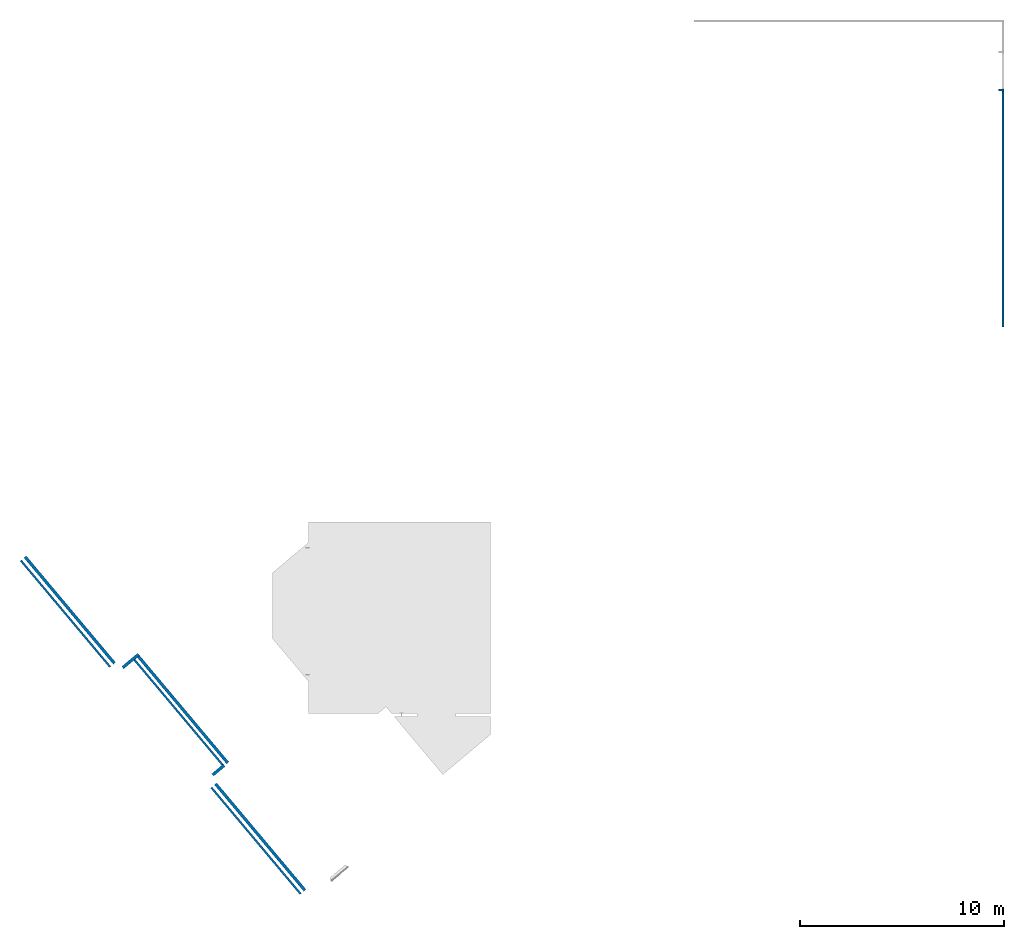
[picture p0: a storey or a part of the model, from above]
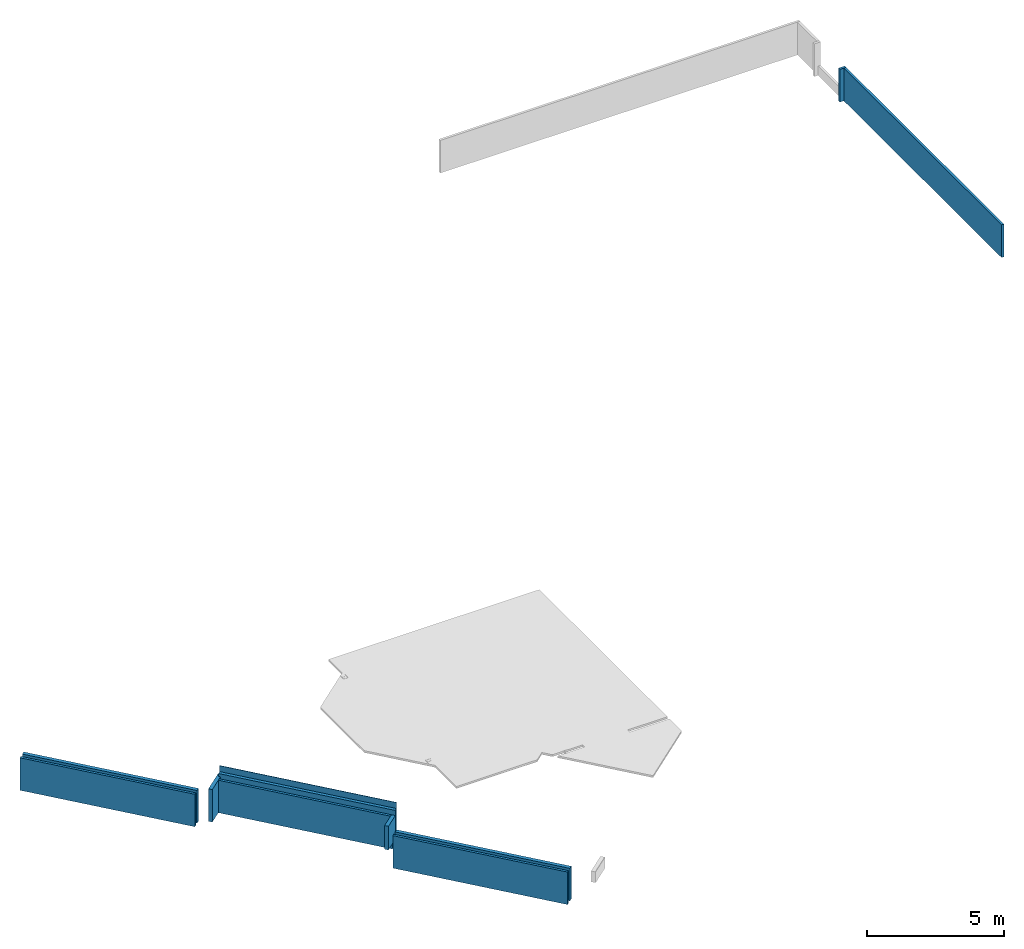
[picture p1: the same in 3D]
Properties of the parts of a building model (IFC2X3), part 1 of 11

# File
Description: ViewDefinition [9, SurfaceGeometryAddOnView, QuantityTakeOffAddOnView, SpaceBoundary2ndLevelAddOnView], Option [Elements to export: Visible elements (on all stories)], Option [Partial Structure Display: Entire Model], Option [IFC Domain: All], Option [Structural Function: All Elements], Option [Convert Grid elements: On], Option [Convert IFC Annotations and ARCHICAD 2D elements: Off], Option [Convert 2D symbols of Doors and Windows: Off], Option [Export geometries that Participates in Collision Detection only: On], Option [Split complex elements: Off], Option [Material Preservation: Explode all], Option [IFC Model position: Survey Point and Project Origin], Option [Curtain Wall export mode: Container Element], Option [Railing export mode: Container Element], Option [Stair export mode: Container Element], Option [Properties To Export: Current Scheme properties only], Option [Space containment: On], Option [IFC Domain For Space Containment: Custom], Option [Bounding Box: On], Option [Geometry to type objects: On], Option [Element Properties: Off], Option [Building Material Properties: Off], Option [Element Parameters: Off], Option [Component Parameters: IFC Component Quantities Only], Option [IFC Base Quantities: On], Option [Door Window Parameters: Off], Option [IFC Space boundaries: On], Option [ARCHICAD Zone Categories as IFC Space classification data: Off], Option [Element Classifications: On]
File name: D:\Dropbox (DankersSlimmerBouwen)\! DankersSlimmerBouwen\! projecten\197 IKC Woensdrecht\Productie\197_ TOT BWK_DO.ifc
Time: 2022-08-03T15:14:06
Author: Architect
Organization: Carree Architecten BNA
Written by: The EXPRESS Data Manager Version 5.02.0100.09 : 26 Sep 2013
Made in: IFC file generated by GRAPHISOFT ARCHICAD 25.0.0 NED FULL Windows version (IFC add-on version: 5010 NED FULL).
Authorization: The authorising person

# IfcSite, Fortuinstraat Woensdrecht
RefLatitude: 51, 27, 0, 0; RefLongitude: 5, 29, 0, 0; RefElevation: 15000 mm
BaseQuantities - GrossPerimeter: 0 mm; GrossArea: 0 m2

# IfcBuilding, IKC Fortuna
BaseQuantities - GrossFloorArea: 0 m2

# IfcBuildingStorey (4)
In: IKC Fortuna
BaseQuantities - GrossFloorArea: 0 m2
Name | Elevation (mm) | NetHeight (mm) = GrossHeight (mm) = Height (mm)
-1 fundering | -1085 | 1085
00 begane grond | 0 | 4000
01 eerste verdieping | 4000 | 4100
02 dak | 8100 | 2400

# IfcBeam: 41 Waterslag SW - MW 290 x 65 (4)
In: 00 begane grond
Type - PredefinedType: BEAM
Classification: Balk (ARCHICAD Classification); 28.11_L KOLOM-/LIGGERCONSTRUCTIES, LIGGER (NL/SfB (4 cijfers))
Pset_BeamCommon - Slope: 0 deg; FireRating: 0; LoadBearing: yes; IsExternal: no; Reference: 41 Waterslag SW - MW 290 x 65
CPset_Phasing - Renovation Phase: Bestaand
BaseQuantities - CrossSectionArea: 0.000438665 m2
Name | NetSurfaceAreaExtrudedSides (m2) = OuterSurfaceArea (m2) | Length (mm) | TotalSurfaceArea (m2) = GrossSurfaceArea (m2) = NetSurfaceArea (m2) | GrossVolume (m3) | NetVolume (m3)
28_Balk_UNP203 | 13.2138 | 15110 | 13.2146 | 0.00657677 | 0.00657677
28_Balk_UNP203 | 1.34295 | 1640.99 | 1.34383 | 0.000668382 | 0.000668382
28_Balk_UNP203 | 21.5643 | 24610 | 21.5652 | 0.0107441 | 0.0107432
28_Balk_UNP203 | 10.1795 | 11669 | 10.1803 | 0.00506733 | 0.00506716

# IfcBeam: 41 Waterslag SW - TR 130 x 66 (5)
In: 02 dak
Type - PredefinedType: BEAM
Classification: Balk (ARCHICAD Classification); 28.11_L KOLOM-/LIGGERCONSTRUCTIES, LIGGER (NL/SfB (4 cijfers)); Material: Metaal - Aluminium
Pset_BeamCommon - Slope: 0 deg; FireRating: 0; LoadBearing: no; IsExternal: yes; Reference: 41 Waterslag SW - TR 130 x 66
CPset_Phasing - Renovation Phase: Bestaand
BaseQuantities - CrossSectionArea: 0.000206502 m2
Component Quantities - Metaal - Aluminium, Component Cross Section Area: 0.000206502 m2
Name | NetSurfaceAreaExtrudedSides (m2) = OuterSurfaceArea (m2) | Length (mm) | TotalSurfaceArea (m2) = GrossSurfaceArea (m2) = NetSurfaceArea (m2) | GrossVolume (m3) | NetVolume (m3) = Metaal - Aluminium, Component Volume (Net) (m3) = Metaal - Aluminium, Component Volume (Gross) (m3) | Metaal - Aluminium, Mass (kg)
28_Balk_Waterslag | 2.97245 | 7220 | 2.97286 | 0.00147965 | 0.00147927 | 4.14196
28_Balk_Waterslag | 1.95411 | 4763.68 | 1.95453 | 0.000973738 | 0.000973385 | 2.72548
28_Balk_Waterslag | 1.2771 | 3135.33 | 1.27751 | 0.000636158 | 0.000635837 | 1.78034
28_Balk_Waterslag | 3.00315 | 7350.01 | 3.00357 | 0.0014952 | 0.00149457 | 4.18481
28_Balk_Waterslag | 3.63498 | 9026.01 | 3.6354 | 0.0018413 | 0.0018405 | 5.1534

# IfcBeam: 41 Waterslag SW - dakopstand 130 x 55, 28_Balk_UNP203
In: 01 eerste verdieping
Type - PredefinedType: BEAM
Classification: Balk (ARCHICAD Classification); 28.11_L KOLOM-/LIGGERCONSTRUCTIES, LIGGER (NL/SfB (4 cijfers)); Material: Metaal - Aluminium
Pset_BeamCommon - Slope: 0 deg; FireRating: 0; LoadBearing: yes; IsExternal: no; Reference: 41 Waterslag SW - dakopstand 130 x 55
CPset_Phasing - Renovation Phase: Bestaand
BaseQuantities - NetSurfaceAreaExtrudedSides: 3.48741 m2; Length: 9114.01 mm; CrossSectionArea: 0.000195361 m2; OuterSurfaceArea: 3.48741 m2; TotalSurfaceArea: 3.4878 m2; GrossSurfaceArea: 3.4878 m2; GrossVolume: 0.00178052 m3; NetSurfaceArea: 3.4878 m2; NetVolume: 0.0017805 m3
Component Quantities - Metaal - Aluminium, Mass: 4.98539 kg; Metaal - Aluminium, Component Cross Section Area: 0.000195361 m2; Metaal - Aluminium, Component Volume (Net): 0.0017805 m3; Metaal - Aluminium, Component Volume (Gross): 0.0017805 m3

# IfcBeam: 41 Zetwerk SW 115 x 74 (3)
In: 00 begane grond
Type - PredefinedType: BEAM
Classification: Balk (ARCHICAD Classification); 28.11_L KOLOM-/LIGGERCONSTRUCTIES, LIGGER (NL/SfB (4 cijfers)); Material: Metaal - Aluminium
Pset_BeamCommon - Slope: 0 deg; FireRating: 0; LoadBearing: yes; IsExternal: no; Reference: 41 Zetwerk SW 115 x 74
CPset_Phasing - Renovation Phase: Bestaand
BaseQuantities - CrossSectionArea: 0.000228 m2
Component Quantities - Metaal - Aluminium, Component Cross Section Area: 0.000228 m2
Name | NetSurfaceAreaExtrudedSides (m2) = OuterSurfaceArea (m2) | Length (mm) | TotalSurfaceArea (m2) = GrossSurfaceArea (m2) = NetSurfaceArea (m2) | GrossVolume (m3) | NetVolume (m3) = Metaal - Aluminium, Component Volume (Net) (m3) = Metaal - Aluminium, Component Volume (Gross) (m3) | Metaal - Aluminium, Mass (kg)
28_Balk_UNP203 | 0.215603 | 1100 | 0.216059 | 0.0002508 | 0.000107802 | 0.301844
28_Balk_UNP203 | 0.0991772 | 1100 | 0.0996332 | 0.0002508 | 0.0000044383 | 0.0124272
28_Balk_UNP203 | 0.0990777 | 1098.97 | 0.0995337 | 0.000250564 | 0.00000442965 | 0.012403

# IfcBeam: 41 Zetwerk SW b 151 x 74, 28_Balk_UNP203
In: 00 begane grond
Type - PredefinedType: BEAM
Classification: Balk (ARCHICAD Classification); 28.11_L KOLOM-/LIGGERCONSTRUCTIES, LIGGER (NL/SfB (4 cijfers)); Material: Metaal - Aluminium
Pset_BeamCommon - Slope: 0 deg; FireRating: 0; LoadBearing: yes; IsExternal: no; Reference: 41 Zetwerk SW b 151 x 74
CPset_Phasing - Renovation Phase: Bestaand
BaseQuantities - NetSurfaceAreaExtrudedSides: 0.244343 m2; Length: 1100 mm; CrossSectionArea: 0.000258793 m2; OuterSurfaceArea: 0.244343 m2; TotalSurfaceArea: 0.244861 m2; GrossSurfaceArea: 0.244861 m2; GrossVolume: 0.000284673 m3; NetSurfaceArea: 0.244861 m2; NetVolume: 0.000121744 m3
Component Quantities - Metaal - Aluminium, Mass: 0.340884 kg; Metaal - Aluminium, Component Cross Section Area: 0.000258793 m2; Metaal - Aluminium, Component Volume (Net): 0.000121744 m3; Metaal - Aluminium, Component Volume (Gross): 0.000121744 m3

# IfcBeam: 41 Zetwerk SW hd b 77 x 97, 28_Balk_UNP203
In: 00 begane grond
Type - PredefinedType: BEAM
Classification: Balk (ARCHICAD Classification); 28.11_L KOLOM-/LIGGERCONSTRUCTIES, LIGGER (NL/SfB (4 cijfers)); Material: Metaal - Aluminium
Pset_BeamCommon - Slope: 0 deg; FireRating: 0; LoadBearing: yes; IsExternal: no; Reference: 41 Zetwerk SW hd b 77 x 97
CPset_Phasing - Renovation Phase: Bestaand
BaseQuantities - NetSurfaceAreaExtrudedSides: 0.421984 m2; Length: 1934.7 mm; CrossSectionArea: 0.000188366 m2; OuterSurfaceArea: 0.421984 m2; TotalSurfaceArea: 0.422361 m2; GrossSurfaceArea: 0.422361 m2; GrossVolume: 0.000343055 m3; NetSurfaceArea: 0.422361 m2; NetVolume: 0.00021001 m3
Component Quantities - Metaal - Aluminium, Mass: 0.588029 kg; Metaal - Aluminium, Component Cross Section Area: 0.000188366 m2; Metaal - Aluminium, Component Volume (Net): 0.00021001 m3; Metaal - Aluminium, Component Volume (Gross): 0.00021001 m3

# IfcBeam: 41 Zetwerk SW o 74 x 109 (4)
In: 00 begane grond
Type - PredefinedType: BEAM
Classification: Balk (ARCHICAD Classification); 28.11_L KOLOM-/LIGGERCONSTRUCTIES, LIGGER (NL/SfB (4 cijfers)); Material: Metaal - Aluminium
Pset_BeamCommon - Slope: 0 deg; FireRating: 0; LoadBearing: yes; IsExternal: no; Reference: 41 Zetwerk SW o 74 x 109
CPset_Phasing - Renovation Phase: Bestaand
BaseQuantities - CrossSectionArea: 0.000205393 m2
Component Quantities - Metaal - Aluminium, Component Cross Section Area: 0.000205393 m2
Name | NetSurfaceAreaExtrudedSides (m2) = OuterSurfaceArea (m2) | Length (mm) | TotalSurfaceArea (m2) = GrossSurfaceArea (m2) = NetSurfaceArea (m2) | GrossVolume (m3) | NetVolume (m3) = Metaal - Aluminium, Component Volume (Net) (m3) | Metaal - Aluminium, Mass (kg) | Metaal - Aluminium, Component Volume (Gross) (m3)
2 x 28_Balk_UNP203 | 0.143414 | 920 | 0.143825 | 0.000188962 | 0.0000717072 | 0.20078 | 0.0000717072
28_Balk_UNP203 | 0.0643181 | 922.191 | 0.0647289 | 0.000189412 | 0.00000328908 | 0.00920943 | 0.00000328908
28_Balk_UNP203 | 0.0641629 | 919.966 | 0.0645737 | 0.000188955 | 0.00000327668 | 0.00917469 | 0.00000328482

# IfcBeam: 41 Zetwerk dakrand sw 253 x 40 (3)
In: 02 dak
Type - PredefinedType: BEAM
Classification: Balk (ARCHICAD Classification); 28.11_L KOLOM-/LIGGERCONSTRUCTIES, LIGGER (NL/SfB (4 cijfers)); Material: Metaal - Staal AFW
Pset_BeamCommon - Slope: 0 deg; FireRating: 0; LoadBearing: yes; IsExternal: no; Reference: 41 Zetwerk dakrand sw 253 x 40
CPset_Phasing - Renovation Phase: Bestaand
BaseQuantities - CrossSectionArea: 0.000346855 m2
Component Quantities - Metaal - Staal AFW, Component Cross Section Area: 0.000346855 m2
Name | NetSurfaceAreaExtrudedSides (m2) = OuterSurfaceArea (m2) | Length (mm) | TotalSurfaceArea (m2) = GrossSurfaceArea (m2) = NetSurfaceArea (m2) | GrossVolume (m3) | NetVolume (m3) = Metaal - Staal AFW, Component Volume (Net) (m3) = Metaal - Staal AFW, Component Volume (Gross) (m3) | Metaal - Staal AFW, Mass (kg)
28_Balk_UNP200 | 16.9808 | 24462 | 16.9815 | 0.00844712 | 0.00844615 | 67.1469
28_Balk_UNP201 | 10.1584 | 14784 | 10.1591 | 0.00505261 | 0.00505261 | 40.1682
28_Balk_UNP202 | 16.9839 | 24462 | 16.9846 | 0.00844712 | 0.00844712 | 67.1546

# IfcBeam: 41 Zetwerk dakrand sw TR 136 x 39 (4)
In: 02 dak
Type - PredefinedType: BEAM
Classification: Balk (ARCHICAD Classification); 28.11_L KOLOM-/LIGGERCONSTRUCTIES, LIGGER (NL/SfB (4 cijfers)); Material: Metaal - Staal AFW
Pset_BeamCommon - Slope: 0 deg; FireRating: 0; LoadBearing: yes; IsExternal: no; Reference: 41 Zetwerk dakrand sw TR 136 x 39
CPset_Phasing - Renovation Phase: Bestaand
BaseQuantities - CrossSectionArea: 0.000219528 m2
Component Quantities - Metaal - Staal AFW, Component Cross Section Area: 0.000219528 m2
Name | NetSurfaceAreaExtrudedSides (m2) = OuterSurfaceArea (m2) | Length (mm) | TotalSurfaceArea (m2) = GrossSurfaceArea (m2) = NetSurfaceArea (m2) | GrossVolume (m3) = NetVolume (m3) = Metaal - Staal AFW, Component Volume (Net) (m3) = Metaal - Staal AFW, Component Volume (Gross) (m3) | Metaal - Staal AFW, Mass (kg)
2 x 28_Balk_UNP201 | 3.18414 | 7340 | 3.18458 | 0.00158494 | 12.6003
2 x 28_Balk_UNP201 | 3.92334 | 9015.99 | 3.92378 | 0.00195287 | 15.5253

# IfcBeam: 42 Wand - Trap 130 x 52
In: 01 eerste verdieping
Type - PredefinedType: BEAM
Classification: Balk (ARCHICAD Classification); 16.12 FUNDATIE BALKEN (NL/SfB (4 cijfers))
Pset_BeamCommon - Slope: 38.2396 deg; FireRating: 0; LoadBearing: yes; IsExternal: yes; Reference: 42 Wand - Trap 130 x 52
CPset_Phasing - Renovation Phase: Bestaand
BaseQuantities - NetSurfaceAreaExtrudedSides: 0.894455 m2; Length: 2091.08 mm; CrossSectionArea: 0.00170275 m2; OuterSurfaceArea: 0.894455 m2; TotalSurfaceArea: 0.89786 m2; GrossSurfaceArea: 0.89786 m2; GrossVolume: 0.00354164 m3; NetSurfaceArea: 0.89786 m2; NetVolume: 0.00325273 m3

# IfcBeam: Hout - Multiplex 12 x 1229, 28_Balk_UNP204
In: 00 begane grond
Type - PredefinedType: BEAM
Classification: Balk (ARCHICAD Classification); 28.11_L KOLOM-/LIGGERCONSTRUCTIES, LIGGER (NL/SfB (4 cijfers)); Material: Hout - Multiplex
Pset_BeamCommon - Slope: 10 deg; FireRating: 0; LoadBearing: yes; IsExternal: no; Reference: Hout - Multiplex 12 x 1229
CPset_Phasing - Renovation Phase: Bestaand
BaseQuantities - NetSurfaceAreaExtrudedSides: 0.349953 m2; Length: 436.899 mm; Width: 12 mm; Depth: 1229.33 mm; CrossSectionArea: 0.014752 m2; OuterSurfaceArea: 0.349953 m2; TotalSurfaceArea: 0.379457 m2; GrossSurfaceArea: 0.379457 m2; GrossVolume: 0.00329864 m3; NetSurfaceArea: 0.379457 m2; NetVolume: 0.0020755 m3
Component Quantities - Hout - Multiplex, Mass: 1.45285 kg; Hout - Multiplex, Projected Component Area (Net): 0.172944 m2; Hout - Multiplex, Projected Component Area (Gross): 0.172944 m2; Hout - Multiplex, Component Thickness: 12 mm; Hout - Multiplex, Rectangular Component Height: 1229.33 mm; Hout - Multiplex, Rectangular Component Width: 12 mm; Hout - Multiplex, Component Cross Section Area: 0.014752 m2; Hout - Multiplex, Component Volume (Net): 0.0020755 m3; Hout - Multiplex, Component Volume (Gross): 0.0020755 m3

# IfcBeam: Hout - Multiplex 120 x 12 (2)
In: 00 begane grond
Type - PredefinedType: BEAM
Classification: Balk (ARCHICAD Classification); 28.11_L KOLOM-/LIGGERCONSTRUCTIES, LIGGER (NL/SfB (4 cijfers)); Material: Hout - Multiplex
Pset_BeamCommon - Slope: 0 deg; FireRating: 0; LoadBearing: yes; IsExternal: no; Reference: Hout - Multiplex 120 x 12
CPset_Phasing - Renovation Phase: Bestaand
BaseQuantities - Width: 120 mm; Depth: 12 mm; CrossSectionArea: 0.00144 m2
Component Quantities - Hout - Multiplex, Component Thickness: 120 mm; Hout - Multiplex, Rectangular Component Height: 12 mm; Hout - Multiplex, Rectangular Component Width: 120 mm; Hout - Multiplex, Component Cross Section Area: 0.00144 m2
Name | NetSurfaceAreaExtrudedSides (m2) = OuterSurfaceArea (m2) | Length (mm) | TotalSurfaceArea (m2) = GrossSurfaceArea (m2) = NetSurfaceArea (m2) | GrossVolume (m3) | NetVolume (m3) = Hout - Multiplex, Component Volume (Net) (m3) = Hout - Multiplex, Component Volume (Gross) (m3) | Hout - Multiplex, Mass (kg) | Hout - Multiplex, Projected Component Area (Net) (m2) = Hout - Multiplex, Projected Component Area (Gross) (m2)
28_Balk_UNP204 | 3.13448 | 11907.8 | 3.13736 | 0.0171472 | 0.017093 | 11.9651 | 0.142894
28_Balk_UNP204 | 0.622431 | 2388.22 | 0.625311 | 0.00343903 | 0.00338577 | 2.37004 | 0.0286058

# IfcBeam: Hout - Multiplex 220 x 12 (3)
In: 00 begane grond
Type - PredefinedType: BEAM
Classification: Balk (ARCHICAD Classification); 28.11_L KOLOM-/LIGGERCONSTRUCTIES, LIGGER (NL/SfB (4 cijfers)); Material: Hout - Multiplex
Pset_BeamCommon - Slope: 0 deg; FireRating: 0; LoadBearing: yes; IsExternal: no; Reference: Hout - Multiplex 220 x 12
CPset_Phasing - Renovation Phase: Bestaand
BaseQuantities - Width: 220 mm; Depth: 12 mm; CrossSectionArea: 0.00264 m2
Component Quantities - Hout - Multiplex, Component Thickness: 220 mm; Hout - Multiplex, Rectangular Component Height: 12 mm; Hout - Multiplex, Rectangular Component Width: 220 mm; Hout - Multiplex, Component Cross Section Area: 0.00264 m2
Name | NetSurfaceAreaExtrudedSides (m2) = OuterSurfaceArea (m2) | Length (mm) | TotalSurfaceArea (m2) = GrossSurfaceArea (m2) = NetSurfaceArea (m2) | GrossVolume (m3) | NetVolume (m3) = Hout - Multiplex, Component Volume (Net) (m3) = Hout - Multiplex, Component Volume (Gross) (m3) | Hout - Multiplex, Mass (kg) | Hout - Multiplex, Projected Component Area (Net) (m2) = Hout - Multiplex, Projected Component Area (Gross) (m2)
28_Balk_UNP203 | 6.56699 | 14310 | 6.57227 | 0.0375503 | 0.0373903 | 26.1732 | 0.171719
28_Balk_UNP203 | 11.1618 | 24238.5 | 11.1671 | 0.0637523 | 0.0635542 | 44.4879 | 0.290835
28_Balk_UNP203 | 5.63733 | 12210 | 5.64261 | 0.0322344 | 0.0321038 | 22.4727 | 0.146521

# IfcBeam: Hout - Multiplex 233 x 12 (10)
In: 00 begane grond
Type - PredefinedType: BEAM
Classification: Balk (ARCHICAD Classification); 28.11_L KOLOM-/LIGGERCONSTRUCTIES, LIGGER (NL/SfB (4 cijfers)); Material: Hout - Multiplex
Pset_BeamCommon - Slope: 0 deg; FireRating: 0; LoadBearing: yes; IsExternal: no; Reference: Hout - Multiplex 233 x 12
CPset_Phasing - Renovation Phase: Bestaand
BaseQuantities - Width: 232.524 mm; Depth: 12 mm; CrossSectionArea: 0.00279029 m2
Component Quantities - Hout - Multiplex, Component Thickness: 232.524 mm; Hout - Multiplex, Rectangular Component Height: 12 mm; Hout - Multiplex, Rectangular Component Width: 232.524 mm; Hout - Multiplex, Component Cross Section Area: 0.00279029 m2
Name | NetSurfaceAreaExtrudedSides (m2) = OuterSurfaceArea (m2) | Length (mm) | TotalSurfaceArea (m2) = GrossSurfaceArea (m2) = NetSurfaceArea (m2) | GrossVolume (m3) | NetVolume (m3) = Hout - Multiplex, Component Volume (Net) (m3) = Hout - Multiplex, Component Volume (Gross) (m3) | Hout - Multiplex, Mass (kg) | Hout - Multiplex, Projected Component Area (Net) (m2) = Hout - Multiplex, Projected Component Area (Gross) (m2)
28_Balk_UNP203 | 5.97294 | 12374.5 | 5.97852 | 0.0342611 | 0.03412 | 23.884 | 0.148493
28_Balk_UNP203 | 4.38759 | 9025.03 | 4.39317 | 0.0251825 | 0.0250482 | 17.5337 | 0.1083
28_Balk_UNP203 | 0.511081 | 1065 | 0.516662 | 0.00297166 | 0.00292176 | 2.04523 | 0.01278
28_Balk_UNP203 | 5.47805 | 11355 | 5.48363 | 0.0314262 | 0.0312823 | 21.8976 | 0.136259
28_Balk_UNP203 | 0.571299 | 1175 | 0.57688 | 0.00327859 | 0.0032587 | 2.28109 | 0.0141
28_Balk_UNP203 | 2.49706 | 5140 | 2.50264 | 0.0143421 | 0.0142613 | 9.98293 | 0.0616799
28_Balk_UNP203 | 0.504886 | 1065 | 0.510466 | 0.00297166 | 0.00289323 | 2.02526 | 0.01278
28_Balk_UNP203 | 2.06934 | 4357.04 | 2.07492 | 0.0121574 | 0.0120029 | 8.402 | 0.0522845
28_Balk_UNP203 | 5.79093 | 11864 | 5.79651 | 0.033104 | 0.0330505 | 23.1354 | 0.142368
28_Balk_UNP203 | 0.870498 | 1779.98 | 0.876079 | 0.00496667 | 0.00496667 | 3.47667 | 0.0213598

# IfcBuildingElementPart (2314)
Name | In | Material | Mass (kg) | Projected Component Area (Net) (m2) | Projected Component Area (Gross) (m2) | Component Thickness (mm) | Component Volume (Net) (m3) | Component Volume (Gross) (m3) | Rectangular Component Height (mm) | Rectangular Component Width (mm) | Component Cross Section Area (m2)
Cement | -1 fundering | Cement | 13312.7 | 100.11 | 99.8191 | 70 | 7.00671 | 6.98639
Isolatie - XPS zwevende dekvloer | -1 fundering | Isolatie - XPS zwevende dekvloer | 70.0771 | 100.11 | 99.8191 | 20 | 2.0022 | 1.99638
Cement | -1 fundering | Cement | 13.8225 | 0.485 | 0.485 | 15 | 0.007275 | 0.007275 | 485 | 15 | 0.007275
ALG - ISOLATIE | -1 fundering | ALG - ISOLATIE | 3.492 | 0.485 | 0.485 | 160 | 0.0776 | 0.0776 | 485 | 160 | 0.0776
4 x Gipsplaat | 00 begane grond | Gipsplaat | 306.986 | 30.6986 | 43.067 | 12.5 | 0.383732 | 0.538337 | 5585 | 12.5 | 0.0698125
Isolatie - Steenwol LSW | 00 begane grond | Isolatie - Steenwol LSW | 84.421 | 30.6986 | 43.067 | 50 | 1.53493 | 2.15335 | 5585 | 50 | 0.27925
ALG - ISOLATIE | 00 begane grond | ALG - ISOLATIE | 19.7388 | 3.13314 | 3.13314 | 140 | 0.438639 | 0.438639 | 830 | 140 | 0.1162
Steen - Baksteen Hoofd | 00 begane grond | Steen - Baksteen Hoofd | 501.302 | 3.13314 | 3.13314 | 100 | 0.313314 | 0.313314 | 830 | 100 | 0.083
ALG - ISOLATIE | 00 begane grond | ALG - ISOLATIE | 86.3275 | 13.7028 | 19.4815 | 140 | 1.91839 | 2.72741 | 3272.5 | 140 | 0.45815
Steen - Baksteen Accent | 00 begane grond | Steen - Baksteen Accent | 2192.44 | 13.7028 | 19.4815 | 100 | 1.37028 | 1.94815 | 3272.5 | 100 | 0.32725
2 x Steen - Baksteen Hoofd | 00 begane grond | Steen - Baksteen Hoofd | 1185.92 | 7.41199 | 7.41199 | 100 | 0.741199 | 0.741199 | 4135 | 100 | 0.4135
2 x ALG - ISOLATIE | 00 begane grond | ALG - ISOLATIE | 42.0064 | 6.66769 | 6.66769 | 140 | 0.933476 | 0.933476 | 4135 | 140 | 0.5789
6 x Isolatie - PUR gespoten | 00 begane grond | Isolatie - PUR gespoten | 0.0309313 |  |  |  | 0.00088375 | 0.00088375 | 87.5 | 10 | 0.000875
6 x Hout AFW | 00 begane grond | Hout AFW | 1.84704 |  |  |  | 0.00335825 | 0.00335825 | 87.5 | 38 | 0.003325
6 x Steen - Kunststeen | 00 begane grond | Steen - Kunststeen | 21.2604 |  |  |  | 0.0132877 | 0.0132877 |  |  | 0.0131562
2 x Metaal - Staal AFW | 00 begane grond | Metaal - Staal AFW | 9.89794 |  |  |  | 0.00124502 | 0.00124502
2 x ALG - ISOLATIE | 00 begane grond | ALG - ISOLATIE | 0.655276 |  |  |  | 0.0145617 | 0.0145617
2 x Metaal - Staal AFW | 00 begane grond | Metaal - Staal AFW | 9.26652 |  |  |  | 0.0011656 | 0.0011656
2 x ALG - ISOLATIE | 00 begane grond | ALG - ISOLATIE | 0.543959 |  |  |  | 0.012088 | 0.012088
Metaal - Staal AFW | 00 begane grond | Metaal - Staal AFW | 10.0635 |  |  |  | 0.00126585 | 0.00126585
ALG - ISOLATIE | 00 begane grond | ALG - ISOLATIE | 0.666918 |  |  |  | 0.0148204 | 0.0148204
Metaal - Staal AFW | 00 begane grond | Metaal - Staal AFW | 9.42248 |  |  |  | 0.00118522 | 0.00118522
ALG - ISOLATIE | 00 begane grond | ALG - ISOLATIE | 0.553619 |  |  |  | 0.0123026 | 0.0123026
Cement | 00 begane grond | Cement | 14034.3 | 105.523 | 103.867 | 70 | 7.38646 | 7.2705
Isolatie - XPS zwevende dekvloer | 00 begane grond | Isolatie - XPS zwevende dekvloer | 73.8662 | 105.523 | 103.867 | 20 | 2.11046 | 2.07733
Cement | 00 begane grond | Cement | 14061 | 105.724 | 103.864 | 70 | 7.40055 | 7.27033
Isolatie - XPS zwevende dekvloer | 00 begane grond | Isolatie - XPS zwevende dekvloer | 74.0071 | 105.724 | 103.864 | 20 | 2.11449 | 2.07728
Cement | 00 begane grond | Cement | 15360.6 | 115.506 | 115.506 | 70 | 8.0845 | 8.0845
Isolatie - XPS zwevende dekvloer | 00 begane grond | Isolatie - XPS zwevende dekvloer | 80.8544 | 115.506 | 115.506 | 20 | 2.31013 | 2.31013
ALG - ISOLATIE | 00 begane grond | ALG - ISOLATIE | 7.1884 | 1.14102 | 6.91977 | 140 | 0.159742 | 0.968767 | 3272.5 | 140 | 0.45815
Steen - Baksteen Accent | 00 begane grond | Steen - Baksteen Accent | 182.562 | 1.14102 | 6.91977 | 100 | 0.114102 | 0.691977 | 3272.5 | 100 | 0.32725
Gipsplaat | 00 begane grond | Gipsplaat | 79.471 | 7.9471 | 7.717 | 12.5 | 0.0993388 | 0.0964625 | 2160 | 12.5 | 0.027
Gipsplaat | 00 begane grond | Gipsplaat | 78.0137 | 7.80137 | 7.64414 | 12.5 | 0.0975171 | 0.0955517 | 2160 | 12.5 | 0.027
Isolatie - Steenwol LSW | 00 begane grond | Isolatie - Steenwol LSW | 32.4612 | 8.13787 | 7.98063 | 75 | 0.590204 | 0.578411 | 2160 | 75 | 0.162
2 x Gipsplaat | 00 begane grond | Gipsplaat | 81.0875 | 8.10875 | 7.95152 | 12.5 | 0.101359 | 0.0993939 | 2160 | 12.5 | 0.027
4 x Steen - Kunststeen | 00 begane grond | Steen - Kunststeen | 20.3552 |  |  |  | 0.012722 | 0.012722 |  |  | 0.0131562
4 x Hout AFW | 00 begane grond | Hout AFW | 1.7684 |  |  |  | 0.00321527 | 0.00321527 | 87.5 | 38 | 0.003325
4 x Isolatie - PUR gespoten | 00 begane grond | Isolatie - PUR gespoten | 0.0296144 |  |  |  | 0.000846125 | 0.000846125 | 87.5 | 10 | 0.000875
ALG - ISOLATIE | 00 begane grond | ALG - ISOLATIE | 5.58306 |  |  |  | 0.124068 | 0.124068 | 210 | 140 | 0.0294
Steen - Baksteen Accent Rollaag | 00 begane grond | Steen - Baksteen Accent Rollaag | 141.792 |  |  |  | 0.08862 | 0.08862 | 210 | 100 | 0.021
8 x Isolatie - PUR gespoten | 00 begane grond | Isolatie - PUR gespoten | 0.0447426 |  |  |  | 0.00127836 | 0.00127836 | 53 | 12 | 0.000636
8 x Hout AFW | 00 begane grond | Hout AFW | 3.40494 |  |  |  | 0.0061908 | 0.0061908 | 70 | 44 | 0.00308
8 x ALG - ISOLATIE | 00 begane grond | ALG - ISOLATIE | 1.98809 |  |  |  | 0.0441798 | 0.0441798 | 157 | 140 | 0.02198
3 x Metaal - Staal AFW | 00 begane grond | Metaal - Staal AFW | 5.03401 |  |  |  | 0.000633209 | 0.000633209 | 4 | 90 | 0.00036
3 x Steen - Baksteen Accent Rollaag | 00 begane grond | Steen - Baksteen Accent Rollaag | 67.536 |  |  |  | 0.04221 | 0.04221 | 210 | 100 | 0.021
3 x Metaal - Staal C | 00 begane grond | Metaal - Staal C | 13.8388 |  |  |  | 0.00174072 | 0.00174072 |  |  | 0.000920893
Metaal - Aluminium | 00 begane grond | Metaal - Aluminium | 66.1067 | 23.6095 | 29.9834 | 1 | 0.0236095 | 0.0299829 | 6000 | 1 | 0.006
Isolatie - Kunststof hard | 00 begane grond | Isolatie - Kunststof hard | 231.374 | 23.61 | 30 | 98 | 2.31374 | 2.93996 | 6000 | 98 | 0.588
Metaal - Aluminium | 00 begane grond | Metaal - Aluminium | 65.7611 | 23.6026 | 29.9926 | 1 | 0.0234861 | 0.0298978 | 6000 | 1 | 0.006
Metaal - Aluminium | 00 begane grond | Metaal - Aluminium | 4.03838 | 1.44228 | 1.44228 | 1 | 0.00144228 | 0.00144228 | 2020 | 1 | 0.00202
Isolatie - Kunststof hard | 00 begane grond | Isolatie - Kunststof hard | 14.1235 | 1.44228 | 1.44228 | 98 | 0.141235 | 0.141235 | 2020 | 98 | 0.19796
Metaal - Aluminium | 00 begane grond | Metaal - Aluminium | 3.96049 | 1.42871 | 1.42871 | 1 | 0.00141446 | 0.00141446 | 2020 | 1 | 0.00202
Steen - Baksteen Accent | 00 begane grond | Steen - Baksteen Accent | 2207.52 | 13.797 | 13.797 | 100 | 1.3797 | 1.3797 | 3285 | 100 | 0.3285
ALG - ISOLATIE | 00 begane grond | ALG - ISOLATIE | 87.7489 | 13.9284 | 13.9284 | 140 | 1.94998 | 1.94998 | 3285 | 140 | 0.4599
Steen - Baksteen Accent | 00 begane grond | Steen - Baksteen Accent | 2289.25 | 14.3078 | 14.3078 | 100 | 1.43078 | 1.43078 | 3585 | 100 | 0.3585
ALG - ISOLATIE | 00 begane grond | ALG - ISOLATIE | 88.1615 | 13.9939 | 13.9939 | 140 | 1.95914 | 1.95914 | 3585 | 140 | 0.5019
ALG - ISOLATIE | 00 begane grond | ALG - ISOLATIE | 264.153 | 41.929 | 46.739 | 140 | 5.87006 | 6.53336 | 3285 | 140 | 0.4599
Steen - Baksteen Accent | 00 begane grond | Steen - Baksteen Accent | 6897.48 | 43.1116 | 47.9216 | 100 | 4.31093 | 4.79052 | 3285 | 100 | 0.3285
Membraan - waterdicht | 00 begane grond | Membraan - waterdicht | 8.24771 | 1.30939 | 2.31903 | 6 | 0.00785496 | 0.0139142 | 472.5 | 6 | 0.002835
Steen - Cellenbeton | 00 begane grond | Steen - Cellenbeton | 162.332 | 2.31903 | 2.31903 | 100 | 0.231903 | 0.231903 | 472.5 | 100 | 0.04725
ALG - ISOLATIE | 00 begane grond | ALG - ISOLATIE | 14.5547 | 2.31028 | 2.31028 | 140 | 0.323439 | 0.323439 | 472.5 | 140 | 0.06615
ALG - ISOLATIE | 00 begane grond | ALG - ISOLATIE | 121.089 | 19.2205 | 27.903 | 140 | 2.69088 | 3.90643 | 3285 | 140 | 0.4599
Steen - Baksteen Accent | 00 begane grond | Steen - Baksteen Accent | 3148.18 | 19.6804 | 28.3629 | 100 | 1.96761 | 2.83348 | 3285 | 100 | 0.3285
Steen - Baksteen Accent | 00 begane grond | Steen - Baksteen Accent | 2790.93 | 17.4508 | 29.1865 | 100 | 1.74433 | 2.91428 | 3285 | 100 | 0.3285
ALG - ISOLATIE | 00 begane grond | ALG - ISOLATIE | 106.215 | 16.8595 | 28.5952 | 140 | 2.36033 | 4.00333 | 3285 | 140 | 0.4599
Steen - Baksteen Accent | 00 begane grond | Steen - Baksteen Accent | 2284.5 | 14.2828 | 25.8724 | 100 | 1.42781 | 2.58362 | 3285 | 100 | 0.3285
ALG - ISOLATIE | 00 begane grond | ALG - ISOLATIE | 92.8787 | 14.7427 | 26.3323 | 140 | 2.06397 | 3.68652 | 3285 | 140 | 0.4599
Steen - Baksteen Accent Rollaag | 00 begane grond | Steen - Baksteen Accent Rollaag | 29.2134 |  |  |  | 0.0182584 | 0.0182584 | 210 | 100 | 0.021
2 x ALG - ISOLATIE | 00 begane grond | ALG - ISOLATIE | 1.15101 |  |  |  | 0.025578 | 0.025578 | 210 | 140 | 0.0294
Steen - Baksteen Accent | 00 begane grond | Steen - Baksteen Accent | 3082.52 | 19.2717 | 33.733 | 100 | 1.92657 | 3.36873 | 3285 | 100 | 0.3285
ALG - ISOLATIE | 00 begane grond | ALG - ISOLATIE | 121.412 | 19.2717 | 33.733 | 140 | 2.69804 | 4.72262 | 3285 | 140 | 0.4599
ALG - ISOLATIE | 00 begane grond | ALG - ISOLATIE | 137.17 | 21.966 | 33.581 | 140 | 3.04822 | 4.67432 | 3285 | 140 | 0.4599
Steen - Baksteen Accent | 00 begane grond | Steen - Baksteen Accent | 3509.17 | 22.0702 | 33.6852 | 100 | 2.19323 | 3.35473 | 3285 | 100 | 0.3285
Steen - Baksteen Accent | 00 begane grond | Steen - Baksteen Accent | 2852.1 | 17.9659 | 20.8696 | 100 | 1.78256 | 2.07205 | 3285 | 100 | 0.3285
ALG - ISOLATIE | 00 begane grond | ALG - ISOLATIE | 110.232 | 17.6901 | 20.5939 | 140 | 2.44961 | 2.85613 | 3285 | 140 | 0.4599
ALG - ISOLATIE | 00 begane grond | ALG - ISOLATIE | 5.4398 | 0.86346 | 6.87609 | 140 | 0.120884 | 0.962652 | 3265 | 140 | 0.4571
Steen - Baksteen Accent | 00 begane grond | Steen - Baksteen Accent | 138.154 | 0.86346 | 6.87609 | 100 | 0.086346 | 0.687609 | 3265 | 100 | 0.3265
ALG - ISOLATIE | 00 begane grond | ALG - ISOLATIE | 115.644 | 18.3562 | 18.3562 | 140 | 2.56987 | 2.56987 | 4722.5 | 140 | 0.66115
Steen - Baksteen Accent | 00 begane grond | Steen - Baksteen Accent | 2936.99 | 18.3562 | 18.3562 | 100 | 1.83562 | 1.83562 | 4722.5 | 100 | 0.47225
ALG - ISOLATIE | 00 begane grond | ALG - ISOLATIE | 85.7786 | 13.6157 | 13.6157 | 140 | 1.90619 | 1.90619 | 4135 | 140 | 0.5789
Steen - Baksteen Hoofd | 00 begane grond | Steen - Baksteen Hoofd | 2271.13 | 14.1946 | 14.1946 | 100 | 1.41946 | 1.41946 | 4135 | 100 | 0.4135
Isolatie - Steenwol LSW | 00 begane grond | Isolatie - Steenwol LSW | 2.54678 | 0.951255 | 0.951255 | 50 | 0.0463051 | 0.0474139 | 778.004 | 50 | 0.0389002
Gipsplaat | 00 begane grond | Gipsplaat | 9.52793 | 0.972505 | 0.972505 | 12.5 | 0.0119099 | 0.0121563 | 778.004 | 12.5 | 0.00972505
Gipsplaat | 00 begane grond | Gipsplaat | 9.72505 | 0.972505 | 0.972505 | 12.5 | 0.0121563 | 0.0121563 | 778.004 | 12.5 | 0.00972505
Cement | 00 begane grond | Cement | 79269.3 | 596.1 | 594.407 | 70 | 41.7207 | 41.6022
Isolatie - XPS zwevende dekvloer | 00 begane grond | Isolatie - XPS zwevende dekvloer | 417.303 | 596.163 | 594.407 | 20 | 11.9229 | 11.8881
4 x Gipsplaat | 00 begane grond | Gipsplaat | 67.32 | 6.732 | 6.732 | 12.5 | 0.08415 | 0.08415 | 3740 | 12.5 | 0.04675
Isolatie - Steenwol LSW | 00 begane grond | Isolatie - Steenwol LSW | 18.513 | 6.732 | 6.732 | 50 | 0.3366 | 0.3366 | 3740 | 50 | 0.187
4 x Gipsplaat | 00 begane grond | Gipsplaat | 134.266 | 13.4266 | 13.4266 | 12.5 | 0.167832 | 0.167832 | 3740 | 12.5 | 0.04675
Isolatie - Steenwol LSW | 00 begane grond | Isolatie - Steenwol LSW | 55.3847 | 13.4266 | 13.4266 | 75 | 1.00699 | 1.00699 | 3740 | 75 | 0.2805
4 x Gipsplaat | 00 begane grond | Gipsplaat | 132.209 | 13.2209 | 13.2209 | 12.5 | 0.165261 | 0.165261 | 3740 | 12.5 | 0.04675
Isolatie - Steenwol LSW | 00 begane grond | Isolatie - Steenwol LSW | 54.5362 | 13.2209 | 13.2209 | 75 | 0.991568 | 0.991568 | 3740 | 75 | 0.2805
Gipsplaat | 00 begane grond | Gipsplaat | 86.0837 | 8.60837 | 8.60837 | 12.5 | 0.107605 | 0.107605 | 3740 | 12.5 | 0.04675
Gipsplaat | 00 begane grond | Gipsplaat | 85.6162 | 8.56162 | 8.56162 | 12.5 | 0.10702 | 0.10702 | 3740 | 12.5 | 0.04675
Isolatie - Steenwol LSW | 00 begane grond | Isolatie - Steenwol LSW | 35.1238 | 8.51487 | 8.51487 | 75 | 0.638615 | 0.638615 | 3740 | 75 | 0.2805
Gipsplaat | 00 begane grond | Gipsplaat | 82.3437 | 8.23437 | 8.23437 | 12.5 | 0.10293 | 0.10293 | 3740 | 12.5 | 0.04675
Gipsplaat | 00 begane grond | Gipsplaat | 81.8762 | 8.18762 | 8.18762 | 12.5 | 0.102345 | 0.102345 | 3740 | 12.5 | 0.04675
Gipsplaat | 00 begane grond | Gipsplaat | 91.6038 | 9.16038 | 9.16038 | 12.5 | 0.114505 | 0.114505 | 4000 | 12.5 | 0.05
Gipsplaat | 00 begane grond | Gipsplaat | 92.5388 | 9.25388 | 9.25388 | 12.5 | 0.115674 | 0.115674 | 4000 | 12.5 | 0.05
Isolatie - Steenwol LSW | 00 begane grond | Isolatie - Steenwol LSW | 26.091 | 9.48763 | 9.48763 | 50 | 0.474382 | 0.474382 | 4000 | 50 | 0.2
Gipsplaat | 00 begane grond | Gipsplaat | 95.3438 | 9.53438 | 9.53438 | 12.5 | 0.11918 | 0.11918 | 4000 | 12.5 | 0.05
Gipsplaat | 00 begane grond | Gipsplaat | 88.3313 | 8.83313 | 8.83313 | 12.5 | 0.110414 | 0.110414 | 4000 | 12.5 | 0.05
4 x Gipsplaat | 00 begane grond | Gipsplaat | 157.966 | 15.7966 | 20.6915 | 12.5 | 0.197457 | 0.258644 | 3740 | 12.5 | 0.04675
Isolatie - Steenwol LSW | 00 begane grond | Isolatie - Steenwol LSW | 43.4406 | 15.7966 | 20.6915 | 50 | 0.789828 | 1.03458 | 3740 | 50 | 0.187
4 x Gipsplaat | 00 begane grond | Gipsplaat | 194.558 | 19.4558 | 21.9033 | 12.5 | 0.243198 | 0.273791 | 3740 | 12.5 | 0.04675
Isolatie - Steenwol LSW | 00 begane grond | Isolatie - Steenwol LSW | 53.5035 | 19.4558 | 21.9033 | 50 | 0.97279 | 1.09516 | 3740 | 50 | 0.187
4 x Gipsplaat | 00 begane grond | Gipsplaat | 301.798 | 30.1798 | 37.5222 | 12.5 | 0.377248 | 0.469028 | 3740 | 12.5 | 0.04675
Isolatie - Steenwol LSW | 00 begane grond | Isolatie - Steenwol LSW | 82.9945 | 30.1798 | 37.5222 | 50 | 1.50899 | 1.87611 | 3740 | 50 | 0.187
5 x Gipsplaat | 00 begane grond | Gipsplaat | 155.873 | 15.5873 | 15.5873 | 12.5 | 0.194841 | 0.194841 | 3740 | 12.5 | 0.04675
Isolatie - Steenwol LSW | 00 begane grond | Isolatie - Steenwol LSW | 42.8651 | 15.5873 | 15.5873 | 50 | 0.779365 | 0.779365 | 3740 | 50 | 0.187
4 x Gipsplaat | 00 begane grond | Gipsplaat | 114.779 | 11.4779 | 11.4779 | 12.5 | 0.143474 | 0.143474 | 3680 | 12.5 | 0.046
Isolatie - Steenwol LSW | 00 begane grond | Isolatie - Steenwol LSW | 47.3464 | 11.4779 | 11.4779 | 75 | 0.860844 | 0.860844 | 3680 | 75 | 0.276
4 x Gipsplaat | 00 begane grond | Gipsplaat | 25.3318 | 2.53319 | 6.9003 | 12.5 | 0.0316648 | 0.0862538 | 3740 | 12.5 | 0.04675
Isolatie - Steenwol LSW | 00 begane grond | Isolatie - Steenwol LSW | 6.96626 | 2.53319 | 6.9003 | 50 | 0.126659 | 0.345015 | 3740 | 50 | 0.187
6 x Gipsplaat | 00 begane grond | Gipsplaat | 52.547 | 5.2547 | 5.2547 | 12.5 | 0.0656837 | 0.0656837 | 3740 | 12.5 | 0.04675
Isolatie - Steenwol LSW | 00 begane grond | Isolatie - Steenwol LSW | 21.6756 | 5.2547 | 5.2547 | 75 | 0.394103 | 0.394103 | 3740 | 75 | 0.2805
4 x Gipsplaat | 00 begane grond | Gipsplaat | 64.757 | 6.4757 | 14.2868 | 12.5 | 0.0809462 | 0.178585 | 3740 | 12.5 | 0.04675
Isolatie - Steenwol LSW | 00 begane grond | Isolatie - Steenwol LSW | 26.7123 | 6.4757 | 14.2868 | 75 | 0.485677 | 1.07151 | 3740 | 75 | 0.2805
4 x Gipsplaat | 00 begane grond | Gipsplaat | 86.7848 | 8.67848 | 8.67848 | 12.5 | 0.108481 | 0.108481 | 4485 | 12.5 | 0.0560625
Isolatie - Steenwol LSW | 00 begane grond | Isolatie - Steenwol LSW | 35.7987 | 8.67848 | 8.67848 | 75 | 0.650886 | 0.650886 | 4485 | 75 | 0.336375
6 x Gipsplaat | 00 begane grond | Gipsplaat | 76.5951 | 7.65951 | 26.7754 | 12.5 | 0.0957439 | 0.334693 | 4485 | 12.5 | 0.0560625
2 x Isolatie - Steenwol LSW | 00 begane grond | Isolatie - Steenwol LSW | 31.5955 | 7.65951 | 26.7754 | 75 | 0.574463 | 2.00816 | 4485 | 75 | 0.336375
6 x Gipsplaat | 00 begane grond | Gipsplaat | 77.3662 | 7.73663 | 7.73663 | 12.5 | 0.0967078 | 0.0967078 | 4485 | 12.5 | 0.0560625
2 x Isolatie - Steenwol LSW | 00 begane grond | Isolatie - Steenwol LSW | 31.9136 | 7.73663 | 7.73663 | 75 | 0.580247 | 0.580247 | 4485 | 75 | 0.336375
4 x Gipsplaat | 00 begane grond | Gipsplaat | 51.4618 | 5.14619 | 5.14619 | 12.5 | 0.0643273 | 0.0643273 | 1650 | 12.5 | 0.020625
Isolatie - Steenwol LSW | 00 begane grond | Isolatie - Steenwol LSW | 14.152 | 5.14619 | 5.14619 | 50 | 0.257309 | 0.257309 | 1650 | 50 | 0.0825
4 x Gipsplaat | 00 begane grond | Gipsplaat | 216.175 | 21.6175 | 26.5125 | 12.5 | 0.270219 | 0.331406 | 3740 | 12.5 | 0.04675
Isolatie - Steenwol LSW | 00 begane grond | Isolatie - Steenwol LSW | 89.1722 | 21.6175 | 26.5125 | 75 | 1.62131 | 1.98843 | 3740 | 75 | 0.2805
4 x Gipsplaat | 00 begane grond | Gipsplaat | 277.921 | 27.7921 | 30.9485 | 12.5 | 0.347401 | 0.386856 | 3740 | 12.5 | 0.04675
Isolatie - Steenwol LSW | 00 begane grond | Isolatie - Steenwol LSW | 114.642 | 27.7921 | 30.9485 | 75 | 2.0844 | 2.32114 | 3740 | 75 | 0.2805
Gipsplaat | 00 begane grond | Gipsplaat | 74.7029 | 7.47029 | 9.91777 | 12.5 | 0.0933786 | 0.123972 | 3740 | 12.5 | 0.04675
Gipsplaat | 00 begane grond | Gipsplaat | 75.1704 | 7.51704 | 9.96452 | 12.5 | 0.093963 | 0.124556 | 3740 | 12.5 | 0.04675
Isolatie - Steenwol LSW | 00 begane grond | Isolatie - Steenwol LSW | 32.1648 | 7.79754 | 10.245 | 75 | 0.584815 | 0.768376 | 3740 | 75 | 0.2805
Gipsplaat | 00 begane grond | Gipsplaat | 78.4429 | 7.84429 | 10.2918 | 12.5 | 0.0980536 | 0.128647 | 3740 | 12.5 | 0.04675
Gipsplaat | 00 begane grond | Gipsplaat | 70.4954 | 7.04954 | 9.49702 | 12.5 | 0.0881192 | 0.118713 | 3740 | 12.5 | 0.04675
4 x Gipsplaat | 00 begane grond | Gipsplaat | 91.2782 | 9.12782 | 11.5753 | 12.5 | 0.114098 | 0.144691 | 3740 | 12.5 | 0.04675
Isolatie - Steenwol LSW | 00 begane grond | Isolatie - Steenwol LSW | 37.6523 | 9.12782 | 11.5753 | 75 | 0.684587 | 0.868147 | 3740 | 75 | 0.2805
4 x Gipsplaat | 00 begane grond | Gipsplaat | 115.962 | 11.5962 | 14.0437 | 12.5 | 0.144953 | 0.175546 | 3740 | 12.5 | 0.04675
Isolatie - Steenwol LSW | 00 begane grond | Isolatie - Steenwol LSW | 47.8344 | 11.5962 | 14.0437 | 75 | 0.869717 | 1.05328 | 3740 | 75 | 0.2805
Gipsplaat | 00 begane grond | Gipsplaat | 21.8147 | 2.18147 | 4.62894 | 12.5 | 0.0272683 | 0.0578618 | 3740 | 12.5 | 0.04675
Gipsplaat | 00 begane grond | Gipsplaat | 29.7622 | 2.97622 | 5.42369 | 12.5 | 0.0372027 | 0.0677962 | 3740 | 12.5 | 0.04675
Isolatie - Steenwol LSW | 00 begane grond | Isolatie - Steenwol LSW | 12.084 | 2.92947 | 5.37694 | 75 | 0.21971 | 0.403271 | 3740 | 75 | 0.2805
Gipsplaat | 00 begane grond | Gipsplaat | 26.4897 | 2.64897 | 5.09644 | 12.5 | 0.0331121 | 0.0637056 | 3740 | 12.5 | 0.04675
Gipsplaat | 00 begane grond | Gipsplaat | 26.0222 | 2.60222 | 5.04969 | 12.5 | 0.0325277 | 0.0631212 | 3740 | 12.5 | 0.04675
Gipsplaat | 00 begane grond | Gipsplaat | 74.7685 | 7.47685 | 7.47685 | 12.5 | 0.0934606 | 0.0934606 | 3740 | 12.5 | 0.04675
Gipsplaat | 00 begane grond | Gipsplaat | 75.236 | 7.5236 | 7.5236 | 12.5 | 0.094045 | 0.094045 | 3740 | 12.5 | 0.04675
Isolatie - Steenwol LSW | 00 begane grond | Isolatie - Steenwol LSW | 32.1919 | 7.8041 | 7.8041 | 75 | 0.585307 | 0.585307 | 3740 | 75 | 0.2805
Gipsplaat | 00 begane grond | Gipsplaat | 78.5085 | 7.85085 | 7.85085 | 12.5 | 0.0981356 | 0.0981356 | 3740 | 12.5 | 0.04675
Gipsplaat | 00 begane grond | Gipsplaat | 78.976 | 7.8976 | 7.8976 | 12.5 | 0.09872 | 0.09872 | 3740 | 12.5 | 0.04675
4 x Gipsplaat | 00 begane grond | Gipsplaat | 130.9 | 13.09 | 13.09 | 12.5 | 0.163625 | 0.163625 | 3740 | 12.5 | 0.04675
Isolatie - Steenwol LSW | 00 begane grond | Isolatie - Steenwol LSW | 35.9975 | 13.09 | 13.09 | 50 | 0.6545 | 0.6545 | 3740 | 50 | 0.187
4 x Gipsplaat | 00 begane grond | Gipsplaat | 98.24 | 9.824 | 9.824 | 12.5 | 0.1228 | 0.1228 | 4000 | 12.5 | 0.05
Isolatie - Steenwol LSW | 00 begane grond | Isolatie - Steenwol LSW | 27.016 | 9.824 | 9.824 | 50 | 0.4912 | 0.4912 | 4000 | 50 | 0.2
4 x Gipsplaat | 00 begane grond | Gipsplaat | 83.2582 | 8.32582 | 13.2208 | 12.5 | 0.104073 | 0.16526 | 3740 | 12.5 | 0.04675
Isolatie - Steenwol LSW | 00 begane grond | Isolatie - Steenwol LSW | 22.896 | 8.32582 | 13.2208 | 50 | 0.416291 | 0.661039 | 3740 | 50 | 0.187
Gipsplaat | 00 begane grond | Gipsplaat | 73.7376 | 7.37376 | 9.82124 | 12.5 | 0.092172 | 0.122765 | 3740 | 12.5 | 0.04675
Gipsplaat | 00 begane grond | Gipsplaat | 74.2051 | 7.42051 | 9.86799 | 12.5 | 0.0927564 | 0.12335 | 3740 | 12.5 | 0.04675
Isolatie - Steenwol LSW | 00 begane grond | Isolatie - Steenwol LSW | 31.7667 | 7.70101 | 10.1485 | 75 | 0.577576 | 0.761137 | 3740 | 75 | 0.2805
Gipsplaat | 00 begane grond | Gipsplaat | 77.4776 | 7.74776 | 10.1952 | 12.5 | 0.096847 | 0.127441 | 3740 | 12.5 | 0.04675
Gipsplaat | 00 begane grond | Gipsplaat | 77.9451 | 7.79451 | 10.242 | 12.5 | 0.0974314 | 0.128025 | 3740 | 12.5 | 0.04675
Gipsplaat | 00 begane grond | Gipsplaat | 106.347 | 10.6347 | 10.6347 | 12.5 | 0.132934 | 0.132934 | 3740 | 12.5 | 0.04675
Gipsplaat | 00 begane grond | Gipsplaat | 105.412 | 10.5412 | 10.5412 | 12.5 | 0.131765 | 0.131765 | 3740 | 12.5 | 0.04675
Isolatie - Steenwol LSW | 00 begane grond | Isolatie - Steenwol LSW | 42.1325 | 10.2139 | 10.2139 | 75 | 0.766046 | 0.766046 | 3740 | 75 | 0.2805
Gipsplaat | 00 begane grond | Gipsplaat | 98.8669 | 9.88669 | 9.88669 | 12.5 | 0.123584 | 0.123584 | 3740 | 12.5 | 0.04675
Gipsplaat | 00 begane grond | Gipsplaat | 97.9319 | 9.79319 | 9.79319 | 12.5 | 0.122415 | 0.122415 | 3740 | 12.5 | 0.04675
4 x Gipsplaat | 00 begane grond | Gipsplaat | 102.139 | 10.2139 | 10.2139 | 12.5 | 0.127674 | 0.127674 | 3740 | 12.5 | 0.04675
Isolatie - Steenwol LSW | 00 begane grond | Isolatie - Steenwol LSW | 28.0883 | 10.2139 | 10.2139 | 50 | 0.510697 | 0.510697 | 3740 | 50 | 0.187
Gipsplaat | 00 begane grond | Gipsplaat | 88.5704 | 8.85704 | 11.3045 | 12.5 | 0.110713 | 0.141307 | 3740 | 12.5 | 0.04675
Gipsplaat | 00 begane grond | Gipsplaat | 89.0379 | 8.90379 | 11.3513 | 12.5 | 0.111297 | 0.141891 | 3740 | 12.5 | 0.04675
Isolatie - Steenwol LSW | 00 begane grond | Isolatie - Steenwol LSW | 24.9997 | 9.09079 | 11.5383 | 50 | 0.45454 | 0.576914 | 3740 | 50 | 0.187
Gipsplaat | 00 begane grond | Gipsplaat | 91.3754 | 9.13754 | 11.585 | 12.5 | 0.114219 | 0.144813 | 3740 | 12.5 | 0.04675
Gipsplaat | 00 begane grond | Gipsplaat | 91.8429 | 9.18429 | 11.6318 | 12.5 | 0.114804 | 0.145397 | 3740 | 12.5 | 0.04675
3 x Gipsplaat | 00 begane grond | Gipsplaat | 124.339 | 12.4339 | 12.4339 | 12.5 | 0.155423 | 0.155423 | 3740 | 12.5 | 0.04675
Gipsplaat | 00 begane grond | Gipsplaat | 124.806 | 12.4806 | 12.4806 | 12.5 | 0.156008 | 0.156008 | 3740 | 12.5 | 0.04675
Isolatie - Steenwol LSW | 00 begane grond | Isolatie - Steenwol LSW | 34.4503 | 12.5274 | 12.5274 | 50 | 0.626369 | 0.626369 | 3740 | 50 | 0.187
Gipsplaat | 00 begane grond | Gipsplaat | 127.144 | 12.7144 | 12.7144 | 12.5 | 0.15893 | 0.15893 | 3740 | 12.5 | 0.04675
Gipsplaat | 00 begane grond | Gipsplaat | 127.611 | 12.7611 | 12.7611 | 12.5 | 0.159514 | 0.159514 | 3740 | 12.5 | 0.04675
4 x Gipsplaat | 00 begane grond | Gipsplaat | 87.1679 | 8.71679 | 11.1643 | 12.5 | 0.10896 | 0.139553 | 3740 | 12.5 | 0.04675
Isolatie - Steenwol LSW | 00 begane grond | Isolatie - Steenwol LSW | 23.9712 | 8.71679 | 11.1643 | 50 | 0.43584 | 0.558214 | 3740 | 50 | 0.187
Gipsplaat | 00 begane grond | Gipsplaat | 75.4519 | 7.54519 | 7.54519 | 12.5 | 0.0943149 | 0.0943149 | 3740 | 12.5 | 0.04675
Gipsplaat | 00 begane grond | Gipsplaat | 74.9844 | 7.49844 | 7.49844 | 12.5 | 0.0937305 | 0.0937305 | 3740 | 12.5 | 0.04675
Isolatie - Steenwol LSW | 00 begane grond | Isolatie - Steenwol LSW | 20.4921 | 7.45169 | 7.45169 | 50 | 0.372585 | 0.372585 | 3740 | 50 | 0.187
Gipsplaat | 00 begane grond | Gipsplaat | 72.6469 | 7.26469 | 7.26469 | 12.5 | 0.0908086 | 0.0908086 | 3740 | 12.5 | 0.04675
Gipsplaat | 00 begane grond | Gipsplaat | 72.1794 | 7.21794 | 7.21794 | 12.5 | 0.0902243 | 0.0902243 | 3740 | 12.5 | 0.04675
Gipsplaat | 00 begane grond | Gipsplaat | 16.0668 | 1.60668 | 4.05416 | 12.5 | 0.0200835 | 0.050677 | 3740 | 12.5 | 0.04675
Gipsplaat | 00 begane grond | Gipsplaat | 16.5343 | 1.65343 | 4.10091 | 12.5 | 0.0206679 | 0.0512614 | 3740 | 12.5 | 0.04675
Isolatie - Steenwol LSW | 00 begane grond | Isolatie - Steenwol LSW | 4.6755 | 1.70018 | 4.14766 | 50 | 0.0850091 | 0.207383 | 3740 | 50 | 0.187
Gipsplaat | 00 begane grond | Gipsplaat | 18.8718 | 1.88718 | 4.33466 | 12.5 | 0.0235898 | 0.0541833 | 3740 | 12.5 | 0.04675
Gipsplaat | 00 begane grond | Gipsplaat | 19.3393 | 1.93393 | 4.38141 | 12.5 | 0.0241741 | 0.0547676 | 3740 | 12.5 | 0.04675
4 x Gipsplaat | 00 begane grond | Gipsplaat | 63.1095 | 6.31095 | 6.31095 | 12.5 | 0.0788869 | 0.0788869 | 3740 | 12.5 | 0.04675
Isolatie - Steenwol LSW | 00 begane grond | Isolatie - Steenwol LSW | 17.3551 | 6.31095 | 6.31095 | 50 | 0.315548 | 0.315548 | 3740 | 50 | 0.187
Gipsplaat | 00 begane grond | Gipsplaat | 156.341 | 15.6341 | 15.6341 | 12.5 | 0.195426 | 0.195426 | 3740 | 12.5 | 0.04675
Isolatie - Steenwol LSW | 00 begane grond | Isolatie - Steenwol LSW | 43.1222 | 15.6808 | 15.6808 | 50 | 0.78404 | 0.78404 | 3740 | 50 | 0.187
Gipsplaat | 00 begane grond | Gipsplaat | 158.678 | 15.8678 | 15.8678 | 12.5 | 0.198348 | 0.198348 | 3740 | 12.5 | 0.04675
Gipsplaat | 00 begane grond | Gipsplaat | 159.146 | 15.9146 | 15.9146 | 12.5 | 0.198932 | 0.198932 | 3740 | 12.5 | 0.04675
4 x Gipsplaat | 00 begane grond | Gipsplaat | 59.2684 | 5.92684 | 5.92684 | 12.5 | 0.0740855 | 0.0740855 | 3740 | 12.5 | 0.04675
Isolatie - Steenwol LSW | 00 begane grond | Isolatie - Steenwol LSW | 16.2988 | 5.92684 | 5.92684 | 50 | 0.296342 | 0.296342 | 3740 | 50 | 0.187
4 x Gipsplaat | 00 begane grond | Gipsplaat | 26.9794 | 2.69794 | 7.3491 | 12.5 | 0.0337243 | 0.0918637 | 3740 | 12.5 | 0.04675
Isolatie - Steenwol LSW | 00 begane grond | Isolatie - Steenwol LSW | 7.41935 | 2.69794 | 7.3491 | 50 | 0.134897 | 0.367455 | 3740 | 50 | 0.187
Gipsplaat | 00 begane grond | Gipsplaat | 40.0042 | 4.00042 | 8.23735 | 12.5 | 0.0500053 | 0.102967 | 3740 | 12.5 | 0.04675
Gipsplaat | 00 begane grond | Gipsplaat | 40.4717 | 4.04717 | 8.2841 | 12.5 | 0.0505896 | 0.103551 | 3740 | 12.5 | 0.04675
Isolatie - Steenwol LSW | 00 begane grond | Isolatie - Steenwol LSW | 11.644 | 4.23417 | 8.4711 | 50 | 0.211708 | 0.423555 | 3740 | 50 | 0.187
Gipsplaat | 00 begane grond | Gipsplaat | 42.8092 | 4.28092 | 8.51785 | 12.5 | 0.0535115 | 0.106473 | 3740 | 12.5 | 0.04675
Gipsplaat | 00 begane grond | Gipsplaat | 43.2767 | 4.32767 | 8.5646 | 12.5 | 0.0540959 | 0.107057 | 3740 | 12.5 | 0.04675
4 x Gipsplaat | 00 begane grond | Gipsplaat | 60.6403 | 6.06403 | 6.06403 | 12.5 | 0.0758003 | 0.0758003 | 3740 | 12.5 | 0.04675
Isolatie - Steenwol LSW | 00 begane grond | Isolatie - Steenwol LSW | 16.6761 | 6.06403 | 6.06403 | 50 | 0.303201 | 0.303201 | 3740 | 50 | 0.187
4 x Gipsplaat | 00 begane grond | Gipsplaat | 101.541 | 10.1541 | 12.6341 | 12.5 | 0.126926 | 0.157926 | 5090 | 12.5 | 0.063625
Isolatie - Steenwol LSW | 00 begane grond | Isolatie - Steenwol LSW | 27.9238 | 10.1541 | 12.6341 | 50 | 0.507705 | 0.631704 | 5090 | 50 | 0.2545
Gipsplaat | 00 begane grond | Gipsplaat | 119.03 | 11.903 | 11.903 | 12.5 | 0.148788 | 0.148788 | 3740 | 12.5 | 0.04675
Gipsplaat | 00 begane grond | Gipsplaat | 119.965 | 11.9965 | 11.9965 | 12.5 | 0.149956 | 0.149956 | 3740 | 12.5 | 0.04675
Isolatie - Steenwol LSW | 00 begane grond | Isolatie - Steenwol LSW | 49.8713 | 12.09 | 12.09 | 75 | 0.906751 | 0.906751 | 3740 | 75 | 0.2805
Gipsplaat | 00 begane grond | Gipsplaat | 126.51 | 12.651 | 12.651 | 12.5 | 0.158138 | 0.158138 | 3740 | 12.5 | 0.04675
Gipsplaat | 00 begane grond | Gipsplaat | 127.445 | 12.7445 | 12.7445 | 12.5 | 0.159306 | 0.159306 | 3740 | 12.5 | 0.04675
8 x Gipsplaat | 00 begane grond | Gipsplaat | 103.782 | 10.3782 | 10.3782 | 12.5 | 0.129728 | 0.129728 | 3740 | 12.5 | 0.04675
2 x Isolatie - Steenwol LSW | 00 begane grond | Isolatie - Steenwol LSW | 42.8101 | 10.3782 | 10.3782 | 75 | 0.778365 | 0.778365 | 3740 | 75 | 0.2805
4 x Gipsplaat | 00 begane grond | Gipsplaat | 145.659 | 14.5659 | 14.5659 | 12.5 | 0.182074 | 0.182074 | 3740 | 12.5 | 0.04675
Isolatie - Steenwol LSW | 00 begane grond | Isolatie - Steenwol LSW | 40.0562 | 14.5659 | 14.5659 | 50 | 0.728295 | 0.728295 | 3740 | 50 | 0.187
4 x Gipsplaat | 00 begane grond | Gipsplaat | 225.069 | 22.5069 | 24.9544 | 12.5 | 0.281336 | 0.31193 | 3740 | 12.5 | 0.04675
Isolatie - Steenwol LSW | 00 begane grond | Isolatie - Steenwol LSW | 61.894 | 22.5069 | 24.9544 | 50 | 1.12534 | 1.24772 | 3740 | 50 | 0.187
4 x Gipsplaat | 00 begane grond | Gipsplaat | 150.64 | 15.064 | 15.064 | 12.5 | 0.1883 | 0.1883 | 5190 | 12.5 | 0.064875
Isolatie - Steenwol LSW | 00 begane grond | Isolatie - Steenwol LSW | 41.4259 | 15.064 | 15.064 | 50 | 0.753199 | 0.753199 | 5190 | 50 | 0.2595
4 x Gipsplaat | 00 begane grond | Gipsplaat | 147.388 | 14.7388 | 14.7388 | 12.5 | 0.184235 | 0.184235 | 5190 | 12.5 | 0.064875
Isolatie - Steenwol LSW | 00 begane grond | Isolatie - Steenwol LSW | 40.5318 | 14.7388 | 14.7388 | 50 | 0.736942 | 0.736942 | 5190 | 50 | 0.2595
4 x Gipsplaat | 00 begane grond | Gipsplaat | 52.3128 | 5.23128 | 9.91084 | 12.5 | 0.065391 | 0.123885 | 3740 | 12.5 | 0.04675
Isolatie - Steenwol LSW | 00 begane grond | Isolatie - Steenwol LSW | 14.386 | 5.23128 | 9.91084 | 50 | 0.261564 | 0.495542 | 3740 | 50 | 0.187
4 x Gipsplaat | 00 begane grond | Gipsplaat | 62.8365 | 6.28365 | 10.4496 | 12.5 | 0.0785456 | 0.13062 | 3740 | 12.5 | 0.04675
Isolatie - Steenwol LSW | 00 begane grond | Isolatie - Steenwol LSW | 17.28 | 6.28365 | 10.4496 | 50 | 0.314183 | 0.522479 | 3740 | 50 | 0.187
4 x Gipsplaat | 00 begane grond | Gipsplaat | 239.345 | 23.9346 | 26.3015 | 12.5 | 0.299182 | 0.328769 | 3740 | 12.5 | 0.04675
Isolatie - Steenwol LSW | 00 begane grond | Isolatie - Steenwol LSW | 98.73 | 23.9346 | 26.3015 | 75 | 1.79509 | 1.97262 | 3740 | 75 | 0.2805
4 x Gipsplaat | 00 begane grond | Gipsplaat | 131.974 | 13.1974 | 13.1974 | 12.5 | 0.164967 | 0.164967 | 3740 | 12.5 | 0.04675
Isolatie - Steenwol LSW | 00 begane grond | Isolatie - Steenwol LSW | 54.4393 | 13.1974 | 13.1974 | 75 | 0.989805 | 0.989805 | 3740 | 75 | 0.2805
4 x Gipsplaat | 00 begane grond | Gipsplaat | 67.2743 | 6.72743 | 12.8331 | 12.5 | 0.0840929 | 0.160413 | 3740 | 12.5 | 0.04675
Isolatie - Steenwol LSW | 00 begane grond | Isolatie - Steenwol LSW | 27.7507 | 6.72743 | 12.8331 | 75 | 0.504557 | 0.962481 | 3740 | 75 | 0.2805
Gipsplaat | 00 begane grond | Gipsplaat | 37.3129 | 3.73129 | 9.83694 | 12.5 | 0.0466411 | 0.122962 | 3740 | 12.5 | 0.04675
Gipsplaat | 00 begane grond | Gipsplaat | 36.8454 | 3.68454 | 9.79019 | 12.5 | 0.0460568 | 0.122377 | 3740 | 12.5 | 0.04675
Isolatie - Steenwol LSW | 00 begane grond | Isolatie - Steenwol LSW | 15.0059 | 3.63779 | 9.74344 | 75 | 0.272834 | 0.730758 | 3740 | 75 | 0.2805
Gipsplaat | 00 begane grond | Gipsplaat | 33.5729 | 3.35729 | 9.46294 | 12.5 | 0.0419661 | 0.118287 | 3740 | 12.5 | 0.04675
Gipsplaat | 00 begane grond | Gipsplaat | 33.1054 | 3.31054 | 9.41619 | 12.5 | 0.0413818 | 0.117702 | 3740 | 12.5 | 0.04675
Gipsplaat | 00 begane grond | Gipsplaat | 83.9349 | 8.39349 | 10.2607 | 12.5 | 0.104919 | 0.128259 | 3740 | 12.5 | 0.04675
Gipsplaat | 00 begane grond | Gipsplaat | 84.4024 | 8.44024 | 10.3074 | 12.5 | 0.105503 | 0.128843 | 3740 | 12.5 | 0.04675
Isolatie - Steenwol LSW | 00 begane grond | Isolatie - Steenwol LSW | 35.973 | 8.72074 | 10.5879 | 75 | 0.654055 | 0.794095 | 3740 | 75 | 0.2805
Gipsplaat | 00 begane grond | Gipsplaat | 87.6749 | 8.76749 | 10.6347 | 12.5 | 0.109594 | 0.132934 | 3740 | 12.5 | 0.04675
Gipsplaat | 00 begane grond | Gipsplaat | 88.1424 | 8.81424 | 10.6814 | 12.5 | 0.110178 | 0.133518 | 3740 | 12.5 | 0.04675
4 x Gipsplaat | 00 begane grond | Gipsplaat | 67.1428 | 6.71428 | 6.71428 | 12.5 | 0.0839286 | 0.0839286 | 5190 | 12.5 | 0.064875
Isolatie - Steenwol LSW | 00 begane grond | Isolatie - Steenwol LSW | 18.4643 | 6.71428 | 6.71428 | 50 | 0.335714 | 0.335714 | 5190 | 50 | 0.2595
4 x Gipsplaat | 00 begane grond | Gipsplaat | 95.6336 | 9.56336 | 26.0502 | 12.5 | 0.119542 | 0.325628 | 3740 | 12.5 | 0.04675
Isolatie - Steenwol LSW | 00 begane grond | Isolatie - Steenwol LSW | 26.2992 | 9.56336 | 26.0502 | 50 | 0.478168 | 1.30251 | 3740 | 50 | 0.187
Gipsplaat | 00 begane grond | Gipsplaat | 52.9432 | 5.29432 | 7.7418 | 12.5 | 0.066179 | 0.0967725 | 3740 | 12.5 | 0.04675
Gipsplaat | 00 begane grond | Gipsplaat | 53.4107 | 5.34107 | 7.78855 | 12.5 | 0.0667634 | 0.0973569 | 3740 | 12.5 | 0.04675
Isolatie - Steenwol LSW | 00 begane grond | Isolatie - Steenwol LSW | 15.2022 | 5.52807 | 7.97555 | 50 | 0.276404 | 0.398778 | 3740 | 50 | 0.187
Gipsplaat | 00 begane grond | Gipsplaat | 55.7482 | 5.57482 | 8.0223 | 12.5 | 0.0696853 | 0.100279 | 3740 | 12.5 | 0.04675
Gipsplaat | 00 begane grond | Gipsplaat | 56.2157 | 5.62157 | 8.06905 | 12.5 | 0.0702697 | 0.100863 | 3740 | 12.5 | 0.04675
2 x Gipsplaat | 00 begane grond | Gipsplaat | 156.611 | 15.6611 | 15.6611 | 12.5 | 0.195764 | 0.195764 | 3740 | 12.5 | 0.04675
Gipsplaat | 00 begane grond | Gipsplaat | 156.144 | 15.6144 | 15.6144 | 12.5 | 0.19518 | 0.19518 | 3740 | 12.5 | 0.04675
Isolatie - Steenwol LSW | 00 begane grond | Isolatie - Steenwol LSW | 42.4253 | 15.4274 | 15.4274 | 50 | 0.77137 | 0.77137 | 3740 | 50 | 0.187
2 x Gipsplaat | 00 begane grond | Gipsplaat | 153.806 | 15.3806 | 15.3806 | 12.5 | 0.192258 | 0.192258 | 3740 | 12.5 | 0.04675
Gipsplaat | 00 begane grond | Gipsplaat | 153.339 | 15.3339 | 15.3339 | 12.5 | 0.191674 | 0.191674 | 3740 | 12.5 | 0.04675
Gipsplaat | 00 begane grond | Gipsplaat | 157.079 | 15.7079 | 15.7079 | 12.5 | 0.196349 | 0.196349 | 3740 | 12.5 | 0.04675
Isolatie - Steenwol LSW | 00 begane grond | Isolatie - Steenwol LSW | 42.9396 | 15.6144 | 15.6144 | 50 | 0.78072 | 0.78072 | 3740 | 50 | 0.187
Gipsplaat | 00 begane grond | Gipsplaat | 154.274 | 15.4274 | 15.4274 | 12.5 | 0.192842 | 0.192842 | 3740 | 12.5 | 0.04675
4 x Gipsplaat | 00 begane grond | Gipsplaat | 131.469 | 13.1469 | 13.1469 | 12.5 | 0.164336 | 0.164336 | 3740 | 12.5 | 0.04675
Isolatie - Steenwol LSW | 00 begane grond | Isolatie - Steenwol LSW | 54.2309 | 13.1469 | 13.1469 | 75 | 0.986017 | 0.986017 | 3740 | 75 | 0.2805
4 x Gipsplaat | 00 begane grond | Gipsplaat | 68.0672 | 6.80672 | 12.9124 | 12.5 | 0.085084 | 0.161405 | 3740 | 12.5 | 0.04675
Isolatie - Steenwol LSW | 00 begane grond | Isolatie - Steenwol LSW | 28.0777 | 6.80672 | 12.9124 | 75 | 0.510504 | 0.968427 | 3740 | 75 | 0.2805
Gipsplaat | 00 begane grond | Gipsplaat | 32.3501 | 3.23501 | 9.34065 | 12.5 | 0.0404376 | 0.116758 | 3740 | 12.5 | 0.04675
Gipsplaat | 00 begane grond | Gipsplaat | 32.8175 | 3.28175 | 9.3874 | 12.5 | 0.0410219 | 0.117343 | 3740 | 12.5 | 0.04675
Isolatie - Steenwol LSW | 00 begane grond | Isolatie - Steenwol LSW | 14.6943 | 3.56225 | 9.6679 | 75 | 0.267169 | 0.725093 | 3740 | 75 | 0.2805
Gipsplaat | 00 begane grond | Gipsplaat | 36.09 | 3.609 | 9.71465 | 12.5 | 0.0451126 | 0.121433 | 3740 | 12.5 | 0.04675
Gipsplaat | 00 begane grond | Gipsplaat | 36.5575 | 3.65576 | 9.7614 | 12.5 | 0.0456969 | 0.122018 | 3740 | 12.5 | 0.04675
Gipsplaat | 00 begane grond | Gipsplaat | 79.2043 | 7.92043 | 9.78763 | 12.5 | 0.0990054 | 0.122345 | 3740 | 12.5 | 0.04675
Gipsplaat | 00 begane grond | Gipsplaat | 78.7368 | 7.87368 | 9.74088 | 12.5 | 0.098421 | 0.121761 | 3740 | 12.5 | 0.04675
Isolatie - Steenwol LSW | 00 begane grond | Isolatie - Steenwol LSW | 32.2861 | 7.82693 | 9.69413 | 75 | 0.58702 | 0.72706 | 3740 | 75 | 0.2805
Gipsplaat | 00 begane grond | Gipsplaat | 75.4643 | 7.54643 | 9.41363 | 12.5 | 0.0943304 | 0.11767 | 3740 | 12.5 | 0.04675
Gipsplaat | 00 begane grond | Gipsplaat | 74.9968 | 7.49968 | 9.36688 | 12.5 | 0.093746 | 0.117086 | 3740 | 12.5 | 0.04675
3 x Gipsplaat | 00 begane grond | Gipsplaat | 146.36 | 14.636 | 14.636 | 12.5 | 0.18295 | 0.18295 | 5450 | 12.5 | 0.068125
Isolatie - Steenwol LSW | 00 begane grond | Isolatie - Steenwol LSW | 40.2489 | 14.636 | 14.636 | 50 | 0.731799 | 0.731799 | 5450 | 50 | 0.2725
Gipsplaat | 00 begane grond | Gipsplaat | 146.129 | 14.636 | 14.636 | 12.5 | 0.182662 | 0.182662 | 5450 | 12.5 | 0.068125
4 x Gipsplaat | 00 begane grond | Gipsplaat | 239.82 | 23.982 | 26.349 | 12.5 | 0.299775 | 0.329362 | 3740 | 12.5 | 0.04675
Isolatie - Steenwol LSW | 00 begane grond | Isolatie - Steenwol LSW | 98.9257 | 23.982 | 26.349 | 75 | 1.79865 | 1.97617 | 3740 | 75 | 0.2805
ALG - ISOLATIE | 00 begane grond | ALG - ISOLATIE | 154.28 | 24.4889 | 24.4889 | 140 | 3.42845 | 3.42845 | 2000 | 140 | 0.28
Steen - Baksteen Hoofd | 00 begane grond | Steen - Baksteen Hoofd | 3920.86 | 24.5054 | 24.5054 | 100 | 2.45054 | 2.45054 | 2000 | 100 | 0.2
2 x Metaal - Staal C | 00 begane grond | Metaal - Staal C | 8.09193 |  |  |  | 0.00101785 | 0.00101785 |  |  | 0.000920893
2 x Steen - Baksteen Accent Rollaag | 00 begane grond | Steen - Baksteen Accent Rollaag | 67.5333 |  |  |  | 0.0422083 | 0.0422083 | 210 | 100 | 0.021
2 x Metaal - Staal AFW | 00 begane grond | Metaal - Staal AFW | 4.9856 |  |  |  | 0.00062712 | 0.00062712 | 4 | 90 | 0.00036
Metaal - Staal C | 00 begane grond | Metaal - Staal C | 4.0661 |  |  |  | 0.000511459 | 0.000511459 |  |  | 0.000920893
Steen - Baksteen Accent Rollaag | 00 begane grond | Steen - Baksteen Accent Rollaag | 33.9347 |  |  |  | 0.0212092 | 0.0212092 | 210 | 100 | 0.021
Metaal - Staal AFW | 00 begane grond | Metaal - Staal AFW | 2.5052 |  |  |  | 0.00031512 | 0.00031512 | 4 | 90 | 0.00036
8 x ALG - ISOLATIE | 00 begane grond | ALG - ISOLATIE | 0.998991 |  |  |  | 0.0221998 | 0.0221998 | 157 | 140 | 0.02198
8 x Hout AFW | 00 begane grond | Hout AFW | 1.71094 |  |  |  | 0.0031108 | 0.0031108 | 70 | 44 | 0.00308
8 x Isolatie - PUR gespoten | 00 begane grond | Isolatie - PUR gespoten | 0.0224826 |  |  |  | 0.00064236 | 0.00064236 | 53 | 12 | 0.000636
Steen - Baksteen Accent Rollaag | 00 begane grond | Steen - Baksteen Accent Rollaag | 55.1037 |  |  |  | 0.0344398 | 0.0344398 | 210 | 100 | 0.021
ALG - ISOLATIE | 00 begane grond | ALG - ISOLATIE | 2.16972 |  |  |  | 0.048216 | 0.048216 | 210 | 140 | 0.0294
Steen - Baksteen Accent Rollaag | 00 begane grond | Steen - Baksteen Accent Rollaag | 36.0862 |  |  |  | 0.0225539 | 0.0225539 | 210 | 100 | 0.021
ALG - ISOLATIE | 00 begane grond | ALG - ISOLATIE | 1.4209 |  |  |  | 0.0315756 | 0.0315756 | 210 | 140 | 0.0294
Steen - Baksteen Accent Rollaag | 00 begane grond | Steen - Baksteen Accent Rollaag | 32.9277 |  |  |  | 0.0205798 | 0.0205798 | 210 | 100 | 0.021
2 x ALG - ISOLATIE | 00 begane grond | ALG - ISOLATIE | 1.29654 |  |  |  | 0.028812 | 0.028812 | 210 | 140 | 0.0294
Steen - Baksteen Accent Rollaag | 00 begane grond | Steen - Baksteen Accent Rollaag | 105.628 |  |  |  | 0.0660173 | 0.0660173 | 210 | 100 | 0.021
ALG - ISOLATIE | 00 begane grond | ALG - ISOLATIE | 4.16597 |  |  |  | 0.0925772 | 0.0925772 | 210 | 140 | 0.0294
2 x Metaal - Staal C | 00 begane grond | Metaal - Staal C | 1.35201 |  |  |  | 0.000170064 | 0.000170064 |  |  | 0.000920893
2 x Steen - Baksteen Accent Rollaag | 00 begane grond | Steen - Baksteen Accent Rollaag | 67.4004 |  |  |  | 0.0421252 | 0.0421252 | 210 | 100 | 0.021
2 x Metaal - Staal AFW | 00 begane grond | Metaal - Staal AFW | 5.62478 |  |  |  | 0.00070752 | 0.00070752 | 4 | 90 | 0.00036
Steen - Baksteen Accent Rollaag | 00 begane grond | Steen - Baksteen Accent Rollaag | 29.2125 |  |  |  | 0.0182578 | 0.0182578 | 210 | 100 | 0.021
2 x Steen - Baksteen Accent Rollaag | 00 begane grond | Steen - Baksteen Accent Rollaag | 44.0067 |  |  |  | 0.0275042 | 0.0275042 | 210 | 100 | 0.021
ALG - ISOLATIE | 00 begane grond | ALG - ISOLATIE | 1.54791 |  |  |  | 0.034398 | 0.034398 | 210 | 140 | 0.0294
ALG - ISOLATIE | 00 begane grond | ALG - ISOLATIE | 2.67246 |  |  |  | 0.059388 | 0.059388 | 210 | 140 | 0.0294
Steen - Baksteen Accent Rollaag | 00 begane grond | Steen - Baksteen Accent Rollaag | 73.92 |  |  |  | 0.0462 | 0.0462 | 210 | 100 | 0.021
Metaal - Staal C | 00 begane grond | Metaal - Staal C | 0.714344 |  |  |  | 0.0000898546 | 0.0000898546 |  |  | 0.000920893
Steen - Baksteen Accent Rollaag | 00 begane grond | Steen - Baksteen Accent Rollaag | 35.6115 |  |  |  | 0.0222572 | 0.0222572 | 210 | 100 | 0.021
Metaal - Staal AFW | 00 begane grond | Metaal - Staal AFW | 2.9719 |  |  |  | 0.000373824 | 0.000373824 | 4 | 90 | 0.00036
ALG - ISOLATIE | 00 begane grond | ALG - ISOLATIE | 1.05042 |  |  |  | 0.0233428 | 0.0233428 | 157 | 140 | 0.02198
Hout AFW | 00 begane grond | Hout AFW | 1.79903 |  |  |  | 0.00327096 | 0.00327096 | 70 | 44 | 0.00308
Isolatie - PUR gespoten | 00 begane grond | Isolatie - PUR gespoten | 0.0236401 |  |  |  | 0.000675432 | 0.000675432 | 53 | 12 | 0.000636
8 x Gipsplaat | 00 begane grond | Gipsplaat | 16.3625 | 1.63625 | 1.63625 | 12.5 | 0.0204531 | 0.0204531 | 3740 | 12.5 | 0.04675
2 x Isolatie - Steenwol LSW | 00 begane grond | Isolatie - Steenwol LSW | 5.78531 | 1.4025 | 1.4025 | 75 | 0.105188 | 0.105188 | 3740 | 75 | 0.2805
4 x Gipsplaat | 00 begane grond | Gipsplaat | 54.3426 | 5.43426 | 7.88173 | 12.5 | 0.0679282 | 0.0985217 | 3740 | 12.5 | 0.04675
Isolatie - Steenwol LSW | 00 begane grond | Isolatie - Steenwol LSW | 14.9442 | 5.43426 | 7.88173 | 50 | 0.271713 | 0.394087 | 3740 | 50 | 0.187
Gipsplaat | 00 begane grond | Gipsplaat | 65.672 | 6.5672 | 9.72364 | 12.5 | 0.08209 | 0.121545 | 3740 | 12.5 | 0.04675
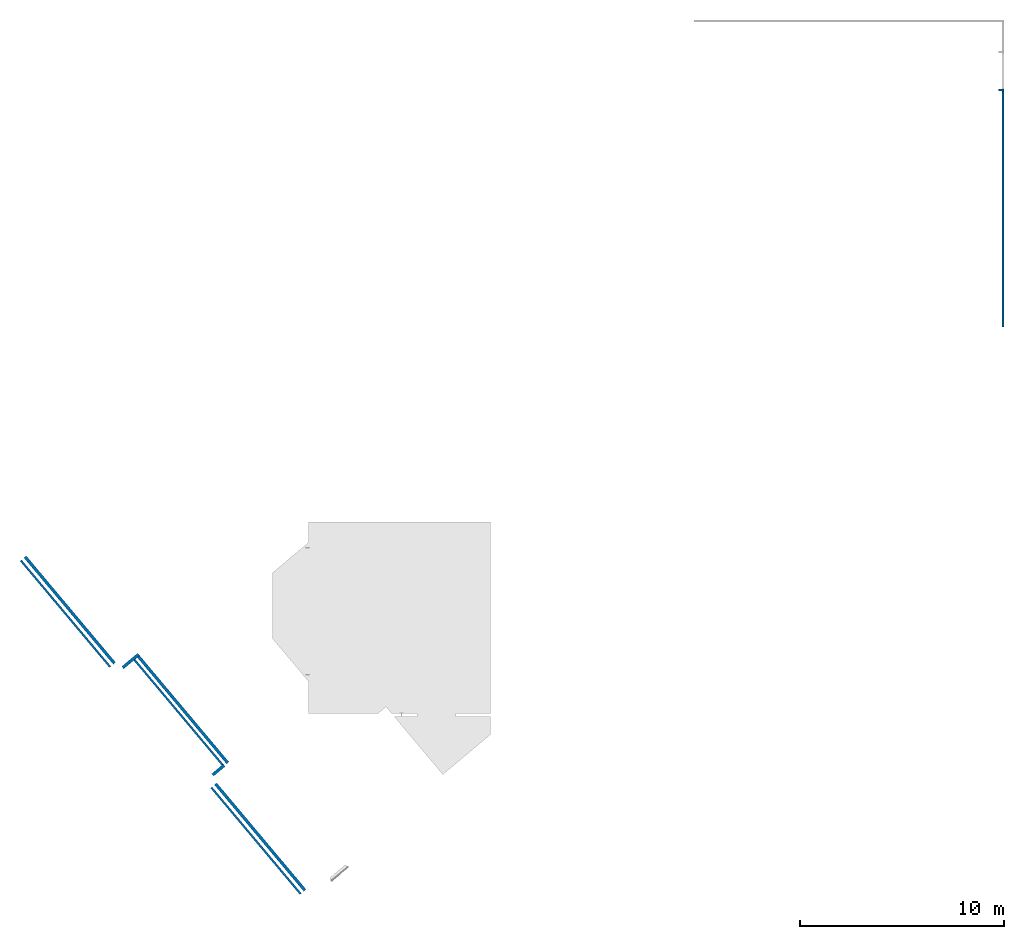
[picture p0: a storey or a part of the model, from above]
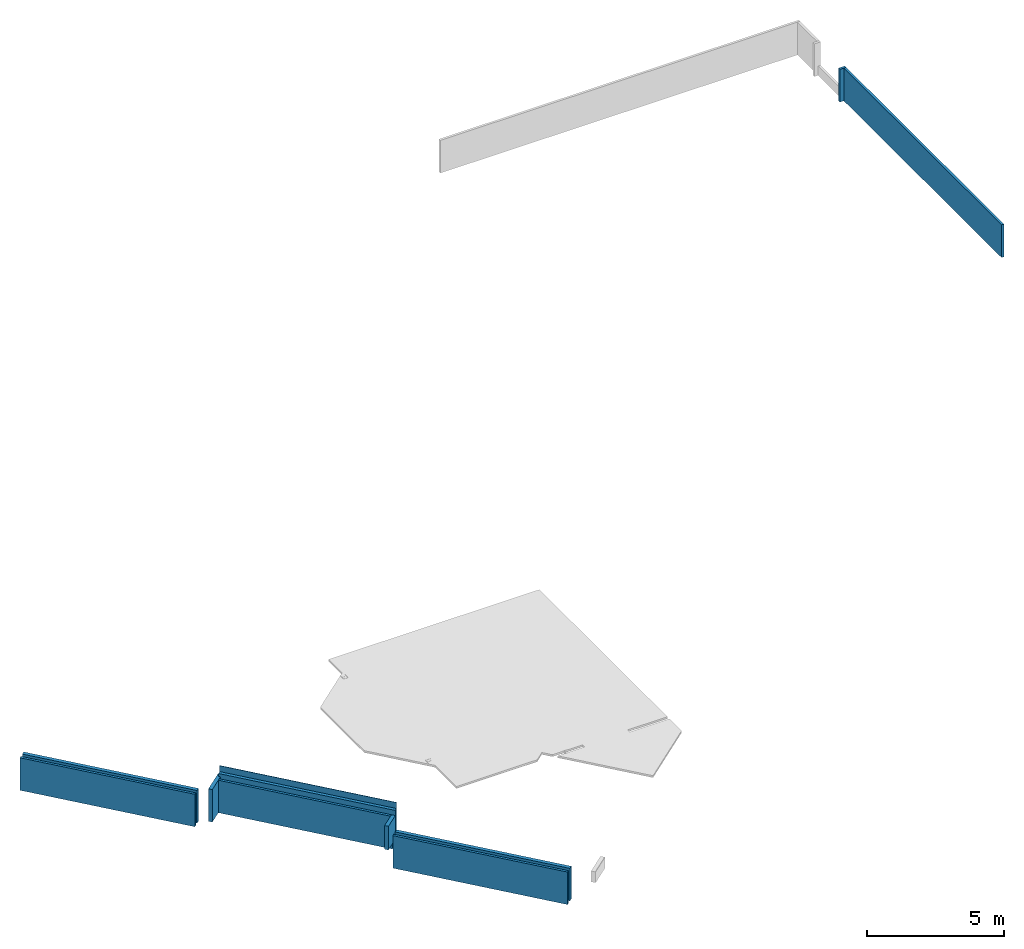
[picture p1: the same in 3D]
Properties of the parts of a building model (IFC2X3), part 2 of 11

# IfcBuildingElementPart (2314)
Name | In | Material | Mass (kg) | Projected Component Area (Net) (m2) | Projected Component Area (Gross) (m2) | Component Thickness (mm) | Component Volume (Net) (m3) | Component Volume (Gross) (m3) | Rectangular Component Height (mm) | Rectangular Component Width (mm) | Component Cross Section Area (m2)
Gipsplaat | 00 begane grond | Gipsplaat | 66.1395 | 6.61395 | 9.77039 | 12.5 | 0.0826743 | 0.12213 | 3740 | 12.5 | 0.04675
Isolatie - Steenwol LSW | 00 begane grond | Isolatie - Steenwol LSW | 18.3169 | 6.6607 | 9.81714 | 50 | 0.333035 | 0.490857 | 3740 | 50 | 0.187
Gipsplaat | 00 begane grond | Gipsplaat | 68.477 | 6.8477 | 10.0041 | 12.5 | 0.0855962 | 0.125052 | 3740 | 12.5 | 0.04675
Gipsplaat | 00 begane grond | Gipsplaat | 68.9445 | 6.89445 | 10.0509 | 12.5 | 0.0861806 | 0.125636 | 3740 | 12.5 | 0.04675
ALG - ISOLATIE | 00 begane grond | ALG - ISOLATIE | 119.054 | 18.8974 | 30.4837 | 140 | 2.64564 | 4.26771 | 3272.5 | 140 | 0.45815
Steen - Baksteen Accent | 00 begane grond | Steen - Baksteen Accent | 3023.59 | 18.8974 | 30.4837 | 100 | 1.88974 | 3.04837 | 3272.5 | 100 | 0.32725
ALG - ISOLATIE | 00 begane grond | ALG - ISOLATIE | 8.43601 | 1.33905 | 1.33905 | 140 | 0.187467 | 0.187467 | 395 | 140 | 0.0553
Steen - Baksteen Accent | 00 begane grond | Steen - Baksteen Accent | 214.248 | 1.33905 | 1.33905 | 100 | 0.133905 | 0.133905 | 395 | 100 | 0.0395
Metaal - Staal C | 00 begane grond | Metaal - Staal C | 0.679367 |  |  |  | 0.0000854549 | 0.0000854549 |  |  | 0.000920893
Steen - Baksteen Accent Rollaag | 00 begane grond | Steen - Baksteen Accent Rollaag | 33.8678 |  |  |  | 0.0211674 | 0.0211674 | 210 | 100 | 0.021
Metaal - Staal AFW | 00 begane grond | Metaal - Staal AFW | 2.82638 |  |  |  | 0.00035552 | 0.00035552 | 4 | 90 | 0.00036
Steen - Baksteen Accent | 00 begane grond | Steen - Baksteen Accent | 3973.25 | 24.8385 | 36.4281 | 100 | 2.48328 | 3.63874 | 3285 | 100 | 0.3285
ALG - ISOLATIE | 00 begane grond | ALG - ISOLATIE | 156.44 | 24.8385 | 36.4281 | 140 | 3.47644 | 5.09994 | 3285 | 140 | 0.4599
ALG - ISOLATIE | 00 begane grond | ALG - ISOLATIE | 9.46303 | 1.50207 | 1.50207 | 140 | 0.210289 | 0.210289 | 652.5 | 140 | 0.09135
Steen - Baksteen Hoofd | 00 begane grond | Steen - Baksteen Hoofd | 240.331 | 1.50207 | 1.50207 | 100 | 0.150207 | 0.150207 | 652.5 | 100 | 0.06525
Cement | 00 begane grond | Cement | 2671.82 | 20.0907 | 20.0907 | 70 | 1.40622 | 1.40622
Isolatie - XPS zwevende dekvloer | 00 begane grond | Isolatie - XPS zwevende dekvloer | 14.0635 | 20.0907 | 20.0907 | 20 | 0.401814 | 0.401814
Cement | 00 begane grond | Cement | 2598.28 | 19.5384 | 19.5384 | 70 | 1.36752 | 1.36752
Isolatie - XPS zwevende dekvloer | 00 begane grond | Isolatie - XPS zwevende dekvloer | 13.6769 | 19.5384 | 19.5384 | 20 | 0.390769 | 0.390769
4 x Steen - Kunststeen | 00 begane grond | Steen - Kunststeen | 42.3103 |  |  |  | 0.0264439 | 0.0264439 |  |  | 0.0131562
4 x Hout AFW | 00 begane grond | Hout AFW | 3.67579 |  |  |  | 0.00668325 | 0.00668325 | 87.5 | 38 | 0.003325
4 x Isolatie - PUR gespoten | 00 begane grond | Isolatie - PUR gespoten | 0.0615563 |  |  |  | 0.00175875 | 0.00175875 | 87.5 | 10 | 0.000875
4 x Gipsplaat | 00 begane grond | Gipsplaat | 59.0659 | 5.90659 | 5.90659 | 12.5 | 0.0738324 | 0.0738324 | 5190 | 12.5 | 0.064875
Isolatie - Steenwol LSW | 00 begane grond | Isolatie - Steenwol LSW | 16.2431 | 5.90659 | 5.90659 | 50 | 0.295329 | 0.295329 | 5190 | 50 | 0.2595
Gipsplaat | 00 begane grond | Gipsplaat | 11.1648 | 1.11582 | 2.4795 | 12.5 | 0.013956 | 0.0309938 | 1450 | 12.5 | 0.018125
Gipsplaat | 00 begane grond | Gipsplaat | 11.1582 | 1.11582 | 2.4795 | 12.5 | 0.0139477 | 0.0309938 | 1450 | 12.5 | 0.018125
Isolatie - Steenwol LSW | 00 begane grond | Isolatie - Steenwol LSW | 3.0685 | 1.11582 | 2.4795 | 50 | 0.0557908 | 0.123975 | 1450 | 50 | 0.0725
4 x Hout AFW | 00 begane grond | Hout AFW | 2.16356 |  |  |  | 0.00393374 | 0.00393374
4 x Metaal - RVS | 00 begane grond | Metaal - RVS | 0.39579 |  |  |  | 0.0000501 | 0.0000501
4 x Hout AFW | 00 begane grond | Hout AFW | 0.232277 |  |  |  | 0.000422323 | 0.000422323
6 x Metaal - RVS | 00 begane grond | Metaal - RVS | 0.129093 |  |  |  | 0.0000163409 | 0.0000163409
 | 00 begane grond |  |  |  |  |  | 0.81809 | 0.81809
Glas | 00 begane grond | Glas | 8674.59 |  |  |  | 3.97917 | 3.97917
Gipsplaat | 00 begane grond | Gipsplaat | 30.4434 | 3.04434 | 6.04074 | 12.5 | 0.0380542 | 0.0755092 | 3650 | 12.5 | 0.045625
Gipsplaat | 00 begane grond | Gipsplaat | 29.9871 | 2.99871 | 5.99511 | 12.5 | 0.0374839 | 0.0749389 | 3650 | 12.5 | 0.045625
Isolatie - Steenwol LSW | 00 begane grond | Isolatie - Steenwol LSW | 8.12099 | 2.95309 | 5.94949 | 50 | 0.147654 | 0.297474 | 3650 | 50 | 0.1825
Gipsplaat | 00 begane grond | Gipsplaat | 27.7059 | 2.77059 | 5.76699 | 12.5 | 0.0346323 | 0.0720873 | 3650 | 12.5 | 0.045625
Gipsplaat | 00 begane grond | Gipsplaat | 27.2496 | 2.72496 | 5.72136 | 12.5 | 0.034062 | 0.071517 | 3650 | 12.5 | 0.045625
Isolatie - Steenwol LSW | 00 begane grond | Isolatie - Steenwol LSW | 14.5542 | 5.29242 | 5.29242 | 50 | 0.264621 | 0.264621 | 1430.02 | 50 | 0.0715011
2 x Gipsplaat | 00 begane grond | Gipsplaat | 53.9812 | 5.39812 | 5.39812 | 12.5 | 0.0674765 | 0.0674765 | 1430.02 | 12.5 | 0.0178753
Beton gewapend C | 00 begane grond | Beton gewapend C | 340.653 |  |  |  | 0.14811 | 0.14811 | 570 | 70 | 0.0399
Beton gewapend C | 00 begane grond | Beton gewapend C | 2539.92 |  |  |  | 1.10431 | 1.10431 |  |  | 0.36375
Beton gewapend C | 00 begane grond | Beton gewapend C | 353.877 |  |  |  | 0.15386 | 0.15386 | 570 | 70 | 0.0399
Beton gewapend C | 00 begane grond | Beton gewapend C | 2878.24 |  |  |  | 1.25141 | 1.25141 |  |  | 0.36375
Beton gewapend C | 00 begane grond | Beton gewapend C | 292.097 |  |  |  | 0.126999 | 0.126999 | 570 | 70 | 0.0399
Beton gewapend C | 00 begane grond | Beton gewapend C | 2184.62 |  |  |  | 0.949836 | 0.949836 |  |  | 0.36375
13 x Metaal - Aluminium | 00 begane grond | Metaal - Aluminium | 16.8 | 6 | 6 | 1 | 0.006 | 0.006 | 6000 | 1 | 0.006
13 x Isolatie - Kunststof hard | 00 begane grond | Isolatie - Kunststof hard | 58.8 | 6 | 6 | 98 | 0.588 | 0.588 | 6000 | 98 | 0.588
6 x Metaal - Aluminium | 00 begane grond | Metaal - Aluminium | 16.7471 | 6 | 6 | 1 | 0.00598111 | 0.00598111 | 6000 | 1 | 0.006
6 x Metaal - Aluminium | 00 begane grond | Metaal - Aluminium | 16.747 | 5.98107 | 5.98107 | 1 | 0.00598107 | 0.00598107 | 6000 | 1 | 0.006
6 x Metaal - Aluminium | 00 begane grond | Metaal - Aluminium | 33.6 | 12 | 12 | 1 | 0.012 | 0.012 | 6000 | 1 | 0.006
5 x Isolatie - Kunststof hard | 00 begane grond | Isolatie - Kunststof hard | 117.6 | 12 | 12 | 98 | 1.176 | 1.176 | 6000 | 98 | 0.588
Metaal - Aluminium | 00 begane grond | Metaal - Aluminium | 33.494 | 11.9621 | 11.9621 | 1 | 0.0119621 | 0.0119621 | 6000 | 1 | 0.006
Metaal - Aluminium | 00 begane grond | Metaal - Aluminium | 21.5883 | 7.7101 | 7.7101 | 1 | 0.0077101 | 0.0077101 | 6000 | 1 | 0.006
Isolatie - Kunststof hard | 00 begane grond | Isolatie - Kunststof hard | 75.5589 | 7.7101 | 7.7101 | 98 | 0.755589 | 0.755589 | 6000 | 98 | 0.588
Metaal - Aluminium | 00 begane grond | Metaal - Aluminium | 21.5211 | 7.68765 | 7.68765 | 1 | 0.0076861 | 0.0076861 | 6000 | 1 | 0.006
4 x Metaal - Aluminium | 00 begane grond | Metaal - Aluminium | 33.4942 | 12 | 12 | 1 | 0.0119622 | 0.0119622 | 6000 | 1 | 0.006
4 x Gipsplaat | 00 begane grond | Gipsplaat | 65.6997 | 6.56997 | 6.56997 | 12.5 | 0.0821246 | 0.0821246 | 4000 | 12.5 | 0.05
Isolatie - Steenwol LSW | 00 begane grond | Isolatie - Steenwol LSW | 18.0674 | 6.56997 | 6.56997 | 50 | 0.328499 | 0.328499 | 4000 | 50 | 0.2
4 x Gipsplaat | 00 begane grond | Gipsplaat | 28.2809 | 2.82809 | 5.94707 | 12.5 | 0.0353511 | 0.0743383 | 3710 | 12.5 | 0.046375
Isolatie - Steenwol LSW | 00 begane grond | Isolatie - Steenwol LSW | 7.77724 | 2.82809 | 5.94707 | 50 | 0.141404 | 0.297353 | 3710 | 50 | 0.1855
Isolatie - Steenwol LSW | 00 begane grond | Isolatie - Steenwol LSW | 0.580835 | 0.219586 | 0.219586 | 50 | 0.0105606 | 0.0107084 | 970 | 50 | 0.0485
Gipsplaat | 00 begane grond | Gipsplaat | 2.24935 | 0.227562 | 0.227562 | 12.5 | 0.00281169 | 0.00284452 | 970 | 12.5 | 0.012125
Gipsplaat | 00 begane grond | Gipsplaat | 2.27562 | 0.227562 | 0.227562 | 12.5 | 0.00284452 | 0.00284452 | 970 | 12.5 | 0.012125
Isolatie - Steenwol LSW | 00 begane grond | Isolatie - Steenwol LSW | 0.597932 | 0.221693 | 0.221693 | 50 | 0.0108715 | 0.0110847 | 970 | 50 | 0.0485
Gipsplaat | 00 begane grond | Gipsplaat | 2.25956 | 0.229746 | 0.229746 | 12.5 | 0.00282445 | 0.00287183 | 970 | 12.5 | 0.012125
Gipsplaat | 00 begane grond | Gipsplaat | 2.29746 | 0.229746 | 0.229746 | 12.5 | 0.00287183 | 0.00287183 | 970 | 12.5 | 0.012125
8 x Gipsplaat | 00 begane grond | Gipsplaat | 9.00195 | 0.900195 | 2.03231 | 12.5 | 0.0112524 | 0.0254039 | 1417.3 | 12.5 | 0.0177163
2 x Isolatie - Steenwol LSW | 00 begane grond | Isolatie - Steenwol LSW | 2.47554 | 0.900195 | 2.03231 | 50 | 0.0450097 | 0.101616 | 1417.3 | 50 | 0.0708652
Gipsplaat | 00 begane grond | Gipsplaat | 12.1084 | 1.21588 | 1.21588 | 12.5 | 0.0151355 | 0.0151985 | 1195.56 | 12.5 | 0.0149446
Gipsplaat | 00 begane grond | Gipsplaat | 12.0078 | 1.20581 | 1.21588 | 12.5 | 0.0150097 | 0.0151985 | 1195.56 | 12.5 | 0.0149446
Isolatie - Steenwol LSW | 00 begane grond | Isolatie - Steenwol LSW | 3.23292 | 1.19574 | 1.21588 | 50 | 0.0587804 | 0.0607939 | 1195.56 | 50 | 0.0597782
ALG - ISOLATIE | 00 begane grond | ALG - ISOLATIE | 6.77241 | 2.55391 | 2.55391 | 60 | 0.150498 | 0.150498 | 493.876 | 60 | 0.0296325
42 Balvaste vlakke beplating | 00 begane grond | 42 Balvaste vlakke beplating | 15.3057 | 2.55094 | 2.55094 | 10 | 0.0255094 | 0.0255094 | 493.876 | 10 | 0.00493876
4 x Gipsplaat | 00 begane grond | Gipsplaat | 168.451 | 16.8451 | 20.6915 | 12.5 | 0.210564 | 0.258644 | 3740 | 12.5 | 0.04675
Isolatie - Steenwol LSW | 00 begane grond | Isolatie - Steenwol LSW | 69.4862 | 16.8451 | 20.6915 | 75 | 1.26339 | 1.55186 | 3740 | 75 | 0.2805
Gipsplaat | 00 begane grond | Gipsplaat | 101.917 | 10.1917 | 10.1917 | 12.5 | 0.127396 | 0.127396 | 3740 | 12.5 | 0.04675
Gipsplaat | 00 begane grond | Gipsplaat | 102.852 | 10.2852 | 10.2852 | 12.5 | 0.128565 | 0.128565 | 3740 | 12.5 | 0.04675
Isolatie - Steenwol LSW | 00 begane grond | Isolatie - Steenwol LSW | 42.8121 | 10.3787 | 10.3787 | 75 | 0.778402 | 0.778402 | 3740 | 75 | 0.2805
Gipsplaat | 00 begane grond | Gipsplaat | 109.397 | 10.9397 | 10.9397 | 12.5 | 0.136746 | 0.136746 | 3740 | 12.5 | 0.04675
Gipsplaat | 00 begane grond | Gipsplaat | 110.332 | 11.0332 | 11.0332 | 12.5 | 0.137915 | 0.137915 | 3740 | 12.5 | 0.04675
4 x Gipsplaat | 00 begane grond | Gipsplaat | 68.006 | 6.8006 | 6.8006 | 12.5 | 0.0850075 | 0.0850075 | 3740 | 12.5 | 0.04675
Isolatie - Steenwol LSW | 00 begane grond | Isolatie - Steenwol LSW | 18.7017 | 6.8006 | 6.8006 | 50 | 0.34003 | 0.34003 | 3740 | 50 | 0.187
Gipsplaat | 00 begane grond | Gipsplaat | 66.8642 | 6.68642 | 13.2112 | 12.5 | 0.0835802 | 0.16514 | 3740 | 12.5 | 0.04675
Gipsplaat | 00 begane grond | Gipsplaat | 67.3211 | 6.73211 | 13.2579 | 12.5 | 0.0841514 | 0.165724 | 3740 | 12.5 | 0.04675
Isolatie - Steenwol LSW | 00 begane grond | Isolatie - Steenwol LSW | 27.9628 | 6.77886 | 13.3047 | 75 | 0.508414 | 0.997851 | 3740 | 75 | 0.2805
Gipsplaat | 00 begane grond | Gipsplaat | 70.5936 | 7.05936 | 13.5852 | 12.5 | 0.088242 | 0.169815 | 3740 | 12.5 | 0.04675
Gipsplaat | 00 begane grond | Gipsplaat | 71.0611 | 7.10611 | 13.6319 | 12.5 | 0.0888264 | 0.170399 | 3740 | 12.5 | 0.04675
4 x Gipsplaat | 00 begane grond | Gipsplaat | 46.4993 | 4.64993 | 4.64993 | 12.5 | 0.0581241 | 0.0581241 | 3740 | 12.5 | 0.04675
Isolatie - Steenwol LSW | 00 begane grond | Isolatie - Steenwol LSW | 12.7873 | 4.64993 | 4.64993 | 50 | 0.232497 | 0.232497 | 3740 | 50 | 0.187
3 x Gipsplaat | 00 begane grond | Gipsplaat | 22.0245 | 2.20245 | 4.64993 | 12.5 | 0.0275307 | 0.0581241 | 3740 | 12.5 | 0.04675
Isolatie - Steenwol LSW | 00 begane grond | Isolatie - Steenwol LSW | 6.05675 | 2.20245 | 4.64993 | 50 | 0.110123 | 0.232497 | 3740 | 50 | 0.187
Gipsplaat | 00 begane grond | Gipsplaat | 30.4395 | 3.04395 | 5.49143 | 12.5 | 0.0380494 | 0.0686429 | 3740 | 12.5 | 0.04675
Isolatie - Steenwol LSW | 00 begane grond | Isolatie - Steenwol LSW | 29.3109 | 10.6585 | 10.6585 | 50 | 0.532926 | 0.532926 | 5190 | 50 | 0.2595
2 x Gipsplaat | 00 begane grond | Gipsplaat | 106.585 | 10.6585 | 10.6585 | 12.5 | 0.133231 | 0.133231 | 5190 | 12.5 | 0.064875
Isolatie - Steenwol LSW | 00 begane grond | Isolatie - Steenwol LSW | 33.1646 | 12.0599 | 12.0599 | 50 | 0.602994 | 0.602994 | 3740 | 50 | 0.187
Isolatie - Steenwol LSW | 00 begane grond | Isolatie - Steenwol LSW | 19.9541 | 7.25603 | 7.25603 | 50 | 0.362801 | 0.362801 | 3740 | 50 | 0.187
2 x Gipsplaat | 00 begane grond | Gipsplaat | 72.5603 | 7.25603 | 7.25603 | 12.5 | 0.0907004 | 0.0907004 | 3740 | 12.5 | 0.04675
Isolatie - Steenwol LSW | 00 begane grond | Isolatie - Steenwol LSW | 9.79314 | 3.56114 | 3.56114 | 50 | 0.178057 | 0.178057 | 3650 | 50 | 0.1825
2 x Gipsplaat | 00 begane grond | Gipsplaat | 35.6114 | 3.56114 | 3.56114 | 12.5 | 0.0445143 | 0.0445143 | 3650 | 12.5 | 0.045625
2 x Isolatie - Steenwol LSW | 00 begane grond | Isolatie - Steenwol LSW | 6.35079 | 2.30938 | 2.30938 | 50 | 0.115469 | 0.115469 | 2367 | 50 | 0.11835
4 x Gipsplaat | 00 begane grond | Gipsplaat | 23.0938 | 2.30938 | 2.30938 | 12.5 | 0.0288672 | 0.0288672 | 2367 | 12.5 | 0.0295875
Isolatie - Steenwol LSW | 00 begane grond | Isolatie - Steenwol LSW | 9.96877 | 3.62501 | 3.62501 | 50 | 0.18125 | 0.18125 | 3650 | 50 | 0.1825
2 x Gipsplaat | 00 begane grond | Gipsplaat | 36.2501 | 3.62501 | 3.62501 | 12.5 | 0.0453126 | 0.0453126 | 3650 | 12.5 | 0.045625
Isolatie - Steenwol LSW | 00 begane grond | Isolatie - Steenwol LSW | 6.46468 | 2.35079 | 2.35079 | 50 | 0.11754 | 0.11754 | 2367 | 50 | 0.11835
2 x Gipsplaat | 00 begane grond | Gipsplaat | 23.5079 | 2.35079 | 2.35079 | 12.5 | 0.0293849 | 0.0293849 | 2367 | 12.5 | 0.0295875
2 x Gipsplaat | 00 begane grond | Gipsplaat | 32.2351 | 3.22351 | 3.22351 | 12.5 | 0.0402938 | 0.0402938 | 3650 | 12.5 | 0.045625
Isolatie - Steenwol LSW | 00 begane grond | Isolatie - Steenwol LSW | 8.86464 | 3.22351 | 3.22351 | 50 | 0.161175 | 0.161175 | 3650 | 50 | 0.1825
2 x Gipsplaat | 00 begane grond | Gipsplaat | 31.3227 | 3.13227 | 3.13227 | 12.5 | 0.0391533 | 0.0391533 | 3650 | 12.5 | 0.045625
Isolatie - Steenwol LSW | 00 begane grond | Isolatie - Steenwol LSW | 8.61374 | 3.13227 | 3.13227 | 50 | 0.156613 | 0.156613 | 3650 | 50 | 0.1825
2 x Gipsplaat | 00 begane grond | Gipsplaat | 23.8134 | 2.38134 | 2.38134 | 12.5 | 0.0297668 | 0.0297668 | 2367 | 12.5 | 0.0295875
Isolatie - Steenwol LSW | 00 begane grond | Isolatie - Steenwol LSW | 6.54869 | 2.38134 | 2.38134 | 50 | 0.119067 | 0.119067 | 2367 | 50 | 0.11835
4 x Isolatie - PUR gespoten | 00 begane grond | Isolatie - PUR gespoten | 0.0319419 |  |  |  | 0.000912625 | 0.000912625 | 87.5 | 10 | 0.000875
4 x Steen - Kunststeen | 00 begane grond | Steen - Kunststeen | 38.2123 |  |  |  | 0.0238827 | 0.0238827 |  |  | 0.0228981
ALG - ISOLATIE | 00 begane grond | ALG - ISOLATIE | 11.912 | 1.8908 | 1.8908 | 140 | 0.264712 | 0.264712 | 4722.5 | 140 | 0.66115
Steen - Baksteen Accent | 00 begane grond | Steen - Baksteen Accent | 302.528 | 1.8908 | 1.8908 | 100 | 0.18908 | 0.18908 | 4722.5 | 100 | 0.47225
8 x Gipsplaat | 00 begane grond | Gipsplaat | 5.49617 | 0.549617 | 0.549617 | 12.5 | 0.00687021 | 0.00687021 | 2290 | 12.5 | 0.028625
2 x Isolatie - Steenwol LSW | 00 begane grond | Isolatie - Steenwol LSW | 1.51145 | 0.549617 | 0.549617 | 50 | 0.0274809 | 0.0274809 | 2290 | 50 | 0.1145
Metaal - Aluminium | 00 begane grond | Metaal - Aluminium | 67.1999 | 24 | 24 | 1 | 0.024 | 0.024 | 6000 | 1 | 0.006
Isolatie - Kunststof hard | 00 begane grond | Isolatie - Kunststof hard | 235.2 | 24 | 24 | 98 | 2.352 | 2.352 | 6000 | 98 | 0.588
Metaal - Aluminium | 00 begane grond | Metaal - Aluminium | 66.9764 | 24 | 24 | 1 | 0.0239202 | 0.0239202 | 6000 | 1 | 0.006
ALG - ISOLATIE | 00 begane grond | ALG - ISOLATIE | 1.00548 |  |  |  | 0.022344 | 0.022344 | 210 | 140 | 0.0294
Steen - Baksteen Accent Rollaag | 00 begane grond | Steen - Baksteen Accent Rollaag | 25.536 |  |  |  | 0.01596 | 0.01596 | 210 | 100 | 0.021
Metaal - Staal AFW | 00 begane grond | Metaal - Staal AFW | 2.52953 |  |  |  | 0.00031818 | 0.00031818 | 4 | 90 | 0.00036
Steen - Baksteen Accent Rollaag | 00 begane grond | Steen - Baksteen Accent Rollaag | 33.936 |  |  |  | 0.02121 | 0.02121 | 210 | 100 | 0.021
Metaal - Staal C | 00 begane grond | Metaal - Staal C | 6.9538 |  |  |  | 0.000874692 | 0.000874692 |  |  | 0.000920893
4 x Metaal - Staal C | 00 begane grond | Metaal - Staal C | 7.39431 |  |  |  | 0.000930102 | 0.000930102 |  |  | 0.000920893
4 x Steen - Baksteen Accent Rollaag | 00 begane grond | Steen - Baksteen Accent Rollaag | 32.6602 |  |  |  | 0.0204126 | 0.0204126 | 210 | 100 | 0.021
4 x Metaal - Staal AFW | 00 begane grond | Metaal - Staal AFW | 2.89062 |  |  |  | 0.0003636 | 0.0003636 | 4 | 90 | 0.00036
Steen - Baksteen Accent Rollaag | 00 begane grond | Steen - Baksteen Accent Rollaag | 96.934 |  |  |  | 0.0605837 | 0.0605837 | 210 | 100 | 0.021
ALG - ISOLATIE | 00 begane grond | ALG - ISOLATIE | 3.79963 |  |  |  | 0.0844362 | 0.0844362 | 210 | 140 | 0.0294
2 x Steen - Baksteen Accent Rollaag | 00 begane grond | Steen - Baksteen Accent Rollaag | 17.796 |  |  |  | 0.0111225 | 0.0111225 | 210 | 100 | 0.021
3 x ALG - ISOLATIE | 00 begane grond | ALG - ISOLATIE | 0.71442 |  |  |  | 0.015876 | 0.015876 | 210 | 140 | 0.0294
Steen - Baksteen Accent Rollaag | 00 begane grond | Steen - Baksteen Accent Rollaag | 17.7954 |  |  |  | 0.0111221 | 0.0111221 | 210 | 100 | 0.021
Metaal - Staal C | 00 begane grond | Metaal - Staal C | 0.668978 |  |  |  | 0.0000841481 | 0.0000841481 |  |  | 0.000920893
Steen - Baksteen Accent Rollaag | 00 begane grond | Steen - Baksteen Accent Rollaag | 33.8863 |  |  |  | 0.0211789 | 0.0211789 | 210 | 100 | 0.021
Metaal - Staal AFW | 00 begane grond | Metaal - Staal AFW | 2.79216 |  |  |  | 0.000351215 | 0.000351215 | 4 | 90 | 0.00036
Steen - Baksteen Accent Rollaag | 00 begane grond | Steen - Baksteen Accent Rollaag | 139.199 |  |  |  | 0.0869994 | 0.0869994 | 210 | 100 | 0.021
ALG - ISOLATIE | 00 begane grond | ALG - ISOLATIE | 5.30778 |  |  |  | 0.117951 | 0.117951 | 210 | 140 | 0.0294
Steen - Baksteen Accent Rollaag | 00 begane grond | Steen - Baksteen Accent Rollaag | 40.3124 |  |  |  | 0.0251953 | 0.0251953 | 210 | 100 | 0.021
2 x ALG - ISOLATIE | 00 begane grond | ALG - ISOLATIE | 1.5876 |  |  |  | 0.03528 | 0.03528 | 210 | 140 | 0.0294
ALG - ISOLATIE | 00 begane grond | ALG - ISOLATIE | 33.4925 | 5.31627 | 5.31627 | 140 | 0.744277 | 0.744277 | 652.5 | 140 | 0.09135
Steen - Baksteen Hoofd | 00 begane grond | Steen - Baksteen Hoofd | 850.603 | 5.31627 | 5.31627 | 100 | 0.531627 | 0.531627 | 652.5 | 100 | 0.06525
ALG - ISOLATIE | 00 begane grond | ALG - ISOLATIE | 8.01509 | 1.27224 | 7.05099 | 140 | 0.178113 | 0.987138 | 3272.5 | 140 | 0.45815
Steen - Baksteen Accent | 00 begane grond | Steen - Baksteen Accent | 203.558 | 1.27224 | 7.05099 | 100 | 0.127224 | 0.705099 | 3272.5 | 100 | 0.32725
ALG - ISOLATIE | 00 begane grond | ALG - ISOLATIE | 76.8834 | 12.2037 | 12.2037 | 140 | 1.70852 | 1.70852 | 652.5 | 140 | 0.09135
Steen - Baksteen Hoofd | 00 begane grond | Steen - Baksteen Hoofd | 1952.59 | 12.2037 | 12.2037 | 100 | 1.22037 | 1.22037 | 652.5 | 100 | 0.06525
Steen - Baksteen Accent | 00 begane grond | Steen - Baksteen Accent | 4968.94 | 31.0559 | 59.9784 | 100 | 3.10559 | 5.99784 | 3272.5 | 100 | 0.32725
ALG - ISOLATIE | 00 begane grond | ALG - ISOLATIE | 195.652 | 31.0559 | 59.9784 | 140 | 4.34782 | 8.39697 | 3272.5 | 140 | 0.45815
ALG - ISOLATIE | 00 begane grond | ALG - ISOLATIE | 86.8232 | 13.7815 | 13.7815 | 140 | 1.9294 | 1.9294 | 4135 | 140 | 0.5789
Steen - Baksteen Hoofd | 00 begane grond | Steen - Baksteen Hoofd | 2297.66 | 14.3604 | 14.3604 | 100 | 1.43604 | 1.43604 | 4135 | 100 | 0.4135
Steen - Baksteen Accent | 00 begane grond | Steen - Baksteen Accent | 399.851 | 2.6972 | 11.3653 | 100 | 0.249907 | 1.11672 | 4722.5 | 100 | 0.47225
ALG - ISOLATIE | 00 begane grond | ALG - ISOLATIE | 17.1871 | 3.0055 | 11.6736 | 140 | 0.381936 | 1.59547 | 4722.5 | 140 | 0.66115
ALG - ISOLATIE | 00 begane grond | ALG - ISOLATIE | 28.3602 | 4.779 | 4.779 | 140 | 0.630226 | 0.630226 | 4722.5 | 140 | 0.66115
Steen - Baksteen Accent | 00 begane grond | Steen - Baksteen Accent | 644.156 | 4.22411 | 4.22411 | 100 | 0.402598 | 0.402598 | 4722.5 | 100 | 0.47225
ALG - ISOLATIE | 00 begane grond | ALG - ISOLATIE | 63.4381 | 10.0695 | 15.877 | 140 | 1.40974 | 2.22279 | 4722.5 | 140 | 0.66115
Steen - Baksteen Accent | 00 begane grond | Steen - Baksteen Accent | 1608.34 | 10.0521 | 15.8596 | 100 | 1.00521 | 1.58596 | 4722.5 | 100 | 0.47225
Metaal - Aluminium | 00 begane grond | Metaal - Aluminium | 16.7459 | 6 | 6 | 1 | 0.00598067 | 0.00598067 | 6000 | 1 | 0.006
Steen - Baksteen Accent Rollaag | 00 begane grond | Steen - Baksteen Accent Rollaag | 40.32 |  |  |  | 0.0252 | 0.0252 | 210 | 100 | 0.021
ALG - ISOLATIE | 00 begane grond | ALG - ISOLATIE | 1.30977 |  |  |  | 0.029106 | 0.029106 | 210 | 140 | 0.0294
Steen - Baksteen Accent Rollaag | 00 begane grond | Steen - Baksteen Accent Rollaag | 33.264 |  |  |  | 0.02079 | 0.02079 | 210 | 100 | 0.021
Steen - Baksteen Accent Rollaag | 00 begane grond | Steen - Baksteen Accent Rollaag | 222.827 |  |  |  | 0.139267 | 0.139267 | 210 | 100 | 0.021
ALG - ISOLATIE | 00 begane grond | ALG - ISOLATIE | 8.77416 |  |  |  | 0.194981 | 0.194981 | 210 | 140 | 0.0294
Metaal - Staal C | 00 begane grond | Metaal - Staal C | 1.89587 |  |  |  | 0.000238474 | 0.000238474 |  |  | 0.000920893
Steen - Baksteen Accent Rollaag | 00 begane grond | Steen - Baksteen Accent Rollaag | 67.4059 |  |  |  | 0.0421287 | 0.0421287 | 210 | 100 | 0.021
Metaal - Staal AFW | 00 begane grond | Metaal - Staal AFW | 5.62999 |  |  |  | 0.000708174 | 0.000708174 | 4 | 90 | 0.00036
Steen - Baksteen Accent Rollaag | 00 begane grond | Steen - Baksteen Accent Rollaag | 32.8945 |  |  |  | 0.0205591 | 0.0205591 | 210 | 100 | 0.021
ALG - ISOLATIE | 00 begane grond | ALG - ISOLATIE | 1.73313 |  |  |  | 0.038514 | 0.038514 | 210 | 140 | 0.0294
Metaal - Aluminium | 00 begane grond | Metaal - Aluminium | 24.6673 | 8.80974 | 11.9917 | 1 | 0.00880974 | 0.0119914 | 6000 | 1 | 0.006
Isolatie - Kunststof hard | 00 begane grond | Isolatie - Kunststof hard | 86.338 | 8.81 | 12 | 98 | 0.86338 | 1.176 | 6000 | 98 | 0.588
Metaal - Aluminium | 00 begane grond | Metaal - Aluminium | 24.537 | 8.81 | 12 | 1 | 0.00876323 | 0.0119601 | 6000 | 1 | 0.006
Metaal - Aluminium | 00 begane grond | Metaal - Aluminium | 7.85379 | 2.80493 | 5.9918 | 1 | 0.00280493 | 0.00599155 | 6000 | 1 | 0.006
Isolatie - Kunststof hard | 00 begane grond | Isolatie - Kunststof hard | 27.4894 | 2.80505 | 6 | 98 | 0.274894 | 0.588 | 6000 | 98 | 0.588
Metaal - Aluminium | 00 begane grond | Metaal - Aluminium | 7.78972 | 2.80505 | 6 | 1 | 0.00278204 | 0.00598004 | 6000 | 1 | 0.006
4 x Metaal - Aluminium | 00 begane grond | Metaal - Aluminium | 1.26333 | 0.451189 | 0.451189 | 1 | 0.000451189 | 0.000451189 | 2050.86 | 1 | 0.00205086
2 x Isolatie - Kunststof hard | 00 begane grond | Isolatie - Kunststof hard | 1.57916 | 0.451189 | 0.451189 | 35 | 0.0157916 | 0.0157916 | 2050.86 | 35 | 0.07178
Metaal - Aluminium | 00 begane grond | Metaal - Aluminium | 11.312 | 4.04 | 4.04 | 1 | 0.00404 | 0.00404 | 2020 | 1 | 0.00202
Isolatie - Kunststof hard | 00 begane grond | Isolatie - Kunststof hard | 39.5661 | 4.04 | 4.04 | 98 | 0.395661 | 0.395661 | 2020 | 98 | 0.19796
Metaal - Aluminium | 00 begane grond | Metaal - Aluminium | 11.1095 | 4.0076 | 4.0076 | 1 | 0.00396768 | 0.00396768 | 2020 | 1 | 0.00202
3 x Metaal - Aluminium | 00 begane grond | Metaal - Aluminium | 11.144 | 3.98 | 3.98 | 1 | 0.00398 | 0.00398 | 3980 | 1 | 0.00398
Isolatie - Kunststof hard | 00 begane grond | Isolatie - Kunststof hard | 39.0009 | 3.98 | 3.98 | 98 | 0.390009 | 0.390009 | 3980 | 98 | 0.39004
Metaal - Aluminium | 00 begane grond | Metaal - Aluminium | 11.1237 | 3.97305 | 3.97305 | 1 | 0.00397274 | 0.00397274 | 3980 | 1 | 0.00398
Isolatie - Kunststof hard | 00 begane grond | Isolatie - Kunststof hard | 39.004 | 3.98 | 3.98 | 98 | 0.39004 | 0.39004 | 3980 | 98 | 0.39004
2 x Metaal - Aluminium | 00 begane grond | Metaal - Aluminium | 7.95682 | 2.84172 | 2.84172 | 1 | 0.00284172 | 0.00284172 | 3980 | 1 | 0.00398
Isolatie - Kunststof hard | 00 begane grond | Isolatie - Kunststof hard | 27.8489 | 2.84172 | 2.84172 | 98 | 0.278489 | 0.278489 | 3980 | 98 | 0.39004
Metaal - Aluminium | 00 begane grond | Metaal - Aluminium | 16.2101 | 5.78932 | 5.78932 | 1 | 0.00578932 | 0.00578932 | 6000 | 1 | 0.006
Isolatie - Kunststof hard | 00 begane grond | Isolatie - Kunststof hard | 56.7352 | 5.78932 | 5.78932 | 98 | 0.567352 | 0.567352 | 6000 | 98 | 0.588
Metaal - Aluminium | 00 begane grond | Metaal - Aluminium | 16.1561 | 5.78827 | 5.78827 | 1 | 0.00577004 | 0.00577004 | 6000 | 1 | 0.006
Metaal - Aluminium | 00 begane grond | Metaal - Aluminium | 50.4 | 18 | 18 | 1 | 0.018 | 0.018 | 6000 | 1 | 0.006
Isolatie - Kunststof hard | 00 begane grond | Isolatie - Kunststof hard | 176.4 | 18 | 18 | 98 | 1.764 | 1.764 | 6000 | 98 | 0.588
Metaal - Aluminium | 00 begane grond | Metaal - Aluminium | 50.2413 | 18 | 18 | 1 | 0.0179433 | 0.0179433 | 6000 | 1 | 0.006
Isolatie - Kunststof hard | 00 begane grond | Isolatie - Kunststof hard | 117.589 | 12 | 12 | 98 | 1.17589 | 1.17589 | 6000 | 98 | 0.588
Metaal - Aluminium | 00 begane grond | Metaal - Aluminium | 33.4617 | 11.9884 | 11.9884 | 1 | 0.0119506 | 0.0119506 | 6000 | 1 | 0.006
Isolatie - Steenwol LSW | 00 begane grond | Isolatie - Steenwol LSW | 5.61261 | 2.0806 | 2.0806 | 50 | 0.102047 | 0.10403 | 970 | 50 | 0.0485
Gipsplaat | 00 begane grond | Gipsplaat | 21.2093 | 2.15618 | 2.15618 | 12.5 | 0.0265116 | 0.0269522 | 970 | 12.5 | 0.012125
Gipsplaat | 00 begane grond | Gipsplaat | 21.5618 | 2.15618 | 2.15618 | 12.5 | 0.0269522 | 0.0269522 | 970 | 12.5 | 0.012125
2 x Gipsplaat | 00 begane grond | Gipsplaat | 1.65365 | 0.165365 | 0.165365 | 12.5 | 0.00206706 | 0.00206706 | 624 | 12.5 | 0.0078
Isolatie - Steenwol LSW | 00 begane grond | Isolatie - Steenwol LSW | 0.454753 | 0.165365 | 0.165365 | 50 | 0.00826823 | 0.00826823 | 624 | 50 | 0.0312
Isolatie - PUR gespoten | 00 begane grond | Isolatie - PUR gespoten | 0.0552825 |  |  |  | 0.0015795 | 0.0015795 | 75 | 10 | 0.00075
Steen - Kunststeen | 00 begane grond | Steen - Kunststeen | 65.2556 |  |  |  | 0.0407848 | 0.0407848 |  |  | 0.019366
4 x Isolatie - PUR gespoten | 00 begane grond | Isolatie - PUR gespoten | 0.0265125 |  |  |  | 0.0007575 | 0.0007575 | 75 | 10 | 0.00075
4 x Hout AFW | 00 begane grond | Hout AFW | 1.58317 |  |  |  | 0.0028785 | 0.0028785 | 75 | 38 | 0.00285
4 x Steen - Kunststeen | 00 begane grond | Steen - Kunststeen | 16.574 |  |  |  | 0.0103587 | 0.0103587 |  |  | 0.0102562
4 x Steen - Kunststeen | 00 begane grond | Steen - Kunststeen | 16.5798 |  |  |  | 0.0103624 | 0.0103624 |  |  | 0.0102562
4 x Hout AFW | 00 begane grond | Hout AFW | 1.58373 |  |  |  | 0.00287951 | 0.00287951 | 75 | 38 | 0.00285
4 x Isolatie - PUR gespoten | 00 begane grond | Isolatie - PUR gespoten | 0.0265218 |  |  |  | 0.000757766 | 0.000757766 | 75 | 10 | 0.00075
5 x Steen - Kunststeen | 00 begane grond | Steen - Kunststeen | 32.9839 |  |  |  | 0.0206149 | 0.0206149 |  |  | 0.0102562
5 x Hout AFW | 00 begane grond | Hout AFW | 3.15067 |  |  |  | 0.0057285 | 0.0057285 | 75 | 38 | 0.00285
7 x Isolatie - PUR gespoten | 00 begane grond | Isolatie - PUR gespoten | 0.0527625 |  |  |  | 0.0015075 | 0.0015075 | 75 | 10 | 0.00075
2 x Steen - Kunststeen | 00 begane grond | Steen - Kunststeen | 61.7757 |  |  |  | 0.0386098 | 0.0386098 |  |  | 0.0192089
Steen - Kunststeen | 00 begane grond | Steen - Kunststeen | 54.9331 |  |  |  | 0.0343332 | 0.0343332 |  |  | 0.019366
Isolatie - PUR gespoten | 00 begane grond | Isolatie - PUR gespoten | 0.0488736 |  |  |  | 0.00139639 | 0.00139639 | 75 | 10 | 0.00075
2 x Steen - Kunststeen | 00 begane grond | Steen - Kunststeen | 32.0558 |  |  |  | 0.0200349 | 0.0200349 |  |  | 0.0192089
2 x Isolatie - PUR gespoten | 00 begane grond | Isolatie - PUR gespoten | 0.0273788 |  |  |  | 0.00078225 | 0.00078225 | 75 | 10 | 0.00075
Steen - Kunststeen | 00 begane grond | Steen - Kunststeen | 32.6397 |  |  |  | 0.0203998 | 0.0203998 |  |  | 0.0192089
Isolatie - PUR gespoten | 00 begane grond | Isolatie - PUR gespoten | 0.0278775 |  |  |  | 0.0007965 | 0.0007965 | 75 | 10 | 0.00075
2 x Steen - Kunststeen | 00 begane grond | Steen - Kunststeen | 15.8684 |  |  |  | 0.00991772 | 0.00991772 |  |  | 0.0102562
2 x Hout AFW | 00 begane grond | Hout AFW | 1.51577 |  |  |  | 0.00275595 | 0.00275595 | 75 | 38 | 0.00285
2 x Isolatie - PUR gespoten | 00 begane grond | Isolatie - PUR gespoten | 0.0253837 |  |  |  | 0.00072525 | 0.00072525 | 75 | 10 | 0.00075
Metaal - Aluminium | 00 begane grond | Metaal - Aluminium | 14.9128 |  |  |  | 0.005326 | 0.005326 |  |  | 0.00035567
Metaal - Aluminium | 00 begane grond | Metaal - Aluminium | 3.50216 |  |  |  | 0.00125077 | 0.00125077 |  |  | 0.000082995
Metaal - Aluminium | 00 begane grond | Metaal - Aluminium | 1.49932 |  |  |  | 0.000535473 | 0.000535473 |  |  | 0.00035567
Metaal - Aluminium | 00 begane grond | Metaal - Aluminium | 0.372145 |  |  |  | 0.000132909 | 0.000132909 |  |  | 0.000082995
Metaal - Aluminium | 00 begane grond | Metaal - Aluminium | 24.3735 |  |  |  | 0.00870483 | 0.00870483 |  |  | 0.00035567
Metaal - Aluminium | 00 begane grond | Metaal - Aluminium | 5.70982 |  |  |  | 0.00203922 | 0.00203922 |  |  | 0.000082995
Metaal - Aluminium | 00 begane grond | Metaal - Aluminium | 11.4855 |  |  |  | 0.00410197 | 0.00410197 |  |  | 0.00035567
Metaal - Aluminium | 00 begane grond | Metaal - Aluminium | 2.70252 |  |  |  | 0.000965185 | 0.000965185 |  |  | 0.000082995
Isolatie - Steenwol LSW | 00 begane grond | Isolatie - Steenwol LSW | 10.7944 | 3.92525 | 3.92525 | 50 | 0.196262 | 0.196262 | 3740 | 50 | 0.187
2 x Gipsplaat | 00 begane grond | Gipsplaat | 39.2525 | 3.92525 | 3.92525 | 12.5 | 0.0490656 | 0.0490656 | 3740 | 12.5 | 0.04675
Isolatie - Steenwol LSW | 00 begane grond | Isolatie - Steenwol LSW | 11.1489 | 4.05416 | 4.05416 | 50 | 0.202708 | 0.202708 | 3740 | 50 | 0.187
2 x Gipsplaat | 00 begane grond | Gipsplaat | 40.5416 | 4.05416 | 4.05416 | 12.5 | 0.050677 | 0.050677 | 3740 | 12.5 | 0.04675
Metaal - Aluminium | 00 begane grond | Metaal - Aluminium | 48.2803 | 17.243 | 19.8131 | 1 | 0.017243 | 0.0198131 | 5980 | 1 | 0.00598
Isolatie - Kunststof hard | 00 begane grond | Isolatie - Kunststof hard | 168.981 | 17.243 | 19.8176 | 98 | 1.68981 | 1.94213 | 5980 | 98 | 0.58604
Metaal - Aluminium | 00 begane grond | Metaal - Aluminium | 48.1587 | 17.2148 | 19.8176 | 1 | 0.0171996 | 0.019787 | 5980 | 1 | 0.00598
Metaal - Aluminium | 00 begane grond | Metaal - Aluminium | 5.52743 | 1.97408 | 1.97408 | 1 | 0.00197408 | 0.00197408 | 6000 | 1 | 0.006
Isolatie - Kunststof hard | 00 begane grond | Isolatie - Kunststof hard | 19.346 | 1.97408 | 1.97408 | 98 | 0.19346 | 0.19346 | 6000 | 98 | 0.588
Metaal - Aluminium | 00 begane grond | Metaal - Aluminium | 5.51003 | 1.97408 | 1.97408 | 1 | 0.00196787 | 0.00196787 | 6000 | 1 | 0.006
Isolatie - Steenwol LSW | 00 begane grond | Isolatie - Steenwol LSW | 2.4684 | 0.8976 | 0.8976 | 50 | 0.04488 | 0.04488 | 3740 | 50 | 0.187
Gipsplaat | 00 begane grond | Gipsplaat | 8.976 | 0.8976 | 0.8976 | 12.5 | 0.01122 | 0.01122 | 3740 | 12.5 | 0.04675
Gipsplaat | 00 begane grond | Gipsplaat | 8.5085 | 0.85085 | 0.85085 | 12.5 | 0.0106356 | 0.0106356 | 3740 | 12.5 | 0.04675
Steen - Baksteen Accent Rollaag | 00 begane grond | Steen - Baksteen Accent Rollaag | 98.175 | 0.613594 | 0.613594 | 100 | 0.0613594 | 0.0613594 | 3272.5 | 100 | 0.32725
ALG - ISOLATIE | 00 begane grond | ALG - ISOLATIE | 3.86564 | 0.613594 | 0.613594 | 140 | 0.0859031 | 0.0859031 | 3272.5 | 140 | 0.45815
Steen - Baksteen Accent Rollaag | 00 begane grond | Steen - Baksteen Accent Rollaag | 104.269 | 0.652969 | 0.652969 | 100 | 0.0651683 | 0.0651683 | 3482.5 | 100 | 0.34825
3 x ALG - ISOLATIE | 00 begane grond | ALG - ISOLATIE | 4.1137 | 0.652969 | 0.652969 | 140 | 0.0914156 | 0.0914156 | 3482.5 | 140 | 0.48755
Steen - Baksteen Accent Rollaag | 00 begane grond | Steen - Baksteen Accent Rollaag | 104.272 | 0.652969 | 0.652969 | 100 | 0.0651702 | 0.0651702 | 3482.5 | 100 | 0.34825
Steen - Baksteen Accent Rollaag | 00 begane grond | Steen - Baksteen Accent Rollaag | 104.279 | 0.652969 | 0.652969 | 100 | 0.0651747 | 0.0651747 | 3482.5 | 100 | 0.34825
Gipsplaat | 00 begane grond | Gipsplaat | 75.2067 | 7.52067 | 7.52067 | 12.5 | 0.0940084 | 0.0940084 | 3740 | 12.5 | 0.04675
Gipsplaat | 00 begane grond | Gipsplaat | 74.7392 | 7.47392 | 7.47392 | 12.5 | 0.093424 | 0.093424 | 3740 | 12.5 | 0.04675
Isolatie - Steenwol LSW | 00 begane grond | Isolatie - Steenwol LSW | 20.039 | 7.28692 | 7.28692 | 50 | 0.364346 | 0.364346 | 3740 | 50 | 0.187
Gipsplaat | 00 begane grond | Gipsplaat | 72.4017 | 7.24017 | 7.24017 | 12.5 | 0.0905021 | 0.0905021 | 3740 | 12.5 | 0.04675
Gipsplaat | 00 begane grond | Gipsplaat | 71.9342 | 7.19342 | 7.19342 | 12.5 | 0.0899178 | 0.0899178 | 3740 | 12.5 | 0.04675
Metaal - Aluminium | 00 begane grond | Metaal - Aluminium | 84.1021 | 30.7739 | 30.7739 | 1 | 0.0300365 | 0.0300365 | 6000 | 1 | 0.006
Isolatie - Kunststof hard | 00 begane grond | Isolatie - Kunststof hard | 305.466 | 31.17 | 31.17 | 98 | 3.05466 | 3.05466 | 6000 | 98 | 0.588
Metaal - Aluminium | 00 begane grond | Metaal - Aluminium | 87.2558 | 31.17 | 31.17 | 1 | 0.0311628 | 0.0311628 | 6000 | 1 | 0.006
Isolatie - Steenwol LSW | 00 begane grond | Isolatie - Steenwol LSW | 8.95345 | 3.2558 | 3.2558 | 50 | 0.16279 | 0.16279 | 3650 | 50 | 0.1825
Gipsplaat | 00 begane grond | Gipsplaat | 33.0143 | 3.30143 | 3.30143 | 12.5 | 0.0412678 | 0.0412678 | 3650 | 12.5 | 0.045625
Gipsplaat | 00 begane grond | Gipsplaat | 33.4705 | 3.34705 | 3.34705 | 12.5 | 0.0418381 | 0.0418381 | 3650 | 12.5 | 0.045625
Isolatie - Steenwol LSW | 00 begane grond | Isolatie - Steenwol LSW | 0.752813 | 0.27375 | 0.27375 | 50 | 0.0136875 | 0.0136875 | 3650 | 50 | 0.1825
Gipsplaat | 00 begane grond | Gipsplaat | 4.5625 | 0.45625 | 0.45625 | 12.5 | 0.00570312 | 0.00570312 | 3650 | 12.5 | 0.045625
Gipsplaat | 00 begane grond | Gipsplaat | 5.01875 | 0.501875 | 0.501875 | 12.5 | 0.00627344 | 0.00627344 | 3650 | 12.5 | 0.045625
Isolatie - Steenwol LSW | 00 begane grond | Isolatie - Steenwol LSW | 14.4504 | 5.2547 | 5.2547 | 50 | 0.262735 | 0.262735 | 3740 | 50 | 0.187
Isolatie - Steenwol LSW | 00 begane grond | Isolatie - Steenwol LSW | 9.17422 | 3.33608 | 3.33608 | 50 | 0.166804 | 0.166804 | 3740 | 50 | 0.187
Gipsplaat | 00 begane grond | Gipsplaat | 33.8283 | 3.38283 | 3.38283 | 12.5 | 0.0422854 | 0.0422854 | 3740 | 12.5 | 0.04675
Gipsplaat | 00 begane grond | Gipsplaat | 34.2958 | 3.42958 | 3.42958 | 12.5 | 0.0428698 | 0.0428698 | 3740 | 12.5 | 0.04675
Isolatie - Steenwol LSW | 00 begane grond | Isolatie - Steenwol LSW | 0.51425 | 0.187 | 0.187 | 50 | 0.00935 | 0.00935 | 3740 | 50 | 0.187
Gipsplaat | 00 begane grond | Gipsplaat | 3.74 | 0.374 | 0.374 | 12.5 | 0.004675 | 0.004675 | 3740 | 12.5 | 0.04675
Gipsplaat | 00 begane grond | Gipsplaat | 4.2075 | 0.42075 | 0.42075 | 12.5 | 0.00525938 | 0.00525938 | 3740 | 12.5 | 0.04675
Gipsplaat | 00 begane grond | Gipsplaat | 29.92 | 2.992 | 2.992 | 12.5 | 0.0374 | 0.0374 | 3740 | 12.5 | 0.04675
Gipsplaat | 00 begane grond | Gipsplaat | 28.985 | 2.8985 | 2.8985 | 12.5 | 0.0362312 | 0.0362312 | 3740 | 12.5 | 0.04675
Isolatie - Steenwol LSW | 00 begane grond | Isolatie - Steenwol LSW | 7.71375 | 2.805 | 2.805 | 50 | 0.14025 | 0.14025 | 3740 | 50 | 0.187
Gipsplaat | 00 begane grond | Gipsplaat | 14.3161 | 1.43161 | 1.43161 | 12.5 | 0.0178951 | 0.0178951 | 3740 | 12.5 | 0.04675
Gipsplaat | 00 begane grond | Gipsplaat | 13.8486 | 1.38486 | 1.38486 | 12.5 | 0.0173107 | 0.0173107 | 3740 | 12.5 | 0.04675
Isolatie - Steenwol LSW | 00 begane grond | Isolatie - Steenwol LSW | 3.29411 | 1.19786 | 1.19786 | 50 | 0.0598929 | 0.0598929 | 3740 | 50 | 0.187
Gipsplaat | 00 begane grond | Gipsplaat | 1.92234 | 0.192234 | 0.192234 | 12.5 | 0.00240293 | 0.00240293 | 3650 | 12.5 | 0.045625
Gipsplaat | 00 begane grond | Gipsplaat | 2.37859 | 0.237859 | 0.237859 | 12.5 | 0.00297324 | 0.00297324 | 3650 | 12.5 | 0.045625
Isolatie - Steenwol LSW | 00 begane grond | Isolatie - Steenwol LSW | 1.15599 | 0.420359 | 0.420359 | 50 | 0.021018 | 0.021018 | 3650 | 50 | 0.1825
Gipsplaat | 00 begane grond | Gipsplaat | 4.65984 | 0.465984 | 0.465984 | 12.5 | 0.00582481 | 0.00582481 | 3650 | 12.5 | 0.045625
Gipsplaat | 00 begane grond | Gipsplaat | 5.11609 | 0.511609 | 0.511609 | 12.5 | 0.00639512 | 0.00639512 | 3650 | 12.5 | 0.045625
4 x Gipsplaat | 00 begane grond | Gipsplaat | 5.82905 | 0.582905 | 0.582905 | 12.5 | 0.00728631 | 0.00728631 | 3650 | 12.5 | 0.045625
Isolatie - Steenwol LSW | 00 begane grond | Isolatie - Steenwol LSW | 1.22658 | 0.44603 | 0.44603 | 50 | 0.0223015 | 0.0223015 | 3650 | 50 | 0.1825
4 x Gipsplaat | 00 begane grond | Gipsplaat | 16.83 | 1.683 | 1.683 | 12.5 | 0.0210375 | 0.0210375 | 3740 | 12.5 | 0.04675
Isolatie - Steenwol LSW | 00 begane grond | Isolatie - Steenwol LSW | 4.62825 | 1.683 | 1.683 | 50 | 0.08415 | 0.08415 | 3740 | 50 | 0.187
2 x Gipsplaat | 00 begane grond | Gipsplaat | 7.8475 | 0.78475 | 0.78475 | 12.5 | 0.00980938 | 0.00980938 | 3650 | 12.5 | 0.045625
Isolatie - Steenwol LSW | 00 begane grond | Isolatie - Steenwol LSW | 2.15806 | 0.78475 | 0.78475 | 50 | 0.0392375 | 0.0392375 | 3650 | 50 | 0.1825
4 x Gipsplaat | 00 begane grond | Gipsplaat | 16.8187 | 1.68187 | 1.68187 | 12.5 | 0.0210234 | 0.0210234 | 3740 | 12.5 | 0.04675
Isolatie - Steenwol LSW | 00 begane grond | Isolatie - Steenwol LSW | 4.62516 | 1.68187 | 1.68187 | 50 | 0.0840937 | 0.0840937 | 3740 | 50 | 0.187
Isolatie - Steenwol LSW | 00 begane grond | Isolatie - Steenwol LSW | 2.15504 | 0.783652 | 0.783652 | 50 | 0.0391826 | 0.0391826 | 3650 | 50 | 0.1825
2 x Gipsplaat | 00 begane grond | Gipsplaat | 7.83652 | 0.783652 | 0.783652 | 12.5 | 0.00979565 | 0.00979565 | 3650 | 12.5 | 0.045625
2 x Hout AFW | 00 begane grond | Hout AFW | 3.14079 |  |  |  | 0.00571053 | 0.00571053
2 x Metaal - RVS | 00 begane grond | Metaal - RVS | 0.527457 |  |  |  | 0.0000667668 | 0.0000667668
2 x Hout AFW | 00 begane grond | Hout AFW | 0.237788 |  |  |  | 0.000432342 | 0.000432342
Isolatie - Steenwol LSW | 00 begane grond | Isolatie - Steenwol LSW | 32.5661 | 11.8422 | 11.8422 | 50 | 0.59211 | 0.59211 | 1420.02 | 50 | 0.0710011
2 x Gipsplaat | 00 begane grond | Gipsplaat | 120.718 | 12.0718 | 12.0718 | 12.5 | 0.150898 | 0.150898 | 1420.02 | 12.5 | 0.0177503
Metaal - Aluminium | 00 begane grond | Metaal - Aluminium | 7.92635 |  |  |  | 0.00283084 | 0.00283084 |  |  | 0.000758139
Metaal - Aluminium | 00 begane grond | Metaal - Aluminium | 8.44497 |  |  |  | 0.00301606 | 0.00301606 |  |  | 0.000758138
Metaal - Aluminium | 00 begane grond | Metaal - Aluminium | 8.61852 |  |  |  | 0.00307804 | 0.00307804 |  |  | 0.000758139
Metaal - Aluminium | 00 begane grond | Metaal - Aluminium | 6.32607 |  |  |  | 0.00225931 | 0.00225931 |  |  | 0.000758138
Metaal - Aluminium | 00 begane grond | Metaal - Aluminium | 5.80358 |  |  |  | 0.00207271 | 0.00207271 |  |  | 0.000758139
Metaal - Aluminium | 00 begane grond | Metaal - Aluminium | 8.57724 |  |  |  | 0.0030633 | 0.0030633 |  |  | 0.000758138
Metaal - Aluminium | 00 begane grond | Metaal - Aluminium | 1.67383 |  |  |  | 0.000597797 | 0.000597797 |  |  | 0.000758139
Metaal - Aluminium | 00 begane grond | Metaal - Aluminium | 1.51911 |  |  |  | 0.000542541 | 0.000542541 |  |  | 0.000758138
Metaal - Aluminium | 00 begane grond | Metaal - Aluminium | 1.48595 |  |  |  | 0.000530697 | 0.000530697 |  |  | 0.000758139
Metaal - Aluminium | 00 begane grond | Metaal - Aluminium | 1.48595 |  |  |  | 0.000530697 | 0.000530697 |  |  | 0.000758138
Metaal - Aluminium | 00 begane grond | Metaal - Aluminium | 6.94214 |  |  |  | 0.00247934 | 0.00247934 |  |  | 0.000758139
Metaal - Aluminium | 00 begane grond | Metaal - Aluminium | 6.66987 |  |  |  | 0.00238209 | 0.00238209 |  |  | 0.000758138
Metaal - Aluminium | 00 begane grond | Metaal - Aluminium | 3.30703 |  |  |  | 0.00118108 | 0.00118108 |  |  | 0.000758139
Metaal - Aluminium | 00 begane grond | Metaal - Aluminium | 3.00046 |  |  |  | 0.00107159 | 0.00107159 |  |  | 0.000758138
19 x Metaal - Aluminium | 00 begane grond | Metaal - Aluminium | 3.58751 |  |  |  | 0.00128125 | 0.00128125 |  |  | 0.000758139
Metaal - Aluminium | 00 begane grond | Metaal - Aluminium | 3.57027 |  |  |  | 0.0012751 | 0.0012751 |  |  | 0.000758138
19 x Metaal - Aluminium | 00 begane grond | Metaal - Aluminium | 3.58751 |  |  |  | 0.00128125 | 0.00128125 |  |  | 0.000758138
Metaal - Aluminium | 00 begane grond | Metaal - Aluminium | 3.5769 |  |  |  | 0.00127746 | 0.00127746 |  |  | 0.000758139
Metaal - Aluminium | 00 begane grond | Metaal - Aluminium | 3.5769 |  |  |  | 0.00127746 | 0.00127746 |  |  | 0.000758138
Metaal - Aluminium | 00 begane grond | Metaal - Aluminium | 2.57731 |  |  |  | 0.00092047 | 0.00092047 |  |  | 0.000758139
Metaal - Aluminium | 00 begane grond | Metaal - Aluminium | 2.51623 |  |  |  | 0.000898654 | 0.000898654 |  |  | 0.000758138
5 x Metaal - Aluminium | 00 begane grond | Metaal - Aluminium | 3.82284 |  |  |  | 0.0013653 | 0.0013653 |  |  | 0.000758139
5 x Metaal - Aluminium | 00 begane grond | Metaal - Aluminium | 3.82283 |  |  |  | 0.0013653 | 0.0013653 |  |  | 0.000758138
2 x Metaal - Aluminium | 00 begane grond | Metaal - Aluminium | 8.40624 |  |  |  | 0.00300223 | 0.00300223 |  |  | 0.000758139
2 x Metaal - Aluminium | 00 begane grond | Metaal - Aluminium | 8.40623 |  |  |  | 0.00300223 | 0.00300223 |  |  | 0.000758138
5 x Metaal - Aluminium | 00 begane grond | Metaal - Aluminium | 7.20687 |  |  |  | 0.00257388 | 0.00257388 |  |  | 0.000758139
5 x Metaal - Aluminium | 00 begane grond | Metaal - Aluminium | 7.20686 |  |  |  | 0.00257388 | 0.00257388 |  |  | 0.000758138
13 x Metaal - Aluminium | 00 begane grond | Metaal - Aluminium | 8.62034 |  |  |  | 0.00307869 | 0.00307869 |  |  | 0.000758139
13 x Metaal - Aluminium | 00 begane grond | Metaal - Aluminium | 8.62033 |  |  |  | 0.00307869 | 0.00307869 |  |  | 0.000758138
Metaal - Aluminium | 00 begane grond | Metaal - Aluminium | 0.870704 |  |  |  | 0.000310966 | 0.000310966 |  |  | 0.000184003
Metaal - Aluminium | 00 begane grond | Metaal - Aluminium | 8.36392 |  |  |  | 0.00298711 | 0.00298711 |  |  | 0.000758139
Metaal - Aluminium | 00 begane grond | Metaal - Aluminium | 8.09198 |  |  |  | 0.00288999 | 0.00288999 |  |  | 0.000758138
Metaal - Aluminium | 00 begane grond | Metaal - Aluminium | 6.17795 |  |  |  | 0.00220641 | 0.00220641 |  |  | 0.000758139
Metaal - Aluminium | 00 begane grond | Metaal - Aluminium | 5.906 |  |  |  | 0.00210928 | 0.00210928 |  |  | 0.000758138
Metaal - Aluminium | 00 begane grond | Metaal - Aluminium | 1.52089 |  |  |  | 0.000543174 | 0.000543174 |  |  | 0.000758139
Metaal - Aluminium | 00 begane grond | Metaal - Aluminium | 1.59488 |  |  |  | 0.000569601 | 0.000569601 |  |  | 0.000758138
Metaal - Aluminium | 00 begane grond | Metaal - Aluminium | 1.52094 |  |  |  | 0.000543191 | 0.000543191 |  |  | 0.000758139
Metaal - Aluminium | 00 begane grond | Metaal - Aluminium | 1.52093 |  |  |  | 0.000543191 | 0.000543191 |  |  | 0.000758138
3 x Metaal - Aluminium | 00 begane grond | Metaal - Aluminium | 8.42747 |  |  |  | 0.00300981 | 0.00300981 |  |  | 0.000758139
3 x Metaal - Aluminium | 00 begane grond | Metaal - Aluminium | 8.42746 |  |  |  | 0.00300981 | 0.00300981 |  |  | 0.000758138
Steen - Kunststeen | 00 begane grond | Steen - Kunststeen | 55.7914 |  |  |  | 0.0348696 | 0.0348696 |  |  | 0.0102562
Hout AFW | 00 begane grond | Hout AFW | 5.32928 |  |  |  | 0.00968961 | 0.00968961 | 75 | 38 | 0.00285
Isolatie - PUR gespoten | 00 begane grond | Isolatie - PUR gespoten | 0.0892464 |  |  |  | 0.0025499 | 0.0025499 | 75 | 10 | 0.00075
2 x Gipsplaat | 00 begane grond | Gipsplaat | 6.2378 | 0.62378 | 0.62378 | 12.5 | 0.00779725 | 0.00779725 | 200 | 12.5 | 0.0025
Isolatie - Steenwol LSW | 00 begane grond | Isolatie - Steenwol LSW | 1.7154 | 0.62378 | 0.62378 | 50 | 0.031189 | 0.031189 | 200 | 50 | 0.01
4 x Gipsplaat | 00 begane grond | Gipsplaat | 58.9472 | 5.89472 | 5.89472 | 12.5 | 0.073684 | 0.073684 | 1890 | 12.5 | 0.023625
Isolatie - Steenwol LSW | 00 begane grond | Isolatie - Steenwol LSW | 16.2105 | 5.89472 | 5.89472 | 50 | 0.294736 | 0.294736 | 1890 | 50 | 0.0945
Isolatie - Steenwol LSW | 00 begane grond | Isolatie - Steenwol LSW | 23.7271 | 5.75201 | 5.75201 | 75 | 0.431401 | 0.431401 | 4485 | 75 | 0.336375
2 x Gipsplaat | 00 begane grond | Gipsplaat | 57.5201 | 5.75201 | 5.75201 | 12.5 | 0.0719002 | 0.0719002 | 4485 | 12.5 | 0.0560625
2 x Gipsplaat | 00 begane grond | Gipsplaat | 8.66423 | 0.866423 | 0.866423 | 12.5 | 0.0108303 | 0.0108303 | 3650 | 12.5 | 0.045625
Isolatie - Steenwol LSW | 00 begane grond | Isolatie - Steenwol LSW | 2.38266 | 0.866423 | 0.866423 | 50 | 0.0433211 | 0.0433211 | 3650 | 50 | 0.1825
Isolatie - Steenwol LSW | 00 begane grond | Isolatie - Steenwol LSW | 2.37587 | 0.863952 | 0.863952 | 50 | 0.0431976 | 0.0431976 | 3650 | 50 | 0.1825
2 x Gipsplaat | 00 begane grond | Gipsplaat | 8.63952 | 0.863952 | 0.863952 | 12.5 | 0.0107994 | 0.0107994 | 3650 | 12.5 | 0.045625
4 x Gipsplaat | 00 begane grond | Gipsplaat | 8.93807 | 0.893807 | 0.893807 | 12.5 | 0.0111726 | 0.0111726 | 3740 | 12.5 | 0.04675
Isolatie - Steenwol LSW | 00 begane grond | Isolatie - Steenwol LSW | 3.68695 | 0.893807 | 0.893807 | 75 | 0.0670355 | 0.0670355 | 3740 | 75 | 0.2805
2 x Gipsplaat | 00 begane grond | Gipsplaat | 76.4037 | 7.64037 | 7.64037 | 12.5 | 0.0955047 | 0.0955047 | 3740 | 12.5 | 0.04675
Isolatie - Steenwol LSW | 00 begane grond | Isolatie - Steenwol LSW | 31.5165 | 7.64037 | 7.64037 | 75 | 0.573028 | 0.573028 | 3740 | 75 | 0.2805
Gipsplaat | 00 begane grond | Gipsplaat | 74.0662 | 7.40662 | 7.40662 | 12.5 | 0.0925828 | 0.0925828 | 3740 | 12.5 | 0.04675
Gipsplaat | 00 begane grond | Gipsplaat | 73.5987 | 7.35987 | 7.35987 | 12.5 | 0.0919984 | 0.0919984 | 3740 | 12.5 | 0.04675
4 x Gipsplaat | 00 begane grond | Gipsplaat | 82.28 | 8.228 | 8.228 | 12.5 | 0.10285 | 0.10285 | 3740 | 12.5 | 0.04675
Isolatie - Steenwol LSW | 00 begane grond | Isolatie - Steenwol LSW | 33.9405 | 8.228 | 8.228 | 75 | 0.6171 | 0.6171 | 3740 | 75 | 0.2805
Gipsplaat | 00 begane grond | Gipsplaat | 68.5508 | 6.85508 | 9.30256 | 12.5 | 0.0856885 | 0.116282 | 3740 | 12.5 | 0.04675
3 x Gipsplaat | 00 begane grond | Gipsplaat | 60.1358 | 6.01358 | 8.46106 | 12.5 | 0.0751697 | 0.105763 | 3740 | 12.5 | 0.04675
Isolatie - Steenwol LSW | 00 begane grond | Isolatie - Steenwol LSW | 24.806 | 6.01358 | 8.46106 | 75 | 0.451018 | 0.634579 | 3740 | 75 | 0.2805
3 x Gipsplaat | 00 begane grond | Gipsplaat | 57.5887 | 5.75887 | 5.75887 | 12.5 | 0.0719858 | 0.0719858 | 4000 | 12.5 | 0.05
Isolatie - Steenwol LSW | 00 begane grond | Isolatie - Steenwol LSW | 15.8369 | 5.75887 | 5.75887 | 50 | 0.287943 | 0.287943 | 4000 | 50 | 0.2
Gipsplaat | 00 begane grond | Gipsplaat | 65.0687 | 6.50687 | 6.50687 | 12.5 | 0.0813358 | 0.0813358 | 4000 | 12.5 | 0.05
Gipsplaat | 00 begane grond | Gipsplaat | 7.35756 | 0.735756 | 0.735756 | 12.5 | 0.00919695 | 0.00919695 | 900 | 12.5 | 0.01125
Gipsplaat | 00 begane grond | Gipsplaat | 7.24506 | 0.724506 | 0.724506 | 12.5 | 0.00905632 | 0.00905632 | 900 | 12.5 | 0.01125
Isolatie - Steenwol LSW | 00 begane grond | Isolatie - Steenwol LSW | 2.94218 | 0.713256 | 0.713256 | 75 | 0.0534942 | 0.0534942 | 900 | 75 | 0.0675
Gipsplaat | 00 begane grond | Gipsplaat | 18.045 | 1.8045 | 1.8045 | 12.5 | 0.0225563 | 0.0225563 | 900 | 12.5 | 0.01125
Gipsplaat | 00 begane grond | Gipsplaat | 17.9325 | 1.79325 | 1.79325 | 12.5 | 0.0224156 | 0.0224156 | 900 | 12.5 | 0.01125
Isolatie - Steenwol LSW | 00 begane grond | Isolatie - Steenwol LSW | 7.11872 | 1.72575 | 1.72575 | 75 | 0.129431 | 0.129431 | 900 | 75 | 0.0675
Steen - Baksteen Hoofd | 01 eerste verdieping | Steen - Baksteen Hoofd | 1248.6 | 7.80374 | 7.80374 | 100 | 0.780374 | 0.780374 | 2842.5 | 100 | 0.28425
ALG - ISOLATIE | 01 eerste verdieping | ALG - ISOLATIE | 46.6565 | 7.40579 | 7.40579 | 140 | 1.03681 | 1.03681 | 2842.5 | 140 | 0.39795
ALG - ISOLATIE | 01 eerste verdieping | ALG - ISOLATIE | 1.8648 | 0.296 | 0.296 | 140 | 0.04144 | 0.04144 | 2960 | 140 | 0.4144
Steen - Baksteen Hoofd | 01 eerste verdieping | Steen - Baksteen Hoofd | 132.608 | 0.8288 | 0.8288 | 100 | 0.08288 | 0.08288 | 2960 | 100 | 0.296
Steen - Baksteen Hoofd | 01 eerste verdieping | Steen - Baksteen Hoofd | 8208.63 | 51.3667 | 86.4914 | 100 | 5.13039 | 8.63053 | 3930 | 100 | 0.393
ALG - ISOLATIE | 01 eerste verdieping | ALG - ISOLATIE | 319.154 | 50.6593 | 85.784 | 140 | 7.0923 | 12.0098 | 3930 | 140 | 0.5502
Cement | 01 eerste verdieping | Cement | 32868.6 | 247.132 | 247.132 | 70 | 17.2993 | 17.2993
Isolatie - XPS zwevende dekvloer | 01 eerste verdieping | Isolatie - XPS zwevende dekvloer | 172.993 | 247.132 | 247.132 | 20 | 4.94265 | 4.94265
4 x Gipsplaat | 01 eerste verdieping | Gipsplaat | 265.668 | 26.5668 | 26.5668 | 12.5 | 0.332085 | 0.332085 | 3930 | 12.5 | 0.049125
Isolatie - Steenwol LSW | 01 eerste verdieping | Isolatie - Steenwol LSW | 109.588 | 26.5668 | 26.5668 | 75 | 1.99251 | 1.99251 | 3930 | 75 | 0.29475
3 x Metaal - Staal C | 01 eerste verdieping | Metaal - Staal C | 7.52291 |  |  |  | 0.000946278 | 0.000946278 |  |  | 0.000920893
3 x Steen - Baksteen Accent Rollaag | 01 eerste verdieping | Steen - Baksteen Accent Rollaag | 64.6955 |  |  |  | 0.0404347 | 0.0404347 | 210 | 100 | 0.021
8 x ALG - ISOLATIE | 01 eerste verdieping | ALG - ISOLATIE | 1.98809 |  |  |  | 0.0441798 | 0.0441798 | 157 | 140 | 0.02198
8 x Hout AFW | 01 eerste verdieping | Hout AFW | 3.40494 |  |  |  | 0.0061908 | 0.0061908 | 70 | 44 | 0.00308
8 x Isolatie - PUR gespoten | 01 eerste verdieping | Isolatie - PUR gespoten | 0.0447426 |  |  |  | 0.00127836 | 0.00127836 | 53 | 12 | 0.000636
Gipsplaat | 01 eerste verdieping | Gipsplaat | 41.0305 | 4.10305 | 7.22203 | 12.5 | 0.0512882 | 0.0902754 | 3930 | 12.5 | 0.049125
Gipsplaat | 01 eerste verdieping | Gipsplaat | 40.5393 | 4.05393 | 7.17291 | 12.5 | 0.0506741 | 0.0896613 | 3930 | 12.5 | 0.049125
Isolatie - Steenwol LSW | 01 eerste verdieping | Isolatie - Steenwol LSW | 11.0132 | 4.0048 | 7.12378 | 50 | 0.20024 | 0.356189 | 3930 | 50 | 0.1965
Gipsplaat | 01 eerste verdieping | Gipsplaat | 38.083 | 3.8083 | 6.92728 | 12.5 | 0.0476038 | 0.086591 | 3930 | 12.5 | 0.049125
Gipsplaat | 01 eerste verdieping | Gipsplaat | 37.5918 | 3.75918 | 6.87816 | 12.5 | 0.0469897 | 0.085977 | 3930 | 12.5 | 0.049125
Metaal - Aluminium | 01 eerste verdieping | Metaal - Aluminium | 21.8587 | 7.80669 | 7.80669 | 1 | 0.00780669 | 0.00780669 | 3415 | 1 | 0.003415
Isolatie - Kunststof hard | 01 eerste verdieping | Isolatie - Kunststof hard | 76.5056 | 7.80669 | 7.80669 | 98 | 0.765056 | 0.765056 | 3415 | 98 | 0.33467
Metaal - Aluminium | 01 eerste verdieping | Metaal - Aluminium | 21.7532 | 7.80669 | 7.80669 | 1 | 0.00776898 | 0.00776898 | 3415 | 1 | 0.003415
Steen - Baksteen Hoofd | 01 eerste verdieping | Steen - Baksteen Hoofd | 3743.11 | 23.4338 | 32.048 | 100 | 2.33944 | 3.20086 | 4830 | 100 | 0.483
ALG - ISOLATIE | 01 eerste verdieping | ALG - ISOLATIE | 147.633 | 23.4338 | 32.048 | 140 | 3.28074 | 4.48671 | 4830 | 140 | 0.6762
Steen - Baksteen Hoofd | 01 eerste verdieping | Steen - Baksteen Hoofd | 5335.4 | 33.3751 | 39.8304 | 100 | 3.33463 | 3.98015 | 4830 | 100 | 0.483
ALG - ISOLATIE | 01 eerste verdieping | ALG - ISOLATIE | 206.003 | 32.6989 | 39.1542 | 140 | 4.57785 | 5.48158 | 4830 | 140 | 0.6762
Steen - Baksteen Hoofd | 01 eerste verdieping | Steen - Baksteen Hoofd | 11488.5 | 71.9068 | 95.5689 | 100 | 7.18034 | 9.54655 | 4830 | 100 | 0.483
ALG - ISOLATIE | 01 eerste verdieping | ALG - ISOLATIE | 447.315 | 71.0374 | 94.6995 | 140 | 9.94033 | 13.2579 | 4830 | 140 | 0.6762
ALG - ISOLATIE | 01 eerste verdieping | ALG - ISOLATIE | 485.655 | 77.3717 | 98.9391 | 140 | 10.7923 | 13.8118 | 4830 | 140 | 0.6762
Steen - Baksteen Hoofd | 01 eerste verdieping | Steen - Baksteen Hoofd | 12352.9 | 77.5249 | 99.0923 | 100 | 7.72053 | 9.87727 | 4830 | 100 | 0.483
Steen - Baksteen Hoofd | 01 eerste verdieping | Steen - Baksteen Hoofd | 4037.59 | 25.4616 | 29.7794 | 100 | 2.52349 | 2.95527 | 4830 | 100 | 0.483
ALG - ISOLATIE | 01 eerste verdieping | ALG - ISOLATIE | 156.067 | 25.0562 | 29.374 | 140 | 3.46815 | 4.07264 | 4830 | 140 | 0.6762
Metaal - Staal C | 01 eerste verdieping | Metaal - Staal C | 9.30156 |  |  |  | 0.00117001 | 0.00117001 |  |  | 0.000920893
Steen - Baksteen Accent Rollaag | 01 eerste verdieping | Steen - Baksteen Accent Rollaag | 67.6223 |  |  |  | 0.042264 | 0.042264 | 210 | 100 | 0.021
ALG - ISOLATIE | 01 eerste verdieping | ALG - ISOLATIE | 2.08304 |  |  |  | 0.0462899 | 0.0462899 | 157 | 140 | 0.02198
Hout AFW | 01 eerste verdieping | Hout AFW | 3.56756 |  |  |  | 0.00648648 | 0.00648648 | 70 | 44 | 0.00308
Isolatie - PUR gespoten | 01 eerste verdieping | Isolatie - PUR gespoten | 0.0468795 |  |  |  | 0.00133942 | 0.00133942 | 53 | 12 | 0.000636
Steen - Baksteen Accent Rollaag | 01 eerste verdieping | Steen - Baksteen Accent Rollaag | 32.526 |  |  |  | 0.0203288 | 0.0203288 | 210 | 100 | 0.021
2 x ALG - ISOLATIE | 01 eerste verdieping | ALG - ISOLATIE | 1.29654 |  |  |  | 0.028812 | 0.028812 | 210 | 140 | 0.0294
ALG - ISOLATIE | 01 eerste verdieping | ALG - ISOLATIE | 68.3813 | 10.8542 | 10.8542 | 140 | 1.51959 | 1.51959 | 3392.5 | 140 | 0.47495
Steen - Baksteen Hoofd | 01 eerste verdieping | Steen - Baksteen Hoofd | 1736.67 | 10.8542 | 10.8542 | 100 | 1.08542 | 1.08542 | 3392.5 | 100 | 0.33925
ALG - ISOLATIE | 01 eerste verdieping | ALG - ISOLATIE | 24.1243 | 3.82925 | 3.82925 | 140 | 0.536095 | 0.536095 | 955 | 140 | 0.1337
Steen - Baksteen Hoofd | 01 eerste verdieping | Steen - Baksteen Hoofd | 612.68 | 3.82925 | 3.82925 | 100 | 0.382925 | 0.382925 | 955 | 100 | 0.0955
ALG - ISOLATIE | 01 eerste verdieping | ALG - ISOLATIE | 128.257 | 20.3583 | 22.2647 | 140 | 2.85016 | 3.11706 | 3930 | 140 | 0.5502
Steen - Baksteen Hoofd | 01 eerste verdieping | Steen - Baksteen Hoofd | 3344.95 | 20.9085 | 22.8149 | 100 | 2.09059 | 2.28029 | 3930 | 100 | 0.393
8 x Gipsplaat | 01 eerste verdieping | Gipsplaat | 3.20617 | 0.320617 | 0.320617 | 12.5 | 0.00400771 | 0.00400771 | 2290 | 12.5 | 0.028625
2 x Isolatie - Steenwol LSW | 01 eerste verdieping | Isolatie - Steenwol LSW | 0.881697 | 0.320617 | 0.320617 | 50 | 0.0160309 | 0.0160309 | 2290 | 50 | 0.1145
4 x Gipsplaat | 01 eerste verdieping | Gipsplaat | 160.987 | 16.0987 | 22.2044 | 12.5 | 0.201234 | 0.277555 | 3930 | 12.5 | 0.049125
Isolatie - Steenwol LSW | 01 eerste verdieping | Isolatie - Steenwol LSW | 66.4073 | 16.0987 | 22.2044 | 75 | 1.20741 | 1.66533 | 3930 | 75 | 0.29475
4 x Gipsplaat | 01 eerste verdieping | Gipsplaat | 156.011 | 15.6011 | 18.0486 | 12.5 | 0.195014 | 0.225607 | 3930 | 12.5 | 0.049125
Isolatie - Steenwol LSW | 01 eerste verdieping | Isolatie - Steenwol LSW | 42.903 | 15.6011 | 18.0486 | 50 | 0.780055 | 0.902429 | 3930 | 50 | 0.1965
4 x Gipsplaat | 01 eerste verdieping | Gipsplaat | 47.2812 | 4.72812 | 5.89512 | 12.5 | 0.0591015 | 0.073689 | 3930 | 12.5 | 0.049125
Isolatie - Steenwol LSW | 01 eerste verdieping | Isolatie - Steenwol LSW | 19.5035 | 4.72812 | 5.89512 | 75 | 0.354609 | 0.442134 | 3930 | 75 | 0.29475
2 x Gipsplaat | 01 eerste verdieping | Gipsplaat | 146.866 | 14.6866 | 17.9542 | 12.5 | 0.183583 | 0.224428 | 3930 | 12.5 | 0.049125
Isolatie - Steenwol LSW | 01 eerste verdieping | Isolatie - Steenwol LSW | 60.5825 | 14.6867 | 17.9543 | 75 | 1.1015 | 1.34657 | 3930 | 75 | 0.29475
2 x Gipsplaat | 01 eerste verdieping | Gipsplaat | 146.867 | 14.6867 | 17.9543 | 12.5 | 0.183584 | 0.224429 | 3930 | 12.5 | 0.049125
4 x Gipsplaat | 01 eerste verdieping | Gipsplaat | 15.2287 | 1.52287 | 1.52287 | 12.5 | 0.0190359 | 0.0190359 | 3930 | 12.5 | 0.049125
Isolatie - Steenwol LSW | 01 eerste verdieping | Isolatie - Steenwol LSW | 3.78262 | 1.3755 | 1.3755 | 50 | 0.068775 | 0.068775 | 3930 | 50 | 0.1965
2 x Gipsplaat | 01 eerste verdieping | Gipsplaat | 108.527 | 10.8527 | 23.064 | 12.5 | 0.135659 | 0.2883 | 3930 | 12.5 | 0.049125
Isolatie - Steenwol LSW | 01 eerste verdieping | Isolatie - Steenwol LSW | 44.7678 | 10.8528 | 23.0641 | 75 | 0.813959 | 1.72981 | 3930 | 75 | 0.29475
Gipsplaat | 01 eerste verdieping | Gipsplaat | 108.529 | 10.8529 | 23.0641 | 12.5 | 0.135661 | 0.288302 | 3930 | 12.5 | 0.049125
Gipsplaat | 01 eerste verdieping | Gipsplaat | 108.529 | 10.8529 | 23.0642 | 12.5 | 0.135661 | 0.288302 | 3930 | 12.5 | 0.049125
Gipsplaat | 01 eerste verdieping | Gipsplaat | 6.66135 | 0.666135 | 0.666135 | 12.5 | 0.00832669 | 0.00832669 | 3930 | 12.5 | 0.049125
Gipsplaat | 01 eerste verdieping | Gipsplaat | 7.1526 | 0.71526 | 0.71526 | 12.5 | 0.00894075 | 0.00894075 | 3930 | 12.5 | 0.049125
Isolatie - Steenwol LSW | 01 eerste verdieping | Isolatie - Steenwol LSW | 3.15309 | 0.764385 | 0.764385 | 75 | 0.0573289 | 0.0573289 | 3930 | 75 | 0.29475
Gipsplaat | 01 eerste verdieping | Gipsplaat | 10.5914 | 1.05913 | 1.05913 | 12.5 | 0.0132392 | 0.0132392 | 3930 | 12.5 | 0.049125
Gipsplaat | 01 eerste verdieping | Gipsplaat | 11.0826 | 1.10826 | 1.10826 | 12.5 | 0.0138532 | 0.0138532 | 3930 | 12.5 | 0.049125
4 x Gipsplaat | 01 eerste verdieping | Gipsplaat | 121.096 | 12.1096 | 15.3772 | 12.5 | 0.151369 | 0.192214 | 3930 | 12.5 | 0.049125
Isolatie - Steenwol LSW | 01 eerste verdieping | Isolatie - Steenwol LSW | 49.9519 | 12.1096 | 15.3772 | 75 | 0.908217 | 1.15329 | 3930 | 75 | 0.29475
Isolatie - Steenwol LSW | 01 eerste verdieping | Isolatie - Steenwol LSW | 8.10562 | 1.965 | 1.965 | 75 | 0.147375 | 0.147375 | 3930 | 75 | 0.29475
Gipsplaat | 01 eerste verdieping | Gipsplaat | 22.5975 | 2.25975 | 2.25975 | 12.5 | 0.0282469 | 0.0282469 | 3930 | 12.5 | 0.049125
Gipsplaat | 01 eerste verdieping | Gipsplaat | 23.0888 | 2.30888 | 2.30888 | 12.5 | 0.0288609 | 0.0288609 | 3930 | 12.5 | 0.049125
Gipsplaat | 01 eerste verdieping | Gipsplaat | 80.879 | 8.10851 | 11.9549 | 12.5 | 0.101099 | 0.149178 | 3930 | 12.5 | 0.049125
Gipsplaat | 01 eerste verdieping | Gipsplaat | 81.108 | 8.13142 | 11.9778 | 12.5 | 0.101385 | 0.149465 | 3930 | 12.5 | 0.049125
Isolatie - Steenwol LSW | 01 eerste verdieping | Isolatie - Steenwol LSW | 22.7267 | 8.34671 | 12.1931 | 50 | 0.413213 | 0.605532 | 3930 | 50 | 0.1965
Gipsplaat | 01 eerste verdieping | Gipsplaat | 82.2534 | 8.24595 | 12.0923 | 12.5 | 0.102817 | 0.150896 | 3930 | 12.5 | 0.049125
Gipsplaat | 01 eerste verdieping | Gipsplaat | 82.4825 | 8.26886 | 12.1152 | 12.5 | 0.103103 | 0.151183 | 3930 | 12.5 | 0.049125
Cement | 01 eerste verdieping | Cement | 6669.98 | 50.1503 | 50.1503 | 70 | 3.51052 | 3.51052
Isolatie - XPS zwevende dekvloer | 01 eerste verdieping | Isolatie - XPS zwevende dekvloer | 35.1052 | 50.1503 | 50.1503 | 20 | 1.00301 | 1.00301
Gipsplaat | 01 eerste verdieping | Gipsplaat | 41.572 | 4.17781 | 4.17781 | 12.5 | 0.051965 | 0.051965 | 3930 | 12.5 | 0.049125
Gipsplaat | 01 eerste verdieping | Gipsplaat | 41.801 | 4.20071 | 4.20071 | 12.5 | 0.0522513 | 0.0522513 | 3930 | 12.5 | 0.049125
Isolatie - Steenwol LSW | 01 eerste verdieping | Isolatie - Steenwol LSW | 11.3882 | 4.22362 | 4.22362 | 50 | 0.207059 | 0.207059 | 3930 | 50 | 0.1965
Gipsplaat | 01 eerste verdieping | Gipsplaat | 42.9464 | 4.31525 | 4.31525 | 12.5 | 0.053683 | 0.053683 | 3930 | 12.5 | 0.049125
Gipsplaat | 01 eerste verdieping | Gipsplaat | 43.1755 | 4.33816 | 4.33816 | 12.5 | 0.0539694 | 0.0539694 | 3930 | 12.5 | 0.049125
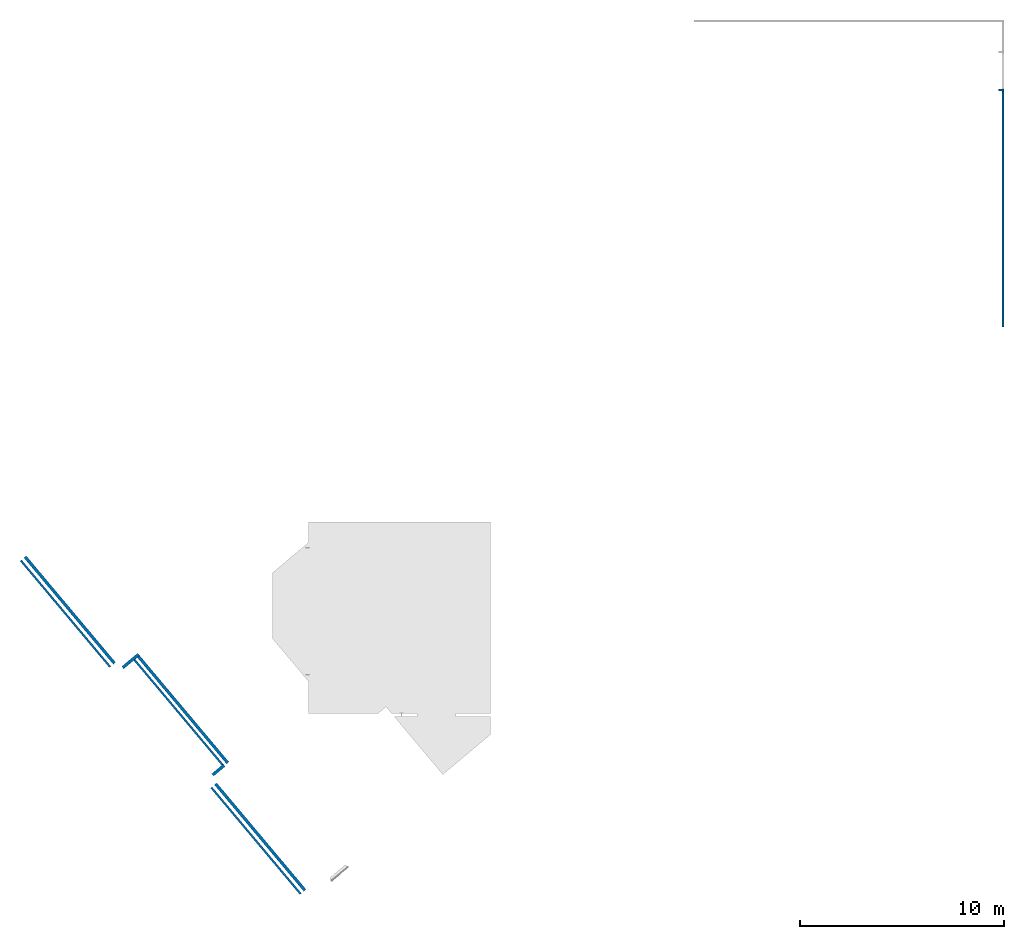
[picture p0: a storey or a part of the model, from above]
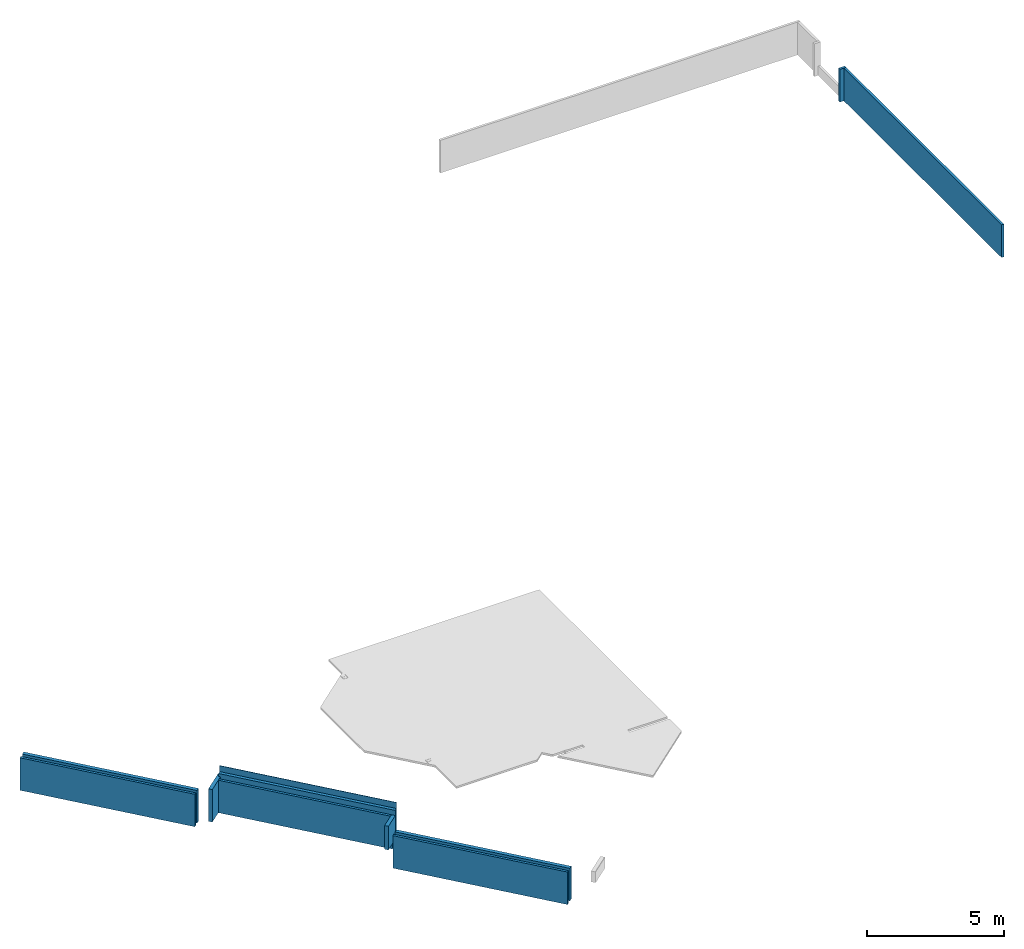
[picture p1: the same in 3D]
Properties of the parts of a building model (IFC2X3), part 3 of 11

# IfcBuildingElementPart (2314)
Name | In | Material | Mass (kg) | Projected Component Area (Net) (m2) | Projected Component Area (Gross) (m2) | Component Thickness (mm) | Component Volume (Net) (m3) | Component Volume (Gross) (m3) | Rectangular Component Height (mm) | Rectangular Component Width (mm) | Component Cross Section Area (m2)
Gipsplaat | 01 eerste verdieping | Gipsplaat | 58.8598 | 5.88598 | 9.04242 | 12.5 | 0.0735747 | 0.11303 | 3930 | 12.5 | 0.049125
Gipsplaat | 01 eerste verdieping | Gipsplaat | 58.3685 | 5.83685 | 8.99329 | 12.5 | 0.0729606 | 0.112416 | 3930 | 12.5 | 0.049125
Isolatie - Steenwol LSW | 01 eerste verdieping | Isolatie - Steenwol LSW | 15.9162 | 5.78773 | 8.94417 | 50 | 0.289386 | 0.447208 | 3930 | 50 | 0.1965
Gipsplaat | 01 eerste verdieping | Gipsplaat | 55.9123 | 5.59123 | 8.74767 | 12.5 | 0.0698903 | 0.109346 | 3930 | 12.5 | 0.049125
Gipsplaat | 01 eerste verdieping | Gipsplaat | 55.421 | 5.5421 | 8.69854 | 12.5 | 0.0692763 | 0.108732 | 3930 | 12.5 | 0.049125
Gipsplaat | 01 eerste verdieping | Gipsplaat | 137.579 | 13.7579 | 13.7579 | 12.5 | 0.171974 | 0.171974 | 3930 | 12.5 | 0.049125
Gipsplaat | 01 eerste verdieping | Gipsplaat | 138.07 | 13.807 | 13.807 | 12.5 | 0.172588 | 0.172588 | 3930 | 12.5 | 0.049125
Isolatie - Steenwol LSW | 01 eerste verdieping | Isolatie - Steenwol LSW | 38.5096 | 14.0035 | 14.0035 | 50 | 0.700175 | 0.700175 | 3930 | 50 | 0.1965
Gipsplaat | 01 eerste verdieping | Gipsplaat | 140.526 | 14.0526 | 14.0526 | 12.5 | 0.175658 | 0.175658 | 3930 | 12.5 | 0.049125
Gipsplaat | 01 eerste verdieping | Gipsplaat | 141.018 | 14.1018 | 14.1018 | 12.5 | 0.176272 | 0.176272 | 3930 | 12.5 | 0.049125
Gipsplaat | 01 eerste verdieping | Gipsplaat | 69.1504 | 6.91504 | 6.91504 | 12.5 | 0.086438 | 0.086438 | 3930 | 12.5 | 0.049125
Gipsplaat | 01 eerste verdieping | Gipsplaat | 68.1679 | 6.81679 | 6.81679 | 12.5 | 0.0852099 | 0.0852099 | 3930 | 12.5 | 0.049125
Isolatie - Steenwol LSW | 01 eerste verdieping | Isolatie - Steenwol LSW | 17.6654 | 6.42379 | 6.42379 | 50 | 0.32119 | 0.32119 | 3930 | 50 | 0.1965
Gipsplaat | 01 eerste verdieping | Gipsplaat | 63.2554 | 6.32554 | 6.32554 | 12.5 | 0.0790693 | 0.0790693 | 3930 | 12.5 | 0.049125
Gipsplaat | 01 eerste verdieping | Gipsplaat | 62.2729 | 6.22729 | 6.22729 | 12.5 | 0.0778411 | 0.0778411 | 3930 | 12.5 | 0.049125
Gipsplaat | 01 eerste verdieping | Gipsplaat | 92.2546 | 9.22546 | 15.1075 | 12.5 | 0.115318 | 0.188843 | 3930 | 12.5 | 0.049125
Gipsplaat | 01 eerste verdieping | Gipsplaat | 92.7458 | 9.27458 | 15.1566 | 12.5 | 0.115932 | 0.189457 | 3930 | 12.5 | 0.049125
Isolatie - Steenwol LSW | 01 eerste verdieping | Isolatie - Steenwol LSW | 39.0682 | 9.47108 | 15.3531 | 75 | 0.710331 | 1.15148 | 3930 | 75 | 0.29475
Gipsplaat | 01 eerste verdieping | Gipsplaat | 95.2021 | 9.52021 | 15.4022 | 12.5 | 0.119003 | 0.192528 | 3930 | 12.5 | 0.049125
Gipsplaat | 01 eerste verdieping | Gipsplaat | 95.6933 | 9.56933 | 15.4513 | 12.5 | 0.119617 | 0.193142 | 3930 | 12.5 | 0.049125
3 x Gipsplaat | 01 eerste verdieping | Gipsplaat | 62.5677 | 6.25677 | 6.25677 | 12.5 | 0.0782096 | 0.0782096 | 3930 | 12.5 | 0.049125
Isolatie - Steenwol LSW | 01 eerste verdieping | Isolatie - Steenwol LSW | 17.2061 | 6.25677 | 6.25677 | 50 | 0.312838 | 0.312838 | 3930 | 50 | 0.1965
2 x Gipsplaat | 01 eerste verdieping | Gipsplaat | 63.5502 | 6.35502 | 6.35502 | 12.5 | 0.0794377 | 0.0794377 | 3930 | 12.5 | 0.049125
Gipsplaat | 01 eerste verdieping | Gipsplaat | 71.2425 | 7.12425 | 9.57173 | 12.5 | 0.0890531 | 0.119647 | 3930 | 12.5 | 0.049125
Gipsplaat | 01 eerste verdieping | Gipsplaat | 70.7513 | 7.07513 | 9.5226 | 12.5 | 0.0884391 | 0.119033 | 3930 | 12.5 | 0.049125
Isolatie - Steenwol LSW | 01 eerste verdieping | Isolatie - Steenwol LSW | 18.9162 | 6.87863 | 9.3261 | 50 | 0.343931 | 0.466305 | 3930 | 50 | 0.1965
Gipsplaat | 01 eerste verdieping | Gipsplaat | 68.295 | 6.8295 | 9.27698 | 12.5 | 0.0853688 | 0.115962 | 3930 | 12.5 | 0.049125
Gipsplaat | 01 eerste verdieping | Gipsplaat | 67.8038 | 6.78038 | 9.22785 | 12.5 | 0.0847547 | 0.115348 | 3930 | 12.5 | 0.049125
Gipsplaat | 01 eerste verdieping | Gipsplaat | 62.0764 | 6.20764 | 6.20764 | 12.5 | 0.0775955 | 0.0775955 | 3930 | 12.5 | 0.049125
Isolatie - Steenwol LSW | 01 eerste verdieping | Isolatie - Steenwol LSW | 16.9359 | 6.15852 | 6.15852 | 50 | 0.307926 | 0.307926 | 3930 | 50 | 0.1965
Gipsplaat | 01 eerste verdieping | Gipsplaat | 59.6202 | 5.96202 | 5.96202 | 12.5 | 0.0745252 | 0.0745252 | 3930 | 12.5 | 0.049125
Gipsplaat | 01 eerste verdieping | Gipsplaat | 59.1289 | 5.91289 | 5.91289 | 12.5 | 0.0739111 | 0.0739111 | 3930 | 12.5 | 0.049125
Gipsplaat | 01 eerste verdieping | Gipsplaat | 106.257 | 10.6257 | 13.0731 | 12.5 | 0.132821 | 0.163414 | 3930 | 12.5 | 0.049125
Gipsplaat | 01 eerste verdieping | Gipsplaat | 105.765 | 10.5765 | 13.024 | 12.5 | 0.132207 | 0.1628 | 3930 | 12.5 | 0.049125
Isolatie - Steenwol LSW | 01 eerste verdieping | Isolatie - Steenwol LSW | 28.9504 | 10.5274 | 12.9749 | 50 | 0.526371 | 0.648745 | 3930 | 50 | 0.1965
Gipsplaat | 01 eerste verdieping | Gipsplaat | 103.309 | 10.3309 | 12.7784 | 12.5 | 0.129136 | 0.15973 | 3930 | 12.5 | 0.049125
Gipsplaat | 01 eerste verdieping | Gipsplaat | 102.818 | 10.2818 | 12.7293 | 12.5 | 0.128522 | 0.159116 | 3930 | 12.5 | 0.049125
Gipsplaat | 01 eerste verdieping | Gipsplaat | 124.738 | 12.4738 | 12.4738 | 12.5 | 0.155923 | 0.155923 | 3930 | 12.5 | 0.049125
Gipsplaat | 01 eerste verdieping | Gipsplaat | 124.247 | 12.4247 | 12.4247 | 12.5 | 0.155309 | 0.155309 | 3930 | 12.5 | 0.049125
Isolatie - Steenwol LSW | 01 eerste verdieping | Isolatie - Steenwol LSW | 34.0328 | 12.3756 | 12.3756 | 50 | 0.618779 | 0.618779 | 3930 | 50 | 0.1965
Gipsplaat | 01 eerste verdieping | Gipsplaat | 121.791 | 12.1791 | 12.1791 | 12.5 | 0.152238 | 0.152238 | 3930 | 12.5 | 0.049125
Gipsplaat | 01 eerste verdieping | Gipsplaat | 121.299 | 12.1299 | 12.1299 | 12.5 | 0.151624 | 0.151624 | 3930 | 12.5 | 0.049125
Gipsplaat | 01 eerste verdieping | Gipsplaat | 35.6188 | 3.56188 | 3.56188 | 12.5 | 0.0445235 | 0.0445235 | 3930 | 12.5 | 0.049125
Gipsplaat | 01 eerste verdieping | Gipsplaat | 36.1101 | 3.61101 | 3.61101 | 12.5 | 0.0451376 | 0.0451376 | 3930 | 12.5 | 0.049125
Isolatie - Steenwol LSW | 01 eerste verdieping | Isolatie - Steenwol LSW | 10.4706 | 3.80751 | 3.80751 | 50 | 0.190375 | 0.190375 | 3930 | 50 | 0.1965
Gipsplaat | 01 eerste verdieping | Gipsplaat | 38.5663 | 3.85663 | 3.85663 | 12.5 | 0.0482079 | 0.0482079 | 3930 | 12.5 | 0.049125
Gipsplaat | 01 eerste verdieping | Gipsplaat | 39.0576 | 3.90576 | 3.90576 | 12.5 | 0.048822 | 0.048822 | 3930 | 12.5 | 0.049125
4 x Gipsplaat | 01 eerste verdieping | Gipsplaat | 86.9325 | 8.69325 | 12.5649 | 12.5 | 0.108666 | 0.157061 | 3930 | 12.5 | 0.049125
Isolatie - Steenwol LSW | 01 eerste verdieping | Isolatie - Steenwol LSW | 35.8597 | 8.69325 | 12.5649 | 75 | 0.651994 | 0.942367 | 3930 | 75 | 0.29475
4 x Gipsplaat | 01 eerste verdieping | Gipsplaat | 226.328 | 22.6328 | 22.6328 | 12.5 | 0.28291 | 0.28291 | 3930 | 12.5 | 0.049125
Isolatie - Steenwol LSW | 01 eerste verdieping | Isolatie - Steenwol LSW | 93.3605 | 22.6328 | 22.6328 | 75 | 1.69746 | 1.69746 | 3930 | 75 | 0.29475
4 x Gipsplaat | 01 eerste verdieping | Gipsplaat | 200.792 | 20.0792 | 22.5267 | 12.5 | 0.25099 | 0.281583 | 3930 | 12.5 | 0.049125
Isolatie - Steenwol LSW | 01 eerste verdieping | Isolatie - Steenwol LSW | 55.2177 | 20.0792 | 22.5267 | 50 | 1.00396 | 1.12633 | 3930 | 50 | 0.1965
4 x Gipsplaat | 01 eerste verdieping | Gipsplaat | 28.089 | 2.8089 | 5.25638 | 12.5 | 0.0351112 | 0.0657047 | 3930 | 12.5 | 0.049125
Isolatie - Steenwol LSW | 01 eerste verdieping | Isolatie - Steenwol LSW | 7.72447 | 2.8089 | 5.25638 | 50 | 0.140445 | 0.262819 | 3930 | 50 | 0.1965
Gipsplaat | 01 eerste verdieping | Gipsplaat | 69.5601 | 6.95601 | 6.95601 | 12.5 | 0.0869502 | 0.0869502 | 3930 | 12.5 | 0.049125
Gipsplaat | 01 eerste verdieping | Gipsplaat | 70.0514 | 7.00514 | 7.00514 | 12.5 | 0.0875642 | 0.0875642 | 3930 | 12.5 | 0.049125
Isolatie - Steenwol LSW | 01 eerste verdieping | Isolatie - Steenwol LSW | 19.8045 | 7.20164 | 7.20164 | 50 | 0.360082 | 0.360082 | 3930 | 50 | 0.1965
Gipsplaat | 01 eerste verdieping | Gipsplaat | 72.5076 | 7.25076 | 7.25076 | 12.5 | 0.0906346 | 0.0906346 | 3930 | 12.5 | 0.049125
Gipsplaat | 01 eerste verdieping | Gipsplaat | 72.9989 | 7.29989 | 7.29989 | 12.5 | 0.0912486 | 0.0912486 | 3930 | 12.5 | 0.049125
3 x Gipsplaat | 01 eerste verdieping | Gipsplaat | 205.441 | 20.5441 | 20.5441 | 12.5 | 0.256801 | 0.256801 | 3930 | 12.5 | 0.049125
Gipsplaat | 01 eerste verdieping | Gipsplaat | 205.932 | 20.5932 | 20.5932 | 12.5 | 0.257415 | 0.257415 | 3930 | 12.5 | 0.049125
Isolatie - Steenwol LSW | 01 eerste verdieping | Isolatie - Steenwol LSW | 56.7664 | 20.6423 | 20.6423 | 50 | 1.03212 | 1.03212 | 3930 | 50 | 0.1965
Gipsplaat | 01 eerste verdieping | Gipsplaat | 208.388 | 20.8388 | 20.8388 | 12.5 | 0.260485 | 0.260485 | 3930 | 12.5 | 0.049125
Gipsplaat | 01 eerste verdieping | Gipsplaat | 208.88 | 20.888 | 20.888 | 12.5 | 0.261099 | 0.261099 | 3930 | 12.5 | 0.049125
3 x Gipsplaat | 01 eerste verdieping | Gipsplaat | 16.2112 | 1.62112 | 1.62112 | 12.5 | 0.0202641 | 0.0202641 | 3930 | 12.5 | 0.049125
Isolatie - Steenwol LSW | 01 eerste verdieping | Isolatie - Steenwol LSW | 4.86337 | 1.7685 | 1.7685 | 50 | 0.088425 | 0.088425 | 3930 | 50 | 0.1965
Gipsplaat | 01 eerste verdieping | Gipsplaat | 16.1332 | 1.62113 | 1.62112 | 12.5 | 0.0201665 | 0.0202641 | 3930 | 12.5 | 0.049125
3 x Gipsplaat | 01 eerste verdieping | Gipsplaat | 41.1275 | 4.11275 | 4.11275 | 12.5 | 0.0514093 | 0.0514093 | 3930 | 12.5 | 0.049125
Gipsplaat | 01 eerste verdieping | Gipsplaat | 41.6187 | 4.16187 | 4.16187 | 12.5 | 0.0520234 | 0.0520234 | 3930 | 12.5 | 0.049125
Isolatie - Steenwol LSW | 01 eerste verdieping | Isolatie - Steenwol LSW | 11.5802 | 4.21099 | 4.21099 | 50 | 0.21055 | 0.21055 | 3930 | 50 | 0.1965
Gipsplaat | 01 eerste verdieping | Gipsplaat | 44.075 | 4.40749 | 4.40749 | 12.5 | 0.0550937 | 0.0550937 | 3930 | 12.5 | 0.049125
Gipsplaat | 01 eerste verdieping | Gipsplaat | 44.5662 | 4.45662 | 4.45662 | 12.5 | 0.0557078 | 0.0557078 | 3930 | 12.5 | 0.049125
Gipsplaat | 01 eerste verdieping | Gipsplaat | 76.2315 | 7.62315 | 10.0706 | 12.5 | 0.0952893 | 0.125883 | 3930 | 12.5 | 0.049125
Gipsplaat | 01 eerste verdieping | Gipsplaat | 76.7227 | 7.67227 | 10.1197 | 12.5 | 0.0959034 | 0.126497 | 3930 | 12.5 | 0.049125
Isolatie - Steenwol LSW | 01 eerste verdieping | Isolatie - Steenwol LSW | 21.6391 | 7.86877 | 10.3163 | 50 | 0.393439 | 0.515813 | 3930 | 50 | 0.1965
Gipsplaat | 01 eerste verdieping | Gipsplaat | 79.179 | 7.9179 | 10.3654 | 12.5 | 0.0989737 | 0.129567 | 3930 | 12.5 | 0.049125
Gipsplaat | 01 eerste verdieping | Gipsplaat | 79.6702 | 7.96702 | 10.4145 | 12.5 | 0.0995878 | 0.130181 | 3930 | 12.5 | 0.049125
4 x Gipsplaat | 01 eerste verdieping | Gipsplaat | 153.115 | 15.3115 | 18.5791 | 12.5 | 0.191394 | 0.232239 | 3930 | 12.5 | 0.049125
Isolatie - Steenwol LSW | 01 eerste verdieping | Isolatie - Steenwol LSW | 64.1733 | 15.5572 | 18.8248 | 75 | 1.16679 | 1.41186 | 3930 | 75 | 0.29475
4 x Gipsplaat | 01 eerste verdieping | Gipsplaat | 87.5726 | 8.75726 | 14.6393 | 12.5 | 0.109466 | 0.182991 | 3930 | 12.5 | 0.049125
Isolatie - Steenwol LSW | 01 eerste verdieping | Isolatie - Steenwol LSW | 36.1237 | 8.75726 | 14.6393 | 75 | 0.656794 | 1.09794 | 3930 | 75 | 0.29475
4 x Gipsplaat | 01 eerste verdieping | Gipsplaat | 88.7515 | 8.87515 | 14.7571 | 12.5 | 0.110939 | 0.184464 | 3930 | 12.5 | 0.049125
Isolatie - Steenwol LSW | 01 eerste verdieping | Isolatie - Steenwol LSW | 36.61 | 8.87515 | 14.7571 | 75 | 0.665637 | 1.10679 | 3930 | 75 | 0.29475
4 x Gipsplaat | 01 eerste verdieping | Gipsplaat | 121.634 | 12.1634 | 12.1634 | 12.5 | 0.152042 | 0.152042 | 3930 | 12.5 | 0.049125
Isolatie - Steenwol LSW | 01 eerste verdieping | Isolatie - Steenwol LSW | 50.1738 | 12.1634 | 12.1634 | 75 | 0.912251 | 0.912251 | 3930 | 75 | 0.29475
4 x Gipsplaat | 01 eerste verdieping | Gipsplaat | 154.803 | 15.4803 | 15.4803 | 12.5 | 0.193503 | 0.193503 | 3930 | 12.5 | 0.049125
Isolatie - Steenwol LSW | 01 eerste verdieping | Isolatie - Steenwol LSW | 63.8561 | 15.4803 | 15.4803 | 75 | 1.16102 | 1.16102 | 3930 | 75 | 0.29475
4 x Gipsplaat | 01 eerste verdieping | Gipsplaat | 191.097 | 19.1097 | 23.1182 | 12.5 | 0.238871 | 0.288978 | 3930 | 12.5 | 0.049125
Isolatie - Steenwol LSW | 01 eerste verdieping | Isolatie - Steenwol LSW | 78.8276 | 19.1097 | 23.1182 | 75 | 1.43323 | 1.73387 | 3930 | 75 | 0.29475
4 x Gipsplaat | 01 eerste verdieping | Gipsplaat | 90.0796 | 9.00796 | 19.1234 | 12.5 | 0.112599 | 0.239042 | 3930 | 12.5 | 0.049125
Isolatie - Steenwol LSW | 01 eerste verdieping | Isolatie - Steenwol LSW | 37.1578 | 9.00796 | 19.1234 | 75 | 0.675597 | 1.43425 | 3930 | 75 | 0.29475
4 x Gipsplaat | 01 eerste verdieping | Gipsplaat | 30.3449 | 3.03449 | 3.03449 | 12.5 | 0.0379312 | 0.0379312 | 3930 | 12.5 | 0.049125
Isolatie - Steenwol LSW | 01 eerste verdieping | Isolatie - Steenwol LSW | 8.34486 | 3.03449 | 3.03449 | 50 | 0.151725 | 0.151725 | 3930 | 50 | 0.1965
Gipsplaat | 01 eerste verdieping | Gipsplaat | 249.476 | 24.9476 | 24.9476 | 12.5 | 0.311846 | 0.311846 | 3930 | 12.5 | 0.049125
Gipsplaat | 01 eerste verdieping | Gipsplaat | 249.968 | 24.9968 | 24.9968 | 12.5 | 0.31246 | 0.31246 | 3930 | 12.5 | 0.049125
Isolatie - Steenwol LSW | 01 eerste verdieping | Isolatie - Steenwol LSW | 103.314 | 25.0459 | 25.0459 | 75 | 1.87844 | 1.87844 | 3930 | 75 | 0.29475
Gipsplaat | 01 eerste verdieping | Gipsplaat | 253.406 | 25.3406 | 25.3406 | 12.5 | 0.316758 | 0.316758 | 3930 | 12.5 | 0.049125
Gipsplaat | 01 eerste verdieping | Gipsplaat | 253.898 | 25.3898 | 25.3898 | 12.5 | 0.317372 | 0.317372 | 3930 | 12.5 | 0.049125
Gipsplaat | 01 eerste verdieping | Gipsplaat | 80.8431 | 8.08431 | 8.08431 | 12.5 | 0.101054 | 0.101054 | 3930 | 12.5 | 0.049125
Gipsplaat | 01 eerste verdieping | Gipsplaat | 80.3518 | 8.03518 | 8.03518 | 12.5 | 0.10044 | 0.10044 | 3930 | 12.5 | 0.049125
Isolatie - Steenwol LSW | 01 eerste verdieping | Isolatie - Steenwol LSW | 21.5564 | 7.83868 | 7.83868 | 50 | 0.391934 | 0.391934 | 3930 | 50 | 0.1965
Gipsplaat | 01 eerste verdieping | Gipsplaat | 77.8956 | 7.78956 | 7.78956 | 12.5 | 0.0973694 | 0.0973694 | 3930 | 12.5 | 0.049125
Gipsplaat | 01 eerste verdieping | Gipsplaat | 77.4043 | 7.74043 | 7.74043 | 12.5 | 0.0967554 | 0.0967554 | 3930 | 12.5 | 0.049125
16 x Steen - Natuursteen AFW | 01 eerste verdieping | Steen - Natuursteen AFW | 13.4613 |  |  |  | 0.0048076 | 0.0048076 | 20 | 238 | 0.00476
16 x Cement | 01 eerste verdieping | Cement | 12.32 |  |  |  | 0.0064842 | 0.0064842 | 30 | 214 | 0.00642
17 x Kit | 01 eerste verdieping | Kit | 0.34542 |  |  |  | 0.0001818 | 0.0001818 | 20 | 9 | 0.00018
16 x Isolatie - PUR gespoten | 01 eerste verdieping | Isolatie - PUR gespoten | 0.0174983 |  |  |  | 0.00049995 | 0.00049995 | 55 | 9 | 0.000495
17 x Hout AFW | 01 eerste verdieping | Hout AFW | 1.86655 |  |  |  | 0.00339373 | 0.00339373 | 70 | 48 | 0.00336002
17 x Metaal - Aluminium | 01 eerste verdieping | Metaal - Aluminium | 1.84429 |  |  |  | 0.000658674 | 0.000658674 |  |  | 0.000655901
17 x Metaal - Aluminium | 01 eerste verdieping | Metaal - Aluminium | 0.218902 |  |  |  | 0.0000781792 | 0.0000781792 |  |  | 0.0000774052
7 x Steen - Natuursteen AFW | 01 eerste verdieping | Steen - Natuursteen AFW | 26.7893 |  |  |  | 0.0095676 | 0.0095676 | 20 | 238 | 0.00476
7 x Cement | 01 eerste verdieping | Cement | 24.518 |  |  |  | 0.0129042 | 0.0129042 | 30 | 214 | 0.00642
8 x Kit | 01 eerste verdieping | Kit | 0.68742 |  |  |  | 0.0003618 | 0.0003618 | 20 | 9 | 0.00018
7 x Isolatie - PUR gespoten | 01 eerste verdieping | Isolatie - PUR gespoten | 0.0348233 |  |  |  | 0.00099495 | 0.00099495 | 55 | 9 | 0.000495
8 x Hout AFW | 01 eerste verdieping | Hout AFW | 3.71462 |  |  |  | 0.00675386 | 0.00675386 | 70 | 48 | 0.00336002
8 x Metaal - Aluminium | 01 eerste verdieping | Metaal - Aluminium | 3.67031 |  |  |  | 0.00131083 | 0.00131083 |  |  | 0.000655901
8 x Metaal - Aluminium | 01 eerste verdieping | Metaal - Aluminium | 0.435636 |  |  |  | 0.000155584 | 0.000155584 |  |  | 0.0000774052
Isolatie - PUR gespoten | 01 eerste verdieping | Isolatie - PUR gespoten | 0.0348232 |  |  |  | 0.00099495 | 0.00099495 | 55 | 9 | 0.000495
Cement | 01 eerste verdieping | Cement | 17.1855 |  |  |  | 0.009045 | 0.009045 | 30 | 150 | 0.0045
Steen - Natuursteen AFW | 01 eerste verdieping | Steen - Natuursteen AFW | 19.1352 |  |  |  | 0.006834 | 0.006834 | 20 | 170 | 0.0034
Isolatie - PUR gespoten | 01 eerste verdieping | Isolatie - PUR gespoten | 0.0174982 |  |  |  | 0.00049995 | 0.00049995 | 55 | 9 | 0.000495
Cement | 01 eerste verdieping | Cement | 8.6355 |  |  |  | 0.004545 | 0.004545 | 30 | 150 | 0.0045
Steen - Natuursteen AFW | 01 eerste verdieping | Steen - Natuursteen AFW | 9.6152 |  |  |  | 0.003434 | 0.003434 | 20 | 170 | 0.0034
Metaal - Aluminium | 01 eerste verdieping | Metaal - Aluminium | 0.218956 |  |  |  | 0.0000781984 | 0.0000781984 |  |  | 0.0000774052
Metaal - Aluminium | 01 eerste verdieping | Metaal - Aluminium | 1.84474 |  |  |  | 0.000658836 | 0.000658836 |  |  | 0.000655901
Hout AFW | 01 eerste verdieping | Hout AFW | 1.86701 |  |  |  | 0.00339456 | 0.00339456 | 70 | 48 | 0.00336002
Isolatie - PUR gespoten | 01 eerste verdieping | Isolatie - PUR gespoten | 0.0175025 |  |  |  | 0.000500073 | 0.000500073 | 55 | 9 | 0.000495
Kit | 01 eerste verdieping | Kit | 0.345505 |  |  |  | 0.000181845 | 0.000181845 | 20 | 9 | 0.00018
Cement | 01 eerste verdieping | Cement | 12.323 |  |  |  | 0.00648579 | 0.00648579 | 30 | 214 | 0.00642
Steen - Natuursteen AFW | 01 eerste verdieping | Steen - Natuursteen AFW | 13.4646 |  |  |  | 0.00480878 | 0.00480878 | 20 | 238 | 0.00476
3 x Hout AFW | 01 eerste verdieping | Hout AFW | 1.78871 |  |  |  | 0.0032522 | 0.0032522 | 70 | 46 | 0.00322
Metaal - Staal AFW | 01 eerste verdieping | Metaal - Staal AFW | 6.54998 |  |  |  | 0.000823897 | 0.000823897 |  |  | 0.000920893
10 x Hout AFW | 01 eerste verdieping | Hout AFW | 3.55971 |  |  |  | 0.0064722 | 0.0064722 | 70 | 46 | 0.00322
Metaal - Staal AFW | 01 eerste verdieping | Metaal - Staal AFW | 13.0126 |  |  |  | 0.00163681 | 0.00163681 |  |  | 0.000920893
Metaal - Staal AFW | 01 eerste verdieping | Metaal - Staal AFW | 12.9999 |  |  |  | 0.00163521 | 0.00163521 |  |  | 0.000920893
Hout AFW | 01 eerste verdieping | Hout AFW | 1.79049 |  |  |  | 0.00325543 | 0.00325543 | 70 | 46 | 0.00322
Metaal - Staal AFW | 01 eerste verdieping | Metaal - Staal AFW | 6.50884 |  |  |  | 0.000818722 | 0.000818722 |  |  | 0.000920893
Metaal - Staal AFW | 01 eerste verdieping | Metaal - Staal AFW | 6.50238 |  |  |  | 0.00081791 | 0.00081791 |  |  | 0.000920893
2 x Metaal - Staal AFW | 01 eerste verdieping | Metaal - Staal AFW | 12.9404 |  |  |  | 0.00162772 | 0.00162772 |  |  | 0.000920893
Metaal - Staal AFW | 01 eerste verdieping | Metaal - Staal AFW | 8.25765 |  |  |  | 0.0010387 | 0.0010387 |  |  | 0.000920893
4 x Metaal - Staal AFW | 01 eerste verdieping | Metaal - Staal AFW | 4.79385 |  |  |  | 0.000603 | 0.000603 | 4 | 75 | 0.0003
4 x Hout AFW | 01 eerste verdieping | Hout AFW | 5.9697 |  |  |  | 0.010854 | 0.010854 | 100 | 54 | 0.0054
4 x Metaal - Staal AFW | 01 eerste verdieping | Metaal - Staal AFW | 4.14937 |  |  |  | 0.000521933 | 0.000521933 |  |  | 0.000920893
14 x Metaal - Staal AFW | 01 eerste verdieping | Metaal - Staal AFW | 2.40885 |  |  |  | 0.000303 | 0.000303 | 4 | 75 | 0.0003
14 x Hout AFW | 01 eerste verdieping | Hout AFW | 2.9997 |  |  |  | 0.005454 | 0.005454 | 100 | 54 | 0.0054
Metaal - Staal AFW | 01 eerste verdieping | Metaal - Staal AFW | 4.14933 |  |  |  | 0.000521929 | 0.000521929 |  |  | 0.000920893
Metaal - Staal AFW | 01 eerste verdieping | Metaal - Staal AFW | 4.14942 |  |  |  | 0.000521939 | 0.000521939 |  |  | 0.000920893
Metaal - Staal AFW | 01 eerste verdieping | Metaal - Staal AFW | 4.14944 |  |  |  | 0.000521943 | 0.000521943 |  |  | 0.000920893
Metaal - Staal AFW | 01 eerste verdieping | Metaal - Staal AFW | 4.1495 |  |  |  | 0.000521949 | 0.000521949 |  |  | 0.000920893
Metaal - Staal AFW | 01 eerste verdieping | Metaal - Staal AFW | 4.38057 |  |  |  | 0.000551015 | 0.000551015 |  |  | 0.000920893
Metaal - Staal AFW | 01 eerste verdieping | Metaal - Staal AFW | 7.39431 |  |  |  | 0.000930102 | 0.000930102 |  |  | 0.000920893
Membraan - waterdicht | 01 eerste verdieping | Membraan - waterdicht | 6.21979 |  |  |  | 0.00592361 | 0.0110056 | 340 | 6 | 0.00204
Steen - Cellenbeton | 01 eerste verdieping | Steen - Cellenbeton | 130.779 |  |  |  | 0.186827 | 0.186827 | 340 | 100 | 0.034
Steen - Baksteen Hoofd | 01 eerste verdieping | Steen - Baksteen Hoofd | 558.282 |  |  |  | 0.348926 | 0.348926 | 635 | 100 | 0.0635
ALG - ISOLATIE | 01 eerste verdieping | ALG - ISOLATIE | 12.78 |  |  |  | 0.283999 | 0.283999 | 360 | 140 | 0.0504
Steen - Baksteen Hoofd | 01 eerste verdieping | Steen - Baksteen Hoofd | 1141.12 |  |  |  | 0.7132 | 0.7132 | 1235 | 100 | 0.1235
Membraan - waterdicht | 01 eerste verdieping | Membraan - waterdicht | 46.5285 |  |  |  | 0.0443128 | 0.0443128 | 340 | 6 | 0.00204
Steen - Cellenbeton | 01 eerste verdieping | Steen - Cellenbeton | 519.506 |  |  |  | 0.742152 | 0.742152 | 340 | 100 | 0.034
Steen - Baksteen Hoofd | 01 eerste verdieping | Steen - Baksteen Hoofd | 2217.72 |  |  |  | 1.38608 | 1.38608 | 635 | 100 | 0.0635
ALG - ISOLATIE | 01 eerste verdieping | ALG - ISOLATIE | 50.0502 |  |  |  | 1.11223 | 1.11223 | 360 | 140 | 0.0504
Steen - Baksteen Hoofd | 01 eerste verdieping | Steen - Baksteen Hoofd | 4423.87 |  |  |  | 2.76492 | 2.76492 | 1235 | 100 | 0.1235
2 x Metaal - Staal C | 01 eerste verdieping | Metaal - Staal C | 3.78017 |  |  |  | 0.000475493 | 0.000475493 |  |  | 0.000920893
2 x Steen - Baksteen Accent Rollaag | 01 eerste verdieping | Steen - Baksteen Accent Rollaag | 32.5087 |  |  |  | 0.0203179 | 0.0203179 | 210 | 100 | 0.021
2 x Metaal - Staal AFW | 01 eerste verdieping | Metaal - Staal AFW | 2.83571 |  |  |  | 0.000356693 | 0.000356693 | 4 | 90 | 0.00036
6 x ALG - ISOLATIE | 01 eerste verdieping | ALG - ISOLATIE | 0.998991 |  |  |  | 0.0221998 | 0.0221998 | 157 | 140 | 0.02198
6 x Hout AFW | 01 eerste verdieping | Hout AFW | 1.71094 |  |  |  | 0.0031108 | 0.0031108 | 70 | 44 | 0.00308
6 x Isolatie - PUR gespoten | 01 eerste verdieping | Isolatie - PUR gespoten | 0.0224826 |  |  |  | 0.00064236 | 0.00064236 | 53 | 12 | 0.000636
4 x Metaal - Staal C | 01 eerste verdieping | Metaal - Staal C | 7.75155 |  |  |  | 0.000975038 | 0.000975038 |  |  | 0.000920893
4 x Steen - Baksteen Accent Rollaag | 01 eerste verdieping | Steen - Baksteen Accent Rollaag | 64.5399 |  |  |  | 0.0403374 | 0.0403374 | 210 | 100 | 0.021
4 x Metaal - Staal AFW | 01 eerste verdieping | Metaal - Staal AFW | 5.70468 |  |  |  | 0.00071757 | 0.00071757 | 4 | 90 | 0.00036
2 x Metaal - Staal C | 01 eerste verdieping | Metaal - Staal C | 3.89506 |  |  |  | 0.000489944 | 0.000489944 |  |  | 0.000920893
2 x Steen - Baksteen Accent Rollaag | 01 eerste verdieping | Steen - Baksteen Accent Rollaag | 32.4305 |  |  |  | 0.0202691 | 0.0202691 | 210 | 100 | 0.021
2 x Metaal - Staal AFW | 01 eerste verdieping | Metaal - Staal AFW | 2.86653 |  |  |  | 0.00036057 | 0.00036057 | 4 | 90 | 0.00036
Gipsplaat | 01 eerste verdieping | Gipsplaat | 43.468 | 4.3468 | 9.24176 | 12.5 | 0.0543351 | 0.115522 | 3930 | 12.5 | 0.049125
Gipsplaat | 01 eerste verdieping | Gipsplaat | 42.4855 | 4.24855 | 9.14351 | 12.5 | 0.0531069 | 0.114294 | 3930 | 12.5 | 0.049125
Isolatie - Steenwol LSW | 01 eerste verdieping | Isolatie - Steenwol LSW | 11.0081 | 4.00293 | 8.89789 | 50 | 0.200146 | 0.444894 | 3930 | 50 | 0.1965
Gipsplaat | 01 eerste verdieping | Gipsplaat | 37.573 | 3.7573 | 8.65226 | 12.5 | 0.0469663 | 0.108153 | 3930 | 12.5 | 0.049125
Gipsplaat | 01 eerste verdieping | Gipsplaat | 36.683 | 3.6683 | 8.55401 | 12.5 | 0.0458538 | 0.106925 | 3930 | 12.5 | 0.049125
Metaal - Aluminium | 01 eerste verdieping | Metaal - Aluminium | 2.01903 |  |  |  | 0.000721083 | 0.000721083 |  |  | 0.000168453
Steen - Baksteen Hoofd | 01 eerste verdieping | Steen - Baksteen Hoofd | 385.173 |  |  |  | 0.240733 | 0.240733 | 562.457 | 100 | 0.0562462
Steen - Baksteen Accent Rollaag | 01 eerste verdieping | Steen - Baksteen Accent Rollaag | 143.808 |  |  |  | 0.08988 | 0.08988 | 210 | 100 | 0.021
ALG - ISOLATIE | 01 eerste verdieping | ALG - ISOLATIE | 7.8246 |  |  |  | 0.17388 | 0.17388 | 300 | 140 | 0.042
Isolatie - Kunststof hard | 01 eerste verdieping | Isolatie - Kunststof hard | 43.5477 |  |  |  | 0.435477 | 0.435477 |  |  | 0.105507
Hout - Multiplex | 01 eerste verdieping | Hout - Multiplex | 21.2344 |  |  |  | 0.0303348 | 0.0303348 |  |  | 0.00716482
Membraan - waterdicht | 01 eerste verdieping | Membraan - waterdicht | 10.1297 |  |  |  | 0.00964734 | 0.00964734 |  |  | 0.00232548
Membraan - waterdicht | 01 eerste verdieping | Membraan - waterdicht | 11.944 |  |  |  | 0.0113753 | 0.0113753 |  |  | 0.00291682
Metaal - Aluminium | 01 eerste verdieping | Metaal - Aluminium | 6.9604 |  |  |  | 0.00248586 | 0.00248586 |  |  | 0.000168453
Steen - Baksteen Hoofd | 01 eerste verdieping | Steen - Baksteen Hoofd | 1321.83 |  |  |  | 0.826144 | 0.826144 | 562.457 | 100 | 0.0562462
Steen - Baksteen Accent Rollaag | 01 eerste verdieping | Steen - Baksteen Accent Rollaag | 493.517 |  |  |  | 0.308448 | 0.308448 | 210 | 100 | 0.021
ALG - ISOLATIE | 01 eerste verdieping | ALG - ISOLATIE | 27.1555 |  |  |  | 0.603456 | 0.603456 | 300 | 140 | 0.042
Isolatie - Kunststof hard | 01 eerste verdieping | Isolatie - Kunststof hard | 150.405 |  |  |  | 1.50405 | 1.50405 |  |  | 0.105507
Hout - Multiplex | 01 eerste verdieping | Hout - Multiplex | 72.3583 |  |  |  | 0.103369 | 0.103369 |  |  | 0.00716482
Membraan - waterdicht | 01 eerste verdieping | Membraan - waterdicht | 35.1826 |  |  |  | 0.0335072 | 0.0335072 |  |  | 0.00232548
Membraan - waterdicht | 01 eerste verdieping | Membraan - waterdicht | 29.683 |  |  |  | 0.0282695 | 0.0408982 |  |  | 0.00291682
Membraan - waterdicht | 01 eerste verdieping | Membraan - waterdicht | 12.2081 |  |  |  | 0.0116267 | 0.0116267 |  |  | 0.00291682
Membraan - waterdicht | 01 eerste verdieping | Membraan - waterdicht | 9.40455 |  |  |  | 0.00895671 | 0.00895671 |  |  | 0.00232548
Hout - Multiplex | 01 eerste verdieping | Hout - Multiplex | 19.0975 |  |  |  | 0.0272821 | 0.0272821 |  |  | 0.00716482
Isolatie - Kunststof hard | 01 eerste verdieping | Isolatie - Kunststof hard | 42.203 |  |  |  | 0.42203 | 0.42203 |  |  | 0.105507
ALG - ISOLATIE | 01 eerste verdieping | ALG - ISOLATIE | 8.0325 |  |  |  | 0.1785 | 0.1785 | 300 | 140 | 0.042
Steen - Baksteen Accent Rollaag | 01 eerste verdieping | Steen - Baksteen Accent Rollaag | 148.848 |  |  |  | 0.09303 | 0.09303 | 210 | 100 | 0.021
Steen - Baksteen Hoofd | 01 eerste verdieping | Steen - Baksteen Hoofd | 398.673 |  |  |  | 0.249171 | 0.249171 | 562.457 | 100 | 0.0562462
Metaal - Aluminium | 01 eerste verdieping | Metaal - Aluminium | 1.95348 |  |  |  | 0.000697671 | 0.000697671 |  |  | 0.000168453
Cement | 01 eerste verdieping | Cement | 74048.1 | 556.753 | 572.294 | 70 | 38.9727 | 40.0606
Isolatie - XPS zwevende dekvloer | 01 eerste verdieping | Isolatie - XPS zwevende dekvloer | 389.727 | 556.753 | 572.294 | 20 | 11.1351 | 11.4459
4 x Gipsplaat | 01 eerste verdieping | Gipsplaat | 22.9777 | 2.29777 | 2.29777 | 12.5 | 0.0287221 | 0.0287221 | 3930 | 12.5 | 0.049125
Isolatie - Steenwol LSW | 01 eerste verdieping | Isolatie - Steenwol LSW | 9.4783 | 2.29777 | 2.29777 | 75 | 0.172333 | 0.172333 | 3930 | 75 | 0.29475
4 x Gipsplaat | 01 eerste verdieping | Gipsplaat | 186.889 | 18.6889 | 18.6889 | 12.5 | 0.233612 | 0.233612 | 3930 | 12.5 | 0.049125
Isolatie - Steenwol LSW | 01 eerste verdieping | Isolatie - Steenwol LSW | 77.0918 | 18.6889 | 18.6889 | 75 | 1.40167 | 1.40167 | 3930 | 75 | 0.29475
Hout - Multiplex | 01 eerste verdieping | Hout - Multiplex | 120.512 |  |  |  | 0.17216 | 0.17216 | 1973 | 18 | 0.0355139
2 x Hout AFW | 01 eerste verdieping | Hout AFW | 12.3413 |  |  |  | 0.0224386 | 0.0224386 | 38 | 121 | 0.004598
Hout AFW | 01 eerste verdieping | Hout AFW | 5.65208 |  |  |  | 0.0102765 | 0.0102765 | 22 | 96 | 0.002112
Metaal - Aluminium | 01 eerste verdieping | Metaal - Aluminium | 3.01375 |  |  |  | 0.00107634 | 0.00107634 |  |  | 0.000222
Metaal - Aluminium | 01 eerste verdieping | Metaal - Aluminium | 3.21097 |  |  |  | 0.00114678 | 0.00114678 |  |  | 0.000236
Hout - Multiplex | 01 eerste verdieping | Hout - Multiplex | 195.948 |  |  |  | 0.279925 | 0.279925 | 1973 | 18 | 0.0355139
2 x Hout AFW | 01 eerste verdieping | Hout AFW | 20.0024 |  |  |  | 0.036368 | 0.036368 | 38 | 121 | 0.004598
Hout AFW | 01 eerste verdieping | Hout AFW | 9.17217 |  |  |  | 0.0166767 | 0.0166767 | 22 | 96 | 0.002112
Metaal - Aluminium | 01 eerste verdieping | Metaal - Aluminium | 4.89996 |  |  |  | 0.00174999 | 0.00174999 |  |  | 0.000222
Metaal - Aluminium | 01 eerste verdieping | Metaal - Aluminium | 5.21613 |  |  |  | 0.0018629 | 0.0018629 |  |  | 0.000236
Isolatie - Steenwol LSW | 01 eerste verdieping | Isolatie - Steenwol LSW | 33.2223 | 12.0808 | 12.0808 | 50 | 0.604041 | 0.604041 | 3930 | 50 | 0.1965
2 x Gipsplaat | 01 eerste verdieping | Gipsplaat | 120.808 | 12.0808 | 12.0808 | 12.5 | 0.15101 | 0.15101 | 3930 | 12.5 | 0.049125
Gipsplaat | 01 eerste verdieping | Gipsplaat | 169.481 | 16.9481 | 16.9481 | 12.5 | 0.211852 | 0.211852 | 3930 | 12.5 | 0.049125
Gipsplaat | 01 eerste verdieping | Gipsplaat | 168.99 | 16.899 | 16.899 | 12.5 | 0.211237 | 0.211237 | 3930 | 12.5 | 0.049125
Isolatie - Steenwol LSW | 01 eerste verdieping | Isolatie - Steenwol LSW | 45.9319 | 16.7025 | 16.7025 | 50 | 0.835125 | 0.835125 | 3930 | 50 | 0.1965
Gipsplaat | 01 eerste verdieping | Gipsplaat | 166.534 | 16.6534 | 16.6534 | 12.5 | 0.208167 | 0.208167 | 3930 | 12.5 | 0.049125
Gipsplaat | 01 eerste verdieping | Gipsplaat | 166.042 | 16.6043 | 16.6043 | 12.5 | 0.207553 | 0.207553 | 3930 | 12.5 | 0.049125
Gipsplaat | 01 eerste verdieping | Gipsplaat | 100.231 | 10.0231 | 10.0231 | 12.5 | 0.125289 | 0.125289 | 5380 | 12.5 | 0.06725
Gipsplaat | 01 eerste verdieping | Gipsplaat | 101.214 | 10.1214 | 10.1214 | 12.5 | 0.126517 | 0.126517 | 5380 | 12.5 | 0.06725
Isolatie - Steenwol LSW | 01 eerste verdieping | Isolatie - Steenwol LSW | 28.5093 | 10.367 | 10.367 | 50 | 0.51835 | 0.51835 | 5380 | 50 | 0.269
Gipsplaat | 01 eerste verdieping | Gipsplaat | 106.126 | 10.6126 | 10.6126 | 12.5 | 0.132658 | 0.132658 | 5380 | 12.5 | 0.06725
Gipsplaat | 01 eerste verdieping | Gipsplaat | 107.109 | 10.7109 | 10.7109 | 12.5 | 0.133886 | 0.133886 | 5380 | 12.5 | 0.06725
Gipsplaat | 01 eerste verdieping | Gipsplaat | 33.1509 | 3.31509 | 6.43407 | 12.5 | 0.0414386 | 0.0804258 | 3930 | 12.5 | 0.049125
Gipsplaat | 01 eerste verdieping | Gipsplaat | 33.6421 | 3.36421 | 6.48319 | 12.5 | 0.0420526 | 0.0810399 | 3930 | 12.5 | 0.049125
Isolatie - Steenwol LSW | 01 eerste verdieping | Isolatie - Steenwol LSW | 9.38667 | 3.41334 | 6.53232 | 50 | 0.170667 | 0.326616 | 3930 | 50 | 0.1965
Gipsplaat | 01 eerste verdieping | Gipsplaat | 36.0984 | 3.60984 | 6.72882 | 12.5 | 0.045123 | 0.0841102 | 3930 | 12.5 | 0.049125
Gipsplaat | 01 eerste verdieping | Gipsplaat | 36.5896 | 3.65896 | 6.77794 | 12.5 | 0.045737 | 0.0847243 | 3930 | 12.5 | 0.049125
2 x Gipsplaat | 01 eerste verdieping | Gipsplaat | 23.5246 | 2.35246 | 2.35246 | 12.5 | 0.0294057 | 0.0294057 | 2100 | 12.5 | 0.02625
2 x Isolatie - Steenwol LSW | 01 eerste verdieping | Isolatie - Steenwol LSW | 6.46926 | 2.35246 | 2.35246 | 50 | 0.117623 | 0.117623 | 2100 | 50 | 0.105
4 x Gipsplaat | 01 eerste verdieping | Gipsplaat | 54.8747 | 5.48747 | 5.48747 | 12.5 | 0.0685934 | 0.0685934 | 3930 | 12.5 | 0.049125
Isolatie - Steenwol LSW | 01 eerste verdieping | Isolatie - Steenwol LSW | 22.6358 | 5.48747 | 5.48747 | 75 | 0.41156 | 0.41156 | 3930 | 75 | 0.29475
4 x Gipsplaat | 01 eerste verdieping | Gipsplaat | 187.808 | 18.7808 | 18.7808 | 12.5 | 0.23476 | 0.23476 | 3930 | 12.5 | 0.049125
Isolatie - Steenwol LSW | 01 eerste verdieping | Isolatie - Steenwol LSW | 77.4707 | 18.7808 | 18.7808 | 75 | 1.40856 | 1.40856 | 3930 | 75 | 0.29475
Gipsplaat | 01 eerste verdieping | Gipsplaat | 23.1209 | 2.31211 | 2.31211 | 12.5 | 0.0289011 | 0.0289011 | 3930 | 12.5 | 0.049125
Gipsplaat | 01 eerste verdieping | Gipsplaat | 23.1212 | 2.31214 | 2.31214 | 12.5 | 0.0289015 | 0.0289015 | 3930 | 12.5 | 0.049125
Isolatie - Steenwol LSW | 01 eerste verdieping | Isolatie - Steenwol LSW | 9.53798 | 2.31234 | 2.31234 | 75 | 0.173418 | 0.173418 | 3930 | 75 | 0.29475
Gipsplaat | 01 eerste verdieping | Gipsplaat | 23.1235 | 2.31237 | 2.31237 | 12.5 | 0.0289044 | 0.0289044 | 3930 | 12.5 | 0.049125
Gipsplaat | 01 eerste verdieping | Gipsplaat | 23.1238 | 2.3124 | 2.3124 | 12.5 | 0.0289048 | 0.0289048 | 3930 | 12.5 | 0.049125
4 x Gipsplaat | 01 eerste verdieping | Gipsplaat | 55.8197 | 5.58197 | 5.58197 | 12.5 | 0.0697747 | 0.0697747 | 3930 | 12.5 | 0.049125
Isolatie - Steenwol LSW | 01 eerste verdieping | Isolatie - Steenwol LSW | 23.0256 | 5.58197 | 5.58197 | 75 | 0.418648 | 0.418648 | 3930 | 75 | 0.29475
4 x Gipsplaat | 01 eerste verdieping | Gipsplaat | 128.705 | 12.8705 | 12.8705 | 12.5 | 0.160882 | 0.160882 | 3930 | 12.5 | 0.049125
Isolatie - Steenwol LSW | 01 eerste verdieping | Isolatie - Steenwol LSW | 35.3939 | 12.8705 | 12.8705 | 50 | 0.643526 | 0.643526 | 3930 | 50 | 0.1965
ALG - ISOLATIE | 01 eerste verdieping | ALG - ISOLATIE | 15.6549 | 2.48491 | 2.48491 | 140 | 0.347887 | 0.347887 | 801.475 | 140 | 0.112206
Steen - Baksteen Hoofd | 01 eerste verdieping | Steen - Baksteen Hoofd | 409.714 | 2.56071 | 2.56071 | 100 | 0.256071 | 0.256071 | 801.475 | 100 | 0.0801475
Steen - Baksteen Accent Rollaag | 01 eerste verdieping | Steen - Baksteen Accent Rollaag | 76.6932 | 0.480469 | 0.480469 | 100 | 0.0479332 | 0.0479332 | 2562.5 | 100 | 0.25625
2 x ALG - ISOLATIE | 01 eerste verdieping | ALG - ISOLATIE | 3.02695 | 0.480469 | 0.480469 | 140 | 0.0672656 | 0.0672656 | 2562.5 | 140 | 0.35875
Isolatie - Steenwol LSW | 01 eerste verdieping | Isolatie - Steenwol LSW | 60.6141 | 14.6943 | 14.6943 | 75 | 1.10207 | 1.10207 | 3930 | 75 | 0.29475
2 x Gipsplaat | 01 eerste verdieping | Gipsplaat | 146.943 | 14.6943 | 14.6943 | 12.5 | 0.183679 | 0.183679 | 3930 | 12.5 | 0.049125
Isolatie - Steenwol LSW | 01 eerste verdieping | Isolatie - Steenwol LSW | 9.16378 | 3.33237 | 3.33237 | 50 | 0.166614 | 0.166614 | 640 | 50 | 0.032
Gipsplaat | 01 eerste verdieping | Gipsplaat | 33.0018 | 3.3002 | 3.3002 | 12.5 | 0.0412522 | 0.0412522 | 640 | 12.5 | 0.008
Gipsplaat | 01 eerste verdieping | Gipsplaat | 32.9214 | 3.29216 | 3.29216 | 12.5 | 0.0411517 | 0.0411517 | 640 | 12.5 | 0.008
Isolatie - Steenwol LSW | 01 eerste verdieping | Isolatie - Steenwol LSW | 83.1232 | 20.1511 | 20.1511 | 75 | 1.51133 | 1.51133 | 3930 | 75 | 0.29475
Isolatie - Steenwol LSW | 01 eerste verdieping | Isolatie - Steenwol LSW | 16.9651 | 4.11275 | 4.11275 | 75 | 0.308456 | 0.308456 | 3930 | 75 | 0.29475
4 x Gipsplaat | 01 eerste verdieping | Gipsplaat | 150.715 | 15.0716 | 15.0716 | 12.5 | 0.188394 | 0.188394 | 3930 | 12.5 | 0.049125
Isolatie - Steenwol LSW | 01 eerste verdieping | Isolatie - Steenwol LSW | 41.4468 | 15.0716 | 15.0716 | 50 | 0.753578 | 0.753578 | 3930 | 50 | 0.1965
4 x Gipsplaat | 01 eerste verdieping | Gipsplaat | 103.306 | 10.3306 | 19.1529 | 12.5 | 0.129132 | 0.239411 | 3930 | 12.5 | 0.049125
Isolatie - Steenwol LSW | 01 eerste verdieping | Isolatie - Steenwol LSW | 28.409 | 10.3306 | 19.1529 | 50 | 0.516528 | 0.957643 | 3930 | 50 | 0.1965
4 x Gipsplaat | 01 eerste verdieping | Gipsplaat | 50.8424 | 5.08424 | 5.08424 | 12.5 | 0.063553 | 0.063553 | 3930 | 12.5 | 0.049125
Isolatie - Steenwol LSW | 01 eerste verdieping | Isolatie - Steenwol LSW | 13.9817 | 5.08424 | 5.08424 | 50 | 0.254212 | 0.254212 | 3930 | 50 | 0.1965
4 x Gipsplaat | 01 eerste verdieping | Gipsplaat | 295.769 | 29.5769 | 29.5769 | 12.5 | 0.369712 | 0.369712 | 3930 | 12.5 | 0.049125
Isolatie - Steenwol LSW | 01 eerste verdieping | Isolatie - Steenwol LSW | 81.3366 | 29.5769 | 29.5769 | 50 | 1.47885 | 1.47885 | 3930 | 50 | 0.1965
4 x Gipsplaat | 01 eerste verdieping | Gipsplaat | 122.702 | 12.2702 | 12.2702 | 12.5 | 0.153378 | 0.153378 | 3930 | 12.5 | 0.049125
Isolatie - Steenwol LSW | 01 eerste verdieping | Isolatie - Steenwol LSW | 33.7431 | 12.2702 | 12.2702 | 50 | 0.613511 | 0.613511 | 3930 | 50 | 0.1965
4 x Gipsplaat | 01 eerste verdieping | Gipsplaat | 16.0886 | 1.60886 | 1.60886 | 12.5 | 0.0201107 | 0.0201107 | 3930 | 12.5 | 0.049125
Isolatie - Steenwol LSW | 01 eerste verdieping | Isolatie - Steenwol LSW | 4.42436 | 1.60886 | 1.60886 | 50 | 0.0804429 | 0.0804429 | 3930 | 50 | 0.1965
4 x Gipsplaat | 01 eerste verdieping | Gipsplaat | 84.2101 | 8.42101 | 14.303 | 12.5 | 0.105263 | 0.178788 | 3930 | 12.5 | 0.049125
Isolatie - Steenwol LSW | 01 eerste verdieping | Isolatie - Steenwol LSW | 34.7367 | 8.42101 | 14.303 | 75 | 0.631576 | 1.07273 | 3930 | 75 | 0.29475
4 x Gipsplaat | 01 eerste verdieping | Gipsplaat | 3.20583 | 0.320583 | 0.320583 | 12.5 | 0.00400729 | 0.00400729 | 2290 | 12.5 | 0.028625
Isolatie - Steenwol LSW | 01 eerste verdieping | Isolatie - Steenwol LSW | 0.881604 | 0.320583 | 0.320583 | 50 | 0.0160292 | 0.0160292 | 2290 | 50 | 0.1145
Gipsplaat | 01 eerste verdieping | Gipsplaat | 4.92333 | 0.492333 | 0.492333 | 12.5 | 0.00615416 | 0.00615416 | 2290 | 12.5 | 0.028625
Gipsplaat | 01 eerste verdieping | Gipsplaat | 4.92332 | 0.492332 | 0.492332 | 12.5 | 0.00615415 | 0.00615415 | 2290 | 12.5 | 0.028625
Isolatie - Steenwol LSW | 01 eerste verdieping | Isolatie - Steenwol LSW | 1.35391 | 0.492331 | 0.492331 | 50 | 0.0246166 | 0.0246166 | 2290 | 50 | 0.1145
2 x Gipsplaat | 01 eerste verdieping | Gipsplaat | 4.9233 | 0.49233 | 0.49233 | 12.5 | 0.00615413 | 0.00615413 | 2290 | 12.5 | 0.028625
2 x Gipsplaat | 01 eerste verdieping | Gipsplaat | 180.486 | 18.0486 | 18.0486 | 12.5 | 0.225607 | 0.225607 | 3930 | 12.5 | 0.049125
Isolatie - Steenwol LSW | 01 eerste verdieping | Isolatie - Steenwol LSW | 74.4504 | 18.0486 | 18.0486 | 75 | 1.35364 | 1.35364 | 3930 | 75 | 0.29475
ALG - ISOLATIE | 01 eerste verdieping | ALG - ISOLATIE | 13.9805 | 2.30091 | 2.30091 | 140 | 0.310677 | 0.310677 | 3392.5 | 140 | 0.47495
Steen - Baksteen Hoofd | 01 eerste verdieping | Steen - Baksteen Hoofd | 332.577 | 2.13729 | 2.13729 | 100 | 0.207861 | 0.207861 | 3392.5 | 100 | 0.33925
Isolatie - Steenwol LSW | 01 eerste verdieping | Isolatie - Steenwol LSW | 45.7968 | 11.1023 | 11.1023 | 75 | 0.832669 | 0.832669 | 3930 | 75 | 0.29475
Gipsplaat | 01 eerste verdieping | Gipsplaat | 111.514 | 11.1514 | 11.1514 | 12.5 | 0.139392 | 0.139392 | 3930 | 12.5 | 0.049125
Gipsplaat | 01 eerste verdieping | Gipsplaat | 112.005 | 11.2005 | 11.2005 | 12.5 | 0.140006 | 0.140006 | 3930 | 12.5 | 0.049125
2 x Gipsplaat | 01 eerste verdieping | Gipsplaat | 23.6397 | 2.36397 | 2.36397 | 12.5 | 0.0295497 | 0.0295497 | 2100 | 12.5 | 0.02625
Steen - Baksteen Hoofd | 01 eerste verdieping | Steen - Baksteen Hoofd | 97.6137 | 0.610087 | 0.610087 | 100 | 0.0610086 | 0.0610086 | 4330 | 100 | 0.433
ALG - ISOLATIE | 01 eerste verdieping | ALG - ISOLATIE | 0.00213413 | 0.00033875 | 0.00033875 | 140 | 0.000047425 | 0.000047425 | 4330 | 140 | 0.6062
Steen - Baksteen Hoofd | 01 eerste verdieping | Steen - Baksteen Hoofd | 20.5203 | 0.128252 | 0.128252 | 100 | 0.0128252 | 0.0128252 | 990 | 100 | 0.099
ALG - ISOLATIE | 01 eerste verdieping | ALG - ISOLATIE | 0.807986 | 0.128252 | 0.128252 | 140 | 0.0179552 | 0.0179552 | 990 | 140 | 0.1386
Steen - Baksteen Accent Rollaag | 01 eerste verdieping | Steen - Baksteen Accent Rollaag | 119.818 | 0.75 | 0.75 | 100 | 0.0748863 | 0.0748863 | 4000 | 100 | 0.4
2 x ALG - ISOLATIE | 01 eerste verdieping | ALG - ISOLATIE | 4.725 | 0.75 | 0.75 | 140 | 0.105 | 0.105 | 4000 | 140 | 0.56
ALG - ISOLATIE | 01 eerste verdieping | ALG - ISOLATIE | 12.9731 | 2.05923 | 2.05923 | 140 | 0.288292 | 0.288292 | 830 | 140 | 0.1162
Steen - Baksteen Hoofd | 01 eerste verdieping | Steen - Baksteen Hoofd | 329.477 | 2.05923 | 2.05923 | 100 | 0.205923 | 0.205923 | 830 | 100 | 0.083
Steen - Baksteen Accent Rollaag | 01 eerste verdieping | Steen - Baksteen Accent Rollaag | 17.7423 |  |  |  | 0.011089 | 0.011089 | 210 | 100 | 0.021
ALG - ISOLATIE | 01 eerste verdieping | ALG - ISOLATIE | 0.71442 |  |  |  | 0.015876 | 0.015876 | 210 | 140 | 0.0294
Steen - Baksteen Accent Rollaag | 01 eerste verdieping | Steen - Baksteen Accent Rollaag | 162.311 |  |  |  | 0.101445 | 0.101445 | 210 | 100 | 0.021
ALG - ISOLATIE | 01 eerste verdieping | ALG - ISOLATIE | 6.39888 |  |  |  | 0.142197 | 0.142197 | 210 | 140 | 0.0294
2 x Metaal - Staal C | 01 eerste verdieping | Metaal - Staal C | 3.84728 |  |  |  | 0.000483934 | 0.000483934 |  |  | 0.000920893
2 x Steen - Baksteen Accent Rollaag | 01 eerste verdieping | Steen - Baksteen Accent Rollaag | 32.4661 |  |  |  | 0.0202913 | 0.0202913 | 210 | 100 | 0.021
2 x Metaal - Staal AFW | 01 eerste verdieping | Metaal - Staal AFW | 2.8537 |  |  |  | 0.000358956 | 0.000358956 | 4 | 90 | 0.00036
ALG - ISOLATIE | 01 eerste verdieping | ALG - ISOLATIE | 47.7009 | 7.57157 | 7.57157 | 140 | 1.06002 | 1.06002 | 1887.5 | 140 | 0.26425
Steen - Baksteen Accent | 01 eerste verdieping | Steen - Baksteen Accent | 1211.45 | 7.57157 | 7.57157 | 100 | 0.757157 | 0.757157 | 1887.5 | 100 | 0.18875
ALG - ISOLATIE | 01 eerste verdieping | ALG - ISOLATIE | 50.522 | 8.01937 | 8.01937 | 140 | 1.12271 | 1.12271 | 2000 | 140 | 0.28
Steen - Baksteen Hoofd | 01 eerste verdieping | Steen - Baksteen Hoofd | 1283.1 | 8.01937 | 8.01937 | 100 | 0.801937 | 0.801937 | 2000 | 100 | 0.2
Metaal - Staal C | 01 eerste verdieping | Metaal - Staal C | 7.65646 |  |  |  | 0.000963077 | 0.000963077 |  |  | 0.000920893
Steen - Baksteen Accent Rollaag | 01 eerste verdieping | Steen - Baksteen Accent Rollaag | 64.6108 |  |  |  | 0.0403818 | 0.0403818 | 210 | 100 | 0.021
Metaal - Staal AFW | 01 eerste verdieping | Metaal - Staal AFW | 5.67914 |  |  |  | 0.000714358 | 0.000714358 | 4 | 90 | 0.00036
Steen - Baksteen Accent Rollaag | 01 eerste verdieping | Steen - Baksteen Accent Rollaag | 84.9853 |  |  |  | 0.0531158 | 0.0531158 | 210 | 100 | 0.021
ALG - ISOLATIE | 01 eerste verdieping | ALG - ISOLATIE | 3.35422 |  |  |  | 0.0745383 | 0.0745383 | 210 | 140 | 0.0294
Metaal - Staal C | 01 eerste verdieping | Metaal - Staal C | 11.1693 |  |  |  | 0.00140494 | 0.00140494 |  |  | 0.000920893
Steen - Baksteen Accent Rollaag | 01 eerste verdieping | Steen - Baksteen Accent Rollaag | 84.7797 |  |  |  | 0.0529873 | 0.0529873 | 210 | 100 | 0.021
Metaal - Staal AFW | 01 eerste verdieping | Metaal - Staal AFW | 7.42122 |  |  |  | 0.000933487 | 0.000933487 | 4 | 90 | 0.00036
ALG - ISOLATIE | 01 eerste verdieping | ALG - ISOLATIE | 2.59364 |  |  |  | 0.0576363 | 0.0576363 | 157 | 140 | 0.02198
Hout AFW | 01 eerste verdieping | Hout AFW | 4.44204 |  |  |  | 0.00807643 | 0.00807643 | 70 | 44 | 0.00308
Isolatie - PUR gespoten | 01 eerste verdieping | Isolatie - PUR gespoten | 0.0583706 |  |  |  | 0.00166773 | 0.00166773 | 53 | 12 | 0.000636
Steen - Baksteen Accent Rollaag | 01 eerste verdieping | Steen - Baksteen Accent Rollaag | 24.9815 |  |  |  | 0.0156134 | 0.0156134 | 210 | 100 | 0.021
3 x ALG - ISOLATIE | 01 eerste verdieping | ALG - ISOLATIE | 1.00548 |  |  |  | 0.022344 | 0.022344 | 210 | 140 | 0.0294
Steen - Baksteen Accent Rollaag | 01 eerste verdieping | Steen - Baksteen Accent Rollaag | 105.731 |  |  |  | 0.0660819 | 0.0660819 | 210 | 100 | 0.021
2 x ALG - ISOLATIE | 01 eerste verdieping | ALG - ISOLATIE | 4.17936 |  |  |  | 0.0928746 | 0.0928746 | 210 | 140 | 0.0294
Steen - Baksteen Accent Rollaag | 01 eerste verdieping | Steen - Baksteen Accent Rollaag | 14.0366 |  |  |  | 0.00877287 | 0.00877287 | 210 | 100 | 0.021
ALG - ISOLATIE | 01 eerste verdieping | ALG - ISOLATIE | 0.56889 |  |  |  | 0.012642 | 0.012642 | 210 | 140 | 0.0294
Steen - Baksteen Accent Rollaag | 01 eerste verdieping | Steen - Baksteen Accent Rollaag | 105.731 |  |  |  | 0.0660821 | 0.0660821 | 210 | 100 | 0.021
Steen - Baksteen Accent Rollaag | 01 eerste verdieping | Steen - Baksteen Accent Rollaag | 25.1216 |  |  |  | 0.015701 | 0.015701 | 210 | 100 | 0.021
Steen - Baksteen Hoofd | 01 eerste verdieping | Steen - Baksteen Hoofd | 644.816 | 4.0301 | 4.0301 | 100 | 0.40301 | 0.40301 | 955 | 100 | 0.0955
ALG - ISOLATIE | 01 eerste verdieping | ALG - ISOLATIE | 25.3896 | 4.0301 | 4.0301 | 140 | 0.564214 | 0.564214 | 955 | 140 | 0.1337
Steen - Baksteen Accent | 01 eerste verdieping | Steen - Baksteen Accent | 1274.44 | 7.96525 | 7.96525 | 100 | 0.796525 | 0.796525 | 1887.5 | 100 | 0.18875
ALG - ISOLATIE | 01 eerste verdieping | ALG - ISOLATIE | 50.1811 | 7.96525 | 7.96525 | 140 | 1.11514 | 1.11514 | 1887.5 | 140 | 0.26425
Steen - Baksteen Hoofd | 01 eerste verdieping | Steen - Baksteen Hoofd | 1494.23 | 9.40324 | 14.6577 | 100 | 0.933892 | 1.45784 | 2842.5 | 100 | 0.28425
ALG - ISOLATIE | 01 eerste verdieping | ALG - ISOLATIE | 59.2978 | 9.49414 | 14.7486 | 140 | 1.31773 | 2.05336 | 2842.5 | 140 | 0.39795
Steen - Baksteen Accent Rollaag | 01 eerste verdieping | Steen - Baksteen Accent Rollaag | 95.3732 |  |  |  | 0.0596082 | 0.0596082 | 210 | 100 | 0.021
ALG - ISOLATIE | 01 eerste verdieping | ALG - ISOLATIE | 3.77055 |  |  |  | 0.08379 | 0.08379 | 210 | 140 | 0.0294
Steen - Baksteen Accent Rollaag | 01 eerste verdieping | Steen - Baksteen Accent Rollaag | 39.93 |  |  |  | 0.0249562 | 0.0249562 | 210 | 100 | 0.021
ALG - ISOLATIE | 01 eerste verdieping | ALG - ISOLATIE | 1.5876 |  |  |  | 0.03528 | 0.03528 | 210 | 140 | 0.0294
Steen - Baksteen Accent Rollaag | 01 eerste verdieping | Steen - Baksteen Accent Rollaag | 25.1468 |  |  |  | 0.0157167 | 0.0157167 | 210 | 100 | 0.021
Steen - Baksteen Accent Rollaag | 01 eerste verdieping | Steen - Baksteen Accent Rollaag | 32.5686 |  |  |  | 0.0203554 | 0.0203554 | 210 | 100 | 0.021
Metaal - Staal AFW | 01 eerste verdieping | Metaal - Staal AFW | 5.64334 |  |  |  | 0.000709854 | 0.000709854 | 4 | 90 | 0.00036
Steen - Baksteen Accent Rollaag | 01 eerste verdieping | Steen - Baksteen Accent Rollaag | 11.7623 |  |  |  | 0.00735142 | 0.00735142 | 210 | 100 | 0.021
ALG - ISOLATIE | 01 eerste verdieping | ALG - ISOLATIE | 0.533406 |  |  |  | 0.0118535 | 0.0118535 | 210 | 140 | 0.0294
Steen - Baksteen Accent Rollaag | 01 eerste verdieping | Steen - Baksteen Accent Rollaag | 28.6443 |  |  |  | 0.0179027 | 0.0179027 | 210 | 100 | 0.021
ALG - ISOLATIE | 01 eerste verdieping | ALG - ISOLATIE | 1.26112 |  |  |  | 0.0280249 | 0.0280249 | 210 | 140 | 0.0294
Steen - Baksteen Hoofd | 01 eerste verdieping | Steen - Baksteen Hoofd | 2638 | 16.5145 | 22.9697 | 100 | 1.64875 | 2.29427 | 4267.5 | 100 | 0.42675
ALG - ISOLATIE | 01 eerste verdieping | ALG - ISOLATIE | 100.04 | 15.8793 | 22.3346 | 140 | 2.2231 | 3.12684 | 4267.5 | 140 | 0.59745
Steen - Baksteen Accent Rollaag | 01 eerste verdieping | Steen - Baksteen Accent Rollaag | 119.763 | 0.75 | 0.75 | 100 | 0.0748518 | 0.0748518 | 4000 | 100 | 0.4
Metaal - Staal C | 01 eerste verdieping | Metaal - Staal C | 21.7617 |  |  |  | 0.00273732 | 0.00273732 |  |  | 0.000920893
Steen - Baksteen Accent Rollaag | 01 eerste verdieping | Steen - Baksteen Accent Rollaag | 109.936 |  |  |  | 0.0687103 | 0.0687103 | 210 | 100 | 0.021
ALG - ISOLATIE | 01 eerste verdieping | ALG - ISOLATIE | 3.88757 |  |  |  | 0.0863905 | 0.0863905 |  |  | 0.02541
Hout AFW | 01 eerste verdieping | Hout AFW | 6.07819 |  |  |  | 0.0110513 | 0.0110513 |  |  | 0.0032505
Isolatie - PUR gespoten | 01 eerste verdieping | Isolatie - PUR gespoten | 0.0910313 |  |  |  | 0.0026009 | 0.0026009 | 85 | 9 | 0.000765
Steen - Baksteen Accent Rollaag | 01 eerste verdieping | Steen - Baksteen Accent Rollaag | 76.6379 | 0.480469 | 0.480469 | 100 | 0.0478987 | 0.0478987 | 2562.5 | 100 | 0.25625
Metaal - Aluminium | 01 eerste verdieping | Metaal - Aluminium | 19.124 | 6.83 | 6.83 | 1 | 0.00683 | 0.00683 | 3415 | 1 | 0.003415
Isolatie - Kunststof hard | 01 eerste verdieping | Isolatie - Kunststof hard | 66.923 | 6.83 | 6.83 | 98 | 0.66923 | 0.66923 | 3415 | 98 | 0.33467
Metaal - Aluminium | 01 eerste verdieping | Metaal - Aluminium | 18.9795 | 6.7784 | 6.7784 | 1 | 0.00677839 | 0.00677839 | 3415 | 1 | 0.003415
5 x Metaal - Aluminium | 01 eerste verdieping | Metaal - Aluminium | 9.562 | 3.415 | 3.415 | 1 | 0.003415 | 0.003415 | 3415 | 1 | 0.003415
5 x Isolatie - Kunststof hard | 01 eerste verdieping | Isolatie - Kunststof hard | 33.467 | 3.415 | 3.415 | 98 | 0.33467 | 0.33467 | 3415 | 98 | 0.33467
5 x Metaal - Aluminium | 01 eerste verdieping | Metaal - Aluminium | 9.50601 | 3.395 | 3.395 | 1 | 0.003395 | 0.003395 | 3415 | 1 | 0.003415
Metaal - Aluminium | 01 eerste verdieping | Metaal - Aluminium | 2.00802 | 0.717151 | 0.717151 | 1 | 0.000717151 | 0.000717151 | 3415 | 1 | 0.003415
Isolatie - Kunststof hard | 01 eerste verdieping | Isolatie - Kunststof hard | 7.02808 | 0.717151 | 0.717151 | 98 | 0.0702808 | 0.0702808 | 3415 | 98 | 0.33467
Metaal - Aluminium | 01 eerste verdieping | Metaal - Aluminium | 1.99626 | 0.712952 | 0.712952 | 1 | 0.000712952 | 0.000712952 | 3415 | 1 | 0.003415
Steen - Baksteen Hoofd | 01 eerste verdieping | Steen - Baksteen Hoofd | 241.501 | 1.50938 | 1.50938 | 100 | 0.150938 | 0.150938 | 260 | 100 | 0.026
ALG - ISOLATIE | 01 eerste verdieping | ALG - ISOLATIE | 9.50911 | 1.50938 | 1.50938 | 140 | 0.211314 | 0.211314 | 260 | 140 | 0.0364
Steen - Natuursteen AFW | 01 eerste verdieping | Steen - Natuursteen AFW | 37.063 |  |  |  | 0.0132368 | 0.0132368 | 20 | 238 | 0.00476
Cement | 01 eerste verdieping | Cement | 33.9207 |  |  |  | 0.017853 | 0.017853 | 30 | 214 | 0.00642
Kit | 01 eerste verdieping | Kit | 0.951047 |  |  |  | 0.000500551 | 0.000500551 | 20 | 9 | 0.00018
Isolatie - PUR gespoten | 01 eerste verdieping | Isolatie - PUR gespoten | 0.048178 |  |  |  | 0.00137652 | 0.00137652 | 55 | 9 | 0.000495
Hout AFW | 01 eerste verdieping | Hout AFW | 5.13919 |  |  |  | 0.00934398 | 0.00934398 | 70 | 48 | 0.00336002
Metaal - Aluminium | 01 eerste verdieping | Metaal - Aluminium | 5.07788 |  |  |  | 0.00181353 | 0.00181353 |  |  | 0.000655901
Metaal - Aluminium | 01 eerste verdieping | Metaal - Aluminium | 0.602704 |  |  |  | 0.000215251 | 0.000215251 |  |  | 0.0000774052
4 x Metaal - Staal AFW | 01 eerste verdieping | Metaal - Staal AFW | 4.2008 |  |  |  | 0.000528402 | 0.000528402 |  |  | 0.000920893
3 x Metaal - Staal AFW | 01 eerste verdieping | Metaal - Staal AFW | 8.36 |  |  |  | 0.00105157 | 0.00105157 |  |  | 0.000920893
Hout AFW | 01 eerste verdieping | Hout AFW | 8.25909 |  |  |  | 0.0150165 | 0.0150165 | 100 | 54 | 0.0054
Metaal - Staal AFW | 01 eerste verdieping | Metaal - Staal AFW | 6.6323 |  |  |  | 0.000834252 | 0.000834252 | 4 | 75 | 0.0003
Metaal - Staal AFW | 01 eerste verdieping | Metaal - Staal AFW | 8.67631 |  |  |  | 0.00109136 | 0.00109136 |  |  | 0.000920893
Metaal - Staal AFW | 01 eerste verdieping | Metaal - Staal AFW | 7.03551 |  |  |  | 0.000884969 | 0.000884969 |  |  | 0.000920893
5 x Metaal - Staal AFW | 01 eerste verdieping | Metaal - Staal AFW | 9.51972 |  |  |  | 0.00119745 | 0.00119745 |  |  | 0.000920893
Metaal - Staal AFW | 01 eerste verdieping | Metaal - Staal AFW | 7.08786 |  |  |  | 0.000891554 | 0.000891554 |  |  | 0.000920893
4 x Gipsplaat | 01 eerste verdieping | Gipsplaat | 32.4713 | 3.24713 | 7.24585 | 12.5 | 0.0405891 | 0.0905731 | 3930 | 12.5 | 0.049125
Isolatie - Steenwol LSW | 01 eerste verdieping | Isolatie - Steenwol LSW | 8.9296 | 3.24713 | 7.24585 | 50 | 0.162356 | 0.362292 | 3930 | 50 | 0.1965
Isolatie - Steenwol LSW | 01 eerste verdieping | Isolatie - Steenwol LSW | 14.9934 | 3.63477 | 3.63477 | 75 | 0.272607 | 0.272607 | 3930 | 75 | 0.29475
2 x Gipsplaat | 01 eerste verdieping | Gipsplaat | 36.8389 | 3.68389 | 3.68389 | 12.5 | 0.0460486 | 0.0460486 | 3930 | 12.5 | 0.049125
2 x Gipsplaat | 01 eerste verdieping | Gipsplaat | 37.3302 | 3.73302 | 3.73302 | 12.5 | 0.0466627 | 0.0466627 | 3930 | 12.5 | 0.049125
2 x Isolatie - Steenwol LSW | 01 eerste verdieping | Isolatie - Steenwol LSW | 1.62112 | 0.393 | 0.393 | 75 | 0.029475 | 0.029475 | 3930 | 75 | 0.29475
Gipsplaat | 01 eerste verdieping | Gipsplaat | 6.8775 | 0.68775 | 0.68775 | 12.5 | 0.00859688 | 0.00859688 | 3930 | 12.5 | 0.049125
2 x Gipsplaat | 01 eerste verdieping | Gipsplaat | 7.36875 | 0.736875 | 0.736875 | 12.5 | 0.00921094 | 0.00921094 | 3930 | 12.5 | 0.049125
Gipsplaat | 01 eerste verdieping | Gipsplaat | 38.4354 | 3.84354 | 3.84354 | 12.5 | 0.0480443 | 0.0480443 | 3930 | 12.5 | 0.049125
Gipsplaat | 01 eerste verdieping | Gipsplaat | 37.9442 | 3.79442 | 3.79442 | 12.5 | 0.0474302 | 0.0474302 | 3930 | 12.5 | 0.049125
Isolatie - Steenwol LSW | 01 eerste verdieping | Isolatie - Steenwol LSW | 15.4493 | 3.74529 | 3.74529 | 75 | 0.280897 | 0.280897 | 3930 | 75 | 0.29475
Gipsplaat | 01 eerste verdieping | Gipsplaat | 6.8775 | 0.68775 | 0.68775 | 12.5 | 0.00859687 | 0.00859687 | 3930 | 12.5 | 0.049125
Gipsplaat | 01 eerste verdieping | Gipsplaat | 15.6211 | 1.56211 | 1.56211 | 12.5 | 0.0195263 | 0.0195263 | 3930 | 12.5 | 0.049125
Gipsplaat | 01 eerste verdieping | Gipsplaat | 15.1298 | 1.51298 | 1.51298 | 12.5 | 0.0189123 | 0.0189123 | 3930 | 12.5 | 0.049125
Isolatie - Steenwol LSW | 01 eerste verdieping | Isolatie - Steenwol LSW | 3.62032 | 1.31648 | 1.31648 | 50 | 0.065824 | 0.065824 | 3930 | 50 | 0.1965
Gipsplaat | 01 eerste verdieping | Gipsplaat | 12.6736 | 1.26736 | 1.26736 | 12.5 | 0.0158419 | 0.0158419 | 3930 | 12.5 | 0.049125
Gipsplaat | 01 eerste verdieping | Gipsplaat | 12.1823 | 1.21823 | 1.21823 | 12.5 | 0.0152279 | 0.0152279 | 3930 | 12.5 | 0.049125
Isolatie - Steenwol LSW | 01 eerste verdieping | Isolatie - Steenwol LSW | 9.99561 | 3.63477 | 3.63477 | 50 | 0.181738 | 0.181738 | 3930 | 50 | 0.1965
Gipsplaat | 01 eerste verdieping | Gipsplaat | 5.40375 | 0.540375 | 0.540375 | 12.5 | 0.00675469 | 0.00675469 | 3930 | 12.5 | 0.049125
2 x Gipsplaat | 01 eerste verdieping | Gipsplaat | 4.9125 | 0.49125 | 0.49125 | 12.5 | 0.00614063 | 0.00614063 | 3930 | 12.5 | 0.049125
Isolatie - Steenwol LSW | 01 eerste verdieping | Isolatie - Steenwol LSW | 0.810562 | 0.29475 | 0.29475 | 50 | 0.0147375 | 0.0147375 | 3930 | 50 | 0.1965
2 x Gipsplaat | 01 eerste verdieping | Gipsplaat | 4.42125 | 0.442125 | 0.442125 | 12.5 | 0.00552656 | 0.00552656 | 3930 | 12.5 | 0.049125
Isolatie - Steenwol LSW | 01 eerste verdieping | Isolatie - Steenwol LSW | 1.37019 | 0.49825 | 0.393 | 50 | 0.0249125 | 0.01965 | 3930 | 50 | 0.1965
Gipsplaat | 01 eerste verdieping | Gipsplaat | 34.5643 | 3.45643 | 3.45643 | 12.5 | 0.0432054 | 0.0432054 | 3930 | 12.5 | 0.049125
Gipsplaat | 01 eerste verdieping | Gipsplaat | 33.5819 | 3.35819 | 3.35819 | 12.5 | 0.0419773 | 0.0419773 | 3930 | 12.5 | 0.049125
Isolatie - Steenwol LSW | 01 eerste verdieping | Isolatie - Steenwol LSW | 8.55954 | 3.11256 | 3.11256 | 50 | 0.155628 | 0.155628 | 3930 | 50 | 0.1965
Gipsplaat | 01 eerste verdieping | Gipsplaat | 3.93 | 0.393 | 0.393 | 12.5 | 0.0049125 | 0.0049125 | 3930 | 12.5 | 0.049125
Isolatie - Steenwol LSW | 01 eerste verdieping | Isolatie - Steenwol LSW | 0.829812 | 0.30175 | 0.1965 | 50 | 0.0150875 | 0.009825 | 3930 | 50 | 0.1965
Isolatie - Steenwol LSW | 01 eerste verdieping | Isolatie - Steenwol LSW | 4.68508 | 1.13578 | 1.13578 | 75 | 0.0851832 | 0.0851832 | 3930 | 75 | 0.29475
Gipsplaat | 01 eerste verdieping | Gipsplaat | 11.849 | 1.1849 | 1.1849 | 12.5 | 0.0148113 | 0.0148113 | 3930 | 12.5 | 0.049125
Gipsplaat | 01 eerste verdieping | Gipsplaat | 12.3403 | 1.23403 | 1.23403 | 12.5 | 0.0154253 | 0.0154253 | 3930 | 12.5 | 0.049125
Isolatie - Steenwol LSW | 01 eerste verdieping | Isolatie - Steenwol LSW | 4.97687 | 1.20651 | 1.20651 | 75 | 0.0904885 | 0.0904885 | 3930 | 75 | 0.29475
Gipsplaat | 01 eerste verdieping | Gipsplaat | 15.0126 | 1.50126 | 1.50126 | 12.5 | 0.0187658 | 0.0187658 | 3930 | 12.5 | 0.049125
Gipsplaat | 01 eerste verdieping | Gipsplaat | 15.5039 | 1.55039 | 1.55039 | 12.5 | 0.0193799 | 0.0193799 | 3930 | 12.5 | 0.049125
Isolatie - Steenwol LSW | 01 eerste verdieping | Isolatie - Steenwol LSW | 3.564 | 0.864 | 0.864 | 75 | 0.0648 | 0.0648 | 3840 | 75 | 0.288
2 x Gipsplaat | 01 eerste verdieping | Gipsplaat | 9.12 | 0.912 | 0.912 | 12.5 | 0.0114 | 0.0114 | 3840 | 12.5 | 0.048
Gipsplaat | 01 eerste verdieping | Gipsplaat | 9.6 | 0.96 | 0.96 | 12.5 | 0.012 | 0.012 | 3840 | 12.5 | 0.048
Isolatie - Steenwol LSW | 01 eerste verdieping | Isolatie - Steenwol LSW | 2.376 | 0.576 | 0.576 | 75 | 0.0432 | 0.0432 | 3840 | 75 | 0.288
Gipsplaat | 01 eerste verdieping | Gipsplaat | 8.64 | 0.864 | 0.864 | 12.5 | 0.0108 | 0.0108 | 3840 | 12.5 | 0.048
Isolatie - Steenwol LSW | 01 eerste verdieping | Isolatie - Steenwol LSW | 4.42566 | 1.07289 | 1.07289 | 75 | 0.0804665 | 0.0804665 | 3930 | 75 | 0.29475
Gipsplaat | 01 eerste verdieping | Gipsplaat | 11.2201 | 1.12201 | 1.12201 | 12.5 | 0.0140251 | 0.0140251 | 3930 | 12.5 | 0.049125
Gipsplaat | 01 eerste verdieping | Gipsplaat | 11.7114 | 1.17114 | 1.17114 | 12.5 | 0.0146392 | 0.0146392 | 3930 | 12.5 | 0.049125
Isolatie - Steenwol LSW | 01 eerste verdieping | Isolatie - Steenwol LSW | 3.46921 | 0.84102 | 0.84102 | 75 | 0.0630765 | 0.0630765 | 3930 | 75 | 0.29475
Gipsplaat | 01 eerste verdieping | Gipsplaat | 11.3577 | 1.13577 | 1.13577 | 12.5 | 0.0141971 | 0.0141971 | 3930 | 12.5 | 0.049125
Gipsplaat | 01 eerste verdieping | Gipsplaat | 11.849 | 1.1849 | 1.1849 | 12.5 | 0.0148112 | 0.0148112 | 3930 | 12.5 | 0.049125
2 x Gipsplaat | 01 eerste verdieping | Gipsplaat | 30.505 | 3.0505 | 3.0505 | 12.5 | 0.0381312 | 0.0381312 | 3930 | 12.5 | 0.049125
Isolatie - Steenwol LSW | 01 eerste verdieping | Isolatie - Steenwol LSW | 12.5833 | 3.0505 | 3.0505 | 75 | 0.228787 | 0.228787 | 3930 | 75 | 0.29475
Gipsplaat | 01 eerste verdieping | Gipsplaat | 8.99139 | 0.89914 | 0.89914 | 12.5 | 0.0112392 | 0.0112392 | 3930 | 12.5 | 0.049125
Gipsplaat | 01 eerste verdieping | Gipsplaat | 8.50017 | 0.850019 | 0.850019 | 12.5 | 0.0106252 | 0.0106252 | 3930 | 12.5 | 0.049125
Isolatie - Steenwol LSW | 01 eerste verdieping | Isolatie - Steenwol LSW | 3.30373 | 0.800915 | 0.800915 | 75 | 0.0600678 | 0.0600678 | 3930 | 75 | 0.29475
Gipsplaat | 01 eerste verdieping | Gipsplaat | 12.6934 | 1.26934 | 1.26934 | 12.5 | 0.0158668 | 0.0158668 | 3930 | 12.5 | 0.049125
Gipsplaat | 01 eerste verdieping | Gipsplaat | 12.2022 | 1.22022 | 1.22022 | 12.5 | 0.0152527 | 0.0152527 | 3930 | 12.5 | 0.049125
Isolatie - Steenwol LSW | 01 eerste verdieping | Isolatie - Steenwol LSW | 2.66438 | 0.645917 | 0.645917 | 75 | 0.0484433 | 0.0484433 | 3930 | 75 | 0.29475
Membraan - waterdicht | 01 eerste verdieping | Membraan - waterdicht | 11.5432 |  |  |  | 0.0109936 | 0.0109936 | 340 | 6 | 0.00204
Steen - Cellenbeton | 01 eerste verdieping | Steen - Cellenbeton | 128.401 |  |  |  | 0.18343 | 0.18343 | 340 | 100 | 0.034
Steen - Baksteen Hoofd | 01 eerste verdieping | Steen - Baksteen Hoofd | 548.132 |  |  |  | 0.342583 | 0.342583 | 635 | 100 | 0.0635
ALG - ISOLATIE | 01 eerste verdieping | ALG - ISOLATIE | 12.4627 |  |  |  | 0.276948 | 0.276948 | 360 | 140 | 0.0504
Steen - Baksteen Hoofd | 01 eerste verdieping | Steen - Baksteen Hoofd | 1121.38 |  |  |  | 0.700863 | 0.700863 | 1235 | 100 | 0.1235
Isolatie - Steenwol LSW | 01 eerste verdieping | Isolatie - Steenwol LSW | 0.205703 | 0.498674 | 0.498674 | 7.5 | 0.00374005 | 0.00374005 | 2100 | 7.5 | 0.01575
2 x Gipsplaat | 01 eerste verdieping | Gipsplaat | 4.98674 | 0.498674 | 0.498674 | 12.5 | 0.00623342 | 0.00623342 | 2100 | 12.5 | 0.02625
Gipsplaat | 01 eerste verdieping | Gipsplaat | 2.49002 |  |  |  | 0.00311253 | 0.00311253 | 12.5 | 130 | 0.00162497
Metaal - RVS | 01 eerste verdieping | Metaal - RVS | 1.10756 |  |  |  | 0.000140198 | 0.000140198 |  |  | 0.0000777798
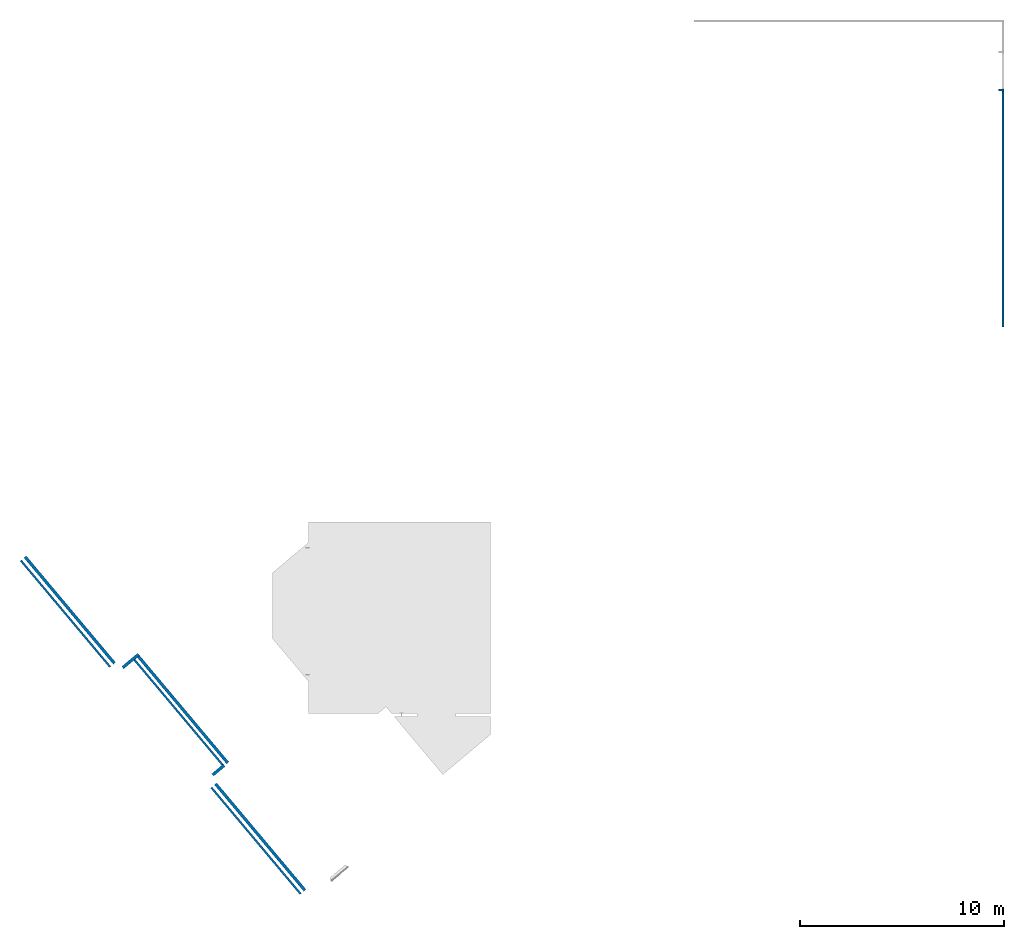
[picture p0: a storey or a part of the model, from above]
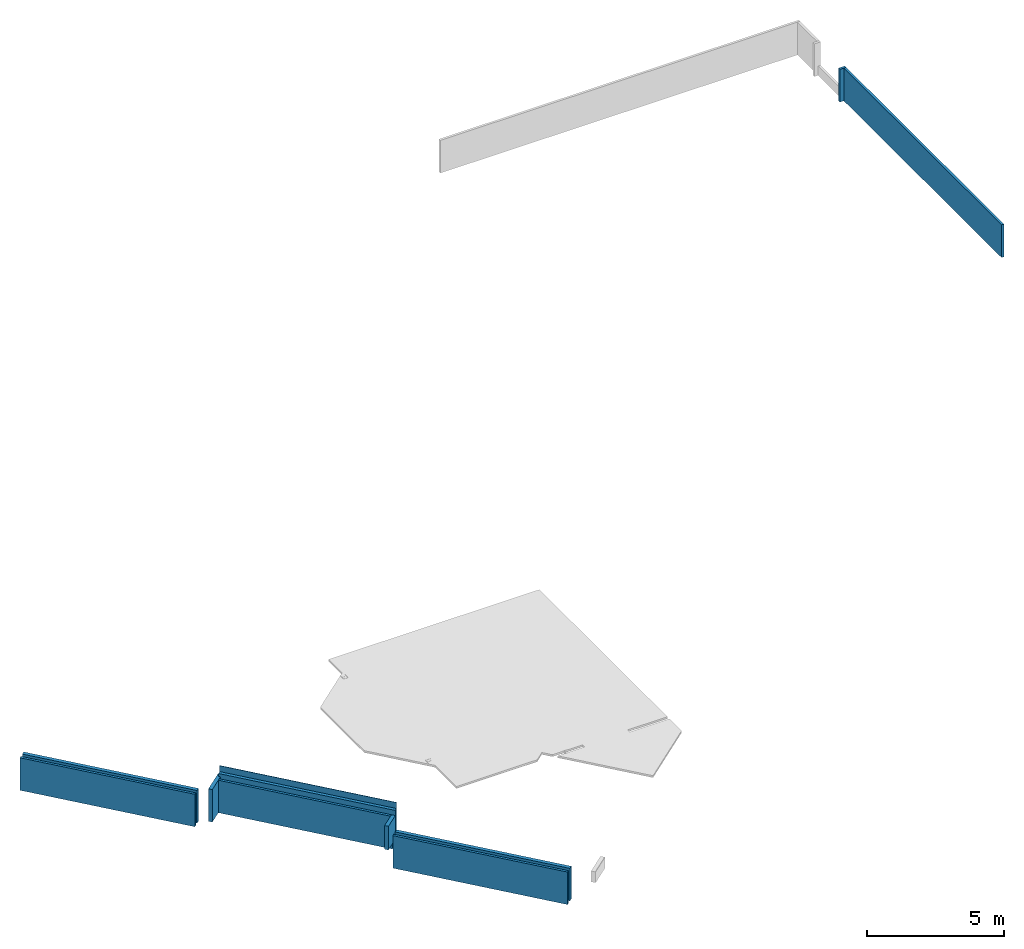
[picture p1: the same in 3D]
Properties of the parts of a building model (IFC2X3), part 4 of 11

# IfcBuildingElementPart (2314)
Name | In | Material | Mass (kg) | Projected Component Area (Net) (m2) | Projected Component Area (Gross) (m2) | Component Thickness (mm) | Component Volume (Net) (m3) | Component Volume (Gross) (m3) | Rectangular Component Height (mm) | Rectangular Component Width (mm) | Component Cross Section Area (m2)
Gipsplaat | 01 eerste verdieping | Gipsplaat | 8.6891 | 0.86891 | 1.61458 | 12.5 | 0.0108614 | 0.0201823 | 1100 | 12.5 | 0.01375
Gipsplaat | 01 eerste verdieping | Gipsplaat | 8.68808 | 0.868911 | 1.61458 | 12.5 | 0.0108601 | 0.020181 | 1100 | 12.5 | 0.01375
Isolatie - Steenwol LSW | 01 eerste verdieping | Isolatie - Steenwol LSW | 2.37734 | 0.867718 | 1.61445 | 50 | 0.0432244 | 0.0805868 | 1100 | 50 | 0.055
Gipsplaat | 01 eerste verdieping | Gipsplaat | 8.68783 | 0.868783 | 1.61445 | 12.5 | 0.0108598 | 0.0201807 | 1100 | 12.5 | 0.01375
Gipsplaat | 01 eerste verdieping | Gipsplaat | 8.68881 | 0.868783 | 1.61445 | 12.5 | 0.010861 | 0.0201832 | 1100 | 12.5 | 0.01375
Gipsplaat | 01 eerste verdieping | Gipsplaat | 33.8624 | 3.38624 | 3.38624 | 12.5 | 0.0423279 | 0.0423279 | 3930 | 12.5 | 0.049125
Gipsplaat | 01 eerste verdieping | Gipsplaat | 33.3711 | 3.33711 | 3.33711 | 12.5 | 0.0417139 | 0.0417139 | 3930 | 12.5 | 0.049125
Isolatie - Steenwol LSW | 01 eerste verdieping | Isolatie - Steenwol LSW | 8.63668 | 3.14061 | 3.14061 | 50 | 0.157031 | 0.157031 | 3930 | 50 | 0.1965
Gipsplaat | 01 eerste verdieping | Gipsplaat | 30.9149 | 3.09149 | 3.09149 | 12.5 | 0.0386436 | 0.0386436 | 3930 | 12.5 | 0.049125
Gipsplaat | 01 eerste verdieping | Gipsplaat | 30.4236 | 3.04236 | 3.04236 | 12.5 | 0.0380295 | 0.0380295 | 3930 | 12.5 | 0.049125
4 x Gipsplaat | 01 eerste verdieping | Gipsplaat | 14.8457 | 1.48457 | 1.48457 | 12.5 | 0.0185571 | 0.0185571 | 3930 | 12.5 | 0.049125
Isolatie - Steenwol LSW | 01 eerste verdieping | Isolatie - Steenwol LSW | 4.08256 | 1.48457 | 1.48457 | 50 | 0.0742283 | 0.0742283 | 3930 | 50 | 0.1965
Gipsplaat | 01 eerste verdieping | Gipsplaat | 5.98201 | 0.604721 | 0.604721 | 12.5 | 0.00747751 | 0.00747751 | 640 | 12.5 | 0.008
Gipsplaat | 01 eerste verdieping | Gipsplaat | 6.1268 | 0.612722 | 0.612722 | 12.5 | 0.0076585 | 0.0076585 | 640 | 12.5 | 0.008
Isolatie - Steenwol LSW | 01 eerste verdieping | Isolatie - Steenwol LSW | 1.70687 | 0.620848 | 0.620848 | 50 | 0.031034 | 0.031034 | 640 | 50 | 0.032
Membraan - waterdicht | 02 dak | Membraan - waterdicht | 2222.06 | 352.711 | 352.711 | 6 | 2.11625 | 2.11625
Isolatie - Kunststof hard | 02 dak | Isolatie - Kunststof hard | 7054.1 | 352.786 | 352.786 | 200 | 70.541 | 70.541
Membraan - waterdicht | 02 dak | Membraan - waterdicht | 22.8239 |  |  |  | 0.0217371 | 0.0259509 |  |  | 0.00283954
Membraan - waterdicht | 02 dak | Membraan - waterdicht | 30.8726 |  |  |  | 0.0294025 | 0.0294025 |  |  | 0.00232811
Hout - Multiplex | 02 dak | Hout - Multiplex | 63.2043 |  |  |  | 0.0902919 | 0.0902919 |  |  | 0.00713866
Isolatie - Kunststof hard | 02 dak | Isolatie - Kunststof hard | 128.224 |  |  |  | 1.28224 | 1.28224 |  |  | 0.102766
ALG - ISOLATIE | 02 dak | ALG - ISOLATIE | 20.6218 |  |  |  | 0.458263 | 0.458263 | 260 | 140 | 0.0364
Steen - Baksteen Hoofd | 02 dak | Steen - Baksteen Hoofd | 1487.19 |  |  |  | 0.929494 | 0.929494 | 720 | 100 | 0.072
Metaal - Aluminium | 02 dak | Metaal - Aluminium | 6.12374 |  |  |  | 0.00218705 | 0.00218705 |  |  | 0.000168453
Metaal - Aluminium | 02 dak | Metaal - Aluminium | 10.5782 |  |  |  | 0.00377793 | 0.00377793 |  |  | 0.000168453
Steen - Baksteen Hoofd | 02 dak | Steen - Baksteen Hoofd | 2579.1 |  |  |  | 1.61194 | 1.61194 | 720 | 100 | 0.072
ALG - ISOLATIE | 02 dak | ALG - ISOLATIE | 36.1474 |  |  |  | 0.803275 | 0.803275 | 260 | 140 | 0.0364
Isolatie - Kunststof hard | 02 dak | Isolatie - Kunststof hard | 225.63 |  |  |  | 2.2563 | 2.2563 |  |  | 0.102766
Hout - Multiplex | 02 dak | Hout - Multiplex | 110.574 |  |  |  | 0.157962 | 0.157962 |  |  | 0.00713866
Membraan - waterdicht | 02 dak | Membraan - waterdicht | 54.0449 |  |  |  | 0.0514713 | 0.0514713 |  |  | 0.00232811
Membraan - waterdicht | 02 dak | Membraan - waterdicht | 26.0009 |  |  |  | 0.0247628 | 0.0460406 |  |  | 0.00283954
Steen - Baksteen Hoofd | 02 dak | Steen - Baksteen Hoofd | 3541.08 | 22.1317 | 22.1317 | 100 | 2.21317 | 2.21317 | 1190 | 100 | 0.119
ALG - ISOLATIE | 02 dak | ALG - ISOLATIE | 149.993 | 24.8059 | 24.8059 | 140 | 3.33318 | 3.33318 | 1190 | 140 | 0.1666
Membraan - waterdicht | 02 dak | Membraan - waterdicht | 12.9619 |  |  |  | 0.0123446 | 0.0261907 |  |  | 0.00291454
Membraan - waterdicht | 02 dak | Membraan - waterdicht | 35.837 |  |  |  | 0.0341304 | 0.0341304 |  |  | 0.00232811
Hout - Multiplex | 02 dak | Hout - Multiplex | 72.9216 |  |  |  | 0.104174 | 0.104174 |  |  | 0.00713866
Isolatie - Kunststof hard | 02 dak | Isolatie - Kunststof hard | 153.294 |  |  |  | 1.53294 | 1.53294 |  |  | 0.105516
ALG - ISOLATIE | 02 dak | ALG - ISOLATIE | 23.9607 |  |  |  | 0.532459 | 0.532459 | 260 | 140 | 0.0364
Steen - Baksteen Hoofd | 02 dak | Steen - Baksteen Hoofd | 1735.5 |  |  |  | 1.08469 | 1.08469 | 732.5 | 100 | 0.07325
Metaal - Aluminium | 02 dak | Metaal - Aluminium | 7.00781 |  |  |  | 0.00250279 | 0.00250279 |  |  | 0.000168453
Metaal - Aluminium | 02 dak | Metaal - Aluminium | 53.0059 | 18.9191 | 20.9748 | 1 | 0.0189307 | 0.0209806 | 2407.09 | 1 | 0.00240709
Isolatie - Kunststof hard | 02 dak | Isolatie - Kunststof hard | 191.31 | 19.5214 | 21.5772 | 98 | 1.9131 | 2.11456 | 2407.09 | 98 | 0.235895
Metaal - Aluminium | 02 dak | Metaal - Aluminium | 54.6734 | 19.5262 | 21.582 | 1 | 0.0195262 | 0.021582 | 2407.09 | 1 | 0.00240709
2 x Metaal - Aluminium | 02 dak | Metaal - Aluminium | 49.1268 | 17.5453 | 17.5453 | 1 | 0.0175453 | 0.0175453 | 2407.09 | 1 | 0.00240709
Isolatie - Kunststof hard | 02 dak | Isolatie - Kunststof hard | 169.608 | 17.307 | 17.307 | 98 | 1.69608 | 1.69608 | 2407.09 | 98 | 0.235895
Metaal - Aluminium | 02 dak | Metaal - Aluminium | 47.1718 | 16.9475 | 16.9475 | 1 | 0.0168471 | 0.0168471 | 2407.09 | 1 | 0.00240709
Isolatie - Kunststof hard | 02 dak | Isolatie - Kunststof hard | 169.632 | 17.3094 | 17.3094 | 98 | 1.69632 | 1.69632 | 2407.09 | 98 | 0.235895
Metaal - Aluminium | 02 dak | Metaal - Aluminium | 48.1122 | 17.1858 | 17.1858 | 1 | 0.0171829 | 0.0171829 | 2407.09 | 1 | 0.00240709
Metaal - Aluminium | 02 dak | Metaal - Aluminium | 59.7129 | 21.326 | 21.326 | 1 | 0.021326 | 0.021326 | 2407.09 | 1 | 0.00240709
Isolatie - Kunststof hard | 02 dak | Isolatie - Kunststof hard | 206.683 | 21.0901 | 21.0901 | 98 | 2.06683 | 2.06683 | 2407.09 | 98 | 0.235895
Metaal - Aluminium | 02 dak | Metaal - Aluminium | 58.6284 | 21.0877 | 21.0877 | 1 | 0.0209387 | 0.0209387 | 2407.09 | 1 | 0.00240709
Metaal - Aluminium | 02 dak | Metaal - Aluminium | 10.259 |  |  |  | 0.00366392 | 0.00366392 |  |  | 0.000168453
Steen - Baksteen Hoofd | 02 dak | Steen - Baksteen Hoofd | 2554.72 |  |  |  | 1.5967 | 1.5967 | 732.5 | 100 | 0.07325
ALG - ISOLATIE | 02 dak | ALG - ISOLATIE | 35.2421 |  |  |  | 0.783158 | 0.783158 | 260 | 140 | 0.0364
Isolatie - Kunststof hard | 02 dak | Isolatie - Kunststof hard | 226.785 |  |  |  | 2.26785 | 2.26785 |  |  | 0.105516
Hout - Multiplex | 02 dak | Hout - Multiplex | 108.464 |  |  |  | 0.154949 | 0.154949 |  |  | 0.00713866
Membraan - waterdicht | 02 dak | Membraan - waterdicht | 52.6366 |  |  |  | 0.0501301 | 0.0501301 |  |  | 0.00232811
Membraan - waterdicht | 02 dak | Membraan - waterdicht | 36.6327 |  |  |  | 0.0348883 | 0.0421529 |  |  | 0.00291454
Metaal - Aluminium | 02 dak | Metaal - Aluminium | 11.3919 |  |  |  | 0.00406852 | 0.00406852 |  |  | 0.000168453
Steen - Baksteen Hoofd | 02 dak | Steen - Baksteen Hoofd | 2828.95 |  |  |  | 1.76809 | 1.76809 | 732.5 | 100 | 0.07325
ALG - ISOLATIE | 02 dak | ALG - ISOLATIE | 39.2429 |  |  |  | 0.872064 | 0.872064 | 260 | 140 | 0.0364
Isolatie - Kunststof hard | 02 dak | Isolatie - Kunststof hard | 251.738 |  |  |  | 2.51738 | 2.51738 |  |  | 0.105516
Hout - Multiplex | 02 dak | Hout - Multiplex | 119.543 |  |  |  | 0.170776 | 0.170776 |  |  | 0.00713866
Membraan - waterdicht | 02 dak | Membraan - waterdicht | 58.6438 |  |  |  | 0.0558512 | 0.0558512 |  |  | 0.00232811
Membraan - waterdicht | 02 dak | Membraan - waterdicht | 21.9693 |  |  |  | 0.0209231 | 0.0433656 |  |  | 0.00291454
Membraan - waterdicht | 02 dak | Membraan - waterdicht | 36.2528 |  |  |  | 0.0345265 | 0.0345265 |  |  | 0.00291454
Membraan - waterdicht | 02 dak | Membraan - waterdicht | 49.8218 |  |  |  | 0.0474494 | 0.0474494 |  |  | 0.00232811
Hout - Multiplex | 02 dak | Hout - Multiplex | 102.37 |  |  |  | 0.146243 | 0.146243 |  |  | 0.00713866
Isolatie - Kunststof hard | 02 dak | Isolatie - Kunststof hard | 183.28 |  |  |  | 1.8328 | 1.8328 |  |  | 0.105516
ALG - ISOLATIE | 02 dak | ALG - ISOLATIE | 33.3965 |  |  |  | 0.742144 | 0.742144 | 260 | 140 | 0.0364
Steen - Baksteen Hoofd | 02 dak | Steen - Baksteen Hoofd | 2395.22 |  |  |  | 1.49702 | 1.49702 | 732.5 | 100 | 0.07325
Metaal - Aluminium | 02 dak | Metaal - Aluminium | 9.58904 |  |  |  | 0.00342466 | 0.00342466 |  |  | 0.000168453
Metaal - Aluminium | 02 dak | Metaal - Aluminium | 4.08657 |  |  |  | 0.00145949 | 0.00145949 |  |  | 0.000168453
Steen - Baksteen Hoofd | 02 dak | Steen - Baksteen Hoofd | 1008.98 |  |  |  | 0.63061 | 0.63061 | 732.5 | 100 | 0.07325
ALG - ISOLATIE | 02 dak | ALG - ISOLATIE | 13.7786 |  |  |  | 0.306192 | 0.306192 | 260 | 140 | 0.0364
Isolatie - Kunststof hard | 02 dak | Isolatie - Kunststof hard | 71.4315 |  |  |  | 0.714315 | 0.714315 |  |  | 0.105516
Hout - Multiplex | 02 dak | Hout - Multiplex | 42.1657 |  |  |  | 0.0602367 | 0.0602367 |  |  | 0.00713866
Membraan - waterdicht | 02 dak | Membraan - waterdicht | 20.8587 |  |  |  | 0.0198655 | 0.0198655 |  |  | 0.00232811
Membraan - waterdicht | 02 dak | Membraan - waterdicht | 15.0076 |  |  |  | 0.0142929 | 0.0142929 |  |  | 0.00291454
Membraan - waterdicht | 02 dak | Membraan - waterdicht | 6.26399 |  |  |  | 0.0059657 | 0.0059657 |  |  | 0.00283954
Membraan - waterdicht | 02 dak | Membraan - waterdicht | 7.48957 |  |  |  | 0.00713292 | 0.00713292 |  |  | 0.00232811
Hout - Multiplex | 02 dak | Hout - Multiplex | 15.7328 |  |  |  | 0.0224754 | 0.0224754 |  |  | 0.00713866
Isolatie - Kunststof hard | 02 dak | Isolatie - Kunststof hard | 31.2644 |  |  |  | 0.312644 | 0.312644 |  |  | 0.102766
ALG - ISOLATIE | 02 dak | ALG - ISOLATIE | 5.00349 |  |  |  | 0.111189 | 0.111189 | 260 | 140 | 0.0364
Steen - Baksteen Hoofd | 02 dak | Steen - Baksteen Hoofd | 368.022 |  |  |  | 0.230014 | 0.230014 | 720 | 100 | 0.072
Metaal - Aluminium | 02 dak | Metaal - Aluminium | 1.50962 |  |  |  | 0.000539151 | 0.000539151 |  |  | 0.000168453
Membraan - waterdicht | 02 dak | Membraan - waterdicht | 20.9977 |  |  |  | 0.0199978 | 0.0199978 |  |  | 0.00283954
Membraan - waterdicht | 02 dak | Membraan - waterdicht | 23.6715 |  |  |  | 0.0225443 | 0.0225443 |  |  | 0.00232811
Hout - Multiplex | 02 dak | Hout - Multiplex | 48.8108 |  |  |  | 0.0697298 | 0.0697298 |  |  | 0.00713866
Isolatie - Kunststof hard | 02 dak | Isolatie - Kunststof hard | 99.2993 |  |  |  | 0.992993 | 0.992993 |  |  | 0.102766
ALG - ISOLATIE | 02 dak | ALG - ISOLATIE | 15.8476 |  |  |  | 0.35217 | 0.35217 | 260 | 140 | 0.0364
Steen - Baksteen Hoofd | 02 dak | Steen - Baksteen Hoofd | 1130.69 |  |  |  | 0.70668 | 0.70668 | 720 | 100 | 0.072
Metaal - Aluminium | 02 dak | Metaal - Aluminium | 4.61964 |  |  |  | 0.00164987 | 0.00164987 |  |  | 0.000168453
Membraan - waterdicht | 02 dak | Membraan - waterdicht | 25.9938 |  |  |  | 0.024756 | 0.046028 |  |  | 0.00283954
Membraan - waterdicht | 02 dak | Membraan - waterdicht | 53.7592 |  |  |  | 0.0511992 | 0.0511992 |  |  | 0.00232811
Hout - Multiplex | 02 dak | Hout - Multiplex | 109.225 |  |  |  | 0.156035 | 0.156035 |  |  | 0.00713866
Isolatie - Kunststof hard | 02 dak | Isolatie - Kunststof hard | 223.29 |  |  |  | 2.2329 | 2.2329 |  |  | 0.102766
ALG - ISOLATIE | 02 dak | ALG - ISOLATIE | 35.9181 |  |  |  | 0.798179 | 0.798179 | 260 | 140 | 0.0364
Steen - Baksteen Hoofd | 02 dak | Steen - Baksteen Hoofd | 2567.58 |  |  |  | 1.60474 | 1.60474 | 720 | 100 | 0.072
Metaal - Aluminium | 02 dak | Metaal - Aluminium | 10.5719 |  |  |  | 0.00377569 | 0.00377569 |  |  | 0.000168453
ALG - ISOLATIE | 02 dak | ALG - ISOLATIE | 3.4343 | 0.545127 | 0.545127 | 140 | 0.0763178 | 0.0763178 | 984 | 140 | 0.13776
Steen - Baksteen Hoofd | 02 dak | Steen - Baksteen Hoofd | 124.003 | 0.775021 | 0.775021 | 100 | 0.0775021 | 0.0775021 | 984 | 100 | 0.0984
Steen - Baksteen Hoofd | 02 dak | Steen - Baksteen Hoofd | 1158.28 | 7.23926 | 7.23926 | 100 | 0.723926 | 0.723926 | 890 | 100 | 0.089
ALG - ISOLATIE | 02 dak | ALG - ISOLATIE | 45.6037 | 7.23926 | 7.23926 | 140 | 1.01341 | 1.01341 | 890 | 140 | 0.1246
ALG - ISOLATIE | 02 dak | ALG - ISOLATIE | 11.9084 | 1.89022 | 1.89022 | 140 | 0.26463 | 0.26463 | 648.525 | 140 | 0.0907935
Steen - Baksteen Hoofd | 02 dak | Steen - Baksteen Hoofd | 321.112 | 2.00695 | 2.00695 | 100 | 0.200695 | 0.200695 | 648.525 | 100 | 0.0648525
2 x Grind | 02 dak | Grind | 7187.23 | 133.107 | 133.107 | 30 | 3.99291 | 3.99291
2 x Membraan - waterdicht | 02 dak | Membraan - waterdicht | 838.51 | 133.099 | 133.099 | 6 | 0.798581 | 0.798581
2 x Isolatie - Kunststof hard | 02 dak | Isolatie - Kunststof hard | 1730.26 | 133.142 | 133.142 | 130 | 17.3026 | 17.3026
Grind | 02 dak | Grind | 16592 | 307.276 | 307.276 | 30 | 9.21778 | 9.21778
Membraan - waterdicht | 02 dak | Membraan - waterdicht | 1935.73 | 307.263 | 307.263 | 6 | 1.84356 | 1.84356
Isolatie - Kunststof hard | 02 dak | Isolatie - Kunststof hard | 3994.37 | 307.333 | 307.333 | 130 | 39.9437 | 39.9437
Grind | 02 dak | Grind | 17964.4 | 332.698 | 395.799 | 30 | 9.98023 | 11.8734
Membraan - waterdicht | 02 dak | Membraan - waterdicht | 2095.85 | 332.679 | 395.783 | 6 | 1.99605 | 2.37468
Isolatie - Kunststof hard | 02 dak | Isolatie - Kunststof hard | 4324.77 | 332.776 | 395.863 | 130 | 43.2477 | 51.4513
ALG - ISOLATIE | 02 dak | ALG - ISOLATIE | 87.6412 | 13.9113 | 13.9113 | 140 | 1.94758 | 1.94758 | 942.5 | 140 | 0.13195
Steen - Baksteen Hoofd | 02 dak | Steen - Baksteen Hoofd | 2246.92 | 14.0433 | 14.0433 | 100 | 1.40433 | 1.40433 | 942.5 | 100 | 0.09425

# IfcBuildingElementProxy: 11 x 478 x 20, __600x692 Rockfon Krios
In: 01 eerste verdieping
Material: Gipsplaat
Component Quantities - Gipsplaat, Mass: 0.0455247 kg; Gipsplaat, Component Volume (Net): 0.0000569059 m3; Gipsplaat, Component Volume (Gross): 0.0000569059 m3

# IfcBuildingElementProxy: 11 x 593 x 20, __600x649 Rockfon Krios
In: 01 eerste verdieping
Material: Gipsplaat
Component Quantities - Gipsplaat, Mass: 0.0566204 kg; Gipsplaat, Component Volume (Net): 0.0000707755 m3; Gipsplaat, Component Volume (Gross): 0.0000707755 m3

# IfcBuildingElementProxy: 141 x 498 x 20, __600x748 Rockfon Krios
In: 01 eerste verdieping
Material: Gipsplaat
Component Quantities - Gipsplaat, Mass: 1.0682 kg; Gipsplaat, Component Volume (Net): 0.00133525 m3; Gipsplaat, Component Volume (Gross): 0.00133525 m3

# IfcBuildingElementProxy: 141 x 535 x 20, __600x696 Rockfon Krios
In: 01 eerste verdieping
Material: Gipsplaat
Component Quantities - Gipsplaat, Mass: 1.14955 kg; Gipsplaat, Component Volume (Net): 0.00143693 m3; Gipsplaat, Component Volume (Gross): 0.00143693 m3

# IfcBuildingElementProxy: 141 x 585 x 20, __600x606 Rockfon Krios
In: 01 eerste verdieping
Material: Gipsplaat
Component Quantities - Gipsplaat, Mass: 1.25853 kg; Gipsplaat, Component Volume (Net): 0.00157316 m3; Gipsplaat, Component Volume (Gross): 0.00157316 m3

# IfcBuildingElementProxy: 141 x 600 x 20 (16)
In: 01 eerste verdieping
Material: Gipsplaat
Name
__600x606 Rockfon Krios | Component Quantities - Gipsplaat, Mass: 1.29052 kg; Gipsplaat, Component Volume (Net): 0.00161315 m3; Gipsplaat, Component Volume (Gross): 0.00161315 m3
__600x617 Rockfon Krios | Component Quantities - Gipsplaat, Mass: 1.29052 kg; Gipsplaat, Component Volume (Net): 0.00161315 m3; Gipsplaat, Component Volume (Gross): 0.00161315 m3
__600x645 Rockfon Krios
__600x664 Rockfon Krios | Component Quantities - Gipsplaat, Mass: 1.29053 kg; Gipsplaat, Component Volume (Net): 0.00161316 m3; Gipsplaat, Component Volume (Gross): 0.00161316 m3
__600x672 Rockfon Krios
__600x679 Rockfon Krios
__600x680 Rockfon Krios
__600x681 Rockfon Krios
__600x683 Rockfon Krios
2 x __600x691 Rockfon Krios
__600x643 Rockfon Krios | Component Quantities - Gipsplaat, Mass: 1.29147 kg; Gipsplaat, Component Volume (Net): 0.00161434 m3; Gipsplaat, Component Volume (Gross): 0.00161434 m3
__600x645 Rockfon Krios | Component Quantities - Gipsplaat, Mass: 1.29108 kg; Gipsplaat, Component Volume (Net): 0.00161385 m3; Gipsplaat, Component Volume (Gross): 0.00161385 m3
__600x675 Rockfon Krios | Component Quantities - Gipsplaat, Mass: 1.29851 kg; Gipsplaat, Component Volume (Net): 0.00162314 m3; Gipsplaat, Component Volume (Gross): 0.00162314 m3
__600x679 Rockfon Krios | Component Quantities - Gipsplaat, Mass: 1.29108 kg; Gipsplaat, Component Volume (Net): 0.00161385 m3; Gipsplaat, Component Volume (Gross): 0.00161385 m3
__600x683 Rockfon Krios | Component Quantities - Gipsplaat, Mass: 1.29471 kg; Gipsplaat, Component Volume (Net): 0.00161839 m3; Gipsplaat, Component Volume (Gross): 0.00161839 m3

# IfcBuildingElementProxy: 142 x 600 x 20 (3)
In: 01 eerste verdieping
Material: Gipsplaat
Name | Gipsplaat, Mass (kg) | Gipsplaat, Component Volume (Net) (m3) = Gipsplaat, Component Volume (Gross) (m3)
__600x672 Rockfon Krios | 1.30611 | 0.00163264
__600x680 Rockfon Krios | 1.30991 | 0.00163739
__600x740 Rockfon Krios | 1.30231 | 0.00162789

# IfcBuildingElementProxy: 143 x 490 x 20, __600x748 Rockfon Krios
In: 01 eerste verdieping
Material: Gipsplaat
Component Quantities - Gipsplaat, Mass: 1.07366 kg; Gipsplaat, Component Volume (Net): 0.00134208 m3; Gipsplaat, Component Volume (Gross): 0.00134208 m3

# IfcBuildingElementProxy: 143 x 600 x 20, __600x694 Rockfon Krios
In: 01 eerste verdieping
Material: Gipsplaat
Component Quantities - Gipsplaat, Mass: 1.31372 kg; Gipsplaat, Component Volume (Net): 0.00164214 m3; Gipsplaat, Component Volume (Gross): 0.00164214 m3

# IfcBuildingElementProxy: 172 x 105 x 20, __600x757 Rockfon Krios
In: 00 begane grond
Material: Gipsplaat
Component Quantities - Gipsplaat, Mass: 4.94535 kg; Gipsplaat, Component Volume (Net): 0.00618169 m3; Gipsplaat, Component Volume (Gross): 0.00618169 m3

# IfcBuildingElementProxy: 197 x 61 x 20, __600x733 Rockfon Krios
In: 01 eerste verdieping
Material: Gipsplaat
Component Quantities - Gipsplaat, Mass: 5.35561 kg; Gipsplaat, Component Volume (Net): 0.00669451 m3; Gipsplaat, Component Volume (Gross): 0.00669451 m3

# IfcBuildingElementProxy: 20 (2)
In: 01 eerste verdieping
Material: Gipsplaat
Name | Gipsplaat, Mass (kg) | Gipsplaat, Component Volume (Net) (m3) = Gipsplaat, Component Volume (Gross) (m3)
__600x606 Rockfon Krios | 3.5574 | 0.00444674
__600x674 Rockfon Krios | 1.41448 | 0.0017681

# IfcBuildingElementProxy: 21 Sandwich custom pyramid 946 x 37 (60)
In: 00 begane grond
Classification: Generieke bekleding & afwerking buiten (ARCHICAD Classification); 41.12 BEKLEDINGEN (NL/SfB (4 cijfers))

# IfcBuildingElementProxy: 21 Sandwich custom pyramid HOEK 582 x 37, 41_Generieke bekleding & afwerking buiten_sandwich custom pyramid
In: 00 begane grond
Classification: Generieke bekleding & afwerking buiten (ARCHICAD Classification); 41.12 BEKLEDINGEN (NL/SfB (4 cijfers))

# IfcBuildingElementProxy: 224 x 461 x 20, __600x628 Rockfon Krios
In: 00 begane grond
Material: Gipsplaat
Component Quantities - Gipsplaat, Mass: 1.59867 kg; Gipsplaat, Component Volume (Net): 0.00199833 m3; Gipsplaat, Component Volume (Gross): 0.00199833 m3

# IfcBuildingElementProxy: 224 x 589 x 20, __600x685 Rockfon Krios
In: 00 begane grond
Material: Gipsplaat
Component Quantities - Gipsplaat, Mass: 2.09579 kg; Gipsplaat, Component Volume (Net): 0.00261974 m3; Gipsplaat, Component Volume (Gross): 0.00261974 m3

# IfcBuildingElementProxy: 224 x 600 x 20, __600x678 Rockfon Krios
In: 00 begane grond
Material: Gipsplaat
Component Quantities - Gipsplaat, Mass: 2.08476 kg; Gipsplaat, Component Volume (Net): 0.00260595 m3; Gipsplaat, Component Volume (Gross): 0.00260595 m3

# IfcBuildingElementProxy: 232 x 264 x 20, __600x754 Rockfon Krios
In: 00 begane grond
Material: Gipsplaat
Component Quantities - Gipsplaat, Mass: 0.941025 kg; Gipsplaat, Component Volume (Net): 0.00117628 m3; Gipsplaat, Component Volume (Gross): 0.00117628 m3

# IfcBuildingElementProxy: 232 x 36 x 20, __600x772 Rockfon Krios
In: 00 begane grond
Material: Gipsplaat
Component Quantities - Gipsplaat, Mass: 5.45278 kg; Gipsplaat, Component Volume (Net): 0.00681597 m3; Gipsplaat, Component Volume (Gross): 0.00681597 m3

# IfcBuildingElementProxy: 232 x 600 x 20 (5)
In: 00 begane grond
Material: Gipsplaat
Name
__600x608 Rockfon Krios | Component Quantities - Gipsplaat, Mass: 2.16533 kg; Gipsplaat, Component Volume (Net): 0.00270666 m3; Gipsplaat, Component Volume (Gross): 0.00270666 m3
__600x638 Rockfon Krios
__600x640 Rockfon Krios
__600x746 Rockfon Krios
__600x765 Rockfon Krios

# IfcBuildingElementProxy: 25 x 525 x 20, __600x606 Rockfon Krios
In: 00 begane grond
Material: Gipsplaat
Component Quantities - Gipsplaat, Mass: 0.166383 kg; Gipsplaat, Component Volume (Net): 0.000207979 m3; Gipsplaat, Component Volume (Gross): 0.000207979 m3

# IfcBuildingElementProxy: 25 x 564 x 20, __600x608 Rockfon Krios
In: 00 begane grond
Material: Gipsplaat
Component Quantities - Gipsplaat, Mass: 0.178864 kg; Gipsplaat, Component Volume (Net): 0.00022358 m3; Gipsplaat, Component Volume (Gross): 0.00022358 m3

# IfcBuildingElementProxy: 25 x 600 x 20 (10)
In: 00 begane grond
Material: Gipsplaat
Name
__600x708 Rockfon Krios | Component Quantities - Gipsplaat, Mass: 0.190401 kg; Gipsplaat, Component Volume (Net): 0.000238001 m3; Gipsplaat, Component Volume (Gross): 0.000238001 m3
__600x710 Rockfon Krios
__600x711 Rockfon Krios
__600x712 Rockfon Krios
__600x713 Rockfon Krios
__600x714 Rockfon Krios
__600x715 Rockfon Krios
__600x717 Rockfon Krios
__600x718 Rockfon Krios
__600x719 Rockfon Krios

# IfcBuildingElementProxy: 259 x 600 x 20, __600x600 Rockfon Krios
In: 00 begane grond
Material: Gipsplaat
Component Quantities - Gipsplaat, Mass: 3.17516 kg; Gipsplaat, Component Volume (Net): 0.00396895 m3; Gipsplaat, Component Volume (Gross): 0.00396895 m3

# IfcBuildingElementProxy: 263 x 461 x 20, __600x704 Rockfon Krios
In: 00 begane grond
Material: Gipsplaat
Component Quantities - Gipsplaat, Mass: 1.87985 kg; Gipsplaat, Component Volume (Net): 0.00234981 m3; Gipsplaat, Component Volume (Gross): 0.00234981 m3

# IfcBuildingElementProxy: 263 x 506 x 20, __600x774 Rockfon Krios
In: 00 begane grond
Material: Gipsplaat
Component Quantities - Gipsplaat, Mass: 2.06512 kg; Gipsplaat, Component Volume (Net): 0.0025814 m3; Gipsplaat, Component Volume (Gross): 0.0025814 m3

# IfcBuildingElementProxy: 263 x 600 x 20 (9)
In: 00 begane grond
Material: Gipsplaat
Name
__600x653 Rockfon Krios | Component Quantities - Gipsplaat, Mass: 2.45144 kg; Gipsplaat, Component Volume (Net): 0.0030643 m3; Gipsplaat, Component Volume (Gross): 0.0030643 m3
__600x698 Rockfon Krios
__600x766 Rockfon Krios
__600x768 Rockfon Krios
__600x771 Rockfon Krios
__600x772 Rockfon Krios | Component Quantities - Gipsplaat, Mass: 2.45144 kg; Gipsplaat, Component Volume (Net): 0.0030643 m3; Gipsplaat, Component Volume (Gross): 0.0030643 m3
__600x693 Rockfon Krios
__600x769 Rockfon Krios
__600x690 Rockfon Krios

# IfcBuildingElementProxy: 285 x 110 x 20, __600x659 Rockfon Krios
In: 01 eerste verdieping
Material: Gipsplaat
Component Quantities - Gipsplaat, Mass: 5.08158 kg; Gipsplaat, Component Volume (Net): 0.00635197 m3; Gipsplaat, Component Volume (Gross): 0.00635197 m3

# IfcBuildingElementProxy: 295 x 600 x 20, __600x641 Rockfon Krios
In: 01 eerste verdieping
Material: Gipsplaat
Component Quantities - Gipsplaat, Mass: 3.82273 kg; Gipsplaat, Component Volume (Net): 0.00477841 m3; Gipsplaat, Component Volume (Gross): 0.00477841 m3

# IfcBuildingElementProxy: 300 x 264 x 20, __600x628 Rockfon Krios
In: 00 begane grond
Material: Gipsplaat
Component Quantities - Gipsplaat, Mass: 1.22029 kg; Gipsplaat, Component Volume (Net): 0.00152536 m3; Gipsplaat, Component Volume (Gross): 0.00152536 m3

# IfcBuildingElementProxy: 300 x 410 x 20, __600x735 Rockfon Krios
In: 00 begane grond
Material: Gipsplaat
Component Quantities - Gipsplaat, Mass: 1.90507 kg; Gipsplaat, Component Volume (Net): 0.00238133 m3; Gipsplaat, Component Volume (Gross): 0.00238133 m3

# IfcBuildingElementProxy: 300 x 593 x 20, __600x705 Rockfon Krios
In: 01 eerste verdieping
Material: Gipsplaat
Component Quantities - Gipsplaat, Mass: 3.52919 kg; Gipsplaat, Component Volume (Net): 0.00441149 m3; Gipsplaat, Component Volume (Gross): 0.00441149 m3

# IfcBuildingElementProxy: 300 x 600 x 20 (16)
In: 00 begane grond
Material: Gipsplaat
Name
__600x609 Rockfon Krios | Component Quantities - Gipsplaat, Mass: 2.80793 kg; Gipsplaat, Component Volume (Net): 0.00350991 m3; Gipsplaat, Component Volume (Gross): 0.00350991 m3
__600x613 Rockfon Krios
__600x624 Rockfon Krios | Component Quantities - Gipsplaat, Mass: 2.80793 kg; Gipsplaat, Component Volume (Net): 0.00350991 m3; Gipsplaat, Component Volume (Gross): 0.00350991 m3
__600x629 Rockfon Krios
__600x632 Rockfon Krios
__600x633 Rockfon Krios
__600x635 Rockfon Krios
__600x636 Rockfon Krios
__600x637 Rockfon Krios
__600x646 Rockfon Krios
__600x652 Rockfon Krios
__600x659 Rockfon Krios
__600x660 Rockfon Krios
__600x719 Rockfon Krios
__600x760 Rockfon Krios
__600x762 Rockfon Krios

# IfcBuildingElementProxy: 311 x 600 x 20, __600x613 Rockfon Krios
In: 00 begane grond
Material: Gipsplaat
Component Quantities - Gipsplaat, Mass: 3.61027 kg; Gipsplaat, Component Volume (Net): 0.00451283 m3; Gipsplaat, Component Volume (Gross): 0.00451283 m3

# IfcBuildingElementProxy: 330 x 538 x 20, __600x620 Rockfon Krios
In: 00 begane grond
Material: Gipsplaat
Component Quantities - Gipsplaat, Mass: 2.77357 kg; Gipsplaat, Component Volume (Net): 0.00346696 m3; Gipsplaat, Component Volume (Gross): 0.00346696 m3

# IfcBuildingElementProxy: 330 x 600 x 20 (11)
In: 00 begane grond
Material: Gipsplaat
Name
__600x618 Rockfon Krios | Component Quantities - Gipsplaat, Mass: 3.09857 kg; Gipsplaat, Component Volume (Net): 0.00387322 m3; Gipsplaat, Component Volume (Gross): 0.00387322 m3
__600x623 Rockfon Krios
__600x641 Rockfon Krios
__600x645 Rockfon Krios
__600x655 Rockfon Krios
__600x657 Rockfon Krios
__600x662 Rockfon Krios | Component Quantities - Gipsplaat, Mass: 3.0189 kg; Gipsplaat, Component Volume (Net): 0.00377363 m3; Gipsplaat, Component Volume (Gross): 0.00377363 m3
__600x687 Rockfon Krios
__600x735 Rockfon Krios
__600x744 Rockfon Krios
__600x753 Rockfon Krios

# IfcBuildingElementProxy: 334 x 209 x 20, __600x609 Rockfon Krios
In: 00 begane grond
Material: Gipsplaat
Component Quantities - Gipsplaat, Mass: 2.69196 kg; Gipsplaat, Component Volume (Net): 0.00336495 m3; Gipsplaat, Component Volume (Gross): 0.00336495 m3

# IfcBuildingElementProxy: 334 x 506 x 20, __600x770 Rockfon Krios
In: 00 begane grond
Material: Gipsplaat
Component Quantities - Gipsplaat, Mass: 2.6384 kg; Gipsplaat, Component Volume (Net): 0.00329799 m3; Gipsplaat, Component Volume (Gross): 0.00329799 m3

# IfcBuildingElementProxy: 334 x 600 x 20 (6)
In: 00 begane grond
Material: Gipsplaat
Name
__600x627 Rockfon Krios | Component Quantities - Gipsplaat, Mass: 3.13196 kg; Gipsplaat, Component Volume (Net): 0.00391495 m3; Gipsplaat, Component Volume (Gross): 0.00391495 m3
__600x669 Rockfon Krios | Component Quantities - Gipsplaat, Mass: 3.13196 kg; Gipsplaat, Component Volume (Net): 0.00391495 m3; Gipsplaat, Component Volume (Gross): 0.00391495 m3
__600x684 Rockfon Krios
__600x686 Rockfon Krios
__600x754 Rockfon Krios
__600x763 Rockfon Krios

# IfcBuildingElementProxy: 343 x 400 x 20, __600x711 Rockfon Krios
In: 01 eerste verdieping
Material: Gipsplaat
Component Quantities - Gipsplaat, Mass: 2.13346 kg; Gipsplaat, Component Volume (Net): 0.00266682 m3; Gipsplaat, Component Volume (Gross): 0.00266682 m3

# IfcBuildingElementProxy: 343 x 410 x 20, __600x764 Rockfon Krios
In: 00 begane grond
Material: Gipsplaat
Component Quantities - Gipsplaat, Mass: 2.18859 kg; Gipsplaat, Component Volume (Net): 0.00273574 m3; Gipsplaat, Component Volume (Gross): 0.00273574 m3

# IfcBuildingElementProxy: 343 x 564 x 20, __600x753 Rockfon Krios
In: 00 begane grond
Material: Gipsplaat
Component Quantities - Gipsplaat, Mass: 3.01912 kg; Gipsplaat, Component Volume (Net): 0.00377391 m3; Gipsplaat, Component Volume (Gross): 0.00377391 m3

# IfcBuildingElementProxy: 343 x 593 x 20, __600x694 Rockfon Krios
In: 01 eerste verdieping
Material: Gipsplaat
Component Quantities - Gipsplaat, Mass: 3.17323 kg; Gipsplaat, Component Volume (Net): 0.00396653 m3; Gipsplaat, Component Volume (Gross): 0.00396653 m3

# IfcBuildingElementProxy: 343 x 600 x 20 (34)
Material: Gipsplaat
Name | In
__600x606 Rockfon Krios | 00 begane grond | Component Quantities - Gipsplaat, Mass: 3.21347 kg; Gipsplaat, Component Volume (Net): 0.00401684 m3; Gipsplaat, Component Volume (Gross): 0.00401684 m3
__600x617 Rockfon Krios | 00 begane grond
__600x620 Rockfon Krios | 00 begane grond
__600x627 Rockfon Krios | 00 begane grond
__600x744 Rockfon Krios | 00 begane grond
__600x745 Rockfon Krios | 00 begane grond
__600x747 Rockfon Krios | 00 begane grond
__600x761 Rockfon Krios | 00 begane grond
__600x768 Rockfon Krios | 00 begane grond
__600x777 Rockfon Krios | 00 begane grond
__600x600 Rockfon Krios | 01 eerste verdieping | Component Quantities - Gipsplaat, Mass: 3.21369 kg; Gipsplaat, Component Volume (Net): 0.00401711 m3; Gipsplaat, Component Volume (Gross): 0.00401711 m3
__600x601 Rockfon Krios | 01 eerste verdieping
__600x606 Rockfon Krios | 01 eerste verdieping | Component Quantities - Gipsplaat, Mass: 3.21369 kg; Gipsplaat, Component Volume (Net): 0.00401711 m3; Gipsplaat, Component Volume (Gross): 0.00401711 m3
__600x612 Rockfon Krios | 01 eerste verdieping
__600x613 Rockfon Krios | 01 eerste verdieping
__600x614 Rockfon Krios | 01 eerste verdieping
__600x618 Rockfon Krios | 01 eerste verdieping
__600x622 Rockfon Krios | 01 eerste verdieping
__600x634 Rockfon Krios | 01 eerste verdieping
__600x636 Rockfon Krios | 01 eerste verdieping
__600x704 Rockfon Krios | 01 eerste verdieping
__600x715 Rockfon Krios | 01 eerste verdieping
__600x696 Rockfon Krios | 01 eerste verdieping
__600x697 Rockfon Krios | 01 eerste verdieping
__600x698 Rockfon Krios | 01 eerste verdieping
__600x707 Rockfon Krios | 01 eerste verdieping
__600x708 Rockfon Krios | 01 eerste verdieping
__600x713 Rockfon Krios | 01 eerste verdieping
__600x714 Rockfon Krios | 01 eerste verdieping
__600x727 Rockfon Krios | 01 eerste verdieping
__600x728 Rockfon Krios | 01 eerste verdieping
__600x733 Rockfon Krios | 01 eerste verdieping
__600x738 Rockfon Krios | 01 eerste verdieping
__600x746 Rockfon Krios | 01 eerste verdieping

# IfcBuildingElementProxy: 356 x 538 x 20, __600x671 Rockfon Krios
In: 00 begane grond
Material: Gipsplaat
Component Quantities - Gipsplaat, Mass: 2.98629 kg; Gipsplaat, Component Volume (Net): 0.00373287 m3; Gipsplaat, Component Volume (Gross): 0.00373287 m3

# IfcBuildingElementProxy: 356 x 600 x 20 (10)
In: 00 begane grond
Material: Gipsplaat
Name
__600x617 Rockfon Krios | Component Quantities - Gipsplaat, Mass: 3.33678 kg; Gipsplaat, Component Volume (Net): 0.00417098 m3; Gipsplaat, Component Volume (Gross): 0.00417098 m3
__600x620 Rockfon Krios
__600x629 Rockfon Krios | Component Quantities - Gipsplaat, Mass: 3.33678 kg; Gipsplaat, Component Volume (Net): 0.00417098 m3; Gipsplaat, Component Volume (Gross): 0.00417098 m3
__600x655 Rockfon Krios | Component Quantities - Gipsplaat, Mass: 3.33678 kg; Gipsplaat, Component Volume (Net): 0.00417098 m3; Gipsplaat, Component Volume (Gross): 0.00417098 m3
__600x657 Rockfon Krios
__600x659 Rockfon Krios
__600x661 Rockfon Krios
__600x687 Rockfon Krios
__600x725 Rockfon Krios
__600x761 Rockfon Krios

# IfcBuildingElementProxy: 362 x 525 x 20 (2)
In: 01 eerste verdieping
Material: Gipsplaat
Name | Gipsplaat, Mass (kg) | Gipsplaat, Component Volume (Net) (m3) = Gipsplaat, Component Volume (Gross) (m3)
__600x642 Rockfon Krios | 2.973 | 0.00371625
__600x620 Rockfon Krios | 2.97114 | 0.00371392

# IfcBuildingElementProxy: 362 x 543 x 20, __600x650 Rockfon Krios
In: 01 eerste verdieping
Material: Gipsplaat
Component Quantities - Gipsplaat, Mass: 3.07009 kg; Gipsplaat, Component Volume (Net): 0.00383761 m3; Gipsplaat, Component Volume (Gross): 0.00383761 m3

# IfcBuildingElementProxy: 362 x 553 x 20, __600x629 Rockfon Krios
In: 01 eerste verdieping
Material: Gipsplaat
Component Quantities - Gipsplaat, Mass: 3.13117 kg; Gipsplaat, Component Volume (Net): 0.00391397 m3; Gipsplaat, Component Volume (Gross): 0.00391397 m3

# IfcBuildingElementProxy: 362 x 600 x 20 (21)
In: 01 eerste verdieping
Material: Gipsplaat
Name
__600x632 Rockfon Krios | Component Quantities - Gipsplaat, Mass: 3.40073 kg; Gipsplaat, Component Volume (Net): 0.00425092 m3; Gipsplaat, Component Volume (Gross): 0.00425092 m3
__600x618 Rockfon Krios | Component Quantities - Gipsplaat, Mass: 3.40073 kg; Gipsplaat, Component Volume (Net): 0.00425092 m3; Gipsplaat, Component Volume (Gross): 0.00425092 m3
__600x623 Rockfon Krios
2 x __600x641 Rockfon Krios
__600x645 Rockfon Krios
__600x655 Rockfon Krios
__600x657 Rockfon Krios
__600x687 Rockfon Krios
__600x735 Rockfon Krios
__600x744 Rockfon Krios
__600x753 Rockfon Krios
__600x622 Rockfon Krios | Component Quantities - Gipsplaat, Mass: 3.3985 kg; Gipsplaat, Component Volume (Net): 0.00424813 m3; Gipsplaat, Component Volume (Gross): 0.00424813 m3
__600x623 Rockfon Krios | Component Quantities - Gipsplaat, Mass: 3.3985 kg; Gipsplaat, Component Volume (Net): 0.00424813 m3; Gipsplaat, Component Volume (Gross): 0.00424813 m3
__600x663 Rockfon Krios | Component Quantities - Gipsplaat, Mass: 3.3985 kg; Gipsplaat, Component Volume (Net): 0.00424813 m3; Gipsplaat, Component Volume (Gross): 0.00424813 m3
__600x667 Rockfon Krios
__600x675 Rockfon Krios
__600x676 Rockfon Krios
__600x689 Rockfon Krios
__600x694 Rockfon Krios
__600x722 Rockfon Krios

# IfcBuildingElementProxy: 371 x 543 x 20, __600x642 Rockfon Krios
In: 01 eerste verdieping
Material: Gipsplaat
Component Quantities - Gipsplaat, Mass: 3.14342 kg; Gipsplaat, Component Volume (Net): 0.00392928 m3; Gipsplaat, Component Volume (Gross): 0.00392928 m3

# IfcBuildingElementProxy: 371 x 600 x 20 (11)
In: 01 eerste verdieping
Material: Gipsplaat
Name
__600x600 Rockfon Krios | Component Quantities - Gipsplaat, Mass: 3.47967 kg; Gipsplaat, Component Volume (Net): 0.00434959 m3; Gipsplaat, Component Volume (Gross): 0.00434959 m3
__600x618 Rockfon Krios | Component Quantities - Gipsplaat, Mass: 3.47968 kg; Gipsplaat, Component Volume (Net): 0.0043496 m3; Gipsplaat, Component Volume (Gross): 0.0043496 m3
__600x625 Rockfon Krios | Component Quantities - Gipsplaat, Mass: 3.47966 kg; Gipsplaat, Component Volume (Net): 0.00434958 m3; Gipsplaat, Component Volume (Gross): 0.00434958 m3
__600x668 Rockfon Krios
__600x720 Rockfon Krios
__600x733 Rockfon Krios | Component Quantities - Gipsplaat, Mass: 3.47966 kg; Gipsplaat, Component Volume (Net): 0.00434957 m3; Gipsplaat, Component Volume (Gross): 0.00434957 m3
__600x737 Rockfon Krios
__600x745 Rockfon Krios
__600x750 Rockfon Krios
__600x752 Rockfon Krios
__600x754 Rockfon Krios

# IfcBuildingElementProxy: 375 x 525 x 20 (2)
In: 01 eerste verdieping
Material: Gipsplaat
Name | Gipsplaat, Mass (kg) | Gipsplaat, Component Volume (Net) (m3) = Gipsplaat, Component Volume (Gross) (m3)
__600x678 Rockfon Krios | 3.07626 | 0.00384532
__600x600 Rockfon Krios | 3.07511 | 0.00384388

# IfcBuildingElementProxy: 375 x 553 x 20, __600x635 Rockfon Krios
In: 01 eerste verdieping
Material: Gipsplaat
Component Quantities - Gipsplaat, Mass: 3.24074 kg; Gipsplaat, Component Volume (Net): 0.00405093 m3; Gipsplaat, Component Volume (Gross): 0.00405093 m3

# IfcBuildingElementProxy: 375 x 600 x 20 (15)
In: 01 eerste verdieping
Material: Gipsplaat
Name | Gipsplaat, Mass (kg) | Gipsplaat, Component Volume (Net) (m3) = Gipsplaat, Component Volume (Gross) (m3)
__600x626 Rockfon Krios | 3.51927 | 0.00439909
__600x667 Rockfon Krios | 3.51956 | 0.00439945
__600x676 Rockfon Krios | 3.51942 | 0.00439927
__600x697 Rockfon Krios | 3.51913 | 0.00439891
__600x736 Rockfon Krios | 3.51898 | 0.00439873
__600x606 Rockfon Krios | 3.51973 | 0.00439967
__600x617 Rockfon Krios | 3.51973 | 0.00439967
__600x621 Rockfon Krios
__600x631 Rockfon Krios
__600x652 Rockfon Krios | 3.51973 | 0.00439967
__600x653 Rockfon Krios
__600x659 Rockfon Krios
__600x670 Rockfon Krios
__600x671 Rockfon Krios
__600x717 Rockfon Krios

# IfcBuildingElementProxy: 387 x 525 x 20, __600x710 Rockfon Krios
In: 01 eerste verdieping
Material: Gipsplaat
Component Quantities - Gipsplaat, Mass: 3.18031 kg; Gipsplaat, Component Volume (Net): 0.00397538 m3; Gipsplaat, Component Volume (Gross): 0.00397538 m3

# IfcBuildingElementProxy: 387 x 600 x 20 (4)
In: 01 eerste verdieping
Material: Gipsplaat
Name | Gipsplaat, Mass (kg) | Gipsplaat, Component Volume (Net) (m3) = Gipsplaat, Component Volume (Gross) (m3)
__600x600 Rockfon Krios | 3.63803 | 0.00454754
__600x617 Rockfon Krios | 3.63822 | 0.00454777
__600x622 Rockfon Krios | 3.63858 | 0.00454823
__600x633 Rockfon Krios | 3.6384 | 0.004548

# IfcBuildingElementProxy: 394 x 105 x 20, __600x612 Rockfon Krios
In: 00 begane grond
Material: Gipsplaat
Component Quantities - Gipsplaat, Mass: 3.88693 kg; Gipsplaat, Component Volume (Net): 0.00485867 m3; Gipsplaat, Component Volume (Gross): 0.00485867 m3

# IfcBuildingElementProxy: 394 x 495 x 20, __600x635 Rockfon Krios
In: 00 begane grond
Material: Gipsplaat
Component Quantities - Gipsplaat, Mass: 3.0541 kg; Gipsplaat, Component Volume (Net): 0.00381762 m3; Gipsplaat, Component Volume (Gross): 0.00381762 m3

# IfcBuildingElementProxy: 394 x 538 x 20, __600x707 Rockfon Krios
In: 00 begane grond
Material: Gipsplaat
Component Quantities - Gipsplaat, Mass: 3.31894 kg; Gipsplaat, Component Volume (Net): 0.00414867 m3; Gipsplaat, Component Volume (Gross): 0.00414867 m3

# IfcBuildingElementProxy: 394 x 600 x 20 (10)
In: 00 begane grond
Material: Gipsplaat
Name
__600x606 Rockfon Krios | Component Quantities - Gipsplaat, Mass: 3.70785 kg; Gipsplaat, Component Volume (Net): 0.00463482 m3; Gipsplaat, Component Volume (Gross): 0.00463482 m3
__600x617 Rockfon Krios | Component Quantities - Gipsplaat, Mass: 3.70785 kg; Gipsplaat, Component Volume (Net): 0.00463482 m3; Gipsplaat, Component Volume (Gross): 0.00463482 m3
__600x621 Rockfon Krios
__600x631 Rockfon Krios
__600x652 Rockfon Krios
__600x653 Rockfon Krios
__600x659 Rockfon Krios
__600x670 Rockfon Krios
__600x671 Rockfon Krios | Component Quantities - Gipsplaat, Mass: 3.70785 kg; Gipsplaat, Component Volume (Net): 0.00463482 m3; Gipsplaat, Component Volume (Gross): 0.00463482 m3
__600x717 Rockfon Krios

# IfcBuildingElementProxy: 395 x 495 x 20, __600x612 Rockfon Krios
In: 00 begane grond
Material: Gipsplaat
Component Quantities - Gipsplaat, Mass: 3.05368 kg; Gipsplaat, Component Volume (Net): 0.0038171 m3; Gipsplaat, Component Volume (Gross): 0.0038171 m3

# IfcBuildingElementProxy: 395 x 538 x 20, __600x753 Rockfon Krios
In: 00 begane grond
Material: Gipsplaat
Component Quantities - Gipsplaat, Mass: 3.31856 kg; Gipsplaat, Component Volume (Net): 0.0041482 m3; Gipsplaat, Component Volume (Gross): 0.0041482 m3

# IfcBuildingElementProxy: 395 x 600 x 20 (10)
In: 00 begane grond
Material: Gipsplaat
Name
__600x621 Rockfon Krios | Component Quantities - Gipsplaat, Mass: 3.70804 kg; Gipsplaat, Component Volume (Net): 0.00463505 m3; Gipsplaat, Component Volume (Gross): 0.00463505 m3
__600x623 Rockfon Krios
__600x631 Rockfon Krios
__600x635 Rockfon Krios
__600x636 Rockfon Krios | Component Quantities - Gipsplaat, Mass: 3.70804 kg; Gipsplaat, Component Volume (Net): 0.00463505 m3; Gipsplaat, Component Volume (Gross): 0.00463505 m3
__600x652 Rockfon Krios
__600x670 Rockfon Krios
__600x675 Rockfon Krios | Component Quantities - Gipsplaat, Mass: 3.70804 kg; Gipsplaat, Component Volume (Net): 0.00463506 m3; Gipsplaat, Component Volume (Gross): 0.00463506 m3
__600x717 Rockfon Krios
__600x744 Rockfon Krios

# IfcBuildingElementProxy: 410 x 400 x 20, __600x605 Rockfon Krios
In: 01 eerste verdieping
Material: Gipsplaat
Component Quantities - Gipsplaat, Mass: 2.55914 kg; Gipsplaat, Component Volume (Net): 0.00319893 m3; Gipsplaat, Component Volume (Gross): 0.00319893 m3

# IfcBuildingElementProxy: 410 x 600 x 20 (16)
In: 01 eerste verdieping
Material: Gipsplaat
Name
__600x645 Rockfon Krios | Component Quantities - Gipsplaat, Mass: 3.85491 kg; Gipsplaat, Component Volume (Net): 0.00481864 m3; Gipsplaat, Component Volume (Gross): 0.00481864 m3
__600x648 Rockfon Krios | Component Quantities - Gipsplaat, Mass: 3.41491 kg; Gipsplaat, Component Volume (Net): 0.00426864 m3; Gipsplaat, Component Volume (Gross): 0.00426864 m3
__600x652 Rockfon Krios | Component Quantities - Gipsplaat, Mass: 3.85491 kg; Gipsplaat, Component Volume (Net): 0.00481864 m3; Gipsplaat, Component Volume (Gross): 0.00481864 m3
__600x671 Rockfon Krios
__600x674 Rockfon Krios
__600x677 Rockfon Krios | Component Quantities - Gipsplaat, Mass: 3.85491 kg; Gipsplaat, Component Volume (Net): 0.00481864 m3; Gipsplaat, Component Volume (Gross): 0.00481864 m3
__600x678 Rockfon Krios
__600x695 Rockfon Krios
__600x714 Rockfon Krios | Component Quantities - Gipsplaat, Mass: 3.7009 kg; Gipsplaat, Component Volume (Net): 0.00462612 m3; Gipsplaat, Component Volume (Gross): 0.00462612 m3
__600x745 Rockfon Krios
__600x755 Rockfon Krios
__600x600 Rockfon Krios
__600x601 Rockfon Krios | Component Quantities - Gipsplaat, Mass: 2.89932 kg; Gipsplaat, Component Volume (Net): 0.00362415 m3; Gipsplaat, Component Volume (Gross): 0.00362415 m3
__600x602 Rockfon Krios
__600x603 Rockfon Krios
__600x604 Rockfon Krios

# IfcBuildingElementProxy: 417 x 155 x 20, __600x690 Rockfon Krios
In: 00 begane grond
Material: Gipsplaat
Component Quantities - Gipsplaat, Mass: 0.989988 kg; Gipsplaat, Component Volume (Net): 0.00123748 m3; Gipsplaat, Component Volume (Gross): 0.00123748 m3

# IfcBuildingElementProxy: 417 x 538 x 20 (2)
In: 00 begane grond
Material: Gipsplaat
Component Quantities - Gipsplaat, Mass: 3.51451 kg
Name | Gipsplaat, Component Volume (Net) (m3) = Gipsplaat, Component Volume (Gross) (m3)
__600x600 Rockfon Krios | 0.00439314
__600x629 Rockfon Krios | 0.00439313

# IfcBuildingElementProxy: 417 x 600 x 20 (20)
In: 00 begane grond
Material: Gipsplaat
Name
__600x606 Rockfon Krios | Component Quantities - Gipsplaat, Mass: 3.92699 kg; Gipsplaat, Component Volume (Net): 0.00490874 m3; Gipsplaat, Component Volume (Gross): 0.00490874 m3
__600x618 Rockfon Krios | Component Quantities - Gipsplaat, Mass: 3.92699 kg; Gipsplaat, Component Volume (Net): 0.00490874 m3; Gipsplaat, Component Volume (Gross): 0.00490874 m3
__600x621 Rockfon Krios | Component Quantities - Gipsplaat, Mass: 3.92699 kg; Gipsplaat, Component Volume (Net): 0.00490874 m3; Gipsplaat, Component Volume (Gross): 0.00490874 m3
__600x623 Rockfon Krios
__600x631 Rockfon Krios
__600x635 Rockfon Krios
__600x641 Rockfon Krios
__600x645 Rockfon Krios
__600x652 Rockfon Krios
__600x653 Rockfon Krios
__600x655 Rockfon Krios
__600x657 Rockfon Krios
__600x659 Rockfon Krios
__600x670 Rockfon Krios
__600x671 Rockfon Krios
__600x687 Rockfon Krios
__600x717 Rockfon Krios
__600x735 Rockfon Krios
__600x744 Rockfon Krios
__600x753 Rockfon Krios

# IfcBuildingElementProxy: 426 x 525 x 20, __600x672 Rockfon Krios
In: 01 eerste verdieping
Material: Gipsplaat
Component Quantities - Gipsplaat, Mass: 3.50565 kg; Gipsplaat, Component Volume (Net): 0.00438206 m3; Gipsplaat, Component Volume (Gross): 0.00438206 m3

# IfcBuildingElementProxy: 426 x 600 x 20 (9)
In: 01 eerste verdieping
Material: Gipsplaat
Name
__600x602 Rockfon Krios | Component Quantities - Gipsplaat, Mass: 4.01001 kg; Gipsplaat, Component Volume (Net): 0.00501251 m3; Gipsplaat, Component Volume (Gross): 0.00501251 m3
__600x638 Rockfon Krios
__600x665 Rockfon Krios
__600x669 Rockfon Krios
__600x674 Rockfon Krios
__600x675 Rockfon Krios
__600x677 Rockfon Krios
__600x687 Rockfon Krios | Component Quantities - Gipsplaat, Mass: 3.47455 kg; Gipsplaat, Component Volume (Net): 0.00434319 m3; Gipsplaat, Component Volume (Gross): 0.00434319 m3
__600x690 Rockfon Krios | Component Quantities - Gipsplaat, Mass: 4.01001 kg; Gipsplaat, Component Volume (Net): 0.00501251 m3; Gipsplaat, Component Volume (Gross): 0.00501251 m3

# IfcBuildingElementProxy: 438 x 110 x 20, __600x682 Rockfon Krios
In: 01 eerste verdieping
Material: Gipsplaat
Component Quantities - Gipsplaat, Mass: 5.37882 kg; Gipsplaat, Component Volume (Net): 0.00672352 m3; Gipsplaat, Component Volume (Gross): 0.00672352 m3

# IfcBuildingElementProxy: 51 x 110 x 20, __600x689 Rockfon Krios
In: 01 eerste verdieping
Material: Gipsplaat
Component Quantities - Gipsplaat, Mass: 5.08158 kg; Gipsplaat, Component Volume (Net): 0.00635198 m3; Gipsplaat, Component Volume (Gross): 0.00635198 m3

# IfcBuildingElementProxy: 517 x 600 x 20, __600x665 Rockfon Krios
In: 01 eerste verdieping
Material: Gipsplaat
Component Quantities - Gipsplaat, Mass: 5.5176 kg; Gipsplaat, Component Volume (Net): 0.006897 m3; Gipsplaat, Component Volume (Gross): 0.006897 m3

# IfcBuildingElementProxy: 553 x 564 x 20, __600x630 Rockfon Krios
In: 00 begane grond
Material: Gipsplaat
Component Quantities - Gipsplaat, Mass: 4.93689 kg; Gipsplaat, Component Volume (Net): 0.00617111 m3; Gipsplaat, Component Volume (Gross): 0.00617111 m3

# IfcBuildingElementProxy: 558 x 525 x 20, __600x651 Rockfon Krios
In: 00 begane grond
Material: Gipsplaat
Component Quantities - Gipsplaat, Mass: 4.597 kg; Gipsplaat, Component Volume (Net): 0.00574625 m3; Gipsplaat, Component Volume (Gross): 0.00574625 m3

# IfcBuildingElementProxy: 558 x 600 x 20 (10)
In: 00 begane grond
Material: Gipsplaat
Name
__600x613 Rockfon Krios | Component Quantities - Gipsplaat, Mass: 5.26056 kg; Gipsplaat, Component Volume (Net): 0.0065757 m3; Gipsplaat, Component Volume (Gross): 0.0065757 m3
__600x622 Rockfon Krios | Component Quantities - Gipsplaat, Mass: 5.26056 kg; Gipsplaat, Component Volume (Net): 0.0065757 m3; Gipsplaat, Component Volume (Gross): 0.0065757 m3
__600x627 Rockfon Krios
__600x658 Rockfon Krios
__600x666 Rockfon Krios
__600x667 Rockfon Krios
__600x672 Rockfon Krios
__600x681 Rockfon Krios
__600x690 Rockfon Krios
__600x699 Rockfon Krios

# IfcBuildingElementProxy: 592 x 490 x 20, __600x692 Rockfon Krios
In: 01 eerste verdieping
Material: Gipsplaat
Component Quantities - Gipsplaat, Mass: 4.55837 kg; Gipsplaat, Component Volume (Net): 0.00569796 m3; Gipsplaat, Component Volume (Gross): 0.00569796 m3

# IfcBuildingElementProxy: 592 x 498 x 20, __600x608 Rockfon Krios
In: 01 eerste verdieping
Material: Gipsplaat
Component Quantities - Gipsplaat, Mass: 4.62885 kg; Gipsplaat, Component Volume (Net): 0.00578606 m3; Gipsplaat, Component Volume (Gross): 0.00578606 m3

# IfcBuildingElementProxy: 592 x 535 x 20, __600x689 Rockfon Krios
In: 01 eerste verdieping
Material: Gipsplaat
Component Quantities - Gipsplaat, Mass: 4.98129 kg; Gipsplaat, Component Volume (Net): 0.00622662 m3; Gipsplaat, Component Volume (Gross): 0.00622662 m3

# IfcBuildingElementProxy: 592 x 585 x 20, __600x665 Rockfon Krios
In: 01 eerste verdieping
Material: Gipsplaat
Component Quantities - Gipsplaat, Mass: 5.4512 kg; Gipsplaat, Component Volume (Net): 0.006814 m3; Gipsplaat, Component Volume (Gross): 0.006814 m3

# IfcBuildingElementProxy: 592 x 600 x 20 (20)
In: 01 eerste verdieping
Material: Gipsplaat
Name
__600x600 Rockfon Krios | Component Quantities - Gipsplaat, Mass: 5.59221 kg; Gipsplaat, Component Volume (Net): 0.00699026 m3; Gipsplaat, Component Volume (Gross): 0.00699026 m3
2 x __600x612 Rockfon Krios
__600x622 Rockfon Krios | Component Quantities - Gipsplaat, Mass: 5.59221 kg; Gipsplaat, Component Volume (Net): 0.00699026 m3; Gipsplaat, Component Volume (Gross): 0.00699026 m3
2 x __600x624 Rockfon Krios
__600x665 Rockfon Krios
2 x __600x676 Rockfon Krios
2 x __600x699 Rockfon Krios
2 x __600x705 Rockfon Krios
__600x707 Rockfon Krios
2 x __600x722 Rockfon Krios
__600x600 Rockfon Krios
__600x608 Rockfon Krios
__600x622 Rockfon Krios
__600x625 Rockfon Krios

# IfcBuildingElementProxy: 594 x 478 x 20, __600x697 Rockfon Krios
In: 01 eerste verdieping
Material: Gipsplaat
Component Quantities - Gipsplaat, Mass: 4.46207 kg; Gipsplaat, Component Volume (Net): 0.00557759 m3; Gipsplaat, Component Volume (Gross): 0.00557759 m3

# IfcBuildingElementProxy: 594 x 593 x 20, __600x665 Rockfon Krios
In: 01 eerste verdieping
Material: Gipsplaat
Component Quantities - Gipsplaat, Mass: 5.54962 kg; Gipsplaat, Component Volume (Net): 0.00693702 m3; Gipsplaat, Component Volume (Gross): 0.00693702 m3

# IfcBuildingElementProxy: 594 x 600 x 20 (8)
In: 01 eerste verdieping
Material: Gipsplaat
Name
__600x613 Rockfon Krios | Component Quantities - Gipsplaat, Mass: 5.61183 kg; Gipsplaat, Component Volume (Net): 0.00701479 m3; Gipsplaat, Component Volume (Gross): 0.00701479 m3
__600x641 Rockfon Krios | Component Quantities - Gipsplaat, Mass: 5.61183 kg; Gipsplaat, Component Volume (Net): 0.00701479 m3; Gipsplaat, Component Volume (Gross): 0.00701479 m3
__600x645 Rockfon Krios
__600x664 Rockfon Krios
__600x682 Rockfon Krios
__600x713 Rockfon Krios
__600x734 Rockfon Krios | Component Quantities - Gipsplaat, Mass: 5.61183 kg; Gipsplaat, Component Volume (Net): 0.00701479 m3; Gipsplaat, Component Volume (Gross): 0.00701479 m3
__600x748 Rockfon Krios

# IfcBuildingElementProxy: 600 x 155 x 20 (7)
In: 00 begane grond
Material: Gipsplaat
Name
__600x602 Rockfon Krios | Component Quantities - Gipsplaat, Mass: 1.42799 kg; Gipsplaat, Component Volume (Net): 0.00178498 m3; Gipsplaat, Component Volume (Gross): 0.00178498 m3
__600x620 Rockfon Krios
__600x627 Rockfon Krios
__600x636 Rockfon Krios
__600x646 Rockfon Krios
__600x666 Rockfon Krios
__600x758 Rockfon Krios

# IfcBuildingElementProxy: 600 x 264 x 20 (5)
In: 00 begane grond
Material: Gipsplaat
Name | Gipsplaat, Mass (kg) | Gipsplaat, Component Volume (Net) (m3) = Gipsplaat, Component Volume (Gross) (m3)
__600x622 Rockfon Krios | 2.46168 | 0.0030771
__600x631 Rockfon Krios | 2.46168 | 0.0030771
__600x771 Rockfon Krios
__600x773 Rockfon Krios | 2.46168 | 0.0030771
__600x778 Rockfon Krios

# IfcBuildingElementProxy: 600 x 400 x 20 (20)
In: 01 eerste verdieping
Material: Gipsplaat
Name
__600x639 Rockfon Krios | Component Quantities - Gipsplaat, Mass: 3.7604 kg; Gipsplaat, Component Volume (Net): 0.0047005 m3; Gipsplaat, Component Volume (Gross): 0.0047005 m3
__600x649 Rockfon Krios
__600x659 Rockfon Krios | Component Quantities - Gipsplaat, Mass: 3.7604 kg; Gipsplaat, Component Volume (Net): 0.0047005 m3; Gipsplaat, Component Volume (Gross): 0.0047005 m3
__600x678 Rockfon Krios
__600x690 Rockfon Krios | Component Quantities - Gipsplaat, Mass: 3.7604 kg; Gipsplaat, Component Volume (Net): 0.0047005 m3; Gipsplaat, Component Volume (Gross): 0.0047005 m3
__600x695 Rockfon Krios | Component Quantities - Gipsplaat, Mass: 3.7604 kg; Gipsplaat, Component Volume (Net): 0.0047005 m3; Gipsplaat, Component Volume (Gross): 0.0047005 m3
__600x699 Rockfon Krios
__600x709 Rockfon Krios
__600x716 Rockfon Krios
__600x720 Rockfon Krios
__600x725 Rockfon Krios
__600x726 Rockfon Krios
__600x729 Rockfon Krios
__600x731 Rockfon Krios
__600x736 Rockfon Krios
__600x742 Rockfon Krios | Component Quantities - Gipsplaat, Mass: 3.7604 kg; Gipsplaat, Component Volume (Net): 0.0047005 m3; Gipsplaat, Component Volume (Gross): 0.0047005 m3
__600x743 Rockfon Krios
__600x747 Rockfon Krios
__600x758 Rockfon Krios
__600x759 Rockfon Krios

# IfcBuildingElementProxy: 600 x 410 x 20 (10)
In: 00 begane grond
Material: Gipsplaat
Name
__600x612 Rockfon Krios | Component Quantities - Gipsplaat, Mass: 3.85784 kg; Gipsplaat, Component Volume (Net): 0.00482229 m3; Gipsplaat, Component Volume (Gross): 0.00482229 m3
__600x614 Rockfon Krios
__600x648 Rockfon Krios
__600x656 Rockfon Krios
__600x667 Rockfon Krios
__600x706 Rockfon Krios
__600x726 Rockfon Krios
__600x763 Rockfon Krios | Component Quantities - Gipsplaat, Mass: 3.85784 kg; Gipsplaat, Component Volume (Net): 0.00482229 m3; Gipsplaat, Component Volume (Gross): 0.00482229 m3
__600x766 Rockfon Krios
__600x769 Rockfon Krios

# IfcBuildingElementProxy: 600 x 461 x 20 (14)
In: 00 begane grond
Material: Gipsplaat
Name
__600x608 Rockfon Krios | Component Quantities - Gipsplaat, Mass: 4.34365 kg; Gipsplaat, Component Volume (Net): 0.00542957 m3; Gipsplaat, Component Volume (Gross): 0.00542957 m3
__600x613 Rockfon Krios
__600x617 Rockfon Krios | Component Quantities - Gipsplaat, Mass: 4.34365 kg; Gipsplaat, Component Volume (Net): 0.00542957 m3; Gipsplaat, Component Volume (Gross): 0.00542957 m3
__600x620 Rockfon Krios
__600x625 Rockfon Krios
__600x641 Rockfon Krios
__600x642 Rockfon Krios
__600x645 Rockfon Krios
__600x657 Rockfon Krios
__600x665 Rockfon Krios | Component Quantities - Gipsplaat, Mass: 4.34365 kg; Gipsplaat, Component Volume (Net): 0.00542957 m3; Gipsplaat, Component Volume (Gross): 0.00542957 m3
__600x688 Rockfon Krios
__600x691 Rockfon Krios
__600x738 Rockfon Krios
__600x755 Rockfon Krios

# IfcBuildingElementProxy: 600 x 478 x 20 (14)
In: 01 eerste verdieping
Material: Gipsplaat
Name
__600x600 Rockfon Krios | Component Quantities - Gipsplaat, Mass: 4.50387 kg; Gipsplaat, Component Volume (Net): 0.00562984 m3; Gipsplaat, Component Volume (Gross): 0.00562984 m3
__600x604 Rockfon Krios
__600x612 Rockfon Krios
__600x614 Rockfon Krios
__600x623 Rockfon Krios
__600x672 Rockfon Krios
__600x693 Rockfon Krios
__600x699 Rockfon Krios
__600x712 Rockfon Krios
__600x719 Rockfon Krios
__600x726 Rockfon Krios
__600x740 Rockfon Krios
__600x747 Rockfon Krios
__600x751 Rockfon Krios

# IfcBuildingElementProxy: 600 x 490 x 20 (11)
In: 01 eerste verdieping
Material: Gipsplaat
Name
__600x644 Rockfon Krios | Component Quantities - Gipsplaat, Mass: 4.61722 kg; Gipsplaat, Component Volume (Net): 0.00577152 m3; Gipsplaat, Component Volume (Gross): 0.00577152 m3
__600x664 Rockfon Krios
__600x668 Rockfon Krios
__600x670 Rockfon Krios
__600x681 Rockfon Krios
__600x682 Rockfon Krios
__600x686 Rockfon Krios
__600x707 Rockfon Krios
__600x719 Rockfon Krios | Component Quantities - Gipsplaat, Mass: 4.61722 kg; Gipsplaat, Component Volume (Net): 0.00577152 m3; Gipsplaat, Component Volume (Gross): 0.00577152 m3
__600x735 Rockfon Krios
__600x752 Rockfon Krios

# IfcBuildingElementProxy: 600 x 495 x 20 (11)
In: 00 begane grond
Material: Gipsplaat
Name
__600x672 Rockfon Krios | Component Quantities - Gipsplaat, Mass: 4.66567 kg; Gipsplaat, Component Volume (Net): 0.00583209 m3; Gipsplaat, Component Volume (Gross): 0.00583209 m3
__600x675 Rockfon Krios
__600x698 Rockfon Krios
__600x716 Rockfon Krios | Component Quantities - Gipsplaat, Mass: 4.94764 kg; Gipsplaat, Component Volume (Net): 0.00618455 m3; Gipsplaat, Component Volume (Gross): 0.00618455 m3
__600x734 Rockfon Krios
__600x752 Rockfon Krios
__600x645 Rockfon Krios | Component Quantities - Gipsplaat, Mass: 4.66479 kg; Gipsplaat, Component Volume (Net): 0.00583099 m3; Gipsplaat, Component Volume (Gross): 0.00583099 m3
__600x649 Rockfon Krios | Component Quantities - Gipsplaat, Mass: 4.66479 kg; Gipsplaat, Component Volume (Net): 0.00583099 m3; Gipsplaat, Component Volume (Gross): 0.00583099 m3
__600x653 Rockfon Krios | Component Quantities - Gipsplaat, Mass: 4.66479 kg; Gipsplaat, Component Volume (Net): 0.00583099 m3; Gipsplaat, Component Volume (Gross): 0.00583099 m3
__600x672 Rockfon Krios
__600x707 Rockfon Krios

# IfcBuildingElementProxy: 600 x 498 x 20 (11)
In: 01 eerste verdieping
Material: Gipsplaat
Name
__600x625 Rockfon Krios | Component Quantities - Gipsplaat, Mass: 4.68861 kg; Gipsplaat, Component Volume (Net): 0.00586076 m3; Gipsplaat, Component Volume (Gross): 0.00586076 m3
__600x655 Rockfon Krios
__600x659 Rockfon Krios
__600x667 Rockfon Krios
__600x668 Rockfon Krios
__600x670 Rockfon Krios
__600x686 Rockfon Krios
__600x692 Rockfon Krios
__600x719 Rockfon Krios
__600x735 Rockfon Krios | Component Quantities - Gipsplaat, Mass: 4.68861 kg; Gipsplaat, Component Volume (Net): 0.00586076 m3; Gipsplaat, Component Volume (Gross): 0.00586076 m3
__600x752 Rockfon Krios

# IfcBuildingElementProxy: 600 x 506 x 20 (14)
In: 00 begane grond
Material: Gipsplaat
Name
__600x621 Rockfon Krios | Component Quantities - Gipsplaat, Mass: 4.77175 kg; Gipsplaat, Component Volume (Net): 0.00596468 m3; Gipsplaat, Component Volume (Gross): 0.00596468 m3
__600x626 Rockfon Krios
__600x637 Rockfon Krios
__600x649 Rockfon Krios
__600x661 Rockfon Krios
__600x683 Rockfon Krios
__600x692 Rockfon Krios
__600x714 Rockfon Krios
__600x722 Rockfon Krios
__600x730 Rockfon Krios
__600x739 Rockfon Krios
__600x746 Rockfon Krios
__600x762 Rockfon Krios
__600x767 Rockfon Krios | Component Quantities - Gipsplaat, Mass: 4.77175 kg; Gipsplaat, Component Volume (Net): 0.00596468 m3; Gipsplaat, Component Volume (Gross): 0.00596468 m3

# IfcBuildingElementProxy: 600 x 525 x 20 (41)
Material: Gipsplaat
Name | In
__600x602 Rockfon Krios | 00 begane grond | Component Quantities - Gipsplaat, Mass: 4.94989 kg; Gipsplaat, Component Volume (Net): 0.00618737 m3; Gipsplaat, Component Volume (Gross): 0.00618737 m3
__600x609 Rockfon Krios | 00 begane grond | Component Quantities - Gipsplaat, Mass: 4.94989 kg; Gipsplaat, Component Volume (Net): 0.00618737 m3; Gipsplaat, Component Volume (Gross): 0.00618737 m3
__600x623 Rockfon Krios | 00 begane grond
__600x625 Rockfon Krios | 00 begane grond
__600x664 Rockfon Krios | 00 begane grond
__600x689 Rockfon Krios | 00 begane grond
__600x698 Rockfon Krios | 00 begane grond
__600x709 Rockfon Krios | 00 begane grond
__600x601 Rockfon Krios | 01 eerste verdieping | Component Quantities - Gipsplaat, Mass: 4.95196 kg; Gipsplaat, Component Volume (Net): 0.00618995 m3; Gipsplaat, Component Volume (Gross): 0.00618995 m3
__600x608 Rockfon Krios | 01 eerste verdieping | Component Quantities - Gipsplaat, Mass: 4.95196 kg; Gipsplaat, Component Volume (Net): 0.00618995 m3; Gipsplaat, Component Volume (Gross): 0.00618995 m3
__600x613 Rockfon Krios | 01 eerste verdieping | Component Quantities - Gipsplaat, Mass: 4.95196 kg; Gipsplaat, Component Volume (Net): 0.00618995 m3; Gipsplaat, Component Volume (Gross): 0.00618995 m3
__600x618 Rockfon Krios | 01 eerste verdieping
__600x620 Rockfon Krios | 01 eerste verdieping
__600x630 Rockfon Krios | 01 eerste verdieping
__600x631 Rockfon Krios | 01 eerste verdieping
__600x650 Rockfon Krios | 01 eerste verdieping
__600x659 Rockfon Krios | 01 eerste verdieping
__600x668 Rockfon Krios | 01 eerste verdieping
__600x670 Rockfon Krios | 01 eerste verdieping
__600x681 Rockfon Krios | 01 eerste verdieping
__600x682 Rockfon Krios | 01 eerste verdieping
__600x685 Rockfon Krios | 01 eerste verdieping
__600x686 Rockfon Krios | 01 eerste verdieping | Component Quantities - Gipsplaat, Mass: 4.95196 kg; Gipsplaat, Component Volume (Net): 0.00618995 m3; Gipsplaat, Component Volume (Gross): 0.00618995 m3
__600x693 Rockfon Krios | 01 eerste verdieping
__600x694 Rockfon Krios | 01 eerste verdieping
__600x721 Rockfon Krios | 01 eerste verdieping
__600x734 Rockfon Krios | 01 eerste verdieping
__600x735 Rockfon Krios | 01 eerste verdieping
__600x747 Rockfon Krios | 01 eerste verdieping
__600x749 Rockfon Krios | 01 eerste verdieping
__600x602 Rockfon Krios | 01 eerste verdieping | Component Quantities - Gipsplaat, Mass: 4.94885 kg; Gipsplaat, Component Volume (Net): 0.00618606 m3; Gipsplaat, Component Volume (Gross): 0.00618606 m3
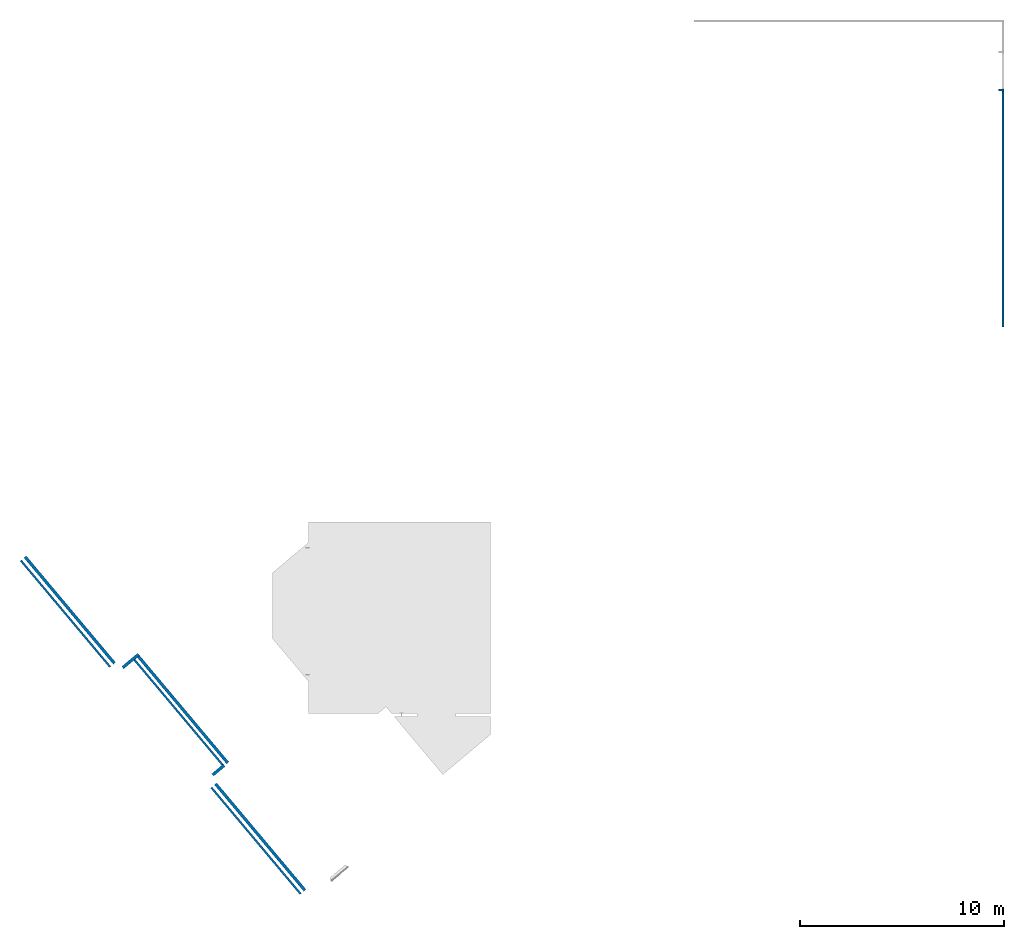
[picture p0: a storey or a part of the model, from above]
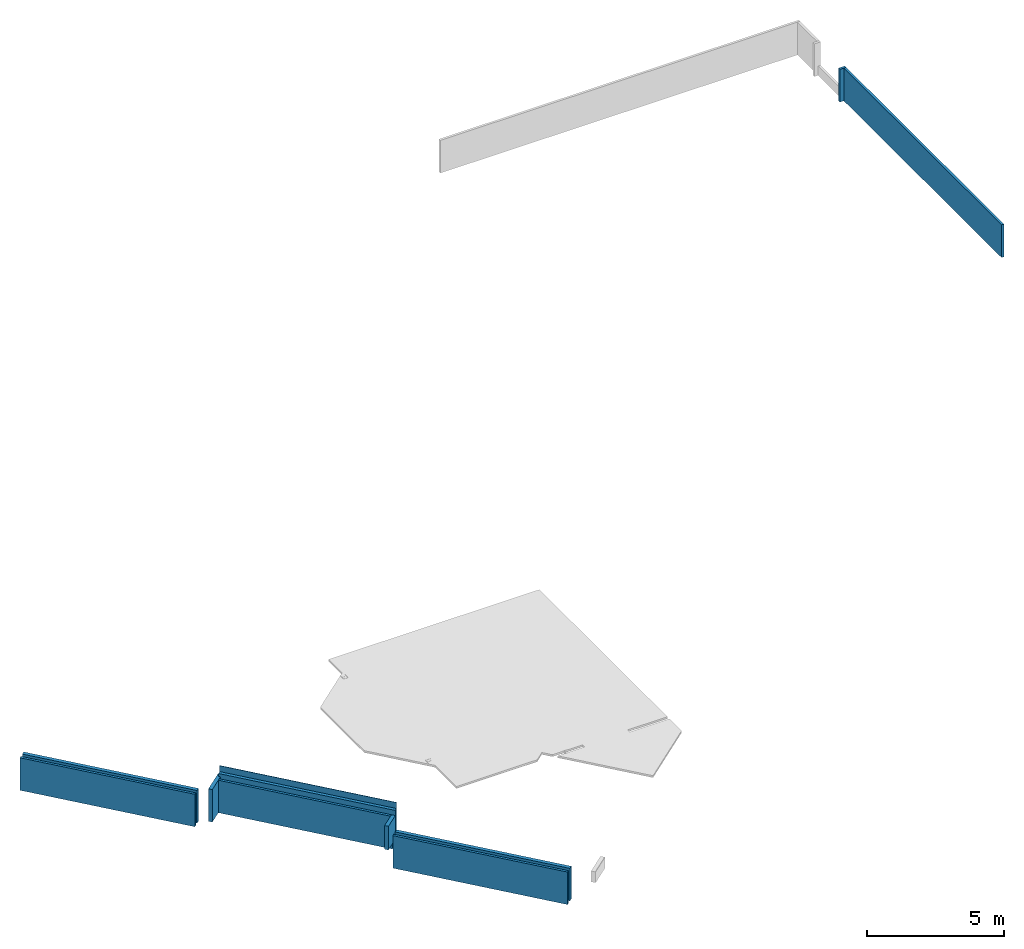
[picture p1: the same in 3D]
Properties of the parts of a building model (IFC2X3), part 5 of 11

# IfcBuildingElementProxy: 600 x 525 x 20 (41)
Name | In
__600x612 Rockfon Krios | 01 eerste verdieping | Component Quantities - Gipsplaat, Mass: 4.94885 kg; Gipsplaat, Component Volume (Net): 0.00618606 m3; Gipsplaat, Component Volume (Gross): 0.00618606 m3
__600x613 Rockfon Krios | 01 eerste verdieping | Component Quantities - Gipsplaat, Mass: 4.94885 kg; Gipsplaat, Component Volume (Net): 0.00618606 m3; Gipsplaat, Component Volume (Gross): 0.00618606 m3
__600x624 Rockfon Krios | 01 eerste verdieping
__600x627 Rockfon Krios | 01 eerste verdieping
__600x636 Rockfon Krios | 01 eerste verdieping
__600x646 Rockfon Krios | 01 eerste verdieping
__600x649 Rockfon Krios | 01 eerste verdieping
__600x666 Rockfon Krios | 01 eerste verdieping
__600x690 Rockfon Krios | 01 eerste verdieping
__600x743 Rockfon Krios | 01 eerste verdieping

# IfcBuildingElementProxy: 600 x 535 x 20 (11)
In: 01 eerste verdieping
Material: Gipsplaat
Name
__600x618 Rockfon Krios | Component Quantities - Gipsplaat, Mass: 5.0456 kg; Gipsplaat, Component Volume (Net): 0.006307 m3; Gipsplaat, Component Volume (Gross): 0.006307 m3
__600x623 Rockfon Krios | Component Quantities - Gipsplaat, Mass: 5.0456 kg; Gipsplaat, Component Volume (Net): 0.006307 m3; Gipsplaat, Component Volume (Gross): 0.006307 m3
__600x643 Rockfon Krios
__600x644 Rockfon Krios
__600x673 Rockfon Krios | Component Quantities - Gipsplaat, Mass: 5.0456 kg; Gipsplaat, Component Volume (Net): 0.006307 m3; Gipsplaat, Component Volume (Gross): 0.006307 m3
__600x674 Rockfon Krios
__600x675 Rockfon Krios
__600x682 Rockfon Krios
__600x694 Rockfon Krios
__600x701 Rockfon Krios
__600x740 Rockfon Krios

# IfcBuildingElementProxy: 600 x 538 x 20 (33)
In: 00 begane grond
Material: Gipsplaat
Name
__600x602 Rockfon Krios | Component Quantities - Gipsplaat, Mass: 5.07027 kg; Gipsplaat, Component Volume (Net): 0.00633783 m3; Gipsplaat, Component Volume (Gross): 0.00633783 m3
__600x612 Rockfon Krios | Component Quantities - Gipsplaat, Mass: 5.07027 kg; Gipsplaat, Component Volume (Net): 0.00633783 m3; Gipsplaat, Component Volume (Gross): 0.00633783 m3
__600x613 Rockfon Krios | Component Quantities - Gipsplaat, Mass: 5.07026 kg; Gipsplaat, Component Volume (Net): 0.00633783 m3; Gipsplaat, Component Volume (Gross): 0.00633783 m3
__600x624 Rockfon Krios
__600x627 Rockfon Krios
__600x636 Rockfon Krios
__600x646 Rockfon Krios
__600x649 Rockfon Krios
2 x __600x666 Rockfon Krios
__600x690 Rockfon Krios
__600x743 Rockfon Krios
__600x606 Rockfon Krios | Component Quantities - Gipsplaat, Mass: 5.06942 kg; Gipsplaat, Component Volume (Net): 0.00633678 m3; Gipsplaat, Component Volume (Gross): 0.00633678 m3
__600x613 Rockfon Krios
__600x618 Rockfon Krios
2 x __600x662 Rockfon Krios
2 x __600x688 Rockfon Krios
2 x __600x698 Rockfon Krios
2 x __600x716 Rockfon Krios
2 x __600x734 Rockfon Krios
__600x735 Rockfon Krios
2 x __600x752 Rockfon Krios
__600x661 Rockfon Krios
__600x672 Rockfon Krios
__600x675 Rockfon Krios
__600x707 Rockfon Krios
__600x725 Rockfon Krios

# IfcBuildingElementProxy: 600 x 543 x 20 (11)
In: 01 eerste verdieping
Material: Gipsplaat
Name
__600x608 Rockfon Krios | Component Quantities - Gipsplaat, Mass: 5.11702 kg; Gipsplaat, Component Volume (Net): 0.00639628 m3; Gipsplaat, Component Volume (Gross): 0.00639628 m3
__600x613 Rockfon Krios
__600x624 Rockfon Krios
__600x646 Rockfon Krios
__600x653 Rockfon Krios
__600x666 Rockfon Krios
__600x670 Rockfon Krios
__600x681 Rockfon Krios
__600x696 Rockfon Krios
__600x708 Rockfon Krios
__600x714 Rockfon Krios

# IfcBuildingElementProxy: 600 x 553 x 20 (11)
In: 01 eerste verdieping
Material: Gipsplaat
Name
__600x661 Rockfon Krios | Component Quantities - Gipsplaat, Mass: 5.21541 kg; Gipsplaat, Component Volume (Net): 0.00651926 m3; Gipsplaat, Component Volume (Gross): 0.00651926 m3
__600x662 Rockfon Krios
__600x672 Rockfon Krios | Component Quantities - Gipsplaat, Mass: 5.21541 kg; Gipsplaat, Component Volume (Net): 0.00651926 m3; Gipsplaat, Component Volume (Gross): 0.00651926 m3
__600x675 Rockfon Krios
__600x688 Rockfon Krios
__600x698 Rockfon Krios
__600x707 Rockfon Krios
__600x716 Rockfon Krios
__600x725 Rockfon Krios
__600x734 Rockfon Krios
__600x752 Rockfon Krios

# IfcBuildingElementProxy: 600 x 564 x 20 (12)
In: 00 begane grond
Material: Gipsplaat
Name
__600x639 Rockfon Krios | Component Quantities - Gipsplaat, Mass: 5.32182 kg; Gipsplaat, Component Volume (Net): 0.00665228 m3; Gipsplaat, Component Volume (Gross): 0.00665228 m3
__600x693 Rockfon Krios
__600x738 Rockfon Krios | Component Quantities - Gipsplaat, Mass: 5.32182 kg; Gipsplaat, Component Volume (Net): 0.00665228 m3; Gipsplaat, Component Volume (Gross): 0.00665228 m3
__600x759 Rockfon Krios
__600x617 Rockfon Krios | Component Quantities - Gipsplaat, Mass: 5.32118 kg; Gipsplaat, Component Volume (Net): 0.00665147 m3; Gipsplaat, Component Volume (Gross): 0.00665147 m3
__600x628 Rockfon Krios
__600x629 Rockfon Krios
__600x640 Rockfon Krios
__600x647 Rockfon Krios
__600x680 Rockfon Krios
__600x707 Rockfon Krios
__600x716 Rockfon Krios

# IfcBuildingElementProxy: 600 x 585 x 20 (9)
In: 01 eerste verdieping
Material: Gipsplaat
Name
__600x617 Rockfon Krios | Component Quantities - Gipsplaat, Mass: 5.52158 kg; Gipsplaat, Component Volume (Net): 0.00690197 m3; Gipsplaat, Component Volume (Gross): 0.00690197 m3
__600x618 Rockfon Krios | Component Quantities - Gipsplaat, Mass: 5.52158 kg; Gipsplaat, Component Volume (Net): 0.00690197 m3; Gipsplaat, Component Volume (Gross): 0.00690197 m3
__600x623 Rockfon Krios | Component Quantities - Gipsplaat, Mass: 5.52158 kg; Gipsplaat, Component Volume (Net): 0.00690197 m3; Gipsplaat, Component Volume (Gross): 0.00690197 m3
__600x655 Rockfon Krios
__600x667 Rockfon Krios
__600x673 Rockfon Krios
__600x674 Rockfon Krios
__600x696 Rockfon Krios
__600x701 Rockfon Krios

# IfcBuildingElementProxy: 600 x 593 x 20 (23)
In: 01 eerste verdieping
Material: Gipsplaat
Name
__600x603 Rockfon Krios | Component Quantities - Gipsplaat, Mass: 5.59308 kg; Gipsplaat, Component Volume (Net): 0.00699135 m3; Gipsplaat, Component Volume (Gross): 0.00699135 m3
__600x626 Rockfon Krios | Component Quantities - Gipsplaat, Mass: 5.59308 kg; Gipsplaat, Component Volume (Net): 0.00699135 m3; Gipsplaat, Component Volume (Gross): 0.00699135 m3
__600x629 Rockfon Krios
__600x633 Rockfon Krios | Component Quantities - Gipsplaat, Mass: 5.59308 kg; Gipsplaat, Component Volume (Net): 0.00699135 m3; Gipsplaat, Component Volume (Gross): 0.00699135 m3
2 x __600x635 Rockfon Krios
__600x656 Rockfon Krios
__600x664 Rockfon Krios
__600x724 Rockfon Krios
__600x744 Rockfon Krios
__600x754 Rockfon Krios
__600x602 Rockfon Krios | Component Quantities - Gipsplaat, Mass: 5.60161 kg; Gipsplaat, Component Volume (Net): 0.00700201 m3; Gipsplaat, Component Volume (Gross): 0.00700201 m3
__600x617 Rockfon Krios | Component Quantities - Gipsplaat, Mass: 5.60161 kg; Gipsplaat, Component Volume (Net): 0.00700201 m3; Gipsplaat, Component Volume (Gross): 0.00700201 m3
__600x622 Rockfon Krios
__600x636 Rockfon Krios
__600x646 Rockfon Krios
__600x653 Rockfon Krios
__600x657 Rockfon Krios
__600x661 Rockfon Krios
__600x662 Rockfon Krios
__600x671 Rockfon Krios | Component Quantities - Gipsplaat, Mass: 5.60161 kg; Gipsplaat, Component Volume (Net): 0.00700201 m3; Gipsplaat, Component Volume (Gross): 0.00700201 m3
__600x741 Rockfon Krios
__600x757 Rockfon Krios

# IfcBuildingElementProxy: 600 x 600 x 20 (47)
Material: Gipsplaat
Name | In
__600x600 Rockfon Krios | 00 begane grond | Component Quantities - Gipsplaat, Mass: 5.6644 kg; Gipsplaat, Component Volume (Net): 0.0070805 m3; Gipsplaat, Component Volume (Gross): 0.0070805 m3
__600x629 Rockfon Krios | 00 begane grond
__600x661 Rockfon Krios | 00 begane grond | Component Quantities - Gipsplaat, Mass: 5.6644 kg; Gipsplaat, Component Volume (Net): 0.0070805 m3; Gipsplaat, Component Volume (Gross): 0.0070805 m3
__600x688 Rockfon Krios | 00 begane grond
__600x725 Rockfon Krios | 00 begane grond
__600x602 Rockfon Krios | 00 begane grond
2 x __600x624 Rockfon Krios | 00 begane grond
__600x627 Rockfon Krios | 00 begane grond
__600x646 Rockfon Krios | 00 begane grond
__600x743 Rockfon Krios | 00 begane grond
__600x617 Rockfon Krios | 00 begane grond | Component Quantities - Gipsplaat, Mass: 5.6644 kg; Gipsplaat, Component Volume (Net): 0.0070805 m3; Gipsplaat, Component Volume (Gross): 0.0070805 m3
__600x649 Rockfon Krios | 00 begane grond
__600x602 Rockfon Krios | 01 eerste verdieping
__600x617 Rockfon Krios | 01 eerste verdieping
__600x624 Rockfon Krios | 01 eerste verdieping
__600x627 Rockfon Krios | 01 eerste verdieping
2 x __600x630 Rockfon Krios | 01 eerste verdieping
__600x632 Rockfon Krios | 01 eerste verdieping
__600x646 Rockfon Krios | 01 eerste verdieping
__600x654 Rockfon Krios | 01 eerste verdieping
__600x655 Rockfon Krios | 01 eerste verdieping
2 x __600x734 Rockfon Krios | 01 eerste verdieping
__600x607 Rockfon Krios | 01 eerste verdieping
__600x629 Rockfon Krios | 01 eerste verdieping
__600x633 Rockfon Krios | 01 eerste verdieping
__600x634 Rockfon Krios | 01 eerste verdieping
__600x669 Rockfon Krios | 01 eerste verdieping
2 x __600x674 Rockfon Krios | 01 eerste verdieping
__600x756 Rockfon Krios | 01 eerste verdieping
__600x759 Rockfon Krios | 01 eerste verdieping
__600x670 Rockfon Krios | 01 eerste verdieping
__600x671 Rockfon Krios | 01 eerste verdieping
__600x672 Rockfon Krios | 01 eerste verdieping
2 x __600x686 Rockfon Krios | 01 eerste verdieping
__600x689 Rockfon Krios | 01 eerste verdieping
__600x748 Rockfon Krios | 01 eerste verdieping
__600x754 Rockfon Krios | 01 eerste verdieping
__600x656 Rockfon Krios | 01 eerste verdieping
__600x657 Rockfon Krios | 01 eerste verdieping
__600x664 Rockfon Krios | 01 eerste verdieping
__600x732 Rockfon Krios | 01 eerste verdieping
__600x740 Rockfon Krios | 01 eerste verdieping

# IfcBuildingElementProxy: 68 x 110 x 20, __600x698 Rockfon Krios
In: 01 eerste verdieping
Material: Gipsplaat
Component Quantities - Gipsplaat, Mass: 5.22439 kg; Gipsplaat, Component Volume (Net): 0.00653049 m3; Gipsplaat, Component Volume (Gross): 0.00653049 m3

# IfcBuildingElementProxy: 87 x 538 x 20, __600x641 Rockfon Krios
In: 00 begane grond
Material: Gipsplaat
Component Quantities - Gipsplaat, Mass: 0.701804 kg; Gipsplaat, Component Volume (Net): 0.000877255 m3; Gipsplaat, Component Volume (Gross): 0.000877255 m3

# IfcBuildingElementProxy: 87 x 600 x 20 (10)
In: 00 begane grond
Material: Gipsplaat
Name
__600x635 Rockfon Krios | Component Quantities - Gipsplaat, Mass: 0.784041 kg; Gipsplaat, Component Volume (Net): 0.000980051 m3; Gipsplaat, Component Volume (Gross): 0.000980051 m3
__600x645 Rockfon Krios
__600x655 Rockfon Krios | Component Quantities - Gipsplaat, Mass: 0.784041 kg; Gipsplaat, Component Volume (Net): 0.000980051 m3; Gipsplaat, Component Volume (Gross): 0.000980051 m3
__600x666 Rockfon Krios | Component Quantities - Gipsplaat, Mass: 0.784041 kg; Gipsplaat, Component Volume (Net): 0.000980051 m3; Gipsplaat, Component Volume (Gross): 0.000980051 m3
__600x668 Rockfon Krios
__600x687 Rockfon Krios
__600x707 Rockfon Krios
__600x725 Rockfon Krios
__600x735 Rockfon Krios
__600x753 Rockfon Krios

# IfcBuildingElementProxy: 87 x 63 x 20, __600x623 Rockfon Krios
In: 00 begane grond
Material: Gipsplaat
Component Quantities - Gipsplaat, Mass: 0.075888 kg; Gipsplaat, Component Volume (Net): 0.00009486 m3; Gipsplaat, Component Volume (Gross): 0.00009486 m3

# IfcBuildingElementProxy: 93 x 250 x 20, __600x757 Rockfon Krios
In: 01 eerste verdieping
Material: Gipsplaat
Component Quantities - Gipsplaat, Mass: 1.13346 kg; Gipsplaat, Component Volume (Net): 0.00141682 m3; Gipsplaat, Component Volume (Gross): 0.00141682 m3

# IfcBuildingElementProxy: ALG - BINNENAFWERKING, _Massa_Morph-x
In: 00 begane grond
Type - ElementType: Massing; PredefinedType: USERDEFINED
Classification: Massa (ARCHICAD Classification); Material: ALG - BINNENAFWERKING
CPset_Phasing - Renovation Phase: Bestaand
Component Quantities - ALG - BINNENAFWERKING, Mass: 26.4362 kg; ALG - BINNENAFWERKING, Component Volume (Net): 0.0330452 m3; ALG - BINNENAFWERKING, Component Volume (Gross): 0.0330452 m3

# IfcBuildingElementProxy: Aluminium RAL 7032 120 x 125, 65_Zonwering_zonwering
In: 01 eerste verdieping
Type - ElementType: Shading Device; PredefinedType: USERDEFINED
Classification: Zonwering (ARCHICAD Classification); 65.31 ZONWERINGINSTALLATIE (NL/SfB (4 cijfers)); Material: Aluminium RAL 7032
CPset_Phasing - Renovation Phase: Bestaand
Component Quantities - Aluminium RAL 7032, Mass: 142.122 kg; Aluminium RAL 7032, Projected Component Area (Net): 0.422983 m2; Aluminium RAL 7032, Projected Component Area (Gross): 0.422983 m2; Aluminium RAL 7032, Component Thickness: 120 mm; Aluminium RAL 7032, Rectangular Component Height: 125 mm; Aluminium RAL 7032, Rectangular Component Width: 120 mm; Aluminium RAL 7032, Component Cross Section Area: 0.015 m2; Aluminium RAL 7032, Component Volume (Net): 0.0507579 m3; Aluminium RAL 7032, Component Volume (Gross): 0.0507579 m3

# IfcBuildingElementProxy: Aluminium RAL 7032 28 x 55 (2)
Type - ElementType: Shading Device; PredefinedType: USERDEFINED
Classification: Zonwering (ARCHICAD Classification); 65.31 ZONWERINGINSTALLATIE (NL/SfB (4 cijfers)); Material: Aluminium RAL 7032
CPset_Phasing - Renovation Phase: Bestaand
Component Quantities - Aluminium RAL 7032, Projected Component Area (Net): 0.181162 m2; Aluminium RAL 7032, Projected Component Area (Gross): 0.181162 m2; Aluminium RAL 7032, Component Thickness: 28 mm; Aluminium RAL 7032, Rectangular Component Height: 55 mm; Aluminium RAL 7032, Rectangular Component Width: 28 mm; Aluminium RAL 7032, Component Cross Section Area: 0.00154 m2
Name | In | Aluminium RAL 7032, Mass (kg) | Aluminium RAL 7032, Component Volume (Net) (m3) = Aluminium RAL 7032, Component Volume (Gross) (m3)
65_Zonwering_zonwering | 00 begane grond | 14.2031 | 0.00507255
65_Zonwering_zonwering | 01 eerste verdieping | 13.8389 | 0.00494247

# IfcBuildingElementProxy: Aluminium RAL 7032 45 x 35 (4)
Type - ElementType: Shading Device; PredefinedType: USERDEFINED
Classification: Zonwering (ARCHICAD Classification); 65.31 ZONWERINGINSTALLATIE (NL/SfB (4 cijfers)); Material: Aluminium RAL 7032
CPset_Phasing - Renovation Phase: Bestaand
Component Quantities - Aluminium RAL 7032, Component Thickness: 45 mm; Aluminium RAL 7032, Rectangular Component Height: 35 mm; Aluminium RAL 7032, Rectangular Component Width: 45 mm; Aluminium RAL 7032, Component Cross Section Area: 0.001575 m2
Name | In | Aluminium RAL 7032, Mass (kg) | Aluminium RAL 7032, Component Volume (Net) (m3) = Aluminium RAL 7032, Component Volume (Gross) (m3)
2 x 65_Zonwering_zonwering | 00 begane grond | 9.98155 | 0.00356484
2 x 65_Zonwering_zonwering | 01 eerste verdieping | 18.9784 | 0.00677801

# IfcBuildingElementProxy: Aluminium RAL 7032 55 x 28 (4)
Type - ElementType: Shading Device; PredefinedType: USERDEFINED
Classification: Zonwering (ARCHICAD Classification); 65.31 ZONWERINGINSTALLATIE (NL/SfB (4 cijfers)); Material: Aluminium RAL 7032
CPset_Phasing - Renovation Phase: Bestaand
Component Quantities - Aluminium RAL 7032, Component Thickness: 55 mm; Aluminium RAL 7032, Rectangular Component Height: 28 mm; Aluminium RAL 7032, Rectangular Component Width: 55 mm; Aluminium RAL 7032, Component Cross Section Area: 0.00154 m2
Name | In | Aluminium RAL 7032, Mass (kg) | Aluminium RAL 7032, Component Volume (Net) (m3) = Aluminium RAL 7032, Component Volume (Gross) (m3)
65_Zonwering_zonwering | 00 begane grond | 9.49886 | 0.00339245
65_Zonwering_zonwering | 00 begane grond | 9.52257 | 0.00340092
65_Zonwering_zonwering | 01 eerste verdieping | 18.5567 | 0.00662739
65_Zonwering_zonwering | 01 eerste verdieping | 18.5502 | 0.00662508

# IfcBuildingElementProxy: Aluminium RAL 7032 95 x 95, 65_Zonwering_zonwering
In: 00 begane grond
Type - ElementType: Shading Device; PredefinedType: USERDEFINED
Classification: Zonwering (ARCHICAD Classification); 65.31 ZONWERINGINSTALLATIE (NL/SfB (4 cijfers)); Material: Aluminium RAL 7032
CPset_Phasing - Renovation Phase: Bestaand
Component Quantities - Aluminium RAL 7032, Mass: 85.5102 kg; Aluminium RAL 7032, Projected Component Area (Net): 0.321467 m2; Aluminium RAL 7032, Projected Component Area (Gross): 0.321467 m2; Aluminium RAL 7032, Component Thickness: 95 mm; Aluminium RAL 7032, Rectangular Component Height: 95 mm; Aluminium RAL 7032, Rectangular Component Width: 95 mm; Aluminium RAL 7032, Component Cross Section Area: 0.009025 m2; Aluminium RAL 7032, Component Volume (Net): 0.0305394 m3; Aluminium RAL 7032, Component Volume (Gross): 0.0305394 m3

# IfcBuildingElementProxy: Dankers Slimmer Bouwen Kubus, 0_Building Element Proxy_nulpunt
In: 00 begane grond
Classification: Building Element Proxy (ARCHICAD Classification); 0.0 ALGEMEEN (NL/SfB (4 cijfers)); Material: ALG - BUITENAFWERKING
CPset_Phasing - Renovation Phase: Bestaand
Component Quantities - ALG - BUITENAFWERKING, Mass: 1878.61 kg; ALG - BUITENAFWERKING, Component Volume (Net): 0.988744 m3; ALG - BUITENAFWERKING, Component Volume (Gross): 0.988744 m3

# IfcBuildingElementProxy: Distinct Panel 1 x 24 x 20, __Panel-D
In: 01 eerste verdieping
Material: Gipsplaat
Component Quantities - Gipsplaat, Mass: 0.00274126 kg; Gipsplaat, Component Volume (Net): 0.00000342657 m3; Gipsplaat, Component Volume (Gross): 0.00000342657 m3

# IfcBuildingElementProxy: Distinct Panel 10 x 410 x 20, __Panel-D
In: 00 begane grond
Material: Gipsplaat
Component Quantities - Gipsplaat, Mass: 0.0343159 kg; Gipsplaat, Component Volume (Net): 0.0000428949 m3; Gipsplaat, Component Volume (Gross): 0.0000428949 m3

# IfcBuildingElementProxy: Distinct Panel 10 x 494 x 20, __Panel-D
In: 00 begane grond
Material: Gipsplaat
Component Quantities - Gipsplaat, Mass: 0.0419735 kg; Gipsplaat, Component Volume (Net): 0.0000524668 m3; Gipsplaat, Component Volume (Gross): 0.0000524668 m3

# IfcBuildingElementProxy: Distinct Panel 10 x 600 x 20 (5)
In: 00 begane grond
Material: Gipsplaat
Name
2 x __Panel-D | Component Quantities - Gipsplaat, Mass: 0.0511046 kg; Gipsplaat, Component Volume (Net): 0.0000638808 m3; Gipsplaat, Component Volume (Gross): 0.0000638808 m3
3 x __Panel-D

# IfcBuildingElementProxy: Distinct Panel 1050 x 392 x 20, __Panel-D
In: 00 begane grond
Material: Gipsplaat
Component Quantities - Gipsplaat, Mass: 6.46774 kg; Gipsplaat, Component Volume (Net): 0.00808467 m3; Gipsplaat, Component Volume (Gross): 0.00808467 m3

# IfcBuildingElementProxy: Distinct Panel 1050 x 393 x 20, __Panel-D
In: 00 begane grond
Material: Gipsplaat
Component Quantities - Gipsplaat, Mass: 6.47972 kg; Gipsplaat, Component Volume (Net): 0.00809965 m3; Gipsplaat, Component Volume (Gross): 0.00809965 m3

# IfcBuildingElementProxy: Distinct Panel 1050 x 600 x 20, __Panel-D
In: 00 begane grond
Material: Gipsplaat
Component Quantities - Gipsplaat, Mass: 9.94394 kg; Gipsplaat, Component Volume (Net): 0.0124299 m3; Gipsplaat, Component Volume (Gross): 0.0124299 m3

# IfcBuildingElementProxy: Distinct Panel 1096 x 442 x 20 (4)
In: 01 eerste verdieping
Material: Gipsplaat
Name | Gipsplaat, Mass (kg) | Gipsplaat, Component Volume (Net) (m3) = Gipsplaat, Component Volume (Gross) (m3)
2 x __Panel-D | 7.62133 | 0.00952666
2 x __Panel-D | 7.62241 | 0.00952801

# IfcBuildingElementProxy: Distinct Panel 1096 x 600 x 20 (6)
In: 01 eerste verdieping
Material: Gipsplaat
Name | Gipsplaat, Mass (kg) | Gipsplaat, Component Volume (Net) (m3) = Gipsplaat, Component Volume (Gross) (m3)
4 x __Panel-D | 10.3888 | 0.0129859
2 x __Panel-D

# IfcBuildingElementProxy: Distinct Panel 110 x 119 x 20, __Panel-D
In: 00 begane grond
Material: Gipsplaat
Component Quantities - Gipsplaat, Mass: 3.3418 kg; Gipsplaat, Component Volume (Net): 0.00417725 m3; Gipsplaat, Component Volume (Gross): 0.00417725 m3

# IfcBuildingElementProxy: Distinct Panel 116 x 138 x 20, __Panel-D
In: 01 eerste verdieping
Material: Gipsplaat
Component Quantities - Gipsplaat, Mass: 0.111542 kg; Gipsplaat, Component Volume (Net): 0.000139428 m3; Gipsplaat, Component Volume (Gross): 0.000139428 m3

# IfcBuildingElementProxy: Distinct Panel 12 x 600 x 20, __Panel-D
In: 00 begane grond
Material: Gipsplaat
Component Quantities - Gipsplaat, Mass: 3.76015 kg; Gipsplaat, Component Volume (Net): 0.00470019 m3; Gipsplaat, Component Volume (Gross): 0.00470019 m3

# IfcBuildingElementProxy: Distinct Panel 1200 x 442 x 20 (4)
In: 01 eerste verdieping
Material: Gipsplaat
Name | Gipsplaat, Mass (kg) | Gipsplaat, Component Volume (Net) (m3) = Gipsplaat, Component Volume (Gross) (m3)
2 x __Panel-D | 8.34588 | 0.0104323
__Panel-D | 8.34706 | 0.0104338
__Panel-D

# IfcBuildingElementProxy: Distinct Panel 1200 x 600 x 20 (6)
In: 01 eerste verdieping
Material: Gipsplaat
Name
2 x __Panel-D | Component Quantities - Gipsplaat, Mass: 11.3764 kg; Gipsplaat, Component Volume (Net): 0.0142205 m3; Gipsplaat, Component Volume (Gross): 0.0142205 m3
4 x __Panel-D

# IfcBuildingElementProxy: Distinct Panel 123 x 55 x 20, __Panel-D
In: 00 begane grond
Material: Gipsplaat
Component Quantities - Gipsplaat, Mass: 0.0947257 kg; Gipsplaat, Component Volume (Net): 0.000118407 m3; Gipsplaat, Component Volume (Gross): 0.000118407 m3

# IfcBuildingElementProxy: Distinct Panel 125 x 149 x 20, __Panel-D
In: 01 eerste verdieping
Material: Gipsplaat
Component Quantities - Gipsplaat, Mass: 0.130801 kg; Gipsplaat, Component Volume (Net): 0.000163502 m3; Gipsplaat, Component Volume (Gross): 0.000163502 m3

# IfcBuildingElementProxy: Distinct Panel 132 x 495 x 20, __Panel-D
In: 00 begane grond
Material: Gipsplaat
Component Quantities - Gipsplaat, Mass: 5.20599 kg; Gipsplaat, Component Volume (Net): 0.00650748 m3; Gipsplaat, Component Volume (Gross): 0.00650748 m3

# IfcBuildingElementProxy: Distinct Panel 137 x 14 x 20, __Panel-D
In: 01 eerste verdieping
Material: Gipsplaat
Component Quantities - Gipsplaat, Mass: 0.0198935 kg; Gipsplaat, Component Volume (Net): 0.0000248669 m3; Gipsplaat, Component Volume (Gross): 0.0000248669 m3

# IfcBuildingElementProxy: Distinct Panel 137 x 236 x 20, __Panel-D
In: 01 eerste verdieping
Material: Gipsplaat
Component Quantities - Gipsplaat, Mass: 0.487331 kg; Gipsplaat, Component Volume (Net): 0.000609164 m3; Gipsplaat, Component Volume (Gross): 0.000609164 m3

# IfcBuildingElementProxy: Distinct Panel 137 x 341 x 20, __Panel-D
In: 01 eerste verdieping
Material: Gipsplaat
Component Quantities - Gipsplaat, Mass: 0.709242 kg; Gipsplaat, Component Volume (Net): 0.000886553 m3; Gipsplaat, Component Volume (Gross): 0.000886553 m3

# IfcBuildingElementProxy: Distinct Panel 137 x 589 x 20, __Panel-D
In: 01 eerste verdieping
Material: Gipsplaat
Component Quantities - Gipsplaat, Mass: 1.23512 kg; Gipsplaat, Component Volume (Net): 0.0015439 m3; Gipsplaat, Component Volume (Gross): 0.0015439 m3

# IfcBuildingElementProxy: Distinct Panel 137 x 600 x 20 (6)
In: 01 eerste verdieping
Material: Gipsplaat
Name
2 x __Panel-D | Component Quantities - Gipsplaat, Mass: 1.2575 kg; Gipsplaat, Component Volume (Net): 0.00157187 m3; Gipsplaat, Component Volume (Gross): 0.00157187 m3
4 x __Panel-D

# IfcBuildingElementProxy: Distinct Panel 140 x 167 x 20, __Panel-D
In: 01 eerste verdieping
Material: Gipsplaat
Component Quantities - Gipsplaat, Mass: 0.166082 kg; Gipsplaat, Component Volume (Net): 0.000207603 m3; Gipsplaat, Component Volume (Gross): 0.000207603 m3

# IfcBuildingElementProxy: Distinct Panel 140 x 19 x 20, __Panel-D
In: 01 eerste verdieping
Material: Gipsplaat
Component Quantities - Gipsplaat, Mass: 2.66293 kg; Gipsplaat, Component Volume (Net): 0.00332866 m3; Gipsplaat, Component Volume (Gross): 0.00332866 m3

# IfcBuildingElementProxy: Distinct Panel 142 x 169 x 20, __Panel-D
In: 00 begane grond
Material: Gipsplaat
Component Quantities - Gipsplaat, Mass: 0.17146 kg; Gipsplaat, Component Volume (Net): 0.000214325 m3; Gipsplaat, Component Volume (Gross): 0.000214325 m3

# IfcBuildingElementProxy: Distinct Panel 143 x 120 x 20, __Panel-D
In: 00 begane grond
Material: Gipsplaat
Component Quantities - Gipsplaat, Mass: 0.119935 kg; Gipsplaat, Component Volume (Net): 0.000149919 m3; Gipsplaat, Component Volume (Gross): 0.000149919 m3

# IfcBuildingElementProxy: Distinct Panel 143 x 600 x 20, __Panel-D
In: 00 begane grond
Material: Gipsplaat
Component Quantities - Gipsplaat, Mass: 4.2724 kg; Gipsplaat, Component Volume (Net): 0.0053405 m3; Gipsplaat, Component Volume (Gross): 0.0053405 m3

# IfcBuildingElementProxy: Distinct Panel 145 x 105 x 20, __Panel-D
In: 00 begane grond
Material: Gipsplaat
Component Quantities - Gipsplaat, Mass: 3.13907 kg; Gipsplaat, Component Volume (Net): 0.00392384 m3; Gipsplaat, Component Volume (Gross): 0.00392384 m3

# IfcBuildingElementProxy: Distinct Panel 146 x 174 x 20, __Panel-D
In: 01 eerste verdieping
Material: Gipsplaat
Component Quantities - Gipsplaat, Mass: 0.181273 kg; Gipsplaat, Component Volume (Net): 0.000226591 m3; Gipsplaat, Component Volume (Gross): 0.000226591 m3

# IfcBuildingElementProxy: Distinct Panel 16 x 1012 x 20, __Panel-D
In: 00 begane grond
Material: Gipsplaat
Component Quantities - Gipsplaat, Mass: 0.170556 kg; Gipsplaat, Component Volume (Net): 0.000213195 m3; Gipsplaat, Component Volume (Gross): 0.000213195 m3

# IfcBuildingElementProxy: Distinct Panel 16 x 1042 x 20, __Panel-D
In: 00 begane grond
Material: Gipsplaat
Component Quantities - Gipsplaat, Mass: 0.175594 kg; Gipsplaat, Component Volume (Net): 0.000219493 m3; Gipsplaat, Component Volume (Gross): 0.000219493 m3

# IfcBuildingElementProxy: Distinct Panel 160 x 122 x 20, __Panel-D
In: 01 eerste verdieping
Material: Gipsplaat
Component Quantities - Gipsplaat, Mass: 5.35322 kg; Gipsplaat, Component Volume (Net): 0.00669152 m3; Gipsplaat, Component Volume (Gross): 0.00669152 m3

# IfcBuildingElementProxy: Distinct Panel 174 x 480 x 20, __Panel-D
In: 01 eerste verdieping
Material: Gipsplaat
Component Quantities - Gipsplaat, Mass: 1.28453 kg; Gipsplaat, Component Volume (Net): 0.00160566 m3; Gipsplaat, Component Volume (Gross): 0.00160566 m3

# IfcBuildingElementProxy: Distinct Panel 174 x 524 x 20, __Panel-D
In: 01 eerste verdieping
Material: Gipsplaat
Component Quantities - Gipsplaat, Mass: 1.40469 kg; Gipsplaat, Component Volume (Net): 0.00175586 m3; Gipsplaat, Component Volume (Gross): 0.00175586 m3

# IfcBuildingElementProxy: Distinct Panel 174 x 600 x 20 (8)
In: 01 eerste verdieping
Material: Gipsplaat
Name
2 x __Panel-D | Component Quantities - Gipsplaat, Mass: 1.60921 kg; Gipsplaat, Component Volume (Net): 0.00201151 m3; Gipsplaat, Component Volume (Gross): 0.00201151 m3
6 x __Panel-D

# IfcBuildingElementProxy: Distinct Panel 182 x 1042 x 20, __Panel-D
In: 00 begane grond
Material: Gipsplaat
Component Quantities - Gipsplaat, Mass: 2.94424 kg; Gipsplaat, Component Volume (Net): 0.0036803 m3; Gipsplaat, Component Volume (Gross): 0.0036803 m3

# IfcBuildingElementProxy: Distinct Panel 182 x 969 x 20, __Panel-D
In: 00 begane grond
Material: Gipsplaat
Component Quantities - Gipsplaat, Mass: 2.80367 kg; Gipsplaat, Component Volume (Net): 0.00350459 m3; Gipsplaat, Component Volume (Gross): 0.00350459 m3

# IfcBuildingElementProxy: Distinct Panel 183 x 171 x 20, __Panel-D
In: 00 begane grond
Material: Gipsplaat
Component Quantities - Gipsplaat, Mass: 0.472372 kg; Gipsplaat, Component Volume (Net): 0.000590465 m3; Gipsplaat, Component Volume (Gross): 0.000590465 m3

# IfcBuildingElementProxy: Distinct Panel 183 x 600 x 20, __Panel-D
In: 00 begane grond
Material: Gipsplaat
Component Quantities - Gipsplaat, Mass: 2.70843 kg; Gipsplaat, Component Volume (Net): 0.00338553 m3; Gipsplaat, Component Volume (Gross): 0.00338553 m3

# IfcBuildingElementProxy: Distinct Panel 19 x 22 x 20, __Panel-D
In: 01 eerste verdieping
Material: Gipsplaat
Component Quantities - Gipsplaat, Mass: 0.00114622 kg; Gipsplaat, Component Volume (Net): 0.00000143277 m3; Gipsplaat, Component Volume (Gross): 0.00000143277 m3

# IfcBuildingElementProxy: Distinct Panel 190 x 445 x 20, __Panel-D
In: 00 begane grond
Material: Gipsplaat
Component Quantities - Gipsplaat, Mass: 5.34519 kg; Gipsplaat, Component Volume (Net): 0.00668149 m3; Gipsplaat, Component Volume (Gross): 0.00668149 m3

# IfcBuildingElementProxy: Distinct Panel 195 x 163 x 20, __Panel-D
In: 01 eerste verdieping
Material: Gipsplaat
Component Quantities - Gipsplaat, Mass: 0.230157 kg; Gipsplaat, Component Volume (Net): 0.000287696 m3; Gipsplaat, Component Volume (Gross): 0.000287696 m3

# IfcBuildingElementProxy: Distinct Panel 195 x 600 x 20, __Panel-D
In: 01 eerste verdieping
Material: Gipsplaat
Component Quantities - Gipsplaat, Mass: 4.56944 kg; Gipsplaat, Component Volume (Net): 0.0057118 m3; Gipsplaat, Component Volume (Gross): 0.0057118 m3

# IfcBuildingElementProxy: Distinct Panel 197 x 1018 x 20, __Panel-D
In: 00 begane grond
Material: Gipsplaat
Component Quantities - Gipsplaat, Mass: 3.11318 kg; Gipsplaat, Component Volume (Net): 0.00389147 m3; Gipsplaat, Component Volume (Gross): 0.00389147 m3

# IfcBuildingElementProxy: Distinct Panel 197 x 993 x 20, __Panel-D
In: 00 begane grond
Material: Gipsplaat
Component Quantities - Gipsplaat, Mass: 3.03632 kg; Gipsplaat, Component Volume (Net): 0.0037954 m3; Gipsplaat, Component Volume (Gross): 0.0037954 m3

# IfcBuildingElementProxy: Distinct Panel 20 (2)
Material: Gipsplaat
Name | In | Gipsplaat, Mass (kg) | Gipsplaat, Component Volume (Net) (m3) = Gipsplaat, Component Volume (Gross) (m3)
__Panel-D | 00 begane grond | 0.174471 | 0.000218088
__Panel-D | 01 eerste verdieping | 0.314878 | 0.000393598

# IfcBuildingElementProxy: Distinct Panel 20 x 376 x 20, __Panel-D
In: 01 eerste verdieping
Material: Gipsplaat
Component Quantities - Gipsplaat, Mass: 0.0886709 kg; Gipsplaat, Component Volume (Net): 0.000110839 m3; Gipsplaat, Component Volume (Gross): 0.000110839 m3

# IfcBuildingElementProxy: Distinct Panel 20 x 386 x 20, __Panel-D
In: 01 eerste verdieping
Material: Gipsplaat
Component Quantities - Gipsplaat, Mass: 0.0910743 kg; Gipsplaat, Component Volume (Net): 0.000113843 m3; Gipsplaat, Component Volume (Gross): 0.000113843 m3

# IfcBuildingElementProxy: Distinct Panel 20 x 600 x 20, __Panel-D
In: 01 eerste verdieping
Material: Gipsplaat
Component Quantities - Gipsplaat, Mass: 0.142219 kg; Gipsplaat, Component Volume (Net): 0.000177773 m3; Gipsplaat, Component Volume (Gross): 0.000177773 m3

# IfcBuildingElementProxy: Distinct Panel 200 x 1175 x 20, __Panel-D
In: 00 begane grond
Material: Gipsplaat
Component Quantities - Gipsplaat, Mass: 10.0711 kg; Gipsplaat, Component Volume (Net): 0.0125888 m3; Gipsplaat, Component Volume (Gross): 0.0125888 m3

# IfcBuildingElementProxy: Distinct Panel 200 x 50 x 20, __Panel-D
In: 00 begane grond
Material: Gipsplaat
Component Quantities - Gipsplaat, Mass: 0.140337 kg; Gipsplaat, Component Volume (Net): 0.000175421 m3; Gipsplaat, Component Volume (Gross): 0.000175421 m3

# IfcBuildingElementProxy: Distinct Panel 200 x 600 x 20 (3)
In: 00 begane grond
Material: Gipsplaat
Name | Gipsplaat, Mass (kg) | Gipsplaat, Component Volume (Net) (m3) = Gipsplaat, Component Volume (Gross) (m3)
2 x __Panel-D | 1.8564 | 0.0023205
__Panel-D

# IfcBuildingElementProxy: Distinct Panel 200 x 67 x 20, __Panel-D
In: 00 begane grond
Material: Gipsplaat
Component Quantities - Gipsplaat, Mass: 0.19193 kg; Gipsplaat, Component Volume (Net): 0.000239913 m3; Gipsplaat, Component Volume (Gross): 0.000239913 m3

# IfcBuildingElementProxy: Distinct Panel 203 x 1018 x 20, __Panel-D
In: 00 begane grond
Material: Gipsplaat
Component Quantities - Gipsplaat, Mass: 3.20482 kg; Gipsplaat, Component Volume (Net): 0.00400603 m3; Gipsplaat, Component Volume (Gross): 0.00400603 m3

# IfcBuildingElementProxy: Distinct Panel 203 x 1175 x 20, __Panel-D
In: 00 begane grond
Material: Gipsplaat
Component Quantities - Gipsplaat, Mass: 11.1384 kg; Gipsplaat, Component Volume (Net): 0.0139229 m3; Gipsplaat, Component Volume (Gross): 0.0139229 m3

# IfcBuildingElementProxy: Distinct Panel 203 x 993 x 20, __Panel-D
In: 00 begane grond
Material: Gipsplaat
Component Quantities - Gipsplaat, Mass: 3.12571 kg; Gipsplaat, Component Volume (Net): 0.00390714 m3; Gipsplaat, Component Volume (Gross): 0.00390714 m3

# IfcBuildingElementProxy: Distinct Panel 208 x 42 x 20, __Panel-D
In: 01 eerste verdieping
Material: Gipsplaat
Component Quantities - Gipsplaat, Mass: 2.32405 kg; Gipsplaat, Component Volume (Net): 0.00290506 m3; Gipsplaat, Component Volume (Gross): 0.00290506 m3

# IfcBuildingElementProxy: Distinct Panel 211 x 80 x 20, __Panel-D
In: 01 eerste verdieping
Material: Gipsplaat
Component Quantities - Gipsplaat, Mass: 0.247768 kg; Gipsplaat, Component Volume (Net): 0.00030971 m3; Gipsplaat, Component Volume (Gross): 0.00030971 m3

# IfcBuildingElementProxy: Distinct Panel 211 x 950 x 20, __Panel-D
In: 01 eerste verdieping
Material: Gipsplaat
Component Quantities - Gipsplaat, Mass: 3.11059 kg; Gipsplaat, Component Volume (Net): 0.00388824 m3; Gipsplaat, Component Volume (Gross): 0.00388824 m3

# IfcBuildingElementProxy: Distinct Panel 215 x 320 x 20, __Panel-D
In: 00 begane grond
Material: Gipsplaat
Component Quantities - Gipsplaat, Mass: 1.05878 kg; Gipsplaat, Component Volume (Net): 0.00132347 m3; Gipsplaat, Component Volume (Gross): 0.00132347 m3

# IfcBuildingElementProxy: Distinct Panel 215 x 345 x 20, __Panel-D
In: 00 begane grond
Material: Gipsplaat
Component Quantities - Gipsplaat, Mass: 1.14471 kg; Gipsplaat, Component Volume (Net): 0.00143089 m3; Gipsplaat, Component Volume (Gross): 0.00143089 m3

# IfcBuildingElementProxy: Distinct Panel 218 x 244 x 20, __Panel-D
In: 00 begane grond
Material: Gipsplaat
Component Quantities - Gipsplaat, Mass: 0.814325 kg; Gipsplaat, Component Volume (Net): 0.00101791 m3; Gipsplaat, Component Volume (Gross): 0.00101791 m3

# IfcBuildingElementProxy: Distinct Panel 218 x 600 x 20 (9)
In: 00 begane grond
Material: Gipsplaat
Name
2 x __Panel-D | Component Quantities - Gipsplaat, Mass: 2.02306 kg; Gipsplaat, Component Volume (Net): 0.00252883 m3; Gipsplaat, Component Volume (Gross): 0.00252883 m3
7 x __Panel-D

# IfcBuildingElementProxy: Distinct Panel 219 x 184 x 20, __Panel-D
In: 01 eerste verdieping
Material: Gipsplaat
Component Quantities - Gipsplaat, Mass: 0.295771 kg; Gipsplaat, Component Volume (Net): 0.000369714 m3; Gipsplaat, Component Volume (Gross): 0.000369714 m3

# IfcBuildingElementProxy: Distinct Panel 219 x 600 x 20, __Panel-D
In: 01 eerste verdieping
Material: Gipsplaat
Component Quantities - Gipsplaat, Mass: 4.69948 kg; Gipsplaat, Component Volume (Net): 0.00587435 m3; Gipsplaat, Component Volume (Gross): 0.00587435 m3

# IfcBuildingElementProxy: Distinct Panel 222 x 264 x 20, __Panel-D
In: 01 eerste verdieping
Material: Gipsplaat
Component Quantities - Gipsplaat, Mass: 0.435276 kg; Gipsplaat, Component Volume (Net): 0.000544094 m3; Gipsplaat, Component Volume (Gross): 0.000544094 m3

# IfcBuildingElementProxy: Distinct Panel 225 x 203 x 20, __Panel-D
In: 01 eerste verdieping
Material: Gipsplaat
Component Quantities - Gipsplaat, Mass: 0.695598 kg; Gipsplaat, Component Volume (Net): 0.000869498 m3; Gipsplaat, Component Volume (Gross): 0.000869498 m3

# IfcBuildingElementProxy: Distinct Panel 225 x 433 x 20, __Panel-D
In: 01 eerste verdieping
Material: Gipsplaat
Component Quantities - Gipsplaat, Mass: 1.50705 kg; Gipsplaat, Component Volume (Net): 0.00188381 m3; Gipsplaat, Component Volume (Gross): 0.00188381 m3

# IfcBuildingElementProxy: Distinct Panel 225 x 461 x 20, __Panel-D
In: 01 eerste verdieping
Material: Gipsplaat
Component Quantities - Gipsplaat, Mass: 1.60327 kg; Gipsplaat, Component Volume (Net): 0.00200408 m3; Gipsplaat, Component Volume (Gross): 0.00200408 m3

# IfcBuildingElementProxy: Distinct Panel 225 x 564 x 20, __Panel-D
In: 01 eerste verdieping
Material: Gipsplaat
Component Quantities - Gipsplaat, Mass: 1.96864 kg; Gipsplaat, Component Volume (Net): 0.0024608 m3; Gipsplaat, Component Volume (Gross): 0.0024608 m3

# IfcBuildingElementProxy: Distinct Panel 225 x 600 x 20 (2)
In: 01 eerste verdieping
Material: Gipsplaat
Name
__Panel-D | Component Quantities - Gipsplaat, Mass: 2.09388 kg; Gipsplaat, Component Volume (Net): 0.00261735 m3; Gipsplaat, Component Volume (Gross): 0.00261735 m3
__Panel-D

# IfcBuildingElementProxy: Distinct Panel 230 x 566 x 20, __Panel-D
In: 00 begane grond
Material: Gipsplaat
Component Quantities - Gipsplaat, Mass: 2.02353 kg; Gipsplaat, Component Volume (Net): 0.00252941 m3; Gipsplaat, Component Volume (Gross): 0.00252941 m3

# IfcBuildingElementProxy: Distinct Panel 230 x 600 x 20 (2)
In: 00 begane grond
Material: Gipsplaat
Name
__Panel-D | Component Quantities - Gipsplaat, Mass: 2.14652 kg; Gipsplaat, Component Volume (Net): 0.00268315 m3; Gipsplaat, Component Volume (Gross): 0.00268315 m3
__Panel-D

# IfcBuildingElementProxy: Distinct Panel 236 x 282 x 20, __Panel-D
In: 01 eerste verdieping
Material: Gipsplaat
Component Quantities - Gipsplaat, Mass: 0.497902 kg; Gipsplaat, Component Volume (Net): 0.000622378 m3; Gipsplaat, Component Volume (Gross): 0.000622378 m3

# IfcBuildingElementProxy: Distinct Panel 239 x 284 x 20, __Panel-D
In: 00 begane grond
Material: Gipsplaat
Component Quantities - Gipsplaat, Mass: 0.507187 kg; Gipsplaat, Component Volume (Net): 0.000633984 m3; Gipsplaat, Component Volume (Gross): 0.000633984 m3

# IfcBuildingElementProxy: Distinct Panel 242 x 289 x 20, __Panel-D
In: 01 eerste verdieping
Material: Gipsplaat
Component Quantities - Gipsplaat, Mass: 0.52396 kg; Gipsplaat, Component Volume (Net): 0.000654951 m3; Gipsplaat, Component Volume (Gross): 0.000654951 m3

# IfcBuildingElementProxy: Distinct Panel 250 x 575 x 20, __Panel-D
In: 00 begane grond
Material: Gipsplaat
Component Quantities - Gipsplaat, Mass: 5.56403 kg; Gipsplaat, Component Volume (Net): 0.00695503 m3; Gipsplaat, Component Volume (Gross): 0.00695503 m3

# IfcBuildingElementProxy: Distinct Panel 258 x 1158 x 20, __Panel-D
In: 01 eerste verdieping
Material: Gipsplaat
Component Quantities - Gipsplaat, Mass: 6.79968 kg; Gipsplaat, Component Volume (Net): 0.0084996 m3; Gipsplaat, Component Volume (Gross): 0.0084996 m3

# IfcBuildingElementProxy: Distinct Panel 258 x 217 x 20, __Panel-D
In: 00 begane grond
Material: Gipsplaat
Component Quantities - Gipsplaat, Mass: 0.415267 kg; Gipsplaat, Component Volume (Net): 0.000519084 m3; Gipsplaat, Component Volume (Gross): 0.000519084 m3

# IfcBuildingElementProxy: Distinct Panel 258 x 600 x 20, __Panel-D
In: 00 begane grond
Material: Gipsplaat
Component Quantities - Gipsplaat, Mass: 4.88694 kg; Gipsplaat, Component Volume (Net): 0.00610868 m3; Gipsplaat, Component Volume (Gross): 0.00610868 m3

# IfcBuildingElementProxy: Distinct Panel 26 x 350 x 20, __Panel-D
In: 00 begane grond
Material: Gipsplaat
Component Quantities - Gipsplaat, Mass: 0.116113 kg; Gipsplaat, Component Volume (Net): 0.000145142 m3; Gipsplaat, Component Volume (Gross): 0.000145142 m3

# IfcBuildingElementProxy: Distinct Panel 26 x 475 x 20, __Panel-D
In: 00 begane grond
Material: Gipsplaat
Component Quantities - Gipsplaat, Mass: 0.15821 kg; Gipsplaat, Component Volume (Net): 0.000197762 m3; Gipsplaat, Component Volume (Gross): 0.000197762 m3

# IfcBuildingElementProxy: Distinct Panel 26 x 600 x 20 (4)
In: 00 begane grond
Material: Gipsplaat
Name
__Panel-D | Component Quantities - Gipsplaat, Mass: 0.20038 kg; Gipsplaat, Component Volume (Net): 0.000250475 m3; Gipsplaat, Component Volume (Gross): 0.000250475 m3
3 x __Panel-D

# IfcBuildingElementProxy: Distinct Panel 261 x 267 x 20, __Panel-D
In: 01 eerste verdieping
Material: Gipsplaat
Component Quantities - Gipsplaat, Mass: 1.07213 kg; Gipsplaat, Component Volume (Net): 0.00134017 m3; Gipsplaat, Component Volume (Gross): 0.00134017 m3

# IfcBuildingElementProxy: Distinct Panel 261 x 463 x 20, __Panel-D
In: 01 eerste verdieping
Material: Gipsplaat
Component Quantities - Gipsplaat, Mass: 2.31175 kg; Gipsplaat, Component Volume (Net): 0.00288969 m3; Gipsplaat, Component Volume (Gross): 0.00288969 m3

# IfcBuildingElementProxy: Distinct Panel 261 x 600 x 20 (6)
In: 01 eerste verdieping
Material: Gipsplaat
Name
3 x __Panel-D | Component Quantities - Gipsplaat, Mass: 2.43499 kg; Gipsplaat, Component Volume (Net): 0.00304374 m3; Gipsplaat, Component Volume (Gross): 0.00304374 m3
3 x __Panel-D

# IfcBuildingElementProxy: Distinct Panel 268 x 333 x 20, __Panel-D
In: 00 begane grond
Material: Gipsplaat
Component Quantities - Gipsplaat, Mass: 1.37789 kg; Gipsplaat, Component Volume (Net): 0.00172236 m3; Gipsplaat, Component Volume (Gross): 0.00172236 m3

# IfcBuildingElementProxy: Distinct Panel 268 x 80 x 20, __Panel-D
In: 01 eerste verdieping
Material: Gipsplaat
Component Quantities - Gipsplaat, Mass: 0.316804 kg; Gipsplaat, Component Volume (Net): 0.000396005 m3; Gipsplaat, Component Volume (Gross): 0.000396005 m3

# IfcBuildingElementProxy: Distinct Panel 268 x 950 x 20, __Panel-D
In: 01 eerste verdieping
Material: Gipsplaat
Component Quantities - Gipsplaat, Mass: 3.9773 kg; Gipsplaat, Component Volume (Net): 0.00497163 m3; Gipsplaat, Component Volume (Gross): 0.00497163 m3

# IfcBuildingElementProxy: Distinct Panel 269 x 462 x 20, __Panel-D
In: 00 begane grond
Material: Gipsplaat
Component Quantities - Gipsplaat, Mass: 1.93026 kg; Gipsplaat, Component Volume (Net): 0.00241283 m3; Gipsplaat, Component Volume (Gross): 0.00241283 m3

# IfcBuildingElementProxy: Distinct Panel 269 x 503 x 20, __Panel-D
In: 00 begane grond
Material: Gipsplaat
Component Quantities - Gipsplaat, Mass: 2.10344 kg; Gipsplaat, Component Volume (Net): 0.0026293 m3; Gipsplaat, Component Volume (Gross): 0.0026293 m3

# IfcBuildingElementProxy: Distinct Panel 269 x 600 x 20 (14)
In: 00 begane grond
Material: Gipsplaat
Name
3 x __Panel-D | Component Quantities - Gipsplaat, Mass: 2.51314 kg; Gipsplaat, Component Volume (Net): 0.00314143 m3; Gipsplaat, Component Volume (Gross): 0.00314143 m3
11 x __Panel-D

# IfcBuildingElementProxy: Distinct Panel 27 x 600 x 20 (4)
In: 01 eerste verdieping
Material: Gipsplaat
Name | Gipsplaat, Mass (kg) | Gipsplaat, Component Volume (Net) (m3) = Gipsplaat, Component Volume (Gross) (m3)
__Panel-D | 0.214264 | 0.000267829
__Panel-D | 0.211615 | 0.000264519
__Panel-D | 0.21294 | 0.000266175
__Panel-D | 0.210291 | 0.000262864

# IfcBuildingElementProxy: Distinct Panel 270 x 550 x 20, __Panel-D
In: 00 begane grond
Material: Gipsplaat
Component Quantities - Gipsplaat, Mass: 2.30627 kg; Gipsplaat, Component Volume (Net): 0.00288284 m3; Gipsplaat, Component Volume (Gross): 0.00288284 m3

# IfcBuildingElementProxy: Distinct Panel 270 x 600 x 20 (4)
In: 00 begane grond
Material: Gipsplaat
Name
2 x __Panel-D | Component Quantities - Gipsplaat, Mass: 2.51828 kg; Gipsplaat, Component Volume (Net): 0.00314785 m3; Gipsplaat, Component Volume (Gross): 0.00314785 m3
2 x __Panel-D

# IfcBuildingElementProxy: Distinct Panel 28 x 127 x 20, __Panel-D
In: 01 eerste verdieping
Material: Gipsplaat
Component Quantities - Gipsplaat, Mass: 0.0397973 kg; Gipsplaat, Component Volume (Net): 0.0000497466 m3; Gipsplaat, Component Volume (Gross): 0.0000497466 m3

# IfcBuildingElementProxy: Distinct Panel 28 x 23 x 20, __Panel-D
In: 00 begane grond
Material: Gipsplaat
Component Quantities - Gipsplaat, Mass: 0.00232532 kg; Gipsplaat, Component Volume (Net): 0.00000290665 m3; Gipsplaat, Component Volume (Gross): 0.00000290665 m3

# IfcBuildingElementProxy: Distinct Panel 28 x 34 x 20, __Panel-D
In: 01 eerste verdieping
Material: Gipsplaat
Component Quantities - Gipsplaat, Mass: 0.00404177 kg; Gipsplaat, Component Volume (Net): 0.00000505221 m3; Gipsplaat, Component Volume (Gross): 0.00000505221 m3

# IfcBuildingElementProxy: Distinct Panel 28 x 600 x 20 (3)
Material: Gipsplaat
Name | In | Gipsplaat, Mass (kg) | Gipsplaat, Component Volume (Net) (m3) = Gipsplaat, Component Volume (Gross) (m3)
__Panel-D | 00 begane grond | 3.48013 | 0.00435017
__Panel-D | 01 eerste verdieping | 0.215587 | 0.000269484
__Panel-D | 01 eerste verdieping | 2.61245 | 0.00326557

# IfcBuildingElementProxy: Distinct Panel 293 x 123 x 20, __Panel-D
In: 00 begane grond
Material: Gipsplaat
Component Quantities - Gipsplaat, Mass: 0.542323 kg; Gipsplaat, Component Volume (Net): 0.000677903 m3; Gipsplaat, Component Volume (Gross): 0.000677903 m3

# IfcBuildingElementProxy: Distinct Panel 293 x 600 x 20 (4)
In: 00 begane grond
Material: Gipsplaat
Name
2 x __Panel-D | Component Quantities - Gipsplaat, Mass: 2.73709 kg; Gipsplaat, Component Volume (Net): 0.00342136 m3; Gipsplaat, Component Volume (Gross): 0.00342136 m3
2 x __Panel-D

# IfcBuildingElementProxy: Distinct Panel 295 x 520 x 20, __Panel-D
In: 00 begane grond
Material: Gipsplaat
Component Quantities - Gipsplaat, Mass: 2.5411 kg; Gipsplaat, Component Volume (Net): 0.00317638 m3; Gipsplaat, Component Volume (Gross): 0.00317638 m3

# IfcBuildingElementProxy: Distinct Panel 295 x 575 x 20, __Panel-D
In: 00 begane grond
Material: Gipsplaat
Component Quantities - Gipsplaat, Mass: 2.64438 kg; Gipsplaat, Component Volume (Net): 0.00330547 m3; Gipsplaat, Component Volume (Gross): 0.00330547 m3

# IfcBuildingElementProxy: Distinct Panel 295 x 600 x 20, __Panel-D
In: 00 begane grond
Material: Gipsplaat
Component Quantities - Gipsplaat, Mass: 2.76081 kg; Gipsplaat, Component Volume (Net): 0.00345101 m3; Gipsplaat, Component Volume (Gross): 0.00345101 m3

# IfcBuildingElementProxy: Distinct Panel 30 x 600 x 20, __Panel-D
In: 01 eerste verdieping
Material: Gipsplaat
Component Quantities - Gipsplaat, Mass: 3.85093 kg; Gipsplaat, Component Volume (Net): 0.00481366 m3; Gipsplaat, Component Volume (Gross): 0.00481366 m3

# IfcBuildingElementProxy: Distinct Panel 300 x 1002 x 20, __Panel-D
In: 01 eerste verdieping
Material: Gipsplaat
Component Quantities - Gipsplaat, Mass: 4.70494 kg; Gipsplaat, Component Volume (Net): 0.00588117 m3; Gipsplaat, Component Volume (Gross): 0.00588117 m3

# IfcBuildingElementProxy: Distinct Panel 300 x 1026 x 20, __Panel-D
In: 01 eerste verdieping
Material: Gipsplaat
Component Quantities - Gipsplaat, Mass: 4.8174 kg; Gipsplaat, Component Volume (Net): 0.00602175 m3; Gipsplaat, Component Volume (Gross): 0.00602175 m3

# IfcBuildingElementProxy: Distinct Panel 300 x 1200 x 20, __Panel-D
In: 01 eerste verdieping
Material: Gipsplaat
Component Quantities - Gipsplaat, Mass: 5.63932 kg; Gipsplaat, Component Volume (Net): 0.00704914 m3; Gipsplaat, Component Volume (Gross): 0.00704914 m3

# IfcBuildingElementProxy: Distinct Panel 300 x 947 x 20, __Panel-D
In: 01 eerste verdieping
Material: Gipsplaat
Component Quantities - Gipsplaat, Mass: 4.44696 kg; Gipsplaat, Component Volume (Net): 0.0055587 m3; Gipsplaat, Component Volume (Gross): 0.0055587 m3

# IfcBuildingElementProxy: Distinct Panel 300 x 950 x 20, __Panel-D
In: 01 eerste verdieping
Material: Gipsplaat
Component Quantities - Gipsplaat, Mass: 4.45876 kg; Gipsplaat, Component Volume (Net): 0.00557345 m3; Gipsplaat, Component Volume (Gross): 0.00557345 m3

# IfcBuildingElementProxy: Distinct Panel 307 x 121 x 20, __Panel-D
In: 01 eerste verdieping
Material: Gipsplaat
Component Quantities - Gipsplaat, Mass: 8.5083 kg; Gipsplaat, Component Volume (Net): 0.0106354 m3; Gipsplaat, Component Volume (Gross): 0.0106354 m3

# IfcBuildingElementProxy: Distinct Panel 31 x 13 x 20, __Panel-D
In: 01 eerste verdieping
Material: Gipsplaat
Component Quantities - Gipsplaat, Mass: 0.00306593 kg; Gipsplaat, Component Volume (Net): 0.00000383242 m3; Gipsplaat, Component Volume (Gross): 0.00000383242 m3

# IfcBuildingElementProxy: Distinct Panel 31 x 600 x 20, __Panel-D
In: 01 eerste verdieping
Material: Gipsplaat
Component Quantities - Gipsplaat, Mass: 1.53698 kg; Gipsplaat, Component Volume (Net): 0.00192122 m3; Gipsplaat, Component Volume (Gross): 0.00192122 m3

# IfcBuildingElementProxy: Distinct Panel 310 x 260 x 20, __Panel-D
In: 01 eerste verdieping
Material: Gipsplaat
Component Quantities - Gipsplaat, Mass: 0.605028 kg; Gipsplaat, Component Volume (Net): 0.000756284 m3; Gipsplaat, Component Volume (Gross): 0.000756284 m3

# IfcBuildingElementProxy: Distinct Panel 310 x 600 x 20, __Panel-D
In: 01 eerste verdieping
Material: Gipsplaat
Component Quantities - Gipsplaat, Mass: 5.10442 kg; Gipsplaat, Component Volume (Net): 0.00638053 m3; Gipsplaat, Component Volume (Gross): 0.00638053 m3

# IfcBuildingElementProxy: Distinct Panel 317 x 179 x 20, __Panel-D
In: 01 eerste verdieping
Material: Gipsplaat
Component Quantities - Gipsplaat, Mass: 0.870898 kg; Gipsplaat, Component Volume (Net): 0.00108862 m3; Gipsplaat, Component Volume (Gross): 0.00108862 m3

# IfcBuildingElementProxy: Distinct Panel 317 x 321 x 20, __Panel-D
In: 01 eerste verdieping
Material: Gipsplaat
Component Quantities - Gipsplaat, Mass: 1.57863 kg; Gipsplaat, Component Volume (Net): 0.00197329 m3; Gipsplaat, Component Volume (Gross): 0.00197329 m3

# IfcBuildingElementProxy: Distinct Panel 317 x 449 x 20, __Panel-D
In: 01 eerste verdieping
Material: Gipsplaat
Component Quantities - Gipsplaat, Mass: 2.21891 kg; Gipsplaat, Component Volume (Net): 0.00277364 m3; Gipsplaat, Component Volume (Gross): 0.00277364 m3

# IfcBuildingElementProxy: Distinct Panel 317 x 600 x 20 (18)
In: 01 eerste verdieping
Material: Gipsplaat
Name
__Panel-D | Component Quantities - Gipsplaat, Mass: 2.97447 kg; Gipsplaat, Component Volume (Net): 0.00371809 m3; Gipsplaat, Component Volume (Gross): 0.00371809 m3
__Panel-D | Component Quantities - Gipsplaat, Mass: 2.97448 kg; Gipsplaat, Component Volume (Net): 0.00371809 m3; Gipsplaat, Component Volume (Gross): 0.00371809 m3
13 x __Panel-D
__Panel-D | Component Quantities - Gipsplaat, Mass: 2.97444 kg; Gipsplaat, Component Volume (Net): 0.00371805 m3; Gipsplaat, Component Volume (Gross): 0.00371805 m3
__Panel-D | Component Quantities - Gipsplaat, Mass: 2.97448 kg; Gipsplaat, Component Volume (Net): 0.0037181 m3; Gipsplaat, Component Volume (Gross): 0.0037181 m3
__Panel-D | Component Quantities - Gipsplaat, Mass: 2.97445 kg; Gipsplaat, Component Volume (Net): 0.00371807 m3; Gipsplaat, Component Volume (Gross): 0.00371807 m3

# IfcBuildingElementProxy: Distinct Panel 318 x 379 x 20, __Panel-D
In: 01 eerste verdieping
Material: Gipsplaat
Component Quantities - Gipsplaat, Mass: 0.917465 kg; Gipsplaat, Component Volume (Net): 0.00114683 m3; Gipsplaat, Component Volume (Gross): 0.00114683 m3

# IfcBuildingElementProxy: Distinct Panel 322 x 883 x 20, __Panel-D
In: 00 begane grond
Material: Gipsplaat
Component Quantities - Gipsplaat, Mass: 4.77265 kg; Gipsplaat, Component Volume (Net): 0.00596582 m3; Gipsplaat, Component Volume (Gross): 0.00596582 m3

# IfcBuildingElementProxy: Distinct Panel 327 x 390 x 20, __Panel-D
In: 01 eerste verdieping
Material: Gipsplaat
Component Quantities - Gipsplaat, Mass: 0.973071 kg; Gipsplaat, Component Volume (Net): 0.00121634 m3; Gipsplaat, Component Volume (Gross): 0.00121634 m3

# IfcBuildingElementProxy: Distinct Panel 327 x 549 x 20, __Panel-D
In: 01 eerste verdieping
Material: Gipsplaat
Component Quantities - Gipsplaat, Mass: 2.38707 kg; Gipsplaat, Component Volume (Net): 0.00298384 m3; Gipsplaat, Component Volume (Gross): 0.00298384 m3

# IfcBuildingElementProxy: Distinct Panel 328 x 503 x 20, __Panel-D
In: 00 begane grond
Material: Gipsplaat
Component Quantities - Gipsplaat, Mass: 2.56973 kg; Gipsplaat, Component Volume (Net): 0.00321217 m3; Gipsplaat, Component Volume (Gross): 0.00321217 m3

# IfcBuildingElementProxy: Distinct Panel 328 x 597 x 20, __Panel-D
In: 01 eerste verdieping
Material: Gipsplaat
Component Quantities - Gipsplaat, Mass: 3.05602 kg; Gipsplaat, Component Volume (Net): 0.00382002 m3; Gipsplaat, Component Volume (Gross): 0.00382002 m3

# IfcBuildingElementProxy: Distinct Panel 328 x 600 x 20 (5)
Material: Gipsplaat
Name | In | Gipsplaat, Mass (kg) | Gipsplaat, Component Volume (Net) (m3) = Gipsplaat, Component Volume (Gross) (m3)
__Panel-D | 00 begane grond | 2.06618 | 0.00258273
__Panel-D | 00 begane grond | 3.07026 | 0.00383783
2 x __Panel-D | 01 eerste verdieping | 3.07105 | 0.00383882
__Panel-D | 01 eerste verdieping

# IfcBuildingElementProxy: Distinct Panel 329 x 328 x 20, __Panel-D
In: 00 begane grond
Material: Gipsplaat
Component Quantities - Gipsplaat, Mass: 1.67417 kg; Gipsplaat, Component Volume (Net): 0.00209272 m3; Gipsplaat, Component Volume (Gross): 0.00209272 m3

# IfcBuildingElementProxy: Distinct Panel 329 x 437 x 20, __Panel-D
In: 00 begane grond
Material: Gipsplaat
Component Quantities - Gipsplaat, Mass: 2.24482 kg; Gipsplaat, Component Volume (Net): 0.00280602 m3; Gipsplaat, Component Volume (Gross): 0.00280602 m3

# IfcBuildingElementProxy: Distinct Panel 329 x 600 x 20 (2)
In: 00 begane grond
Material: Gipsplaat
Name
__Panel-D | Component Quantities - Gipsplaat, Mass: 3.08848 kg; Gipsplaat, Component Volume (Net): 0.0038606 m3; Gipsplaat, Component Volume (Gross): 0.0038606 m3
__Panel-D

# IfcBuildingElementProxy: Distinct Panel 33 x 1012 x 20, __Panel-D
In: 00 begane grond
Material: Gipsplaat
Component Quantities - Gipsplaat, Mass: 0.447544 kg; Gipsplaat, Component Volume (Net): 0.00055943 m3; Gipsplaat, Component Volume (Gross): 0.00055943 m3

# IfcBuildingElementProxy: Distinct Panel 33 x 1042 x 20, __Panel-D
In: 00 begane grond
Material: Gipsplaat
Component Quantities - Gipsplaat, Mass: 0.460765 kg; Gipsplaat, Component Volume (Net): 0.000575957 m3; Gipsplaat, Component Volume (Gross): 0.000575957 m3

# IfcBuildingElementProxy: Distinct Panel 333 x 11 x 20, __Panel-D
In: 01 eerste verdieping
Material: Gipsplaat
Component Quantities - Gipsplaat, Mass: 5.6191 kg; Gipsplaat, Component Volume (Net): 0.00702388 m3; Gipsplaat, Component Volume (Gross): 0.00702388 m3

# IfcBuildingElementProxy: Distinct Panel 333 x 149 x 20, __Panel-D
In: 01 eerste verdieping
Material: Gipsplaat
Component Quantities - Gipsplaat, Mass: 0.776031 kg; Gipsplaat, Component Volume (Net): 0.000970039 m3; Gipsplaat, Component Volume (Gross): 0.000970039 m3

# IfcBuildingElementProxy: Distinct Panel 333 x 572 x 20 (2)
In: 01 eerste verdieping
Material: Gipsplaat
Name | Gipsplaat, Mass (kg) | Gipsplaat, Component Volume (Net) (m3) = Gipsplaat, Component Volume (Gross) (m3)
__Panel-D | 2.97144 | 0.0037143
__Panel-D | 2.97888 | 0.0037236

# IfcBuildingElementProxy: Distinct Panel 333 x 600 x 20 (14)
In: 01 eerste verdieping
Material: Gipsplaat
Name
2 x __Panel-D | Component Quantities - Gipsplaat, Mass: 3.11865 kg; Gipsplaat, Component Volume (Net): 0.00389832 m3; Gipsplaat, Component Volume (Gross): 0.00389832 m3
10 x __Panel-D
__Panel-D | Component Quantities - Gipsplaat, Mass: 3.12647 kg; Gipsplaat, Component Volume (Net): 0.00390808 m3; Gipsplaat, Component Volume (Gross): 0.00390808 m3
__Panel-D | Component Quantities - Gipsplaat, Mass: 5.51261 kg; Gipsplaat, Component Volume (Net): 0.00689076 m3; Gipsplaat, Component Volume (Gross): 0.00689076 m3

# IfcBuildingElementProxy: Distinct Panel 334 x 281 x 20, __Panel-D
In: 01 eerste verdieping
Material: Gipsplaat
Component Quantities - Gipsplaat, Mass: 0.708857 kg; Gipsplaat, Component Volume (Net): 0.000886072 m3; Gipsplaat, Component Volume (Gross): 0.000886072 m3

# IfcBuildingElementProxy: Distinct Panel 334 x 600 x 20, __Panel-D
In: 01 eerste verdieping
Material: Gipsplaat
Component Quantities - Gipsplaat, Mass: 5.19625 kg; Gipsplaat, Component Volume (Net): 0.00649531 m3; Gipsplaat, Component Volume (Gross): 0.00649531 m3

# IfcBuildingElementProxy: Distinct Panel 335 x 399 x 20, __Panel-D
In: 00 begane grond
Material: Gipsplaat
Component Quantities - Gipsplaat, Mass: 1.02063 kg; Gipsplaat, Component Volume (Net): 0.00127579 m3; Gipsplaat, Component Volume (Gross): 0.00127579 m3

# IfcBuildingElementProxy: Distinct Panel 339 x 404 x 20, __Panel-D
In: 01 eerste verdieping
Material: Gipsplaat
Component Quantities - Gipsplaat, Mass: 1.04436 kg; Gipsplaat, Component Volume (Net): 0.00130545 m3; Gipsplaat, Component Volume (Gross): 0.00130545 m3

# IfcBuildingElementProxy: Distinct Panel 340 x 328 x 20, __Panel-D
In: 00 begane grond
Material: Gipsplaat
Component Quantities - Gipsplaat, Mass: 1.73002 kg; Gipsplaat, Component Volume (Net): 0.00216252 m3; Gipsplaat, Component Volume (Gross): 0.00216252 m3

# IfcBuildingElementProxy: Distinct Panel 340 x 437 x 20, __Panel-D
In: 00 begane grond
Material: Gipsplaat
Component Quantities - Gipsplaat, Mass: 2.24575 kg; Gipsplaat, Component Volume (Net): 0.00280719 m3; Gipsplaat, Component Volume (Gross): 0.00280719 m3

# IfcBuildingElementProxy: Distinct Panel 340 x 600 x 20 (2)
In: 00 begane grond
Material: Gipsplaat
Name
__Panel-D | Component Quantities - Gipsplaat, Mass: 3.1915 kg; Gipsplaat, Component Volume (Net): 0.00398938 m3; Gipsplaat, Component Volume (Gross): 0.00398938 m3
__Panel-D

# IfcBuildingElementProxy: Distinct Panel 343 x 13 x 20, __Panel-D
In: 01 eerste verdieping
Material: Gipsplaat
Component Quantities - Gipsplaat, Mass: 0.0405088 kg; Gipsplaat, Component Volume (Net): 0.0000506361 m3; Gipsplaat, Component Volume (Gross): 0.0000506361 m3

# IfcBuildingElementProxy: Distinct Panel 343 x 590 x 20, __Panel-D
In: 01 eerste verdieping
Material: Gipsplaat
Component Quantities - Gipsplaat, Mass: 3.15958 kg; Gipsplaat, Component Volume (Net): 0.00394948 m3; Gipsplaat, Component Volume (Gross): 0.00394948 m3

# IfcBuildingElementProxy: Distinct Panel 343 x 600 x 20 (4)
In: 01 eerste verdieping
Material: Gipsplaat
Name
__Panel-D | Component Quantities - Gipsplaat, Mass: 3.21369 kg; Gipsplaat, Component Volume (Net): 0.00401711 m3; Gipsplaat, Component Volume (Gross): 0.00401711 m3
3 x __Panel-D

# IfcBuildingElementProxy: Distinct Panel 343 x 908 x 20, __Panel-D
In: 00 begane grond
Material: Gipsplaat
Component Quantities - Gipsplaat, Mass: 4.90606 kg; Gipsplaat, Component Volume (Net): 0.00613257 m3; Gipsplaat, Component Volume (Gross): 0.00613257 m3

# IfcBuildingElementProxy: Distinct Panel 346 x 597 x 20, __Panel-D
In: 01 eerste verdieping
Material: Gipsplaat
Component Quantities - Gipsplaat, Mass: 3.22958 kg; Gipsplaat, Component Volume (Net): 0.00403697 m3; Gipsplaat, Component Volume (Gross): 0.00403697 m3

# IfcBuildingElementProxy: Distinct Panel 350 x 332 x 20, __Panel-D
In: 00 begane grond
Material: Gipsplaat
Component Quantities - Gipsplaat, Mass: 1.80731 kg; Gipsplaat, Component Volume (Net): 0.00225914 m3; Gipsplaat, Component Volume (Gross): 0.00225914 m3

# IfcBuildingElementProxy: Distinct Panel 353 x 67 x 20, __Panel-D
In: 00 begane grond
Material: Gipsplaat
Component Quantities - Gipsplaat, Mass: 0.342916 kg; Gipsplaat, Component Volume (Net): 0.000428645 m3; Gipsplaat, Component Volume (Gross): 0.000428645 m3

# IfcBuildingElementProxy: Distinct Panel 356 x 424 x 20, __Panel-D
In: 00 begane grond
Material: Gipsplaat
Component Quantities - Gipsplaat, Mass: 1.15421 kg; Gipsplaat, Component Volume (Net): 0.00144277 m3; Gipsplaat, Component Volume (Gross): 0.00144277 m3

# IfcBuildingElementProxy: Distinct Panel 356 x 494 x 20, __Panel-D
In: 00 begane grond
Material: Gipsplaat
Component Quantities - Gipsplaat, Mass: 2.05238 kg; Gipsplaat, Component Volume (Net): 0.00256548 m3; Gipsplaat, Component Volume (Gross): 0.00256548 m3

# IfcBuildingElementProxy: Distinct Panel 357 x 1018 x 20, __Panel-D
In: 00 begane grond
Material: Gipsplaat
Component Quantities - Gipsplaat, Mass: 5.70217 kg; Gipsplaat, Component Volume (Net): 0.00712771 m3; Gipsplaat, Component Volume (Gross): 0.00712771 m3

# IfcBuildingElementProxy: Distinct Panel 357 x 1175 x 20, __Panel-D
In: 00 begane grond
Material: Gipsplaat
Component Quantities - Gipsplaat, Mass: 10.3331 kg; Gipsplaat, Component Volume (Net): 0.0129164 m3; Gipsplaat, Component Volume (Gross): 0.0129164 m3

# IfcBuildingElementProxy: Distinct Panel 357 x 993 x 20, __Panel-D
In: 00 begane grond
Material: Gipsplaat
Component Quantities - Gipsplaat, Mass: 5.5614 kg; Gipsplaat, Component Volume (Net): 0.00695175 m3; Gipsplaat, Component Volume (Gross): 0.00695175 m3

# IfcBuildingElementProxy: Distinct Panel 358 x 432 x 20 (2)
In: 00 begane grond
Material: Gipsplaat
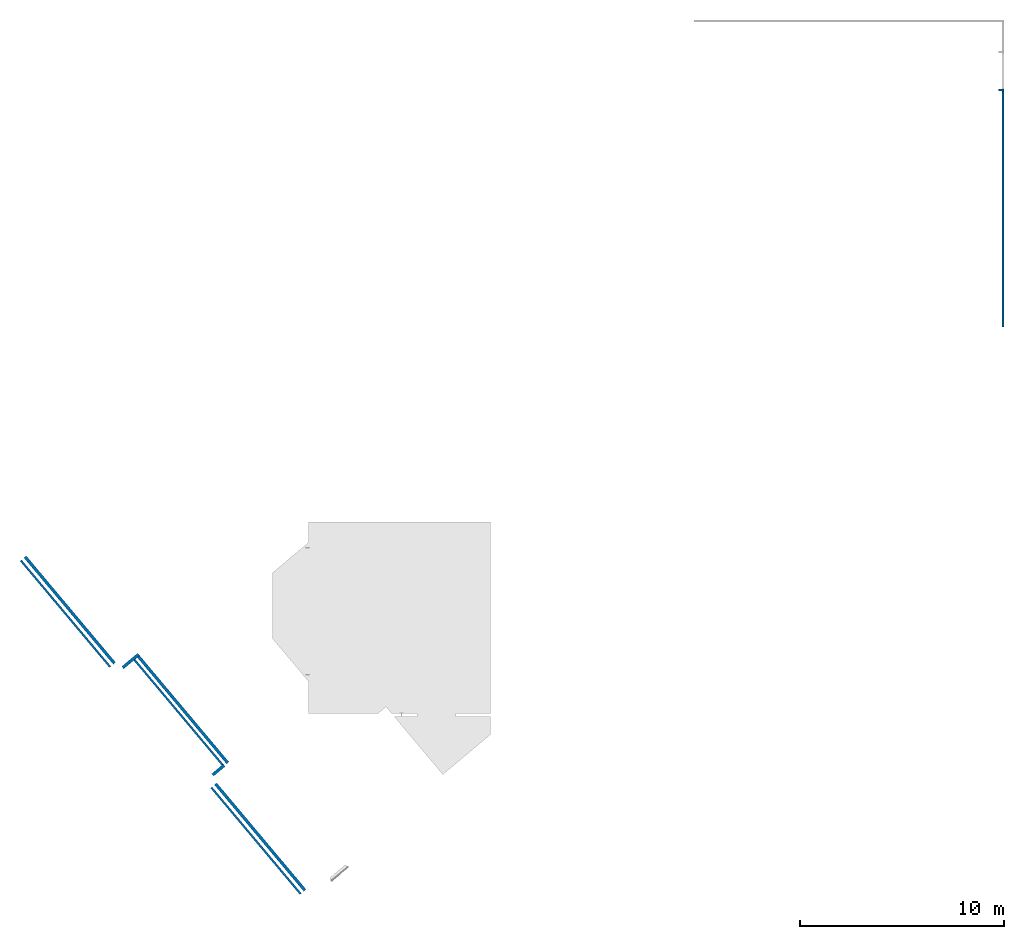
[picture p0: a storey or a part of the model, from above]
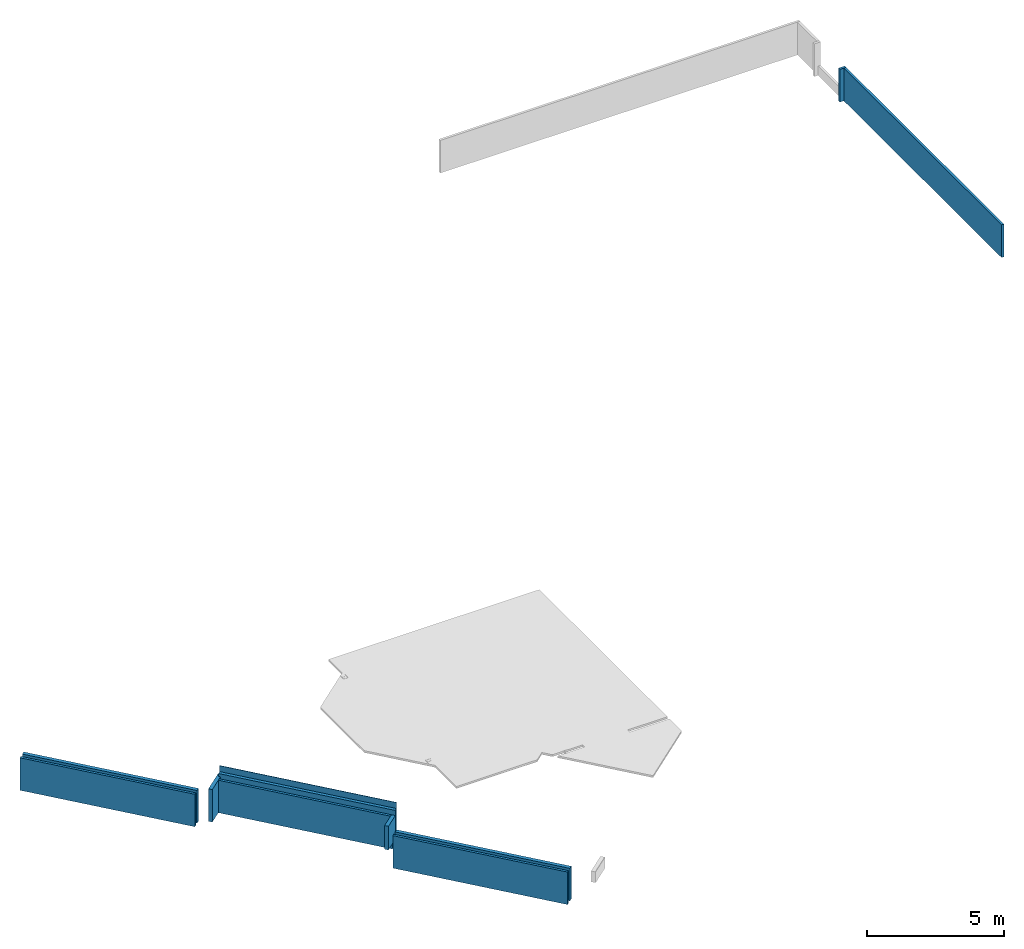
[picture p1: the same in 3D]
Properties of the parts of a building model (IFC2X3), part 6 of 11

# IfcBuildingElementProxy: Distinct Panel 358 x 432 x 20 (2)
Component Quantities - Gipsplaat, Mass: 2.40985 kg; Gipsplaat, Component Volume (Net): 0.00301231 m3; Gipsplaat, Component Volume (Gross): 0.00301231 m3

# IfcBuildingElementProxy: Distinct Panel 358 x 600 x 20 (3)
In: 00 begane grond
Material: Gipsplaat
Name | Gipsplaat, Mass (kg) | Gipsplaat, Component Volume (Net) (m3) = Gipsplaat, Component Volume (Gross) (m3)
2 x __Panel-D | 3.35677 | 0.00419596
__Panel-D

# IfcBuildingElementProxy: Distinct Panel 359 x 301 x 20, __Panel-D
In: 00 begane grond
Material: Gipsplaat
Component Quantities - Gipsplaat, Mass: 0.820834 kg; Gipsplaat, Component Volume (Net): 0.00102604 m3; Gipsplaat, Component Volume (Gross): 0.00102604 m3

# IfcBuildingElementProxy: Distinct Panel 359 x 600 x 20, __Panel-D
In: 00 begane grond
Material: Gipsplaat
Component Quantities - Gipsplaat, Mass: 5.27981 kg; Gipsplaat, Component Volume (Net): 0.00659976 m3; Gipsplaat, Component Volume (Gross): 0.00659976 m3

# IfcBuildingElementProxy: Distinct Panel 36 x 30 x 20, __Panel-D
In: 01 eerste verdieping
Material: Gipsplaat
Component Quantities - Gipsplaat, Mass: 0.00479949 kg; Gipsplaat, Component Volume (Net): 0.00000599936 m3; Gipsplaat, Component Volume (Gross): 0.00000599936 m3

# IfcBuildingElementProxy: Distinct Panel 360 x 600 x 20 (11)
In: 00 begane grond
Material: Gipsplaat
Name
3 x __Panel-D | Component Quantities - Gipsplaat, Mass: 3.38204 kg; Gipsplaat, Component Volume (Net): 0.00422755 m3; Gipsplaat, Component Volume (Gross): 0.00422755 m3
7 x __Panel-D
__Panel-D | Component Quantities - Gipsplaat, Mass: 3.0805 kg; Gipsplaat, Component Volume (Net): 0.00385063 m3; Gipsplaat, Component Volume (Gross): 0.00385063 m3

# IfcBuildingElementProxy: Distinct Panel 362 x 592 x 20, __Panel-D
In: 00 begane grond
Material: Gipsplaat
Component Quantities - Gipsplaat, Mass: 4.32093 kg; Gipsplaat, Component Volume (Net): 0.00540116 m3; Gipsplaat, Component Volume (Gross): 0.00540116 m3

# IfcBuildingElementProxy: Distinct Panel 368 x 561 x 20, __Panel-D
In: 00 begane grond
Material: Gipsplaat
Component Quantities - Gipsplaat, Mass: 3.23009 kg; Gipsplaat, Component Volume (Net): 0.00403761 m3; Gipsplaat, Component Volume (Gross): 0.00403761 m3

# IfcBuildingElementProxy: Distinct Panel 372 x 564 x 20, __Panel-D
In: 00 begane grond
Material: Gipsplaat
Component Quantities - Gipsplaat, Mass: 4.19674 kg; Gipsplaat, Component Volume (Net): 0.00524593 m3; Gipsplaat, Component Volume (Gross): 0.00524593 m3

# IfcBuildingElementProxy: Distinct Panel 373 x 313 x 20, __Panel-D
In: 00 begane grond
Material: Gipsplaat
Component Quantities - Gipsplaat, Mass: 0.888321 kg; Gipsplaat, Component Volume (Net): 0.0011104 m3; Gipsplaat, Component Volume (Gross): 0.0011104 m3

# IfcBuildingElementProxy: Distinct Panel 373 x 600 x 20, __Panel-D
In: 00 begane grond
Material: Gipsplaat
Component Quantities - Gipsplaat, Mass: 5.32376 kg; Gipsplaat, Component Volume (Net): 0.0066547 m3; Gipsplaat, Component Volume (Gross): 0.0066547 m3

# IfcBuildingElementProxy: Distinct Panel 377 x 267 x 20, __Panel-D
In: 01 eerste verdieping
Material: Gipsplaat
Component Quantities - Gipsplaat, Mass: 2.34222 kg; Gipsplaat, Component Volume (Net): 0.00292778 m3; Gipsplaat, Component Volume (Gross): 0.00292778 m3

# IfcBuildingElementProxy: Distinct Panel 378 x 445 x 20, __Panel-D
In: 00 begane grond
Material: Gipsplaat
Component Quantities - Gipsplaat, Mass: 2.6244 kg; Gipsplaat, Component Volume (Net): 0.0032805 m3; Gipsplaat, Component Volume (Gross): 0.0032805 m3

# IfcBuildingElementProxy: Distinct Panel 378 x 600 x 20 (7)
In: 00 begane grond
Material: Gipsplaat
Name
3 x __Panel-D | Component Quantities - Gipsplaat, Mass: 3.55098 kg; Gipsplaat, Component Volume (Net): 0.00443873 m3; Gipsplaat, Component Volume (Gross): 0.00443873 m3
4 x __Panel-D

# IfcBuildingElementProxy: Distinct Panel 380 x 350 x 20, __Panel-D
In: 00 begane grond
Material: Gipsplaat
Component Quantities - Gipsplaat, Mass: 2.06897 kg; Gipsplaat, Component Volume (Net): 0.00258621 m3; Gipsplaat, Component Volume (Gross): 0.00258621 m3

# IfcBuildingElementProxy: Distinct Panel 380 x 475 x 20, __Panel-D
In: 00 begane grond
Material: Gipsplaat
Component Quantities - Gipsplaat, Mass: 2.81907 kg; Gipsplaat, Component Volume (Net): 0.00352383 m3; Gipsplaat, Component Volume (Gross): 0.00352383 m3

# IfcBuildingElementProxy: Distinct Panel 380 x 600 x 20 (4)
In: 00 begane grond
Material: Gipsplaat
Name
2 x __Panel-D | Component Quantities - Gipsplaat, Mass: 3.57047 kg; Gipsplaat, Component Volume (Net): 0.00446309 m3; Gipsplaat, Component Volume (Gross): 0.00446309 m3
2 x __Panel-D

# IfcBuildingElementProxy: Distinct Panel 385 x 458 x 20, __Panel-D
In: 00 begane grond
Material: Gipsplaat
Component Quantities - Gipsplaat, Mass: 1.35317 kg; Gipsplaat, Component Volume (Net): 0.00169147 m3; Gipsplaat, Component Volume (Gross): 0.00169147 m3

# IfcBuildingElementProxy: Distinct Panel 387 x 600 x 20 (3)
In: 00 begane grond
Material: Gipsplaat
Name | Gipsplaat, Mass (kg) | Gipsplaat, Component Volume (Net) (m3) = Gipsplaat, Component Volume (Gross) (m3)
2 x __Panel-D | 3.64123 | 0.00455154
__Panel-D

# IfcBuildingElementProxy: Distinct Panel 388 x 450 x 20, __Panel-D
In: 00 begane grond
Material: Gipsplaat
Component Quantities - Gipsplaat, Mass: 2.72997 kg; Gipsplaat, Component Volume (Net): 0.00341247 m3; Gipsplaat, Component Volume (Gross): 0.00341247 m3

# IfcBuildingElementProxy: Distinct Panel 388 x 475 x 20, __Panel-D
In: 00 begane grond
Material: Gipsplaat
Component Quantities - Gipsplaat, Mass: 2.88333 kg; Gipsplaat, Component Volume (Net): 0.00360417 m3; Gipsplaat, Component Volume (Gross): 0.00360417 m3

# IfcBuildingElementProxy: Distinct Panel 388 x 600 x 20 (3)
In: 00 begane grond
Material: Gipsplaat
Name | Gipsplaat, Mass (kg) | Gipsplaat, Component Volume (Net) (m3) = Gipsplaat, Component Volume (Gross) (m3)
2 x __Panel-D | 3.64998 | 0.00456247
__Panel-D

# IfcBuildingElementProxy: Distinct Panel 39 x 47 x 20, __Panel-D
In: 01 eerste verdieping
Material: Gipsplaat
Component Quantities - Gipsplaat, Mass: 0.00925757 kg; Gipsplaat, Component Volume (Net): 0.000011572 m3; Gipsplaat, Component Volume (Gross): 0.000011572 m3

# IfcBuildingElementProxy: Distinct Panel 39 x 600 x 20, __Panel-D
In: 01 eerste verdieping
Material: Gipsplaat
Component Quantities - Gipsplaat, Mass: 2.71309 kg; Gipsplaat, Component Volume (Net): 0.00339136 m3; Gipsplaat, Component Volume (Gross): 0.00339136 m3

# IfcBuildingElementProxy: Distinct Panel 392 x 950 x 20, __Panel-D
In: 01 eerste verdieping
Material: Gipsplaat
Component Quantities - Gipsplaat, Mass: 7.52524 kg; Gipsplaat, Component Volume (Net): 0.00940655 m3; Gipsplaat, Component Volume (Gross): 0.00940655 m3

# IfcBuildingElementProxy: Distinct Panel 393 x 1130 x 20, __Panel-D
In: 01 eerste verdieping
Material: Gipsplaat
Component Quantities - Gipsplaat, Mass: 6.97518 kg; Gipsplaat, Component Volume (Net): 0.00871898 m3; Gipsplaat, Component Volume (Gross): 0.00871898 m3

# IfcBuildingElementProxy: Distinct Panel 393 x 1200 x 20, __Panel-D
In: 01 eerste verdieping
Material: Gipsplaat
Component Quantities - Gipsplaat, Mass: 7.13135 kg; Gipsplaat, Component Volume (Net): 0.00891419 m3; Gipsplaat, Component Volume (Gross): 0.00891419 m3

# IfcBuildingElementProxy: Distinct Panel 400 x 470 x 20, __Panel-D
In: 00 begane grond
Material: Gipsplaat
Component Quantities - Gipsplaat, Mass: 2.93537 kg; Gipsplaat, Component Volume (Net): 0.00366922 m3; Gipsplaat, Component Volume (Gross): 0.00366922 m3

# IfcBuildingElementProxy: Distinct Panel 400 x 495 x 20, __Panel-D
In: 00 begane grond
Material: Gipsplaat
Component Quantities - Gipsplaat, Mass: 3.09673 kg; Gipsplaat, Component Volume (Net): 0.00387092 m3; Gipsplaat, Component Volume (Gross): 0.00387092 m3

# IfcBuildingElementProxy: Distinct Panel 400 x 497 x 20 (2)
In: 00 begane grond
Material: Gipsplaat
Component Quantities - Gipsplaat, Mass: 3.10959 kg; Gipsplaat, Component Volume (Net): 0.00388699 m3; Gipsplaat, Component Volume (Gross): 0.00388699 m3

# IfcBuildingElementProxy: Distinct Panel 400 x 539 x 20, __Panel-D
In: 00 begane grond
Material: Gipsplaat
Component Quantities - Gipsplaat, Mass: 3.37349 kg; Gipsplaat, Component Volume (Net): 0.00421687 m3; Gipsplaat, Component Volume (Gross): 0.00421687 m3

# IfcBuildingElementProxy: Distinct Panel 400 x 544 x 20, __Panel-D
In: 00 begane grond
Material: Gipsplaat
Component Quantities - Gipsplaat, Mass: 3.40384 kg; Gipsplaat, Component Volume (Net): 0.0042548 m3; Gipsplaat, Component Volume (Gross): 0.0042548 m3

# IfcBuildingElementProxy: Distinct Panel 400 x 600 x 20 (28)
In: 00 begane grond
Material: Gipsplaat
Name
__Panel-D | Component Quantities - Gipsplaat, Mass: 3.75823 kg; Gipsplaat, Component Volume (Net): 0.00469778 m3; Gipsplaat, Component Volume (Gross): 0.00469778 m3
__Panel-D | Component Quantities - Gipsplaat, Mass: 3.75823 kg; Gipsplaat, Component Volume (Net): 0.00469779 m3; Gipsplaat, Component Volume (Gross): 0.00469779 m3
2 x __Panel-D | Component Quantities - Gipsplaat, Mass: 3.75822 kg; Gipsplaat, Component Volume (Net): 0.00469778 m3; Gipsplaat, Component Volume (Gross): 0.00469778 m3
17 x __Panel-D
4 x __Panel-D | Component Quantities - Gipsplaat, Mass: 3.76057 kg; Gipsplaat, Component Volume (Net): 0.00470071 m3; Gipsplaat, Component Volume (Gross): 0.00470071 m3
__Panel-D | Component Quantities - Gipsplaat, Mass: 3.41699 kg; Gipsplaat, Component Volume (Net): 0.00427124 m3; Gipsplaat, Component Volume (Gross): 0.00427124 m3
__Panel-D | Component Quantities - Gipsplaat, Mass: 3.76016 kg; Gipsplaat, Component Volume (Net): 0.00470019 m3; Gipsplaat, Component Volume (Gross): 0.00470019 m3
__Panel-D | Component Quantities - Gipsplaat, Mass: 3.76015 kg; Gipsplaat, Component Volume (Net): 0.00470019 m3; Gipsplaat, Component Volume (Gross): 0.00470019 m3

# IfcBuildingElementProxy: Distinct Panel 403 x 62 x 20, __Panel-D
In: 00 begane grond
Material: Gipsplaat
Component Quantities - Gipsplaat, Mass: 3.34321 kg; Gipsplaat, Component Volume (Net): 0.00417901 m3; Gipsplaat, Component Volume (Gross): 0.00417901 m3

# IfcBuildingElementProxy: Distinct Panel 406 x 138 x 20, __Panel-D
In: 01 eerste verdieping
Material: Gipsplaat
Component Quantities - Gipsplaat, Mass: 0.90193 kg; Gipsplaat, Component Volume (Net): 0.00112741 m3; Gipsplaat, Component Volume (Gross): 0.00112741 m3

# IfcBuildingElementProxy: Distinct Panel 413 x 342 x 20, __Panel-D
In: 00 begane grond
Material: Gipsplaat
Component Quantities - Gipsplaat, Mass: 2.19957 kg; Gipsplaat, Component Volume (Net): 0.00274947 m3; Gipsplaat, Component Volume (Gross): 0.00274947 m3

# IfcBuildingElementProxy: Distinct Panel 413 x 600 x 20 (4)
Material: Gipsplaat
Name | In | Gipsplaat, Mass (kg) | Gipsplaat, Component Volume (Net) (m3) = Gipsplaat, Component Volume (Gross) (m3)
__Panel-D | 00 begane grond | 3.88797 | 0.00485997
__Panel-D | 00 begane grond | 4.02386 | 0.00502983
__Panel-D | 00 begane grond
__Panel-D | 01 eerste verdieping | 3.72223 | 0.00465279

# IfcBuildingElementProxy: Distinct Panel 415 x 531 x 20, __Panel-D
In: 01 eerste verdieping
Material: Gipsplaat
Component Quantities - Gipsplaat, Mass: 1.71707 kg; Gipsplaat, Component Volume (Net): 0.00214633 m3; Gipsplaat, Component Volume (Gross): 0.00214633 m3

# IfcBuildingElementProxy: Distinct Panel 418 x 18 x 20, __Panel-D
In: 00 begane grond
Material: Gipsplaat
Component Quantities - Gipsplaat, Mass: 3.48794 kg; Gipsplaat, Component Volume (Net): 0.00435993 m3; Gipsplaat, Component Volume (Gross): 0.00435993 m3

# IfcBuildingElementProxy: Distinct Panel 418 x 450 x 20, __Panel-D
In: 00 begane grond
Material: Gipsplaat
Component Quantities - Gipsplaat, Mass: 2.93788 kg; Gipsplaat, Component Volume (Net): 0.00367235 m3; Gipsplaat, Component Volume (Gross): 0.00367235 m3

# IfcBuildingElementProxy: Distinct Panel 418 x 475 x 20, __Panel-D
In: 00 begane grond
Material: Gipsplaat
Component Quantities - Gipsplaat, Mass: 3.10292 kg; Gipsplaat, Component Volume (Net): 0.00387865 m3; Gipsplaat, Component Volume (Gross): 0.00387865 m3

# IfcBuildingElementProxy: Distinct Panel 418 x 600 x 20 (2)
In: 00 begane grond
Material: Gipsplaat
Component Quantities - Gipsplaat, Mass: 3.92794 kg; Gipsplaat, Component Volume (Net): 0.00490993 m3; Gipsplaat, Component Volume (Gross): 0.00490993 m3

# IfcBuildingElementProxy: Distinct Panel 420 x 550 x 20, __Panel-D
In: 00 begane grond
Material: Gipsplaat
Component Quantities - Gipsplaat, Mass: 3.61414 kg; Gipsplaat, Component Volume (Net): 0.00451768 m3; Gipsplaat, Component Volume (Gross): 0.00451768 m3

# IfcBuildingElementProxy: Distinct Panel 420 x 564 x 20, __Panel-D
In: 00 begane grond
Material: Gipsplaat
Component Quantities - Gipsplaat, Mass: 3.707 kg; Gipsplaat, Component Volume (Net): 0.00463375 m3; Gipsplaat, Component Volume (Gross): 0.00463375 m3

# IfcBuildingElementProxy: Distinct Panel 420 x 600 x 20 (7)
In: 00 begane grond
Material: Gipsplaat
Name
2 x __Panel-D | Component Quantities - Gipsplaat, Mass: 3.94638 kg; Gipsplaat, Component Volume (Net): 0.00493298 m3; Gipsplaat, Component Volume (Gross): 0.00493298 m3
5 x __Panel-D

# IfcBuildingElementProxy: Distinct Panel 422 x 600 x 20, __Panel-D
In: 00 begane grond
Material: Gipsplaat
Component Quantities - Gipsplaat, Mass: 4.23382 kg; Gipsplaat, Component Volume (Net): 0.00529228 m3; Gipsplaat, Component Volume (Gross): 0.00529228 m3

# IfcBuildingElementProxy: Distinct Panel 425 x 356 x 20, __Panel-D
In: 01 eerste verdieping
Material: Gipsplaat
Component Quantities - Gipsplaat, Mass: 1.15761 kg; Gipsplaat, Component Volume (Net): 0.00144701 m3; Gipsplaat, Component Volume (Gross): 0.00144701 m3

# IfcBuildingElementProxy: Distinct Panel 425 x 432 x 20 (2)
In: 00 begane grond
Material: Gipsplaat
Component Quantities - Gipsplaat, Mass: 2.87063 kg; Gipsplaat, Component Volume (Net): 0.00358829 m3; Gipsplaat, Component Volume (Gross): 0.00358829 m3

# IfcBuildingElementProxy: Distinct Panel 425 x 507 x 20, __Panel-D
In: 01 eerste verdieping
Material: Gipsplaat
Component Quantities - Gipsplaat, Mass: 1.65878 kg; Gipsplaat, Component Volume (Net): 0.00207347 m3; Gipsplaat, Component Volume (Gross): 0.00207347 m3

# IfcBuildingElementProxy: Distinct Panel 425 x 600 x 20 (8)
Material: Gipsplaat
Name | In | Gipsplaat, Mass (kg) | Gipsplaat, Component Volume (Net) (m3) = Gipsplaat, Component Volume (Gross) (m3)
2 x __Panel-D | 00 begane grond | 3.99861 | 0.00499826
__Panel-D | 00 begane grond
__Panel-D | 01 eerste verdieping | 5.46169 | 0.00682712
__Panel-D | 01 eerste verdieping | 3.99788 | 0.00499735
2 x __Panel-D | 01 eerste verdieping
__Panel-D | 01 eerste verdieping | 5.19734 | 0.00649667

# IfcBuildingElementProxy: Distinct Panel 427 x 30 x 20, __Panel-D
In: 00 begane grond
Material: Gipsplaat
Component Quantities - Gipsplaat, Mass: 0.168141 kg; Gipsplaat, Component Volume (Net): 0.000210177 m3; Gipsplaat, Component Volume (Gross): 0.000210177 m3

# IfcBuildingElementProxy: Distinct Panel 427 x 600 x 20, __Panel-D
In: 00 begane grond
Material: Gipsplaat
Component Quantities - Gipsplaat, Mass: 4.11743 kg; Gipsplaat, Component Volume (Net): 0.00514679 m3; Gipsplaat, Component Volume (Gross): 0.00514679 m3

# IfcBuildingElementProxy: Distinct Panel 43 x 52 x 20, __Panel-D
In: 01 eerste verdieping
Material: Gipsplaat
Component Quantities - Gipsplaat, Mass: 0.0119777 kg; Gipsplaat, Component Volume (Net): 0.0000149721 m3; Gipsplaat, Component Volume (Gross): 0.0000149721 m3

# IfcBuildingElementProxy: Distinct Panel 43 x 600 x 20, __Panel-D
In: 01 eerste verdieping
Material: Gipsplaat
Component Quantities - Gipsplaat, Mass: 2.75387 kg; Gipsplaat, Component Volume (Net): 0.00344234 m3; Gipsplaat, Component Volume (Gross): 0.00344234 m3

# IfcBuildingElementProxy: Distinct Panel 432 x 193 x 20, __Panel-D
In: 00 begane grond
Material: Gipsplaat
Component Quantities - Gipsplaat, Mass: 3.64697 kg; Gipsplaat, Component Volume (Net): 0.00455871 m3; Gipsplaat, Component Volume (Gross): 0.00455871 m3

# IfcBuildingElementProxy: Distinct Panel 432 x 471 x 20 (2)
In: 00 begane grond
Material: Gipsplaat
Component Quantities - Gipsplaat, Mass: 3.18528 kg; Gipsplaat, Component Volume (Net): 0.0039816 m3; Gipsplaat, Component Volume (Gross): 0.0039816 m3

# IfcBuildingElementProxy: Distinct Panel 432 x 561 x 20, __Panel-D
In: 00 begane grond
Material: Gipsplaat
Component Quantities - Gipsplaat, Mass: 3.79977 kg; Gipsplaat, Component Volume (Net): 0.00474971 m3; Gipsplaat, Component Volume (Gross): 0.00474971 m3

# IfcBuildingElementProxy: Distinct Panel 432 x 600 x 20 (29)
In: 00 begane grond
Material: Gipsplaat
Name
3 x __Panel-D | Component Quantities - Gipsplaat, Mass: 4.06391 kg; Gipsplaat, Component Volume (Net): 0.00507989 m3; Gipsplaat, Component Volume (Gross): 0.00507989 m3
26 x __Panel-D

# IfcBuildingElementProxy: Distinct Panel 435 x 519 x 20, __Panel-D
In: 01 eerste verdieping
Material: Gipsplaat
Component Quantities - Gipsplaat, Mass: 1.74248 kg; Gipsplaat, Component Volume (Net): 0.0021781 m3; Gipsplaat, Component Volume (Gross): 0.0021781 m3

# IfcBuildingElementProxy: Distinct Panel 437 x 592 x 20, __Panel-D
In: 00 begane grond
Material: Gipsplaat
Component Quantities - Gipsplaat, Mass: 4.05584 kg; Gipsplaat, Component Volume (Net): 0.0050698 m3; Gipsplaat, Component Volume (Gross): 0.0050698 m3

# IfcBuildingElementProxy: Distinct Panel 437 x 600 x 20 (5)
In: 00 begane grond
Material: Gipsplaat
Name
__Panel-D | Component Quantities - Gipsplaat, Mass: 4.10827 kg; Gipsplaat, Component Volume (Net): 0.00513534 m3; Gipsplaat, Component Volume (Gross): 0.00513534 m3
4 x __Panel-D

# IfcBuildingElementProxy: Distinct Panel 437 x 65 x 20, __Panel-D
In: 00 begane grond
Material: Gipsplaat
Component Quantities - Gipsplaat, Mass: 0.414705 kg; Gipsplaat, Component Volume (Net): 0.000518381 m3; Gipsplaat, Component Volume (Gross): 0.000518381 m3

# IfcBuildingElementProxy: Distinct Panel 440 x 12 x 20, __Panel-D
In: 00 begane grond
Material: Gipsplaat
Component Quantities - Gipsplaat, Mass: 0.0490079 kg; Gipsplaat, Component Volume (Net): 0.0000612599 m3; Gipsplaat, Component Volume (Gross): 0.0000612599 m3

# IfcBuildingElementProxy: Distinct Panel 440 x 488 x 20, __Panel-D
In: 00 begane grond
Material: Gipsplaat
Component Quantities - Gipsplaat, Mass: 3.35817 kg; Gipsplaat, Component Volume (Net): 0.00419771 m3; Gipsplaat, Component Volume (Gross): 0.00419771 m3

# IfcBuildingElementProxy: Distinct Panel 440 x 538 x 20, __Panel-D
In: 00 begane grond
Material: Gipsplaat
Component Quantities - Gipsplaat, Mass: 3.70597 kg; Gipsplaat, Component Volume (Net): 0.00463246 m3; Gipsplaat, Component Volume (Gross): 0.00463246 m3

# IfcBuildingElementProxy: Distinct Panel 440 x 590 x 20, __Panel-D
In: 01 eerste verdieping
Material: Gipsplaat
Component Quantities - Gipsplaat, Mass: 3.9722 kg; Gipsplaat, Component Volume (Net): 0.00496525 m3; Gipsplaat, Component Volume (Gross): 0.00496525 m3

# IfcBuildingElementProxy: Distinct Panel 440 x 600 x 20 (13)
Material: Gipsplaat
Name | In
2 x __Panel-D | 00 begane grond | Component Quantities - Gipsplaat, Mass: 4.13882 kg; Gipsplaat, Component Volume (Net): 0.00517353 m3; Gipsplaat, Component Volume (Gross): 0.00517353 m3
7 x __Panel-D | 00 begane grond
2 x __Panel-D | 01 eerste verdieping | Component Quantities - Gipsplaat, Mass: 4.14051 kg; Gipsplaat, Component Volume (Net): 0.00517564 m3; Gipsplaat, Component Volume (Gross): 0.00517564 m3
__Panel-D | 01 eerste verdieping
__Panel-D | 01 eerste verdieping | Component Quantities - Gipsplaat, Mass: 5.09069 kg; Gipsplaat, Component Volume (Net): 0.00636336 m3; Gipsplaat, Component Volume (Gross): 0.00636336 m3

# IfcBuildingElementProxy: Distinct Panel 443 x 277 x 20, __Panel-D
In: 00 begane grond
Material: Gipsplaat
Component Quantities - Gipsplaat, Mass: 3.62595 kg; Gipsplaat, Component Volume (Net): 0.00453243 m3; Gipsplaat, Component Volume (Gross): 0.00453243 m3

# IfcBuildingElementProxy: Distinct Panel 443 x 317 x 20, __Panel-D
In: 00 begane grond
Material: Gipsplaat
Component Quantities - Gipsplaat, Mass: 2.18179 kg; Gipsplaat, Component Volume (Net): 0.00272724 m3; Gipsplaat, Component Volume (Gross): 0.00272724 m3

# IfcBuildingElementProxy: Distinct Panel 443 x 342 x 20, __Panel-D
In: 00 begane grond
Material: Gipsplaat
Component Quantities - Gipsplaat, Mass: 2.35683 kg; Gipsplaat, Component Volume (Net): 0.00294604 m3; Gipsplaat, Component Volume (Gross): 0.00294604 m3

# IfcBuildingElementProxy: Distinct Panel 443 x 600 x 20 (4)
In: 00 begane grond
Material: Gipsplaat
Name
__Panel-D | Component Quantities - Gipsplaat, Mass: 4.16595 kg; Gipsplaat, Component Volume (Net): 0.00520743 m3; Gipsplaat, Component Volume (Gross): 0.00520743 m3
3 x __Panel-D

# IfcBuildingElementProxy: Distinct Panel 449 x 377 x 20, __Panel-D
In: 01 eerste verdieping
Material: Gipsplaat
Component Quantities - Gipsplaat, Mass: 1.29966 kg; Gipsplaat, Component Volume (Net): 0.00162457 m3; Gipsplaat, Component Volume (Gross): 0.00162457 m3

# IfcBuildingElementProxy: Distinct Panel 449 x 600 x 20, __Panel-D
In: 01 eerste verdieping
Material: Gipsplaat
Component Quantities - Gipsplaat, Mass: 5.51531 kg; Gipsplaat, Component Volume (Net): 0.00689413 m3; Gipsplaat, Component Volume (Gross): 0.00689413 m3

# IfcBuildingElementProxy: Distinct Panel 45 x 54 x 20, __Panel-D
In: 00 begane grond
Material: Gipsplaat
Component Quantities - Gipsplaat, Mass: 0.0134529 kg; Gipsplaat, Component Volume (Net): 0.0000168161 m3; Gipsplaat, Component Volume (Gross): 0.0000168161 m3

# IfcBuildingElementProxy: Distinct Panel 450 x 1026 x 20, __Panel-D
In: 01 eerste verdieping
Material: Gipsplaat
Component Quantities - Gipsplaat, Mass: 7.26832 kg; Gipsplaat, Component Volume (Net): 0.0090854 m3; Gipsplaat, Component Volume (Gross): 0.0090854 m3

# IfcBuildingElementProxy: Distinct Panel 450 x 212 x 20, __Panel-D
In: 00 begane grond
Material: Gipsplaat
Component Quantities - Gipsplaat, Mass: 1.47699 kg; Gipsplaat, Component Volume (Net): 0.00184624 m3; Gipsplaat, Component Volume (Gross): 0.00184624 m3

# IfcBuildingElementProxy: Distinct Panel 450 x 262 x 20, __Panel-D
In: 00 begane grond
Material: Gipsplaat
Component Quantities - Gipsplaat, Mass: 1.83303 kg; Gipsplaat, Component Volume (Net): 0.00229129 m3; Gipsplaat, Component Volume (Gross): 0.00229129 m3

# IfcBuildingElementProxy: Distinct Panel 450 x 363 x 20 (2)
In: 00 begane grond
Material: Gipsplaat
Name
__Panel-D | Component Quantities - Gipsplaat, Mass: 2.54489 kg; Gipsplaat, Component Volume (Net): 0.00318111 m3; Gipsplaat, Component Volume (Gross): 0.00318111 m3
__Panel-D

# IfcBuildingElementProxy: Distinct Panel 450 x 412 x 20, __Panel-D
In: 00 begane grond
Material: Gipsplaat
Component Quantities - Gipsplaat, Mass: 2.90017 kg; Gipsplaat, Component Volume (Net): 0.00362521 m3; Gipsplaat, Component Volume (Gross): 0.00362521 m3

# IfcBuildingElementProxy: Distinct Panel 450 x 427 x 20, __Panel-D
In: 00 begane grond
Material: Gipsplaat
Component Quantities - Gipsplaat, Mass: 3.00048 kg; Gipsplaat, Component Volume (Net): 0.0037506 m3; Gipsplaat, Component Volume (Gross): 0.0037506 m3

# IfcBuildingElementProxy: Distinct Panel 450 x 497 x 20 (2)
In: 00 begane grond
Material: Gipsplaat
Component Quantities - Gipsplaat, Mass: 3.50291 kg
Name | Gipsplaat, Component Volume (Net) (m3) = Gipsplaat, Component Volume (Gross) (m3)
__Panel-D | 0.00437863
__Panel-D | 0.00437864

# IfcBuildingElementProxy: Distinct Panel 450 x 539 x 20, __Panel-D
In: 00 begane grond
Material: Gipsplaat
Component Quantities - Gipsplaat, Mass: 3.80061 kg; Gipsplaat, Component Volume (Net): 0.00475076 m3; Gipsplaat, Component Volume (Gross): 0.00475076 m3

# IfcBuildingElementProxy: Distinct Panel 450 x 600 x 20 (15)
In: 00 begane grond
Material: Gipsplaat
Name
2 x __Panel-D | Component Quantities - Gipsplaat, Mass: 4.23555 kg; Gipsplaat, Component Volume (Net): 0.00529443 m3; Gipsplaat, Component Volume (Gross): 0.00529443 m3
9 x __Panel-D
2 x __Panel-D | Component Quantities - Gipsplaat, Mass: 4.23623 kg; Gipsplaat, Component Volume (Net): 0.00529528 m3; Gipsplaat, Component Volume (Gross): 0.00529528 m3
2 x __Panel-D | Component Quantities - Gipsplaat, Mass: 4.23622 kg; Gipsplaat, Component Volume (Net): 0.00529528 m3; Gipsplaat, Component Volume (Gross): 0.00529528 m3

# IfcBuildingElementProxy: Distinct Panel 452 x 539 x 20, __Panel-D
In: 00 begane grond
Material: Gipsplaat
Component Quantities - Gipsplaat, Mass: 1.88358 kg; Gipsplaat, Component Volume (Net): 0.00235448 m3; Gipsplaat, Component Volume (Gross): 0.00235448 m3

# IfcBuildingElementProxy: Distinct Panel 458 x 600 x 20 (11)
In: 01 eerste verdieping
Material: Gipsplaat
Name
2 x __Panel-D | Component Quantities - Gipsplaat, Mass: 4.31647 kg; Gipsplaat, Component Volume (Net): 0.00539558 m3; Gipsplaat, Component Volume (Gross): 0.00539558 m3
8 x __Panel-D
__Panel-D | Component Quantities - Gipsplaat, Mass: 3.36557 kg; Gipsplaat, Component Volume (Net): 0.00420696 m3; Gipsplaat, Component Volume (Gross): 0.00420696 m3

# IfcBuildingElementProxy: Distinct Panel 465 x 328 x 20, __Panel-D
In: 00 begane grond
Material: Gipsplaat
Component Quantities - Gipsplaat, Mass: 2.37438 kg; Gipsplaat, Component Volume (Net): 0.00296798 m3; Gipsplaat, Component Volume (Gross): 0.00296798 m3

# IfcBuildingElementProxy: Distinct Panel 465 x 437 x 20, __Panel-D
In: 00 begane grond
Material: Gipsplaat
Component Quantities - Gipsplaat, Mass: 3.18369 kg; Gipsplaat, Component Volume (Net): 0.00397962 m3; Gipsplaat, Component Volume (Gross): 0.00397962 m3

# IfcBuildingElementProxy: Distinct Panel 465 x 600 x 20 (2)
In: 00 begane grond
Material: Gipsplaat
Name
__Panel-D | Component Quantities - Gipsplaat, Mass: 4.3802 kg; Gipsplaat, Component Volume (Net): 0.00547525 m3; Gipsplaat, Component Volume (Gross): 0.00547525 m3
__Panel-D

# IfcBuildingElementProxy: Distinct Panel 468 x 111 x 20, __Panel-D
In: 01 eerste verdieping
Material: Gipsplaat
Component Quantities - Gipsplaat, Mass: 4.50204 kg; Gipsplaat, Component Volume (Net): 0.00562754 m3; Gipsplaat, Component Volume (Gross): 0.00562754 m3

# IfcBuildingElementProxy: Distinct Panel 468 x 24 x 20, __Panel-D
In: 01 eerste verdieping
Material: Gipsplaat
Component Quantities - Gipsplaat, Mass: 0.138961 kg; Gipsplaat, Component Volume (Net): 0.000173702 m3; Gipsplaat, Component Volume (Gross): 0.000173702 m3

# IfcBuildingElementProxy: Distinct Panel 470 x 154 x 20, __Panel-D
In: 00 begane grond
Material: Gipsplaat
Component Quantities - Gipsplaat, Mass: 1.10651 kg; Gipsplaat, Component Volume (Net): 0.00138314 m3; Gipsplaat, Component Volume (Gross): 0.00138314 m3

# IfcBuildingElementProxy: Distinct Panel 471 x 105 x 20, __Panel-D
In: 00 begane grond
Material: Gipsplaat
Component Quantities - Gipsplaat, Mass: 5.44781 kg; Gipsplaat, Component Volume (Net): 0.00680976 m3; Gipsplaat, Component Volume (Gross): 0.00680976 m3

# IfcBuildingElementProxy: Distinct Panel 471 x 320 x 20, __Panel-D
In: 00 begane grond
Material: Gipsplaat
Component Quantities - Gipsplaat, Mass: 2.34533 kg; Gipsplaat, Component Volume (Net): 0.00293166 m3; Gipsplaat, Component Volume (Gross): 0.00293166 m3

# IfcBuildingElementProxy: Distinct Panel 471 x 345 x 20, __Panel-D
In: 00 begane grond
Material: Gipsplaat
Component Quantities - Gipsplaat, Mass: 2.53566 kg; Gipsplaat, Component Volume (Net): 0.00316958 m3; Gipsplaat, Component Volume (Gross): 0.00316958 m3

# IfcBuildingElementProxy: Distinct Panel 473 x 600 x 20 (13)
In: 00 begane grond
Material: Gipsplaat
Name
2 x __Panel-D | Component Quantities - Gipsplaat, Mass: 4.46004 kg; Gipsplaat, Component Volume (Net): 0.00557505 m3; Gipsplaat, Component Volume (Gross): 0.00557505 m3
10 x __Panel-D
__Panel-D | Component Quantities - Gipsplaat, Mass: 5.16989 kg; Gipsplaat, Component Volume (Net): 0.00646236 m3; Gipsplaat, Component Volume (Gross): 0.00646236 m3

# IfcBuildingElementProxy: Distinct Panel 474 x 398 x 20, __Panel-D
In: 00 begane grond
Material: Gipsplaat
Component Quantities - Gipsplaat, Mass: 1.44983 kg; Gipsplaat, Component Volume (Net): 0.00181228 m3; Gipsplaat, Component Volume (Gross): 0.00181228 m3

# IfcBuildingElementProxy: Distinct Panel 474 x 600 x 20, __Panel-D
In: 00 begane grond
Material: Gipsplaat
Component Quantities - Gipsplaat, Mass: 5.56068 kg; Gipsplaat, Component Volume (Net): 0.00695084 m3; Gipsplaat, Component Volume (Gross): 0.00695084 m3

# IfcBuildingElementProxy: Distinct Panel 475 x 171 x 20, __Panel-D
In: 00 begane grond
Material: Gipsplaat
Component Quantities - Gipsplaat, Mass: 1.25036 kg; Gipsplaat, Component Volume (Net): 0.00156295 m3; Gipsplaat, Component Volume (Gross): 0.00156295 m3

# IfcBuildingElementProxy: Distinct Panel 475 x 236 x 20, __Panel-D
In: 00 begane grond
Material: Gipsplaat
Component Quantities - Gipsplaat, Mass: 4.48525 kg; Gipsplaat, Component Volume (Net): 0.00560657 m3; Gipsplaat, Component Volume (Gross): 0.00560657 m3

# IfcBuildingElementProxy: Distinct Panel 475 x 600 x 20 (6)
In: 00 begane grond
Material: Gipsplaat
Name
2 x __Panel-D | Component Quantities - Gipsplaat, Mass: 4.47313 kg; Gipsplaat, Component Volume (Net): 0.00559141 m3; Gipsplaat, Component Volume (Gross): 0.00559141 m3
4 x __Panel-D

# IfcBuildingElementProxy: Distinct Panel 478 x 592 x 20, __Panel-D
In: 00 begane grond
Material: Gipsplaat
Component Quantities - Gipsplaat, Mass: 4.4498 kg; Gipsplaat, Component Volume (Net): 0.00556225 m3; Gipsplaat, Component Volume (Gross): 0.00556225 m3

# IfcBuildingElementProxy: Distinct Panel 478 x 600 x 20 (5)
In: 00 begane grond
Material: Gipsplaat
Name
2 x __Panel-D | Component Quantities - Gipsplaat, Mass: 4.50733 kg; Gipsplaat, Component Volume (Net): 0.00563416 m3; Gipsplaat, Component Volume (Gross): 0.00563416 m3
3 x __Panel-D

# IfcBuildingElementProxy: Distinct Panel 478 x 65 x 20, __Panel-D
In: 00 begane grond
Material: Gipsplaat
Component Quantities - Gipsplaat, Mass: 0.454987 kg; Gipsplaat, Component Volume (Net): 0.000568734 m3; Gipsplaat, Component Volume (Gross): 0.000568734 m3

# IfcBuildingElementProxy: Distinct Panel 48 x 80 x 20, __Panel-D
In: 01 eerste verdieping
Material: Gipsplaat
Component Quantities - Gipsplaat, Mass: 0.0518455 kg; Gipsplaat, Component Volume (Net): 0.0000648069 m3; Gipsplaat, Component Volume (Gross): 0.0000648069 m3

# IfcBuildingElementProxy: Distinct Panel 48 x 950 x 20, __Panel-D
In: 01 eerste verdieping
Material: Gipsplaat
Component Quantities - Gipsplaat, Mass: 0.650892 kg; Gipsplaat, Component Volume (Net): 0.000813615 m3; Gipsplaat, Component Volume (Gross): 0.000813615 m3

# IfcBuildingElementProxy: Distinct Panel 480 x 544 x 20, __Panel-D
In: 01 eerste verdieping
Material: Gipsplaat
Component Quantities - Gipsplaat, Mass: 4.09641 kg; Gipsplaat, Component Volume (Net): 0.00512052 m3; Gipsplaat, Component Volume (Gross): 0.00512052 m3

# IfcBuildingElementProxy: Distinct Panel 480 x 600 x 20 (10)
In: 01 eerste verdieping
Material: Gipsplaat
Name
2 x __Panel-D | Component Quantities - Gipsplaat, Mass: 4.52427 kg; Gipsplaat, Component Volume (Net): 0.00565534 m3; Gipsplaat, Component Volume (Gross): 0.00565534 m3
8 x __Panel-D

# IfcBuildingElementProxy: Distinct Panel 482 x 361 x 20 (4)
In: 00 begane grond
Material: Gipsplaat
Component Quantities - Gipsplaat, Mass: 2.7169 kg; Gipsplaat, Component Volume (Net): 0.00339612 m3; Gipsplaat, Component Volume (Gross): 0.00339612 m3

# IfcBuildingElementProxy: Distinct Panel 482 x 600 x 20 (14)
In: 00 begane grond
Material: Gipsplaat
Name
5 x __Panel-D | Component Quantities - Gipsplaat, Mass: 4.5451 kg; Gipsplaat, Component Volume (Net): 0.00568137 m3; Gipsplaat, Component Volume (Gross): 0.00568137 m3
9 x __Panel-D

# IfcBuildingElementProxy: Distinct Panel 487 x 176 x 20, __Panel-D
In: 01 eerste verdieping
Material: Gipsplaat
Component Quantities - Gipsplaat, Mass: 1.32279 kg; Gipsplaat, Component Volume (Net): 0.00165349 m3; Gipsplaat, Component Volume (Gross): 0.00165349 m3

# IfcBuildingElementProxy: Distinct Panel 487 x 395 x 20, __Panel-D
In: 01 eerste verdieping
Material: Gipsplaat
Component Quantities - Gipsplaat, Mass: 3.00925 kg; Gipsplaat, Component Volume (Net): 0.00376156 m3; Gipsplaat, Component Volume (Gross): 0.00376156 m3

# IfcBuildingElementProxy: Distinct Panel 487 x 55 x 20, __Panel-D
In: 01 eerste verdieping
Material: Gipsplaat
Component Quantities - Gipsplaat, Mass: 0.385975 kg; Gipsplaat, Component Volume (Net): 0.000482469 m3; Gipsplaat, Component Volume (Gross): 0.000482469 m3

# IfcBuildingElementProxy: Distinct Panel 487 x 566 x 20, __Panel-D
In: 00 begane grond
Material: Gipsplaat
Component Quantities - Gipsplaat, Mass: 3.88533 kg; Gipsplaat, Component Volume (Net): 0.00485666 m3; Gipsplaat, Component Volume (Gross): 0.00485666 m3

# IfcBuildingElementProxy: Distinct Panel 487 x 600 x 20 (16)
Material: Gipsplaat
Name | In
2 x __Panel-D | 00 begane grond | Component Quantities - Gipsplaat, Mass: 4.58822 kg; Gipsplaat, Component Volume (Net): 0.00573528 m3; Gipsplaat, Component Volume (Gross): 0.00573528 m3
3 x __Panel-D | 00 begane grond
__Panel-D | 01 eerste verdieping | Component Quantities - Gipsplaat, Mass: 4.59127 kg; Gipsplaat, Component Volume (Net): 0.00573909 m3; Gipsplaat, Component Volume (Gross): 0.00573909 m3
10 x __Panel-D | 01 eerste verdieping

# IfcBuildingElementProxy: Distinct Panel 487 x 94 x 20, __Panel-D
In: 01 eerste verdieping
Material: Gipsplaat
Component Quantities - Gipsplaat, Mass: 0.689778 kg; Gipsplaat, Component Volume (Net): 0.000862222 m3; Gipsplaat, Component Volume (Gross): 0.000862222 m3

# IfcBuildingElementProxy: Distinct Panel 488 x 317 x 20, __Panel-D
In: 00 begane grond
Material: Gipsplaat
Component Quantities - Gipsplaat, Mass: 2.41015 kg; Gipsplaat, Component Volume (Net): 0.00301269 m3; Gipsplaat, Component Volume (Gross): 0.00301269 m3

# IfcBuildingElementProxy: Distinct Panel 488 x 50 x 20, __Panel-D
In: 00 begane grond
Material: Gipsplaat
Component Quantities - Gipsplaat, Mass: 0.347892 kg; Gipsplaat, Component Volume (Net): 0.000434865 m3; Gipsplaat, Component Volume (Gross): 0.000434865 m3

# IfcBuildingElementProxy: Distinct Panel 488 x 550 x 20, __Panel-D
In: 00 begane grond
Material: Gipsplaat
Component Quantities - Gipsplaat, Mass: 4.49427 kg; Gipsplaat, Component Volume (Net): 0.00561783 m3; Gipsplaat, Component Volume (Gross): 0.00561783 m3

# IfcBuildingElementProxy: Distinct Panel 488 x 600 x 20 (4)
In: 00 begane grond
Material: Gipsplaat
Name | Gipsplaat, Mass (kg) | Gipsplaat, Component Volume (Net) (m3) = Gipsplaat, Component Volume (Gross) (m3)
3 x __Panel-D | 4.60198 | 0.00575247
__Panel-D

# IfcBuildingElementProxy: Distinct Panel 490 x 163 x 20, __Panel-D
In: 01 eerste verdieping
Material: Gipsplaat
Component Quantities - Gipsplaat, Mass: 1.22958 kg; Gipsplaat, Component Volume (Net): 0.00153697 m3; Gipsplaat, Component Volume (Gross): 0.00153697 m3

# IfcBuildingElementProxy: Distinct Panel 490 x 328 x 20, __Panel-D
In: 00 begane grond
Material: Gipsplaat
Component Quantities - Gipsplaat, Mass: 2.5041 kg; Gipsplaat, Component Volume (Net): 0.00313012 m3; Gipsplaat, Component Volume (Gross): 0.00313012 m3

# IfcBuildingElementProxy: Distinct Panel 490 x 437 x 20, __Panel-D
In: 00 begane grond
Material: Gipsplaat
Component Quantities - Gipsplaat, Mass: 3.25725 kg; Gipsplaat, Component Volume (Net): 0.00407157 m3; Gipsplaat, Component Volume (Gross): 0.00407157 m3

# IfcBuildingElementProxy: Distinct Panel 490 x 478 x 20, __Panel-D
In: 01 eerste verdieping
Material: Gipsplaat
Component Quantities - Gipsplaat, Mass: 3.67383 kg; Gipsplaat, Component Volume (Net): 0.00459228 m3; Gipsplaat, Component Volume (Gross): 0.00459228 m3

# IfcBuildingElementProxy: Distinct Panel 490 x 571 x 20, __Panel-D
In: 01 eerste verdieping
Material: Gipsplaat
Component Quantities - Gipsplaat, Mass: 4.39143 kg; Gipsplaat, Component Volume (Net): 0.00548928 m3; Gipsplaat, Component Volume (Gross): 0.00548928 m3

# IfcBuildingElementProxy: Distinct Panel 490 x 600 x 20 (7)
Material: Gipsplaat
Name | In | Gipsplaat, Mass (kg) | Gipsplaat, Component Volume (Net) (m3) = Gipsplaat, Component Volume (Gross) (m3)
__Panel-D | 00 begane grond | 4.6195 | 0.00577438
__Panel-D | 00 begane grond
__Panel-D | 01 eerste verdieping | 4.89572 | 0.00611965
3 x __Panel-D | 01 eerste verdieping | 4.61668 | 0.00577085
__Panel-D | 01 eerste verdieping

# IfcBuildingElementProxy: Distinct Panel 500 x 332 x 20, __Panel-D
In: 00 begane grond
Material: Gipsplaat
Component Quantities - Gipsplaat, Mass: 2.59308 kg; Gipsplaat, Component Volume (Net): 0.00324134 m3; Gipsplaat, Component Volume (Gross): 0.00324134 m3

# IfcBuildingElementProxy: Distinct Panel 500 x 333 x 20, __Panel-D
In: 00 begane grond
Material: Gipsplaat
Component Quantities - Gipsplaat, Mass: 2.59451 kg; Gipsplaat, Component Volume (Net): 0.00324314 m3; Gipsplaat, Component Volume (Gross): 0.00324314 m3

# IfcBuildingElementProxy: Distinct Panel 500 x 480 x 20, __Panel-D
In: 01 eerste verdieping
Material: Gipsplaat
Component Quantities - Gipsplaat, Mass: 3.76134 kg; Gipsplaat, Component Volume (Net): 0.00470168 m3; Gipsplaat, Component Volume (Gross): 0.00470168 m3

# IfcBuildingElementProxy: Distinct Panel 500 x 524 x 20, __Panel-D
In: 01 eerste verdieping
Material: Gipsplaat
Component Quantities - Gipsplaat, Mass: 4.1132 kg; Gipsplaat, Component Volume (Net): 0.0051415 m3; Gipsplaat, Component Volume (Gross): 0.0051415 m3

# IfcBuildingElementProxy: Distinct Panel 500 x 600 x 20 (20)
Material: Gipsplaat
Name | In
__Panel-D | 00 begane grond | Component Quantities - Gipsplaat, Mass: 4.71238 kg; Gipsplaat, Component Volume (Net): 0.00589048 m3; Gipsplaat, Component Volume (Gross): 0.00589048 m3
11 x __Panel-D | 00 begane grond
3 x __Panel-D | 01 eerste verdieping | Component Quantities - Gipsplaat, Mass: 4.71207 kg; Gipsplaat, Component Volume (Net): 0.00589009 m3; Gipsplaat, Component Volume (Gross): 0.00589009 m3
5 x __Panel-D | 01 eerste verdieping

# IfcBuildingElementProxy: Distinct Panel 502 x 546 x 20, __Panel-D
In: 01 eerste verdieping
Material: Gipsplaat
Component Quantities - Gipsplaat, Mass: 4.30257 kg; Gipsplaat, Component Volume (Net): 0.00537821 m3; Gipsplaat, Component Volume (Gross): 0.00537821 m3

# IfcBuildingElementProxy: Distinct Panel 502 x 600 x 20 (25)
In: 01 eerste verdieping
Material: Gipsplaat
Name | Gipsplaat, Mass (kg) | Gipsplaat, Component Volume (Net) (m3) = Gipsplaat, Component Volume (Gross) (m3)
__Panel-D | 4.73527 | 0.00591909
__Panel-D | 4.73602 | 0.00592002
__Panel-D | 4.73274 | 0.00591592
__Panel-D | 4.73542 | 0.00591928
__Panel-D | 4.73512 | 0.00591891
__Panel-D | 4.73363 | 0.00591704
__Panel-D | 4.73468 | 0.00591835
__Panel-D | 4.73482 | 0.00591853
__Panel-D | 4.73259 | 0.00591573
__Panel-D | 4.73244 | 0.00591555
__Panel-D | 4.73557 | 0.00591946
__Panel-D | 4.73318 | 0.00591648
__Panel-D | 4.73438 | 0.00591797
__Panel-D | 4.73333 | 0.00591667
__Panel-D | 4.73393 | 0.00591741
__Panel-D | 4.73348 | 0.00591685
__Panel-D | 4.73408 | 0.0059176
__Panel-D | 4.73497 | 0.00591872
__Panel-D | 4.73289 | 0.00591611
__Panel-D | 4.73423 | 0.00591779
__Panel-D | 4.73572 | 0.00591965
__Panel-D | 4.73453 | 0.00591816
__Panel-D | 4.73378 | 0.00591723
__Panel-D | 4.73304 | 0.00591629
__Panel-D | 4.73587 | 0.00591984

# IfcBuildingElementProxy: Distinct Panel 503 x 571 x 20, __Panel-D
In: 01 eerste verdieping
Material: Gipsplaat
Component Quantities - Gipsplaat, Mass: 4.50564 kg; Gipsplaat, Component Volume (Net): 0.00563206 m3; Gipsplaat, Component Volume (Gross): 0.00563206 m3

# IfcBuildingElementProxy: Distinct Panel 503 x 600 x 20 (4)
In: 01 eerste verdieping
Material: Gipsplaat
Name | Gipsplaat, Mass (kg) | Gipsplaat, Component Volume (Net) (m3) = Gipsplaat, Component Volume (Gross) (m3)
__Panel-D | 4.73632 | 0.0059204
__Panel-D | 4.73662 | 0.00592077
__Panel-D | 4.73647 | 0.00592058
__Panel-D | 4.73617 | 0.00592021

# IfcBuildingElementProxy: Distinct Panel 507 x 1200 x 20, __Panel-D
In: 01 eerste verdieping
Material: Gipsplaat
Component Quantities - Gipsplaat, Mass: 9.60419 kg; Gipsplaat, Component Volume (Net): 0.0120052 m3; Gipsplaat, Component Volume (Gross): 0.0120052 m3

# IfcBuildingElementProxy: Distinct Panel 507 x 947 x 20, __Panel-D
In: 01 eerste verdieping
Material: Gipsplaat
Component Quantities - Gipsplaat, Mass: 7.57352 kg; Gipsplaat, Component Volume (Net): 0.0094669 m3; Gipsplaat, Component Volume (Gross): 0.0094669 m3

# IfcBuildingElementProxy: Distinct Panel 507 x 950 x 20, __Panel-D
In: 01 eerste verdieping
Material: Gipsplaat
Component Quantities - Gipsplaat, Mass: 7.59361 kg; Gipsplaat, Component Volume (Net): 0.00949201 m3; Gipsplaat, Component Volume (Gross): 0.00949201 m3

# IfcBuildingElementProxy: Distinct Panel 513 x 600 x 20 (6)
In: 00 begane grond
Material: Gipsplaat
Name
3 x __Panel-D | Component Quantities - Gipsplaat, Mass: 4.83287 kg; Gipsplaat, Component Volume (Net): 0.00604109 m3; Gipsplaat, Component Volume (Gross): 0.00604109 m3
3 x __Panel-D

# IfcBuildingElementProxy: Distinct Panel 518 x 212 x 20, __Panel-D
In: 00 begane grond
Material: Gipsplaat
Component Quantities - Gipsplaat, Mass: 1.70141 kg; Gipsplaat, Component Volume (Net): 0.00212676 m3; Gipsplaat, Component Volume (Gross): 0.00212676 m3

# IfcBuildingElementProxy: Distinct Panel 518 x 230 x 20, __Panel-D
In: 00 begane grond
Material: Gipsplaat
Component Quantities - Gipsplaat, Mass: 4.43909 kg; Gipsplaat, Component Volume (Net): 0.00554887 m3; Gipsplaat, Component Volume (Gross): 0.00554887 m3

# IfcBuildingElementProxy: Distinct Panel 518 x 262 x 20, __Panel-D
In: 00 begane grond
Material: Gipsplaat
Component Quantities - Gipsplaat, Mass: 2.11154 kg; Gipsplaat, Component Volume (Net): 0.00263942 m3; Gipsplaat, Component Volume (Gross): 0.00263942 m3

# IfcBuildingElementProxy: Distinct Panel 518 x 363 x 20 (2)
In: 00 begane grond
Material: Gipsplaat
Name
__Panel-D | Component Quantities - Gipsplaat, Mass: 2.93156 kg; Gipsplaat, Component Volume (Net): 0.00366445 m3; Gipsplaat, Component Volume (Gross): 0.00366445 m3
__Panel-D

# IfcBuildingElementProxy: Distinct Panel 518 x 412 x 20, __Panel-D
In: 00 begane grond
Material: Gipsplaat
Component Quantities - Gipsplaat, Mass: 3.34082 kg; Gipsplaat, Component Volume (Net): 0.00417602 m3; Gipsplaat, Component Volume (Gross): 0.00417602 m3

# IfcBuildingElementProxy: Distinct Panel 518 x 600 x 20 (7)
In: 00 begane grond
Material: Gipsplaat
Name
__Panel-D | Component Quantities - Gipsplaat, Mass: 4.87909 kg; Gipsplaat, Component Volume (Net): 0.00609886 m3; Gipsplaat, Component Volume (Gross): 0.00609886 m3
6 x __Panel-D

# IfcBuildingElementProxy: Distinct Panel 52 x 327 x 20, __Panel-D
In: 00 begane grond
Material: Gipsplaat
Component Quantities - Gipsplaat, Mass: 0.244875 kg; Gipsplaat, Component Volume (Net): 0.000306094 m3; Gipsplaat, Component Volume (Gross): 0.000306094 m3

# IfcBuildingElementProxy: Distinct Panel 52 x 544 x 20, __Panel-D
In: 00 begane grond
Material: Gipsplaat
Component Quantities - Gipsplaat, Mass: 0.409159 kg; Gipsplaat, Component Volume (Net): 0.000511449 m3; Gipsplaat, Component Volume (Gross): 0.000511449 m3

# IfcBuildingElementProxy: Distinct Panel 52 x 600 x 20 (5)
In: 00 begane grond
Material: Gipsplaat
Name
2 x __Panel-D | Component Quantities - Gipsplaat, Mass: 0.452039 kg; Gipsplaat, Component Volume (Net): 0.000565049 m3; Gipsplaat, Component Volume (Gross): 0.000565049 m3
3 x __Panel-D

# IfcBuildingElementProxy: Distinct Panel 521 x 437 x 20, __Panel-D
In: 01 eerste verdieping
Material: Gipsplaat
Component Quantities - Gipsplaat, Mass: 1.75757 kg; Gipsplaat, Component Volume (Net): 0.00219696 m3; Gipsplaat, Component Volume (Gross): 0.00219696 m3

# IfcBuildingElementProxy: Distinct Panel 540 x 453 x 20, __Panel-D
In: 01 eerste verdieping
Material: Gipsplaat
Component Quantities - Gipsplaat, Mass: 1.88791 kg; Gipsplaat, Component Volume (Net): 0.00235989 m3; Gipsplaat, Component Volume (Gross): 0.00235989 m3

# IfcBuildingElementProxy: Distinct Panel 540 x 600 x 20, __Panel-D
In: 01 eerste verdieping
Material: Gipsplaat
Component Quantities - Gipsplaat, Mass: 5.64125 kg; Gipsplaat, Component Volume (Net): 0.00705157 m3; Gipsplaat, Component Volume (Gross): 0.00705157 m3

# IfcBuildingElementProxy: Distinct Panel 543 x 1198 x 20, __Panel-D
In: 00 begane grond
Material: Gipsplaat
Component Quantities - Gipsplaat, Mass: 10.28 kg; Gipsplaat, Component Volume (Net): 0.01285 m3; Gipsplaat, Component Volume (Gross): 0.01285 m3

# IfcBuildingElementProxy: Distinct Panel 543 x 375 x 20, __Panel-D
In: 00 begane grond
Material: Gipsplaat
Component Quantities - Gipsplaat, Mass: 3.18446 kg; Gipsplaat, Component Volume (Net): 0.00398058 m3; Gipsplaat, Component Volume (Gross): 0.00398058 m3

# IfcBuildingElementProxy: Distinct Panel 543 x 425 x 20, __Panel-D
In: 00 begane grond
Material: Gipsplaat
Component Quantities - Gipsplaat, Mass: 3.61485 kg; Gipsplaat, Component Volume (Net): 0.00451857 m3; Gipsplaat, Component Volume (Gross): 0.00451857 m3

# IfcBuildingElementProxy: Distinct Panel 543 x 600 x 20 (3)
In: 00 begane grond
Material: Gipsplaat
Name
__Panel-D | Component Quantities - Gipsplaat, Mass: 5.12163 kg; Gipsplaat, Component Volume (Net): 0.00640204 m3; Gipsplaat, Component Volume (Gross): 0.00640204 m3
2 x __Panel-D

# IfcBuildingElementProxy: Distinct Panel 549 x 600 x 20, __Panel-D
In: 00 begane grond
Material: Gipsplaat
Component Quantities - Gipsplaat, Mass: 2.77404 kg; Gipsplaat, Component Volume (Net): 0.00346755 m3; Gipsplaat, Component Volume (Gross): 0.00346755 m3

# IfcBuildingElementProxy: Distinct Panel 553 x 592 x 20, __Panel-D
In: 00 begane grond
Material: Gipsplaat
Component Quantities - Gipsplaat, Mass: 5.15046 kg; Gipsplaat, Component Volume (Net): 0.00643807 m3; Gipsplaat, Component Volume (Gross): 0.00643807 m3

# IfcBuildingElementProxy: Distinct Panel 553 x 600 x 20 (22)
In: 00 begane grond
Material: Gipsplaat
Name
__Panel-D | Component Quantities - Gipsplaat, Mass: 4.9509 kg; Gipsplaat, Component Volume (Net): 0.00618863 m3; Gipsplaat, Component Volume (Gross): 0.00618863 m3
2 x __Panel-D | Component Quantities - Gipsplaat, Mass: 5.21704 kg; Gipsplaat, Component Volume (Net): 0.0065213 m3; Gipsplaat, Component Volume (Gross): 0.0065213 m3
19 x __Panel-D

# IfcBuildingElementProxy: Distinct Panel 557 x 1200 x 20, __Panel-D
In: 00 begane grond
Material: Gipsplaat
Component Quantities - Gipsplaat, Mass: 10.5532 kg; Gipsplaat, Component Volume (Net): 0.0131915 m3; Gipsplaat, Component Volume (Gross): 0.0131915 m3

# IfcBuildingElementProxy: Distinct Panel 557 x 375 x 20, __Panel-D
In: 00 begane grond
Material: Gipsplaat
Component Quantities - Gipsplaat, Mass: 3.26733 kg; Gipsplaat, Component Volume (Net): 0.00408416 m3; Gipsplaat, Component Volume (Gross): 0.00408416 m3

# IfcBuildingElementProxy: Distinct Panel 557 x 425 x 20, __Panel-D
In: 00 begane grond
Material: Gipsplaat
Component Quantities - Gipsplaat, Mass: 3.70892 kg; Gipsplaat, Component Volume (Net): 0.00463615 m3; Gipsplaat, Component Volume (Gross): 0.00463615 m3

# IfcBuildingElementProxy: Distinct Panel 557 x 600 x 20 (3)
In: 00 begane grond
Material: Gipsplaat
Name | Gipsplaat, Mass (kg) | Gipsplaat, Component Volume (Net) (m3) = Gipsplaat, Component Volume (Gross) (m3)
2 x __Panel-D | 5.2549 | 0.00656863
__Panel-D

# IfcBuildingElementProxy: Distinct Panel 560 x 494 x 20 (2)
In: 00 begane grond
Material: Gipsplaat
Name | Gipsplaat, Mass (kg) | Gipsplaat, Component Volume (Net) (m3) = Gipsplaat, Component Volume (Gross) (m3)
__Panel-D | 4.34248 | 0.00542811
__Panel-D | 2.24658 | 0.00280823

# IfcBuildingElementProxy: Distinct Panel 560 x 600 x 20 (9)
In: 00 begane grond
Material: Gipsplaat
Name | Gipsplaat, Mass (kg) | Gipsplaat, Component Volume (Net) (m3) = Gipsplaat, Component Volume (Gross) (m3)
__Panel-D | 5.28718 | 0.00660898
__Panel-D | 5.28717 | 0.00660896
__Panel-D | 5.28715 | 0.00660894
__Panel-D | 5.28719 | 0.00660899
3 x __Panel-D
__Panel-D | 5.28716 | 0.00660895
__Panel-D | 5.2872 | 0.006609

# IfcBuildingElementProxy: Distinct Panel 562 x 1084 x 20, __Panel-D
In: 00 begane grond
Material: Gipsplaat
Component Quantities - Gipsplaat, Mass: 9.62348 kg; Gipsplaat, Component Volume (Net): 0.0120294 m3; Gipsplaat, Component Volume (Gross): 0.0120294 m3

# IfcBuildingElementProxy: Distinct Panel 562 x 221 x 20, __Panel-D
In: 00 begane grond
Material: Gipsplaat
Component Quantities - Gipsplaat, Mass: 1.92614 kg; Gipsplaat, Component Volume (Net): 0.00240767 m3; Gipsplaat, Component Volume (Gross): 0.00240767 m3

# IfcBuildingElementProxy: Distinct Panel 562 x 600 x 20 (7)
In: 00 begane grond
Material: Gipsplaat
Name
2 x __Panel-D | Component Quantities - Gipsplaat, Mass: 5.29797 kg; Gipsplaat, Component Volume (Net): 0.00662246 m3; Gipsplaat, Component Volume (Gross): 0.00662246 m3
5 x __Panel-D

# IfcBuildingElementProxy: Distinct Panel 563 x 1084 x 20, __Panel-D
In: 00 begane grond
Material: Gipsplaat
Component Quantities - Gipsplaat, Mass: 9.62468 kg; Gipsplaat, Component Volume (Net): 0.0120309 m3; Gipsplaat, Component Volume (Gross): 0.0120309 m3

# IfcBuildingElementProxy: Distinct Panel 563 x 499 x 20, __Panel-D
In: 00 begane grond
Material: Gipsplaat
Component Quantities - Gipsplaat, Mass: 4.40756 kg; Gipsplaat, Component Volume (Net): 0.00550945 m3; Gipsplaat, Component Volume (Gross): 0.00550945 m3

# IfcBuildingElementProxy: Distinct Panel 563 x 549 x 20, __Panel-D
In: 00 begane grond
Material: Gipsplaat
Component Quantities - Gipsplaat, Mass: 4.85368 kg; Gipsplaat, Component Volume (Net): 0.0060671 m3; Gipsplaat, Component Volume (Gross): 0.0060671 m3

# IfcBuildingElementProxy: Distinct Panel 563 x 600 x 20 (9)
In: 00 begane grond
Material: Gipsplaat
Name
__Panel-D | Component Quantities - Gipsplaat, Mass: 5.30887 kg; Gipsplaat, Component Volume (Net): 0.00663609 m3; Gipsplaat, Component Volume (Gross): 0.00663609 m3
8 x __Panel-D

# IfcBuildingElementProxy: Distinct Panel 564 x 474 x 20, __Panel-D
In: 01 eerste verdieping
Material: Gipsplaat
Component Quantities - Gipsplaat, Mass: 2.06817 kg; Gipsplaat, Component Volume (Net): 0.00258521 m3; Gipsplaat, Component Volume (Gross): 0.00258521 m3

# IfcBuildingElementProxy: Distinct Panel 564 x 600 x 20, __Panel-D
In: 01 eerste verdieping
Material: Gipsplaat
Component Quantities - Gipsplaat, Mass: 5.65665 kg; Gipsplaat, Component Volume (Net): 0.00707081 m3; Gipsplaat, Component Volume (Gross): 0.00707081 m3

# IfcBuildingElementProxy: Distinct Panel 575 x 12 x 20, __Panel-D
In: 00 begane grond
Material: Gipsplaat
Component Quantities - Gipsplaat, Mass: 0.0642824 kg; Gipsplaat, Component Volume (Net): 0.000080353 m3; Gipsplaat, Component Volume (Gross): 0.000080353 m3

# IfcBuildingElementProxy: Distinct Panel 575 x 457 x 20, __Panel-D
In: 00 begane grond
Material: Gipsplaat
Component Quantities - Gipsplaat, Mass: 4.26277 kg; Gipsplaat, Component Volume (Net): 0.00532846 m3; Gipsplaat, Component Volume (Gross): 0.00532846 m3

# IfcBuildingElementProxy: Distinct Panel 575 x 538 x 20, __Panel-D
In: 00 begane grond
Material: Gipsplaat
Component Quantities - Gipsplaat, Mass: 4.86101 kg; Gipsplaat, Component Volume (Net): 0.00607626 m3; Gipsplaat, Component Volume (Gross): 0.00607626 m3

# IfcBuildingElementProxy: Distinct Panel 575 x 600 x 20 (9)
In: 00 begane grond
Material: Gipsplaat
Name
2 x __Panel-D | Component Quantities - Gipsplaat, Mass: 5.42878 kg; Gipsplaat, Component Volume (Net): 0.00678597 m3; Gipsplaat, Component Volume (Gross): 0.00678597 m3
7 x __Panel-D

# IfcBuildingElementProxy: Distinct Panel 578 x 23 x 20, __Panel-D
In: 01 eerste verdieping
Material: Gipsplaat
Component Quantities - Gipsplaat, Mass: 2.305 kg; Gipsplaat, Component Volume (Net): 0.00288125 m3; Gipsplaat, Component Volume (Gross): 0.00288125 m3

# IfcBuildingElementProxy: Distinct Panel 580 x 101 x 20, __Panel-D
In: 00 begane grond
Material: Gipsplaat
Component Quantities - Gipsplaat, Mass: 0.883238 kg; Gipsplaat, Component Volume (Net): 0.00110405 m3; Gipsplaat, Component Volume (Gross): 0.00110405 m3

# IfcBuildingElementProxy: Distinct Panel 580 x 399 x 20, __Panel-D
In: 00 begane grond
Material: Gipsplaat
Component Quantities - Gipsplaat, Mass: 3.18535 kg; Gipsplaat, Component Volume (Net): 0.00398168 m3; Gipsplaat, Component Volume (Gross): 0.00398168 m3

# IfcBuildingElementProxy: Distinct Panel 580 x 499 x 20, __Panel-D
In: 00 begane grond
Material: Gipsplaat
Component Quantities - Gipsplaat, Mass: 4.54524 kg; Gipsplaat, Component Volume (Net): 0.00568155 m3; Gipsplaat, Component Volume (Gross): 0.00568155 m3

# IfcBuildingElementProxy: Distinct Panel 580 x 600 x 20 (8)
In: 00 begane grond
Material: Gipsplaat
Name
3 x __Panel-D | Component Quantities - Gipsplaat, Mass: 5.47471 kg; Gipsplaat, Component Volume (Net): 0.00684339 m3; Gipsplaat, Component Volume (Gross): 0.00684339 m3
4 x __Panel-D
__Panel-D | Component Quantities - Gipsplaat, Mass: 5.31402 kg; Gipsplaat, Component Volume (Net): 0.00664253 m3; Gipsplaat, Component Volume (Gross): 0.00664253 m3

# IfcBuildingElementProxy: Distinct Panel 583 x 116 x 20, __Panel-D
In: 00 begane grond
Material: Gipsplaat
Component Quantities - Gipsplaat, Mass: 1.74174 kg; Gipsplaat, Component Volume (Net): 0.00217717 m3; Gipsplaat, Component Volume (Gross): 0.00217717 m3

# IfcBuildingElementProxy: Distinct Panel 583 x 284 x 20, __Panel-D
In: 00 begane grond
Material: Gipsplaat
Component Quantities - Gipsplaat, Mass: 5.45487 kg; Gipsplaat, Component Volume (Net): 0.00681859 m3; Gipsplaat, Component Volume (Gross): 0.00681859 m3

# IfcBuildingElementProxy: Distinct Panel 583 x 600 x 20 (5)
In: 00 begane grond
Material: Gipsplaat
Name | Gipsplaat, Mass (kg) | Gipsplaat, Component Volume (Net) (m3) = Gipsplaat, Component Volume (Gross) (m3)
3 x __Panel-D | 5.50723 | 0.00688404
2 x __Panel-D

# IfcBuildingElementProxy: Distinct Panel 585 x 468 x 20 (4)
In: 01 eerste verdieping
Material: Gipsplaat
Name | Gipsplaat, Mass (kg) | Gipsplaat, Component Volume (Net) (m3) = Gipsplaat, Component Volume (Gross) (m3)
__Panel-D | 4.29708 | 0.00537135
__Panel-D | 3.53093 | 0.00441366
2 x __Panel-D | 4.30006 | 0.00537508

# IfcBuildingElementProxy: Distinct Panel 585 x 596 x 20 (4)
In: 01 eerste verdieping
Material: Gipsplaat
Name | Gipsplaat, Mass (kg) | Gipsplaat, Component Volume (Net) (m3) = Gipsplaat, Component Volume (Gross) (m3)
2 x __Panel-D | 5.48468 | 0.00685585
2 x __Panel-D | 5.48885 | 0.00686106

# IfcBuildingElementProxy: Distinct Panel 585 x 600 x 20 (20)
In: 01 eerste verdieping
Material: Gipsplaat
Name
3 x __Panel-D | Component Quantities - Gipsplaat, Mass: 5.52196 kg; Gipsplaat, Component Volume (Net): 0.00690245 m3; Gipsplaat, Component Volume (Gross): 0.00690245 m3
14 x __Panel-D
3 x __Panel-D | Component Quantities - Gipsplaat, Mass: 5.526 kg; Gipsplaat, Component Volume (Net): 0.0069075 m3; Gipsplaat, Component Volume (Gross): 0.0069075 m3

# IfcBuildingElementProxy: Distinct Panel 586 x 1047 x 20, __Panel-D
In: 01 eerste verdieping
Material: Gipsplaat
Component Quantities - Gipsplaat, Mass: 9.69012 kg; Gipsplaat, Component Volume (Net): 0.0121126 m3; Gipsplaat, Component Volume (Gross): 0.0121126 m3

# IfcBuildingElementProxy: Distinct Panel 592 x 1200 x 20, __Panel-D
In: 01 eerste verdieping
Material: Gipsplaat
Component Quantities - Gipsplaat, Mass: 11.2234 kg; Gipsplaat, Component Volume (Net): 0.0140293 m3; Gipsplaat, Component Volume (Gross): 0.0140293 m3

# IfcBuildingElementProxy: Distinct Panel 592 x 180 x 20, __Panel-D
In: 01 eerste verdieping
Material: Gipsplaat
Component Quantities - Gipsplaat, Mass: 7.70273 kg; Gipsplaat, Component Volume (Net): 0.00962841 m3; Gipsplaat, Component Volume (Gross): 0.00962841 m3

# IfcBuildingElementProxy: Distinct Panel 600 x 1002 x 20 (3)
In: 01 eerste verdieping
Material: Gipsplaat
Name | Gipsplaat, Mass (kg) | Gipsplaat, Component Volume (Net) (m3) = Gipsplaat, Component Volume (Gross) (m3)
2 x __Panel-D | 9.49145 | 0.0118643
__Panel-D

# IfcBuildingElementProxy: Distinct Panel 600 x 101 x 20, __Panel-D
In: 00 begane grond
Material: Gipsplaat
Component Quantities - Gipsplaat, Mass: 0.91384 kg; Gipsplaat, Component Volume (Net): 0.0011423 m3; Gipsplaat, Component Volume (Gross): 0.0011423 m3

# IfcBuildingElementProxy: Distinct Panel 600 x 1012 x 20 (3)
In: 00 begane grond
Material: Gipsplaat
Name | Gipsplaat, Mass (kg) | Gipsplaat, Component Volume (Net) (m3) = Gipsplaat, Component Volume (Gross) (m3)
__Panel-D | 9.58624 | 0.0119828
__Panel-D | 9.58193 | 0.0119774
__Panel-D

# IfcBuildingElementProxy: Distinct Panel 600 x 1018 x 20 (4)
In: 00 begane grond
Material: Gipsplaat
Name | Gipsplaat, Mass (kg) | Gipsplaat, Component Volume (Net) (m3) = Gipsplaat, Component Volume (Gross) (m3)
3 x __Panel-D | 9.639 | 0.0120488
__Panel-D

# IfcBuildingElementProxy: Distinct Panel 600 x 1026 x 20 (4)
In: 01 eerste verdieping
Material: Gipsplaat
Name
2 x __Panel-D | Component Quantities - Gipsplaat, Mass: 9.71831 kg; Gipsplaat, Component Volume (Net): 0.0121479 m3; Gipsplaat, Component Volume (Gross): 0.0121479 m3
2 x __Panel-D

# IfcBuildingElementProxy: Distinct Panel 600 x 1042 x 20 (4)
In: 00 begane grond
Material: Gipsplaat
Name
__Panel-D | Component Quantities - Gipsplaat, Mass: 9.86943 kg; Gipsplaat, Component Volume (Net): 0.0123368 m3; Gipsplaat, Component Volume (Gross): 0.0123368 m3
3 x __Panel-D

# IfcBuildingElementProxy: Distinct Panel 600 x 1047 x 20 (4)
In: 01 eerste verdieping
Material: Gipsplaat
Name | Gipsplaat, Mass (kg) | Gipsplaat, Component Volume (Net) (m3) = Gipsplaat, Component Volume (Gross) (m3)
3 x __Panel-D | 9.91508 | 0.0123939
__Panel-D

# IfcBuildingElementProxy: Distinct Panel 600 x 1084 x 20, __Panel-D
In: 00 begane grond
Material: Gipsplaat
Component Quantities - Gipsplaat, Mass: 10.2721 kg; Gipsplaat, Component Volume (Net): 0.0128401 m3; Gipsplaat, Component Volume (Gross): 0.0128401 m3

# IfcBuildingElementProxy: Distinct Panel 600 x 1130 x 20, __Panel-D
In: 01 eerste verdieping
Material: Gipsplaat
Component Quantities - Gipsplaat, Mass: 10.7088 kg; Gipsplaat, Component Volume (Net): 0.013386 m3; Gipsplaat, Component Volume (Gross): 0.013386 m3

# IfcBuildingElementProxy: Distinct Panel 600 x 1158 x 20, __Panel-D
In: 01 eerste verdieping
Material: Gipsplaat
Component Quantities - Gipsplaat, Mass: 10.98 kg; Gipsplaat, Component Volume (Net): 0.0137249 m3; Gipsplaat, Component Volume (Gross): 0.0137249 m3

# IfcBuildingElementProxy: Distinct Panel 600 x 1175 x 20 (4)
In: 00 begane grond
Material: Gipsplaat
Name
2 x __Panel-D | Component Quantities - Gipsplaat, Mass: 11.1384 kg; Gipsplaat, Component Volume (Net): 0.0139229 m3; Gipsplaat, Component Volume (Gross): 0.0139229 m3
2 x __Panel-D

# IfcBuildingElementProxy: Distinct Panel 600 x 12 x 20 (3)
In: 00 begane grond
Material: Gipsplaat
Name | Gipsplaat, Mass (kg) | Gipsplaat, Component Volume (Net) (m3) = Gipsplaat, Component Volume (Gross) (m3)
__Panel-D | 0.0670724 | 0.0000838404
__Panel-D
__Panel-D | 0.0670724 | 0.0000838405

# IfcBuildingElementProxy: Distinct Panel 600 x 1200 x 20 (9)
Material: Gipsplaat
Name | In
3 x __Panel-D | 00 begane grond | Component Quantities - Gipsplaat, Mass: 11.3756 kg; Gipsplaat, Component Volume (Net): 0.0142195 m3; Gipsplaat, Component Volume (Gross): 0.0142195 m3
2 x __Panel-D | 00 begane grond
__Panel-D | 01 eerste verdieping | Component Quantities - Gipsplaat, Mass: 11.3764 kg; Gipsplaat, Component Volume (Net): 0.0142205 m3; Gipsplaat, Component Volume (Gross): 0.0142205 m3
3 x __Panel-D | 01 eerste verdieping

# IfcBuildingElementProxy: Distinct Panel 600 x 123 x 20 (4)
In: 00 begane grond
Material: Gipsplaat
Name
__Panel-D | Component Quantities - Gipsplaat, Mass: 1.12234 kg; Gipsplaat, Component Volume (Net): 0.00140292 m3; Gipsplaat, Component Volume (Gross): 0.00140292 m3
3 x __Panel-D

# IfcBuildingElementProxy: Distinct Panel 600 x 13 x 20 (10)
In: 01 eerste verdieping
Material: Gipsplaat
Name
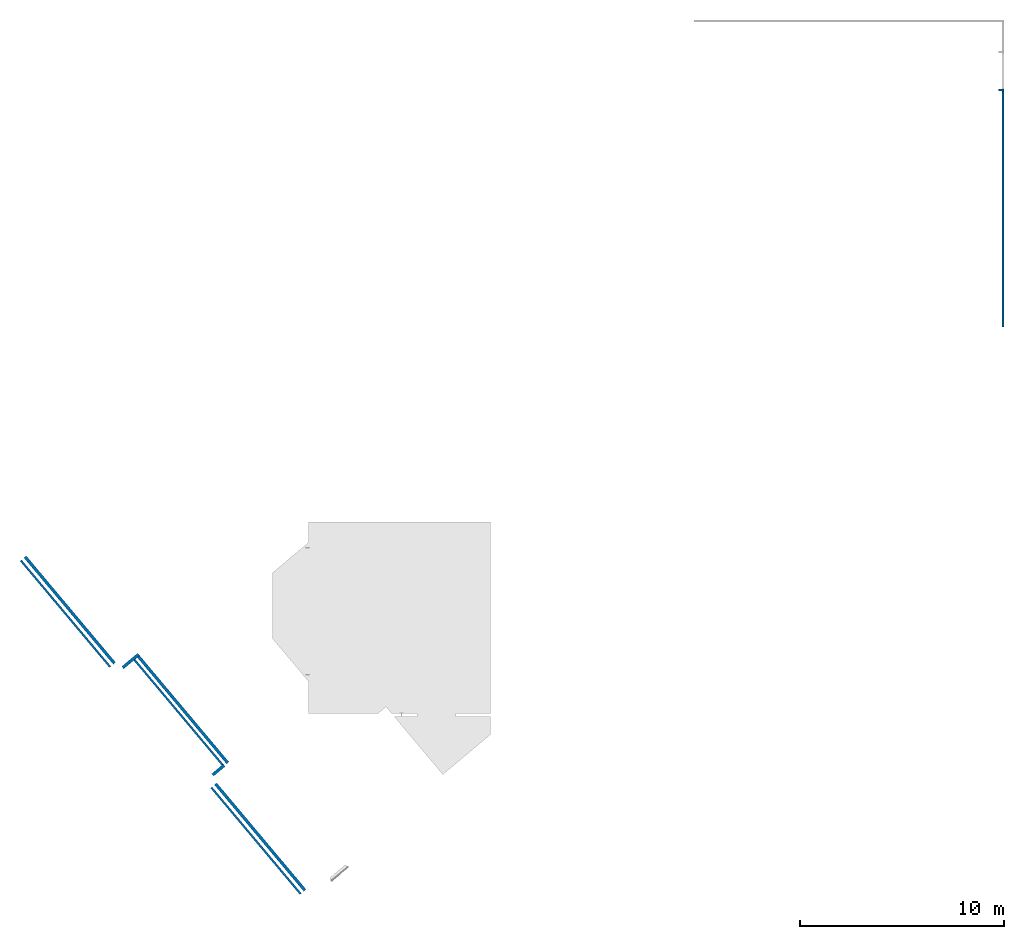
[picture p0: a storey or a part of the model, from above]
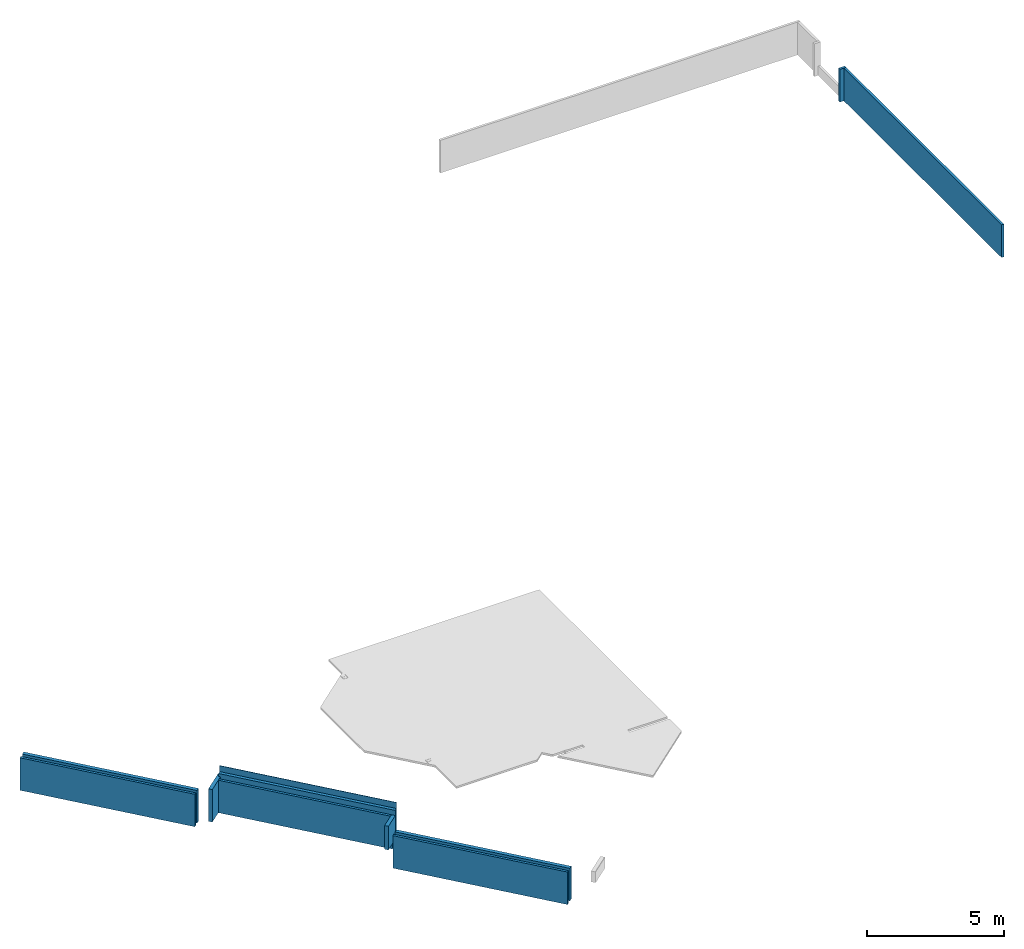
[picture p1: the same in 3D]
Properties of the parts of a building model (IFC2X3), part 7 of 11

# IfcBuildingElementProxy: Distinct Panel 600 x 13 x 20 (10)
Name
__Panel-D | Component Quantities - Gipsplaat, Mass: 0.0714007 kg; Gipsplaat, Component Volume (Net): 0.0000892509 m3; Gipsplaat, Component Volume (Gross): 0.0000892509 m3
9 x __Panel-D

# IfcBuildingElementProxy: Distinct Panel 600 x 149 x 20 (2)
In: 01 eerste verdieping
Material: Gipsplaat
Name | Gipsplaat, Mass (kg) | Gipsplaat, Component Volume (Net) (m3) = Gipsplaat, Component Volume (Gross) (m3)
__Panel-D | 2.67738 | 0.00334672
__Panel-D | 4.30837 | 0.00538547

# IfcBuildingElementProxy: Distinct Panel 600 x 167 x 20, __Panel-D
In: 01 eerste verdieping
Material: Gipsplaat
Component Quantities - Gipsplaat, Mass: 4.41309 kg; Gipsplaat, Component Volume (Net): 0.00551637 m3; Gipsplaat, Component Volume (Gross): 0.00551637 m3

# IfcBuildingElementProxy: Distinct Panel 600 x 171 x 20 (7)
In: 00 begane grond
Material: Gipsplaat
Name
3 x __Panel-D | Component Quantities - Gipsplaat, Mass: 1.58336 kg; Gipsplaat, Component Volume (Net): 0.0019792 m3; Gipsplaat, Component Volume (Gross): 0.0019792 m3
4 x __Panel-D

# IfcBuildingElementProxy: Distinct Panel 600 x 174 x 20, __Panel-D
In: 01 eerste verdieping
Material: Gipsplaat
Component Quantities - Gipsplaat, Mass: 4.45354 kg; Gipsplaat, Component Volume (Net): 0.00556693 m3; Gipsplaat, Component Volume (Gross): 0.00556693 m3

# IfcBuildingElementProxy: Distinct Panel 600 x 176 x 20, __Panel-D
In: 01 eerste verdieping
Material: Gipsplaat
Component Quantities - Gipsplaat, Mass: 1.63197 kg; Gipsplaat, Component Volume (Net): 0.00203996 m3; Gipsplaat, Component Volume (Gross): 0.00203996 m3

# IfcBuildingElementProxy: Distinct Panel 600 x 179 x 20 (2)
In: 01 eerste verdieping
Material: Gipsplaat
Name
__Panel-D | Component Quantities - Gipsplaat, Mass: 1.65851 kg; Gipsplaat, Component Volume (Net): 0.00207313 m3; Gipsplaat, Component Volume (Gross): 0.00207313 m3
__Panel-D

# IfcBuildingElementProxy: Distinct Panel 600 x 212 x 20 (3)
In: 00 begane grond
Material: Gipsplaat
Name | Gipsplaat, Mass (kg) | Gipsplaat, Component Volume (Net) (m3) = Gipsplaat, Component Volume (Gross) (m3)
2 x __Panel-D | 1.97525 | 0.00246907
__Panel-D

# IfcBuildingElementProxy: Distinct Panel 600 x 22 x 20, __Panel-D
In: 01 eerste verdieping
Material: Gipsplaat
Component Quantities - Gipsplaat, Mass: 3.44023 kg; Gipsplaat, Component Volume (Net): 0.00430029 m3; Gipsplaat, Component Volume (Gross): 0.00430029 m3

# IfcBuildingElementProxy: Distinct Panel 600 x 221 x 20 (2)
In: 00 begane grond
Material: Gipsplaat
Name
__Panel-D | Component Quantities - Gipsplaat, Mass: 2.05936 kg; Gipsplaat, Component Volume (Net): 0.0025742 m3; Gipsplaat, Component Volume (Gross): 0.0025742 m3
__Panel-D

# IfcBuildingElementProxy: Distinct Panel 600 x 236 x 20, __Panel-D
In: 01 eerste verdieping
Material: Gipsplaat
Component Quantities - Gipsplaat, Mass: 4.07608 kg; Gipsplaat, Component Volume (Net): 0.0050951 m3; Gipsplaat, Component Volume (Gross): 0.0050951 m3

# IfcBuildingElementProxy: Distinct Panel 600 x 24 x 20 (4)
In: 01 eerste verdieping
Material: Gipsplaat
Name
__Panel-D | Component Quantities - Gipsplaat, Mass: 0.178676 kg; Gipsplaat, Component Volume (Net): 0.000223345 m3; Gipsplaat, Component Volume (Gross): 0.000223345 m3
3 x __Panel-D

# IfcBuildingElementProxy: Distinct Panel 600 x 244 x 20, __Panel-D
In: 00 begane grond
Material: Gipsplaat
Component Quantities - Gipsplaat, Mass: 2.28004 kg; Gipsplaat, Component Volume (Net): 0.00285005 m3; Gipsplaat, Component Volume (Gross): 0.00285005 m3

# IfcBuildingElementProxy: Distinct Panel 600 x 248 x 20 (7)
In: 01 eerste verdieping
Material: Gipsplaat
Name
__Panel-D | Component Quantities - Gipsplaat, Mass: 2.31317 kg; Gipsplaat, Component Volume (Net): 0.00289146 m3; Gipsplaat, Component Volume (Gross): 0.00289146 m3
6 x __Panel-D

# IfcBuildingElementProxy: Distinct Panel 600 x 262 x 20 (3)
In: 00 begane grond
Material: Gipsplaat
Name | Gipsplaat, Mass (kg) | Gipsplaat, Component Volume (Net) (m3) = Gipsplaat, Component Volume (Gross) (m3)
2 x __Panel-D | 2.4514 | 0.00306425
__Panel-D

# IfcBuildingElementProxy: Distinct Panel 600 x 264 x 20, __Panel-D
In: 01 eerste verdieping
Material: Gipsplaat
Component Quantities - Gipsplaat, Mass: 4.91376 kg; Gipsplaat, Component Volume (Net): 0.0061422 m3; Gipsplaat, Component Volume (Gross): 0.0061422 m3

# IfcBuildingElementProxy: Distinct Panel 600 x 267 x 20 (9)
In: 01 eerste verdieping
Material: Gipsplaat
Name
2 x __Panel-D | Component Quantities - Gipsplaat, Mass: 2.49405 kg; Gipsplaat, Component Volume (Net): 0.00311756 m3; Gipsplaat, Component Volume (Gross): 0.00311756 m3
7 x __Panel-D

# IfcBuildingElementProxy: Distinct Panel 600 x 282 x 20, __Panel-D
In: 01 eerste verdieping
Material: Gipsplaat
Component Quantities - Gipsplaat, Mass: 4.99113 kg; Gipsplaat, Component Volume (Net): 0.00623891 m3; Gipsplaat, Component Volume (Gross): 0.00623891 m3

# IfcBuildingElementProxy: Distinct Panel 600 x 289 x 20, __Panel-D
In: 01 eerste verdieping
Material: Gipsplaat
Component Quantities - Gipsplaat, Mass: 5.02071 kg; Gipsplaat, Component Volume (Net): 0.00627589 m3; Gipsplaat, Component Volume (Gross): 0.00627589 m3

# IfcBuildingElementProxy: Distinct Panel 600 x 30 x 20 (3)
In: 00 begane grond
Material: Gipsplaat
Name
__Panel-D | Component Quantities - Gipsplaat, Mass: 0.237145 kg; Gipsplaat, Component Volume (Net): 0.000296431 m3; Gipsplaat, Component Volume (Gross): 0.000296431 m3
2 x __Panel-D

# IfcBuildingElementProxy: Distinct Panel 600 x 317 x 20 (4)
In: 00 begane grond
Material: Gipsplaat
Name
__Panel-D | Component Quantities - Gipsplaat, Mass: 2.96656 kg; Gipsplaat, Component Volume (Net): 0.0037082 m3; Gipsplaat, Component Volume (Gross): 0.0037082 m3
2 x __Panel-D
__Panel-D | Component Quantities - Gipsplaat, Mass: 3.76626 kg; Gipsplaat, Component Volume (Net): 0.00470783 m3; Gipsplaat, Component Volume (Gross): 0.00470783 m3

# IfcBuildingElementProxy: Distinct Panel 600 x 320 x 20 (3)
In: 00 begane grond
Material: Gipsplaat
Name | Gipsplaat, Mass (kg) | Gipsplaat, Component Volume (Net) (m3) = Gipsplaat, Component Volume (Gross) (m3)
2 x __Panel-D | 2.99621 | 0.00374527
__Panel-D

# IfcBuildingElementProxy: Distinct Panel 600 x 321 x 20 (2)
In: 01 eerste verdieping
Material: Gipsplaat
Name
__Panel-D | Component Quantities - Gipsplaat, Mass: 3.00629 kg; Gipsplaat, Component Volume (Net): 0.00375786 m3; Gipsplaat, Component Volume (Gross): 0.00375786 m3
__Panel-D

# IfcBuildingElementProxy: Distinct Panel 600 x 327 x 20, __Panel-D
In: 00 begane grond
Material: Gipsplaat
Component Quantities - Gipsplaat, Mass: 4.73721 kg; Gipsplaat, Component Volume (Net): 0.00592151 m3; Gipsplaat, Component Volume (Gross): 0.00592151 m3

# IfcBuildingElementProxy: Distinct Panel 600 x 328 x 20 (12)
In: 00 begane grond
Material: Gipsplaat
Name
2 x __Panel-D | Component Quantities - Gipsplaat, Mass: 3.07051 kg; Gipsplaat, Component Volume (Net): 0.00383813 m3; Gipsplaat, Component Volume (Gross): 0.00383813 m3
10 x __Panel-D

# IfcBuildingElementProxy: Distinct Panel 600 x 332 x 20 (2)
In: 00 begane grond
Material: Gipsplaat
Component Quantities - Gipsplaat, Mass: 3.11694 kg; Gipsplaat, Component Volume (Net): 0.00389618 m3; Gipsplaat, Component Volume (Gross): 0.00389618 m3

# IfcBuildingElementProxy: Distinct Panel 600 x 333 x 20 (2)
In: 00 begane grond
Material: Gipsplaat
Component Quantities - Gipsplaat, Mass: 3.11867 kg; Gipsplaat, Component Volume (Net): 0.00389834 m3; Gipsplaat, Component Volume (Gross): 0.00389834 m3

# IfcBuildingElementProxy: Distinct Panel 600 x 34 x 20, __Panel-D
In: 01 eerste verdieping
Material: Gipsplaat
Component Quantities - Gipsplaat, Mass: 3.52527 kg; Gipsplaat, Component Volume (Net): 0.00440659 m3; Gipsplaat, Component Volume (Gross): 0.00440659 m3

# IfcBuildingElementProxy: Distinct Panel 600 x 341 x 20, __Panel-D
In: 01 eerste verdieping
Material: Gipsplaat
Component Quantities - Gipsplaat, Mass: 4.59476 kg; Gipsplaat, Component Volume (Net): 0.00574345 m3; Gipsplaat, Component Volume (Gross): 0.00574345 m3

# IfcBuildingElementProxy: Distinct Panel 600 x 342 x 20 (3)
In: 00 begane grond
Material: Gipsplaat
Name | Gipsplaat, Mass (kg) | Gipsplaat, Component Volume (Net) (m3) = Gipsplaat, Component Volume (Gross) (m3)
2 x __Panel-D | 3.20456 | 0.0040057
__Panel-D

# IfcBuildingElementProxy: Distinct Panel 600 x 345 x 20 (3)
In: 00 begane grond
Material: Gipsplaat
Name | Gipsplaat, Mass (kg) | Gipsplaat, Component Volume (Net) (m3) = Gipsplaat, Component Volume (Gross) (m3)
__Panel-D | 3.2394 | 0.00404925
__Panel-D | 3.23939 | 0.00404924
__Panel-D

# IfcBuildingElementProxy: Distinct Panel 600 x 350 x 20 (4)
In: 00 begane grond
Material: Gipsplaat
Name | Gipsplaat, Mass (kg) | Gipsplaat, Component Volume (Net) (m3) = Gipsplaat, Component Volume (Gross) (m3)
3 x __Panel-D | 3.28233 | 0.00410291
__Panel-D

# IfcBuildingElementProxy: Distinct Panel 600 x 361 x 20 (6)
In: 00 begane grond
Material: Gipsplaat
Name | Gipsplaat, Mass (kg) | Gipsplaat, Component Volume (Net) (m3) = Gipsplaat, Component Volume (Gross) (m3)
5 x __Panel-D | 3.38598 | 0.00423247
__Panel-D

# IfcBuildingElementProxy: Distinct Panel 600 x 363 x 20 (6)
In: 00 begane grond
Material: Gipsplaat
Name
3 x __Panel-D | Component Quantities - Gipsplaat, Mass: 3.4034 kg; Gipsplaat, Component Volume (Net): 0.00425425 m3; Gipsplaat, Component Volume (Gross): 0.00425425 m3
3 x __Panel-D

# IfcBuildingElementProxy: Distinct Panel 600 x 375 x 20 (5)
In: 00 begane grond
Material: Gipsplaat
Name | Gipsplaat, Mass (kg) | Gipsplaat, Component Volume (Net) (m3) = Gipsplaat, Component Volume (Gross) (m3)
4 x __Panel-D | 3.52194 | 0.00440243
__Panel-D

# IfcBuildingElementProxy: Distinct Panel 600 x 379 x 20, __Panel-D
In: 01 eerste verdieping
Material: Gipsplaat
Component Quantities - Gipsplaat, Mass: 5.34143 kg; Gipsplaat, Component Volume (Net): 0.00667678 m3; Gipsplaat, Component Volume (Gross): 0.00667678 m3

# IfcBuildingElementProxy: Distinct Panel 600 x 395 x 20, __Panel-D
In: 01 eerste verdieping
Material: Gipsplaat
Component Quantities - Gipsplaat, Mass: 3.71261 kg; Gipsplaat, Component Volume (Net): 0.00464076 m3; Gipsplaat, Component Volume (Gross): 0.00464076 m3

# IfcBuildingElementProxy: Distinct Panel 600 x 399 x 20, __Panel-D
In: 00 begane grond
Material: Gipsplaat
Component Quantities - Gipsplaat, Mass: 3.75096 kg; Gipsplaat, Component Volume (Net): 0.0046887 m3; Gipsplaat, Component Volume (Gross): 0.0046887 m3

# IfcBuildingElementProxy: Distinct Panel 600 x 4 x 20, __Panel-D
In: 01 eerste verdieping
Material: Gipsplaat
Component Quantities - Gipsplaat, Mass: 9.49145 kg; Gipsplaat, Component Volume (Net): 0.0118643 m3; Gipsplaat, Component Volume (Gross): 0.0118643 m3

# IfcBuildingElementProxy: Distinct Panel 600 x 404 x 20, __Panel-D
In: 01 eerste verdieping
Material: Gipsplaat
Component Quantities - Gipsplaat, Mass: 5.41017 kg; Gipsplaat, Component Volume (Net): 0.00676271 m3; Gipsplaat, Component Volume (Gross): 0.00676271 m3

# IfcBuildingElementProxy: Distinct Panel 600 x 412 x 20 (3)
In: 00 begane grond
Material: Gipsplaat
Name
__Panel-D | Component Quantities - Gipsplaat, Mass: 3.87854 kg; Gipsplaat, Component Volume (Net): 0.00484817 m3; Gipsplaat, Component Volume (Gross): 0.00484817 m3
2 x __Panel-D

# IfcBuildingElementProxy: Distinct Panel 600 x 425 x 20 (5)
In: 00 begane grond
Material: Gipsplaat
Name | Gipsplaat, Mass (kg) | Gipsplaat, Component Volume (Net) (m3) = Gipsplaat, Component Volume (Gross) (m3)
3 x __Panel-D | 3.99794 | 0.00499743
2 x __Panel-D

# IfcBuildingElementProxy: Distinct Panel 600 x 427 x 20 (3)
In: 00 begane grond
Material: Gipsplaat
Name
__Panel-D | Component Quantities - Gipsplaat, Mass: 4.01268 kg; Gipsplaat, Component Volume (Net): 0.00501585 m3; Gipsplaat, Component Volume (Gross): 0.00501585 m3
2 x __Panel-D

# IfcBuildingElementProxy: Distinct Panel 600 x 432 x 20 (8)
In: 00 begane grond
Material: Gipsplaat
Name
4 x __Panel-D | Component Quantities - Gipsplaat, Mass: 4.06651 kg; Gipsplaat, Component Volume (Net): 0.00508314 m3; Gipsplaat, Component Volume (Gross): 0.00508314 m3
4 x __Panel-D

# IfcBuildingElementProxy: Distinct Panel 600 x 437 x 20 (11)
In: 00 begane grond
Material: Gipsplaat
Name
2 x __Panel-D | Component Quantities - Gipsplaat, Mass: 4.11709 kg; Gipsplaat, Component Volume (Net): 0.00514637 m3; Gipsplaat, Component Volume (Gross): 0.00514637 m3
9 x __Panel-D

# IfcBuildingElementProxy: Distinct Panel 600 x 449 x 20 (2)
In: 01 eerste verdieping
Material: Gipsplaat
Name | Gipsplaat, Mass (kg) | Gipsplaat, Component Volume (Net) (m3) = Gipsplaat, Component Volume (Gross) (m3)
__Panel-D | 4.2256 | 0.005282
__Panel-D | 4.22561 | 0.00528202

# IfcBuildingElementProxy: Distinct Panel 600 x 450 x 20 (3)
In: 00 begane grond
Material: Gipsplaat
Name
__Panel-D | Component Quantities - Gipsplaat, Mass: 4.23665 kg; Gipsplaat, Component Volume (Net): 0.00529581 m3; Gipsplaat, Component Volume (Gross): 0.00529581 m3
2 x __Panel-D

# IfcBuildingElementProxy: Distinct Panel 600 x 461 x 20 (3)
In: 01 eerste verdieping
Material: Gipsplaat
Name | Gipsplaat, Mass (kg) | Gipsplaat, Component Volume (Net) (m3) = Gipsplaat, Component Volume (Gross) (m3)
2 x __Panel-D | 4.33719 | 0.00542149
__Panel-D

# IfcBuildingElementProxy: Distinct Panel 600 x 462 x 20 (13)
In: 00 begane grond
Material: Gipsplaat
Name
__Panel-D | Component Quantities - Gipsplaat, Mass: 4.35064 kg; Gipsplaat, Component Volume (Net): 0.0054383 m3; Gipsplaat, Component Volume (Gross): 0.0054383 m3
__Panel-D | Component Quantities - Gipsplaat, Mass: 4.35063 kg; Gipsplaat, Component Volume (Net): 0.00543829 m3; Gipsplaat, Component Volume (Gross): 0.00543829 m3
8 x __Panel-D
__Panel-D | Component Quantities - Gipsplaat, Mass: 4.35056 kg; Gipsplaat, Component Volume (Net): 0.00543821 m3; Gipsplaat, Component Volume (Gross): 0.00543821 m3
2 x __Panel-D | Component Quantities - Gipsplaat, Mass: 4.35059 kg; Gipsplaat, Component Volume (Net): 0.00543824 m3; Gipsplaat, Component Volume (Gross): 0.00543824 m3

# IfcBuildingElementProxy: Distinct Panel 600 x 468 x 20 (4)
In: 01 eerste verdieping
Material: Gipsplaat
Name
__Panel-D | Component Quantities - Gipsplaat, Mass: 4.40792 kg; Gipsplaat, Component Volume (Net): 0.0055099 m3; Gipsplaat, Component Volume (Gross): 0.0055099 m3
2 x __Panel-D
__Panel-D | Component Quantities - Gipsplaat, Mass: 4.40776 kg; Gipsplaat, Component Volume (Net): 0.0055097 m3; Gipsplaat, Component Volume (Gross): 0.0055097 m3

# IfcBuildingElementProxy: Distinct Panel 600 x 47 x 20, __Panel-D
In: 01 eerste verdieping
Material: Gipsplaat
Component Quantities - Gipsplaat, Mass: 5.48557 kg; Gipsplaat, Component Volume (Net): 0.00685697 m3; Gipsplaat, Component Volume (Gross): 0.00685697 m3

# IfcBuildingElementProxy: Distinct Panel 600 x 470 x 20 (10)
In: 00 begane grond
Material: Gipsplaat
Name
2 x __Panel-D | Component Quantities - Gipsplaat, Mass: 4.4242 kg; Gipsplaat, Component Volume (Net): 0.00553025 m3; Gipsplaat, Component Volume (Gross): 0.00553025 m3
7 x __Panel-D
__Panel-D | Component Quantities - Gipsplaat, Mass: 5.39498 kg; Gipsplaat, Component Volume (Net): 0.00674373 m3; Gipsplaat, Component Volume (Gross): 0.00674373 m3

# IfcBuildingElementProxy: Distinct Panel 600 x 471 x 20, __Panel-D
In: 00 begane grond
Material: Gipsplaat
Component Quantities - Gipsplaat, Mass: 4.43973 kg; Gipsplaat, Component Volume (Net): 0.00554967 m3; Gipsplaat, Component Volume (Gross): 0.00554967 m3

# IfcBuildingElementProxy: Distinct Panel 600 x 475 x 20 (7)
In: 00 begane grond
Material: Gipsplaat
Name | Gipsplaat, Mass (kg) | Gipsplaat, Component Volume (Net) (m3) = Gipsplaat, Component Volume (Gross) (m3)
2 x __Panel-D | 4.47233 | 0.00559041
2 x __Panel-D
3 x __Panel-D | 4.47465 | 0.00559331

# IfcBuildingElementProxy: Distinct Panel 600 x 478 x 20, __Panel-D
In: 01 eerste verdieping
Material: Gipsplaat
Component Quantities - Gipsplaat, Mass: 4.50756 kg; Gipsplaat, Component Volume (Net): 0.00563445 m3; Gipsplaat, Component Volume (Gross): 0.00563445 m3

# IfcBuildingElementProxy: Distinct Panel 600 x 480 x 20 (4)
In: 01 eerste verdieping
Material: Gipsplaat
Name | Gipsplaat, Mass (kg) | Gipsplaat, Component Volume (Net) (m3) = Gipsplaat, Component Volume (Gross) (m3)
3 x __Panel-D | 4.52152 | 0.0056519
__Panel-D

# IfcBuildingElementProxy: Distinct Panel 600 x 488 x 20 (3)
In: 00 begane grond
Material: Gipsplaat
Component Quantities - Gipsplaat, Mass: 4.59599 kg; Gipsplaat, Component Volume (Net): 0.00574499 m3; Gipsplaat, Component Volume (Gross): 0.00574499 m3

# IfcBuildingElementProxy: Distinct Panel 600 x 494 x 20 (4)
In: 00 begane grond
Material: Gipsplaat
Component Quantities - Gipsplaat, Mass: 4.65233 kg; Gipsplaat, Component Volume (Net): 0.00581542 m3; Gipsplaat, Component Volume (Gross): 0.00581542 m3

# IfcBuildingElementProxy: Distinct Panel 600 x 495 x 20 (9)
In: 00 begane grond
Material: Gipsplaat
Name
3 x __Panel-D | Component Quantities - Gipsplaat, Mass: 4.6674 kg; Gipsplaat, Component Volume (Net): 0.00583425 m3; Gipsplaat, Component Volume (Gross): 0.00583425 m3
6 x __Panel-D

# IfcBuildingElementProxy: Distinct Panel 600 x 497 x 20 (4)
In: 00 begane grond
Material: Gipsplaat
Component Quantities - Gipsplaat, Component Volume (Net): 0.00585482 m3; Gipsplaat, Component Volume (Gross): 0.00585482 m3
Name | Gipsplaat, Mass (kg)
2 x __Panel-D | 4.68386
2 x __Panel-D | 4.68385

# IfcBuildingElementProxy: Distinct Panel 600 x 499 x 20 (5)
In: 00 begane grond
Material: Gipsplaat
Name
2 x __Panel-D | Component Quantities - Gipsplaat, Mass: 4.70273 kg; Gipsplaat, Component Volume (Net): 0.00587841 m3; Gipsplaat, Component Volume (Gross): 0.00587841 m3
3 x __Panel-D

# IfcBuildingElementProxy: Distinct Panel 600 x 50 x 20 (3)
In: 00 begane grond
Material: Gipsplaat
Name
__Panel-D | Component Quantities - Gipsplaat, Mass: 0.428207 kg; Gipsplaat, Component Volume (Net): 0.000535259 m3; Gipsplaat, Component Volume (Gross): 0.000535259 m3
2 x __Panel-D

# IfcBuildingElementProxy: Distinct Panel 600 x 503 x 20 (14)
In: 00 begane grond
Material: Gipsplaat
Name
3 x __Panel-D | Component Quantities - Gipsplaat, Mass: 4.74096 kg; Gipsplaat, Component Volume (Net): 0.0059262 m3; Gipsplaat, Component Volume (Gross): 0.0059262 m3
11 x __Panel-D

# IfcBuildingElementProxy: Distinct Panel 600 x 519 x 20, __Panel-D
In: 01 eerste verdieping
Material: Gipsplaat
Component Quantities - Gipsplaat, Mass: 5.62191 kg; Gipsplaat, Component Volume (Net): 0.00702739 m3; Gipsplaat, Component Volume (Gross): 0.00702739 m3

# IfcBuildingElementProxy: Distinct Panel 600 x 52 x 20, __Panel-D
In: 01 eerste verdieping
Material: Gipsplaat
Component Quantities - Gipsplaat, Mass: 3.65734 kg; Gipsplaat, Component Volume (Net): 0.00457167 m3; Gipsplaat, Component Volume (Gross): 0.00457167 m3

# IfcBuildingElementProxy: Distinct Panel 600 x 524 x 20 (4)
In: 01 eerste verdieping
Material: Gipsplaat
Name
2 x __Panel-D | Component Quantities - Gipsplaat, Mass: 4.9445 kg; Gipsplaat, Component Volume (Net): 0.00618062 m3; Gipsplaat, Component Volume (Gross): 0.00618062 m3
2 x __Panel-D

# IfcBuildingElementProxy: Distinct Panel 600 x 531 x 20, __Panel-D
In: 01 eerste verdieping
Material: Gipsplaat
Component Quantities - Gipsplaat, Mass: 5.6343 kg; Gipsplaat, Component Volume (Net): 0.00704288 m3; Gipsplaat, Component Volume (Gross): 0.00704288 m3

# IfcBuildingElementProxy: Distinct Panel 600 x 534 x 20, __Panel-D
In: 01 eerste verdieping
Material: Gipsplaat
Component Quantities - Gipsplaat, Mass: 2.63004 kg; Gipsplaat, Component Volume (Net): 0.00328755 m3; Gipsplaat, Component Volume (Gross): 0.00328755 m3

# IfcBuildingElementProxy: Distinct Panel 600 x 538 x 20 (3)
In: 00 begane grond
Material: Gipsplaat
Name | Gipsplaat, Mass (kg) | Gipsplaat, Component Volume (Net) (m3) = Gipsplaat, Component Volume (Gross) (m3)
2 x __Panel-D | 5.07199 | 0.00633999
__Panel-D

# IfcBuildingElementProxy: Distinct Panel 600 x 539 x 20 (3)
In: 00 begane grond
Material: Gipsplaat
Component Quantities - Gipsplaat, Mass: 5.08192 kg; Gipsplaat, Component Volume (Net): 0.00635241 m3; Gipsplaat, Component Volume (Gross): 0.00635241 m3

# IfcBuildingElementProxy: Distinct Panel 600 x 544 x 20 (18)
Material: Gipsplaat
Name | In
__Panel-D | 00 begane grond | Component Quantities - Gipsplaat, Mass: 5.12708 kg; Gipsplaat, Component Volume (Net): 0.00640885 m3; Gipsplaat, Component Volume (Gross): 0.00640885 m3
3 x __Panel-D | 00 begane grond
__Panel-D | 01 eerste verdieping | Component Quantities - Gipsplaat, Mass: 5.12046 kg; Gipsplaat, Component Volume (Net): 0.00640057 m3; Gipsplaat, Component Volume (Gross): 0.00640057 m3
__Panel-D | 01 eerste verdieping | Component Quantities - Gipsplaat, Mass: 5.12874 kg; Gipsplaat, Component Volume (Net): 0.00641092 m3; Gipsplaat, Component Volume (Gross): 0.00641092 m3
12 x __Panel-D | 01 eerste verdieping

# IfcBuildingElementProxy: Distinct Panel 600 x 546 x 20 (6)
In: 01 eerste verdieping
Material: Gipsplaat
Name
__Panel-D | Component Quantities - Gipsplaat, Mass: 5.15003 kg; Gipsplaat, Component Volume (Net): 0.00643754 m3; Gipsplaat, Component Volume (Gross): 0.00643754 m3
5 x __Panel-D

# IfcBuildingElementProxy: Distinct Panel 600 x 549 x 20 (5)
In: 00 begane grond
Material: Gipsplaat
Name | Gipsplaat, Mass (kg) | Gipsplaat, Component Volume (Net) (m3) = Gipsplaat, Component Volume (Gross) (m3)
2 x __Panel-D | 5.17873 | 0.00647341
2 x __Panel-D
__Panel-D | 4.10403 | 0.00513004

# IfcBuildingElementProxy: Distinct Panel 600 x 55 x 20 (3)
Material: Gipsplaat
Name | In | Gipsplaat, Mass (kg) | Gipsplaat, Component Volume (Net) (m3) = Gipsplaat, Component Volume (Gross) (m3)
2 x __Panel-D | 00 begane grond | 0.478448 | 0.00059806
__Panel-D | 01 eerste verdieping | 0.47619 | 0.000595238

# IfcBuildingElementProxy: Distinct Panel 600 x 550 x 20 (5)
In: 00 begane grond
Material: Gipsplaat
Name
2 x __Panel-D | Component Quantities - Gipsplaat, Mass: 5.18752 kg; Gipsplaat, Component Volume (Net): 0.0064844 m3; Gipsplaat, Component Volume (Gross): 0.0064844 m3
3 x __Panel-D

# IfcBuildingElementProxy: Distinct Panel 600 x 561 x 20, __Panel-D
In: 00 begane grond
Material: Gipsplaat
Component Quantities - Gipsplaat, Mass: 5.29623 kg; Gipsplaat, Component Volume (Net): 0.00662028 m3; Gipsplaat, Component Volume (Gross): 0.00662028 m3

# IfcBuildingElementProxy: Distinct Panel 600 x 564 x 20 (11)
Material: Gipsplaat
Name | In
2 x __Panel-D | 00 begane grond | Component Quantities - Gipsplaat, Mass: 5.3208 kg; Gipsplaat, Component Volume (Net): 0.006651 m3; Gipsplaat, Component Volume (Gross): 0.006651 m3
6 x __Panel-D | 00 begane grond
3 x __Panel-D | 01 eerste verdieping | Component Quantities - Gipsplaat, Mass: 5.32561 kg; Gipsplaat, Component Volume (Net): 0.00665701 m3; Gipsplaat, Component Volume (Gross): 0.00665701 m3

# IfcBuildingElementProxy: Distinct Panel 600 x 566 x 20 (2)
In: 00 begane grond
Material: Gipsplaat
Name
__Panel-D | Component Quantities - Gipsplaat, Mass: 5.33984 kg; Gipsplaat, Component Volume (Net): 0.0066748 m3; Gipsplaat, Component Volume (Gross): 0.0066748 m3
__Panel-D

# IfcBuildingElementProxy: Distinct Panel 600 x 570 x 20, __Panel-D
In: 01 eerste verdieping
Material: Gipsplaat
Component Quantities - Gipsplaat, Mass: 2.97652 kg; Gipsplaat, Component Volume (Net): 0.00372066 m3; Gipsplaat, Component Volume (Gross): 0.00372066 m3

# IfcBuildingElementProxy: Distinct Panel 600 x 571 x 20 (6)
In: 01 eerste verdieping
Material: Gipsplaat
Name
__Panel-D | Component Quantities - Gipsplaat, Mass: 5.38802 kg; Gipsplaat, Component Volume (Net): 0.00673503 m3; Gipsplaat, Component Volume (Gross): 0.00673503 m3
5 x __Panel-D

# IfcBuildingElementProxy: Distinct Panel 600 x 572 x 20 (7)
In: 01 eerste verdieping
Material: Gipsplaat
Name
3 x __Panel-D | Component Quantities - Gipsplaat, Mass: 5.39701 kg; Gipsplaat, Component Volume (Net): 0.00674626 m3; Gipsplaat, Component Volume (Gross): 0.00674626 m3
4 x __Panel-D

# IfcBuildingElementProxy: Distinct Panel 600 x 575 x 20, __Panel-D
In: 00 begane grond
Material: Gipsplaat
Component Quantities - Gipsplaat, Mass: 5.42551 kg; Gipsplaat, Component Volume (Net): 0.00678189 m3; Gipsplaat, Component Volume (Gross): 0.00678189 m3

# IfcBuildingElementProxy: Distinct Panel 600 x 590 x 20 (10)
In: 01 eerste verdieping
Material: Gipsplaat
Name
2 x __Panel-D | Component Quantities - Gipsplaat, Mass: 5.56903 kg; Gipsplaat, Component Volume (Net): 0.00696129 m3; Gipsplaat, Component Volume (Gross): 0.00696129 m3
7 x __Panel-D
__Panel-D | Component Quantities - Gipsplaat, Mass: 5.39903 kg; Gipsplaat, Component Volume (Net): 0.00674879 m3; Gipsplaat, Component Volume (Gross): 0.00674879 m3

# IfcBuildingElementProxy: Distinct Panel 600 x 592 x 20 (4)
In: 00 begane grond
Material: Gipsplaat
Name
2 x __Panel-D | Component Quantities - Gipsplaat, Mass: 5.59211 kg; Gipsplaat, Component Volume (Net): 0.00699013 m3; Gipsplaat, Component Volume (Gross): 0.00699013 m3
2 x __Panel-D

# IfcBuildingElementProxy: Distinct Panel 600 x 596 x 20 (4)
In: 01 eerste verdieping
Material: Gipsplaat
Name | Gipsplaat, Mass (kg) | Gipsplaat, Component Volume (Net) (m3) = Gipsplaat, Component Volume (Gross) (m3)
2 x __Panel-D | 5.62616 | 0.0070327
2 x __Panel-D | 5.62632 | 0.0070329

# IfcBuildingElementProxy: Distinct Panel 600 x 597 x 20 (7)
In: 01 eerste verdieping
Material: Gipsplaat
Name
2 x __Panel-D | Component Quantities - Gipsplaat, Mass: 5.63667 kg; Gipsplaat, Component Volume (Net): 0.00704584 m3; Gipsplaat, Component Volume (Gross): 0.00704584 m3
5 x __Panel-D

# IfcBuildingElementProxy: Distinct Panel 600 x 600 x 20 (1874)
Material: Gipsplaat
Name | In
25 x __Panel-D | 00 begane grond | Component Quantities - Gipsplaat, Mass: 5.6644 kg; Gipsplaat, Component Volume (Net): 0.0070805 m3; Gipsplaat, Component Volume (Gross): 0.0070805 m3
943 x __Panel-D | 00 begane grond
2 x __Panel-D | 00 begane grond | Component Quantities - Gipsplaat, Mass: 5.61905 kg; Gipsplaat, Component Volume (Net): 0.00702381 m3; Gipsplaat, Component Volume (Gross): 0.00702381 m3
__Panel-D | 00 begane grond | Component Quantities - Gipsplaat, Mass: 5.37058 kg; Gipsplaat, Component Volume (Net): 0.00671322 m3; Gipsplaat, Component Volume (Gross): 0.00671322 m3
__Panel-D | 00 begane grond | Component Quantities - Gipsplaat, Mass: 5.60712 kg; Gipsplaat, Component Volume (Net): 0.00700891 m3; Gipsplaat, Component Volume (Gross): 0.00700891 m3
__Panel-D | 00 begane grond | Component Quantities - Gipsplaat, Mass: 4.81206 kg; Gipsplaat, Component Volume (Net): 0.00601507 m3; Gipsplaat, Component Volume (Gross): 0.00601507 m3
__Panel-D | 00 begane grond | Component Quantities - Gipsplaat, Mass: 5.00184 kg; Gipsplaat, Component Volume (Net): 0.0062523 m3; Gipsplaat, Component Volume (Gross): 0.0062523 m3
__Panel-D | 00 begane grond | Component Quantities - Gipsplaat, Mass: 4.4277 kg; Gipsplaat, Component Volume (Net): 0.00553462 m3; Gipsplaat, Component Volume (Gross): 0.00553462 m3
__Panel-D | 00 begane grond | Component Quantities - Gipsplaat, Mass: 5.64077 kg; Gipsplaat, Component Volume (Net): 0.00705097 m3; Gipsplaat, Component Volume (Gross): 0.00705097 m3
__Panel-D | 00 begane grond | Component Quantities - Gipsplaat, Mass: 3.67584 kg; Gipsplaat, Component Volume (Net): 0.0045948 m3; Gipsplaat, Component Volume (Gross): 0.0045948 m3
__Panel-D | 00 begane grond | Component Quantities - Gipsplaat, Mass: 5.46027 kg; Gipsplaat, Component Volume (Net): 0.00682534 m3; Gipsplaat, Component Volume (Gross): 0.00682534 m3
883 x __Panel-D | 01 eerste verdieping
__Panel-D | 01 eerste verdieping | Component Quantities - Gipsplaat, Mass: 5.37479 kg; Gipsplaat, Component Volume (Net): 0.00671849 m3; Gipsplaat, Component Volume (Gross): 0.00671849 m3
2 x __Panel-D | 01 eerste verdieping | Component Quantities - Gipsplaat, Mass: 5.6644 kg; Gipsplaat, Component Volume (Net): 0.0070805 m3; Gipsplaat, Component Volume (Gross): 0.0070805 m3
__Panel-D | 01 eerste verdieping | Component Quantities - Gipsplaat, Mass: 5.41589 kg; Gipsplaat, Component Volume (Net): 0.00676986 m3; Gipsplaat, Component Volume (Gross): 0.00676986 m3
__Panel-D | 01 eerste verdieping | Component Quantities - Gipsplaat, Mass: 3.88036 kg; Gipsplaat, Component Volume (Net): 0.00485044 m3; Gipsplaat, Component Volume (Gross): 0.00485044 m3
__Panel-D | 01 eerste verdieping | Component Quantities - Gipsplaat, Mass: 5.62423 kg; Gipsplaat, Component Volume (Net): 0.00703029 m3; Gipsplaat, Component Volume (Gross): 0.00703029 m3
__Panel-D | 01 eerste verdieping | Component Quantities - Gipsplaat, Mass: 3.54192 kg; Gipsplaat, Component Volume (Net): 0.0044274 m3; Gipsplaat, Component Volume (Gross): 0.0044274 m3
__Panel-D | 01 eerste verdieping | Component Quantities - Gipsplaat, Mass: 1.03063 kg; Gipsplaat, Component Volume (Net): 0.00128828 m3; Gipsplaat, Component Volume (Gross): 0.00128828 m3
__Panel-D | 01 eerste verdieping | Component Quantities - Gipsplaat, Mass: 4.55151 kg; Gipsplaat, Component Volume (Net): 0.00568938 m3; Gipsplaat, Component Volume (Gross): 0.00568938 m3
__Panel-D | 01 eerste verdieping | Component Quantities - Gipsplaat, Mass: 5.34857 kg; Gipsplaat, Component Volume (Net): 0.00668571 m3; Gipsplaat, Component Volume (Gross): 0.00668571 m3
__Panel-D | 01 eerste verdieping | Component Quantities - Gipsplaat, Mass: 5.11647 kg; Gipsplaat, Component Volume (Net): 0.00639559 m3; Gipsplaat, Component Volume (Gross): 0.00639559 m3
__Panel-D | 01 eerste verdieping | Component Quantities - Gipsplaat, Mass: 5.27737 kg; Gipsplaat, Component Volume (Net): 0.00659672 m3; Gipsplaat, Component Volume (Gross): 0.00659672 m3
__Panel-D | 01 eerste verdieping | Component Quantities - Gipsplaat, Mass: 5.39551 kg; Gipsplaat, Component Volume (Net): 0.00674439 m3; Gipsplaat, Component Volume (Gross): 0.00674439 m3

# IfcBuildingElementProxy: Distinct Panel 600 x 65 x 20 (2)
In: 00 begane grond
Material: Gipsplaat
Component Quantities - Gipsplaat, Mass: 0.571786 kg; Gipsplaat, Component Volume (Net): 0.000714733 m3; Gipsplaat, Component Volume (Gross): 0.000714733 m3

# IfcBuildingElementProxy: Distinct Panel 600 x 67 x 20 (3)
In: 00 begane grond
Material: Gipsplaat
Name | Gipsplaat, Mass (kg) | Gipsplaat, Component Volume (Net) (m3) = Gipsplaat, Component Volume (Gross) (m3)
2 x __Panel-D | 0.585633 | 0.000732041
__Panel-D

# IfcBuildingElementProxy: Distinct Panel 600 x 947 x 20 (2)
In: 01 eerste verdieping
Material: Gipsplaat
Name
__Panel-D | Component Quantities - Gipsplaat, Mass: 8.97102 kg; Gipsplaat, Component Volume (Net): 0.0112138 m3; Gipsplaat, Component Volume (Gross): 0.0112138 m3
__Panel-D

# IfcBuildingElementProxy: Distinct Panel 600 x 95 x 20, __Panel-D
In: 01 eerste verdieping
Material: Gipsplaat
Component Quantities - Gipsplaat, Mass: 0.851983 kg; Gipsplaat, Component Volume (Net): 0.00106498 m3; Gipsplaat, Component Volume (Gross): 0.00106498 m3

# IfcBuildingElementProxy: Distinct Panel 600 x 950 x 20 (3)
In: 01 eerste verdieping
Material: Gipsplaat
Name
__Panel-D | Component Quantities - Gipsplaat, Mass: 8.99482 kg; Gipsplaat, Component Volume (Net): 0.0112435 m3; Gipsplaat, Component Volume (Gross): 0.0112435 m3
2 x __Panel-D

# IfcBuildingElementProxy: Distinct Panel 600 x 969 x 20, __Panel-D
In: 00 begane grond
Material: Gipsplaat
Component Quantities - Gipsplaat, Mass: 9.42277 kg; Gipsplaat, Component Volume (Net): 0.0117785 m3; Gipsplaat, Component Volume (Gross): 0.0117785 m3

# IfcBuildingElementProxy: Distinct Panel 600 x 993 x 20 (4)
In: 00 begane grond
Material: Gipsplaat
Name | Gipsplaat, Mass (kg) | Gipsplaat, Component Volume (Net) (m3) = Gipsplaat, Component Volume (Gross) (m3)
3 x __Panel-D | 9.40105 | 0.0117513
__Panel-D

# IfcBuildingElementProxy: Distinct Panel 79 x 600 x 20, __Panel-D
In: 01 eerste verdieping
Material: Gipsplaat
Component Quantities - Gipsplaat, Mass: 3.85674 kg; Gipsplaat, Component Volume (Net): 0.00482092 m3; Gipsplaat, Component Volume (Gross): 0.00482092 m3

# IfcBuildingElementProxy: Distinct Panel 79 x 67 x 20, __Panel-D
In: 01 eerste verdieping
Material: Gipsplaat
Component Quantities - Gipsplaat, Mass: 0.0329996 kg; Gipsplaat, Component Volume (Net): 0.0000412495 m3; Gipsplaat, Component Volume (Gross): 0.0000412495 m3

# IfcBuildingElementProxy: Distinct Panel 93 x 1200 x 20, __Panel-D
In: 01 eerste verdieping
Material: Gipsplaat
Component Quantities - Gipsplaat, Mass: 1.67661 kg; Gipsplaat, Component Volume (Net): 0.00209577 m3; Gipsplaat, Component Volume (Gross): 0.00209577 m3

# IfcBuildingElementProxy: Distinct Panel 93 x 947 x 20, __Panel-D
In: 01 eerste verdieping
Material: Gipsplaat
Component Quantities - Gipsplaat, Mass: 1.32212 kg; Gipsplaat, Component Volume (Net): 0.00165265 m3; Gipsplaat, Component Volume (Gross): 0.00165265 m3

# IfcBuildingElementProxy: Distinct Panel 93 x 950 x 20, __Panel-D
In: 01 eerste verdieping
Material: Gipsplaat
Component Quantities - Gipsplaat, Mass: 1.32562 kg; Gipsplaat, Component Volume (Net): 0.00165703 m3; Gipsplaat, Component Volume (Gross): 0.00165703 m3

# IfcBuildingElementProxy: Distinct Panel 95 x 248 x 20, __Panel-D
In: 01 eerste verdieping
Material: Gipsplaat
Component Quantities - Gipsplaat, Mass: 0.350761 kg; Gipsplaat, Component Volume (Net): 0.000438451 m3; Gipsplaat, Component Volume (Gross): 0.000438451 m3

# IfcBuildingElementProxy: Distinct Panel 95 x 600 x 20 (4)
In: 01 eerste verdieping
Material: Gipsplaat
Name | Gipsplaat, Mass (kg) | Gipsplaat, Component Volume (Net) (m3) = Gipsplaat, Component Volume (Gross) (m3)
2 x __Panel-D | 0.85893 | 0.00107366
__Panel-D | 2.24343 | 0.00280429
__Panel-D

# IfcBuildingElementProxy: Main Panel 11 x 600 x 20 (8)
In: 01 eerste verdieping
Material: Gipsplaat
Name
__600x677 Rockfon Krios | Component Quantities - Gipsplaat, Mass: 0.0567967 kg; Gipsplaat, Component Volume (Net): 0.0000709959 m3; Gipsplaat, Component Volume (Gross): 0.0000709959 m3
__600x720 Rockfon Krios | Component Quantities - Gipsplaat, Mass: 0.0567967 kg; Gipsplaat, Component Volume (Net): 0.0000709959 m3; Gipsplaat, Component Volume (Gross): 0.0000709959 m3
__600x750 Rockfon Krios
__600x752 Rockfon Krios
__600x753 Rockfon Krios | Component Quantities - Gipsplaat, Mass: 0.0567967 kg; Gipsplaat, Component Volume (Net): 0.0000709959 m3; Gipsplaat, Component Volume (Gross): 0.0000709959 m3
__600x754 Rockfon Krios
__600x755 Rockfon Krios
__600x758 Rockfon Krios

# IfcBuildingElementProxy: Main Panel 148 x 18 x 20, __600x932 Rockfon Krios
In: 00 begane grond
Material: Gipsplaat
Component Quantities - Gipsplaat, Mass: 5.02968 kg; Gipsplaat, Component Volume (Net): 0.0062871 m3; Gipsplaat, Component Volume (Gross): 0.0062871 m3

# IfcBuildingElementProxy: Main Panel 287 x 437 x 20, __Panel-D
In: 00 begane grond
Material: Gipsplaat
Component Quantities - Gipsplaat, Mass: 1.98036 kg; Gipsplaat, Component Volume (Net): 0.00247545 m3; Gipsplaat, Component Volume (Gross): 0.00247545 m3

# IfcBuildingElementProxy: Main Panel 292 x 503 x 20, __Panel-D
In: 00 begane grond
Material: Gipsplaat
Component Quantities - Gipsplaat, Mass: 2.28887 kg; Gipsplaat, Component Volume (Net): 0.00286109 m3; Gipsplaat, Component Volume (Gross): 0.00286109 m3

# IfcBuildingElementProxy: Main Panel 292 x 600 x 20 (13)
In: 00 begane grond
Material: Gipsplaat
Name
3 x __Panel-D | Component Quantities - Gipsplaat, Mass: 2.73694 kg; Gipsplaat, Component Volume (Net): 0.00342117 m3; Gipsplaat, Component Volume (Gross): 0.00342117 m3
10 x __Panel-D

# IfcBuildingElementProxy: Main Panel 295 x 44 x 20, __600x761 Rockfon Krios
In: 01 eerste verdieping
Material: Gipsplaat
Component Quantities - Gipsplaat, Mass: 0.179507 kg; Gipsplaat, Component Volume (Net): 0.000224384 m3; Gipsplaat, Component Volume (Gross): 0.000224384 m3

# IfcBuildingElementProxy: Main Panel 343 x 44 x 20, __600x762 Rockfon Krios
In: 01 eerste verdieping
Material: Gipsplaat
Component Quantities - Gipsplaat, Mass: 0.209006 kg; Gipsplaat, Component Volume (Net): 0.000261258 m3; Gipsplaat, Component Volume (Gross): 0.000261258 m3

# IfcBuildingElementProxy: Main Panel 350 x 437 x 20, __Panel-D
In: 00 begane grond
Material: Gipsplaat
Component Quantities - Gipsplaat, Mass: 2.38244 kg; Gipsplaat, Component Volume (Net): 0.00297805 m3; Gipsplaat, Component Volume (Gross): 0.00297805 m3

# IfcBuildingElementProxy: Main Panel 350 x 503 x 20, __Panel-D
In: 00 begane grond
Material: Gipsplaat
Component Quantities - Gipsplaat, Mass: 2.74677 kg; Gipsplaat, Component Volume (Net): 0.00343346 m3; Gipsplaat, Component Volume (Gross): 0.00343346 m3

# IfcBuildingElementProxy: Main Panel 350 x 600 x 20 (13)
In: 00 begane grond
Material: Gipsplaat
Name
2 x __Panel-D | Component Quantities - Gipsplaat, Mass: 3.28446 kg; Gipsplaat, Component Volume (Net): 0.00410558 m3; Gipsplaat, Component Volume (Gross): 0.00410558 m3
11 x __Panel-D

# IfcBuildingElementProxy: Main Panel 400 x 495 x 20, __600x086 Rockfon Krios
In: 00 begane grond
Material: Gipsplaat
Component Quantities - Gipsplaat, Mass: 3.72813 kg; Gipsplaat, Component Volume (Net): 0.00466017 m3; Gipsplaat, Component Volume (Gross): 0.00466017 m3

# IfcBuildingElementProxy: Main Panel 400 x 538 x 20, __600x943 Rockfon Krios
In: 00 begane grond
Material: Gipsplaat
Component Quantities - Gipsplaat, Mass: 3.3371 kg; Gipsplaat, Component Volume (Net): 0.00417137 m3; Gipsplaat, Component Volume (Gross): 0.00417137 m3

# IfcBuildingElementProxy: Main Panel 400 x 600 x 20 (10)
In: 00 begane grond
Material: Gipsplaat
Name
__600x956 Rockfon Krios | Component Quantities - Gipsplaat, Mass: 3.72813 kg; Gipsplaat, Component Volume (Net): 0.00466016 m3; Gipsplaat, Component Volume (Gross): 0.00466016 m3
__600x969 Rockfon Krios
__600x982 Rockfon Krios
__600x995 Rockfon Krios
__600x008 Rockfon Krios
__600x021 Rockfon Krios
__600x034 Rockfon Krios
__600x047 Rockfon Krios
__600x060 Rockfon Krios
__600x073 Rockfon Krios

# IfcBuildingElementProxy: Main Panel 401 x 155 x 20, __600x074 Rockfon Krios
In: 00 begane grond
Material: Gipsplaat
Component Quantities - Gipsplaat, Mass: 0.941698 kg; Gipsplaat, Component Volume (Net): 0.00117712 m3; Gipsplaat, Component Volume (Gross): 0.00117712 m3

# IfcBuildingElementProxy: Main Panel 401 x 538 x 20, __600x931 Rockfon Krios
In: 00 begane grond
Material: Gipsplaat
Component Quantities - Gipsplaat, Mass: 3.34564 kg; Gipsplaat, Component Volume (Net): 0.00418205 m3; Gipsplaat, Component Volume (Gross): 0.00418205 m3

# IfcBuildingElementProxy: Main Panel 401 x 600 x 20 (10)
In: 00 begane grond
Material: Gipsplaat
Name
__600x944 Rockfon Krios | Component Quantities - Gipsplaat, Mass: 3.73767 kg; Gipsplaat, Component Volume (Net): 0.00467209 m3; Gipsplaat, Component Volume (Gross): 0.00467209 m3
__600x957 Rockfon Krios
__600x970 Rockfon Krios
__600x983 Rockfon Krios
__600x996 Rockfon Krios
__600x009 Rockfon Krios
__600x022 Rockfon Krios
__600x035 Rockfon Krios
__600x048 Rockfon Krios
__600x061 Rockfon Krios

# IfcBuildingElementProxy: Main Panel 49 x 538 x 20, __600x762 Rockfon Krios
In: 00 begane grond
Material: Gipsplaat
Component Quantities - Gipsplaat, Mass: 0.369326 kg; Gipsplaat, Component Volume (Net): 0.000461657 m3; Gipsplaat, Component Volume (Gross): 0.000461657 m3

# IfcBuildingElementProxy: Main Panel 49 x 600 x 20 (10)
In: 00 begane grond
Material: Gipsplaat
Name
__600x775 Rockfon Krios | Component Quantities - Gipsplaat, Mass: 0.412603 kg; Gipsplaat, Component Volume (Net): 0.000515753 m3; Gipsplaat, Component Volume (Gross): 0.000515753 m3
__600x788 Rockfon Krios
__600x801 Rockfon Krios
__600x814 Rockfon Krios
__600x827 Rockfon Krios
__600x840 Rockfon Krios
__600x853 Rockfon Krios
__600x866 Rockfon Krios
__600x879 Rockfon Krios
__600x892 Rockfon Krios

# IfcBuildingElementProxy: Main Panel 49 x 63 x 20, __600x905 Rockfon Krios
In: 00 begane grond
Material: Gipsplaat
Component Quantities - Gipsplaat, Mass: 0.0399361 kg; Gipsplaat, Component Volume (Net): 0.0000499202 m3; Gipsplaat, Component Volume (Gross): 0.0000499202 m3

# IfcBuildingElementProxy: Main Panel 5 x 400 x 20, __600x767 Rockfon Krios
In: 01 eerste verdieping
Material: Gipsplaat
Component Quantities - Gipsplaat, Mass: 0.00268115 kg; Gipsplaat, Component Volume (Net): 0.00000335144 m3; Gipsplaat, Component Volume (Gross): 0.00000335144 m3

# IfcBuildingElementProxy: Main Panel 5 x 600 x 20 (7)
In: 01 eerste verdieping
Material: Gipsplaat
Name
__600x763 Rockfon Krios | Component Quantities - Gipsplaat, Mass: 0.00403865 kg; Gipsplaat, Component Volume (Net): 0.00000504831 m3; Gipsplaat, Component Volume (Gross): 0.00000504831 m3
__600x762 Rockfon Krios
__600x760 Rockfon Krios
__600x766 Rockfon Krios
__600x764 Rockfon Krios
__600x765 Rockfon Krios
__600x761 Rockfon Krios

# IfcBuildingElementProxy: Main Panel 600 x 155 x 20 (7)
In: 00 begane grond
Material: Gipsplaat
Name
__600x075 Rockfon Krios | Component Quantities - Gipsplaat, Mass: 1.41571 kg; Gipsplaat, Component Volume (Net): 0.00176963 m3; Gipsplaat, Component Volume (Gross): 0.00176963 m3
__600x076 Rockfon Krios
__600x077 Rockfon Krios
__600x078 Rockfon Krios | Component Quantities - Gipsplaat, Mass: 1.41571 kg; Gipsplaat, Component Volume (Net): 0.00176963 m3; Gipsplaat, Component Volume (Gross): 0.00176963 m3
__600x079 Rockfon Krios
__600x080 Rockfon Krios
__600x081 Rockfon Krios

# IfcBuildingElementProxy: Main Panel 600 x 437 x 20 (10)
In: 00 begane grond
Material: Gipsplaat
Name
3 x __Panel-D | Component Quantities - Gipsplaat, Mass: 4.10876 kg; Gipsplaat, Component Volume (Net): 0.00513595 m3; Gipsplaat, Component Volume (Gross): 0.00513595 m3
7 x __Panel-D

# IfcBuildingElementProxy: Main Panel 600 x 44 x 20 (10)
In: 01 eerste verdieping
Material: Gipsplaat
Name
__600x764 Rockfon Krios | Component Quantities - Gipsplaat, Mass: 0.368392 kg; Gipsplaat, Component Volume (Net): 0.000460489 m3; Gipsplaat, Component Volume (Gross): 0.000460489 m3
__600x756 Rockfon Krios
__600x766 Rockfon Krios
__600x765 Rockfon Krios
__600x763 Rockfon Krios
__600x760 Rockfon Krios
__600x767 Rockfon Krios
__600x757 Rockfon Krios
__600x759 Rockfon Krios
__600x758 Rockfon Krios

# IfcBuildingElementProxy: Main Panel 600 x 503 x 20 (10)
In: 00 begane grond
Material: Gipsplaat
Name
2 x __Panel-D | Component Quantities - Gipsplaat, Mass: 4.73708 kg; Gipsplaat, Component Volume (Net): 0.00592135 m3; Gipsplaat, Component Volume (Gross): 0.00592135 m3
8 x __Panel-D

# IfcBuildingElementProxy: Main Panel 600 x 538 x 20 (10)
In: 00 begane grond
Material: Gipsplaat
Name
__600x933 Rockfon Krios | Component Quantities - Gipsplaat, Mass: 5.02968 kg; Gipsplaat, Component Volume (Net): 0.0062871 m3; Gipsplaat, Component Volume (Gross): 0.0062871 m3
__600x934 Rockfon Krios
__600x935 Rockfon Krios
__600x936 Rockfon Krios
__600x937 Rockfon Krios
__600x938 Rockfon Krios
__600x939 Rockfon Krios
__600x940 Rockfon Krios
__600x941 Rockfon Krios
__600x942 Rockfon Krios

# IfcBuildingElementProxy: Main Panel 600 x 600 x 20 (1656)
Material: Gipsplaat
Name | In
__600x600 Rockfon Krios | 00 begane grond | Component Quantities - Gipsplaat, Mass: 5.61905 kg; Gipsplaat, Component Volume (Net): 0.00702381 m3; Gipsplaat, Component Volume (Gross): 0.00702381 m3
6 x __600x601 Rockfon Krios | 00 begane grond
__600x602 Rockfon Krios | 00 begane grond | Component Quantities - Gipsplaat, Mass: 5.61905 kg; Gipsplaat, Component Volume (Net): 0.00702381 m3; Gipsplaat, Component Volume (Gross): 0.00702381 m3
6 x __600x603 Rockfon Krios | 00 begane grond
6 x __600x604 Rockfon Krios | 00 begane grond
6 x __600x605 Rockfon Krios | 00 begane grond
6 x __600x607 Rockfon Krios | 00 begane grond
6 x __600x610 Rockfon Krios | 00 begane grond
6 x __600x611 Rockfon Krios | 00 begane grond
6 x __600x615 Rockfon Krios | 00 begane grond
6 x __600x616 Rockfon Krios | 00 begane grond
3 x __600x618 Rockfon Krios | 00 begane grond
6 x __600x619 Rockfon Krios | 00 begane grond
2 x __600x621 Rockfon Krios | 00 begane grond
2 x __600x623 Rockfon Krios | 00 begane grond
4 x __600x625 Rockfon Krios | 00 begane grond
5 x __600x626 Rockfon Krios | 00 begane grond
5 x __600x630 Rockfon Krios | 00 begane grond
6 x __600x634 Rockfon Krios | 00 begane grond
2 x __600x641 Rockfon Krios | 00 begane grond
__600x642 Rockfon Krios | 00 begane grond | Component Quantities - Gipsplaat, Mass: 5.61905 kg; Gipsplaat, Component Volume (Net): 0.00702381 m3; Gipsplaat, Component Volume (Gross): 0.00702381 m3
6 x __600x643 Rockfon Krios | 00 begane grond
6 x __600x644 Rockfon Krios | 00 begane grond
2 x __600x645 Rockfon Krios | 00 begane grond
5 x __600x647 Rockfon Krios | 00 begane grond
2 x __600x649 Rockfon Krios | 00 begane grond
6 x __600x650 Rockfon Krios | 00 begane grond
5 x __600x651 Rockfon Krios | 00 begane grond
2 x __600x653 Rockfon Krios | 00 begane grond
6 x __600x654 Rockfon Krios | 00 begane grond
3 x __600x655 Rockfon Krios | 00 begane grond
2 x __600x657 Rockfon Krios | 00 begane grond
5 x __600x658 Rockfon Krios | 00 begane grond
2 x __600x661 Rockfon Krios | 00 begane grond
3 x __600x662 Rockfon Krios | 00 begane grond
6 x __600x663 Rockfon Krios | 00 begane grond
5 x __600x664 Rockfon Krios | 00 begane grond
5 x __600x665 Rockfon Krios | 00 begane grond
2 x __600x666 Rockfon Krios | 00 begane grond
6 x __600x668 Rockfon Krios | 00 begane grond
5 x __600x669 Rockfon Krios | 00 begane grond
3 x __600x670 Rockfon Krios | 00 begane grond
3 x __600x671 Rockfon Krios | 00 begane grond
2 x __600x672 Rockfon Krios | 00 begane grond
6 x __600x673 Rockfon Krios | 00 begane grond
6 x __600x674 Rockfon Krios | 00 begane grond
3 x __600x675 Rockfon Krios | 00 begane grond
6 x __600x676 Rockfon Krios | 00 begane grond
6 x __600x677 Rockfon Krios | 00 begane grond
5 x __600x678 Rockfon Krios | 00 begane grond
6 x __600x679 Rockfon Krios | 00 begane grond
5 x __600x680 Rockfon Krios | 00 begane grond
5 x __600x681 Rockfon Krios | 00 begane grond
6 x __600x682 Rockfon Krios | 00 begane grond
5 x __600x683 Rockfon Krios | 00 begane grond
5 x __600x684 Rockfon Krios | 00 begane grond
5 x __600x685 Rockfon Krios | 00 begane grond
5 x __600x686 Rockfon Krios | 00 begane grond
3 x __600x687 Rockfon Krios | 00 begane grond
2 x __600x688 Rockfon Krios | 00 begane grond
5 x __600x689 Rockfon Krios | 00 begane grond
__600x690 Rockfon Krios | 00 begane grond
5 x __600x691 Rockfon Krios | 00 begane grond
5 x __600x692 Rockfon Krios | 00 begane grond
6 x __600x694 Rockfon Krios | 00 begane grond
6 x __600x695 Rockfon Krios | 00 begane grond
6 x __600x696 Rockfon Krios | 00 begane grond
6 x __600x697 Rockfon Krios | 00 begane grond
__600x698 Rockfon Krios | 00 begane grond
5 x __600x699 Rockfon Krios | 00 begane grond
6 x __600x700 Rockfon Krios | 00 begane grond
6 x __600x701 Rockfon Krios | 00 begane grond
6 x __600x702 Rockfon Krios | 00 begane grond
6 x __600x703 Rockfon Krios | 00 begane grond
5 x __600x704 Rockfon Krios | 00 begane grond
6 x __600x705 Rockfon Krios | 00 begane grond
2 x __600x707 Rockfon Krios | 00 begane grond
5 x __600x708 Rockfon Krios | 00 begane grond
5 x __600x709 Rockfon Krios | 00 begane grond
5 x __600x710 Rockfon Krios | 00 begane grond
5 x __600x711 Rockfon Krios | 00 begane grond
5 x __600x712 Rockfon Krios | 00 begane grond
5 x __600x713 Rockfon Krios | 00 begane grond
4 x __600x714 Rockfon Krios | 00 begane grond
5 x __600x715 Rockfon Krios | 00 begane grond
2 x __600x716 Rockfon Krios | 00 begane grond
2 x __600x717 Rockfon Krios | 00 begane grond
5 x __600x718 Rockfon Krios | 00 begane grond
5 x __600x720 Rockfon Krios | 00 begane grond
5 x __600x721 Rockfon Krios | 00 begane grond
4 x __600x722 Rockfon Krios | 00 begane grond
5 x __600x723 Rockfon Krios | 00 begane grond
5 x __600x724 Rockfon Krios | 00 begane grond
2 x __600x725 Rockfon Krios | 00 begane grond
5 x __600x727 Rockfon Krios | 00 begane grond
5 x __600x728 Rockfon Krios | 00 begane grond
5 x __600x729 Rockfon Krios | 00 begane grond
4 x __600x730 Rockfon Krios | 00 begane grond
5 x __600x731 Rockfon Krios | 00 begane grond
5 x __600x732 Rockfon Krios | 00 begane grond
5 x __600x733 Rockfon Krios | 00 begane grond
2 x __600x734 Rockfon Krios | 00 begane grond
5 x __600x736 Rockfon Krios | 00 begane grond
5 x __600x737 Rockfon Krios | 00 begane grond
4 x __600x739 Rockfon Krios | 00 begane grond
5 x __600x740 Rockfon Krios | 00 begane grond
5 x __600x741 Rockfon Krios | 00 begane grond
5 x __600x742 Rockfon Krios | 00 begane grond
2 x __600x743 Rockfon Krios | 00 begane grond
5 x __600x748 Rockfon Krios | 00 begane grond
5 x __600x749 Rockfon Krios | 00 begane grond
5 x __600x750 Rockfon Krios | 00 begane grond
5 x __600x751 Rockfon Krios | 00 begane grond
2 x __600x752 Rockfon Krios | 00 begane grond
4 x __600x755 Rockfon Krios | 00 begane grond
2 x __600x756 Rockfon Krios | 00 begane grond
2 x __600x757 Rockfon Krios | 00 begane grond
2 x __600x758 Rockfon Krios | 00 begane grond
__600x767 Rockfon Krios | 00 begane grond
__600x770 Rockfon Krios | 00 begane grond
__600x774 Rockfon Krios | 00 begane grond
2 x __600x775 Rockfon Krios | 00 begane grond
__600x776 Rockfon Krios | 00 begane grond
__600x779 Rockfon Krios | 00 begane grond
__600x780 Rockfon Krios | 00 begane grond
__600x781 Rockfon Krios | 00 begane grond
__600x782 Rockfon Krios | 00 begane grond
__600x783 Rockfon Krios | 00 begane grond
__600x784 Rockfon Krios | 00 begane grond
__600x785 Rockfon Krios | 00 begane grond
2 x __600x600 Rockfon Krios | 00 begane grond
2 x __600x612 Rockfon Krios | 00 begane grond
5 x __600x614 Rockfon Krios | 00 begane grond
__600x620 Rockfon Krios | 00 begane grond
2 x __600x624 Rockfon Krios | 00 begane grond
2 x __600x631 Rockfon Krios | 00 begane grond
5 x __600x632 Rockfon Krios | 00 begane grond
5 x __600x633 Rockfon Krios | 00 begane grond
2 x __600x635 Rockfon Krios | 00 begane grond
2 x __600x636 Rockfon Krios | 00 begane grond
4 x __600x637 Rockfon Krios | 00 begane grond
5 x __600x638 Rockfon Krios | 00 begane grond
5 x __600x639 Rockfon Krios | 00 begane grond
4 x __600x642 Rockfon Krios | 00 begane grond
2 x __600x646 Rockfon Krios | 00 begane grond
5 x __600x648 Rockfon Krios | 00 begane grond
2 x __600x652 Rockfon Krios | 00 begane grond
5 x __600x656 Rockfon Krios | 00 begane grond
2 x __600x659 Rockfon Krios | 00 begane grond
5 x __600x660 Rockfon Krios | 00 begane grond
4 x __600x693 Rockfon Krios | 00 begane grond
5 x __600x706 Rockfon Krios | 00 begane grond
__600x602 Rockfon Krios | 00 begane grond
__600x606 Rockfon Krios | 00 begane grond
4 x __600x622 Rockfon Krios | 00 begane grond
__600x629 Rockfon Krios | 00 begane grond
4 x __600x640 Rockfon Krios | 00 begane grond
4 x __600x667 Rockfon Krios | 00 begane grond
4 x __600x719 Rockfon Krios | 00 begane grond
4 x __600x726 Rockfon Krios | 00 begane grond
__600x735 Rockfon Krios | 00 begane grond
__600x744 Rockfon Krios | 00 begane grond
4 x __600x745 Rockfon Krios | 00 begane grond
4 x __600x747 Rockfon Krios | 00 begane grond
__600x753 Rockfon Krios | 00 begane grond
__600x759 Rockfon Krios | 00 begane grond
__600x760 Rockfon Krios | 00 begane grond
__600x761 Rockfon Krios | 00 begane grond
__600x764 Rockfon Krios | 00 begane grond
__600x765 Rockfon Krios | 00 begane grond
__600x773 Rockfon Krios | 00 begane grond
3 x __600x608 Rockfon Krios | 00 begane grond
3 x __600x609 Rockfon Krios | 00 begane grond
3 x __600x628 Rockfon Krios | 00 begane grond
3 x __600x738 Rockfon Krios | 00 begane grond
3 x __600x746 Rockfon Krios | 00 begane grond
3 x __600x754 Rockfon Krios | 00 begane grond
__600x945 Rockfon Krios | 00 begane grond | Component Quantities - Gipsplaat, Mass: 5.61905 kg; Gipsplaat, Component Volume (Net): 0.00702381 m3; Gipsplaat, Component Volume (Gross): 0.00702381 m3
__600x946 Rockfon Krios | 00 begane grond
__600x947 Rockfon Krios | 00 begane grond
__600x948 Rockfon Krios | 00 begane grond
__600x949 Rockfon Krios | 00 begane grond
__600x950 Rockfon Krios | 00 begane grond
__600x951 Rockfon Krios | 00 begane grond
__600x952 Rockfon Krios | 00 begane grond
__600x953 Rockfon Krios | 00 begane grond
__600x954 Rockfon Krios | 00 begane grond
__600x955 Rockfon Krios | 00 begane grond
__600x958 Rockfon Krios | 00 begane grond
__600x959 Rockfon Krios | 00 begane grond
__600x960 Rockfon Krios | 00 begane grond
__600x961 Rockfon Krios | 00 begane grond
__600x962 Rockfon Krios | 00 begane grond
__600x963 Rockfon Krios | 00 begane grond
__600x964 Rockfon Krios | 00 begane grond
__600x965 Rockfon Krios | 00 begane grond
__600x966 Rockfon Krios | 00 begane grond
__600x967 Rockfon Krios | 00 begane grond
__600x968 Rockfon Krios | 00 begane grond
__600x971 Rockfon Krios | 00 begane grond
__600x972 Rockfon Krios | 00 begane grond
__600x973 Rockfon Krios | 00 begane grond
__600x974 Rockfon Krios | 00 begane grond
__600x975 Rockfon Krios | 00 begane grond
__600x976 Rockfon Krios | 00 begane grond
__600x977 Rockfon Krios | 00 begane grond
__600x978 Rockfon Krios | 00 begane grond
__600x979 Rockfon Krios | 00 begane grond
__600x980 Rockfon Krios | 00 begane grond
__600x981 Rockfon Krios | 00 begane grond
__600x984 Rockfon Krios | 00 begane grond
__600x985 Rockfon Krios | 00 begane grond
__600x986 Rockfon Krios | 00 begane grond
__600x987 Rockfon Krios | 00 begane grond
__600x988 Rockfon Krios | 00 begane grond
__600x989 Rockfon Krios | 00 begane grond
__600x990 Rockfon Krios | 00 begane grond
__600x991 Rockfon Krios | 00 begane grond
__600x992 Rockfon Krios | 00 begane grond
__600x993 Rockfon Krios | 00 begane grond
__600x994 Rockfon Krios | 00 begane grond
__600x997 Rockfon Krios | 00 begane grond
__600x998 Rockfon Krios | 00 begane grond
__600x999 Rockfon Krios | 00 begane grond
__600x000 Rockfon Krios | 00 begane grond
__600x001 Rockfon Krios | 00 begane grond
__600x002 Rockfon Krios | 00 begane grond
__600x003 Rockfon Krios | 00 begane grond
__600x004 Rockfon Krios | 00 begane grond
__600x005 Rockfon Krios | 00 begane grond
__600x006 Rockfon Krios | 00 begane grond
__600x007 Rockfon Krios | 00 begane grond
__600x010 Rockfon Krios | 00 begane grond
__600x011 Rockfon Krios | 00 begane grond
__600x012 Rockfon Krios | 00 begane grond
__600x013 Rockfon Krios | 00 begane grond
__600x014 Rockfon Krios | 00 begane grond
__600x015 Rockfon Krios | 00 begane grond
__600x016 Rockfon Krios | 00 begane grond
__600x017 Rockfon Krios | 00 begane grond
__600x018 Rockfon Krios | 00 begane grond
__600x019 Rockfon Krios | 00 begane grond
__600x020 Rockfon Krios | 00 begane grond
__600x023 Rockfon Krios | 00 begane grond
__600x024 Rockfon Krios | 00 begane grond
__600x025 Rockfon Krios | 00 begane grond
__600x026 Rockfon Krios | 00 begane grond
__600x027 Rockfon Krios | 00 begane grond
__600x028 Rockfon Krios | 00 begane grond
__600x029 Rockfon Krios | 00 begane grond
__600x030 Rockfon Krios | 00 begane grond
__600x031 Rockfon Krios | 00 begane grond
__600x032 Rockfon Krios | 00 begane grond
__600x033 Rockfon Krios | 00 begane grond
__600x036 Rockfon Krios | 00 begane grond
__600x037 Rockfon Krios | 00 begane grond
__600x038 Rockfon Krios | 00 begane grond
__600x039 Rockfon Krios | 00 begane grond
__600x040 Rockfon Krios | 00 begane grond
__600x041 Rockfon Krios | 00 begane grond
__600x042 Rockfon Krios | 00 begane grond
__600x043 Rockfon Krios | 00 begane grond
__600x044 Rockfon Krios | 00 begane grond
__600x045 Rockfon Krios | 00 begane grond
__600x046 Rockfon Krios | 00 begane grond
__600x049 Rockfon Krios | 00 begane grond
__600x050 Rockfon Krios | 00 begane grond
__600x051 Rockfon Krios | 00 begane grond
__600x052 Rockfon Krios | 00 begane grond
__600x053 Rockfon Krios | 00 begane grond
__600x054 Rockfon Krios | 00 begane grond
__600x055 Rockfon Krios | 00 begane grond
__600x056 Rockfon Krios | 00 begane grond
__600x057 Rockfon Krios | 00 begane grond
__600x058 Rockfon Krios | 00 begane grond
__600x059 Rockfon Krios | 00 begane grond
__600x062 Rockfon Krios | 00 begane grond
__600x063 Rockfon Krios | 00 begane grond
__600x064 Rockfon Krios | 00 begane grond
__600x065 Rockfon Krios | 00 begane grond
__600x066 Rockfon Krios | 00 begane grond
__600x067 Rockfon Krios | 00 begane grond
__600x068 Rockfon Krios | 00 begane grond
__600x069 Rockfon Krios | 00 begane grond
__600x070 Rockfon Krios | 00 begane grond
__600x071 Rockfon Krios | 00 begane grond
__600x072 Rockfon Krios | 00 begane grond
__600x082 Rockfon Krios | 00 begane grond | Component Quantities - Gipsplaat, Mass: 5.61905 kg; Gipsplaat, Component Volume (Net): 0.00702381 m3; Gipsplaat, Component Volume (Gross): 0.00702381 m3
__600x083 Rockfon Krios | 00 begane grond
__600x084 Rockfon Krios | 00 begane grond
__600x085 Rockfon Krios | 00 begane grond
__600x601 Rockfon Krios | 01 eerste verdieping | Component Quantities - Gipsplaat, Mass: 5.61905 kg; Gipsplaat, Component Volume (Net): 0.00702381 m3; Gipsplaat, Component Volume (Gross): 0.00702381 m3
__600x602 Rockfon Krios | 01 eerste verdieping | Component Quantities - Gipsplaat, Mass: 5.61905 kg; Gipsplaat, Component Volume (Net): 0.00702381 m3; Gipsplaat, Component Volume (Gross): 0.00702381 m3
6 x __600x603 Rockfon Krios | 01 eerste verdieping
6 x __600x604 Rockfon Krios | 01 eerste verdieping
7 x __600x605 Rockfon Krios | 01 eerste verdieping
7 x __600x607 Rockfon Krios | 01 eerste verdieping
8 x __600x609 Rockfon Krios | 01 eerste verdieping
8 x __600x610 Rockfon Krios | 01 eerste verdieping
8 x __600x611 Rockfon Krios | 01 eerste verdieping
3 x __600x613 Rockfon Krios | 01 eerste verdieping
6 x __600x614 Rockfon Krios | 01 eerste verdieping
8 x __600x615 Rockfon Krios | 01 eerste verdieping
8 x __600x616 Rockfon Krios | 01 eerste verdieping
8 x __600x619 Rockfon Krios | 01 eerste verdieping
6 x __600x620 Rockfon Krios | 01 eerste verdieping
7 x __600x621 Rockfon Krios | 01 eerste verdieping
6 x __600x626 Rockfon Krios | 01 eerste verdieping
6 x __600x627 Rockfon Krios | 01 eerste verdieping
8 x __600x628 Rockfon Krios | 01 eerste verdieping
5 x __600x629 Rockfon Krios | 01 eerste verdieping
5 x __600x630 Rockfon Krios | 01 eerste verdieping
6 x __600x631 Rockfon Krios | 01 eerste verdieping
6 x __600x632 Rockfon Krios | 01 eerste verdieping
5 x __600x633 Rockfon Krios | 01 eerste verdieping
__600x634 Rockfon Krios | 01 eerste verdieping | Component Quantities - Gipsplaat, Mass: 5.61905 kg; Gipsplaat, Component Volume (Net): 0.00702381 m3; Gipsplaat, Component Volume (Gross): 0.00702381 m3
5 x __600x635 Rockfon Krios | 01 eerste verdieping
5 x __600x636 Rockfon Krios | 01 eerste verdieping
8 x __600x637 Rockfon Krios | 01 eerste verdieping
7 x __600x638 Rockfon Krios | 01 eerste verdieping
7 x __600x639 Rockfon Krios | 01 eerste verdieping
8 x __600x640 Rockfon Krios | 01 eerste verdieping
4 x __600x641 Rockfon Krios | 01 eerste verdieping
6 x __600x642 Rockfon Krios | 01 eerste verdieping
4 x __600x646 Rockfon Krios | 01 eerste verdieping
8 x __600x647 Rockfon Krios | 01 eerste verdieping
7 x __600x648 Rockfon Krios | 01 eerste verdieping
5 x __600x649 Rockfon Krios | 01 eerste verdieping
6 x __600x650 Rockfon Krios | 01 eerste verdieping
8 x __600x651 Rockfon Krios | 01 eerste verdieping
6 x __600x652 Rockfon Krios | 01 eerste verdieping
5 x __600x653 Rockfon Krios | 01 eerste verdieping
7 x __600x654 Rockfon Krios | 01 eerste verdieping
6 x __600x656 Rockfon Krios | 01 eerste verdieping
5 x __600x657 Rockfon Krios | 01 eerste verdieping
8 x __600x658 Rockfon Krios | 01 eerste verdieping
8 x __600x660 Rockfon Krios | 01 eerste verdieping
5 x __600x661 Rockfon Krios | 01 eerste verdieping
6 x __600x662 Rockfon Krios | 01 eerste verdieping
7 x __600x663 Rockfon Krios | 01 eerste verdieping
6 x __600x666 Rockfon Krios | 01 eerste verdieping
6 x __600x669 Rockfon Krios | 01 eerste verdieping
4 x __600x671 Rockfon Krios | 01 eerste verdieping
5 x __600x677 Rockfon Krios | 01 eerste verdieping
5 x __600x678 Rockfon Krios | 01 eerste verdieping
8 x __600x684 Rockfon Krios | 01 eerste verdieping
7 x __600x685 Rockfon Krios | 01 eerste verdieping
6 x __600x687 Rockfon Krios | 01 eerste verdieping
7 x __600x688 Rockfon Krios | 01 eerste verdieping
5 x __600x690 Rockfon Krios | 01 eerste verdieping
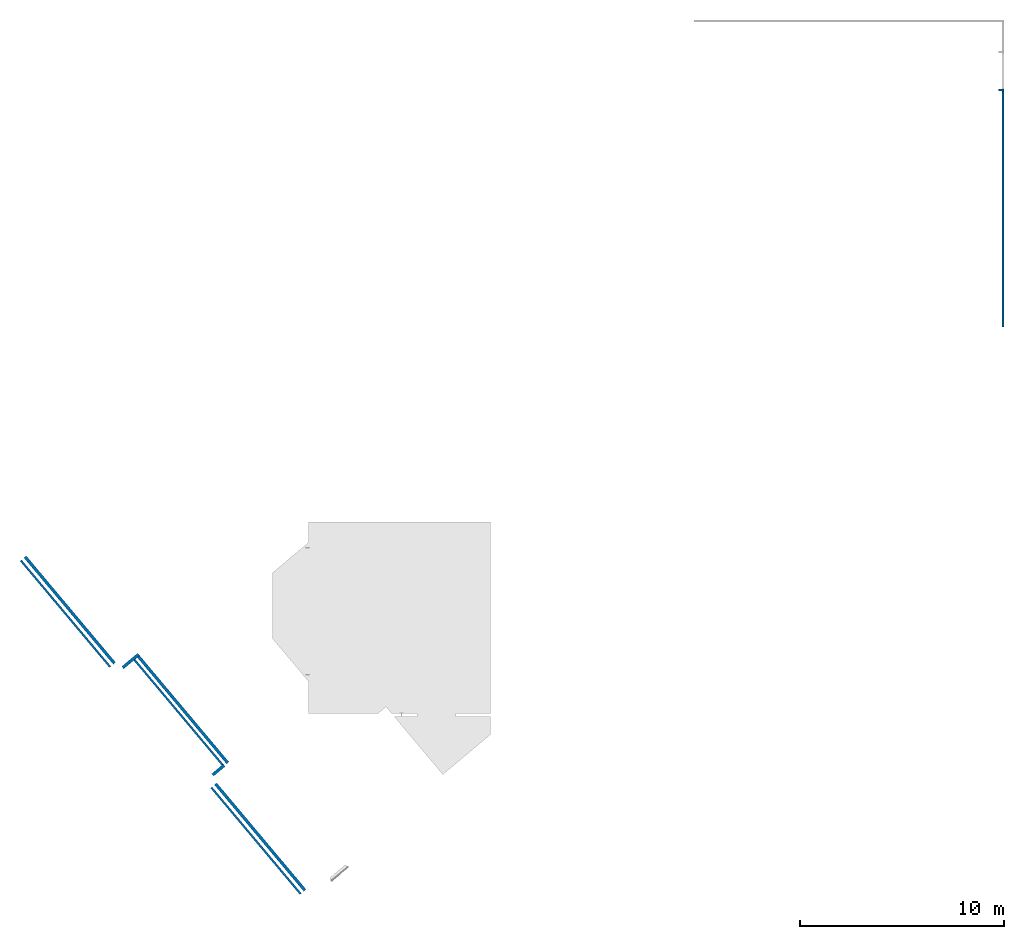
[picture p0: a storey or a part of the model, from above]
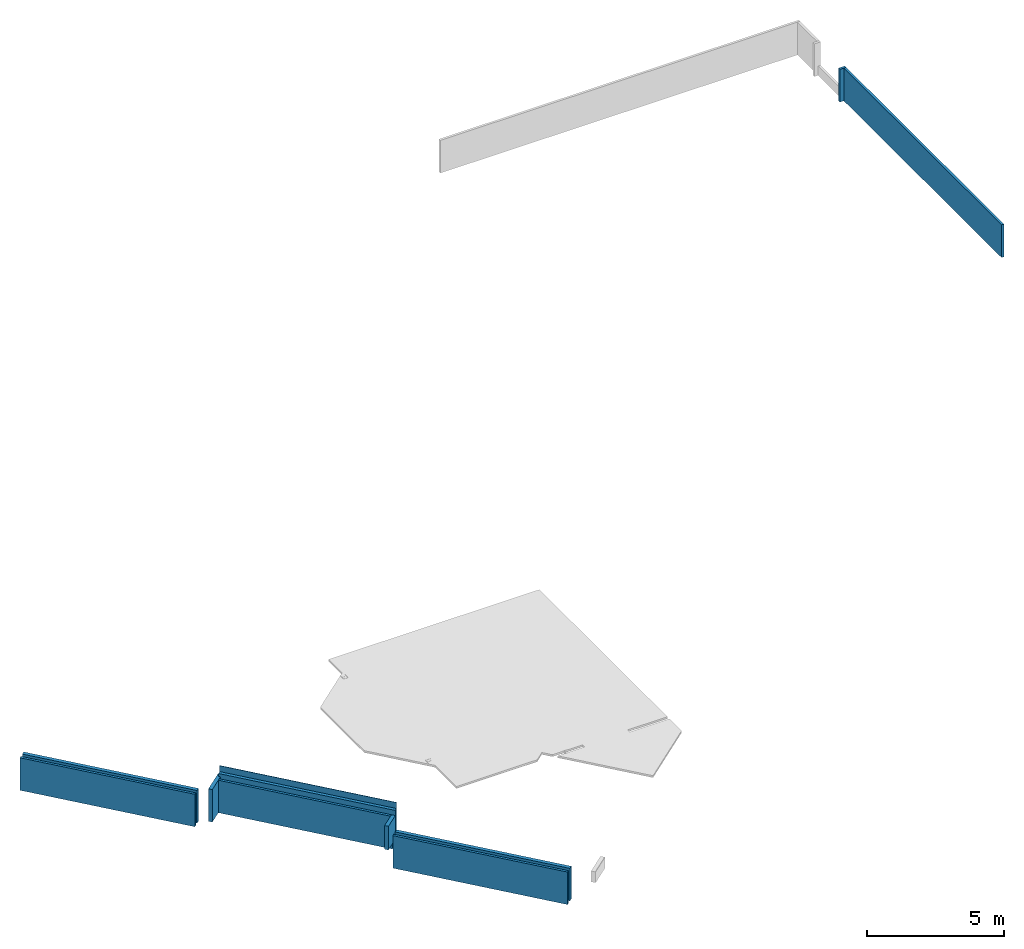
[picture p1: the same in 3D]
Properties of the parts of a building model (IFC2X3), part 8 of 11

# IfcBuildingElementProxy: Main Panel 600 x 600 x 20 (1656)
Name | In
6 x __600x693 Rockfon Krios | 01 eerste verdieping
6 x __600x695 Rockfon Krios | 01 eerste verdieping
5 x __600x697 Rockfon Krios | 01 eerste verdieping
5 x __600x698 Rockfon Krios | 01 eerste verdieping
8 x __600x700 Rockfon Krios | 01 eerste verdieping
8 x __600x702 Rockfon Krios | 01 eerste verdieping
8 x __600x703 Rockfon Krios | 01 eerste verdieping
7 x __600x704 Rockfon Krios | 01 eerste verdieping
8 x __600x706 Rockfon Krios | 01 eerste verdieping
6 x __600x708 Rockfon Krios | 01 eerste verdieping
7 x __600x709 Rockfon Krios | 01 eerste verdieping
7 x __600x710 Rockfon Krios | 01 eerste verdieping
7 x __600x711 Rockfon Krios | 01 eerste verdieping
7 x __600x712 Rockfon Krios | 01 eerste verdieping
6 x __600x713 Rockfon Krios | 01 eerste verdieping
5 x __600x714 Rockfon Krios | 01 eerste verdieping
7 x __600x715 Rockfon Krios | 01 eerste verdieping
6 x __600x716 Rockfon Krios | 01 eerste verdieping
7 x __600x717 Rockfon Krios | 01 eerste verdieping
8 x __600x718 Rockfon Krios | 01 eerste verdieping
5 x __600x720 Rockfon Krios | 01 eerste verdieping
7 x __600x721 Rockfon Krios | 01 eerste verdieping
8 x __600x723 Rockfon Krios | 01 eerste verdieping
7 x __600x724 Rockfon Krios | 01 eerste verdieping
6 x __600x725 Rockfon Krios | 01 eerste verdieping
6 x __600x726 Rockfon Krios | 01 eerste verdieping
7 x __600x727 Rockfon Krios | 01 eerste verdieping
7 x __600x728 Rockfon Krios | 01 eerste verdieping
7 x __600x729 Rockfon Krios | 01 eerste verdieping
8 x __600x730 Rockfon Krios | 01 eerste verdieping
7 x __600x731 Rockfon Krios | 01 eerste verdieping
7 x __600x732 Rockfon Krios | 01 eerste verdieping
5 x __600x733 Rockfon Krios | 01 eerste verdieping
3 x __600x734 Rockfon Krios | 01 eerste verdieping
6 x __600x736 Rockfon Krios | 01 eerste verdieping
7 x __600x737 Rockfon Krios | 01 eerste verdieping
7 x __600x738 Rockfon Krios | 01 eerste verdieping
8 x __600x739 Rockfon Krios | 01 eerste verdieping
7 x __600x741 Rockfon Krios | 01 eerste verdieping
7 x __600x742 Rockfon Krios | 01 eerste verdieping
6 x __600x743 Rockfon Krios | 01 eerste verdieping
6 x __600x744 Rockfon Krios | 01 eerste verdieping
6 x __600x745 Rockfon Krios | 01 eerste verdieping
7 x __600x746 Rockfon Krios | 01 eerste verdieping
5 x __600x747 Rockfon Krios | 01 eerste verdieping
7 x __600x749 Rockfon Krios | 01 eerste verdieping
6 x __600x750 Rockfon Krios | 01 eerste verdieping
7 x __600x751 Rockfon Krios | 01 eerste verdieping
6 x __600x753 Rockfon Krios | 01 eerste verdieping
4 x __600x754 Rockfon Krios | 01 eerste verdieping
6 x __600x755 Rockfon Krios | 01 eerste verdieping
4 x __600x608 Rockfon Krios | 01 eerste verdieping
3 x __600x623 Rockfon Krios | 01 eerste verdieping
5 x __600x625 Rockfon Krios | 01 eerste verdieping
6 x __600x643 Rockfon Krios | 01 eerste verdieping
6 x __600x644 Rockfon Krios | 01 eerste verdieping
3 x __600x659 Rockfon Krios | 01 eerste verdieping
3 x __600x665 Rockfon Krios | 01 eerste verdieping
4 x __600x667 Rockfon Krios | 01 eerste verdieping
4 x __600x668 Rockfon Krios | 01 eerste verdieping
2 x __600x670 Rockfon Krios | 01 eerste verdieping
2 x __600x672 Rockfon Krios | 01 eerste verdieping
6 x __600x673 Rockfon Krios | 01 eerste verdieping
3 x __600x675 Rockfon Krios | 01 eerste verdieping
4 x __600x676 Rockfon Krios | 01 eerste verdieping
6 x __600x679 Rockfon Krios | 01 eerste verdieping
6 x __600x680 Rockfon Krios | 01 eerste verdieping
4 x __600x681 Rockfon Krios | 01 eerste verdieping
3 x __600x682 Rockfon Krios | 01 eerste verdieping
6 x __600x683 Rockfon Krios | 01 eerste verdieping
3 x __600x686 Rockfon Krios | 01 eerste verdieping
4 x __600x689 Rockfon Krios | 01 eerste verdieping
6 x __600x691 Rockfon Krios | 01 eerste verdieping
5 x __600x692 Rockfon Krios | 01 eerste verdieping
4 x __600x696 Rockfon Krios | 01 eerste verdieping
4 x __600x699 Rockfon Krios | 01 eerste verdieping
6 x __600x701 Rockfon Krios | 01 eerste verdieping
4 x __600x707 Rockfon Krios | 01 eerste verdieping
5 x __600x719 Rockfon Krios | 01 eerste verdieping
5 x __600x722 Rockfon Krios | 01 eerste verdieping
4 x __600x735 Rockfon Krios | 01 eerste verdieping
4 x __600x740 Rockfon Krios | 01 eerste verdieping
4 x __600x748 Rockfon Krios | 01 eerste verdieping
3 x __600x752 Rockfon Krios | 01 eerste verdieping
4 x __600x601 Rockfon Krios | 01 eerste verdieping
3 x __600x606 Rockfon Krios | 01 eerste verdieping
2 x __600x618 Rockfon Krios | 01 eerste verdieping
3 x __600x624 Rockfon Krios | 01 eerste verdieping
4 x __600x655 Rockfon Krios | 01 eerste verdieping
3 x __600x694 Rockfon Krios | 01 eerste verdieping
5 x __600x705 Rockfon Krios | 01 eerste verdieping
3 x __600x612 Rockfon Krios | 01 eerste verdieping
5 x __600x634 Rockfon Krios | 01 eerste verdieping
3 x __600x645 Rockfon Krios | 01 eerste verdieping
3 x __600x664 Rockfon Krios | 01 eerste verdieping
2 x __600x622 Rockfon Krios | 01 eerste verdieping
__600x674 Rockfon Krios | 01 eerste verdieping
2 x __600x617 Rockfon Krios | 01 eerste verdieping
__600x756 Rockfon Krios | 01 eerste verdieping
2 x __600x602 Rockfon Krios | 01 eerste verdieping
__600x661 Rockfon Krios | 01 eerste verdieping | Component Quantities - Gipsplaat, Mass: 5.61905 kg; Gipsplaat, Component Volume (Net): 0.00702381 m3; Gipsplaat, Component Volume (Gross): 0.00702381 m3

# IfcBuildingElementProxy: Trapelement beton 25 KM (6)
Classification: Building Element Proxy (ARCHICAD Classification); 0.0 ALGEMEEN (NL/SfB (4 cijfers))
CPset_Phasing - Renovation Phase: Bestaand
Name | In | Component, Component Volume (Net) (m3) = Component, Component Volume (Gross) (m3)
0_Building Element Proxy_T1.2 | 00 begane grond | 0.465806
0_Building Element Proxy_T1.3 | 00 begane grond | 0.833907
0_Building Element Proxy_T1.1 | 00 begane grond | 0.89062
0_Building Element Proxy_T2.1 | 00 begane grond | 0.759023
0_Building Element Proxy_T1.4 | 01 eerste verdieping | 0.848823
0_Building Element Proxy_T2.2 | 01 eerste verdieping | 0.759023

# IfcBuildingElementProxy: U Profiel kolom 25 (2)
Classification: Building Element Proxy (ARCHICAD Classification); 0.0 ALGEMEEN (NL/SfB (4 cijfers)); Material: Metaal - Staal AFW
CPset_Phasing - Renovation Phase: Bestaand
Component Quantities - Metaal - Staal AFW, Mass: 0.789725 kg; Metaal - Staal AFW, Component Volume (Net): 0.0000993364 m3; Metaal - Staal AFW, Component Volume (Gross): 0.0000993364 m3
Name | In
0_Building Element Proxy_ladderbeugel | 01 eerste verdieping
0_Building Element Proxy_ladderbeugel | 02 dak

# IfcColumn: 41 Zetwerk SW 115 x 74 (6)
In: 00 begane grond
Type - PredefinedType: COLUMN
Classification: Kolom (ARCHICAD Classification); 28.11_K KOLOM-/LIGGERCONSTRUCTIES, KOLOM (NL/SfB (4 cijfers)); Material: Metaal - Aluminium
Pset_ColumnCommon - Slope: 90 deg; FireRating: 0; LoadBearing: yes; IsExternal: no; Reference: 41 Zetwerk SW 115 x 74
CPset_Phasing - Renovation Phase: Bestaand
BaseQuantities - CrossSectionArea: 0.000228 m2
Component Quantities - Metaal - Aluminium, Component Cross Section Area: 0.000228 m2
Name | Length (mm) | OuterSurfaceArea (m2) | TotalSurfaceArea (m2) = GrossSurfaceArea (m2) | GrossVolume (m3) = NetVolume (m3) = Metaal - Aluminium, Component Volume (Net) (m3) = Metaal - Aluminium, Component Volume (Gross) (m3) | Metaal - Aluminium, Mass (kg)
2 x 28_Kolom_omtimmering kolom | 3249.37 | 0.636876 | 0.637072 | 0.000318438 | 0.891627
28_Kolom_omtimmering kolom | 3254.37 | 0.293182 | 0.29319 | 0.0000129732 | 0.036325
28_Kolom_omtimmering kolom | 3254.37 | 0.427542 | 0.427577 | 0.0000570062 | 0.159617
28_Kolom_omtimmering kolom | 3254.38 | 0.293182 | 0.29319 | 0.0000129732 | 0.036325
28_Kolom_omtimmering kolom | 3254.38 | 0.42743 | 0.427462 | 0.0000524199 | 0.146776

# IfcColumn: 41 Zetwerk SW 2 115 x 74 (2)
In: 00 begane grond
Type - PredefinedType: COLUMN
Classification: Kolom (ARCHICAD Classification); 28.11_K KOLOM-/LIGGERCONSTRUCTIES, KOLOM (NL/SfB (4 cijfers)); Material: Metaal - Aluminium
Pset_ColumnCommon - Slope: 90 deg; FireRating: 0; LoadBearing: yes; IsExternal: no; Reference: 41 Zetwerk SW 2 115 x 74
CPset_Phasing - Renovation Phase: Bestaand
BaseQuantities - Length: 3249.37 mm; CrossSectionArea: 0.000192 m2; OuterSurfaceArea: 0.640126 m2; TotalSurfaceArea: 0.640322 m2; GrossSurfaceArea: 0.640322 m2; GrossVolume: 0.000318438 m3; NetVolume: 0.000318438 m3
Component Quantities - Metaal - Aluminium, Mass: 0.891627 kg; Metaal - Aluminium, Component Cross Section Area: 0.000192 m2; Metaal - Aluminium, Component Volume (Net): 0.000318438 m3; Metaal - Aluminium, Component Volume (Gross): 0.000318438 m3

# IfcColumn: 41 Zetwerk SW hd 77 x 94 (2)
In: 00 begane grond
Type - PredefinedType: COLUMN
Classification: Kolom (ARCHICAD Classification); 28.11_K KOLOM-/LIGGERCONSTRUCTIES, KOLOM (NL/SfB (4 cijfers)); Material: Metaal - Aluminium
Pset_ColumnCommon - Slope: 90 deg; FireRating: 0; LoadBearing: yes; IsExternal: no; Reference: 41 Zetwerk SW hd 77 x 94
CPset_Phasing - Renovation Phase: Bestaand
BaseQuantities - Length: 1471 mm; CrossSectionArea: 0.000188 m2; OuterSurfaceArea: 0.325293 m2; TotalSurfaceArea: 0.325566 m2; GrossSurfaceArea: 0.325566 m2; GrossVolume: 0.000161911 m3; NetVolume: 0.000161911 m3
Component Quantities - Metaal - Aluminium, Mass: 0.453352 kg; Metaal - Aluminium, Component Cross Section Area: 0.000188 m2; Metaal - Aluminium, Component Volume (Net): 0.000161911 m3; Metaal - Aluminium, Component Volume (Gross): 0.000161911 m3

# IfcColumn: 41 Zetwerk SW hoek 151 x 151 (8)
Type - PredefinedType: COLUMN
Classification: Kolom (ARCHICAD Classification); 28.11_K KOLOM-/LIGGERCONSTRUCTIES, KOLOM (NL/SfB (4 cijfers)); Material: Metaal - Aluminium
Pset_ColumnCommon - Slope: 90 deg; FireRating: 0; LoadBearing: yes; IsExternal: no; Reference: 41 Zetwerk SW hoek 151 x 151
CPset_Phasing - Renovation Phase: Bestaand
BaseQuantities - CrossSectionArea: 0.00034915 m2
Component Quantities - Metaal - Aluminium, Component Cross Section Area: 0.00034915 m2
Name | In | Length (mm) | OuterSurfaceArea (m2) | TotalSurfaceArea (m2) = GrossSurfaceArea (m2) | GrossVolume (m3) = NetVolume (m3) = Metaal - Aluminium, Component Volume (Net) (m3) = Metaal - Aluminium, Component Volume (Gross) (m3) | Metaal - Aluminium, Mass (kg)
28_Kolom_omtimmering kolom | 00 begane grond | 4070 | 2.85022 | 2.85092 | 0.00142104 | 3.97892
28_Kolom_omtimmering kolom | 00 begane grond | 4060.86 | 2.58238 | 2.58304 | 0.00128916 | 3.60964
28_Kolom_omtimmering kolom | 01 eerste verdieping | 1690 | 1.18351 | 1.18421 | 0.000590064 | 1.65218
28_Kolom_omtimmering kolom | 01 eerste verdieping | 1690 | 1.07468 | 1.07531 | 0.000536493 | 1.50218
3 x 28_Kolom_omtimmering kolom | 02 dak | 2544 | 1.76601 | 1.76666 | 0.000880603 | 2.46569
28_Kolom_omtimmering kolom | 02 dak | 2602 | 1.80023 | 1.80088 | 0.000897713 | 2.5136

# IfcColumn: Hout - Hardhout 114 x 114, 28_Kolom_hoekstijl kozijnen
In: 01 eerste verdieping
Type - PredefinedType: COLUMN
Classification: Kolom (ARCHICAD Classification); 28.11_K KOLOM-/LIGGERCONSTRUCTIES, KOLOM (NL/SfB (4 cijfers)); Material: Hout - Hardhout
Pset_ColumnCommon - Slope: 90 deg; FireRating: 0; LoadBearing: yes; IsExternal: no; Reference: Hout - Hardhout 114 x 114
CPset_Phasing - Renovation Phase: Bestaand
BaseQuantities - Length: 3840 mm; Width: 114 mm; Depth: 114 mm; CrossSectionArea: 0.012996 m2; OuterSurfaceArea: 1.75104 m2; TotalSurfaceArea: 1.77703 m2; GrossSurfaceArea: 1.77703 m2; GrossVolume: 0.0499046 m3; NetVolume: 0.0499046 m3
Component Quantities - Hout - Hardhout, Mass: 34.9332 kg; Hout - Hardhout, Component Thickness: 114 mm; Hout - Hardhout, Rectangular Component Height: 114 mm; Hout - Hardhout, Rectangular Component Width: 114 mm; Hout - Hardhout, Component Cross Section Area: 0.012996 m2; Hout - Hardhout, Component Volume (Net): 0.0499046 m3; Hout - Hardhout, Component Volume (Gross): 0.0499046 m3

# IfcColumn: L30/2 30 x 30 (4)
Type - PredefinedType: COLUMN
Classification: Kolom (ARCHICAD Classification); 28.11_K KOLOM-/LIGGERCONSTRUCTIES, KOLOM (NL/SfB (4 cijfers)); Material: Metaal - Staal C
Pset_ColumnCommon - Slope: 90 deg; FireRating: 0; LoadBearing: yes; IsExternal: no; Reference: L30/2 30 x 30
CPset_Phasing - Renovation Phase: Bestaand
BaseQuantities - CrossSectionArea: 0.000116 m2
Component Quantities - Metaal - Staal C, Component Cross Section Area: 0.000116 m2
Name | In | Length (mm) | OuterSurfaceArea (m2) | TotalSurfaceArea (m2) = GrossSurfaceArea (m2) | GrossVolume (m3) = NetVolume (m3) = Metaal - Staal C, Component Volume (Net) (m3) = Metaal - Staal C, Component Volume (Gross) (m3) | Metaal - Staal C, Mass (kg)
28_Kolom_omtimmering kolom | 00 begane grond | 2566.2 | 0.307943 | 0.308175 | 0.000297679 | 2.36655
28_Kolom_omtimmering kolom | 00 begane grond | 1799.59 | 0.215951 | 0.216183 | 0.000208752 | 1.65958
28_Kolom_omtimmering kolom | 01 eerste verdieping | 3970 | 0.4764 | 0.476632 | 0.00046052 | 3.66113
28_Kolom_omtimmering kolom | 01 eerste verdieping | 3395 | 0.4074 | 0.407632 | 0.00039382 | 3.13087

# IfcCovering: 21 Dakopstand 286, 21_Wandafwerking_Dakopstand
In: 00 begane grond
Type - PredefinedType: CLADDING
Classification: 21.12 SPOUWWANDEN (NL/SfB (4 cijfers)); Wandafwerking (ARCHICAD Classification)
Pset_CoveringCommon - FireRating: 0; Material: 21 Dakopstand
CPset_Phasing - Renovation Phase: Bestaand
BaseQuantities - GrossArea: 1.40369 m2; NetArea: 1.37424 m2

# IfcCovering: 21 Dakrand berging mw 416 x 814 (3)
In: 01 eerste verdieping
Type - PredefinedType: CLADDING
Classification: 21.12 SPOUWWANDEN (NL/SfB (4 cijfers)); Wandafwerking (ARCHICAD Classification)
Pset_CoveringCommon - FireRating: 0; Material: 21 Dakrand berging mw
CPset_Phasing - Renovation Phase: Bestaand
Name | GrossArea (m2) | NetArea (m2)
21_Wandafwerking_Dakrand | 1.70444 | 1.658
21_Wandafwerking_Dakrand | 5.99684 | 5.56275
21_Wandafwerking_Dakrand | 1.62964 | 1.66546

# IfcCovering: 21 Dakrand hoofd 416 x 774 (5)
In: 02 dak
Type - PredefinedType: CLADDING
Classification: 21.12 SPOUWWANDEN (NL/SfB (4 cijfers)); Wandafwerking (ARCHICAD Classification)
Pset_CoveringCommon - FireRating: 0; Material: 21 Dakrand hoofd
CPset_Phasing - Renovation Phase: Bestaand
Name | GrossArea (m2) | NetArea (m2)
21_Wandafwerking_Dakrand | 6.12284 | 5.0212
21_Wandafwerking_Dakrand | 8.91275 | 7.50203
21_Wandafwerking_Dakrand | 10.0011 | 8.1966
21_Wandafwerking_Dakrand | 8.44328 | 7.13021
21_Wandafwerking_Dakrand | 3.58086 | 3.00178

# IfcCovering: 21 Dakrand hoog 416 x 761 (5)
In: 02 dak
Type - PredefinedType: CLADDING
Classification: 21.12 SPOUWWANDEN (NL/SfB (4 cijfers)); Wandafwerking (ARCHICAD Classification)
Pset_CoveringCommon - FireRating: 0; Material: 21 Dakrand hoog
CPset_Phasing - Renovation Phase: Bestaand
Name | GrossArea (m2) | NetArea (m2)
21_Wandafwerking_Dakrand | 5.2474 | 4.42433
21_Wandafwerking_Dakrand | 9.18736 | 7.61366
21_Wandafwerking_Dakrand | 1.24772 | 1.11628
21_Wandafwerking_Dakrand | 3.99968 | 3.40803
21_Wandafwerking_Dakrand | 9.18736 | 7.54841

# IfcCovering: 21 Dakrand terras 386 x 1235 (3)
In: 01 eerste verdieping
Type - PredefinedType: CLADDING
Classification: 21.12 SPOUWWANDEN (NL/SfB (4 cijfers)); Wandafwerking (ARCHICAD Classification)
Pset_CoveringCommon - FireRating: 0; Material: 21 Dakrand terras
CPset_Phasing - Renovation Phase: Bestaand
Name | GrossArea (m2) | NetArea (m2)
21_Wandafwerking_Dakrand | 2.15461 | 1.91587
21_Wandafwerking_Dakrand | 8.53137 | 7.64145
21_Wandafwerking_Dakrand | 2.15465 | 1.90863

# IfcCovering: 21 Dakrand terras muurafdekker 440 x 80 (3)
In: 01 eerste verdieping
Type - PredefinedType: CLADDING
Classification: Wandafwerking (ARCHICAD Classification); 41.12 BEKLEDINGEN (NL/SfB (4 cijfers)); Material: Steen - beton muurafdekker
Pset_CoveringCommon - FireRating: 0; Material: 21 Dakrand terras muurafdekker
CPset_Phasing - Renovation Phase: Bestaand
Component Quantities - Steen - beton muurafdekker, Component Cross Section Area: 0.0305233 m2
Name | GrossArea (m2) = NetArea (m2) | Steen - beton muurafdekker, Mass (kg) | Steen - beton muurafdekker, Component Volume (Net) (m3) = Steen - beton muurafdekker, Component Volume (Gross) (m3)
41_Wandafwerking_Muurafdekker | 2.222 | 272.064 | 0.17004
41_Wandafwerking_Muurafdekker | 8.8192 | 1078.86 | 0.674287
41_Wandafwerking_Muurafdekker | 2.22196 | 272.059 | 0.170037

# IfcCovering: 21 MW accent rollaag 280 (8)
Classification: 41.11 AFWERKLAGEN (NL/SfB (4 cijfers)); Afwerking (ARCHICAD Classification)
Pset_CoveringCommon - FireRating: 0; Material: 21 MW accent rollaag
CPset_Phasing - Renovation Phase: Bestaand
BaseQuantities - GrossArea: 0.0525 m2; NetArea: 0.0525 m2
Name | In
4 x 41_Afwerking_Rollaag | 00 begane grond
4 x 41_Afwerking_Rollaag | 01 eerste verdieping

# IfcCovering: 41 Kantplank 175, 41_Wandafwerking_Kantplank
In: -1 fundering
Type - PredefinedType: CLADDING
Classification: Wandafwerking (ARCHICAD Classification); 41.11 AFWERKLAGEN (NL/SfB (4 cijfers))
Pset_CoveringCommon - FireRating: 0; Material: 41 Kantplank
CPset_Phasing - Renovation Phase: Bestaand
BaseQuantities - GrossArea: 0.175 m2; NetArea: 0.175 m2

# IfcCovering: 41 Latei MW 275 x 142 (19)
In: 01 eerste verdieping
Classification: 41.11 AFWERKLAGEN (NL/SfB (4 cijfers)); Afwerking (ARCHICAD Classification)
Pset_CoveringCommon - FireRating: 0; Material: 41 Latei MW
CPset_Phasing - Renovation Phase: Bestaand
Name | GrossArea (m2) | NetArea (m2)
4 x 41_Afwerking_Latei | 0.55275 | 0.55275
13 x 41_Afwerking_Latei | 0.27775 | 0.27775
41_Afwerking_Waterslag | 0.764731 | 0.764731
41_Afwerking_Waterslag | 0.27775 | 0.26765

# IfcCovering: 41 Latei MW rollaag 280 x 227 (30)
Classification: 41.11 AFWERKLAGEN (NL/SfB (4 cijfers)); Afwerking (ARCHICAD Classification)
Pset_CoveringCommon - FireRating: 0; Material: 41 Latei MW rollaag
CPset_Phasing - Renovation Phase: Bestaand
Name | In | GrossArea (m2) | NetArea (m2)
3 x 41_Afwerking_Latei + rollaag | 00 begane grond | 0.5628 | 0.533035
2 x 41_Afwerking_Latei + rollaag | 00 begane grond | 0.5628 | 0.532162
41_Afwerking_Latei + rollaag | 00 begane grond | 0.2828 | 0.267405
2 x 41_Afwerking_Latei + rollaag | 00 begane grond | 0.5628 | 0.5427
41_Afwerking_Latei + rollaag | 00 begane grond | 0.29736 | 0.28674
41_Afwerking_Latei + rollaag | 00 begane grond | 0.2828 | 0.2727
41_Afwerking_Latei + rollaag | 00 begane grond | 0.2828 | 0.267844
4 x 41_Afwerking_Latei + rollaag | 00 begane grond | 0.2828 | 0.27876
41_Afwerking_Latei + rollaag | 00 begane grond | 0.2828 | 0.271624
41_Afwerking_Latei + rollaag | 00 begane grond | 0.5628 | 0.543159
6 x 41_Afwerking_Latei + rollaag | 01 eerste verdieping | 0.2828 | 0.27876
6 x 41_Afwerking_Latei + rollaag | 01 eerste verdieping | 0.5628 | 0.55476
41_Afwerking_Latei + rollaag | 01 eerste verdieping | 0.734221 | 0.7236

# IfcCovering: 41 Latei MW rollaag vlies 280 x 224, 41_Afwerking_Latei + rollaag
In: 01 eerste verdieping
Classification: 41.11 AFWERKLAGEN (NL/SfB (4 cijfers)); Afwerking (ARCHICAD Classification)
Pset_CoveringCommon - FireRating: 0; Material: 41 Latei MW rollaag vlies
CPset_Phasing - Renovation Phase: Bestaand
BaseQuantities - GrossArea: 0.951962 m2; NetArea: 0.843166 m2

# IfcCovering: 41 Latei MW rollaag zw 280 x 227 (3)
In: 01 eerste verdieping
Classification: 41.11 AFWERKLAGEN (NL/SfB (4 cijfers)); Afwerking (ARCHICAD Classification)
Pset_CoveringCommon - FireRating: 0; Material: 41 Latei MW rollaag zw
CPset_Phasing - Renovation Phase: Bestaand
Name | GrossArea (m2) | NetArea (m2)
2 x 41_Afwerking_Latei + rollaag | 0.5628 | 0.49044
41_Afwerking_Latei + rollaag | 0.58968 | 0.513864

# IfcCovering: 41 Latei MW zw 269 x 142 (14)
In: 01 eerste verdieping
Classification: 41.11 AFWERKLAGEN (NL/SfB (4 cijfers)); Afwerking (ARCHICAD Classification)
Pset_CoveringCommon - FireRating: 0; Material: 41 Latei MW zw
CPset_Phasing - Renovation Phase: Bestaand
Name | GrossArea (m2) | NetArea (m2)
3 x 41_Afwerking_Latei | 0.27169 | 0.1515
4 x 41_Afwerking_Latei | 0.54069 | 0.3015
41_Afwerking_Latei | 0.27196 | 0.15165
5 x 41_Afwerking_MW latei | 0.54069 | 0.2814
41_Afwerking_MW latei | 0.54069 | 0.28542

# IfcCovering: 41 Rollaag 280 x 210 (36)
Classification: 41.11 AFWERKLAGEN (NL/SfB (4 cijfers)); Afwerking (ARCHICAD Classification)
Pset_CoveringCommon - FireRating: 0; Material: 41 Rollaag
CPset_Phasing - Renovation Phase: Bestaand
Name | In | GrossArea (m2) | NetArea (m2)
41_Afwerking_Rollaag | 00 begane grond | 1.1816 | 1.1816
2 x 41_Afwerking_Rollaag | 00 begane grond | 0.2436 | 0.2436
41_Afwerking_Rollaag | 00 begane grond | 0.4592 | 0.4592
41_Afwerking_Rollaag | 00 begane grond | 0.30072 | 0.30072
2 x 41_Afwerking_Rollaag | 00 begane grond | 0.2744 | 0.2744
41_Afwerking_Rollaag | 00 begane grond | 0.881688 | 0.881688
41_Afwerking_Rollaag | 00 begane grond | 0.3276 | 0.3432
41_Afwerking_Rollaag | 00 begane grond | 0.6048 | 0.5892
41_Afwerking_Rollaag | 00 begane grond | 0.2128 | 0.2128
41_Afwerking_Rollaag | 00 begane grond | 0.809233 | 0.8055
3 x 41_Afwerking_Rollaag | 00 begane grond | 0.1512 | 0.1512
41_Afwerking_Rollaag | 00 begane grond | 1.1731 | 1.14027
2 x 41_Afwerking_Rollaag | 00 begane grond | 0.336 | 0.336
41_Afwerking_Rollaag | 00 begane grond | 0.2772 | 0.2772
41_Afwerking_Rollaag | 00 begane grond | 1.85697 | 1.85697
41_Afwerking_Rollaag | 00 begane grond | 0.3668 | 0.3668
2 x 41_Afwerking_Rollaag | 01 eerste verdieping | 0.2744 | 0.2744
41_Afwerking_Rollaag | 01 eerste verdieping | 0.1512 | 0.1512
41_Afwerking_Rollaag | 01 eerste verdieping | 1.35426 | 1.35426
41_Afwerking_Rollaag | 01 eerste verdieping | 0.709889 | 0.709889
3 x 41_Afwerking_Rollaag | 01 eerste verdieping | 0.2128 | 0.2128
2 x 41_Afwerking_Rollaag | 01 eerste verdieping | 0.88452 | 0.88452
41_Afwerking_Rollaag | 01 eerste verdieping | 0.1204 | 0.1204
41_Afwerking_Rollaag | 01 eerste verdieping | 0.798 | 0.798
41_Afwerking_Rollaag | 01 eerste verdieping | 0.336 | 0.336
41_Afwerking_Rollaag | 01 eerste verdieping | 0.129337 | 0.108972
41_Afwerking_Rollaag | 01 eerste verdieping | 0.232178 | 0.252542

# IfcCovering: 41 Waterslag MW 477 x 90 (2)
In: 01 eerste verdieping
Classification: 41.11 AFWERKLAGEN (NL/SfB (4 cijfers)); Afwerking (ARCHICAD Classification)
Pset_CoveringCommon - FireRating: 0; Material: 41 Waterslag MW
CPset_Phasing - Renovation Phase: Bestaand
Name | GrossArea (m2) | NetArea (m2)
41_Afwerking_Waterslag | 0.958777 | 0.557775
41_Afwerking_Waterslag | 0.481774 | 0.280275

# IfcCovering: 41 Waterslag MW 545 x 90 (25)
In: 01 eerste verdieping
Classification: 41.11 AFWERKLAGEN (NL/SfB (4 cijfers)); Afwerking (ARCHICAD Classification)
Pset_CoveringCommon - FireRating: 0; Material: 41 Waterslag MW
CPset_Phasing - Renovation Phase: Bestaand
Name | GrossArea (m2) | NetArea (m2)
16 x 41_Afwerking_Waterslag | 0.550454 | 0.348955
7 x 41_Afwerking_Waterslag | 1.09546 | 0.694455
41_Afwerking_Waterslag | 0.550589 | 0.349041
41_Afwerking_Waterslag | 1.51557 | 0.96078

# IfcCovering: 41 dorpel 1450 280 x 88 (14)
In: 00 begane grond
Classification: 41.11 AFWERKLAGEN (NL/SfB (4 cijfers)); Afwerking (ARCHICAD Classification)
Pset_CoveringCommon - FireRating: 0; Material: 41 dorpel 1450
CPset_Phasing - Renovation Phase: Bestaand
Name | GrossArea (m2) = NetArea (m2)
6 x 41_Afwerking_Dorpel | 0.2828
4 x 41_Afwerking_Dorpel | 0.27076
4 x 41_Afwerking_Dorpel | 0.5628

# IfcCovering: 41 dorpel aan peil 280 x 75 (16)
In: 00 begane grond
Classification: 41.11 AFWERKLAGEN (NL/SfB (4 cijfers)); Afwerking (ARCHICAD Classification)
Pset_CoveringCommon - FireRating: 0; Material: 41 dorpel aan peil
CPset_Phasing - Renovation Phase: Bestaand
Name | GrossArea (m2) | NetArea (m2)
41_Afwerking_Dorpel | 0.2828 | 0.2828
4 x 41_Afwerking_Dorpel | 0.282899 | 0.282899
3 x 41_Afwerking_Waterslag | 0.2828 | 0.2828
2 x 41_Afwerking_Dorpel | 0.5628 | 0.5628
3 x 41_Afwerking_Waterslag | 0.5628 | 0.5628
2 x 41_Afwerking_Waterslag | 0.27076 | 0.27076
41_Afwerking_Waterslag | 0.951962 | 0.951961

# IfcCovering: 41 dorpel d bi 1450 280 x 108 (4)
In: 00 begane grond
Classification: 41.11 AFWERKLAGEN (NL/SfB (4 cijfers)); Afwerking (ARCHICAD Classification)
Pset_CoveringCommon - FireRating: 0; Material: 41 dorpel d bi 1450
CPset_Phasing - Renovation Phase: Bestaand
BaseQuantities - GrossArea: 0.29204 m2; NetArea: 0.29204 m2

# IfcCovering: 41 dorpel d bi 280 x 95 (5)
In: 00 begane grond
Classification: 41.11 AFWERKLAGEN (NL/SfB (4 cijfers)); Afwerking (ARCHICAD Classification)
Pset_CoveringCommon - FireRating: 0; Material: 41 dorpel d bi
CPset_Phasing - Renovation Phase: Bestaand
Name | GrossArea (m2) = NetArea (m2)
41_Afwerking_Dorpel | 0.5628
41_Afwerking_Waterslag | 0.5628
2 x 41_Afwerking_Waterslag | 0.29204
41_Afwerking_Waterslag | 0.29736

# IfcCovering: 41 dorpel d bi berging 192 x 95, 41_Afwerking_Waterslag
In: 00 begane grond
Classification: 41.11 AFWERKLAGEN (NL/SfB (4 cijfers)); Afwerking (ARCHICAD Classification); Material: Beton gewapend prefab
Pset_CoveringCommon - FireRating: 0; Material: 41 dorpel d bi berging
CPset_Phasing - Renovation Phase: Bestaand
BaseQuantities - GrossArea: 0.33984 m2; NetArea: 0.33984 m2
Component Quantities - Beton gewapend prefab, Mass: 72.6482 kg; Beton gewapend prefab, Component Cross Section Area: 0.0171018 m2; Beton gewapend prefab, Component Volume (Net): 0.0302701 m3; Beton gewapend prefab, Component Volume (Gross): 0.0302701 m3

# IfcCovering: 41 dorpel d bu 280 x 95 (2)
In: 00 begane grond
Classification: 41.11 AFWERKLAGEN (NL/SfB (4 cijfers)); Afwerking (ARCHICAD Classification)
Pset_CoveringCommon - FireRating: 0; Material: 41 dorpel d bu
CPset_Phasing - Renovation Phase: Bestaand
Name | GrossArea (m2) | NetArea (m2)
41_Afwerking_Dorpel | 0.58968 | 0.58968
41_Afwerking_Waterslag | 0.4956 | 0.4976

# IfcCovering: 42 Omtimmering kolom 205 x 196, 42_Wandafwerking_omtimmering kolom
In: 00 begane grond
Type - PredefinedType: CLADDING
Classification: Wandafwerking (ARCHICAD Classification); 42.12 BEKLEDINGEN (NL/SfB (4 cijfers)); Material: Brandwering
Pset_CoveringCommon - FireRating: 0; Material: 42 Omtimmering kolom
CPset_Phasing - Renovation Phase: Bestaand
BaseQuantities - GrossArea: 0.00565019 m2; NetArea: 0.00565019 m2
Component Quantities - Brandwering, Mass: 29.2906 kg; Brandwering, Component Cross Section Area: 0.00940019 m2; Brandwering, Component Volume (Net): 0.0244088 m3; Brandwering, Component Volume (Gross): 0.0244088 m3

# IfcCovering: 42 Omtimmering kolom 235 x 245 (64)
Type - PredefinedType: CLADDING
Classification: Wandafwerking (ARCHICAD Classification); 42.12 BEKLEDINGEN (NL/SfB (4 cijfers)); Material: Brandwering
Pset_CoveringCommon - FireRating: 0; Material: 42 Omtimmering kolom
CPset_Phasing - Renovation Phase: Bestaand
Component Quantities - Brandwering, Component Cross Section Area: 0.011375 m2
Name | In | GrossArea (m2) = NetArea (m2) | Brandwering, Mass (kg) | Brandwering, Component Volume (Net) (m3) | Brandwering, Component Volume (Gross) (m3)
42_Wandafwerking_omtimmering kolom | 00 begane grond | 0.0042875 | 18.7021 | 0.0155851 | 0.0155851
5 x 42_Wandafwerking_omtimmering kolom | 00 begane grond | 0.011375 | 49.6178 | 0.0413481 | 0.0413481
2 x 42_Wandafwerking_omtimmering kolom | 00 begane grond | 0.007625 | 33.2602 | 0.0277169 | 0.0277169
42_Wandafwerking_omtimmering kolom | 00 begane grond | 0.011375 | 49.4786 | 0.0412322 | 0.0412322
2 x 42_Wandafwerking_omtimmering kolom | 00 begane grond | 0.011375 | 48.7987 | 0.0406656 | 0.0406656
42_Wandafwerking_omtimmering kolom | 00 begane grond | 0.011375 | 48.7829 | 0.0406524 | 0.0406524
42_Wandafwerking_omtimmering kolom | 00 begane grond | 0.011375 | 49.5321 | 0.0412767 | 0.0412767
42_Wandafwerking_omtimmering kolom | 00 begane grond | 0.011375 | 49.5068 | 0.0412556 | 0.0412556
42_Wandafwerking_omtimmering kolom | 00 begane grond | 0.011375 | 49.0035 | 0.0408362 | 0.0408362
42_Wandafwerking_omtimmering kolom | 00 begane grond | 0.011375 | 52.85 | 0.0440417 | 0.043884
42_Wandafwerking_omtimmering kolom | 00 begane grond | 0.011375 | 49.5846 | 0.0413205 | 0.0413205
2 x 42_Wandafwerking_omtimmering kolom | 00 begane grond | 0.011375 | 48.8711 | 0.0407259 | 0.0407259
42_Wandafwerking_omtimmering kolom | 00 begane grond | 0.0113463 | 58.9326 | 0.0491105 | 0.0491105
42_Wandafwerking_omtimmering kolom | 00 begane grond | 0.011375 | 58.9636 | 0.0491363 | 0.0491363
42_Wandafwerking_omtimmering kolom | 00 begane grond | 0.0095 | 40.755 | 0.0339625 | 0.0339625
42_Wandafwerking_omtimmering kolom | 00 begane grond | 0.011375 | 47.4338 | 0.0395281 | 0.0395281
4 x 42_Wandafwerking_omtimmering kolom | 00 begane grond | 0.011375 | 47.4201 | 0.0395168 | 0.0395168
42_Wandafwerking_omtimmering kolom | 00 begane grond | 0.011375 | 49.8225 | 0.0415188 | 0.0415188
42_Wandafwerking_omtimmering kolom | 00 begane grond | 0.0095026 | 41.5569 | 0.0346307 | 0.0346245
42_Wandafwerking_omtimmering kolom | 00 begane grond | 0.011375 | 68.4411 | 0.0570343 | 0.0570343
42_Wandafwerking_omtimmering kolom | 00 begane grond | 0.011375 | 49.5904 | 0.0413254 | 0.0413254
42_Wandafwerking_omtimmering kolom | 00 begane grond | 0.0042875 | 18.772 | 0.0156433 | 0.0156433
42_Wandafwerking_omtimmering kolom | 00 begane grond | 0.011375 | 69.3983 | 0.0578319 | 0.0578319
42_Wandafwerking_omtimmering kolom | 00 begane grond | 0.00874881 | 16.3999 | 0.0136666 | 0.0136666
42_Wandafwerking_omtimmering kolom | 00 begane grond | 0.0038875 | 16.9573 | 0.0141311 | 0.0141311
42_Wandafwerking_omtimmering kolom | 00 begane grond | 0.0113552 | 69.5078 | 0.0579231 | 0.0579231
2 x 42_Wandafwerking_omtimmering kolom | 00 begane grond | 0.00428211 | 18.6786 | 0.0155655 | 0.0155655
9 x 42_Wandafwerking_omtimmering kolom | 01 eerste verdieping | 0.011375 | 52.2112 | 0.0435094 | 0.0435094
2 x 42_Wandafwerking_omtimmering kolom | 01 eerste verdieping | 0.011375 | 51.0647 | 0.0425539 | 0.0425539
42_Wandafwerking_omtimmering kolom | 01 eerste verdieping | 0.007625 | 46.4671 | 0.0387226 | 0.0387226
42_Wandafwerking_omtimmering kolom | 01 eerste verdieping | 0.00380381 | 32.2074 | 0.0268395 | 0.0268395
2 x 42_Wandafwerking_omtimmering kolom | 01 eerste verdieping | 0.011375 | 46.41 | 0.038675 | 0.038675
42_Wandafwerking_omtimmering kolom | 01 eerste verdieping | 0.011375 | 52.1318 | 0.0434432 | 0.0434432
42_Wandafwerking_omtimmering kolom | 01 eerste verdieping | 0.011375 | 50.6142 | 0.0421785 | 0.0421785
42_Wandafwerking_omtimmering kolom | 01 eerste verdieping | 0.00543752 | 42.1716 | 0.035143 | 0.035143
42_Wandafwerking_omtimmering kolom | 01 eerste verdieping | 0.00949999 | 58.0795 | 0.0483996 | 0.0483996
42_Wandafwerking_omtimmering kolom | 01 eerste verdieping | 0 | 51.8427 | 0.0432022 | 0.0432022
42_Wandafwerking_omtimmering kolom | 01 eerste verdieping | 0.00428751 | 19.6797 | 0.0163997 | 0.0163997
42_Wandafwerking_omtimmering kolom | 01 eerste verdieping | 0.00428751 | 19.2464 | 0.0160387 | 0.0160387
2 x 42_Wandafwerking_omtimmering kolom | 01 eerste verdieping | 0.0046875 | 21.5156 | 0.0179297 | 0.0179297
42_Wandafwerking_omtimmering kolom | 01 eerste verdieping | 0.00966863 | 42.7547 | 0.0356289 | 0.0356289
42_Wandafwerking_omtimmering kolom | 01 eerste verdieping | 0.0032769 | 16.5168 | 0.013764 | 0.013764

# IfcCovering: 42 Omtimmering kolom 3-ZIJDIG 235 x 232, 42_Wandafwerking_omtimmering kolom
In: 01 eerste verdieping
Type - PredefinedType: CLADDING
Classification: Wandafwerking (ARCHICAD Classification); 42.12 BEKLEDINGEN (NL/SfB (4 cijfers)); Material: Brandwering
Pset_CoveringCommon - FireRating: 0; Material: 42 Omtimmering kolom 3-ZIJDIG
CPset_Phasing - Renovation Phase: Bestaand
BaseQuantities - GrossArea: 0.00551676 m2; NetArea: 0.00551676 m2
Component Quantities - Brandwering, Mass: 24.4726 kg; Brandwering, Component Cross Section Area: 0.0084375 m2; Brandwering, Component Volume (Net): 0.0203938 m3; Brandwering, Component Volume (Gross): 0.0203938 m3

# IfcCovering: 42 Omtimmering kolom 400 x 245, 42_Wandafwerking_omtimmering kolom
In: 01 eerste verdieping
Type - PredefinedType: CLADDING
Classification: Wandafwerking (ARCHICAD Classification); 42.12 BEKLEDINGEN (NL/SfB (4 cijfers)); Material: Brandwering
Pset_CoveringCommon - FireRating: 0; Material: 42 Omtimmering kolom
CPset_Phasing - Renovation Phase: Bestaand
BaseQuantities - GrossArea: 0.0155 m2; NetArea: 0.0155 m2
Component Quantities - Brandwering, Mass: 71.1451 kg; Brandwering, Component Cross Section Area: 0.0155 m2; Brandwering, Component Volume (Net): 0.0592876 m3; Brandwering, Component Volume (Gross): 0.0592876 m3

# IfcCovering: 43 Vloerafwerking 90 (9)
Type - PredefinedType: FLOORING
Classification: Vloerafwerking (ARCHICAD Classification); 43.21 AFWERKLAGEN (NL/SfB (4 cijfers))
Pset_CoveringCommon - FireRating: 0; Material: 43 Vloerafwerking
CPset_Phasing - Renovation Phase: Bestaand
Name | In | GrossArea (m2) | NetArea (m2)
43_Vloerafwerking_Vloerafwerking | 00 begane grond | 105.523 | 105.52
43_Vloerafwerking_Vloerafwerking | 00 begane grond | 105.738 | 105.721
43_Vloerafwerking_Vloerafwerking | 00 begane grond | 115.811 | 115.488
43_Vloerafwerking_Vloerafwerking | 00 begane grond | 598.38 | 595.971
43_Vloerafwerking_Vloerafwerking | 00 begane grond | 20.2661 | 20.0882
43_Vloerafwerking_Vloerafwerking | 00 begane grond | 19.5624 | 19.535
43_Vloerafwerking_Vloerafwerking | 01 eerste verdieping | 247.173 | 247.132
43_Vloerafwerking_Vloerafwerking | 01 eerste verdieping | 50.1656 | 50.1503
43_Vloerafwerking_Vloerafwerking | 01 eerste verdieping | 574.3 | 556.753

# IfcCovering: 43 Vloerafwerking gym 90, 43_Vloerafwerking_Vloerafwerking
In: 00 begane grond
Type - PredefinedType: FLOORING
Classification: Vloerafwerking (ARCHICAD Classification); 43.21 AFWERKLAGEN (NL/SfB (4 cijfers)); Material: Cement
Pset_CoveringCommon - FireRating: 0; Material: 43 Vloerafwerking gym
CPset_Phasing - Renovation Phase: Bestaand
BaseQuantities - GrossArea: 380.319 m2; NetArea: 379.925 m2
Component Quantities - Cement, Mass: 64968.4 kg; Cement, Projected Component Area (Net): 379.941 m2; Cement, Projected Component Area (Gross): 379.429 m2; Cement, Component Thickness: 90 mm; Cement, Component Volume (Net): 34.1939 m3; Cement, Component Volume (Gross): 34.148 m3

# IfcCovering: 45 Gipsplafond op tengels 35, 43_Vloerafwerking_Vloerafwerking
In: 01 eerste verdieping
Type - PredefinedType: FLOORING
Classification: Vloerafwerking (ARCHICAD Classification); 43.21 AFWERKLAGEN (NL/SfB (4 cijfers)); Material: Gipsplaat
Pset_CoveringCommon - FireRating: 0; Material: 45 Gipsplafond op tengels
CPset_Phasing - Renovation Phase: Bestaand
BaseQuantities - GrossArea: 8.202 m2; NetArea: 8.20072 m2
Component Quantities - Gipsplaat, Mass: 82.0057 kg; Gipsplaat, Projected Component Area (Net): 8.20057 m2; Gipsplaat, Projected Component Area (Gross): 8.20057 m2; Gipsplaat, Component Thickness: 12.5 mm; Gipsplaat, Component Volume (Net): 0.102507 m3; Gipsplaat, Component Volume (Gross): 0.102507 m3

# IfcCovering: ALG - ISOLATIE 140, 21_Wandafwerking_Dakopstand
In: 02 dak
Type - PredefinedType: CLADDING
Classification: 21.12 SPOUWWANDEN (NL/SfB (4 cijfers)); Wandafwerking (ARCHICAD Classification); Material: ALG - ISOLATIE
Pset_CoveringCommon - FireRating: 0; Material: ALG - ISOLATIE
CPset_Phasing - Renovation Phase: Bestaand
BaseQuantities - GrossArea: 2.04792 m2; NetArea: 2.04792 m2
Component Quantities - ALG - ISOLATIE, Mass: 38.7552 kg; ALG - ISOLATIE, Projected Component Area (Net): 6.15161 m2; ALG - ISOLATIE, Projected Component Area (Gross): 6.15161 m2; ALG - ISOLATIE, Component Thickness: 140 mm; ALG - ISOLATIE, Rectangular Component Height: 420.537 mm; ALG - ISOLATIE, Rectangular Component Width: 140 mm; ALG - ISOLATIE, Component Cross Section Area: 0.0588752 m2; ALG - ISOLATIE, Component Volume (Net): 0.861226 m3; ALG - ISOLATIE, Component Volume (Gross): 0.861226 m3

# IfcCovering: Curtain Wall Type (61)
Type - PredefinedType: CEILING
Classification: Plafondafwerking (ARCHICAD Classification); 45.12 SYSTEEMPLAFONDS (NL/SfB (4 cijfers))
CPset_Phasing - Phase: 50; Renovation Phase: Bestaand
Pset_CoveringCommon - FireRating: 0
Name | In | GrossArea (m2) = NetArea (m2)
45_Plafondafwerking_P02 | 00 begane grond | 61.858
45_Plafondafwerking_P01 | 00 begane grond | 58.0497
45_Plafondafwerking_P04 | 00 begane grond | 27.6949
45_Plafondafwerking_P02 gec | 00 begane grond | 81.6972
45_Plafondafwerking_P02 | 00 begane grond | 9.04844
45_Plafondafwerking_P02 | 00 begane grond | 4.7533
45_Plafondafwerking_P02 | 00 begane grond | 6.74262
45_Plafondafwerking_P02 | 00 begane grond | 5.43845
45_Plafondafwerking_P02 | 00 begane grond | 6.71099
45_Plafondafwerking_P02 | 00 begane grond | 7.07454
45_Plafondafwerking_P02 | 00 begane grond | 9.80579
45_Plafondafwerking_P01 | 00 begane grond | 57.9814
45_Plafondafwerking_P02 | 00 begane grond | 7.49408
45_Plafondafwerking_P02 gec | 00 begane grond | 9.81424
45_Plafondafwerking_P02a | 00 begane grond | 1.4533
45_Plafondafwerking_P02 | 00 begane grond | 14.6235
45_Plafondafwerking_P02 v | 00 begane grond | 27.7206
45_Plafondafwerking_P02 v | 00 begane grond | 26.1931
45_Plafondafwerking_P02 | 00 begane grond | 7.24556
45_Plafondafwerking_P01 | 00 begane grond | 38.1562
45_Plafondafwerking_P02 | 00 begane grond | 8.47949
45_Plafondafwerking_P01 | 00 begane grond | 57.0767
45_Plafondafwerking_P02 gec | 00 begane grond | 5.72771
45_Plafondafwerking_P02 | 00 begane grond | 15.2726
45_Plafondafwerking_P04 | 00 begane grond | 7.73554
45_Plafondafwerking_P04 | 00 begane grond | 31.9829
45_Plafondafwerking_P04 | 00 begane grond | 27.3212
45_Plafondafwerking_P02 gec | 00 begane grond | 7.94503
45_Plafondafwerking_P02a | 00 begane grond | 5.38892
45_Plafondafwerking_P02a | 00 begane grond | 8.25572
45_Plafondafwerking_P02a | 00 begane grond | 8.44491
45_Plafondafwerking_P02 v | 00 begane grond | 11.9215
45_Plafondafwerking_P01 | 00 begane grond | 51.8767
45_Plafondafwerking_P01 | 00 begane grond | 51.5633
45_Plafondafwerking_P02 | 00 begane grond | 10.6595
45_Plafondafwerking_P01 | 00 begane grond | 52.0663
45_Plafondafwerking_P01 | 00 begane grond | 50.8942
45_Plafondafwerking_P02 | 00 begane grond | 13.6068
45_Plafondafwerking_P04 | 00 begane grond | 18.248
45_Plafondafwerking_P02 v | 00 begane grond | 1.86982
45_Plafondafwerking_P02a | 01 eerste verdieping | 12.322
45_Plafondafwerking_P01 | 01 eerste verdieping | 51.5692
45_Plafondafwerking_P02 | 01 eerste verdieping | 50.0573
45_Plafondafwerking_P02a | 01 eerste verdieping | 8.87663
45_Plafondafwerking_P02 | 01 eerste verdieping | 9.5841
45_Plafondafwerking_P01 | 01 eerste verdieping | 52.8551
45_Plafondafwerking_P02 | 01 eerste verdieping | 9.63544
45_Plafondafwerking_P01 | 01 eerste verdieping | 52.8607
45_Plafondafwerking_P01 | 01 eerste verdieping | 52.1122
45_Plafondafwerking_P01 | 01 eerste verdieping | 51.9285
45_Plafondafwerking_P02 | 01 eerste verdieping | 20.1799
45_Plafondafwerking_P01 | 01 eerste verdieping | 52.0371
45_Plafondafwerking_P02a | 01 eerste verdieping | 5.10229
45_Plafondafwerking_P04 | 01 eerste verdieping | 140.144
45_Plafondafwerking_P02a | 01 eerste verdieping | 3.12537
45_Plafondafwerking_P02 | 01 eerste verdieping | 86.6153
45_Plafondafwerking_P01 | 01 eerste verdieping | 51.8337
45_Plafondafwerking_P01 | 01 eerste verdieping | 52.1944
45_Plafondafwerking_P02 | 01 eerste verdieping | 17.8425
45_Plafondafwerking_P02a | 01 eerste verdieping | 5.93857
45_Plafondafwerking_P02 | 01 eerste verdieping | 77.508

# IfcCovering: Hout - Multiplex 100 x 13, 42_Wandafwerking_gipsplaat
In: 00 begane grond
Type - PredefinedType: CLADDING
Classification: Wandafwerking (ARCHICAD Classification); 42.12 BEKLEDINGEN (NL/SfB (4 cijfers)); Material: Hout - Multiplex
Pset_CoveringCommon - FireRating: 0; Material: Hout - Multiplex
CPset_Phasing - Renovation Phase: Bestaand
BaseQuantities - GrossArea: 0.318871 m2; NetArea: 0.318871 m2
Component Quantities - Hout - Multiplex, Mass: 2.79013 kg; Hout - Multiplex, Projected Component Area (Net): 0.0398589 m2; Hout - Multiplex, Projected Component Area (Gross): 0.0398589 m2; Hout - Multiplex, Component Thickness: 100 mm; Hout - Multiplex, Rectangular Component Height: 12.5 mm; Hout - Multiplex, Rectangular Component Width: 100 mm; Hout - Multiplex, Component Cross Section Area: 0.00125 m2; Hout - Multiplex, Component Volume (Net): 0.00398589 m3; Hout - Multiplex, Component Volume (Gross): 0.00398589 m3

# IfcCovering: Hout - Multiplex 90 24 x 90 (7)
In: 00 begane grond
Type - PredefinedType: CLADDING
Classification: Wandafwerking (ARCHICAD Classification); 42.12 BEKLEDINGEN (NL/SfB (4 cijfers)); Material: Hout - Multiplex 90
Pset_CoveringCommon - FireRating: 0; Material: Hout - Multiplex 90
CPset_Phasing - Renovation Phase: Bestaand
Component Quantities - Hout - Multiplex 90, Component Thickness: 24 mm; Hout - Multiplex 90, Rectangular Component Height: 90 mm; Hout - Multiplex 90, Rectangular Component Width: 24 mm; Hout - Multiplex 90, Component Cross Section Area: 0.00216 m2
Name | GrossArea (m2) = NetArea (m2) | Hout - Multiplex 90, Mass (kg) | Hout - Multiplex 90, Projected Component Area (Net) (m2) = Hout - Multiplex 90, Projected Component Area (Gross) (m2) | Hout - Multiplex 90, Component Volume (Net) (m3) = Hout - Multiplex 90, Component Volume (Gross) (m3)
42_Wandafwerking_Plint | 0.268584 | 16.9208 | 1.00827 | 0.0241726
42_Wandafwerking_Plint | 0.577524 | 36.384 | 2.16787 | 0.0519772
42_Wandafwerking_Plint | 0.0281092 | 1.77088 | 0.10649 | 0.00252983
42_Wandafwerking_Plint | 0.286291 | 18.0363 | 1.07467 | 0.0257662
42_Wandafwerking_Plint | 0.076956 | 4.84823 | 0.289665 | 0.00692604
42_Wandafwerking_Plint | 0.376248 | 23.7036 | 1.41201 | 0.0338623
42_Wandafwerking_Plint | 0.027912 | 1.75846 | 0.10575 | 0.00251208

# IfcCovering: Isolatie - Kunststof hard (3)
Type - PredefinedType: ROOFING
Classification: Dakafwerking (ARCHICAD Classification); 47.11 VLAKKE DAKAFWERKINGEN (NL/SfB (4 cijfers)); Material: Isolatie - Kunststof hard
Pset_CoveringCommon - FireRating: 0; Material: Isolatie - Kunststof hard
CPset_Phasing - Renovation Phase: Bestaand
Name | In
2 x 47_Dakafwerking_Dakbedekking+isolatie | 01 eerste verdieping
47_Dakafwerking_Dakbedekking+isolatie | 02 dak

# IfcCovering: Isolatie - Kunststof hard 100, 21_Wandafwerking_Dakopstand
In: 00 begane grond
Type - PredefinedType: CLADDING
Classification: 21.12 SPOUWWANDEN (NL/SfB (4 cijfers)); Wandafwerking (ARCHICAD Classification); Material: Isolatie - Kunststof hard
Pset_CoveringCommon - FireRating: 0; Material: Isolatie - Kunststof hard
CPset_Phasing - Renovation Phase: Bestaand
BaseQuantities - GrossArea: 0.922 m2; NetArea: 0.922 m2
Component Quantities - Isolatie - Kunststof hard, Mass: 42.8458 kg; Isolatie - Kunststof hard, Projected Component Area (Net): 4.28458 m2; Isolatie - Kunststof hard, Projected Component Area (Gross): 4.28458 m2; Isolatie - Kunststof hard, Component Thickness: 100 mm; Isolatie - Kunststof hard, Rectangular Component Height: 464.705 mm; Isolatie - Kunststof hard, Rectangular Component Width: 100 mm; Isolatie - Kunststof hard, Component Cross Section Area: 0.0464705 m2; Isolatie - Kunststof hard, Component Volume (Net): 0.428458 m3; Isolatie - Kunststof hard, Component Volume (Gross): 0.428458 m3

# IfcCovering: Isolatie - Kunststof hard 120, 43_Vloerafwerking_Vloerafwerking
In: 02 dak
Type - PredefinedType: FLOORING
Classification: Vloerafwerking (ARCHICAD Classification); 43.21 AFWERKLAGEN (NL/SfB (4 cijfers)); Material: Isolatie - Kunststof hard
Pset_CoveringCommon - FireRating: 0; Material: Isolatie - Kunststof hard
CPset_Phasing - Renovation Phase: Bestaand
BaseQuantities - GrossArea: 0 m2; NetArea: 0 m2
Component Quantities - Isolatie - Kunststof hard, Mass: 1827 kg; Isolatie - Kunststof hard, Projected Component Area (Net): 266.16 m2; Isolatie - Kunststof hard, Projected Component Area (Gross): 266.16 m2; Isolatie - Kunststof hard, Component Thickness: 120 mm; Isolatie - Kunststof hard, Component Volume (Net): 18.27 m3; Isolatie - Kunststof hard, Component Volume (Gross): 31.9392 m3

# IfcCovering: Isolatie - Kunststof hard 190 (2)
In: 02 dak
Type - PredefinedType: FLOORING
Classification: Vloerafwerking (ARCHICAD Classification); 43.21 AFWERKLAGEN (NL/SfB (4 cijfers)); Material: Isolatie - Kunststof hard
Pset_CoveringCommon - FireRating: 0; Material: Isolatie - Kunststof hard
CPset_Phasing - Renovation Phase: Bestaand
Component Quantities - Isolatie - Kunststof hard, Component Thickness: 190 mm
Name | GrossArea (m2) | NetArea (m2) | Isolatie - Kunststof hard, Mass (kg) | Isolatie - Kunststof hard, Projected Component Area (Net) (m2) | Isolatie - Kunststof hard, Projected Component Area (Gross) (m2) | Isolatie - Kunststof hard, Component Volume (Net) (m3) | Isolatie - Kunststof hard, Component Volume (Gross) (m3)
43_Vloerafwerking_Vloerafwerking | 0.0685596 | 0.00283321 | 2559.62 | 206.188 | 206.188 | 25.5962 | 39.1756
43_Vloerafwerking_Vloerafwerking | 0.00923552 | 0 | 2769.71 | 220.856 | 277.738 | 27.6971 | 52.7702

# IfcCovering: Isolatie - Kunststof hard 70, 43_Vloerafwerking_Vloerafwerking
In: 02 dak
Type - PredefinedType: FLOORING
Classification: Vloerafwerking (ARCHICAD Classification); 43.21 AFWERKLAGEN (NL/SfB (4 cijfers)); Material: Isolatie - Kunststof hard
Pset_CoveringCommon - FireRating: 0; Material: Isolatie - Kunststof hard
CPset_Phasing - Renovation Phase: Bestaand
BaseQuantities - GrossArea: 0.056006 m2; NetArea: 0 m2
Component Quantities - Isolatie - Kunststof hard, Mass: 932.586 kg; Isolatie - Kunststof hard, Projected Component Area (Net): 212.794 m2; Isolatie - Kunststof hard, Projected Component Area (Gross): 212.794 m2; Isolatie - Kunststof hard, Component Thickness: 70 mm; Isolatie - Kunststof hard, Component Volume (Net): 9.32586 m3; Isolatie - Kunststof hard, Component Volume (Gross): 14.8956 m3

# IfcCovering: MS125 2.75.2A 125, 41_Afwerking_Waterslag
In: 00 begane grond
Classification: 41.11 AFWERKLAGEN (NL/SfB (4 cijfers)); Afwerking (ARCHICAD Classification)
Pset_CoveringCommon - FireRating: 0; Material: MS125 2.75.2A
CPset_Phasing - Renovation Phase: Bestaand
BaseQuantities - GrossArea: 0.479375 m2; NetArea: 0.479375 m2

# IfcCovering: Steen - Cellenbeton 100 (2)
In: 02 dak
Type - PredefinedType: CLADDING
Classification: 21.12 SPOUWWANDEN (NL/SfB (4 cijfers)); Wandafwerking (ARCHICAD Classification); Material: Steen - Cellenbeton
Pset_CoveringCommon - FireRating: 0; Material: Steen - Cellenbeton
CPset_Phasing - Renovation Phase: Bestaand
Component Quantities - Steen - Cellenbeton, Component Thickness: 100 mm; Steen - Cellenbeton, Rectangular Component Width: 100 mm
Name | GrossArea (m2) = NetArea (m2) | Steen - Cellenbeton, Mass (kg) | Steen - Cellenbeton, Projected Component Area (Net) (m2) | Steen - Cellenbeton, Projected Component Area (Gross) (m2) | Steen - Cellenbeton, Rectangular Component Height (mm) | Steen - Cellenbeton, Component Cross Section Area (m2) | Steen - Cellenbeton, Component Volume (Net) (m3) | Steen - Cellenbeton, Component Volume (Gross) (m3)
21_Wandafwerking_Dakopstand | 1.44942 | 303.29 | 4.33275 | 4.27579 | 295 | 0.0295 | 0.433271 | 0.427579
21_Wandafwerking_Dakopstand | 0.0133792 | 3.98446 | 0.0569632 | 0.0569632 | 426.159 | 0.0426159 | 0.00569209 | 0.00569209

# IfcCovering: Tegels - Vloer 50, 47_Dakafwerking_Tegels
In: 01 eerste verdieping
Type - PredefinedType: ROOFING
Classification: Dakafwerking (ARCHICAD Classification); 47.11 VLAKKE DAKAFWERKINGEN (NL/SfB (4 cijfers)); Material: Tegels - Vloer
Pset_CoveringCommon - FireRating: 0; Material: Tegels - Vloer
CPset_Phasing - Renovation Phase: Bestaand
Component Quantities - Tegels - Vloer, Mass: 13703.1 kg; Tegels - Vloer, Projected Component Area (Net): 119.157 m2; Tegels - Vloer, Projected Component Area (Gross): 119.157 m2; Tegels - Vloer, Component Thickness: 50 mm; Tegels - Vloer, Component Volume (Net): 5.95786 m3; Tegels - Vloer, Component Volume (Gross): 5.95786 m3

# IfcCurtainWall: Curtain Wall Type, 21_Vliesgevel_Vliesgevel
In: 00 begane grond
Classification: Vliesgevel (ARCHICAD Classification); 21.14 VLIESWANDEN (NL/SfB (4 cijfers))
Pset_CurtainWallCommon - Reference: Type vliesgevel; FireRating: 0; IsExternal: yes
CPset_Phasing - Renovation Phase: Bestaand
BaseQuantities - Width: 180 mm; Length: 3383.86 mm; Height: 6800 mm; GrossSideArea: 23.0103 m2; NetSideArea: 23.0103 m2

# IfcDoor: D1 25 (18)
Type - OperationType: SINGLE_SWING_LEFT; ParameterTakesPrecedence: no; Sizeable: no
Classification: Deur (ARCHICAD Classification); 32.31 DRAAIDEUREN (NL/SfB (4 cijfers))
Pset_DoorCommon - Reference: 32_n.v.t.; ThermalTransmittance: 0; IsExternal: no
Material - Frame / Draaiend deel: n.v.t.; Deurblad: n.v.t.; Onderdorpel: n.v.t.; Stofdorpel: n.v.t.; Vensterbank: n.v.t.; Ventilatierooster: n.v.t.; Spouwlat: n.v.t.; Rollaag / Latei: n.v.t.; Afwerking dagkant buiten: n.v.t.; Afwerking dagkant binnen: n.v.t.; Zonwering - behuizing: n.v.t.; Zonwering - isolatie: n.v.t.; Glas: Glas - algemeen
CPset_Phasing - Renovation Phase: Bestaand
Name | In | OverallHeight (mm) = Height (mm) | OverallWidth (mm) | FireRating | SelfClosing | FireResistanceRating | Width (mm) | Perimeter (mm) | Area (m2) | Volume (m3) = NetVolume (m3) = Component, Component Volume (Net) (m3) = Component, Component Volume (Gross) (m3) | Depth (mm) | GlazingAreaFraction
3 x 32_Deur_h.01a | 00 begane grond | 2367 | 1034 | 0 | no | Geen | 1034 | 6802 | 2.44748 | 0.125883 | 100
32_Deur_h.01c | 00 begane grond | 2367 | 1034 | 0 | no | Geen | 1034 | 6802 | 2.44748 | 0.0725356 | 100 | 1.33368
3 x 32_Deur_h.01c | 00 begane grond | 2367 | 1034 | 0 | no | Geen | 1034 | 6802 | 2.44748 | 0.0777052 | 125 | 1.20444
2 x 32_Deur_h.01b | 00 begane grond | 2367 | 1034 | 0 | no | Geen | 1034 | 6802 | 2.44748 | 0.124964 | 125
2 x 32_Deur_h.01c | 00 begane grond | 2367 | 1034 | 0 | no | Geen | 1034 | 6802 | 2.44748 | 0.0777052 | 100 | 1.20444
32_Deur_h.01d | 00 begane grond | 2367 | 1034 | 0 | no | Geen | 1034 | 6802 | 2.44748 | 0.113187 | 100 | 0.3174
32_Deur_L | 00 begane grond | 2000 | 945 | 0 | no |  | 945 | 5890 | 1.89 | 0.047496 |  | 1.2963
32_Deur_h.01d | 01 eerste verdieping | 2367 | 1034 | 0 | no | Geen | 1034 | 6802 | 2.44748 | 0.113187 | 100 | 0.3174
32_Deur_h.01a | 01 eerste verdieping | 2367 | 1034 | 0 | no | Geen | 1034 | 6802 | 2.44748 | 0.125883 | 100
32_Deur_h.01a | 01 eerste verdieping | 2367 | 1034 | 60 | yes | 60 minuten brandwerend en zelfsluitend | 1034 | 6802 | 2.44748 | 0.125883 | 100
32_Deur_h.01d | 01 eerste verdieping | 2367 | 1034 | 0 | no | Geen | 1030.09 | 6794.19 | 2.43823 | 0.113187 | 100 | 0.3174
32_Deur_L | 01 eerste verdieping | 2000 | 945 | 0 | no |  | 945 | 5890 | 1.89 | 0.047496 |  | 1.2963

# IfcDoor: D1 25 (25)
Type - OperationType: SINGLE_SWING_RIGHT; ParameterTakesPrecedence: no; Sizeable: no
Classification: Deur (ARCHICAD Classification); 32.31 DRAAIDEUREN (NL/SfB (4 cijfers))
Pset_DoorCommon - Reference: 32_n.v.t.; ThermalTransmittance: 0; IsExternal: no
Material - Frame / Draaiend deel: n.v.t.; Deurblad: n.v.t.; Onderdorpel: n.v.t.; Stofdorpel: n.v.t.; Vensterbank: n.v.t.; Ventilatierooster: n.v.t.; Spouwlat: n.v.t.; Rollaag / Latei: n.v.t.; Afwerking dagkant buiten: n.v.t.; Afwerking dagkant binnen: n.v.t.; Zonwering - behuizing: n.v.t.; Zonwering - isolatie: n.v.t.; Glas: Glas - algemeen
CPset_Phasing - Renovation Phase: Bestaand
Name | In | OverallHeight (mm) | OverallWidth (mm) | FireRating | GlazingAreaFraction | SelfClosing | FireResistanceRating | Height (mm) | Width (mm) | Perimeter (mm) | Area (m2) | Volume (m3) = NetVolume (m3) = Component, Component Volume (Net) (m3) = Component, Component Volume (Gross) (m3) | Depth (mm)
32_Deur_h.01d | 00 begane grond | 2367 | 1034 | 0 | 0.3174 | no | Geen | 2367 | 1034 | 6802 | 2.44748 | 0.113136 | 150
32_Deur_h.01a | 00 begane grond | 2367 | 1034 | 0 |  | no | Geen | 2367 | 1034 | 6802 | 2.44748 | 0.125832 | 150
32_Deur_h.01a | 00 begane grond | 2367 | 1034 | 0 |  | no | Zelfsluitend | 2350 | 1034 | 6768 | 2.4299 | 0.125832 | 33
2 x 32_Deur_h.01c | 00 begane grond | 2367 | 1034 | 0 | 1.20444 | no | Geen | 2367 | 1034 | 6802 | 2.44748 | 0.0777052 | 100
5 x 32_Deur_h.01a | 00 begane grond | 2367 | 1034 | 0 |  | no | Geen | 2367 | 1034 | 6802 | 2.44748 | 0.125883 | 100
2 x 32_Deur_h.01b | 00 begane grond | 2367 | 1034 | 0 |  | no | Geen | 2367 | 1034 | 6802 | 2.44748 | 0.124964 | 125
32_Deur_h.01c | 00 begane grond | 2367 | 1034 | 0 | 1.20444 | no | Geen | 2367 | 1034 | 6802 | 2.44748 | 0.0777052 | 125
32_Deur_h.01c | 00 begane grond | 2367 | 1034 | 60 | 1.20444 | yes | 60 minuten brandwerend en zelfsluitend | 2367 | 1034 | 6802 | 2.44748 | 0.0777052 | 100
32_Deur_h.01d | 00 begane grond | 2367 | 1034 | 0 | 0.3174 | no | Geen | 2367 | 1034 | 6802 | 2.44748 | 0.113187 | 100
32_Deur_P.01 | 00 begane grond | 2300 | 920 | 0 | 1.085 | no |  | 2300 | 920 | 6440 | 2.116 | 0.08248 | 80
32_Deur_L | 00 begane grond | 2000 | 945 | 0 | 1.2963 | no |  | 2000 | 945 | 5890 | 1.89 | 0.047496
32_Deur_h.01c | 00 begane grond | 2367 | 1034 | 60 | 1.27184 | yes | 60 minuten brandwerend en zelfsluitend | 2367 | 1034 | 6802 | 2.44748 | 0.0750092 | 125
2 x 32_Deur_h.01d | 01 eerste verdieping | 2367 | 1034 | 0 | 0.3174 | no | Geen | 2367 | 1034 | 6802 | 2.44748 | 0.113187 | 100
2 x 32_Deur_h.01a | 01 eerste verdieping | 2367 | 1034 | 0 |  | no | Geen | 2367 | 1034 | 6802 | 2.44748 | 0.125883 | 100
32_Deur_h.01c | 01 eerste verdieping | 2367 | 1034 | 0 | 1.20444 | no | Geen | 2367 | 1034 | 6802 | 2.44748 | 0.0777052 | 100
32_Deur_L | 01 eerste verdieping | 2000 | 945 | 0 | 1.2963 | no |  | 2000 | 945 | 5890 | 1.89 | 0.047496
32_Deur_A.16 | 02 dak | 1984 | 1095 | 0 | 1.37427 | no |  | 1824.09 | 1127 | 5902.18 | 2.05575 | 0.0494891 | 100

# IfcDoor: D1 bl 25, 31_Deur_A.04
In: 00 begane grond
Type - OperationType: SINGLE_SWING_RIGHT; ParameterTakesPrecedence: no; Sizeable: no
OverallHeight: 2800 mm; OverallWidth: 1046 mm; Classification: Deur (ARCHICAD Classification); 31.31 DRAAIDEUREN (NL/SfB (4 cijfers))
Pset_DoorCommon - Reference: 31_n.v.t.; FireRating: 0; ThermalTransmittance: 0; GlazingAreaFraction: 1.90629; SelfClosing: no; IsExternal: yes
Material - Frame / Draaiend deel: n.v.t.; Deurblad: n.v.t.; Onderdorpel: n.v.t.; Stofdorpel: n.v.t.; Vensterbank: n.v.t.; Ventilatierooster: n.v.t.; Spouwlat: n.v.t.; Rollaag / Latei: n.v.t.; Afwerking dagkant buiten: n.v.t.; Afwerking dagkant binnen: n.v.t.; Zonwering - behuizing: n.v.t.; Zonwering - isolatie: n.v.t.; Glas: Glas - algemeen
CPset_Phasing - Renovation Phase: Bestaand
BaseQuantities - Height: 2875 mm; Width: 1062 mm; Perimeter: 7874 mm; Area: 3.05325 m2; Volume: 0.0632717 m3; Depth: 280 mm; NetVolume: 0.0632717 m3
Component Quantities - Component, Component Volume (Net): 0.0632717 m3; Component, Component Volume (Gross): 0.0632717 m3

# IfcDoor: D1 bl zl1-b 25 (6)
Type - OperationType: SINGLE_SWING_LEFT; ParameterTakesPrecedence: no; Sizeable: no
OverallWidth: 1994 mm; Classification: Deur (ARCHICAD Classification); 31.31 DRAAIDEUREN (NL/SfB (4 cijfers))
Pset_DoorCommon - Reference: 31_n.v.t.; FireRating: 0; ThermalTransmittance: 0; SelfClosing: no; IsExternal: yes
Material - Frame / Draaiend deel: n.v.t.; Deurblad: n.v.t.; Onderdorpel: n.v.t.; Stofdorpel: n.v.t.; Vensterbank: n.v.t.; Ventilatierooster: n.v.t.; Spouwlat: n.v.t.; Rollaag / Latei: n.v.t.; Afwerking dagkant buiten: n.v.t.; Afwerking dagkant binnen: n.v.t.; Zonwering - behuizing: n.v.t.; Zonwering - isolatie: n.v.t.; Glas: Glas - algemeen
CPset_Phasing - Renovation Phase: Bestaand
BaseQuantities - Width: 2010 mm; Depth: 280 mm
Name | In | OverallHeight (mm) | GlazingAreaFraction | Height (mm) | Perimeter (mm) | Area (m2) | Volume (m3) = NetVolume (m3) = Component, Component Volume (Net) (m3) | Component, Component Volume (Gross) (m3)
2 x 31_Deur_A.02a | 00 begane grond | 2803.5 | 3.36735 | 2875 | 9770 | 5.77875 | 0.122388 | 0.123879
2 x 31_Deur_A.02 | 00 begane grond | 2816 | 3.38873 | 2875 | 9770 | 5.77875 | 0.124087 | 0.124087
31_Deur_A.02a | 00 begane grond | 2803.5 | 3.36735 | 2875 | 9770 | 5.77875 | 0.123879 | 0.123879
31_Deur_A.13 | 01 eerste verdieping | 2694.02 | 3.16123 | 2912.5 | 9845 | 5.85412 | 0.139524 | 0.139524

# IfcDoor: D1 bl zl1-b 25 (3)
Type - OperationType: SINGLE_SWING_RIGHT; ParameterTakesPrecedence: no; Sizeable: no
OverallWidth: 1994 mm; Classification: Deur (ARCHICAD Classification); 31.31 DRAAIDEUREN (NL/SfB (4 cijfers))
Pset_DoorCommon - Reference: 31_n.v.t.; FireRating: 0; ThermalTransmittance: 0; SelfClosing: no; IsExternal: yes
Material - Frame / Draaiend deel: n.v.t.; Deurblad: n.v.t.; Onderdorpel: n.v.t.; Stofdorpel: n.v.t.; Vensterbank: n.v.t.; Ventilatierooster: n.v.t.; Spouwlat: n.v.t.; Rollaag / Latei: n.v.t.; Afwerking dagkant buiten: n.v.t.; Afwerking dagkant binnen: n.v.t.; Zonwering - behuizing: n.v.t.; Zonwering - isolatie: n.v.t.; Glas: Glas - algemeen
CPset_Phasing - Renovation Phase: Bestaand
BaseQuantities - Width: 2010 mm; Depth: 280 mm
Name | In | OverallHeight (mm) | GlazingAreaFraction | Height (mm) | Perimeter (mm) | Area (m2) | Volume (m3) = NetVolume (m3) = Component, Component Volume (Net) (m3) = Component, Component Volume (Gross) (m3)
31_Deur_A.02a | 00 begane grond | 2803.5 | 3.36735 | 2875 | 9770 | 5.77875 | 0.123879
2 x 31_Deur_A.13 | 01 eerste verdieping | 2694.02 | 3.16123 | 2912.5 | 9845 | 5.85412 | 0.139524

# IfcDoor: D1 zl1-b 25 (4)
Type - OperationType: SINGLE_SWING_LEFT; ParameterTakesPrecedence: no; Sizeable: no
OverallHeight: 2367 mm; Classification: Deur (ARCHICAD Classification); 32.31 DRAAIDEUREN (NL/SfB (4 cijfers))
Pset_DoorCommon - Reference: 32_n.v.t.; ThermalTransmittance: 0; IsExternal: no
Material - Frame / Draaiend deel: n.v.t.; Deurblad: n.v.t.; Onderdorpel: n.v.t.; Stofdorpel: n.v.t.; Vensterbank: n.v.t.; Ventilatierooster: n.v.t.; Spouwlat: n.v.t.; Rollaag / Latei: n.v.t.; Afwerking dagkant buiten: n.v.t.; Afwerking dagkant binnen: n.v.t.; Zonwering - behuizing: n.v.t.; Zonwering - isolatie: n.v.t.; Glas: Glas - algemeen
CPset_Phasing - Renovation Phase: Bestaand
BaseQuantities - Height: 2367 mm
Name | In | OverallWidth (mm) = Width (mm) | FireRating | GlazingAreaFraction | SelfClosing | Perimeter (mm) | Area (m2) | Volume (m3) = NetVolume (m3) = Component, Component Volume (Net) (m3) = Component, Component Volume (Gross) (m3) | Depth (mm)
32_Deur_h.15 | 00 begane grond | 2757 | 60 | 3.54824 | yes | 10248 | 6.52582 | 0.186315 | 125 | Pset_FireRatingProperties - FireResistanceRating: 60 minuten brandwerend en zelfsluitend
32_Deur_h.13 | 01 eerste verdieping | 1625 | 0 | 1.17009 | no | 7984 | 3.84638 | 0.151967 | 100
32_Deur_h.13 | 01 eerste verdieping | 1635.67 | 0 | 2.39837 | no | 8005.35 | 3.87164 | 0.103952 | 125
32_Deur_h.18 | 01 eerste verdieping | 1987 | 0 | 3.18288 | no | 8708 | 4.70323 | 0.109319 | 125

# IfcDoor: D1 zl1-b 25 (3)
Type - OperationType: SINGLE_SWING_RIGHT; ParameterTakesPrecedence: no; Sizeable: no
OverallHeight: 2367 mm; Classification: Deur (ARCHICAD Classification); 32.31 DRAAIDEUREN (NL/SfB (4 cijfers))
Pset_DoorCommon - Reference: 32_n.v.t.; ThermalTransmittance: 0; IsExternal: no
Material - Frame / Draaiend deel: n.v.t.; Deurblad: n.v.t.; Onderdorpel: n.v.t.; Stofdorpel: n.v.t.; Vensterbank: n.v.t.; Ventilatierooster: n.v.t.; Spouwlat: n.v.t.; Rollaag / Latei: n.v.t.; Afwerking dagkant buiten: n.v.t.; Afwerking dagkant binnen: n.v.t.; Zonwering - behuizing: n.v.t.; Zonwering - isolatie: n.v.t.; Glas: Glas - algemeen
CPset_Phasing - Renovation Phase: Bestaand
BaseQuantities - Height: 2367 mm
Name | In | OverallWidth (mm) = Width (mm) | FireRating | GlazingAreaFraction | SelfClosing | FireResistanceRating | Perimeter (mm) | Area (m2) | Volume (m3) = NetVolume (m3) = Component, Component Volume (Net) (m3) = Component, Component Volume (Gross) (m3) | Depth (mm)
32_Deur_h.13 | 00 begane grond | 1625 | 60 | 1.17009 | yes | 60 minuten brandwerend en zelfsluitend | 7984 | 3.84638 | 0.151967 | 125
32_Deur_h.18 | 01 eerste verdieping | 1987 | 0 | 3.18288 | no |  | 8708 | 4.70323 | 0.109319 | 125
32_Deur_h.20 | 01 eerste verdieping | 1689.36 | 30 | 1.31381 | yes | 30 minuten brandwerend en zelfsluitend | 8112.72 | 3.99872 | 0.15295 | 100
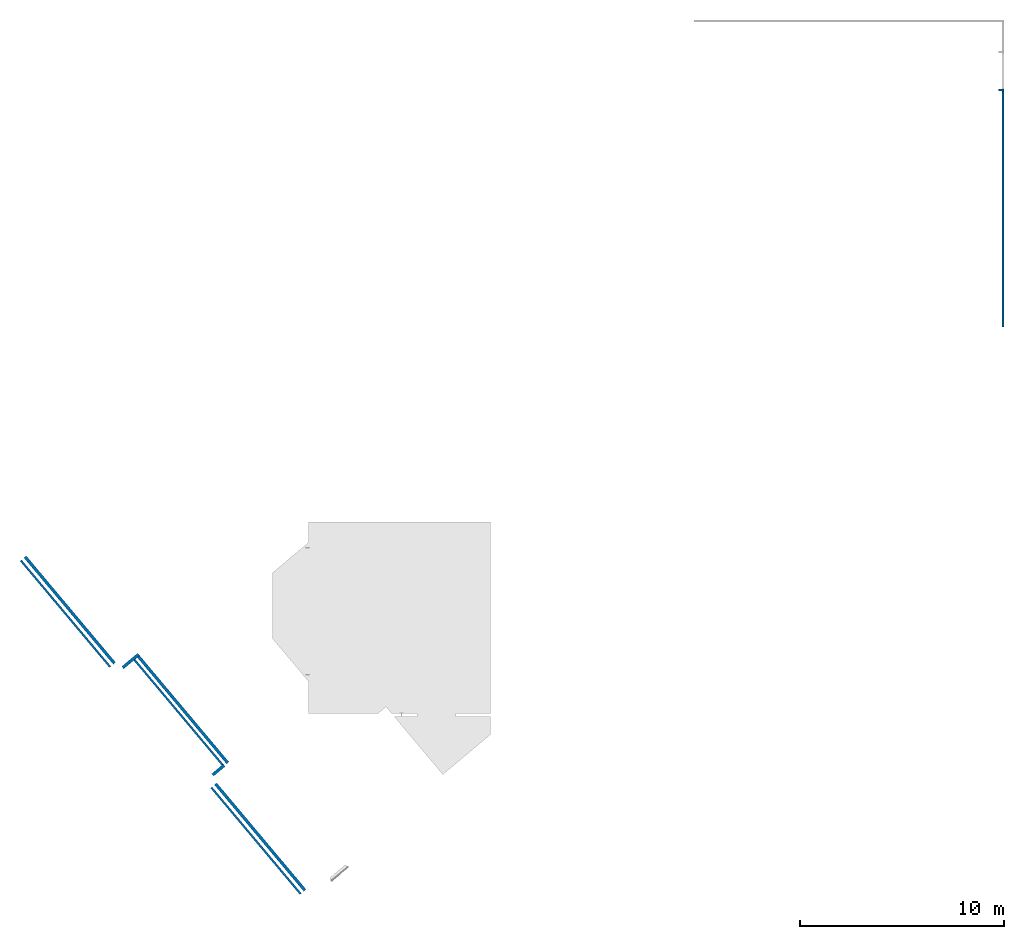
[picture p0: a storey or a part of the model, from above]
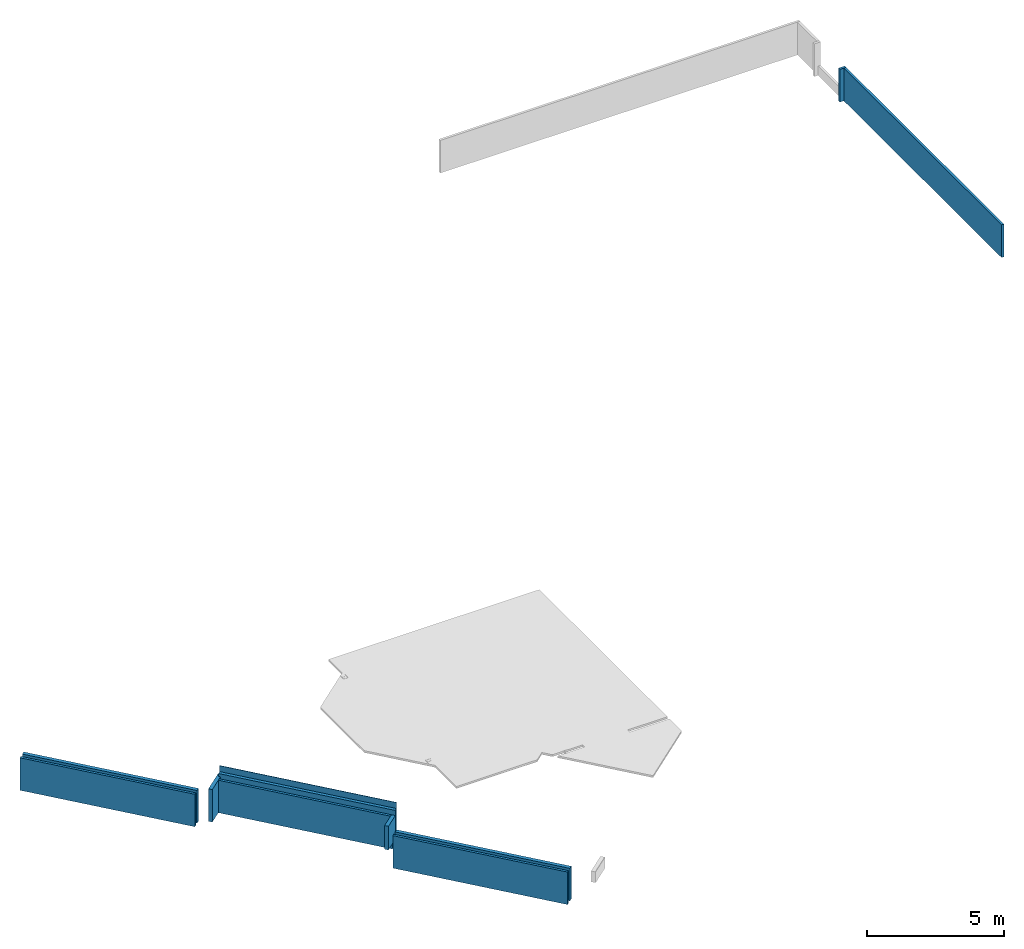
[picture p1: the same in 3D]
Properties of the parts of a building model (IFC2X3), part 9 of 11

# IfcDoor: D2 25 (12)
Type - OperationType: DOUBLE_DOOR_SINGLE_SWING; ParameterTakesPrecedence: no; Sizeable: no
Pset_DoorCommon - ThermalTransmittance: 0
Material - Frame / Draaiend deel: n.v.t.; Deurblad: n.v.t.; Onderdorpel: n.v.t.; Stofdorpel: n.v.t.; Vensterbank: n.v.t.; Ventilatierooster: n.v.t.; Spouwlat: n.v.t.; Rollaag / Latei: n.v.t.; Afwerking dagkant buiten: n.v.t.; Afwerking dagkant binnen: n.v.t.; Zonwering - behuizing: n.v.t.; Zonwering - isolatie: n.v.t.; Glas: Glas - algemeen
CPset_Phasing - Renovation Phase: Bestaand
Name | In | OverallHeight (mm) | OverallWidth (mm) | Classification | Reference | FireRating | GlazingAreaFraction | SelfClosing | IsExternal | Height (mm) | Width (mm) | Perimeter (mm) | Area (m2) | Volume (m3) = NetVolume (m3) = Component, Component Volume (Net) (m3) = Component, Component Volume (Gross) (m3) | Depth (mm)
32_Deur_h.08 | 00 begane grond | 2367 | 1977 | Deur (ARCHICAD Classification); 32.31 DRAAIDEUREN (NL/SfB (4 cijfers)) | 32_n.v.t. | 0 | 2.42496 | no | no | 2457 | 1977 | 8868 | 4.85749 | 0.122843 | 100
32_Deur_h.12 | 00 begane grond | 2367 | 1934 | Deur (ARCHICAD Classification); 32.31 DRAAIDEUREN (NL/SfB (4 cijfers)) | 32_n.v.t. | 0 |  | no | no | 2367 | 1934 | 8602 | 4.57778 | 0.215507 | 150
31_Deur_H.14 | 00 begane grond | 2415 | 1760 | Deur (ARCHICAD Classification); 31.31 DRAAIDEUREN (NL/SfB (4 cijfers)) | 31_n.v.t. | 0 |  | no | yes | 2717.5 | 1770 | 8975 | 4.80997 | 0.251416 | 280
31_Deur_A.06a | 00 begane grond | 2786 | 2090 | Deur (ARCHICAD Classification); 31.31 DRAAIDEUREN (NL/SfB (4 cijfers)) | 31_n.v.t. | 0 | 3.92593 | no | yes | 2855 | 2106 | 9922 | 6.01263 | 0.117347 | 280 | Pset_FireRatingProperties - FireResistanceRating: Geen
32_Deur_h.08 | 00 begane grond | 2367 | 1845 | Deur (ARCHICAD Classification); 32.31 DRAAIDEUREN (NL/SfB (4 cijfers)) | 32_n.v.t. | 60 | 2.18907 | yes | no | 2367 | 1845 | 8424 | 4.36712 | 0.119126 | 100 | Pset_FireRatingProperties - FireResistanceRating: 60 minuten brandwerend en zelfsluitend
2 x 32_Deur_h.08 | 00 begane grond | 2367 | 1977 | Deur (ARCHICAD Classification); 32.31 DRAAIDEUREN (NL/SfB (4 cijfers)) | 32_n.v.t. | 0 | 2.42496 | no | no | 2367 | 1977 | 8688 | 4.67956 | 0.122843 | 100
32_Deur_h.08 | 00 begane grond | 2367 | 1790 | Deur (ARCHICAD Classification); 32.31 DRAAIDEUREN (NL/SfB (4 cijfers)) | 32_n.v.t. | 60 | 2.20779 | yes | no | 2367 | 1790 | 8314 | 4.23693 | 0.112897 | 100 | Pset_FireRatingProperties - FireResistanceRating: 60 minuten brandwerend en zelfsluitend
32_Deur_h.10 | 00 begane grond | 2367 | 1760 | Deur (ARCHICAD Classification); 32.31 DRAAIDEUREN (NL/SfB (4 cijfers)) | 32_n.v.t. | 0 |  | no | no | 2367 | 1760 | 8254 | 4.16592 | 0.19822 | 100
32_Deur_h.08 | 00 begane grond | 2367 | 1790 | Deur (ARCHICAD Classification); 32.31 DRAAIDEUREN (NL/SfB (4 cijfers)) | 32_n.v.t. | 60 | 2.09079 | yes | no | 2367 | 1790 | 8314 | 4.23693 | 0.117577 | 100 | Pset_FireRatingProperties - FireResistanceRating: 60 minuten brandwerend en zelfsluitend
31_Deur_H.14 | 00 begane grond | 2387 | 1760 | Deur (ARCHICAD Classification); 31.31 DRAAIDEUREN (NL/SfB (4 cijfers)) | 31_n.v.t. | 0 |  | no | yes | 1410 | 1826 | 6472 | 2.57466 | 0.250947 | 100
32_Deur_h.19b | 01 eerste verdieping | 2367 | 2252.5 | Deur (ARCHICAD Classification); 32.31 DRAAIDEUREN (NL/SfB (4 cijfers)) | 32_n.v.t. | 60 | 2.82987 | yes | no | 2367 | 2252.5 | 9239 | 5.33167 | 0.134147 | 100 | Pset_FireRatingProperties - FireResistanceRating: 60 minuten brandwerend en zelfsluitend

# IfcDoor: D2 bl 25 (2)
In: 00 begane grond
Type - OperationType: DOUBLE_DOOR_SINGLE_SWING; ParameterTakesPrecedence: no; Sizeable: no
OverallWidth: 1994 mm; Classification: Deur (ARCHICAD Classification); 31.31 DRAAIDEUREN (NL/SfB (4 cijfers))
Pset_DoorCommon - Reference: 31_n.v.t.; FireRating: 0; ThermalTransmittance: 0; SelfClosing: no; IsExternal: yes
Material - Frame / Draaiend deel: n.v.t.; Deurblad: n.v.t.; Onderdorpel: n.v.t.; Stofdorpel: n.v.t.; Vensterbank: n.v.t.; Ventilatierooster: n.v.t.; Spouwlat: n.v.t.; Rollaag / Latei: n.v.t.; Afwerking dagkant buiten: n.v.t.; Afwerking dagkant binnen: n.v.t.; Zonwering - behuizing: n.v.t.; Zonwering - isolatie: n.v.t.; Glas: Glas - algemeen
CPset_Phasing - Renovation Phase: Bestaand
BaseQuantities - Width: 2010 mm; Depth: 280 mm
Name | OverallHeight (mm) | GlazingAreaFraction | Height (mm) | Perimeter (mm) | Area (m2) | Volume (m3) = NetVolume (m3) = Component, Component Volume (Net) (m3) = Component, Component Volume (Gross) (m3)
31_Deur_A.08 | 2800 | 3.67128 | 2875 | 9770 | 5.77875 | 0.118284
31_Deur_A.05 | 4237.5 | 3.05684 | 4312.5 | 12645 | 8.66812 | 0.307614

# IfcDoor: DS1 voor wand 25, 32_Deur_s.01
In: 01 eerste verdieping
Type - OperationType: SLIDING_TO_RIGHT; ParameterTakesPrecedence: no; Sizeable: no
OverallHeight: 2100 mm; OverallWidth: 1000 mm; Classification: Deur (ARCHICAD Classification); 32.31 DRAAIDEUREN (NL/SfB (4 cijfers))
Pset_DoorCommon - Reference: 32_n.v.t.; FireRating: 0; ThermalTransmittance: 0; SelfClosing: no; IsExternal: no
Material - Frame / Draaiend deel: n.v.t.; Deurblad: n.v.t.; Onderdorpel: n.v.t.; Stofdorpel: n.v.t.; Vensterbank: n.v.t.; Spouwlat: n.v.t.; Rollaag / Latei: n.v.t.; Afwerking dagkant buiten: n.v.t.; Afwerking dagkant binnen: n.v.t.; Zonwering - behuizing: n.v.t.; Zonwering - isolatie: n.v.t.; Glas: Glas - algemeen
CPset_Phasing - Renovation Phase: Bestaand
BaseQuantities - Height: 2190 mm; Width: 999.9 mm; Perimeter: 6379.8 mm; Area: 2.18978 m2; Volume: 0.084 m3; Depth: 150 mm; NetVolume: 0.084 m3
Component Quantities - Component, Component Volume (Net): 0.084 m3; Component, Component Volume (Gross): 0.084 m3

# IfcDoor: DSn 25 (13)
Type - OperationType: USERDEFINED; ParameterTakesPrecedence: no; Sizeable: no
OverallHeight: 2367 mm; OverallWidth: 2485 mm; Classification: Deur (ARCHICAD Classification); 32.31 DRAAIDEUREN (NL/SfB (4 cijfers))
Pset_DoorCommon - Reference: 32_n.v.t.; FireRating: 0; ThermalTransmittance: 0; GlazingAreaFraction: 3.62949; SelfClosing: no; IsExternal: no
Material - Frame / Draaiend deel: n.v.t.; Deurblad: n.v.t.; Onderdorpel: n.v.t.; Stofdorpel: n.v.t.; Vensterbank: n.v.t.; Ventilatierooster: n.v.t.; Spouwlat: n.v.t.; Rollaag / Latei: n.v.t.; Afwerking dagkant buiten: n.v.t.; Afwerking dagkant binnen: n.v.t.; Zonwering - behuizing: n.v.t.; Zonwering - isolatie: n.v.t.; Glas: Glas - algemeen
CPset_Phasing - Renovation Phase: Bestaand
BaseQuantities - Width: 2485 mm; Volume: 0.183209 m3; NetVolume: 0.183209 m3
Component Quantities - Component, Component Volume (Net): 0.183209 m3; Component, Component Volume (Gross): 0.183209 m3
Name | In | Height (mm) | Perimeter (mm) | Area (m2) | Depth (mm)
32_Deur_h.03 | 00 begane grond | 2367 | 9704 | 5.88199 | 125
32_Deur_h.03 | 00 begane grond | 2367 | 9704 | 5.88199 | 120
4 x 32_Deur_h.03 | 00 begane grond | 2457 | 9884 | 6.10564 | 125
3 x 32_Deur_h.03 | 01 eerste verdieping | 2457 | 9884 | 6.10564 | 125
4 x 32_Deur_h.03 | 01 eerste verdieping | 2367 | 9704 | 5.88199 | 125

# IfcFlowTerminal: Sanitaire wanden 25 (13)
Classification: Sanitair toestel (ARCHICAD Classification); 74.11 SANITAIRE TOESTELLEN; NORMAAL (NL/SfB (4 cijfers))
CPset_Phasing - Renovation Phase: Bestaand
Name | In | Component, Component Volume (Net) (m3) = Component, Component Volume (Gross) (m3)
74_Sanitair toestel_toilet | 00 begane grond | 0.113719
2 x 74_Sanitair toestel_wc-schermen | 00 begane grond | 0.247302
74_Sanitair toestel_toilet | 00 begane grond | 0.0542351
2 x 74_Sanitair toestel_Lift | 01 eerste verdieping | 0.112819
74_Sanitair toestel_Lift | 01 eerste verdieping | 0.053335
2 x 74_Sanitair toestel_Lift | 01 eerste verdieping | 0.0544934
74_Sanitair toestel_wc-schermen | 01 eerste verdieping | 0.0875732
74_Sanitair toestel_wc-schermen | 01 eerste verdieping | 0.0665732
74_Sanitair toestel_Lift | 01 eerste verdieping | 0.319123
74_Sanitair toestel_Lift | 01 eerste verdieping | 0.0613877

# IfcFurnishingElement: Boekenplank 01 25 (14)
Classification: Inrichting (ARCHICAD Classification); 71.11 MEUBILERINGEN (NL/SfB (4 cijfers))
CPset_Phasing - Renovation Phase: Bestaand
Name | In | Component, Component Volume (Net) (m3) = Component, Component Volume (Gross) (m3)
71_Inrichting_G5 | 00 begane grond | 0.120087
71_Inrichting_G1 | 00 begane grond | 0.110936
71_Inrichting_G5 | 00 begane grond | 0.131676
71_Inrichting_G1 | 00 begane grond | 0.126257
71_Inrichting_G4 | 00 begane grond | 0.264029
71_Inrichting_G1 | 01 eerste verdieping | 0.0649814
71_Inrichting_G1 | 01 eerste verdieping | 0.128796
71_Inrichting_G1 | 01 eerste verdieping | 0.24186
71_Inrichting_G1 | 01 eerste verdieping | 0.0669767
71_Inrichting_G3 | 01 eerste verdieping | 0.190777
71_Inrichting_G2 | 01 eerste verdieping | 0.244467
2 x 71_Inrichting_G1 | 01 eerste verdieping | 0.183102
71_Inrichting_G2 | 01 eerste verdieping | 0.163898

# IfcFurnishingElement: Keukenopstelling 25 (17)
Classification: 73.11 KEUKENMEUBILERING (NL/SfB (4 cijfers)); Inrichting (ARCHICAD Classification)
CPset_Phasing - Renovation Phase: Bestaand
Name | In | Component, Component Volume (Net) (m3) = Component, Component Volume (Gross) (m3)
73_Inrichting_P5: opstelplaats keuken door gebruikers | 00 begane grond | 3.34732
73_Inrichting_keuken | 00 begane grond | 1.449
73_Inrichting_P4 | 00 begane grond | 1.39104
73_Inrichting_P3 | 00 begane grond | 0.962961
4 x 73_Inrichting_P1 | 00 begane grond | 0.642
8 x 73_Inrichting_P2 | 01 eerste verdieping | 0.642
73_Inrichting_P6: opstelplaats keuken door gebruikers | 01 eerste verdieping | 1.3482

# IfcMember: Boundary Frame 50 x 180 (16)
In: 00 begane grond
Type - PredefinedType: MULLION
Classification: Vliesgevel - kader (ARCHICAD Classification); Material: ALG - ALGEMEEN
Pset_MemberCommon - FireRating: 0
CPset_Phasing - Renovation Phase: Bestaand
BaseQuantities - CrossSectionArea: 0.009 m2
Name | Slope (deg) | Length (mm) | OuterSurfaceArea (m2) | TotalSurfaceArea (m2) = GrossSurfaceArea (m2) | GrossVolume (m3) = NetVolume (m3) | ALG - ALGEMEEN, Mass (kg) | ALG - ALGEMEEN, Component Volume (Net) (m3) = ALG - ALGEMEEN, Component Volume (Gross) (m3)
2 x _Vliesgevel - kader_Kader-x | 0 | 1105 | 0.5083 | 0.5263 | 0.009945 | 7.18864 | 0.0089858
2 x _Vliesgevel - kader_Kader-x | 90 | 2211.5 | 1.01729 | 1.03529 | 0.0199035 | 14.3765 | 0.0179706
2 x _Vliesgevel - kader_Kader-x | 90 | 1914.5 | 0.88067 | 0.89867 | 0.0172305 | 12.4366 | 0.0155457
2 x _Vliesgevel - kader_Kader-x | 90 | 2360 | 1.0856 | 1.1036 | 0.02124 | 15.3306 | 0.0191632
2 x _Vliesgevel - kader_Kader-x | 90 | 124 | 0.05704 | 0.07504 | 0.001116 | 0.805504 | 0.00100688
2 x _Vliesgevel - kader_Kader-x | 0 | 1105 | 0.5083 | 0.5263 | 0.009945
_Vliesgevel - kader_Kader-x | 0 | 1123.86 | 0.516977 | 0.534977 | 0.0101148 | 7.30061 | 0.00912576
2 x _Vliesgevel - kader_Kader-x | 90 | 140 | 0.0644 | 0.0824 | 0.00126 | 0.92 | 0.00115
_Vliesgevel - kader_Kader-x | 0 | 1123.86 | 0.516977 | 0.534977 | 0.0101148

# IfcMember: IfcMember (57)
Type - ElementType: Rail; PredefinedType: USERDEFINED
Classification: Reling - regel (ARCHICAD Classification)
CPset_Phasing - Renovation Phase: Bestaand
Name | In | Material | GrossVolume (m3) = NetVolume (m3) | Length (mm) | Metaal - RVS, Mass (kg) | Metaal - RVS, Component Volume (Net) (m3) = Metaal - RVS, Component Volume (Gross) (m3)
3 x _Reling - regel_ | 00 begane grond | Hout AFW | 0.00000976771 | 5 | Component Quantities - Hout AFW, Mass: 0.00537224 kg; Hout AFW, Component Volume (Net): 0.00000976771 m3; Hout AFW, Component Volume (Gross): 0.00000976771 m3
4 x _Reling - regel_Handregel-x | 00 begane grond |  | 0.00398384 | 2022.46
4 x _Reling - regel_Handregel-x | 00 begane grond |  | 0.000438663 | 225
9 x _Reling - regel_ | 00 begane grond | Hout AFW | 0.00000976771 | 5
2 x _Reling - regel_Handregel-x | 00 begane grond |  | 0.0057773 | 2931.86
2 x _Reling - regel_Handregel-x | 00 begane grond |  | 0.000448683 | 230
_Reling - regel_Handregel-x | 01 eerste verdieping | Metaal - RVS | 0.00236805 | 7903.46 | 18.7076 | 0.00236805
_Reling - regel_Regel-x | 01 eerste verdieping | Metaal - RVS | 0.00949814 | 7943.1 | 75.0353 | 0.00949814
_Reling - regel_Handregel-x | 01 eerste verdieping | Metaal - RVS | 0.00145752 | 4869.02 | 11.5144 | 0.00145752
_Reling - regel_Regel-x | 01 eerste verdieping | Metaal - RVS | 0.00585682 | 4908.66 | 46.2689 | 0.00585682
_Reling - regel_Handregel-x | 01 eerste verdieping | Metaal - RVS | 0.00184012 | 1471.78 | 14.5369 | 0.00184012
_Reling - regel_ | 01 eerste verdieping | Metaal - RVS | 0.00073589 | 1471.78 | 5.81353 | 0.00073589
_Reling - regel_Regel-x | 01 eerste verdieping | Metaal - RVS | 0.00073589 | 1471.78 | 5.81353 | 0.00073589
_Reling - regel_ | 01 eerste verdieping | Metaal - Staal AFW | 0.00166983 | 5589.9 | Component Quantities - Metaal - Staal AFW, Mass: 13.2751 kg; Metaal - Staal AFW, Component Volume (Net): 0.00166983 m3; Metaal - Staal AFW, Component Volume (Gross): 0.00166983 m3
_Reling - regel_ | 01 eerste verdieping | Metaal - Staal AFW | 0.00662181 | 22118 | Component Quantities - Metaal - Staal AFW, Mass: 52.6434 kg; Metaal - Staal AFW, Component Volume (Net): 0.00662181 m3; Metaal - Staal AFW, Component Volume (Gross): 0.00662181 m3
_Reling - regel_ | 01 eerste verdieping | Metaal - Staal AFW | 0.00166986 | 5590 | Component Quantities - Metaal - Staal AFW, Mass: 13.2754 kg; Metaal - Staal AFW, Component Volume (Net): 0.00166986 m3; Metaal - Staal AFW, Component Volume (Gross): 0.00166986 m3
_Reling - regel_ | 01 eerste verdieping | Metaal - RVS | 0.0014976 | 1497.6 | 11.8311 | 0.0014976
_Reling - regel_Regel-x | 01 eerste verdieping | Metaal - RVS | 0.000748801 | 1497.6 | 5.91553 | 0.000748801
2 x _Reling - regel_ | 01 eerste verdieping | Metaal - RVS | 0.0000025 | 5 | 0.01975 | 0.0000025
_Reling - regel_Handregel-x | 01 eerste verdieping | Hout AFW | 0.00292892 | 2342.64 | Component Quantities - Hout AFW, Mass: 1.61091 kg; Hout AFW, Component Volume (Net): 0.00292892 m3; Hout AFW, Component Volume (Gross): 0.00292892 m3
_Reling - regel_ | 01 eerste verdieping | Metaal - RVS | 0.00117132 | 2342.64 | 9.25341 | 0.00117132
_Reling - regel_Regel-x | 01 eerste verdieping | Metaal - RVS | 0.00187411 | 2342.64 | 14.8055 | 0.00187411
_Reling - regel_ | 01 eerste verdieping | Metaal - RVS | 0.000146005 | 116.779 | 1.15344 | 0.000146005
_Reling - regel_Handregel-x | 01 eerste verdieping | Metaal - RVS | 0.00202167 | 1616.99 | 15.9712 | 0.00202167
_Reling - regel_ | 01 eerste verdieping | Metaal - RVS | 0.00161699 | 1616.99 | 12.7742 | 0.00161699
_Reling - regel_Regel-x | 01 eerste verdieping | Metaal - RVS | 0.000808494 | 1616.99 | 6.3871 | 0.000808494
2 x _Reling - regel_ | 01 eerste verdieping | Metaal - RVS | 0.000005 | 5 | 0.0395 | 0.000005
_Reling - regel_Handregel-x | 01 eerste verdieping | Metaal - RVS | 0.00292892 | 2342.64 | 23.1385 | 0.00292892
_Reling - regel_ | 01 eerste verdieping | Metaal - RVS | 0.00234264 | 2342.64 | 18.5068 | 0.00234264
_Reling - regel_Regel-x | 01 eerste verdieping | Metaal - RVS | 0.00117132 | 2342.64 | 9.25341 | 0.00117132
_Reling - regel_ | 01 eerste verdieping | Metaal - RVS | 0.000178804 | 357.609 | 1.41255 | 0.000178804
_Reling - regel_Handregel-x | 01 eerste verdieping | Metaal - RVS | 0.00255417 | 2049.84 | 20.178 | 0.00255417
_Reling - regel_ | 01 eerste verdieping | Metaal - RVS | 0.00204637 | 2049.84 | 16.1663 | 0.00204637
_Reling - regel_Regel-x | 01 eerste verdieping | Metaal - RVS | 0.000897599 | 1797.62 | 7.09103 | 0.000897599
_Reling - regel_Handregel-x | 01 eerste verdieping | Metaal - RVS | 0.000103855 | 90 | 0.820458 | 0.000103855
_Reling - regel_ | 01 eerste verdieping | Metaal - RVS | 0.0000865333 | 90 | 0.683613 | 0.0000865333
_Reling - regel_Regel-x | 01 eerste verdieping | Metaal - RVS | 0.000045 | 90 | 0.3555 | 0.000045

# IfcMember: IfcMember (135)
In: 01 eerste verdieping
Type - PredefinedType: MEMBER
Classification: Onderdeel (ARCHICAD Classification)
Pset_MemberCommon - FireRating: 0
CPset_Phasing - Renovation Phase: Bestaand
Name | Material | GrossVolume (m3) = NetVolume (m3) | Length (mm)
11 x _Onderdeel_Spijlen-x | Metaal - RVS | 0.000935 | 1225
_Onderdeel_Spijlen-x | Metaal - RVS | 0.0004875 | 975 | Component Quantities - Metaal - RVS, Mass: 3.85125 kg; Metaal - RVS, Component Volume (Net): 0.0004875 m3; Metaal - RVS, Component Volume (Gross): 0.0004875 m3
13 x _Onderdeel_Spijlen-x | Metaal - RVS | 0.0004875 | 975
_Onderdeel_Spijlen-x | Metaal - Staal AFW | 0.0000327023 | 418.5 | Component Quantities - Metaal - Staal AFW, Mass: 0.259983 kg; Metaal - Staal AFW, Component Volume (Net): 0.0000327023 m3; Metaal - Staal AFW, Component Volume (Gross): 0.0000327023 m3
31 x _Onderdeel_Spijlen-x | Metaal - Staal AFW | 0.0000327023 | 418.5
_Onderdeel_Spijlen-x | Metaal - RVS | 0.00043875 | 877.5 | Component Quantities - Metaal - RVS, Mass: 3.46612 kg; Metaal - RVS, Component Volume (Net): 0.00043875 m3; Metaal - RVS, Component Volume (Gross): 0.00043875 m3
13 x _Onderdeel_Spijlen-x | Metaal - RVS | 0.00043875 | 877.5
_Onderdeel_Spijlen-x | Metaal - RVS | 0.00065 | 1307.88 | Component Quantities - Metaal - RVS, Mass: 5.135 kg; Metaal - RVS, Component Volume (Net): 0.00065 m3; Metaal - RVS, Component Volume (Gross): 0.00065 m3
17 x _Onderdeel_Spijlen-x | Metaal - RVS | 0.00065 | 1307.88
_Onderdeel_Spijlen-x | Metaal - RVS | 0.00063875 | 1285.42 | Component Quantities - Metaal - RVS, Mass: 5.04612 kg; Metaal - RVS, Component Volume (Net): 0.00063875 m3; Metaal - RVS, Component Volume (Gross): 0.00063875 m3
11 x _Onderdeel_Spijlen-x | Metaal - RVS | 0.00063875 | 1285.42
_Onderdeel_Spijlen-x | Metaal - RVS | 0.00048875 | 985.38 | Component Quantities - Metaal - RVS, Mass: 3.86112 kg; Metaal - RVS, Component Volume (Net): 0.00048875 m3; Metaal - RVS, Component Volume (Gross): 0.00048875 m3
17 x _Onderdeel_Spijlen-x | Metaal - RVS | 0.00048875 | 985.38
_Onderdeel_Spijlen-x | Metaal - RVS | 0.00064875 | 1305.38 | Component Quantities - Metaal - RVS, Mass: 5.12512 kg; Metaal - RVS, Component Volume (Net): 0.00064875 m3; Metaal - RVS, Component Volume (Gross): 0.00064875 m3
13 x _Onderdeel_Spijlen-x | Metaal - RVS | 0.00064875 | 1305.38
_Onderdeel_Spijlen-x | Metaal - RVS | 0.000574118 | 1152.18 | Component Quantities - Metaal - RVS, Mass: 4.53553 kg; Metaal - RVS, Component Volume (Net): 0.000574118 m3; Metaal - RVS, Component Volume (Gross): 0.000574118 m3
_Onderdeel_Spijlen-x | Metaal - RVS | 0.000611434 | 1226.81 | Component Quantities - Metaal - RVS, Mass: 4.83033 kg; Metaal - RVS, Component Volume (Net): 0.000611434 m3; Metaal - RVS, Component Volume (Gross): 0.000611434 m3

# IfcMember: IfcMember (20)
In: 01 eerste verdieping
Type - PredefinedType: POST
Classification: Reling - baluster (ARCHICAD Classification)
CPset_Phasing - Renovation Phase: Bestaand
Name | Material | GrossVolume (m3) = NetVolume (m3) | Length (mm)
_Reling - baluster_ | Metaal - RVS | 0.000935 | 1225 | Component Quantities - Metaal - RVS, Mass: 7.3865 kg; Metaal - RVS, Component Volume (Net): 0.000935 m3; Metaal - RVS, Component Volume (Gross): 0.000935 m3
2 x _Reling - baluster_ | Metaal - RVS | 0.000935 | 1225
3 x _Reling - baluster_ | Metaal - RVS | 0.00049 | 980 | Component Quantities - Metaal - RVS, Mass: 3.871 kg; Metaal - RVS, Component Volume (Net): 0.00049 m3; Metaal - RVS, Component Volume (Gross): 0.00049 m3
2 x _Reling - baluster_ | Metaal - RVS | 0.00049 | 980
_Reling - baluster_ | Metaal - Staal AFW | 0.0000332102 | 425 | Component Quantities - Metaal - Staal AFW, Mass: 0.264021 kg; Metaal - Staal AFW, Component Volume (Net): 0.0000332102 m3; Metaal - Staal AFW, Component Volume (Gross): 0.0000332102 m3
3 x _Reling - baluster_ | Metaal - Staal AFW | 0.0000332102 | 425
_Reling - baluster_ | Metaal - RVS | 0.00065 | 1307.88 | Component Quantities - Metaal - RVS, Mass: 5.135 kg; Metaal - RVS, Component Volume (Net): 0.00065 m3; Metaal - RVS, Component Volume (Gross): 0.00065 m3
_Reling - baluster_ | Metaal - RVS | 0.00065 | 1307.88
_Reling - baluster_ | Metaal - RVS | 0.00064 | 1287.92 | Component Quantities - Metaal - RVS, Mass: 5.056 kg; Metaal - RVS, Component Volume (Net): 0.00064 m3; Metaal - RVS, Component Volume (Gross): 0.00064 m3
_Reling - baluster_ | Metaal - RVS | 0.00049 | 987.919 | Component Quantities - Metaal - RVS, Mass: 3.871 kg; Metaal - RVS, Component Volume (Net): 0.00049 m3; Metaal - RVS, Component Volume (Gross): 0.00049 m3
_Reling - baluster_ | Metaal - RVS | 0.00058 | 1167.88 | Component Quantities - Metaal - RVS, Mass: 4.582 kg; Metaal - RVS, Component Volume (Net): 0.00058 m3; Metaal - RVS, Component Volume (Gross): 0.00058 m3
_Reling - baluster_ | Metaal - RVS | 0.00058 | 1167.88
_Reling - baluster_ | Metaal - RVS | 0.00049 | 987.88 | Component Quantities - Metaal - RVS, Mass: 3.871 kg; Metaal - RVS, Component Volume (Net): 0.00049 m3; Metaal - RVS, Component Volume (Gross): 0.00049 m3
_Reling - baluster_ | Metaal - RVS | 0.00049 | 983.467 | Component Quantities - Metaal - RVS, Mass: 3.871 kg; Metaal - RVS, Component Volume (Net): 0.00049 m3; Metaal - RVS, Component Volume (Gross): 0.00049 m3

# IfcMember: Mullion Frame 50 x 180 (10)
In: 00 begane grond
Type - PredefinedType: MULLION
Classification: Vliesgevel - kader (ARCHICAD Classification); Material: ALG - ALGEMEEN
Pset_MemberCommon - Slope: 90 deg; FireRating: 0
CPset_Phasing - Renovation Phase: Bestaand
BaseQuantities - CrossSectionArea: 0.009 m2
Name | Length (mm) | OuterSurfaceArea (m2) | TotalSurfaceArea (m2) = GrossSurfaceArea (m2) | GrossVolume (m3) = NetVolume (m3)
_Vliesgevel - kader_Kader-x | 1914.5 | 0.88067 | 0.89867 | 0.0172305 | Component Quantities - ALG - ALGEMEEN, Mass: 11.0888 kg; ALG - ALGEMEEN, Component Volume (Net): 0.013861 m3; ALG - ALGEMEEN, Component Volume (Gross): 0.013861 m3
_Vliesgevel - kader_Kader-x | 124 | 0.05704 | 0.07504 | 0.001116 | Component Quantities - ALG - ALGEMEEN, Mass: 0.718208 kg; ALG - ALGEMEEN, Component Volume (Net): 0.00089776 m3; ALG - ALGEMEEN, Component Volume (Gross): 0.00089776 m3
_Vliesgevel - kader_Kader-x | 2186.5 | 1.00579 | 1.02379 | 0.0196785 | Component Quantities - ALG - ALGEMEEN, Mass: 12.6642 kg; ALG - ALGEMEEN, Component Volume (Net): 0.0158303 m3; ALG - ALGEMEEN, Component Volume (Gross): 0.0158303 m3
_Vliesgevel - kader_Kader-x | 124 | 0.05704 | 0.07504 | 0.001116
_Vliesgevel - kader_Kader-x | 115 | 0.0529 | 0.0709 | 0.001035 | Component Quantities - ALG - ALGEMEEN, Mass: 0.66608 kg; ALG - ALGEMEEN, Component Volume (Net): 0.0008326 m3; ALG - ALGEMEEN, Component Volume (Gross): 0.0008326 m3
_Vliesgevel - kader_Kader-x | 2360 | 1.0856 | 1.1036 | 0.02124 | Component Quantities - ALG - ALGEMEEN, Mass: 13.6691 kg; ALG - ALGEMEEN, Component Volume (Net): 0.0170864 m3; ALG - ALGEMEEN, Component Volume (Gross): 0.0170864 m3
_Vliesgevel - kader_Kader-x | 2360 | 1.0856 | 1.1036 | 0.02124
_Vliesgevel - kader_Kader-x | 1914.5 | 0.88067 | 0.89867 | 0.0172305
_Vliesgevel - kader_Kader-x | 115 | 0.0529 | 0.0709 | 0.001035
_Vliesgevel - kader_Kader-x | 2186.5 | 1.00579 | 1.02379 | 0.0196785

# IfcMember: Transom Frame 50 x 180 (12)
In: 00 begane grond
Type - PredefinedType: MULLION
Classification: Vliesgevel - kader (ARCHICAD Classification); Material: ALG - ALGEMEEN
Pset_MemberCommon - Slope: 0 deg; FireRating: 0
CPset_Phasing - Renovation Phase: Bestaand
BaseQuantities - CrossSectionArea: 0.009 m2
Name | Length (mm) | OuterSurfaceArea (m2) | TotalSurfaceArea (m2) = GrossSurfaceArea (m2) | GrossVolume (m3) = NetVolume (m3)
_Vliesgevel - kader_Kader-x | 1073.86 | 0.493977 | 0.511977 | 0.00966476 | Component Quantities - ALG - ALGEMEEN, Mass: 6.21981 kg; ALG - ALGEMEEN, Component Volume (Net): 0.00777477 m3; ALG - ALGEMEEN, Component Volume (Gross): 0.00777477 m3
2 x _Vliesgevel - kader_Kader-x | 1055 | 0.4853 | 0.5033 | 0.009495 | Component Quantities - ALG - ALGEMEEN, Mass: 6.11056 kg; ALG - ALGEMEEN, Component Volume (Net): 0.0076382 m3; ALG - ALGEMEEN, Component Volume (Gross): 0.0076382 m3
6 x _Vliesgevel - kader_Kader-x | 1055 | 0.4853 | 0.5033 | 0.009495
3 x _Vliesgevel - kader_Kader-x | 1073.86 | 0.493977 | 0.511977 | 0.00966476

# IfcOpeningElement (188)
Name | In | Depth (mm) | Height (mm) | Width (mm) | Area (m2) | Volume (m3)
__Leeg | 00 begane grond | 33 | 2350 | 1779.98 | 4.18296 | 0
__Leeg | 00 begane grond | 100 | 2367 | 1048 | 2.48062 | 0
32_Deur_r.01 | 00 begane grond | 100 | 2729 | 2560 | 6.98624 | 0
__Leeg | 00 begane grond | 150 | 2367 | 1034 | 2.44748 | 0
__Leeg | 00 begane grond | 100 | 2457 | 3056.96 | 7.51094 | 0
32_Deur_h.08 | 00 begane grond | 100 | 2457 | 1977 | 4.85749 | 0.122843
32_Deur_h.01d | 00 begane grond | 150 | 2367 | 1034 | 2.44748 | 0.113136
32_Deur_h.01a | 00 begane grond | 150 | 2367 | 1034 | 2.44748 | 0.125832
32_Deur_r.01 | 00 begane grond | 100 | 3501.31 | 2560 | 8.96334 | 0
2 x 31_Deur_A.02a | 00 begane grond | 280 | 2875 | 2010 | 5.77875 | 0.122388
32_Deur_h.12 | 00 begane grond | 150 | 2367 | 1934 | 4.57778 | 0.215507
2 x 31_Raam_A.09 | 00 begane grond | 100 | 3195 | 1000 | 3.195 | 0.0363588
31_Deur_H.14 | 00 begane grond | 280 | 2717.5 | 1770 | 4.80997 | 0.251416
31_Raam_A.01b | 00 begane grond | 280 | 2875 | 2010 | 5.77875 | 0.0678532
3 x 31_Raam_A.03 | 00 begane grond | 280 | 2875 | 1010 | 2.90375 | 0.0455377
31_Raam_A.01b | 00 begane grond | 280 | 2875 | 2010 | 5.77875 | 0.0693447
5 x 31_Raam_A.03a | 00 begane grond | 280 | 2875 | 1010 | 2.90375 | 0.0345965
31_Deur_A.04 | 00 begane grond | 280 | 2875 | 1062 | 3.05325 | 0.0632717
2 x 31_Raam_A.01a | 00 begane grond | 280 | 2891 | 2010 | 5.81091 | 0.0804327
2 x 31_Deur_A.02 | 00 begane grond | 280 | 2875 | 2010 | 5.77875 | 0.124087
31_Raam_A.01a | 00 begane grond | 280 | 2875 | 2010 | 5.77875 | 0.0804327
31_Deur_A.08 | 00 begane grond | 280 | 2875 | 2010 | 5.77875 | 0.118284
31_Deur_A.06a | 00 begane grond | 280 | 2855 | 2106 | 6.01263 | 0.117347
__Leeg | 00 begane grond | 33 | 1040 | 894.966 | 0.930764 | 0
2 x __Leeg | 00 begane grond | 33 | 1040 | 920 | 0.9568 | 0
__Leeg | 00 begane grond | 33 | 1040 | 919.966 | 0.956764 | 0
32_Deur_h.01a | 00 begane grond | 33 | 2350 | 1034 | 2.4299 | 0.125832
_Lege opening_Opening-x | 00 begane grond | 194.5 | 842 | 842 | 0.708964 | 0.0942922 | Classification: Lege opening (ARCHICAD Classification); CPset_Phasing - Renovation Phase: Bestaand
8 x 32_Deur_h.01a | 00 begane grond | 100 | 2367 | 1034 | 2.44748 | 0.125883
5 x 32_Deur_h.01c | 00 begane grond | 100 | 2367 | 1034 | 2.44748 | 0.0777052
32_Deur_h.01c | 00 begane grond | 100 | 2367 | 1034 | 2.44748 | 0.0725356
32_Deur_h.08 | 00 begane grond | 100 | 2367 | 1845 | 4.36712 | 0.119126
32_Raam_h.11 | 00 begane grond | 125 | 2367 | 815 | 1.92911 | 0.0253228
32_Deur_h.03 | 00 begane grond | 125 | 2367 | 2485 | 5.88199 | 0.183209
_Lege opening_Opening-x | 00 begane grond | 125 | 3865 | 5970 | 23.074 | 2.38949 | Classification: Lege opening (ARCHICAD Classification); CPset_Phasing - Renovation Phase: Bestaand
4 x 32_Deur_h.01b | 00 begane grond | 125 | 2367 | 1034 | 2.44748 | 0.124964
4 x 32_Deur_h.01c | 00 begane grond | 125 | 2367 | 1034 | 2.44748 | 0.0777052
_Lege opening_Opening-x | 00 begane grond | 125 | 842 | 842 | 0.708964 | 0.0886205 | Classification: Lege opening (ARCHICAD Classification); CPset_Phasing - Renovation Phase: Bestaand
32_Raam_h.11 | 00 begane grond | 120 | 2367 | 815 | 1.92911 | 0.0253228
32_Deur_h.03 | 00 begane grond | 120 | 2367 | 2485 | 5.88199 | 0.183209
2 x 32_Deur_h.08 | 00 begane grond | 100 | 2367 | 1977 | 4.67956 | 0.122843
32_Deur_h.08 | 00 begane grond | 100 | 2367 | 1790 | 4.23693 | 0.112897
32_Deur_h.10 | 00 begane grond | 100 | 2367 | 1760 | 4.16592 | 0.19822
2 x 32_Raam_h.22 | 00 begane grond | 125 | 2367 | 1000 | 2.367 | 0.0268598
4 x 32_Deur_h.03 | 00 begane grond | 125 | 2457 | 2485 | 6.10564 | 0.183209
2 x 32_Raam_h.05 | 00 begane grond | 125 | 1167 | 1600 | 1.8672 | 0.021875
32_Raam_h.09 | 00 begane grond | 100 | 2367 | 2157.68 | 5.10723 | 0.0457537
32_Raam_h.07 | 00 begane grond | 100 | 2367 | 3017.62 | 7.1427 | 0.0621739
32_Deur_h.08 | 00 begane grond | 100 | 2367 | 1790 | 4.23693 | 0.117577
2 x 32_Deur_h.01d | 00 begane grond | 100 | 2367 | 1034 | 2.44748 | 0.113187
_Lege opening_Opening-x | 00 begane grond | 100 | 842 | 842 | 0.708964 | 0.0708964 | Classification: Lege opening (ARCHICAD Classification); CPset_Phasing - Renovation Phase: Bestaand
5 x 31_Raam_A.03b | 00 begane grond | 280 | 2875 | 1010 | 2.90375 | 0.0453827
2 x 31_Deur_A.02a | 00 begane grond | 280 | 2875 | 2010 | 5.77875 | 0.123879
32_Deur_Roldeur | 00 begane grond | 100 | 2200 | 1362 | 2.9964 | 0
32_Deur_Roldeur | 00 begane grond | 100 | 2290 | 1362 | 3.11898 | 0
22_Schuifwand_P-03 | 00 begane grond | 80 | 2292 | 1240 | 2.84208 | 0.0111744
2 x 22_Schuifwand_P-02 | 00 begane grond | 80 | 2292 | 1240 | 2.84208 | 0.0111744
32_Deur_P.01 | 00 begane grond | 80 | 2300 | 920 | 2.116 | 0.08248
2 x 32_Deur_L | 00 begane grond | 80 | 2000 | 945 | 1.89 | 0.047496
32_Deur_h.13 | 00 begane grond | 125 | 2367 | 1625 | 3.84638 | 0.151967
32_Deur_h.15 | 00 begane grond | 125 | 2367 | 2757 | 6.52582 | 0.186315
4 x 31_Raam_A.01c | 00 begane grond | 280 | 2875 | 2010 | 5.77875 | 0.069137
31_Raam_A.03c | 00 begane grond | 280 | 2875 | 1010 | 2.90375 | 0.0344911
31_Deur_A.05 | 00 begane grond | 280 | 4312.5 | 2010 | 8.66812 | 0.307614
31_Raam_A.09 | 00 begane grond | 100 | 3190 | 1000 | 3.19 | 0.0363335
31_Raam_A.09 | 00 begane grond | 100 | 3195 | 999.986 | 3.19495 | 0.0363588
31_Deur_H.14 | 00 begane grond | 100 | 1410 | 1826 | 2.57466 | 0.250947
_Lege opening_Opening-x | 00 begane grond | 100 | 3865 | 5970 | 23.074 | 1.91159 | Classification: Lege opening (ARCHICAD Classification); CPset_Phasing - Renovation Phase: Bestaand
32_Deur_h.01c | 00 begane grond | 125 | 2367 | 1034 | 2.44748 | 0.0750092
3 x 31_Raam_A.14 | 01 eerste verdieping | 280 | 2912.5 | 2010 | 5.85412 | 0.0767996
3 x 31_Deur_A.13 | 01 eerste verdieping | 280 | 2912.5 | 2010 | 5.85412 | 0.139524
32_Raam_h.16 | 01 eerste verdieping | 150 | 1760 | 6989 | 12.3006 | 0.206119
2 x 32_Deur_Roldeur | 01 eerste verdieping | 100 | 2290 | 1362 | 3.11898 | 0
32_Deur_s.01 | 01 eerste verdieping | 150 | 2190 | 999.9 | 2.18978 | 0.084
13 x 31_Raam_A.11 | 01 eerste verdieping | 280 | 2137.5 | 1010 | 2.15888 | 0.0374591
4 x 31_Raam_A.10 | 01 eerste verdieping | 280 | 2137.5 | 2010 | 4.29638 | 0.0581424
31_Raam_A.10 | 01 eerste verdieping | 280 | 2137.5 | 2010 | 4.29638 | 0.0561401
3 x 31_Raam_A.10a | 01 eerste verdieping | 280 | 2137.5 | 2010 | 4.29638 | 0.0669627
4 x 31_Raam_A.11b | 01 eerste verdieping | 280 | 2137.5 | 1010 | 2.15888 | 0.0284285
31_Raam_A.15 | 01 eerste verdieping | 280 | 1887.5 | 1010 | 1.90638 | 0.0190723
3 x 32_Deur_h.03 | 01 eerste verdieping | 125 | 2457 | 2485 | 6.10564 | 0.183209
3 x 32_Deur_h.01d | 01 eerste verdieping | 100 | 2367 | 1034 | 2.44748 | 0.113187
32_Raam_h.06 | 01 eerste verdieping | 125 | 1167 | 1000 | 1.167 | 0.0168902
6 x 32_Raam_h.05 | 01 eerste verdieping | 125 | 1167 | 1400 | 1.6338 | 0.0202134
32_Deur_h.13 | 01 eerste verdieping | 100 | 2367 | 1625 | 3.84638 | 0.151967
_Lege opening_Opening-x | 01 eerste verdieping | 100 | 842 | 842 | 0.708964 | 0.0708964 | Classification: Lege opening (ARCHICAD Classification); CPset_Phasing - Renovation Phase: Bestaand
4 x 32_Deur_h.03 | 01 eerste verdieping | 125 | 2367 | 2485 | 5.88199 | 0.183209
4 x 32_Deur_h.01a | 01 eerste verdieping | 100 | 2367 | 1034 | 2.44748 | 0.125883
32_Deur_h.13 | 01 eerste verdieping | 125 | 2367 | 1635.67 | 3.87164 | 0.103952
32_Deur_h.01c | 01 eerste verdieping | 100 | 2367 | 1034 | 2.44748 | 0.0777052
32_Raam_h.21 | 01 eerste verdieping | 125 | 2367 | 1693.5 | 4.00851 | 0.0326214
2 x 32_Deur_h.18 | 01 eerste verdieping | 125 | 2367 | 1987 | 4.70323 | 0.109319
_Lege opening_Opening-x | 01 eerste verdieping | 125 | 842 | 842 | 0.708964 | 0.0886205 | Classification: Lege opening (ARCHICAD Classification); CPset_Phasing - Renovation Phase: Bestaand
32_Deur_h.01d | 01 eerste verdieping | 100 | 2367 | 1030.09 | 2.43823 | 0.113187
32_Raam_h.17 | 01 eerste verdieping | 150 | 1760 | 1095 | 1.9272 | 0.041566
32_Raam_h.19a | 01 eerste verdieping | 100 | 1367 | 2553.5 | 3.49063 | 0.0766779
32_Deur_h.19b | 01 eerste verdieping | 100 | 2367 | 2252.5 | 5.33167 | 0.134147
2 x 32_Deur_L | 01 eerste verdieping | 80 | 2000 | 945 | 1.89 | 0.047496
31_Raam_A.12 | 01 eerste verdieping | 280 | 1887.5 | 2783.84 | 5.2545 | 0.0603661
32_Deur_h.20 | 01 eerste verdieping | 100 | 2367 | 1689.36 | 3.99872 | 0.15295
32_Deur_A.16 | 02 dak | 100 | 1824.09 | 1127 | 2.05575 | 0.0494891

# IfcPlate: Distinct Panel 1095 x 114 x 33 (2)
In: 00 begane grond
Type - PredefinedType: CURTAIN_PANEL
Classification: Vliesgevel - paneel (ARCHICAD Classification)
Pset_PlateCommon - FireRating: 0
CPset_Phasing - Renovation Phase: Bestaand
BaseQuantities - Width: 1055 mm; Perimeter: 2258 mm; GrossArea: 0.12483 m2; NetArea: 0.07807 m2; GrossVolume: 0.00411939 m3; NetVolume: 0.00257631 m3

# IfcPlate: Distinct Panel 1095 x 130 x 33 (2)
In: 00 begane grond
Type - PredefinedType: CURTAIN_PANEL
Classification: Vliesgevel - paneel (ARCHICAD Classification)
Pset_PlateCommon - FireRating: 0
CPset_Phasing - Renovation Phase: Bestaand
BaseQuantities - Width: 1055 mm; Perimeter: 2290 mm; GrossArea: 0.14235 m2; NetArea: 0.09495 m2; GrossVolume: 0.00469755 m3; NetVolume: 0.00313335 m3

# IfcPlate: Distinct Panel 1114 x 114 x 33, _Vliesgevel - paneel_Paneel-x
In: 00 begane grond
Type - PredefinedType: CURTAIN_PANEL
Classification: Vliesgevel - paneel (ARCHICAD Classification)
Pset_PlateCommon - FireRating: 0
CPset_Phasing - Renovation Phase: Bestaand
BaseQuantities - Width: 1073.86 mm; Perimeter: 2295.73 mm; GrossArea: 0.12698 m2; NetArea: 0.0794658 m2; GrossVolume: 0.00419035 m3; NetVolume: 0.00262237 m3

# IfcPlate: Distinct Panel 1114 x 130 x 33, _Vliesgevel - paneel_Paneel-x
In: 00 begane grond
Type - PredefinedType: CURTAIN_PANEL
Classification: Vliesgevel - paneel (ARCHICAD Classification)
Pset_PlateCommon - FireRating: 0
CPset_Phasing - Renovation Phase: Bestaand
BaseQuantities - Width: 1073.86 mm; Perimeter: 2327.73 mm; GrossArea: 0.144802 m2; NetArea: 0.0966476 m2; GrossVolume: 0.00477847 m3; NetVolume: 0.00318937 m3

# IfcPlate: Main Panel 1095 x 1904 x 33 (2)
In: 00 begane grond
Type - PredefinedType: CURTAIN_PANEL
Classification: Vliesgevel - paneel (ARCHICAD Classification); Material: Glas
Pset_PlateCommon - FireRating: 0
CPset_Phasing - Renovation Phase: Bestaand
BaseQuantities - Width: 1055 mm; Perimeter: 5839 mm; GrossArea: 2.08543 m2; NetArea: 1.96705 m2; GrossVolume: 0.0688191 m3; NetVolume: 0.0649126 m3
Component Quantities - Glas, Mass: 150.026 kg; Glas, Component Volume (Net): 0.0688191 m3; Glas, Component Volume (Gross): 0.0688191 m3

# IfcPlate: Main Panel 1095 x 2201 x 33 (2)
In: 00 begane grond
Type - PredefinedType: CURTAIN_PANEL
Classification: Vliesgevel - paneel (ARCHICAD Classification); Material: Glas
Pset_PlateCommon - FireRating: 0
CPset_Phasing - Renovation Phase: Bestaand
BaseQuantities - Width: 1055 mm; Perimeter: 6433 mm; GrossArea: 2.41064 m2; NetArea: 2.28038 m2; GrossVolume: 0.0795512 m3; NetVolume: 0.0752526 m3
Component Quantities - Glas, Mass: 173.422 kg; Glas, Component Volume (Net): 0.0795512 m3; Glas, Component Volume (Gross): 0.0795512 m3

# IfcPlate: Main Panel 1095 x 2350 x 33 (2)
In: 00 begane grond
Type - PredefinedType: CURTAIN_PANEL
Classification: Vliesgevel - paneel (ARCHICAD Classification); Material: Glas
Pset_PlateCommon - FireRating: 0
CPset_Phasing - Renovation Phase: Bestaand
BaseQuantities - Width: 1055 mm; Perimeter: 6730 mm; GrossArea: 2.57325 m2; NetArea: 2.43705 m2; GrossVolume: 0.0849172 m3
Component Quantities - Glas, Mass: 185.12 kg; Glas, Component Volume (Net): 0.0849172 m3; Glas, Component Volume (Gross): 0.0849172 m3
Name | NetVolume (m3)
_Vliesgevel - paneel_Paneel-x | 0.0804227
_Vliesgevel - paneel_Paneel-x | 0.0804226

# IfcPlate: Main Panel 1114 x 1904 x 33, _Vliesgevel - paneel_Paneel-x
In: 00 begane grond
Type - PredefinedType: CURTAIN_PANEL
Classification: Vliesgevel - paneel (ARCHICAD Classification); Material: Glas
Pset_PlateCommon - FireRating: 0
CPset_Phasing - Renovation Phase: Bestaand
BaseQuantities - Width: 1073.86 mm; Perimeter: 5876.73 mm; GrossArea: 2.12135 m2; NetArea: 2.00222 m2; GrossVolume: 0.0700046 m3; NetVolume: 0.0660732 m3
Component Quantities - Glas, Mass: 152.61 kg; Glas, Component Volume (Net): 0.0700046 m3; Glas, Component Volume (Gross): 0.0700046 m3

# IfcPlate: Main Panel 1114 x 2201 x 33, _Vliesgevel - paneel_Paneel-x
In: 00 begane grond
Type - PredefinedType: CURTAIN_PANEL
Classification: Vliesgevel - paneel (ARCHICAD Classification); Material: Glas
Pset_PlateCommon - FireRating: 0
CPset_Phasing - Renovation Phase: Bestaand
BaseQuantities - Width: 1073.86 mm; Perimeter: 6470.73 mm; GrossArea: 2.45217 m2; NetArea: 2.32115 m2; GrossVolume: 0.0809216 m3; NetVolume: 0.0765981 m3
Component Quantities - Glas, Mass: 176.409 kg; Glas, Component Volume (Net): 0.0809216 m3; Glas, Component Volume (Gross): 0.0809216 m3

# IfcPlate: Main Panel 1114 x 2350 x 33, _Vliesgevel - paneel_Paneel-x
In: 00 begane grond
Type - PredefinedType: CURTAIN_PANEL
Classification: Vliesgevel - paneel (ARCHICAD Classification); Material: Glas
Pset_PlateCommon - FireRating: 0
CPset_Phasing - Renovation Phase: Bestaand
BaseQuantities - Width: 1073.86 mm; Perimeter: 6767.73 mm; GrossArea: 2.61758 m2; NetArea: 2.48062 m2; GrossVolume: 0.08638 m3; NetVolume: 0.0818605 m3
Component Quantities - Glas, Mass: 188.308 kg; Glas, Component Volume (Net): 0.08638 m3; Glas, Component Volume (Gross): 0.08638 m3

# IfcRailing: 34 Viderand 146 x 2002 (2)
In: 01 eerste verdieping
Type - PredefinedType: BALUSTRADE
Classification: Balustrade (ARCHICAD Classification); 34.11 BINNENBALUSTRADES (NL/SfB (4 cijfers))
CPset_Phasing - Renovation Phase: Bestaand
Pset_RailingCommon - IsExternal: no
Name | NetVolume (m3)
 | 0.229537
 | 0.372951

# IfcRailing: Railing Type (14)
CPset_Phasing - Renovation Phase: Bestaand
Pset_RailingCommon - IsExternal: no
Name | In | Classification | GrossVolume (m3) = NetVolume (m3) | Length (mm)
4 x _Reling_Reling-x | 00 begane grond | Reling (ARCHICAD Classification) | 0.00444204 | 2428.71
2 x _Reling_Reling-x | 00 begane grond | Reling (ARCHICAD Classification) | 0.00624552 | 3343.11
34_Reling_Reling vide | 01 eerste verdieping | Reling (ARCHICAD Classification); 34.21 BINNENLEUNINGEN (NL/SfB (4 cijfers)) | 0.0322705 | 12739.8
34_Reling_Trapleuning | 01 eerste verdieping | Reling (ARCHICAD Classification); 34.21 BINNENLEUNINGEN (NL/SfB (4 cijfers)) | 0.0111169 | 1471.78
34_Reling_Reling vide | 01 eerste verdieping | Reling (ARCHICAD Classification); 34.21 BINNENLEUNINGEN (NL/SfB (4 cijfers)) | 0.0111408 | 32997.9
34_Reling_Trapleuning | 01 eerste verdieping | Reling (ARCHICAD Classification); 34.21 BINNENLEUNINGEN (NL/SfB (4 cijfers)) | 0.0093689 | 1497.6
34_Reling_Trapleuning | 01 eerste verdieping | Reling (ARCHICAD Classification); 34.21 BINNENLEUNINGEN (NL/SfB (4 cijfers)) | 0.0189793 | 2342.64
34_Reling_Trapleuning | 01 eerste verdieping | Reling (ARCHICAD Classification); 34.21 BINNENLEUNINGEN (NL/SfB (4 cijfers)) | 0.0133882 | 1616.99
34_Reling_Trapleuning | 01 eerste verdieping | Reling (ARCHICAD Classification); 34.21 BINNENLEUNINGEN (NL/SfB (4 cijfers)) | 0.0193393 | 2342.64
34_Reling_Trapleuning | 01 eerste verdieping | Reling (ARCHICAD Classification); 34.21 BINNENLEUNINGEN (NL/SfB (4 cijfers)) | 0.0176504 | 2139.84

# IfcRoof (5)
In: 02 dak
Classification: Dak (ARCHICAD Classification); 27.21 VLAKKE DAKEN (NL/SfB (4 cijfers))
Pset_RoofCommon - FireRating: 0; IsExternal: yes
CPset_Phasing - Renovation Phase: Bestaand
Name | TotalArea (m2) = TotalSurfaceArea (m2)
27_Dak_Dak | 352.709
2 x 27_Dak_Dak | 133.097
27_Dak_Dak | 307.259
27_Dak_Dak | 332.674

# IfcSlab: 43 Vloerafwerking 90, 23_Vloer_Vloer ihw gestort
In: -1 fundering
Classification: Vloer (ARCHICAD Classification); 23.21 VRIJDRAGENDE VLOEREN (NL/SfB (4 cijfers))
Pset_SlabCommon - FireRating: 0; LoadBearing: yes; IsExternal: yes
CPset_Phasing - Renovation Phase: Bestaand
BaseQuantities - Width: 90 mm; Perimeter: 41218.5 mm; GrossArea: 101.199 m2; NetArea: 100.07 m2; GrossVolume: 9.11051 m3; NetVolume: 9.00891 m3

# IfcSlab: Steen - Keramisch 50, 23_Vloer_Bestrating
In: 00 begane grond
Classification: Vloer (ARCHICAD Classification); 23.10 ALGEMEEN (NL/SfB (4 cijfers)); Material: Steen - Keramisch
Pset_SlabCommon - FireRating: 0; LoadBearing: no; IsExternal: no
CPset_Phasing - Renovation Phase: Bestaand
BaseQuantities - Width: 50 mm; Perimeter: 16128 mm; GrossArea: 16.1468 m2; NetArea: 15.898 m2; GrossVolume: 0.807339 m3; NetVolume: 0.7949 m3
Component Quantities - Steen - Keramisch, Mass: 1271.84 kg; Steen - Keramisch, Projected Component Area (Net): 15.898 m2; Steen - Keramisch, Projected Component Area (Gross): 15.898 m2; Steen - Keramisch, Component Thickness: 50 mm; Steen - Keramisch, Component Volume (Net): 0.7949 m3; Steen - Keramisch, Component Volume (Gross): 0.7949 m3

# IfcStair (3)
In: 00 begane grond
Classification: Trap (ARCHICAD Classification); 24.10 ALGEMEEN (NL/SfB (4 cijfers))
Pset_StairCommon - FireRating: 0; IsExternal: no
CPset_Phasing - Renovation Phase: Bestaand
Name | NetVolume (m3)
24_Trap_Traptreden beton | 1.25242
24_Trap_Traptreden beton | 1.40527
24_Trap_Traptreden beton | 1.07683

# IfcTransportElement: ALG - BINNENAFWERKING 80 (4)
Type - PredefinedType: ELEVATOR
Classification: Lift (ARCHICAD Classification); 66.12 HYDRAULISCHE LIFTEN (NL/SfB (4 cijfers)); Material: ALG - BINNENAFWERKING
CPset_Phasing - Renovation Phase: Bestaand
Component Quantities - ALG - BINNENAFWERKING, Component Thickness: 80 mm; ALG - BINNENAFWERKING, Rectangular Component Width: 80 mm
Name | In | ALG - BINNENAFWERKING, Mass (kg) | ALG - BINNENAFWERKING, Projected Component Area (Net) (m2) | ALG - BINNENAFWERKING, Projected Component Area (Gross) (m2) | ALG - BINNENAFWERKING, Rectangular Component Height (mm) | ALG - BINNENAFWERKING, Component Cross Section Area (m2) | ALG - BINNENAFWERKING, Component Volume (Net) (m3) | ALG - BINNENAFWERKING, Component Volume (Gross) (m3)
2 x 66_Lift_liftvoorwand | 00 begane grond | 70.8096 | 1.1064 | 2.9964 | 2200 | 0.176 | 0.088512 | 0.239712
2 x 66_Lift_liftvoorwand | 01 eerste verdieping | 79.5264 | 1.2426 | 3.1326 | 2300 | 0.184 | 0.099408 | 0.250608

# IfcTransportElement: Lift 25, 66_Lift_Lift
In: 00 begane grond
Type - PredefinedType: ELEVATOR
Classification: Lift (ARCHICAD Classification); 66.11 ELEKTRISCHE LIFTEN (NL/SfB (4 cijfers))
CPset_Phasing - Renovation Phase: Bestaand

# IfcWall: 21 MW accent 280 (23)
Classification: Wand (ARCHICAD Classification); 21.12 SPOUWWANDEN (NL/SfB (4 cijfers))
Pset_WallCommon - FireRating: 0; SurfaceSpreadOfFlame: 0; LoadBearing: no; IsExternal: yes
CPset_Phasing - Renovation Phase: Bestaand
BaseQuantities - Width: 280 mm
Name | In | Length (mm) | Height (mm) | GrossFootprintArea (m2) = NetFootprintArea (m2) | GrossSideArea (m2) | NetSideArea (m2) | GrossVolume (m3) | NetVolume (m3)
21_Wand_Baksteen | 00 begane grond | 5953.1 | 3272.5 | 1.66687 | 19.4815 | 13.7028 | 5.4525 | 3.83678
21_Wand_Baksteen | 00 begane grond | 2114.52 | 3272.5 | 0.592065 | 6.91977 | 1.14102 | 1.9352 | 0.319484
21_Wand_Baksteen | 00 begane grond | 4100 | 3285 | 1.1792 | 13.8627 | 13.8627 | 3.87367 | 3.87367
21_Wand_Baksteen | 00 begane grond | 4250 | 3585 | 1.2056 | 14.1508 | 14.1508 | 3.95494 | 3.95494
21_Wand_Baksteen | 00 begane grond | 14508 | 3285 | 3.55827 | 47.2462 | 42.5203 | 13.2269 | 11.8921
21_Wand_Baksteen | 00 begane grond | 8494.08 | 3285 | 2.39394 | 28.133 | 19.4505 | 7.85785 | 5.43239
21_Wand_Baksteen | 00 begane grond | 8844.79 | 3285 | 2.46094 | 28.8909 | 17.1551 | 8.07932 | 4.79735
21_Wand_Baksteen | 00 begane grond | 8015.92 | 3285 | 2.22886 | 26.1024 | 14.5127 | 7.31675 | 4.07605
21_Wand_Baksteen | 00 begane grond | 10268.8 | 3285 | 2.87526 | 33.733 | 19.2717 | 9.43951 | 5.39533
21_Wand_Baksteen | 00 begane grond | 10105 | 3285 | 2.84978 | 33.4952 | 21.8802 | 9.36151 | 6.10931
21_Wand_Baksteen | 00 begane grond | 6334.35 | 3285 | 1.75325 | 20.5939 | 17.6902 | 5.75817 | 4.94612
21_Wand_Baksteen | 00 begane grond | 2106 | 410 | 0.58968 | 6.87609 | 0.86346 | 1.9253 | 0.241769
21_Wand_Baksteen | 00 begane grond | 3886.96 | 4722.5 | 1.08835 | 18.3562 | 18.3562 | 5.13973 | 5.13973
21_Wand_Baksteen | 00 begane grond | 9315.1 | 3272.5 | 2.60823 | 30.4837 | 18.8974 | 8.53543 | 5.29128
21_Wand_Baksteen | 00 begane grond | 3390 | 395 | 0.9492 | 1.33905 | 1.33905 | 0.374934 | 0.374934
21_Wand_Baksteen | 00 begane grond | 11089.2 | 3285 | 3.10498 | 36.4281 | 24.8241 | 10.1953 | 6.9532
21_Wand_Baksteen | 00 begane grond | 400.381 | 4722.5 | 0.112107 | 1.8908 | 1.8908 | 0.529423 | 0.529423
21_Wand_Baksteen | 00 begane grond | 2154.62 | 3272.5 | 0.603293 | 7.05099 | 1.27224 | 1.97428 | 0.356226
21_Wand_Baksteen | 00 begane grond | 18328 | 3272.5 | 5.13184 | 59.9784 | 31.0559 | 16.7939 | 8.69565
21_Wand_Baksteen | 00 begane grond | 2471.92 | 4722.5 | 0.671772 | 11.2421 | 2.57396 | 3.17244 | 0.745369
21_Wand_Baksteen | 00 begane grond | 829.207 | 4722.5 | 0.252542 | 4.22417 | 4.22417 | 1.19263 | 1.19263
21_Wand_Baksteen | 00 begane grond | 3362 | 4722.5 | 0.94136 | 15.8683 | 10.0608 | 4.44383 | 2.81773
21_Wand_Baksteen | 01 eerste verdieping | 4011.43 | 1887.5 | 1.1232 | 7.57157 | 7.57157 | 2.12004 | 2.12004

# IfcWall: 21 MW hoofd 280 (35)
Classification: Wand (ARCHICAD Classification); 21.12 SPOUWWANDEN (NL/SfB (4 cijfers))
Pset_WallCommon - FireRating: 0; SurfaceSpreadOfFlame: 0; LoadBearing: no; IsExternal: yes
CPset_Phasing - Renovation Phase: Bestaand
BaseQuantities - Width: 280 mm
Name | In | Length (mm) | Height (mm) | GrossFootprintArea (m2) = NetFootprintArea (m2) | GrossSideArea (m2) | NetSideArea (m2) | GrossVolume (m3) | NetVolume (m3)
21_Wand_Baksteen | 00 begane grond | 3774.86 | 830 | 1.05696 | 3.13314 | 3.13314 | 0.877278 | 0.877278
2 x 21_Wand_Baksteen | 00 begane grond | 1752.5 | 4135 | 0.4751 | 7.03984 | 7.03984 | 1.96454 | 1.96454
21_Wand_Baksteen | 00 begane grond | 3292.78 | 4135 | 0.937579 | 13.9051 | 13.9051 | 3.87689 | 3.87689
21_Wand_Baksteen | 00 begane grond | 12252.7 | 2000 | 3.43075 | 24.4971 | 24.4971 | 6.85873 | 6.85873
21_Wand_Baksteen | 00 begane grond | 2302.02 | 652.5 | 0.644566 | 1.50207 | 1.50207 | 0.420579 | 0.420579
21_Wand_Baksteen | 00 begane grond | 8147.53 | 652.5 | 2.28131 | 5.31627 | 5.31627 | 1.48855 | 1.48855
21_Wand_Baksteen | 00 begane grond | 18703 | 652.5 | 5.23684 | 12.2037 | 12.2037 | 3.41704 | 3.41704
21_Wand_Baksteen | 00 begane grond | 3332.88 | 4135 | 0.948807 | 14.0709 | 14.0709 | 3.92332 | 3.92332
21_Wand_Vezel Cement Plaat | 01 eerste verdieping | 2605.38 | 2842.5 | 0.745107 | 7.60477 | 7.60477 | 2.11797 | 2.11797
21_Wand_Vezel Cement Plaat | 01 eerste verdieping | 240 | 2960 | 0.0516 | 0.5624 | 0.5624 | 0.152736 | 0.152736
21_Wand_Vezel Cement Plaat | 01 eerste verdieping | 21828 | 3930 | 2.87924 | 86.1377 | 51.013 | 24.0788 | 14.2591
21_Wand_Baksteen | 01 eerste verdieping | 8134 | 3940 | 2.27752 | 32.048 | 23.4338 | 8.96136 | 6.5494
21_Wand_Baksteen | 01 eerste verdieping | 8246.45 | 4830 | 2.28541 | 39.4923 | 33.037 | 11.0297 | 9.22221
21_Wand_Baksteen | 01 eerste verdieping | 19606.5 | 4830 | 5.51343 | 95.1141 | 71.4721 | 26.5827 | 19.9671
21_Wand_Baksteen | 01 eerste verdieping | 20373.8 | 4830 | 5.72504 | 98.8131 | 77.2457 | 27.6047 | 21.5658
21_Wand_Baksteen | 01 eerste verdieping | 6146.85 | 4830 | 1.70075 | 29.374 | 25.0563 | 8.20838 | 6.99941
21_Wand_Baksteen | 01 eerste verdieping | 3199.46 | 3392.5 | 0.89585 | 10.8542 | 10.8542 | 3.03917 | 3.03917
21_Wand_Baksteen | 01 eerste verdieping | 4009.68 | 955 | 1.12271 | 3.82925 | 3.82925 | 1.07219 | 1.07219
21_Wand_Vezel Cement Plaat | 01 eerste verdieping | 5665.32 | 3930 | 1.60189 | 22.5398 | 20.6334 | 6.2923 | 5.76042
21_Wand_Baksteen | 01 eerste verdieping | 3195 | 801.475 | 0.8946 | 2.52281 | 2.52281 | 0.704221 | 0.704221
21_Wand_Baksteen | 01 eerste verdieping | 641.707 | 3392.5 | 0.200042 | 2.13731 | 2.13731 | 0.601274 | 0.601274
21_Wand_Baksteen | 01 eerste verdieping | 140.05 | 3387.5 | 0.023628 | 0.305213 | 0.305213 | 0.0800395 | 0.0800395
21_Wand_Baksteen | 01 eerste verdieping | 129.547 | 990 | 0.0362732 | 0.128252 | 0.128252 | 0.0359105 | 0.0359105
21_Wand_Vezel Cement Plaat | 01 eerste verdieping | 2481 | 830 | 0.69468 | 2.05923 | 2.05923 | 0.576584 | 0.576584
21_Wand_Baksteen | 01 eerste verdieping | 4009.68 | 2000 | 1.12271 | 8.01937 | 8.01937 | 2.24542 | 2.24542
21_Wand_Vezel Cement Plaat | 01 eerste verdieping | 4220 | 955 | 1.1816 | 4.0301 | 4.0301 | 1.12843 | 1.12843
21_Wand_Vezel Cement Plaat | 01 eerste verdieping | 5221.92 | 2842.5 | 0.880439 | 14.6214 | 9.3669 | 4.09553 | 2.62599
21_Wand_Baksteen | 01 eerste verdieping | 5277.54 | 4267.5 | 1.49331 | 22.6521 | 16.1969 | 6.31953 | 4.51206
21_Wand_Vezel Cement Plaat | 01 eerste verdieping | 5805.32 | 260 | 1.62549 | 1.50938 | 1.50938 | 0.422627 | 0.422627
21_Wand_Vezel Cement Plaat | 02 dak | 22208 | 1190 | 6.24944 | 23.4688 | 23.4688 | 6.48128 | 6.48128
21_Wand_Vezel Cement Plaat | 02 dak | 747.623 | 984 | 0.193734 | 0.660074 | 0.660074 | 0.181135 | 0.181135
21_Wand_Baksteen | 02 dak | 13411.5 | 890 | 2.27752 | 7.23555 | 7.23555 | 2.02691 | 2.02691
21_Wand_Baksteen | 02 dak | 3054.64 | 648.525 | 0.839698 | 1.94858 | 1.94858 | 0.544565 | 0.544565
21_Wand_Baksteen | 02 dak | 14620 | 942.5 | 4.1484 | 13.9773 | 13.9773 | 3.90987 | 3.90987

# IfcWall: 21 MW kader staand 260, 21_Wand_Vezel Cement Plaat
In: 01 eerste verdieping
Classification: Wand (ARCHICAD Classification); 21.12 SPOUWWANDEN (NL/SfB (4 cijfers))
Pset_WallCommon - FireRating: 0; SurfaceSpreadOfFlame: 0; LoadBearing: no; IsExternal: yes
CPset_Phasing - Renovation Phase: Bestaand
BaseQuantities - Length: 4220 mm; Height: 1887.5 mm; Width: 260 mm; GrossFootprintArea: 1.0972 m2; NetFootprintArea: 1.0972 m2; GrossSideArea: 7.96525 m2; NetSideArea: 7.96525 m2; GrossVolume: 2.07097 m3; NetVolume: 2.07097 m3

# IfcWall: 21 Plankprofiel 37 (2)
In: 00 begane grond
Classification: Wand (ARCHICAD Classification); 21.12 SPOUWWANDEN (NL/SfB (4 cijfers))
Pset_WallCommon - FireRating: 0; SurfaceSpreadOfFlame: 0; LoadBearing: no; IsExternal: yes
CPset_Phasing - Renovation Phase: Bestaand
BaseQuantities - Length: 220 mm; Height: 2050.86 mm; Width: 37 mm; GrossFootprintArea: 0.00814 m2; NetFootprintArea: 0.00814 m2; GrossSideArea: 0.451189 m2; NetSideArea: 0.451189 m2; GrossVolume: 0.016694 m3; NetVolume: 0.016694 m3

# IfcWall: 21 Vezelcementplaat 188, 21_Wand_Vezel Cement Plaat
In: 02 dak
Classification: Wand (ARCHICAD Classification); 21.12 SPOUWWANDEN (NL/SfB (4 cijfers)); Material: ALG - ISOLATIE
Pset_WallCommon - FireRating: 0; SurfaceSpreadOfFlame: 0; LoadBearing: no; IsExternal: yes
CPset_Phasing - Renovation Phase: Bestaand
BaseQuantities - Length: 97.7297 mm; Height: 540 mm; Width: 188 mm; GrossFootprintArea: 0.0136822 m2; NetFootprintArea: 0.0136822 m2; GrossSideArea: 0.026387 m2; NetSideArea: 0.026387 m2; GrossVolume: 0.00738837 m3; NetVolume: 0.00738837 m3
Component Quantities - ALG - ISOLATIE, Mass: 0.332476 kg; ALG - ISOLATIE, Projected Component Area (Net): 0.052774 m2; ALG - ISOLATIE, Projected Component Area (Gross): 0.052774 m2; ALG - ISOLATIE, Component Thickness: 140 mm; ALG - ISOLATIE, Rectangular Component Height: 540 mm; ALG - ISOLATIE, Rectangular Component Width: 140 mm; ALG - ISOLATIE, Component Cross Section Area: 0.0756 m2; ALG - ISOLATIE, Component Volume (Net): 0.00738837 m3; ALG - ISOLATIE, Component Volume (Gross): 0.00738837 m3

# IfcWall: 21 isolatieopstand techniekruimte 98 (5)
In: 02 dak
Classification: Wand (ARCHICAD Classification); 21.13 SYSTEEMWANDEN (NL/SfB (4 cijfers)); Material: Isolatie - Kunststof hard
Pset_WallCommon - FireRating: 0; SurfaceSpreadOfFlame: 0; LoadBearing: no; IsExternal: yes
CPset_Phasing - Renovation Phase: Bestaand
BaseQuantities - Width: 98 mm
Component Quantities - Isolatie - Kunststof hard, Component Thickness: 98 mm; Isolatie - Kunststof hard, Rectangular Component Height: 467 mm; Isolatie - Kunststof hard, Rectangular Component Width: 98 mm; Isolatie - Kunststof hard, Component Cross Section Area: 0.045766 m2
Name | Length (mm) | Height (mm) | GrossFootprintArea (m2) = NetFootprintArea (m2) | GrossSideArea (m2) = NetSideArea (m2) | GrossVolume (m3) = NetVolume (m3) = Isolatie - Kunststof hard, Component Volume (Net) (m3) | Isolatie - Kunststof hard, Mass (kg) | Isolatie - Kunststof hard, Projected Component Area (Net) (m2) | Isolatie - Kunststof hard, Projected Component Area (Gross) (m2) | Isolatie - Kunststof hard, Component Volume (Gross) (m3)
21_Wand_Sandwich beplating | 3058.33 | 277 | 0.294914 | 0.683117 | 0.0738639 | 7.38639 | 0.833584 | 0.833584 | 0.0738639
21_Wand_Sandwich beplating | 4686.66 | 277 | 0.454491 | 1.05275 | 0.113831 | 11.3831 | 1.28463 | 1.28463 | 0.113831
21_Wand_Sandwich beplating | 7196 | 277 | 0.705208 | 1.63709 | 0.176224 | 17.6224 | 1.99329 | 1.99329 | 0.176224
21_Wand_Sandwich beplating | 8871.99 | 467 | 0.869455 | 2.0175 | 0.217983 | 21.7983 | 4.12954 | 2.45754 | 0.217966
21_Wand_Sandwich beplating | 7196 | 467 | 0.714812 | 1.66294 | 0.183202 | 18.3202 | 3.37875 | 2.02044 | 0.18072

# IfcWall: 21 sandwich 100 (46)
Pset_WallCommon - FireRating: 0; SurfaceSpreadOfFlame: 0; LoadBearing: no; IsExternal: yes
CPset_Phasing - Renovation Phase: Bestaand
BaseQuantities - Width: 100 mm
Name | In | Classification | Length (mm) | Height (mm) | GrossFootprintArea (m2) = NetFootprintArea (m2) | GrossSideArea (m2) | NetSideArea (m2) | GrossVolume (m3) | NetVolume (m3)
21_Wand_sandwichplaat | 00 begane grond | Wand (ARCHICAD Classification); 21.12 SPOUWWANDEN (NL/SfB (4 cijfers)) | 5000 | 6000 | 0.5 | 29.9401 | 23.5584 | 2.99984 | 2.36086
21_Wand_sandwichplaat | 00 begane grond | Wand (ARCHICAD Classification); 21.12 SPOUWWANDEN (NL/SfB (4 cijfers)) | 714 | 2020 | 0.0714 | 1.42836 | 1.42836 | 0.144092 | 0.144092
12 x 21_Wand_sandwichplaat | 00 begane grond | Wand (ARCHICAD Classification); 21.12 SPOUWWANDEN (NL/SfB (4 cijfers)) | 1000 | 6000 | 0.1 | 5.99054 | 5.99054 | 0.599981 | 0.599981
5 x 21_Wand_sandwichplaat | 00 begane grond | Wand (ARCHICAD Classification); 21.12 SPOUWWANDEN (NL/SfB (4 cijfers)) | 2000 | 6000 | 0.2 | 11.9811 | 11.9811 | 1.19996 | 1.19996
21_Wand_sandwichplaat | 00 begane grond | Wand (ARCHICAD Classification); 21.12 SPOUWWANDEN (NL/SfB (4 cijfers)) | 1285.02 | 6000 | 0.128502 | 7.69887 | 7.69887 | 0.770987 | 0.770987
21_Wand_sandwichplaat | 00 begane grond | Wand (ARCHICAD Classification); 21.12 SPOUWWANDEN (NL/SfB (4 cijfers)) | 4000 | 6000 | 0.4 | 23.96 | 23.96 | 2.39992 | 2.39992
21_Wand_sandwichplaat | 00 begane grond | Wand (ARCHICAD Classification); 21.12 SPOUWWANDEN (NL/SfB (4 cijfers)) | 1000 | 6000 | 0.1 | 5.98894 | 5.98894 | 0.599981 | 0.599981
21_Wand_sandwichplaat | 00 begane grond | Wand (ARCHICAD Classification); 21.12 SPOUWWANDEN (NL/SfB (4 cijfers)) | 2000 | 6000 | 0.2 | 11.9757 | 8.78987 | 1.19995 | 0.88096
21_Wand_sandwichplaat | 00 begane grond | Wand (ARCHICAD Classification); 21.12 SPOUWWANDEN (NL/SfB (4 cijfers)) | 1000 | 6000 | 0.1 | 5.98578 | 2.79499 | 0.599972 | 0.280484
21_Wand_sandwichplaat | 00 begane grond | Wand (ARCHICAD Classification); 21.12 SPOUWWANDEN (NL/SfB (4 cijfers)) | 2000 | 2020 | 0.2 | 4.00381 | 4.00381 | 0.403668 | 0.403668
21_Wand_sandwichplaat | 00 begane grond | Wand (ARCHICAD Classification); 21.12 SPOUWWANDEN (NL/SfB (4 cijfers)) | 999.999 | 3980 | 0.0999999 | 3.97622 | 3.97622 | 0.397962 | 0.397962
21_Wand_sandwichplaat | 00 begane grond | Wand (ARCHICAD Classification); 21.12 SPOUWWANDEN (NL/SfB (4 cijfers)) | 999.999 | 3980 | 0.0999999 | 3.98 | 3.98 | 0.398 | 0.398
21_Wand_sandwichplaat | 00 begane grond | Wand (ARCHICAD Classification); 21.12 SPOUWWANDEN (NL/SfB (4 cijfers)) | 714 | 3980 | 0.0714 | 2.84172 | 2.84172 | 0.284172 | 0.284172
21_Wand_sandwichplaat | 00 begane grond | Wand (ARCHICAD Classification); 21.12 SPOUWWANDEN (NL/SfB (4 cijfers)) | 964.886 | 6000 | 0.0964886 | 5.77966 | 5.77966 | 0.578912 | 0.578912
21_Wand_sandwichplaat | 00 begane grond | Wand (ARCHICAD Classification); 21.12 SPOUWWANDEN (NL/SfB (4 cijfers)) | 3000 | 6000 | 0.3 | 17.9716 | 17.9716 | 1.79994 | 1.79994
21_Wand_sandwichplaat | 00 begane grond | Wand (ARCHICAD Classification); 21.12 SPOUWWANDEN (NL/SfB (4 cijfers)) | 2000 | 6000 | 0.2 | 11.9753 | 11.9753 | 1.19984 | 1.19984
21_Wand_sandwichplaat | 00 begane grond | Wand (ARCHICAD Classification); 21.12 SPOUWWANDEN (NL/SfB (4 cijfers)) | 3313.98 | 5980 | 0.148793 | 19.8007 | 17.2289 | 1.98171 | 1.72425
21_Wand_sandwichplaat | 00 begane grond | Wand (ARCHICAD Classification); 21.12 SPOUWWANDEN (NL/SfB (4 cijfers)) | 329.014 | 6000 | 0.0329014 | 1.97097 | 1.97097 | 0.197402 | 0.197402
21_Wand_sandwichplaat | 00 begane grond | Wand (ARCHICAD Classification); 21.12 SPOUWWANDEN (NL/SfB (4 cijfers)) | 5194.99 | 6000 | 0.5195 | 30.4466 | 30.4466 | 3.11586 | 3.11586
21_Wand_sandwichplaat | 01 eerste verdieping | Wand (ARCHICAD Classification); 21.12 SPOUWWANDEN (NL/SfB (4 cijfers)) | 2286 | 3415 | 0.2286 | 7.7878 | 7.7878 | 0.780631 | 0.780631
21_Wand_sandwichplaat | 01 eerste verdieping | Wand (ARCHICAD Classification); 21.12 SPOUWWANDEN (NL/SfB (4 cijfers)) | 2000 | 3415 | 0.2 | 6.8042 | 6.8042 | 0.682838 | 0.682838
5 x 21_Wand_sandwichplaat | 01 eerste verdieping | Wand (ARCHICAD Classification); 21.12 SPOUWWANDEN (NL/SfB (4 cijfers)) | 1000 | 3415 | 0.1 | 3.405 | 3.405 | 0.34148 | 0.34148
21_Wand_sandwichplaat | 01 eerste verdieping | Wand (ARCHICAD Classification); 21.12 SPOUWWANDEN (NL/SfB (4 cijfers)) | 210 | 3415 | 0.021 | 0.715051 | 0.715051 | 0.0717109 | 0.0717109
21_Wand_Sandwich beplating | 02 dak | Wand (ARCHICAD Classification); 21.13 SYSTEEMWANDEN (NL/SfB (4 cijfers)) | 8866 | 2407.09 | 0.783512 | 21.1785 | 19.1458 | 2.15713 | 1.95156
21_Wand_Sandwich beplating | 02 dak | Wand (ARCHICAD Classification); 21.13 SYSTEEMWANDEN (NL/SfB (4 cijfers)) | 7190 | 2407.09 | 0.719 | 17.1874 | 17.1874 | 1.73048 | 1.73048
21_Wand_Sandwich beplating | 02 dak | Wand (ARCHICAD Classification); 21.13 SYSTEEMWANDEN (NL/SfB (4 cijfers)) | 7240 | 2407.09 | 0.719197 | 17.3656 | 17.3656 | 1.73105 | 1.73105
21_Wand_Sandwich beplating | 02 dak | Wand (ARCHICAD Classification); 21.13 SYSTEEMWANDEN (NL/SfB (4 cijfers)) | 8810.67 | 2407.09 | 0.876265 | 21.1623 | 21.1623 | 2.10909 | 2.10909

# IfcWall: 41 Plank h 42 x 255 (5)
In: 00 begane grond
Classification: Wand (ARCHICAD Classification); 21.12 SPOUWWANDEN (NL/SfB (4 cijfers)); Material: Metaal - Aluminium
Pset_WallCommon - FireRating: 0; SurfaceSpreadOfFlame: 0; LoadBearing: no; IsExternal: yes
CPset_Phasing - Renovation Phase: Bestaand
BaseQuantities - Height: 255 mm; Width: 42 mm
Component Quantities - Metaal - Aluminium, Component Cross Section Area: 0.000321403 m2
Name | Length (mm) | GrossFootprintArea (m2) = NetFootprintArea (m2) | GrossSideArea (m2) = NetSideArea (m2) | GrossVolume (m3) = NetVolume (m3) = Metaal - Aluminium, Component Volume (Net) (m3) = Metaal - Aluminium, Component Volume (Gross) (m3) | Metaal - Aluminium, Mass (kg)
21_Wand_sandwichplaat | 9965 | 0.335774 | 2.93073 | 0.00324305 | 9.08055
21_Wand_sandwichplaat | 4975 | 0.164133 | 1.42744 | 0.00158154 | 4.4283
21_Wand_sandwichplaat | 6150 | 0.20295 | 1.74981 | 0.0019466 | 5.45048
21_Wand_sandwichplaat | 18290 | 0.6114 | 5.31222 | 0.00590509 | 16.5342
21_Wand_sandwichplaat | 14300 | 0.486692 | 4.22813 | 0.00470002 | 13.1601

# IfcWall: 42 Gymzaal 70, 22_Wand_KZST
In: 00 begane grond
Classification: Wand (ARCHICAD Classification); 22.21 MASSIEVE WANDEN (NL/SfB (4 cijfers))
Pset_WallCommon - FireRating: 0; SurfaceSpreadOfFlame: 0; LoadBearing: yes; IsExternal: no
CPset_Phasing - Renovation Phase: Bestaand
BaseQuantities - Length: 5180 mm; Height: 493.876 mm; Width: 70 mm; GrossFootprintArea: 0.36254 m2; NetFootprintArea: 0.36254 m2; GrossSideArea: 2.42019 m2; NetSideArea: 2.42019 m2; GrossVolume: 0.176007 m3; NetVolume: 0.176007 m3
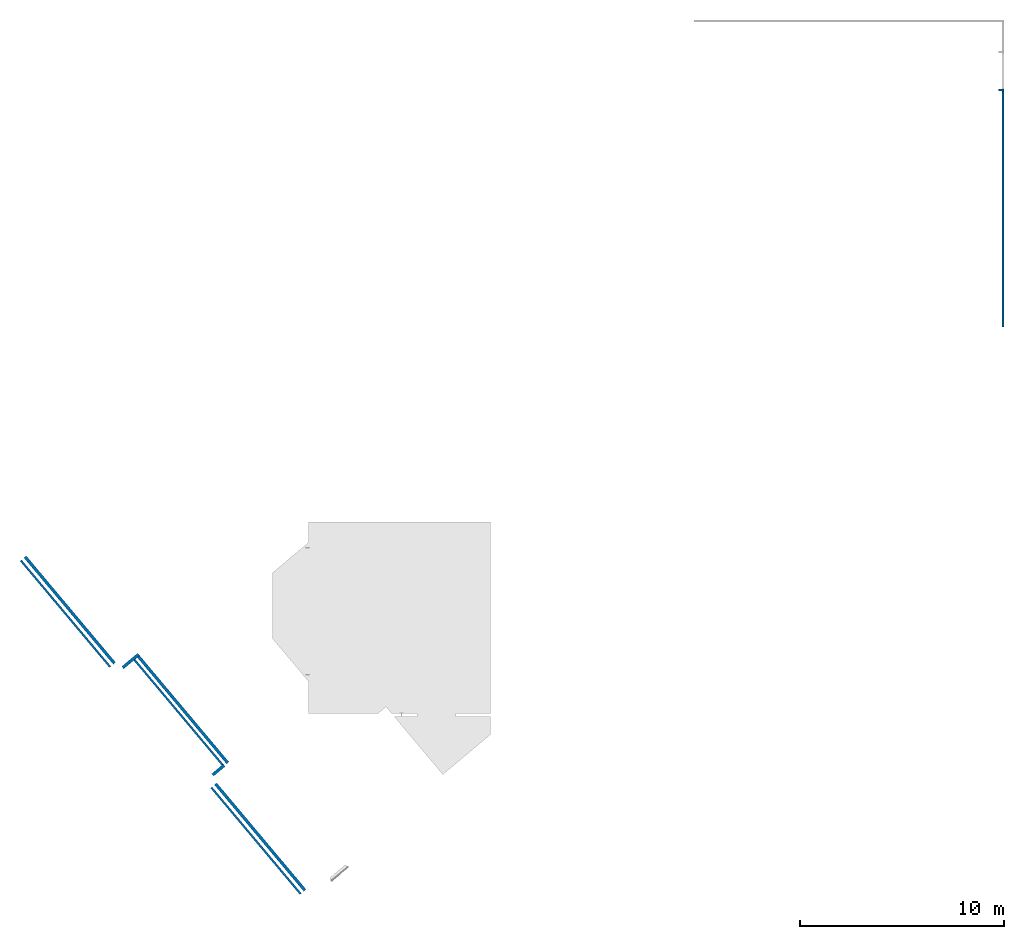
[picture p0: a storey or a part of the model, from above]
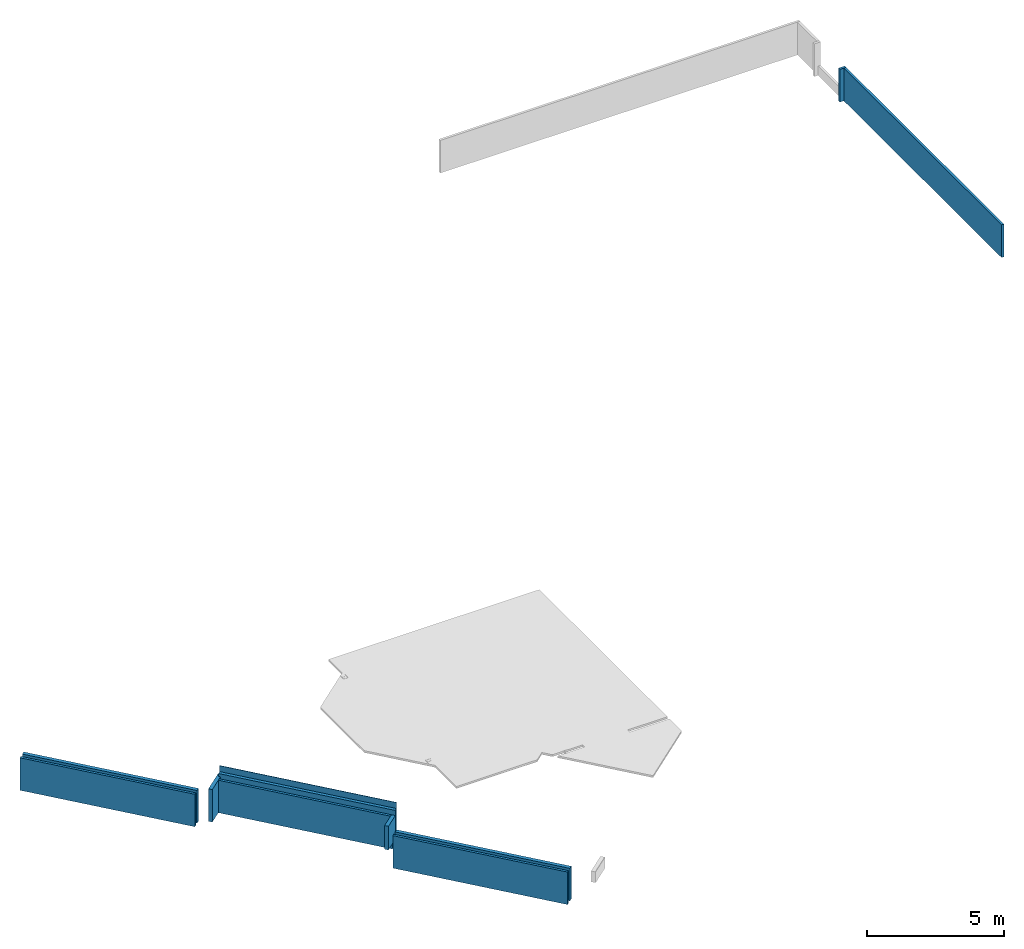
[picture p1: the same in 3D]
Properties of the parts of a building model (IFC2X3), part 10 of 11

# IfcWall: 42 Vilton Isonic Wool 33 (14)
In: 00 begane grond
Classification: Wand (ARCHICAD Classification); 22.21 MASSIEVE WANDEN (NL/SfB (4 cijfers)); Material: 42 Vilton Isonic Wool
Pset_WallCommon - FireRating: 0; SurfaceSpreadOfFlame: 0; LoadBearing: yes; IsExternal: no
CPset_Phasing - Renovation Phase: Bestaand
BaseQuantities - Width: 33 mm
Component Quantities - 42 Vilton Isonic Wool, Component Thickness: 33 mm; 42 Vilton Isonic Wool, Rectangular Component Width: 33 mm
Name | Length (mm) | Height (mm) = 42 Vilton Isonic Wool, Rectangular Component Height (mm) | GrossFootprintArea (m2) = NetFootprintArea (m2) | GrossSideArea (m2) | NetSideArea (m2) | GrossVolume (m3) = 42 Vilton Isonic Wool, Component Volume (Gross) (m3) | NetVolume (m3) = 42 Vilton Isonic Wool, Component Volume (Net) (m3) | 42 Vilton Isonic Wool, Mass (kg) | 42 Vilton Isonic Wool, Projected Component Area (Net) (m2) | 42 Vilton Isonic Wool, Projected Component Area (Gross) (m2) | 42 Vilton Isonic Wool, Component Cross Section Area (m2)
22_Wand_Vilton Isonic Wool | 4539 | 2350 | 0.0910475 | 10.6666 | 6.48367 | 0.351999 | 0.213961 | 128.377 | 6.48367 | 10.6666 | 0.07755
22_Wand_KZST | 4730 | 2350 | 0.156033 | 11.0376 | 11.0376 | 0.366655 | 0.366655 | 219.993 | 11.1148 | 11.1148 | 0.07755
22_Wand_KZST | 5190 | 2350 | 0.171115 | 11.985 | 11.0542 | 0.40212 | 0.371405 | 222.843 | 11.2657 | 12.1965 | 0.07755
22_Wand_KZST | 3217 | 3600 | 0.106705 | 11.6406 | 11.6406 | 0.38414 | 0.38414 | 230.484 | 11.6406 | 11.6406 | 0.1188
22_Wand_KZST | 4805 | 2350 | 0.15841 | 11.0802 | 10.1234 | 0.372263 | 0.340689 | 204.413 | 10.3349 | 11.2917 | 0.07755
22_Wand_Vilton Isonic Wool | 1030 | 2350 | 0.03399 | 2.4205 | 2.4205 | 0.0798765 | 0.0798765 | 47.9259 | 2.4205 | 2.4205 | 0.07755
22_Wand_KZST | 4810 | 2350 | 0.158704 | 11.092 | 11.092 | 0.372953 | 0.372953 | 223.772 | 11.3035 | 11.3035 | 0.07755
22_Wand_Vilton Isonic Wool | 9517 | 2350 | 0.314061 | 22.3649 | 20.4514 | 0.738043 | 0.674895 | 404.937 | 20.4514 | 22.3649 | 0.07755
22_Wand_KZST | 4580 | 2350 | 0.15114 | 10.763 | 10.763 | 0.355179 | 0.355179 | 213.107 | 10.763 | 10.763 | 0.07755
22_Wand_Vilton Isonic Wool | 9619 | 2350 | 0.317427 | 22.6046 | 22.6046 | 0.745953 | 0.745953 | 447.572 | 22.6046 | 22.6046 | 0.07755
22_Wand_vzw | 14109.4 | 2350 | 0.430942 | 33.1182 | 29.9904 | 1.0929 | 0.989683 | 593.81 | 29.9904 | 33.1182 | 0.07755
22_Wand_Vilton Isonic Wool | 5133 | 2350 | 0.169389 | 12.0625 | 12.0625 | 0.398064 | 0.398064 | 238.838 | 12.0625 | 12.0625 | 0.07755
22_Wand_KZST | 5165 | 961 | 0.170445 | 4.96357 | 4.96357 | 0.163798 | 0.163798 | 98.2786 | 4.96357 | 4.96357 | 0.031713
22_Wand_Vilton Isonic Wool | 3458 | 1250 | 0.114114 | 4.3225 | 4.3225 | 0.142643 | 0.142643 | 85.5855 | 4.3225 | 4.3225 | 0.04125

# IfcWall: ALG - BINNENAFWERKING 120 x 120, 22_Schuifwand_rail panelenwand
In: 00 begane grond
Type - ElementType: MOVABLE; PredefinedType: USERDEFINED
Classification: Schuifwand (ARCHICAD Classification); 22.14 SYSTEEMWANDEN VERPLAATSBAAR (NL/SfB (4 cijfers)); Material: ALG - BINNENAFWERKING
Pset_WallCommon - FireRating: 0; SurfaceSpreadOfFlame: 0; LoadBearing: no; IsExternal: no
CPset_Phasing - Renovation Phase: Bestaand
BaseQuantities - Length: 5970 mm; Height: 120 mm; Width: 120 mm; GrossSideArea: 1.4328 m2; NetSideArea: 1.4328 m2; GrossFootprintArea: 0.7164 m2; NetFootprintArea: 0.7164 m2; GrossVolume: 0.085968 m3; NetVolume: 0.085968 m3
Component Quantities - ALG - BINNENAFWERKING, Mass: 68.7744 kg; ALG - BINNENAFWERKING, Projected Component Area (Net): 0.7164 m2; ALG - BINNENAFWERKING, Projected Component Area (Gross): 0.7164 m2; ALG - BINNENAFWERKING, Component Thickness: 120 mm; ALG - BINNENAFWERKING, Rectangular Component Height: 120 mm; ALG - BINNENAFWERKING, Rectangular Component Width: 120 mm; ALG - BINNENAFWERKING, Component Cross Section Area: 0.0144 m2; ALG - BINNENAFWERKING, Component Volume (Net): 0.085968 m3; ALG - BINNENAFWERKING, Component Volume (Gross): 0.085968 m3

# IfcWall: ALG - BINNENAFWERKING 80 (6)
In: 00 begane grond
Type - ElementType: MOVABLE; PredefinedType: USERDEFINED
Classification: Schuifwand (ARCHICAD Classification); 22.14 SYSTEEMWANDEN VERPLAATSBAAR (NL/SfB (4 cijfers)); Material: ALG - BINNENAFWERKING
Pset_WallCommon - FireRating: 0; SurfaceSpreadOfFlame: 0; LoadBearing: no; IsExternal: no
CPset_Phasing - Renovation Phase: Bestaand
BaseQuantities - Height: 2992 mm; Width: 80 mm
Component Quantities - ALG - BINNENAFWERKING, Component Thickness: 80 mm; ALG - BINNENAFWERKING, Rectangular Component Height: 2992 mm; ALG - BINNENAFWERKING, Rectangular Component Width: 80 mm; ALG - BINNENAFWERKING, Component Cross Section Area: 0.23936 m2
Name | Length (mm) | GrossFootprintArea (m2) = NetFootprintArea (m2) | GrossSideArea (m2) = ALG - BINNENAFWERKING, Projected Component Area (Gross) (m2) | NetSideArea (m2) = ALG - BINNENAFWERKING, Projected Component Area (Net) (m2) | GrossVolume (m3) = ALG - BINNENAFWERKING, Component Volume (Gross) (m3) | NetVolume (m3) = ALG - BINNENAFWERKING, Component Volume (Net) (m3) | ALG - BINNENAFWERKING, Mass (kg)
2 x 22_Schuifwand_panelenwand | 80 | 0.0064 | 0.23936 | 0.23936 | 0.0191488 | 0.0191488 | 15.319
3 x 22_Schuifwand_panelenwand | 1440 | 0.1152 | 4.30848 | 1.4664 | 0.344678 | 0.117312 | 93.8496
22_Schuifwand_panelenwand | 1440 | 0.0416 | 4.30848 | 2.19248 | 0.344678 | 0.175398 | 140.319

# IfcWall: ALG - ISOLATIE 140 (3)
Classification: Wand (ARCHICAD Classification); 21.12 SPOUWWANDEN (NL/SfB (4 cijfers)); Material: ALG - ISOLATIE
Pset_WallCommon - FireRating: 0; SurfaceSpreadOfFlame: 0; LoadBearing: no; IsExternal: yes
CPset_Phasing - Renovation Phase: Bestaand
BaseQuantities - Width: 140 mm
Component Quantities - ALG - ISOLATIE, Component Thickness: 140 mm; ALG - ISOLATIE, Rectangular Component Width: 140 mm
Name | In | Length (mm) | Height (mm) | GrossFootprintArea (m2) = NetFootprintArea (m2) | GrossSideArea (m2) = NetSideArea (m2) | GrossVolume (m3) = NetVolume (m3) = ALG - ISOLATIE, Component Volume (Net) (m3) = ALG - ISOLATIE, Component Volume (Gross) (m3) | ALG - ISOLATIE, Mass (kg) | ALG - ISOLATIE, Projected Component Area (Net) (m2) = ALG - ISOLATIE, Projected Component Area (Gross) (m2) | ALG - ISOLATIE, Rectangular Component Height (mm) | ALG - ISOLATIE, Component Cross Section Area (m2)
21_Wand_KZST | 00 begane grond | 4100 | 3385 | 0.574 | 13.0692 | 1.93652 | 87.1432 | 13.8785 | 3385 | 0.4739
21_Wand_KZST | 00 begane grond | 4743.99 | 3385 | 0.664159 | 16.0584 | 2.24818 | 101.168 | 16.0584 | 3585 | 0.5019
21_Wand_Baksteen | 01 eerste verdieping | 84 | 3887.5 | 0.01176 | 0.32655 | 0.045717 | 2.05727 | 0.32655 | 4830 | 0.6762

# IfcWall: Gipsplaat 12, 22_Wand_KZST
In: 01 eerste verdieping
Classification: Wand (ARCHICAD Classification); 22.21 MASSIEVE WANDEN (NL/SfB (4 cijfers)); Material: Gipsplaat
Pset_WallCommon - FireRating: 0; SurfaceSpreadOfFlame: 0; LoadBearing: yes; IsExternal: no
CPset_Phasing - Renovation Phase: Bestaand
BaseQuantities - Length: 7711.19 mm; Height: 350 mm; Width: 12 mm; GrossFootprintArea: 0.0885392 m2; NetFootprintArea: 0.0885392 m2; GrossSideArea: 2.58096 m2; NetSideArea: 2.58096 m2; GrossVolume: 0.0309715 m3; NetVolume: 0.0309715 m3
Component Quantities - Gipsplaat, Mass: 24.7772 kg; Gipsplaat, Projected Component Area (Net): 2.58454 m2; Gipsplaat, Projected Component Area (Gross): 2.58454 m2; Gipsplaat, Component Thickness: 12 mm; Gipsplaat, Rectangular Component Height: 350 mm; Gipsplaat, Rectangular Component Width: 12 mm; Gipsplaat, Component Cross Section Area: 0.0042 m2; Gipsplaat, Component Volume (Net): 0.0309715 m3; Gipsplaat, Component Volume (Gross): 0.0309715 m3

# IfcWall: Gipsplaat 13 (5)
Classification: Wand (ARCHICAD Classification); 22.21 MASSIEVE WANDEN (NL/SfB (4 cijfers)); Material: Gipsplaat
Pset_WallCommon - FireRating: 0; SurfaceSpreadOfFlame: 0; IsExternal: no
CPset_Phasing - Renovation Phase: Bestaand
BaseQuantities - Width: 12.5 mm
Component Quantities - Gipsplaat, Component Thickness: 12.5 mm; Gipsplaat, Rectangular Component Width: 12.5 mm
Name | In | LoadBearing | Length (mm) | Height (mm) = Gipsplaat, Rectangular Component Height (mm) | GrossFootprintArea (m2) = NetFootprintArea (m2) | GrossSideArea (m2) = NetSideArea (m2) | GrossVolume (m3) = NetVolume (m3) = Gipsplaat, Component Volume (Net) (m3) = Gipsplaat, Component Volume (Gross) (m3) | Gipsplaat, Mass (kg) | Gipsplaat, Projected Component Area (Net) (m2) = Gipsplaat, Projected Component Area (Gross) (m2) | Gipsplaat, Component Cross Section Area (m2)
22_Wand_Binnenwand | 00 begane grond | no | 1471.45 | 384.5 | 0.0183931 | 0.565771 | 0.00707214 | 5.65771 | 0.565771 | 0.00480625
22_Wand_Binnenwand | 00 begane grond | no | 1216.99 | 395 | 0.0152124 | 0.480711 | 0.00600889 | 4.80711 | 0.480711 | 0.0049375
22_Wand_koof | 01 eerste verdieping | no | 271.201 | 367 | 0.00331189 | 0.0147848 | 0.000185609 | 0.148487 | 0.0148558 | 0.0045875
22_Wand_KZST | 01 eerste verdieping | yes | 1120.22 | 350 | 0.0140027 | 0.392076 | 0.00490095 | 3.92076 | 0.392076 | 0.004375
22_Wand_koof | 01 eerste verdieping | no | 231.151 | 367 | 0.00296751 | 0.0871261 | 0.00108908 | 0.871261 | 0.0871492 | 0.0045875

# IfcWall: Hout - Multiplex 90 15 (2)
In: 00 begane grond
Classification: Wand (ARCHICAD Classification); 22.21 MASSIEVE WANDEN (NL/SfB (4 cijfers)); Material: Hout - Multiplex 90
Pset_WallCommon - FireRating: 0; SurfaceSpreadOfFlame: 0; LoadBearing: yes; IsExternal: no
CPset_Phasing - Renovation Phase: Bestaand
BaseQuantities - Width: 15 mm
Component Quantities - Hout - Multiplex 90, Component Thickness: 15 mm; Hout - Multiplex 90, Rectangular Component Width: 15 mm
Name | Length (mm) | Height (mm) = Hout - Multiplex 90, Rectangular Component Height (mm) | GrossFootprintArea (m2) = NetFootprintArea (m2) | GrossSideArea (m2) = NetSideArea (m2) = Hout - Multiplex 90, Projected Component Area (Net) (m2) = Hout - Multiplex 90, Projected Component Area (Gross) (m2) | GrossVolume (m3) = NetVolume (m3) = Hout - Multiplex 90, Component Volume (Net) (m3) = Hout - Multiplex 90, Component Volume (Gross) (m3) | Hout - Multiplex 90, Mass (kg) | Hout - Multiplex 90, Component Cross Section Area (m2)
22_Wand_Vilton Isonic Wool | 1779.98 | 40 | 0.0266998 | 0.0711994 | 0.00106799 | 0.747593 | 0.0006
22_Wand_Vilton Isonic Wool | 1034 | 73 | 0.01551 | 0.075482 | 0.00113223 | 0.792561 | 0.001095

# IfcWall: KZ 120 120, 22_Wand_Binnenwand
In: 00 begane grond
Classification: Wand (ARCHICAD Classification); 22.21 MASSIEVE WANDEN (NL/SfB (4 cijfers)); Material: Steen - Kalkzandsteen C
Pset_WallCommon - FireRating: 0; SurfaceSpreadOfFlame: 0; LoadBearing: no; IsExternal: no
CPset_Phasing - Renovation Phase: Bestaand
BaseQuantities - Length: 6619 mm; Height: 4000 mm; Width: 120 mm; GrossFootprintArea: 0.79428 m2; NetFootprintArea: 0.79428 m2; GrossSideArea: 26.476 m2; NetSideArea: 18.6649 m2; GrossVolume: 3.17712 m3; NetVolume: 2.23979 m3
Component Quantities - Steen - Kalkzandsteen C, Mass: 4255.6 kg; Steen - Kalkzandsteen C, Projected Component Area (Net): 18.6649 m2; Steen - Kalkzandsteen C, Projected Component Area (Gross): 26.476 m2; Steen - Kalkzandsteen C, Component Thickness: 120 mm; Steen - Kalkzandsteen C, Rectangular Component Height: 4000 mm; Steen - Kalkzandsteen C, Rectangular Component Width: 120 mm; Steen - Kalkzandsteen C, Component Cross Section Area: 0.48 m2; Steen - Kalkzandsteen C, Component Volume (Net): 2.23979 m3; Steen - Kalkzandsteen C, Component Volume (Gross): 3.17712 m3

# IfcWall: KZ 150 150 (2)
In: 01 eerste verdieping
Classification: Wand (ARCHICAD Classification); 22.21 MASSIEVE WANDEN (NL/SfB (4 cijfers)); Material: Steen - Kalkzandsteen C
Pset_WallCommon - FireRating: 60; SurfaceSpreadOfFlame: 60; Compartmentation: yes; LoadBearing: no; IsExternal: no
CPset_Phasing - Renovation Phase: Bestaand
BaseQuantities - Height: 3930 mm; Width: 150 mm
Component Quantities - Steen - Kalkzandsteen C, Component Thickness: 150 mm; Steen - Kalkzandsteen C, Rectangular Component Height: 3930 mm; Steen - Kalkzandsteen C, Rectangular Component Width: 150 mm; Steen - Kalkzandsteen C, Component Cross Section Area: 0.5895 m2
Name | Length (mm) | GrossFootprintArea (m2) = NetFootprintArea (m2) | GrossSideArea (m2) = NetSideArea (m2) = Steen - Kalkzandsteen C, Projected Component Area (Net) (m2) = Steen - Kalkzandsteen C, Projected Component Area (Gross) (m2) | GrossVolume (m3) = NetVolume (m3) = Steen - Kalkzandsteen C, Component Volume (Net) (m3) = Steen - Kalkzandsteen C, Component Volume (Gross) (m3) | Steen - Kalkzandsteen C, Mass (kg)
22_Wand_Binnenwand | 4589.32 | 0.688398 | 18.036 | 2.7054 | 5140.27
22_Wand_Binnenwand | 1784.68 | 0.267702 | 7.0138 | 1.05207 | 1998.93

# IfcWall: MS100 2.50.2A 100 (100)
Classification: Wand (ARCHICAD Classification); 22.21 MASSIEVE WANDEN (NL/SfB (4 cijfers))
Pset_WallCommon - IsExternal: no
CPset_Phasing - Renovation Phase: Bestaand
BaseQuantities - Width: 100 mm
Name | In | FireRating = SurfaceSpreadOfFlame | LoadBearing | Length (mm) | Height (mm) | GrossFootprintArea (m2) = NetFootprintArea (m2) | GrossSideArea (m2) | NetSideArea (m2) | GrossVolume (m3) | NetVolume (m3)
22_Wand_KZST | 00 begane grond | 0 | yes | 7711.19 | 5585 | 0.771119 | 43.067 | 30.6986 | 4.3067 | 3.06986
22_Wand_Binnenwand | 00 begane grond | 0 | no | 1800 | 3740 | 0.18 | 6.732 | 6.732 | 0.6732 | 0.6732
22_Wand_Binnenwand | 00 begane grond | 60 | no | 2307.78 | 4000 | 0.239528 | 8.99676 | 8.99676 | 0.934154 | 0.934154 | Pset_WallCommon - Compartmentation: yes
22_Wand_Binnenwand | 00 begane grond | 0 | no | 5532.49 | 3740 | 0.553249 | 20.6915 | 15.7966 | 2.06915 | 1.57966
22_Wand_Binnenwand | 00 begane grond | 0 | no | 5856.49 | 3740 | 0.585649 | 21.9033 | 19.4558 | 2.19033 | 1.94558
22_Wand_Binnenwand | 00 begane grond | 0 | no | 10032.7 | 3740 | 1.00327 | 37.5222 | 30.1798 | 3.75222 | 3.01798
22_Wand_Binnenwand | 00 begane grond | 0 | no | 4167.73 | 3740 | 0.416773 | 15.5873 | 15.5873 | 1.55873 | 1.55873
22_Wand_Binnenwand | 00 begane grond | 60 | no | 1845 | 3740 | 0.1845 | 6.9003 | 2.53319 | 0.69003 | 0.253319 | Pset_WallCommon - Compartmentation: yes
22_Wand_Binnenwand | 00 begane grond | 0 | no | 3118.9 | 1650 | 0.31189 | 5.14619 | 5.14619 | 0.514618 | 0.514618
22_Wand_Binnenwand | 00 begane grond | 0 | no | 3500 | 3740 | 0.35 | 13.09 | 13.09 | 1.309 | 1.309
22_Wand_Binnenwand | 00 begane grond | 0 | no | 2456 | 4000 | 0.2456 | 9.824 | 9.824 | 0.9824 | 0.9824
22_Wand_Binnenwand | 00 begane grond | 0 | no | 3634.97 | 3740 | 0.353497 | 13.2208 | 8.32582 | 1.32208 | 0.832582
22_Wand_Binnenwand | 00 begane grond | 0 | no | 2731 | 3740 | 0.2731 | 10.2139 | 10.2139 | 1.02139 | 1.02139
22_Wand_Binnenwand | 00 begane grond | 60 | no | 3060.1 | 3740 | 0.307572 | 11.4681 | 9.02067 | 1.15032 | 0.905573 | Pset_WallCommon - Compartmentation: yes
22_Wand_Binnenwand | 00 begane grond | 60 | no | 3374.56 | 3740 | 0.335894 | 12.5975 | 12.5975 | 1.25624 | 1.25624 | Pset_WallCommon - Compartmentation: yes
22_Wand_Binnenwand | 00 begane grond | 0 | no | 3010.1 | 3740 | 0.29851 | 11.1643 | 8.71679 | 1.11643 | 0.871679
22_Wand_Binnenwand | 00 begane grond | 0 | no | 1967.43 | 3740 | 0.198306 | 7.38157 | 7.38157 | 0.741663 | 0.741663
22_Wand_Binnenwand | 00 begane grond | 0 | no | 1134 | 3740 | 0.111838 | 4.21779 | 1.77031 | 0.418272 | 0.173524
22_Wand_Binnenwand | 00 begane grond | 0 | no | 1687.42 | 3740 | 0.168742 | 6.31095 | 6.31095 | 0.631095 | 0.631095
22_Wand_Binnenwand | 00 begane grond | 0 | no | 4217.73 | 3740 | 0.42021 | 15.7509 | 15.7509 | 1.57159 | 1.57159
22_Wand_Binnenwand | 00 begane grond | 0 | no | 1584.72 | 3740 | 0.158472 | 5.92684 | 5.92684 | 0.592684 | 0.592684
22_Wand_Binnenwand | 00 begane grond | 0 | no | 1965 | 3740 | 0.1965 | 7.3491 | 2.69794 | 0.73491 | 0.269794
22_Wand_Binnenwand | 00 begane grond | 60 | no | 2240 | 3740 | 0.225562 | 8.40098 | 4.16404 | 0.843604 | 0.419911 | Pset_WallCommon - Compartmentation: yes
22_Wand_Binnenwand | 00 begane grond | 60 | no | 1621.4 | 3740 | 0.16214 | 6.06403 | 6.06403 | 0.606403 | 0.606403 | Pset_WallCommon - Compartmentation: yes
22_Wand_Binnenwand | 00 begane grond | 0 | no | 2489.97 | 5073.99 | 0.248997 | 10.1541 | 10.1541 | 1.01541 | 1.01541
22_Wand_Binnenwand | 00 begane grond | 0 | no | 3894.62 | 3740 | 0.389462 | 14.5659 | 14.5659 | 1.45659 | 1.45659
22_Wand_Binnenwand | 00 begane grond | 0 | no | 6672.29 | 3740 | 0.667229 | 24.9544 | 22.5069 | 2.49544 | 2.25069
22_Wand_Binnenwand | 00 begane grond | 0 | no | 2902.5 | 5190 | 0.29025 | 15.064 | 15.064 | 1.5064 | 1.5064
22_Wand_Binnenwand | 00 begane grond | 0 | no | 2839.85 | 5190 | 0.283985 | 14.7388 | 14.7388 | 1.47388 | 1.47388
22_Wand_Binnenwand | 00 begane grond | 0 | no | 2649.96 | 3740 | 0.264996 | 9.91084 | 5.23128 | 0.991084 | 0.523128
22_Wand_Binnenwand | 00 begane grond | 0 | no | 2794 | 3740 | 0.2794 | 10.4496 | 6.28365 | 1.04496 | 0.628365
22_Wand_Binnenwand | 00 begane grond | 0 | no | 1293.7 | 5190 | 0.12937 | 6.71428 | 6.71428 | 0.671428 | 0.671428
22_Wand_Binnenwand | 00 begane grond | 60 | no | 6965.3 | 3740 | 0.69653 | 26.0502 | 9.56336 | 2.60502 | 0.956336 | Pset_WallCommon - Compartmentation: yes
22_Wand_Binnenwand | 00 begane grond | 0 | no | 2107.5 | 3740 | 0.212313 | 7.90543 | 5.45795 | 0.794049 | 0.549301
22_Wand_Binnenwand | 00 begane grond | 0 | no | 4149.97 | 3740 | 0.413435 | 15.4975 | 15.4975 | 1.54625 | 1.54625
22_Wand_Binnenwand | 00 begane grond | 0 | no | 4149.97 | 3740 | 0.41656 | 15.5443 | 15.5443 | 1.55793 | 1.55793
22_Wand_Binnenwand | 00 begane grond | 0 | no | 2685.5 | 5450 | 0.26855 | 14.6097 | 14.6097 | 1.46331 | 1.46331
22_Wand_Binnenwand | 00 begane grond | 0 | no | 2107.42 | 3740 | 0.210742 | 7.88173 | 5.43426 | 0.788173 | 0.543426
22_Wand_Binnenwand | 00 begane grond | 0 | no | 2649.9 | 3740 | 0.263428 | 9.88726 | 6.73082 | 0.98522 | 0.669576
22_Wand_Binnenwand | 00 begane grond | 0 | no | 1143.8 | 5190 | 0.11438 | 5.90659 | 5.90659 | 0.590659 | 0.590659
22_Wand_Binnenwand | 00 begane grond | 0 | no | 1605 | 3650 | 0.0258621 | 5.88105 | 2.88465 | 0.591527 | 0.291887
22_Wand_Binnenwand | 00 begane grond | 0 | no | 1642.49 | 4000 | 0.164249 | 6.56997 | 6.56997 | 0.656997 | 0.656997
22_Wand_Binnenwand | 00 begane grond | 0 | no | 1602.98 | 3710 | 0.0240983 | 5.94707 | 2.82809 | 0.594707 | 0.282809
2 x 22_Wand_Binnenwand | 00 begane grond | 0 | no | 1433.93 | 1195.56 | 0.143393 | 0.900195 | 0.900195 | 0.0900195 | 0.0900195
22_Wand_Binnenwand | 00 begane grond | 0 | no | 1818.34 | 3740 | 0.181834 | 6.8006 | 6.8006 | 0.68006 | 0.68006
22_Wand_Binnenwand | 00 begane grond | 60 | no | 1243.3 | 3740 | 0.12433 | 4.64993 | 4.64993 | 0.464993 | 0.464993 | Pset_WallCommon - Compartmentation: yes
22_Wand_Binnenwand | 00 begane grond | 0 | no | 1243.3 | 3740 | 0.127142 | 5.07068 | 2.6232 | 0.475512 | 0.230764
2 x 22_Wand_Binnenwand | 00 begane grond | 0 | no | 240.007 | 2290 | 0.0240007 | 0.549617 | 0.549617 | 0.0549617 | 0.0549617
22_Wand_Binnenwand | 00 begane grond | 60 | no | 1973.37 | 3740 | 0.195775 | 7.35705 | 7.35705 | 0.732198 | 0.732198 | Pset_WallCommon - Compartmentation: yes
22_Wand_Binnenwand | 00 begane grond | 0 | no | 90.167 | 3650 | 0.0105792 | 0.351922 | 0.351922 | 0.0386141 | 0.0386141
22_Wand_Binnenwand | 00 begane grond | 0 | no | 172.2 | 3650 | 0.014095 | 0.582905 | 0.582905 | 0.0514468 | 0.0514468
22_Wand_Binnenwand | 00 begane grond | 60 | no | 450 | 3740 | 0.045 | 1.683 | 1.683 | 0.1683 | 0.1683 | Pset_WallCommon - Compartmentation: yes
22_Wand_Binnenwand | 00 begane grond | 60 | no | 449.699 | 3740 | 0.0449699 | 1.68187 | 1.68187 | 0.168187 | 0.168187 | Pset_WallCommon - Compartmentation: yes
22_Wand_Binnenwand | 00 begane grond | 0 | no | 3118.9 | 1890 | 0.31189 | 5.89472 | 5.89472 | 0.589472 | 0.589472
22_Wand_Binnenwand | 00 begane grond | 0 | no | 1439.72 | 4000 | 0.146472 | 6.13287 | 6.13287 | 0.585237 | 0.585237
22_Wand_Binnenwand | 01 eerste verdieping | 0 | no | 1787.67 | 3930 | 0.0441292 | 7.05009 | 3.93111 | 0.708694 | 0.396796
2 x 22_Wand_Binnenwand | 01 eerste verdieping | 0 | no | 140.007 | 2290 | 0.0140007 | 0.320617 | 0.320617 | 0.0320617 | 0.0320617
22_Wand_Binnenwand | 01 eerste verdieping | 0 | no | 4592.51 | 3930 | 0.459251 | 18.0486 | 15.6011 | 1.80486 | 1.56011
22_Wand_Binnenwand | 01 eerste verdieping | 0 | no | 400 | 3930 | 0.036875 | 1.52287 | 1.52287 | 0.144919 | 0.144919
22_Wand_Binnenwand | 01 eerste verdieping | 0 | no | 3048.95 | 3930 | 0.306935 | 12.0144 | 8.16807 | 1.20625 | 0.821617
22_Wand_Binnenwand | 01 eerste verdieping | 0 | no | 1086.37 | 3930 | 0.106597 | 4.23737 | 4.23737 | 0.418928 | 0.418928
22_Wand_Binnenwand | 01 eerste verdieping | 0 | no | 2250.87 | 3930 | 0.226649 | 8.87048 | 5.71404 | 0.890732 | 0.575088
22_Wand_Binnenwand | 01 eerste verdieping | 0 | no | 3538.23 | 3930 | 0.355386 | 13.9298 | 13.9298 | 1.39667 | 1.39667
22_Wand_Binnenwand | 01 eerste verdieping | 0 | no | 1684.55 | 3930 | 0.16533 | 6.57117 | 6.57117 | 0.649748 | 0.649748
22_Wand_Binnenwand | 01 eerste verdieping | 0 | no | 1604.55 | 3930 | 0.15983 | 6.30589 | 6.30589 | 0.628133 | 0.628133
22_Wand_Binnenwand | 01 eerste verdieping | 0 | no | 2398.05 | 3930 | 0.238243 | 9.39979 | 6.95231 | 0.936295 | 0.691547
22_Wand_Binnenwand | 01 eerste verdieping | 60 | no | 1542.05 | 3930 | 0.155768 | 6.08483 | 6.08483 | 0.612167 | 0.612167 | Pset_WallCommon - Compartmentation: yes
22_Wand_Binnenwand | 01 eerste verdieping | 0 | no | 3371.5 | 3930 | 0.329213 | 12.9012 | 10.4537 | 1.29381 | 1.04906
22_Wand_Binnenwand | 01 eerste verdieping | 0 | no | 3124 | 3930 | 0.313963 | 12.3019 | 12.3019 | 1.23387 | 1.23387
22_Wand_Binnenwand | 01 eerste verdieping | 0 | no | 943.832 | 3930 | 0.0959457 | 3.73382 | 3.73382 | 0.377067 | 0.377067
22_Wand_Binnenwand | 01 eerste verdieping | 60 | no | 5731.97 | 3930 | 0.573197 | 22.5267 | 20.0792 | 2.25267 | 2.00792 | Pset_WallCommon - Compartmentation: yes
22_Wand_Binnenwand | 01 eerste verdieping | 0 | no | 1337.5 | 3930 | 0.13375 | 5.25638 | 2.8089 | 0.525638 | 0.28089
22_Wand_Binnenwand | 01 eerste verdieping | 60 | no | 1807.48 | 3930 | 0.18231 | 7.12795 | 7.12795 | 0.71648 | 0.71648 | Pset_WallCommon - Compartmentation: yes
22_Wand_Binnenwand | 01 eerste verdieping | 60 | no | 5277.5 | 3930 | 0.526187 | 20.716 | 20.716 | 2.06792 | 2.06792 | Pset_WallCommon - Compartmentation: yes
22_Wand_Binnenwand | 01 eerste verdieping | 0 | no | 400 | 3930 | 0.043125 | 1.62112 | 1.60633 | 0.169481 | 0.169384
22_Wand_Binnenwand | 01 eerste verdieping | 0 | no | 1096.5 | 3930 | 0.108088 | 4.28468 | 4.28468 | 0.424784 | 0.424784
22_Wand_Binnenwand | 01 eerste verdieping | 0 | no | 2600 | 3930 | 0.261563 | 10.2426 | 7.79508 | 1.02794 | 0.783193
22_Wand_Binnenwand | 01 eerste verdieping | 0 | no | 772.136 | 3930 | 0.0772136 | 3.03449 | 3.03449 | 0.303449 | 0.303449
22_Wand_Binnenwand | 01 eerste verdieping | 0 | no | 2019.58 | 3930 | 0.200395 | 7.91237 | 7.91237 | 0.787552 | 0.787552
22_Wand_Binnenwand | 01 eerste verdieping | 0 | no | 2264.09 | 3930 | 0.226409 | 8.89789 | 4.00755 | 0.889789 | 0.400409
22_Wand_Binnenwand | 01 eerste verdieping | 0 | no | 4275 | 3930 | 0.425937 | 16.7762 | 16.7762 | 1.67393 | 1.67393
22_Wand_Binnenwand | 01 eerste verdieping | 0 | no | 1900 | 5380 | 0.2 | 10.367 | 10.367 | 1.0367 | 1.0367
22_Wand_Binnenwand | 01 eerste verdieping | 0 | no | 1687.17 | 3930 | 0.0309542 | 6.606 | 3.48702 | 0.656916 | 0.345018
22_Wand_Binnenwand | 01 eerste verdieping | 0 | no | 3299.94 | 3930 | 0.327494 | 12.8705 | 12.8705 | 1.28705 | 1.28705
22_Wand_Binnenwand | 01 eerste verdieping | 60 | no | 3835 | 3930 | 0.3835 | 15.0716 | 15.0716 | 1.50716 | 1.50716 | Pset_WallCommon - Compartmentation: yes
22_Wand_Binnenwand | 01 eerste verdieping | 60 | no | 4873.5 | 3930 | 0.48735 | 19.1529 | 10.3306 | 1.91529 | 1.03306 | Pset_WallCommon - Compartmentation: yes
22_Wand_Binnenwand | 01 eerste verdieping | 0 | no | 1293.7 | 3930 | 0.12937 | 5.08424 | 5.08424 | 0.508424 | 0.508424
22_Wand_Binnenwand | 01 eerste verdieping | 60 | no | 7525.94 | 3930 | 0.752594 | 29.5769 | 29.5769 | 2.95769 | 2.95769 | Pset_WallCommon - Compartmentation: yes
22_Wand_Binnenwand | 01 eerste verdieping | 0 | no | 3122.19 | 3930 | 0.312219 | 12.2702 | 12.2702 | 1.22702 | 1.22702
22_Wand_Binnenwand | 01 eerste verdieping | 0 | no | 409.379 | 3930 | 0.0409378 | 1.60886 | 1.60886 | 0.160886 | 0.160886
22_Wand_Binnenwand | 01 eerste verdieping | 0 | no | 139.993 | 2290 | 0.0139993 | 0.320583 | 0.320583 | 0.0320583 | 0.0320583
22_Wand_Binnenwand | 01 eerste verdieping | 0 | no | 139.992 | 2290 | 0.0214992 | 0.492331 | 0.492331 | 0.0492331 | 0.0492331
22_Wand_Binnenwand | 01 eerste verdieping | 0 | no | 1843.73 | 3930 | 0.184373 | 7.24585 | 3.24713 | 0.724585 | 0.324713
22_Wand_Binnenwand | 01 eerste verdieping | 0 | no | 359.982 | 3930 | 0.0344357 | 1.39017 | 1.39017 | 0.135332 | 0.135332
22_Wand_koof | 01 eerste verdieping | 0 | no | 1487.85 | 1100 | 0.148664 | 0.868847 | 0.868847 | 0.0866663 | 0.0866663
22_Wand_Binnenwand | 01 eerste verdieping | 60 | no | 824.138 | 3930 | 0.0808513 | 3.2143 | 3.2143 | 0.317745 | 0.317745 | Pset_WallCommon - Compartmentation: yes
22_Wand_Binnenwand | 01 eerste verdieping | 60 | no | 377.752 | 3930 | 0.0377752 | 1.48457 | 1.48457 | 0.148457 | 0.148457 | Pset_WallCommon - Compartmentation: yes

# IfcWall: MS100 75.2A 100 (24)
Classification: Wand (ARCHICAD Classification); 22.21 MASSIEVE WANDEN (NL/SfB (4 cijfers))
Pset_WallCommon - LoadBearing: no; IsExternal: no
CPset_Phasing - Renovation Phase: Bestaand
BaseQuantities - Width: 100 mm
Name | In | FireRating = SurfaceSpreadOfFlame | Length (mm) | Height (mm) | GrossFootprintArea (m2) = NetFootprintArea (m2) | GrossSideArea (m2) | NetSideArea (m2) | GrossVolume (m3) | NetVolume (m3)
22_Wand_Binnenwand | 00 begane grond | 0 | 1725 | 4485 | 0.1725 | 7.73663 | 7.73663 | 0.773663 | 0.773663
22_Wand_Binnenwand | 00 begane grond | 0 | 1282.5 | 4485 | 0.12825 | 5.75201 | 5.75201 | 0.575201 | 0.575201
22_Wand_Binnenwand | 00 begane grond | 0 | 5970 | 1283 | 0 | 26.7754 | 7.65951 | 2.67754 | 0.765951
22_Wand_Binnenwand | 00 begane grond | 0 | 767.507 | 900 | 0.0797194 | 0.724506 | 0.724506 | 0.0717475 | 0.0717475
22_Wand_Binnenwand | 00 begane grond | 0 | 1967.5 | 900 | 0.193781 | 1.76513 | 1.76513 | 0.174403 | 0.174403
22_Wand_Binnenwand | 01 eerste verdieping | 0 | 550 | 3930 | 0.0520312 | 2.13694 | 2.13694 | 0.204483 | 0.204483
22_Wand_Binnenwand | 01 eerste verdieping | 60 | 3739.01 | 3930 | 0.373901 | 14.6943 | 14.6943 | 1.46943 | 1.46943 | Pset_WallCommon - Compartmentation: yes
22_Wand_Binnenwand | 01 eerste verdieping | 0 | 5227.5 | 3930 | 0.51525 | 20.3476 | 20.3476 | 2.02493 | 2.02493
22_Wand_Binnenwand | 01 eerste verdieping | 0 | 1046.5 | 3930 | 0.10465 | 4.11275 | 4.11275 | 0.411274 | 0.411274
22_Wand_Binnenwand | 01 eerste verdieping | 0 | 4592.51 | 3930 | 0.459251 | 18.0486 | 18.0486 | 1.80486 | 1.80486
22_Wand_Binnenwand | 01 eerste verdieping | 0 | 2800 | 3930 | 0.282969 | 11.1514 | 11.1514 | 1.11207 | 1.11207
22_Wand_Binnenwand | 01 eerste verdieping | 0 | 899.877 | 3930 | 0.0929564 | 3.68389 | 3.68389 | 0.365319 | 0.365319
2 x 22_Wand_Binnenwand | 01 eerste verdieping | 0 | 150 | 3930 | 0.0120313 | 0.564937 | 0.564937 | 0.0472828 | 0.0472828
22_Wand_Binnenwand | 01 eerste verdieping | 0 | 928 | 3930 | 0.0957687 | 3.79442 | 3.79442 | 0.376371 | 0.376371
22_Wand_Binnenwand | 01 eerste verdieping | 0 | 264.002 | 3930 | 0.0293689 | 1.1849 | 1.1849 | 0.11542 | 0.11542
22_Wand_Binnenwand | 01 eerste verdieping | 0 | 357.001 | 3930 | 0.0327313 | 1.37845 | 1.37845 | 0.128634 | 0.128634
22_Wand_Binnenwand | 01 eerste verdieping | 0 | 200 | 3840 | 0.0229687 | 0.912 | 0.912 | 0.0882 | 0.0882
22_Wand_Binnenwand | 01 eerste verdieping | 0 | 200 | 3840 | 0.0170312 | 0.744 | 0.744 | 0.0654 | 0.0654
22_Wand_Binnenwand | 01 eerste verdieping | 0 | 247.999 | 3930 | 0.0277687 | 1.12201 | 1.12201 | 0.109131 | 0.109131
22_Wand_Binnenwand | 01 eerste verdieping | 0 | 264 | 3930 | 0.0234313 | 1.01296 | 1.01296 | 0.0920848 | 0.0920848
22_Wand_Binnenwand | 01 eerste verdieping | 0 | 776.208 | 3930 | 0.0776207 | 3.0505 | 3.0505 | 0.30505 | 0.30505
22_Wand_Binnenwand | 01 eerste verdieping | 0 | 178.792 | 3930 | 0.0208479 | 0.850026 | 0.850026 | 0.0819323 | 0.0819323
22_Wand_Binnenwand | 01 eerste verdieping | 0 | 285.49 | 3930 | 0.0255803 | 0.957628 | 0.957628 | 0.0795628 | 0.0795628

# IfcWall: MS125 2.75.2A 125 (65)
Classification: Wand (ARCHICAD Classification); 22.21 MASSIEVE WANDEN (NL/SfB (4 cijfers))
Pset_WallCommon - LoadBearing: no; IsExternal: no
CPset_Phasing - Renovation Phase: Bestaand
BaseQuantities - Width: 125 mm
Name | In | FireRating = SurfaceSpreadOfFlame | Length (mm) | Height (mm) | GrossFootprintArea (m2) = NetFootprintArea (m2) | GrossSideArea (m2) | NetSideArea (m2) | GrossVolume (m3) | NetVolume (m3)
22_Wand_Binnenwand | 00 begane grond | 60 | 3590 | 3740 | 0.44875 | 13.4266 | 13.4266 | 1.67832 | 1.67832 | Pset_WallCommon - Compartmentation: yes
22_Wand_Binnenwand | 00 begane grond | 60 | 3535 | 3740 | 0.441875 | 13.2209 | 13.2209 | 1.65261 | 1.65261 | Pset_WallCommon - Compartmentation: yes
22_Wand_Binnenwand | 00 begane grond | 60 | 2239.2 | 3740 | 0.283025 | 8.39799 | 8.39799 | 1.05851 | 1.05851 | Pset_WallCommon - Compartmentation: yes
22_Wand_Binnenwand | 00 begane grond | 60 | 3119 | 3680 | 0.389875 | 11.4779 | 11.4779 | 1.43474 | 1.43474 | Pset_WallCommon - Compartmentation: yes
22_Wand_Binnenwand | 00 begane grond | 0 | 1405 | 3740 | 0.175625 | 5.2547 | 5.2547 | 0.656837 | 0.656837
22_Wand_Binnenwand | 00 begane grond | 0 | 3820 | 3740 | 0.4775 | 14.2868 | 6.4757 | 1.78585 | 0.809462
22_Wand_Binnenwand | 00 begane grond | 0 | 1935 | 4485 | 0.241875 | 8.67848 | 8.67848 | 1.08481 | 1.08481
22_Wand_Binnenwand | 00 begane grond | 0 | 5970 | 1283 | 0 | 26.7754 | 7.65951 | 3.34693 | 0.957439
22_Wand_Binnenwand | 00 begane grond | 0 | 1725 | 4485 | 0.215625 | 7.73663 | 7.73663 | 0.967078 | 0.967078
22_Wand_Binnenwand | 00 begane grond | 0 | 7088.89 | 3740 | 0.886112 | 26.5125 | 21.6175 | 3.31406 | 2.70219
22_Wand_Binnenwand | 00 begane grond | 0 | 8275 | 3740 | 1.03437 | 30.9485 | 27.7921 | 3.86856 | 3.47401
22_Wand_Binnenwand | 00 begane grond | 0 | 2701.81 | 3740 | 0.338039 | 9.70739 | 7.25991 | 1.26426 | 0.95833
22_Wand_Binnenwand | 00 begane grond | 0 | 3095 | 3740 | 0.386875 | 11.5753 | 9.12782 | 1.44691 | 1.14098
22_Wand_Binnenwand | 00 begane grond | 0 | 3755 | 3740 | 0.469375 | 14.0437 | 11.5962 | 1.75546 | 1.44953
22_Wand_Binnenwand | 00 begane grond | 0 | 1400.19 | 3740 | 0.175336 | 4.83932 | 2.39184 | 0.655756 | 0.349821
22_Wand_Binnenwand | 00 begane grond | 60 | 2049.16 | 3740 | 0.25927 | 7.68722 | 7.68722 | 0.969669 | 0.969669 | Pset_WallCommon - Compartmentation: yes
22_Wand_Binnenwand | 00 begane grond | 0 | 2676 | 3740 | 0.337625 | 10.0316 | 7.58414 | 1.26272 | 0.956783
22_Wand_Binnenwand | 00 begane grond | 60 | 2731 | 3740 | 0.341375 | 10.2139 | 10.2139 | 1.27674 | 1.27674 | Pset_WallCommon - Compartmentation: yes
22_Wand_Binnenwand | 00 begane grond | 0 | 3307.62 | 3740 | 0.407203 | 12.3238 | 12.3238 | 1.52294 | 1.52294
2 x 22_Wand_Binnenwand | 00 begane grond | 0 | 2774.92 | 3740 | 0.346865 | 10.3782 | 10.3782 | 1.29728 | 1.29728
22_Wand_Binnenwand | 00 begane grond | 0 | 7032.5 | 3740 | 0.879062 | 26.3015 | 23.9346 | 3.28769 | 2.99182
22_Wand_Binnenwand | 00 begane grond | 0 | 3528.72 | 3740 | 0.441089 | 13.1974 | 13.1974 | 1.64967 | 1.64967
22_Wand_Binnenwand | 00 begane grond | 0 | 3431.3 | 3740 | 0.118288 | 12.8331 | 6.72743 | 1.60413 | 0.840929
22_Wand_Binnenwand | 00 begane grond | 0 | 2567.7 | 3740 | 0.0134621 | 9.62656 | 3.52092 | 1.21209 | 0.44888
22_Wand_Binnenwand | 00 begane grond | 0 | 2793.5 | 3740 | 0.352312 | 10.4711 | 8.60386 | 1.31765 | 1.08425
22_Wand_Binnenwand | 00 begane grond | 0 | 3515.21 | 3740 | 0.439402 | 13.1469 | 13.1469 | 1.64336 | 1.64336
22_Wand_Binnenwand | 00 begane grond | 0 | 3452.5 | 3740 | 0.120938 | 12.9124 | 6.80672 | 1.61405 | 0.85084
22_Wand_Binnenwand | 00 begane grond | 0 | 2547.5 | 3740 | 0.0109375 | 9.55102 | 3.44538 | 1.20264 | 0.439438
22_Wand_Binnenwand | 00 begane grond | 0 | 2554.51 | 3740 | 0.322439 | 9.57726 | 7.71006 | 1.20592 | 0.972523
22_Wand_Binnenwand | 00 begane grond | 0 | 7045.19 | 3740 | 0.880648 | 26.349 | 23.982 | 3.29362 | 2.99775
2 x 22_Wand_Binnenwand | 00 begane grond | 0 | 450 | 3740 | 0.05 | 1.63625 | 1.63625 | 0.187 | 0.187
22_Wand_Binnenwand | 00 begane grond | 60 | 5532.49 | 3740 | 0.691562 | 20.6915 | 16.8451 | 2.58644 | 2.10564 | Pset_WallCommon - Compartmentation: yes
22_Wand_Binnenwand | 00 begane grond | 0 | 2850.05 | 3740 | 0.350006 | 10.6124 | 10.6124 | 1.30902 | 1.30902
22_Wand_Binnenwand | 00 begane grond | 60 | 3594.9 | 3740 | 0.446238 | 13.4216 | 6.89626 | 1.66893 | 0.853214 | Pset_WallCommon - Compartmentation: yes
22_Wand_Binnenwand | 00 begane grond | 0 | 238.986 | 3740 | 0.0298732 | 0.893807 | 0.893807 | 0.111726 | 0.111726
22_Wand_Binnenwand | 00 begane grond | 60 | 2005.38 | 3740 | 0.253641 | 7.50012 | 7.50012 | 0.948619 | 0.948619 | Pset_WallCommon - Compartmentation: yes
22_Wand_Binnenwand | 00 begane grond | 60 | 2200 | 3740 | 0.275 | 8.228 | 8.228 | 1.0285 | 1.0285 | Pset_WallCommon - Compartmentation: yes
22_Wand_Binnenwand | 00 begane grond | 60 | 2262.31 | 3740 | 0.285602 | 8.88181 | 6.43433 | 1.06815 | 0.762216 | Pset_WallCommon - Compartmentation: yes
22_Wand_Binnenwand | 01 eerste verdieping | 0 | 6760 | 3930 | 0.845 | 26.5668 | 26.5668 | 3.32085 | 3.32085
22_Wand_Binnenwand | 01 eerste verdieping | 0 | 5649.97 | 3930 | 0.395621 | 22.2044 | 16.0987 | 2.77555 | 2.01234
22_Wand_Binnenwand | 01 eerste verdieping | 0 | 1500.03 | 3930 | 0.187504 | 5.89512 | 4.72812 | 0.73689 | 0.591015
22_Wand_Binnenwand | 01 eerste verdieping | 0 | 4568.52 | 3930 | 0.571065 | 17.9543 | 14.6867 | 2.24428 | 1.83583
22_Wand_Binnenwand | 01 eerste verdieping | 0 | 5868.72 | 3930 | 0.11234 | 23.0641 | 10.8528 | 2.88301 | 1.3566
22_Wand_Binnenwand | 01 eerste verdieping | 0 | 232 | 3930 | 0.025875 | 0.887197 | 0.887197 | 0.101689 | 0.101689
22_Wand_Binnenwand | 01 eerste verdieping | 0 | 3912.76 | 3930 | 0.489095 | 15.3772 | 12.1096 | 1.92214 | 1.51369
22_Wand_Binnenwand | 01 eerste verdieping | 0 | 3881.63 | 3930 | 0.487392 | 15.2794 | 9.39739 | 1.91545 | 1.1802
22_Wand_Binnenwand | 01 eerste verdieping | 0 | 3197.17 | 3930 | 0.399647 | 12.5649 | 8.69325 | 1.57061 | 1.08666
22_Wand_Binnenwand | 01 eerste verdieping | 0 | 5758.99 | 3930 | 0.719874 | 22.6328 | 22.6328 | 2.8291 | 2.8291
22_Wand_Binnenwand | 01 eerste verdieping | 0 | 4715.02 | 3930 | 0.595627 | 18.5791 | 15.3115 | 2.34081 | 1.93236
22_Wand_Binnenwand | 01 eerste verdieping | 0 | 3725 | 3930 | 0.465625 | 14.6393 | 8.75726 | 1.82991 | 1.09466
22_Wand_Binnenwand | 01 eerste verdieping | 0 | 3755 | 3930 | 0.469375 | 14.7571 | 8.87515 | 1.84464 | 1.10939
22_Wand_Binnenwand | 01 eerste verdieping | 0 | 3095 | 3930 | 0.386875 | 12.1634 | 12.1634 | 1.52042 | 1.52042
22_Wand_Binnenwand | 01 eerste verdieping | 0 | 3939 | 3930 | 0.492375 | 15.4803 | 15.4803 | 1.93503 | 1.93503
22_Wand_Binnenwand | 01 eerste verdieping | 0 | 5882.5 | 3930 | 0.735312 | 23.1182 | 19.1097 | 2.88978 | 2.38871
22_Wand_Binnenwand | 01 eerste verdieping | 0 | 4866 | 3930 | 0.60825 | 19.1234 | 9.00796 | 2.39042 | 1.12599
22_Wand_Binnenwand | 01 eerste verdieping | 0 | 6410.5 | 3930 | 0.798187 | 25.1687 | 25.1687 | 3.13688 | 3.13688
22_Wand_Binnenwand | 01 eerste verdieping | 0 | 584.674 | 3930 | 0.0730842 | 2.29777 | 2.29777 | 0.287221 | 0.287221
22_Wand_Binnenwand | 01 eerste verdieping | 0 | 4755.45 | 3930 | 0.594431 | 18.6889 | 18.6889 | 2.33612 | 2.33612
22_Wand_Binnenwand | 01 eerste verdieping | 0 | 1396.3 | 3930 | 0.174538 | 5.48747 | 5.48747 | 0.685934 | 0.685934
22_Wand_Binnenwand | 01 eerste verdieping | 0 | 4778.82 | 3930 | 0.597353 | 18.7808 | 18.7808 | 2.3476 | 2.3476
22_Wand_Binnenwand | 01 eerste verdieping | 0 | 588.355 | 3930 | 0.0735444 | 2.31224 | 2.31224 | 0.28903 | 0.28903
22_Wand_Binnenwand | 01 eerste verdieping | 0 | 1420.35 | 3930 | 0.177544 | 5.58197 | 5.58197 | 0.697747 | 0.697747
22_Wand_Binnenwand | 01 eerste verdieping | 0 | 3639.44 | 3930 | 0.45493 | 14.303 | 8.42101 | 1.78788 | 1.05263

# IfcWall: MS75 50.2A 75 (45)
Classification: Wand (ARCHICAD Classification); 22.21 MASSIEVE WANDEN (NL/SfB (4 cijfers))
Pset_WallCommon - FireRating: 0; SurfaceSpreadOfFlame: 0; LoadBearing: no; IsExternal: no
CPset_Phasing - Renovation Phase: Bestaand
BaseQuantities - Width: 75 mm
Name | In | Length (mm) | Height (mm) | GrossFootprintArea (m2) = NetFootprintArea (m2) | GrossSideArea (m2) | NetSideArea (m2) | GrossVolume (m3) | NetVolume (m3)
22_Wand_koof | 00 begane grond | 1250 | 778.004 | 0.0814299 | 0.947809 | 0.947809 | 0.0703714 | 0.0703714
22_Wand_Binnenwand | 00 begane grond | 1710 | 1323.69 | 0.12825 | 1.11582 | 1.11582 | 0.0836946 | 0.0836946
22_Wand_koof | 00 begane grond | 3774.85 | 1430.02 | 0.283114 | 5.34527 | 5.34527 | 0.399574 | 0.399574
22_Wand_koof | 00 begane grond | 234.6 | 970 | 0.0159531 | 0.220792 | 0.220792 | 0.0162168 | 0.0162168
22_Wand_koof | 00 begane grond | 236.852 | 970 | 0.0153953 | 0.223351 | 0.223351 | 0.0165678 | 0.0165678
22_Wand_Binnenwand | 00 begane grond | 1016.99 | 1195.56 | 0.0762743 | 1.18568 | 1.18568 | 0.0889257 | 0.0889257
22_Wand_Binnenwand | 00 begane grond | 2053.66 | 5190 | 0.154025 | 10.6585 | 10.6585 | 0.799389 | 0.799389
22_Wand_Binnenwand | 00 begane grond | 3324.56 | 3740 | 0.244342 | 12.2469 | 12.2469 | 0.91384 | 0.91384
22_Wand_Binnenwand | 00 begane grond | 1940.11 | 3740 | 0.145509 | 7.25603 | 7.25603 | 0.544202 | 0.544202
22_Wand_Binnenwand | 00 begane grond | 975.655 | 3650 | 0.0731742 | 3.56114 | 3.56114 | 0.267086 | 0.267086
2 x 22_Wand_Binnenwand | 00 begane grond | 975.655 | 2367 | 0.0731742 | 2.30938 | 2.30938 | 0.173203 | 0.173203
22_Wand_Binnenwand | 00 begane grond | 993.152 | 3650 | 0.0744864 | 3.62501 | 3.62501 | 0.271875 | 0.271875
22_Wand_Binnenwand | 00 begane grond | 993.152 | 2367 | 0.0744864 | 2.35079 | 2.35079 | 0.176309 | 0.176309
22_Wand_Binnenwand | 00 begane grond | 883.152 | 3650 | 0.0662364 | 3.22351 | 3.22351 | 0.241763 | 0.241763
22_Wand_Binnenwand | 00 begane grond | 858.155 | 3650 | 0.0643617 | 3.13227 | 3.13227 | 0.23492 | 0.23492
22_Wand_Binnenwand | 00 begane grond | 1006.06 | 2367 | 0.0754544 | 2.38134 | 2.38134 | 0.178601 | 0.178601
22_Wand_koof | 00 begane grond | 2222.86 | 970 | 0.144686 | 2.09636 | 2.09636 | 0.155511 | 0.155511
22_Wand_koof | 00 begane grond | 265.007 | 624 | 0.0198756 | 0.165365 | 0.165365 | 0.0124023 | 0.0124023
22_Wand_Binnenwand | 00 begane grond | 1049.53 | 3740 | 0.0787149 | 3.92525 | 3.92525 | 0.294394 | 0.294394
22_Wand_Binnenwand | 00 begane grond | 1084 | 3740 | 0.0813 | 4.05416 | 4.05416 | 0.304062 | 0.304062
22_Wand_Binnenwand | 00 begane grond | 277.5 | 3740 | 0.0178437 | 0.874225 | 0.874225 | 0.0667356 | 0.0667356
22_Wand_Binnenwand | 00 begane grond | 879.5 | 3650 | 0.0673688 | 3.30143 | 3.30143 | 0.245896 | 0.245896
22_Wand_Binnenwand | 00 begane grond | 112.5 | 3650 | 0.00703125 | 0.387813 | 0.387813 | 0.0256641 | 0.0256641
22_Wand_Binnenwand | 00 begane grond | 1405 | 3740 | 0.105375 | 5.2547 | 5.2547 | 0.394103 | 0.394103
22_Wand_Binnenwand | 00 begane grond | 879.5 | 3740 | 0.0673688 | 3.38283 | 3.38283 | 0.251959 | 0.251959
22_Wand_Binnenwand | 00 begane grond | 87.5 | 3740 | 0.00515625 | 0.303875 | 0.303875 | 0.0192844 | 0.0192844
22_Wand_Binnenwand | 00 begane grond | 787.5 | 3740 | 0.0571875 | 2.8985 | 2.8985 | 0.213881 | 0.213881
22_Wand_Binnenwand | 00 begane grond | 357.783 | 3740 | 0.0254275 | 1.31473 | 1.31473 | 0.0950988 | 0.0950988
22_Wand_Binnenwand | 00 begane grond | 215 | 3650 | 0.016125 | 0.78475 | 0.78475 | 0.0588562 | 0.0588562
22_Wand_Binnenwand | 00 begane grond | 214.699 | 3650 | 0.0161024 | 0.783652 | 0.783652 | 0.0587739 | 0.0587739
22_Wand_koof | 00 begane grond | 8501.17 | 1420.02 | 0.637588 | 11.957 | 11.957 | 0.893906 | 0.893906
22_Wand_Binnenwand | 00 begane grond | 3118.9 | 200 | 0.233917 | 0.62378 | 0.62378 | 0.0467835 | 0.0467835
22_Wand_Binnenwand | 00 begane grond | 237.376 | 3650 | 0.0178032 | 0.866423 | 0.866423 | 0.0649817 | 0.0649817
22_Wand_Binnenwand | 00 begane grond | 236.699 | 3650 | 0.0177524 | 0.863952 | 0.863952 | 0.0647964 | 0.0647964
22_Wand_Binnenwand | 01 eerste verdieping | 3074 | 3930 | 0.23055 | 12.0808 | 12.0808 | 0.906061 | 0.906061
22_Wand_koof | 01 eerste verdieping | 1120.22 | 2100 | 0.0840163 | 2.35246 | 2.35246 | 0.176434 | 0.176434
22_Wand_koof | 01 eerste verdieping | 5170.23 | 640 | 0.389173 | 3.31224 | 3.31224 | 0.249018 | 0.249018
22_Wand_koof | 01 eerste verdieping | 1125.7 | 2100 | 0.0841535 | 2.35822 | 2.35822 | 0.176722 | 0.176722
22_Wand_Binnenwand | 01 eerste verdieping | 912.377 | 3930 | 0.0698345 | 3.68389 | 3.68389 | 0.27445 | 0.27445
22_Wand_Binnenwand | 01 eerste verdieping | 112.5 | 3930 | 0.00703125 | 0.417563 | 0.417563 | 0.0276328 | 0.0276328
22_Wand_Binnenwand | 01 eerste verdieping | 87.5 | 3930 | 0.0142188 | 0.442125 | 0.49475 | 0.0313172 | 0.0365797
22_Wand_Binnenwand | 01 eerste verdieping | 817 | 3930 | 0.061275 | 3.2845 | 3.2845 | 0.240811 | 0.240811
22_Wand_Binnenwand | 01 eerste verdieping | 87.5 | 3930 | 0.0114062 | 0.319312 | 0.371937 | 0.0202641 | 0.0255266
22_Wand_koof | 01 eerste verdieping | 982.511 | 640 | 0.0722672 | 0.596382 | 0.596382 | 0.04617 | 0.04617

# IfcWall: MS75 afw bwb 33, 22_Wand_koof
In: 01 eerste verdieping
Classification: Wand (ARCHICAD Classification); 22.21 MASSIEVE WANDEN (NL/SfB (4 cijfers))
Pset_WallCommon - FireRating: 0; SurfaceSpreadOfFlame: 0; LoadBearing: no; IsExternal: no
CPset_Phasing - Renovation Phase: Bestaand
BaseQuantities - Length: 237.464 mm; Height: 2100 mm; Width: 32.5 mm; GrossFootprintArea: 0.00771757 m2; NetFootprintArea: 0.00771757 m2; GrossSideArea: 0.498674 m2; NetSideArea: 0.498674 m2; GrossVolume: 0.0162069 m3; NetVolume: 0.0162069 m3

# IfcWall: R1 25 (3)
In: 00 begane grond
Type - ElementType: MOVABLE; PredefinedType: USERDEFINED
Classification: Schuifwand (ARCHICAD Classification); 22.14 SYSTEEMWANDEN VERPLAATSBAAR (NL/SfB (4 cijfers))
Pset_WallCommon - SurfaceSpreadOfFlame: 0; ThermalTransmittance: 0
CPset_Phasing - Renovation Phase: Bestaand
BaseQuantities - Height: 2292 mm; Width: 1240 mm; GrossSideArea: 2.84208 m2; NetSideArea: 2.84208 m2; GrossVolume: 0.0111744 m3; NetVolume: 0.0111744 m3
Component Quantities - Component, Component Volume (Net): 0.0111744 m3; Component, Component Volume (Gross): 0.0111744 m3
Name
22_Schuifwand_P-03
2 x 22_Schuifwand_P-02

# IfcWall: Steen - Baksteen Accent 100 (7)
Classification: Wand (ARCHICAD Classification); 21.12 SPOUWWANDEN (NL/SfB (4 cijfers)); Material: Steen - Baksteen Accent
Pset_WallCommon - FireRating: 0; SurfaceSpreadOfFlame: 0; LoadBearing: no; IsExternal: yes
CPset_Phasing - Renovation Phase: Bestaand
BaseQuantities - Width: 100 mm
Component Quantities - Steen - Baksteen Accent, Component Thickness: 100 mm; Steen - Baksteen Accent, Rectangular Component Width: 100 mm
Name | In | Length (mm) | Height (mm) = Steen - Baksteen Accent, Rectangular Component Height (mm) | GrossFootprintArea (m2) = NetFootprintArea (m2) | GrossSideArea (m2) = NetSideArea (m2) | GrossVolume (m3) = NetVolume (m3) = Steen - Baksteen Accent, Component Volume (Net) (m3) = Steen - Baksteen Accent, Component Volume (Gross) (m3) | Steen - Baksteen Accent, Mass (kg) | Steen - Baksteen Accent, Projected Component Area (Net) (m2) = Steen - Baksteen Accent, Projected Component Area (Gross) (m2) | Steen - Baksteen Accent, Component Cross Section Area (m2)
21_Wand_Kantplank | -1 fundering | 15310.1 | 1460 | 1.518 | 22.1628 | 2.21626 | 3546.02 | 22.1628 | 0.146
21_Wand_Kantplank | -1 fundering | 11589 | 1460 | 1.1539 | 16.841 | 1.68406 | 2694.5 | 16.8468 | 0.146
21_Wand_Kantplank | -1 fundering | 1460.98 | 1460 | 0.141098 | 2.05933 | 0.205932 | 329.491 | 2.06004 | 0.146
21_Wand_Kantplank | -1 fundering | 1820 | 410 | 0.187 | 0.7667 | 0.07667 | 122.672 | 0.7667 | 0.041
21_Wand_Kantplank | -1 fundering | 260 | 1460 | 0.026 | 0.379547 | 0.0379547 | 60.7274 | 0.379547 | 0.146
21_Wand_Kantplank | -1 fundering | 210 | 1460 | 0.026 | 0.338549 | 0.0338549 | 54.1679 | 0.338549 | 0.146
21_Wand_sandwichplaat | 00 begane grond | 24807 | 1458.78 | 2.4757 | 36.1027 | 3.61029 | 5776.47 | 36.1149 | 0.145878

# IfcWall: Steen - Kalkzandsteen C 100 (14)
Classification: Wand (ARCHICAD Classification); 22.21 MASSIEVE WANDEN (NL/SfB (4 cijfers)); Material: Steen - Kalkzandsteen C
Pset_WallCommon - FireRating: 0; SurfaceSpreadOfFlame: 0; LoadBearing: yes; IsExternal: no
CPset_Phasing - Renovation Phase: Bestaand
BaseQuantities - Width: 100 mm
Component Quantities - Steen - Kalkzandsteen C, Component Thickness: 100 mm; Steen - Kalkzandsteen C, Rectangular Component Width: 100 mm
Name | In | Length (mm) | Height (mm) | GrossFootprintArea (m2) = NetFootprintArea (m2) | GrossSideArea (m2) | NetSideArea (m2) | GrossVolume (m3) = Steen - Kalkzandsteen C, Component Volume (Gross) (m3) | NetVolume (m3) = Steen - Kalkzandsteen C, Component Volume (Net) (m3) | Steen - Kalkzandsteen C, Mass (kg) | Steen - Kalkzandsteen C, Projected Component Area (Net) (m2) | Steen - Kalkzandsteen C, Projected Component Area (Gross) (m2) | Steen - Kalkzandsteen C, Rectangular Component Height (mm) | Steen - Kalkzandsteen C, Component Cross Section Area (m2)
22_Wand_KZST | -1 fundering | 6900 | 1450 | 0.68 | 9.86 | 9.86 | 0.986 | 0.986 | 1873.4 | 9.86 | 9.86 | 1450 | 0.145
22_Wand_KZST | -1 fundering | 6775 | 1450 | 0.6775 | 9.74463 | 9.74463 | 0.974463 | 0.974463 | 1851.48 | 9.74463 | 9.74463 | 1450 | 0.145
22_Wand_KZST | -1 fundering | 6800 | 1450 | 0.68 | 9.86 | 9.86 | 0.986 | 0.986 | 1873.4 | 9.86 | 9.86 | 1450 | 0.145
22_Wand_KZST | 00 begane grond | 1033 | 3214 | 0.1033 | 3.11604 | 3.11604 | 0.311196 | 0.311196 | 591.273 | 3.32006 | 3.32006 | 3214 | 0.3214
22_Wand_KZST | 00 begane grond | 4611 | 7381.72 | 0.4611 | 33.9181 | 30.7285 | 3.38578 | 3.06683 | 5826.97 | 30.7309 | 33.9205 | 7381.72 | 0.738172
22_Wand_KZST | 00 begane grond | 3530 | 3214 | 0.22244 | 10.6482 | 3.43161 | 1.06343 | 0.341766 | 649.356 | 4.12878 | 11.3454 | 3214 | 0.3214
22_Wand_KZST | 00 begane grond | 5714 | 4025 | 0.440831 | 21.7476 | 12.6087 | 2.16752 | 1.25585 | 2386.11 | 13.7452 | 22.8905 | 4025 | 0.4025
22_Wand_KZST | 00 begane grond | 248.899 | 3986.31 | 0.0248899 | 0.992187 | 0.992187 | 0.0992187 | 0.0992187 | 188.515 | 0.992187 | 0.992187 | 3986.31 | 0.398631
22_Wand_KZST | 00 begane grond | 4100 | 2990 | 0.41 | 12.259 | 12.259 | 1.2259 | 1.2259 | 2329.21 | 12.259 | 12.259 | 3385 | 0.3385
22_Wand_KZST | 00 begane grond | 4611 | 7381.72 | 0.4611 | 33.9523 | 33.9523 | 3.38897 | 3.38897 | 6439.03 | 33.9523 | 33.9523 | 7381.72 | 0.738172
22_Wand_KZST | 00 begane grond | 4792 | 6855 | 0.4792 | 32.8492 | 32.8492 | 3.28492 | 3.28492 | 6241.34 | 32.8492 | 32.8492 | 6855 | 0.6855
22_Wand_KZST | 00 begane grond | 1407 | 3214 | 0.1407 | 4.24422 | 4.24422 | 0.423866 | 0.423866 | 805.345 | 4.5221 | 4.5221 | 3214 | 0.3214
22_Wand_KZST | 01 eerste verdieping | 1759.99 | 3930 | 0.175999 | 6.91509 | 6.91509 | 0.691509 | 0.691509 | 1313.87 | 6.91509 | 6.91509 | 3990 | 0.399
22_Wand_KZST | 01 eerste verdieping | 165 | 2440 | 0.009 | 0.218073 | 0.218073 | 0.0218073 | 0.0218073 | 41.4339 | 0.218073 | 0.218073 | 2477 | 0.2477

# IfcWall: Steen - Kalkzandsteen C 150 (21)
Classification: Wand (ARCHICAD Classification); 22.21 MASSIEVE WANDEN (NL/SfB (4 cijfers)); Material: Steen - Kalkzandsteen C
Pset_WallCommon - LoadBearing: yes; IsExternal: no
CPset_Phasing - Renovation Phase: Bestaand
BaseQuantities - Width: 150 mm
Component Quantities - Steen - Kalkzandsteen C, Component Thickness: 150 mm; Steen - Kalkzandsteen C, Rectangular Component Width: 150 mm
Name | In | FireRating = SurfaceSpreadOfFlame | Length (mm) | Height (mm) | GrossFootprintArea (m2) = NetFootprintArea (m2) | GrossSideArea (m2) | NetSideArea (m2) | GrossVolume (m3) = Steen - Kalkzandsteen C, Component Volume (Gross) (m3) | NetVolume (m3) | Steen - Kalkzandsteen C, Mass (kg) | Steen - Kalkzandsteen C, Projected Component Area (Net) (m2) | Steen - Kalkzandsteen C, Projected Component Area (Gross) (m2) | Steen - Kalkzandsteen C, Rectangular Component Height (mm) | Steen - Kalkzandsteen C, Component Cross Section Area (m2) | Steen - Kalkzandsteen C, Component Volume (Net) (m3)
22_Wand_KZST | -1 fundering | 0 | 7225 | 1450 | 1.02 | 9.86 | 9.86 | 1.479 | 1.479 | 2810.1 | 9.86 | 9.86 | 1450 | 0.2175 | 1.479
22_Wand_KZST | -1 fundering | 0 | 7539 | 1450 | 1.02 | 9.86 | 9.86 | 1.479 | 1.479 | 2810.1 | 9.86 | 9.86 | 1450 | 0.2175 | 1.479
22_Wand_KZST | -1 fundering | 0 | 685.007 | 1055 | 0.110251 | 0.775433 | 0.775433 | 0.116315 | 0.116315 | 220.998 | 0.775433 | 0.775433 | 1055 | 0.15825 | 0.116315
22_Wand_KZST | -1 fundering | 0 | 1190.01 | 1450 | 0.152251 | 1.47176 | 1.47176 | 0.220764 | 0.220764 | 419.452 | 1.47176 | 1.47176 | 1450 | 0.2175 | 0.220764
22_Wand_KZST | -1 fundering | 0 | 6800 | 1450 | 1.03125 | 8.97869 | 8.97869 | 1.24661 | 1.24661 | 2368.57 | 9.88962 | 9.88962 | 1450 | 0.2175 | 1.24661
22_Wand_KZST | 00 begane grond | 0 | 14584 | 4135 | 2.1651 | 59.6846 | 57.2371 | 8.95269 | 8.58557 | 16312.6 | 57.2371 | 59.6846 | 4135 | 0.62025 | 8.58557
22_Wand_KZST | 00 begane grond | 0 | 7259 | 5585 | 1.08885 | 40.4774 | 35.5824 | 6.07156 | 5.33733 | 10140.9 | 35.5824 | 40.4774 | 5585 | 0.83775 | 5.33732
22_Wand_KZST | 00 begane grond | 0 | 4727.99 | 4135 | 0.812601 | 21.0002 | 21.0002 | 3.15297 | 3.15297 | 5990.65 | 21.0198 | 21.0198 | 4135 | 0.62025 | 3.15297
22_Wand_KZST | 00 begane grond | 60 | 7045 | 3740 | 1.05675 | 26.3483 | 26.3483 | 3.95225 | 3.95225 | 7509.27 | 26.3483 | 26.3483 | 3740 | 0.561 | 3.95225 | Pset_WallCommon - Compartmentation: yes
22_Wand_KZST | 00 begane grond | 60 | 7200 | 3740 | 1.08 | 26.928 | 26.928 | 4.0392 | 4.0392 | 7674.48 | 26.928 | 26.928 | 3740 | 0.561 | 4.0392 | Pset_WallCommon - Compartmentation: yes
22_Wand_KZST | 00 begane grond | 0 | 4385.99 | 4425 | 0.367799 | 19.3902 | 14.8124 | 2.90852 | 2.22186 | 4221.53 | 14.8124 | 19.3902 | 4425 | 0.66375 | 2.22186
22_Wand_KZST | 00 begane grond | 0 | 8996.39 | 4075 | 1.34946 | 36.601 | 36.601 | 5.49845 | 5.49845 | 10447.1 | 36.6603 | 36.6603 | 4075 | 0.61125 | 5.49845
22_Wand_KZST | 00 begane grond | 0 | 4477 | 4425 | 0.67155 | 17.8655 | 17.8655 | 2.75788 | 2.75788 | 5239.98 | 18.4089 | 18.4089 | 4425 | 0.66375 | 2.75788
22_Wand_KZST | 01 eerste verdieping | 60 | 10064.4 | 2432.1 | 1.50965 | 24.4776 | 24.4776 | 3.67164 | 3.67164 | 6976.11 | 24.4776 | 24.4776 | 2432.1 | 0.364816 | 3.67164 | Pset_WallCommon - Compartmentation: yes
22_Wand_KZST | 01 eerste verdieping | 0 | 7259 | 3000 | 1.08885 | 21.581 | 21.581 | 3.26649 | 3.26649 | 6206.33 | 21.777 | 21.777 | 3000 | 0.45 | 3.26649
22_Wand_KZST | 01 eerste verdieping | 0 | 7452.95 | 2315 | 0.0649859 | 16.8625 | 4.56185 | 2.52956 | 0.684462 | 1300.48 | 4.77264 | 17.0733 | 2315 | 0.34725 | 0.684462
22_Wand_KZST | 01 eerste verdieping | 0 | 9121.49 | 3930 | 1.36822 | 35.8413 | 35.8413 | 5.37619 | 5.37619 | 10214.8 | 35.8413 | 35.8413 | 3930 | 0.5895 | 5.37619
22_Wand_KZST | 01 eerste verdieping | 0 | 7336.84 | 3930 | 0.950541 | 28.8338 | 26.644 | 4.32507 | 3.9966 | 7593.54 | 26.644 | 28.8338 | 3930 | 0.5895 | 3.9966
22_Wand_KZST | 01 eerste verdieping | 0 | 1145.22 | 2440 | 0.171785 | 2.76741 | 0.84021 | 0.416552 | 0.127472 | 242.196 | 0.851748 | 2.77895 | 2500 | 0.375 | 0.127472
22_Wand_KZST | 01 eerste verdieping | 0 | 174.964 | 2440 | 0.0337457 | 0.5434 | 0.5434 | 0.0818057 | 0.0818057 | 155.431 | 0.545762 | 0.545762 | 2477 | 0.37155 | 0.0818057
22_Wand_KZST | 01 eerste verdieping | 30 | 6021.5 | 2432.1 | 0.903225 | 14.6449 | 14.6449 | 2.19674 | 2.19674 | 4173.8 | 14.6449 | 14.6449 | 2432.1 | 0.364816 | 2.19674 | Pset_WallCommon - Compartmentation: yes

# IfcWall: Steen - Kalkzandsteen C 214, 21_Wand_KZST
In: 00 begane grond
Classification: Wand (ARCHICAD Classification); 21.21 MASSIEVE WANDEN (NL/SfB (4 cijfers)); Material: Steen - Kalkzandsteen C
Pset_WallCommon - FireRating: 0; SurfaceSpreadOfFlame: 0; LoadBearing: yes; IsExternal: yes
CPset_Phasing - Renovation Phase: Bestaand
BaseQuantities - Length: 3401.21 mm; Height: 395 mm; Width: 214 mm; GrossFootprintArea: 0.727859 m2; NetFootprintArea: 0.727859 m2; GrossSideArea: 1.34348 m2; NetSideArea: 1.34348 m2; GrossVolume: 0.287504 m3; NetVolume: 0.287504 m3
Component Quantities - Steen - Kalkzandsteen C, Mass: 546.258 kg; Steen - Kalkzandsteen C, Projected Component Area (Net): 1.34348 m2; Steen - Kalkzandsteen C, Projected Component Area (Gross): 1.34348 m2; Steen - Kalkzandsteen C, Component Thickness: 214 mm; Steen - Kalkzandsteen C, Rectangular Component Height: 395 mm; Steen - Kalkzandsteen C, Rectangular Component Width: 214 mm; Steen - Kalkzandsteen C, Component Cross Section Area: 0.08453 m2; Steen - Kalkzandsteen C, Component Volume (Net): 0.287504 m3; Steen - Kalkzandsteen C, Component Volume (Gross): 0.287504 m3

# IfcWindow: ALG - ALGEMEEN, 37_Daklicht_dakluik
In: 01 eerste verdieping
Type - ParameterTakesPrecedence: no; Sizeable: no
Classification: Daklicht (ARCHICAD Classification); 37.20 ALGEMEEN (NL/SfB (4 cijfers)); Material: ALG - ALGEMEEN
Pset_WindowCommon - FireRating: 0; IsExternal: yes
CPset_Phasing - Renovation Phase: Bestaand
Component Quantities - ALG - ALGEMEEN, Mass: 0 kg; ALG - ALGEMEEN, Component Volume (Net): 0 m3; ALG - ALGEMEEN, Component Volume (Gross): 0 m3

# IfcWindow: R1 25 (36)
Type - OperationType: DOUBLE_PANEL_HORIZONTAL; ParameterTakesPrecedence: no; Sizeable: no
Pset_WindowCommon - Reference: 31_n.v.t.; FireRating: 0; ThermalTransmittance: 0; IsExternal: yes
Material - Afwerking dagkant binnen: n.v.t.; Afwerking dagkant buiten: n.v.t.; Draaiend deel: n.v.t.; Frame: n.v.t.; Onderdorpel: n.v.t.; Rollaag / latei: n.v.t.; Spouwlat: n.v.t.; Vensterbank: n.v.t.; Ventilatierooster: n.v.t.; Zonwering - behuizing: n.v.t.; Zonwering - isolatie: n.v.t.; Glas: Glas - algemeen
CPset_Phasing - Renovation Phase: Bestaand
Name | In | OverallHeight (mm) | OverallWidth (mm) | Classification | GlazingAreaFraction | GrossArea (m2) = Area (m2) | Height (mm) | Width (mm) | Perimeter (mm) | Volume (m3) = NetVolume (m3) = Component, Component Volume (Net) (m3) = Component, Component Volume (Gross) (m3) | Depth (mm)
2 x 31_Raam_A.09 | 00 begane grond | 3160 | 904 | Raam (ARCHICAD Classification); 31.21 GESLOTEN RAMEN (NL/SfB (4 cijfers)) | 2.27021 | 3.195 | 3195 | 1000 | 8390 | 0.0363588 | 100
3 x 31_Raam_A.03 | 00 begane grond | 2816 | 994 | Raam (ARCHICAD Classification); 31.24 RAMEN DRAAIEND OP VERT. OF HOR. AS (NL/SfB (4 cijfers)) | 2.02174 | 2.90375 | 2875 | 1010 | 7770 | 0.0455377 | 280
5 x 31_Raam_A.03a | 00 begane grond | 2816 | 994 | Raam (ARCHICAD Classification); 31.24 RAMEN DRAAIEND OP VERT. OF HOR. AS (NL/SfB (4 cijfers)) | 2.2411 | 2.90375 | 2875 | 1010 | 7770 | 0.0345965 | 280
5 x 31_Raam_A.03b | 00 begane grond | 2803.5 | 994 | Raam (ARCHICAD Classification); 31.24 RAMEN DRAAIEND OP VERT. OF HOR. AS (NL/SfB (4 cijfers)) | 2.01201 | 2.90375 | 2875 | 1010 | 7770 | 0.0453827 | 280
31_Raam_A.03c | 00 begane grond | 2803.5 | 994 | Raam (ARCHICAD Classification); 31.24 RAMEN DRAAIEND OP VERT. OF HOR. AS (NL/SfB (4 cijfers)) | 2.23037 | 2.90375 | 2875 | 1010 | 7770 | 0.0344911 | 280
31_Raam_A.09 | 00 begane grond | 3157 | 904 | Raam (ARCHICAD Classification); 31.21 GESLOTEN RAMEN (NL/SfB (4 cijfers)) | 2.2679 | 3.19 | 3190 | 1000 | 8380 | 0.0363335 | 100
31_Raam_A.09 | 00 begane grond | 3160 | 904 | Raam (ARCHICAD Classification); 31.21 GESLOTEN RAMEN (NL/SfB (4 cijfers)) | 2.27021 | 3.19495 | 3195 | 999.986 | 8389.97 | 0.0363588 | 100
13 x 31_Raam_A.11 | 01 eerste verdieping | 2084.5 | 994 | Raam (ARCHICAD Classification); 31.24 RAMEN DRAAIEND OP VERT. OF HOR. AS (NL/SfB (4 cijfers)) | 1.43263 | 2.15888 | 2137.5 | 1010 | 6295 | 0.0374591 | 280
4 x 31_Raam_A.11b | 01 eerste verdieping | 2084.5 | 994 | Raam (ARCHICAD Classification); 31.24 RAMEN DRAAIEND OP VERT. OF HOR. AS (NL/SfB (4 cijfers)) | 1.61347 | 2.15888 | 2137.5 | 1010 | 6295 | 0.0284285 | 280
31_Raam_A.06b | 01 eerste verdieping | 4014 | 2090 | Raam (ARCHICAD Classification); 31.24 RAMEN DRAAIEND OP VERT. OF HOR. AS (NL/SfB (4 cijfers)) | 3.80053 | 8.2961 | 4000 | 2074.03 | 12148.1 | 0.21771 | 280

# IfcWindow: R1 25 (16)
Type - OperationType: SINGLE_PANEL; ParameterTakesPrecedence: no; Sizeable: no
Pset_WindowCommon - FireRating: 0; ThermalTransmittance: 0
Material - Afwerking dagkant binnen: n.v.t.; Afwerking dagkant buiten: n.v.t.; Draaiend deel: n.v.t.; Frame: n.v.t.; Onderdorpel: n.v.t.; Rollaag / latei: n.v.t.; Spouwlat: n.v.t.; Vensterbank: n.v.t.; Ventilatierooster: n.v.t.; Zonwering - behuizing: n.v.t.; Zonwering - isolatie: n.v.t.; Glas: Glas - algemeen
CPset_Phasing - Renovation Phase: Bestaand
Name | In | OverallHeight (mm) | OverallWidth (mm) | Classification | Reference | GlazingAreaFraction | IsExternal | GrossArea (m2) = Area (m2) | Height (mm) | Width (mm) | Perimeter (mm) | Volume (m3) = NetVolume (m3) = Component, Component Volume (Net) (m3) = Component, Component Volume (Gross) (m3) | Depth (mm)
32_Raam_h.11 | 00 begane grond | 2367 | 815 | Raam (ARCHICAD Classification); 32.21 GESLOTEN RAMEN (NL/SfB (4 cijfers)) | 32_n.v.t. | 1.52067 | no | 1.92911 | 2367 | 815 | 6364 | 0.0253228 | 125
32_Raam_h.11 | 00 begane grond | 2367 | 815 | Raam (ARCHICAD Classification); 32.21 GESLOTEN RAMEN (NL/SfB (4 cijfers)) | 32_n.v.t. | 1.52067 | no | 1.92911 | 2367 | 815 | 6364 | 0.0253228 | 120
2 x 32_Raam_h.22 | 00 begane grond | 2367 | 1000 | Raam (ARCHICAD Classification); 32.21 GESLOTEN RAMEN (NL/SfB (4 cijfers)) | 32_n.v.t. | 1.93378 | no | 2.367 | 2367 | 1000 | 6734 | 0.0268598 | 125
2 x 32_Raam_h.05 | 00 begane grond | 1167 | 1600 | Raam (ARCHICAD Classification); 32.21 GESLOTEN RAMEN (NL/SfB (4 cijfers)) | 32_n.v.t. | 1.51438 | no | 1.8672 | 1167 | 1600 | 5534 | 0.021875 | 125
31_Raam_A.15 | 01 eerste verdieping | 1817.5 | 1000 | Raam (ARCHICAD Classification); 31.21 GESLOTEN RAMEN (NL/SfB (4 cijfers)) | 31_n.v.t. | 1.55624 | yes | 1.90638 | 1887.5 | 1010 | 5795 | 0.0190723 | 280
32_Raam_h.06 | 01 eerste verdieping | 1167 | 1000 | Raam (ARCHICAD Classification); 32.21 GESLOTEN RAMEN (NL/SfB (4 cijfers)) | 32_n.v.t. | 0.894578 | no | 1.167 | 1167 | 1000 | 4334 | 0.0168902 | 125
6 x 32_Raam_h.05 | 01 eerste verdieping | 1167 | 1400 | Raam (ARCHICAD Classification); 32.21 GESLOTEN RAMEN (NL/SfB (4 cijfers)) | 32_n.v.t. | 1.30778 | no | 1.6338 | 1167 | 1400 | 5134 | 0.0202134 | 125
32_Raam_h.21 | 01 eerste verdieping | 2367 | 1693.5 | Raam (ARCHICAD Classification); 32.21 GESLOTEN RAMEN (NL/SfB (4 cijfers)) | 32_n.v.t. | 3.48236 | no | 4.00851 | 2367 | 1693.5 | 8121 | 0.0326214 | 125
32_Raam_h.17 | 01 eerste verdieping | 1760 | 1095 | Raam (ARCHICAD Classification); 32.21 GESLOTEN RAMEN (NL/SfB (4 cijfers)) | 32_n.v.t. | 1.56259 | no | 1.9272 | 1760 | 1095 | 5710 | 0.041566 | 150

# IfcWindow: R2 bl ol 25 (20)
Type - OperationType: USERDEFINED; ParameterTakesPrecedence: no; Sizeable: no
OverallWidth: 1994 mm; Classification: Raam (ARCHICAD Classification); 31.24 RAMEN DRAAIEND OP VERT. OF HOR. AS (NL/SfB (4 cijfers))
Pset_WindowCommon - Reference: 31_n.v.t.; FireRating: 0; ThermalTransmittance: 0; IsExternal: yes
Material - Afwerking dagkant binnen: n.v.t.; Afwerking dagkant buiten: n.v.t.; Draaiend deel: n.v.t.; Frame: n.v.t.; Onderdorpel: n.v.t.; Rollaag / latei: n.v.t.; Spouwlat: n.v.t.; Vensterbank: n.v.t.; Ventilatierooster: n.v.t.; Zonwering - behuizing: n.v.t.; Zonwering - isolatie: n.v.t.; Glas: Glas - algemeen
CPset_Phasing - Renovation Phase: Bestaand
BaseQuantities - Width: 2010 mm; Depth: 280 mm
Name | In | OverallHeight (mm) | GlazingAreaFraction | GrossArea (m2) = Area (m2) | Height (mm) | Perimeter (mm) | Volume (m3) = NetVolume (m3) = Component, Component Volume (Net) (m3) | Component, Component Volume (Gross) (m3)
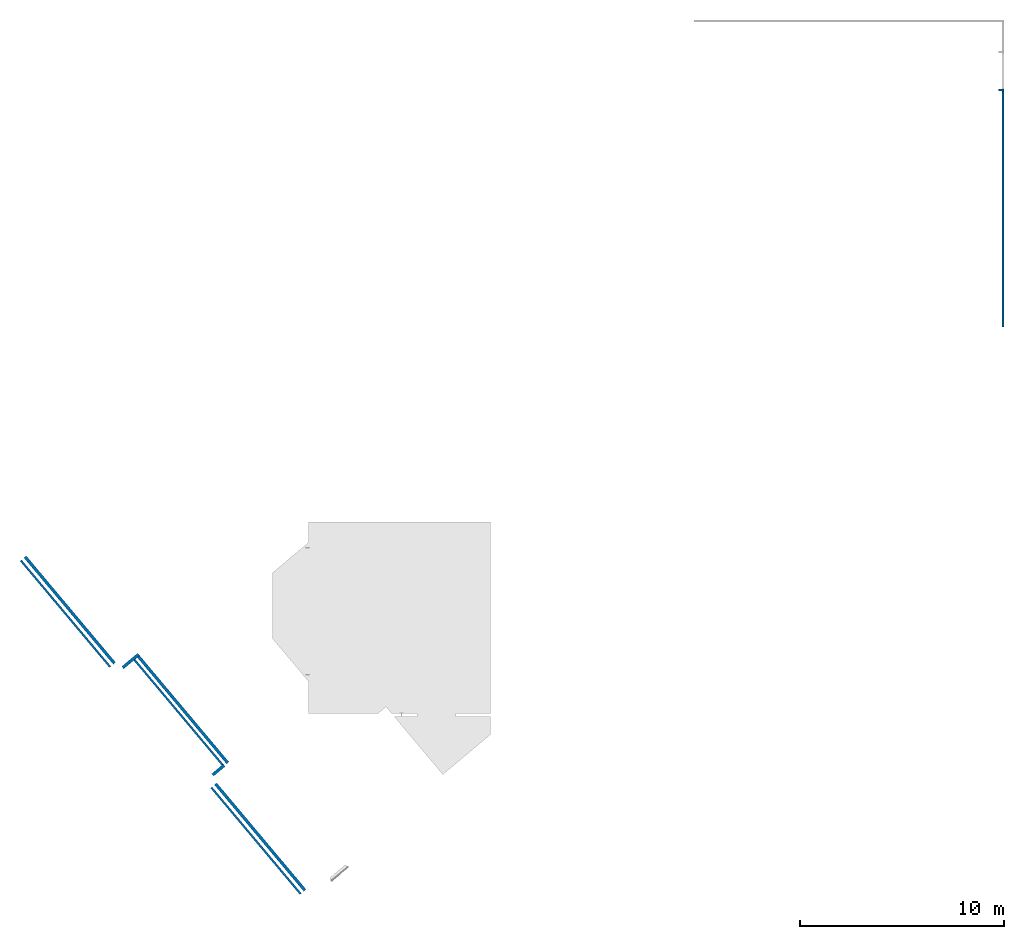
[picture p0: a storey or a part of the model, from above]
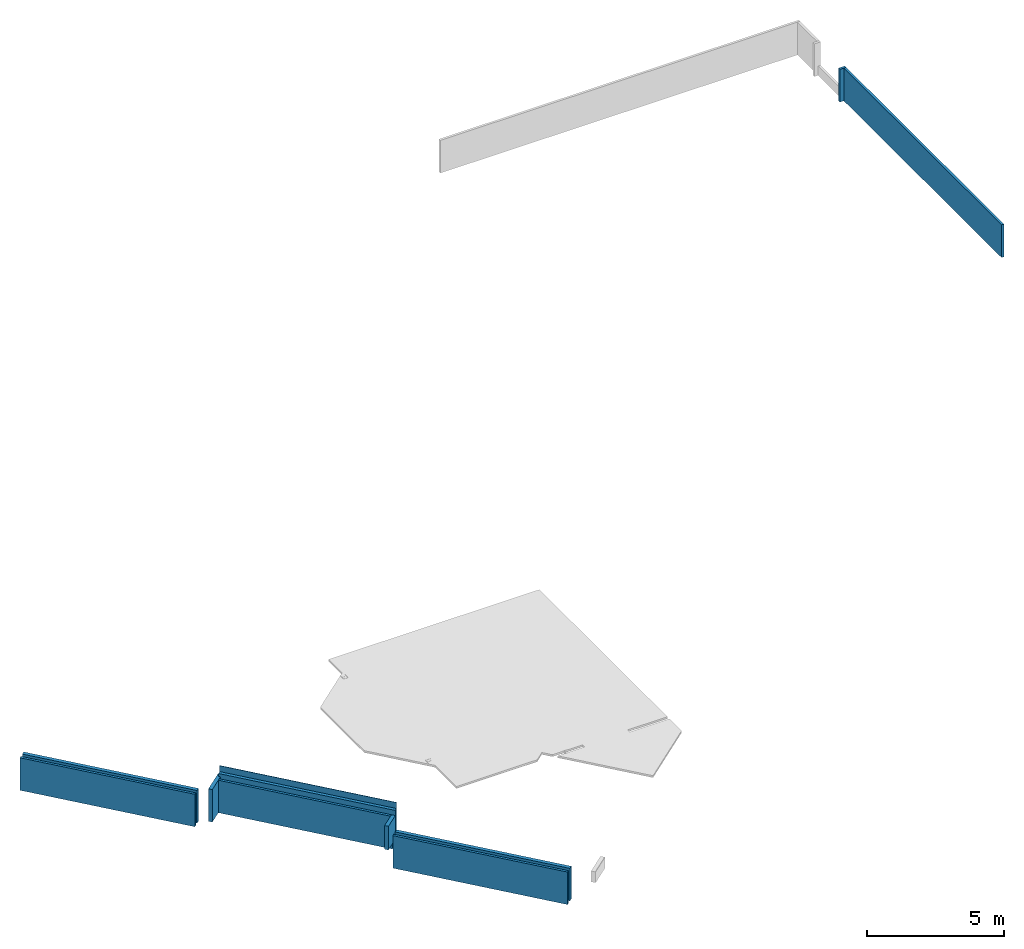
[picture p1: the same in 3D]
Properties of the parts of a building model (IFC2X3), part 11 of 11

# IfcWindow: R2 bl ol 25 (20)
Name | In | OverallHeight (mm) | GlazingAreaFraction | GrossArea (m2) = Area (m2) | Height (mm) | Perimeter (mm) | Volume (m3) = NetVolume (m3) = Component, Component Volume (Net) (m3) | Component, Component Volume (Gross) (m3)
31_Raam_A.01b | 00 begane grond | 2816 | 4.45316 | 5.77875 | 2875 | 9770 | 0.0678532 | 0.0693447
31_Raam_A.01b | 00 begane grond | 2816 | 4.45316 | 5.77875 | 2875 | 9770 | 0.0693447 | 0.0693447
2 x 31_Raam_A.01a | 00 begane grond | 2816 | 4.23084 | 5.81091 | 2891 | 9802 | 0.0804327 | 0.0804327
31_Raam_A.01a | 00 begane grond | 2816 | 4.23084 | 5.77875 | 2875 | 9770 | 0.0804327 | 0.0804327
4 x 31_Raam_A.01c | 00 begane grond | 2803.5 | 4.43178 | 5.77875 | 2875 | 9770 | 0.069137 | 0.069137
3 x 31_Raam_A.14 | 01 eerste verdieping | 2639.5 | 3.94314 | 5.85412 | 2912.5 | 9845 | 0.0767996 | 0.0767996
4 x 31_Raam_A.10 | 01 eerste verdieping | 2084.5 | 3.18309 | 4.29638 | 2137.5 | 8295 | 0.0581424 | 0.0581424
31_Raam_A.10 | 01 eerste verdieping | 2084.5 | 3.18309 | 4.29638 | 2137.5 | 8295 | 0.0561401 | 0.0581424
3 x 31_Raam_A.10a | 01 eerste verdieping | 2084.5 | 3.0065 | 4.29638 | 2137.5 | 8295 | 0.0669627 | 0.0669627

# IfcWindow: Rnx horizontaal 25, 32_Raam_h.09
In: 00 begane grond
Type - OperationType: DOUBLE_PANEL_VERTICAL; ParameterTakesPrecedence: no; Sizeable: no
OverallHeight: 2367 mm; OverallWidth: 2157.68 mm; Classification: Raam (ARCHICAD Classification); 32.21 GESLOTEN RAMEN (NL/SfB (4 cijfers))
Pset_WindowCommon - Reference: 32_n.v.t.; FireRating: 0; ThermalTransmittance: 0; GlazingAreaFraction: 4.36927; IsExternal: no
Material - Afwerking dagkant binnen: n.v.t.; Afwerking dagkant buiten: n.v.t.; Draaiend deel: n.v.t.; Frame: n.v.t.; Onderdorpel: n.v.t.; Rollaag / latei: n.v.t.; Spouwlat: n.v.t.; Vensterbank: n.v.t.; Ventilatierooster: n.v.t.; Zonwering - behuizing: n.v.t.; Zonwering - isolatie: n.v.t.; Glas: Glas - algemeen
Pset_FireRatingProperties - FireResistanceRating: 60 minuten brandwerend
CPset_Phasing - Renovation Phase: Bestaand
BaseQuantities - GrossArea: 5.10723 m2; Height: 2367 mm; Width: 2157.68 mm; Perimeter: 9049.36 mm; Area: 5.10723 m2; Volume: 0.0457537 m3; Depth: 100 mm; NetVolume: 0.0457537 m3
Component Quantities - Component, Component Volume (Net): 0.0457537 m3; Component, Component Volume (Gross): 0.0457537 m3

# IfcWindow: Rnx horizontaal 25 (3)
Type - OperationType: TRIPLE_PANEL_VERTICAL; ParameterTakesPrecedence: no; Sizeable: no
Pset_WindowCommon - ThermalTransmittance: 0
Material - Afwerking dagkant binnen: n.v.t.; Afwerking dagkant buiten: n.v.t.; Draaiend deel: n.v.t.; Frame: n.v.t.; Onderdorpel: n.v.t.; Rollaag / latei: n.v.t.; Spouwlat: n.v.t.; Vensterbank: n.v.t.; Ventilatierooster: n.v.t.; Zonwering - behuizing: n.v.t.; Zonwering - isolatie: n.v.t.; Glas: Glas - algemeen
CPset_Phasing - Renovation Phase: Bestaand
Name | In | OverallHeight (mm) | OverallWidth (mm) | Classification | Reference | FireRating | GlazingAreaFraction | IsExternal | FireResistanceRating | GrossArea (m2) = Area (m2) | Height (mm) | Width (mm) | Perimeter (mm) | Volume (m3) = NetVolume (m3) = Component, Component Volume (Net) (m3) = Component, Component Volume (Gross) (m3) | Depth (mm)
32_Raam_h.07 | 00 begane grond | 2367 | 3017.62 | Raam (ARCHICAD Classification); 32.21 GESLOTEN RAMEN (NL/SfB (4 cijfers)) | 32_n.v.t. | 0 | 6.1399 | no | 60 minuten brandwerend | 7.1427 | 2367 | 3017.62 | 10769.2 | 0.0621739 | 100
32_Raam_h.19a | 01 eerste verdieping | 1367 | 2553.5 | Raam (ARCHICAD Classification); 32.21 GESLOTEN RAMEN (NL/SfB (4 cijfers)) | 32_n.v.t. | 60 | 2.81802 | no | 60 minuten brandwerend | 3.49063 | 1367 | 2553.5 | 7841 | 0.0766779 | 100
31_Raam_A.12 | 01 eerste verdieping | 1834.5 | 2767.84 | Raam (ARCHICAD Classification); 31.24 RAMEN DRAAIEND OP VERT. OF HOR. AS (NL/SfB (4 cijfers)) | 31_n.v.t. | 0 | 4.23918 | yes |  | 5.2545 | 1887.5 | 2783.84 | 9342.68 | 0.0603661 | 280

# IfcWindow: Rnx horizontaal 25, 32_Raam_h.16
In: 01 eerste verdieping
Type - OperationType: USERDEFINED; ParameterTakesPrecedence: no; Sizeable: no
OverallHeight: 1760 mm; OverallWidth: 6989 mm; Classification: Raam (ARCHICAD Classification); 32.21 GESLOTEN RAMEN (NL/SfB (4 cijfers))
Pset_WindowCommon - Reference: 32_n.v.t.; FireRating: 0; ThermalTransmittance: 0; GlazingAreaFraction: 10.4926; IsExternal: no
Material - Afwerking dagkant binnen: n.v.t.; Afwerking dagkant buiten: n.v.t.; Draaiend deel: n.v.t.; Frame: n.v.t.; Onderdorpel: n.v.t.; Rollaag / latei: n.v.t.; Spouwlat: n.v.t.; Vensterbank: n.v.t.; Ventilatierooster: n.v.t.; Zonwering - behuizing: n.v.t.; Zonwering - isolatie: n.v.t.; Glas: Glas - algemeen
CPset_Phasing - Renovation Phase: Bestaand
BaseQuantities - GrossArea: 12.3006 m2; Height: 1760 mm; Width: 6989 mm; Perimeter: 17498 mm; Area: 12.3006 m2; Volume: 0.206119 m3; Depth: 150 mm; NetVolume: 0.206119 m3
Component Quantities - Component, Component Volume (Net): 0.206119 m3; Component, Component Volume (Gross): 0.206119 m3
